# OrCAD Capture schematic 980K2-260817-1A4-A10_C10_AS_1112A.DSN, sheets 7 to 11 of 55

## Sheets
7 T14.SLOT14_PMVIx: size A2
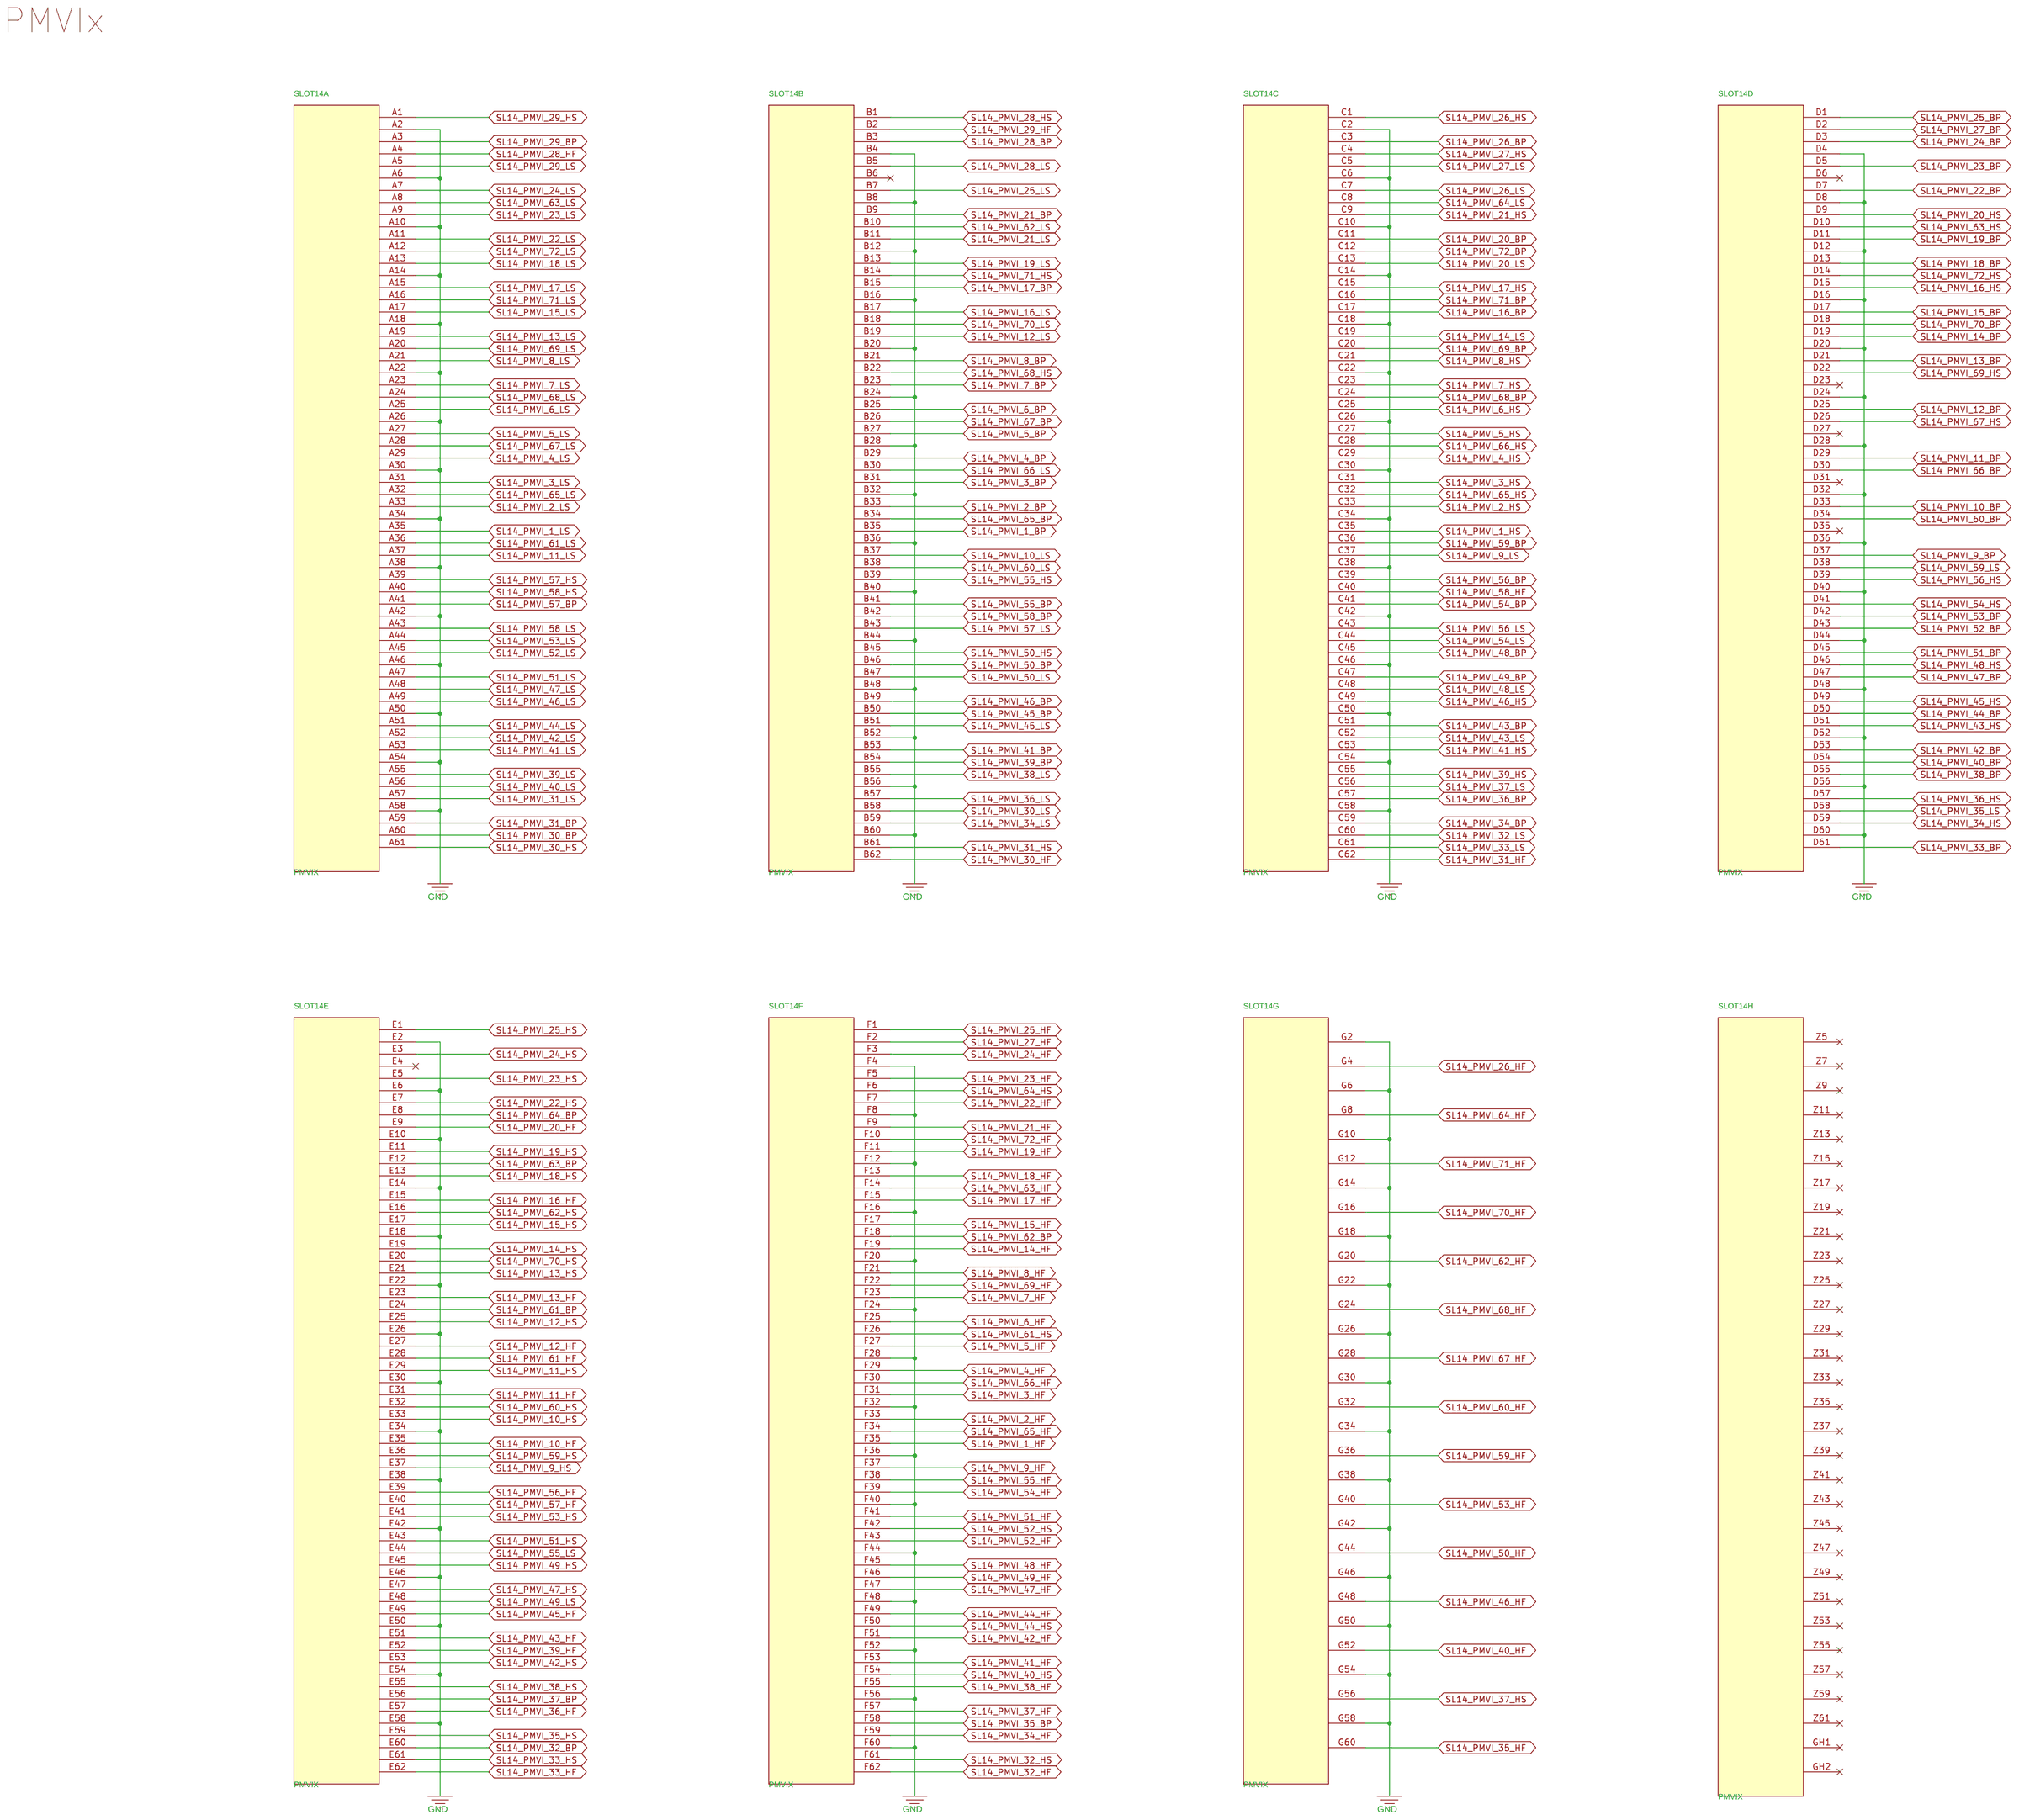
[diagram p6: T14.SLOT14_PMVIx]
8 T13.SLOT13_GX1x: size A2
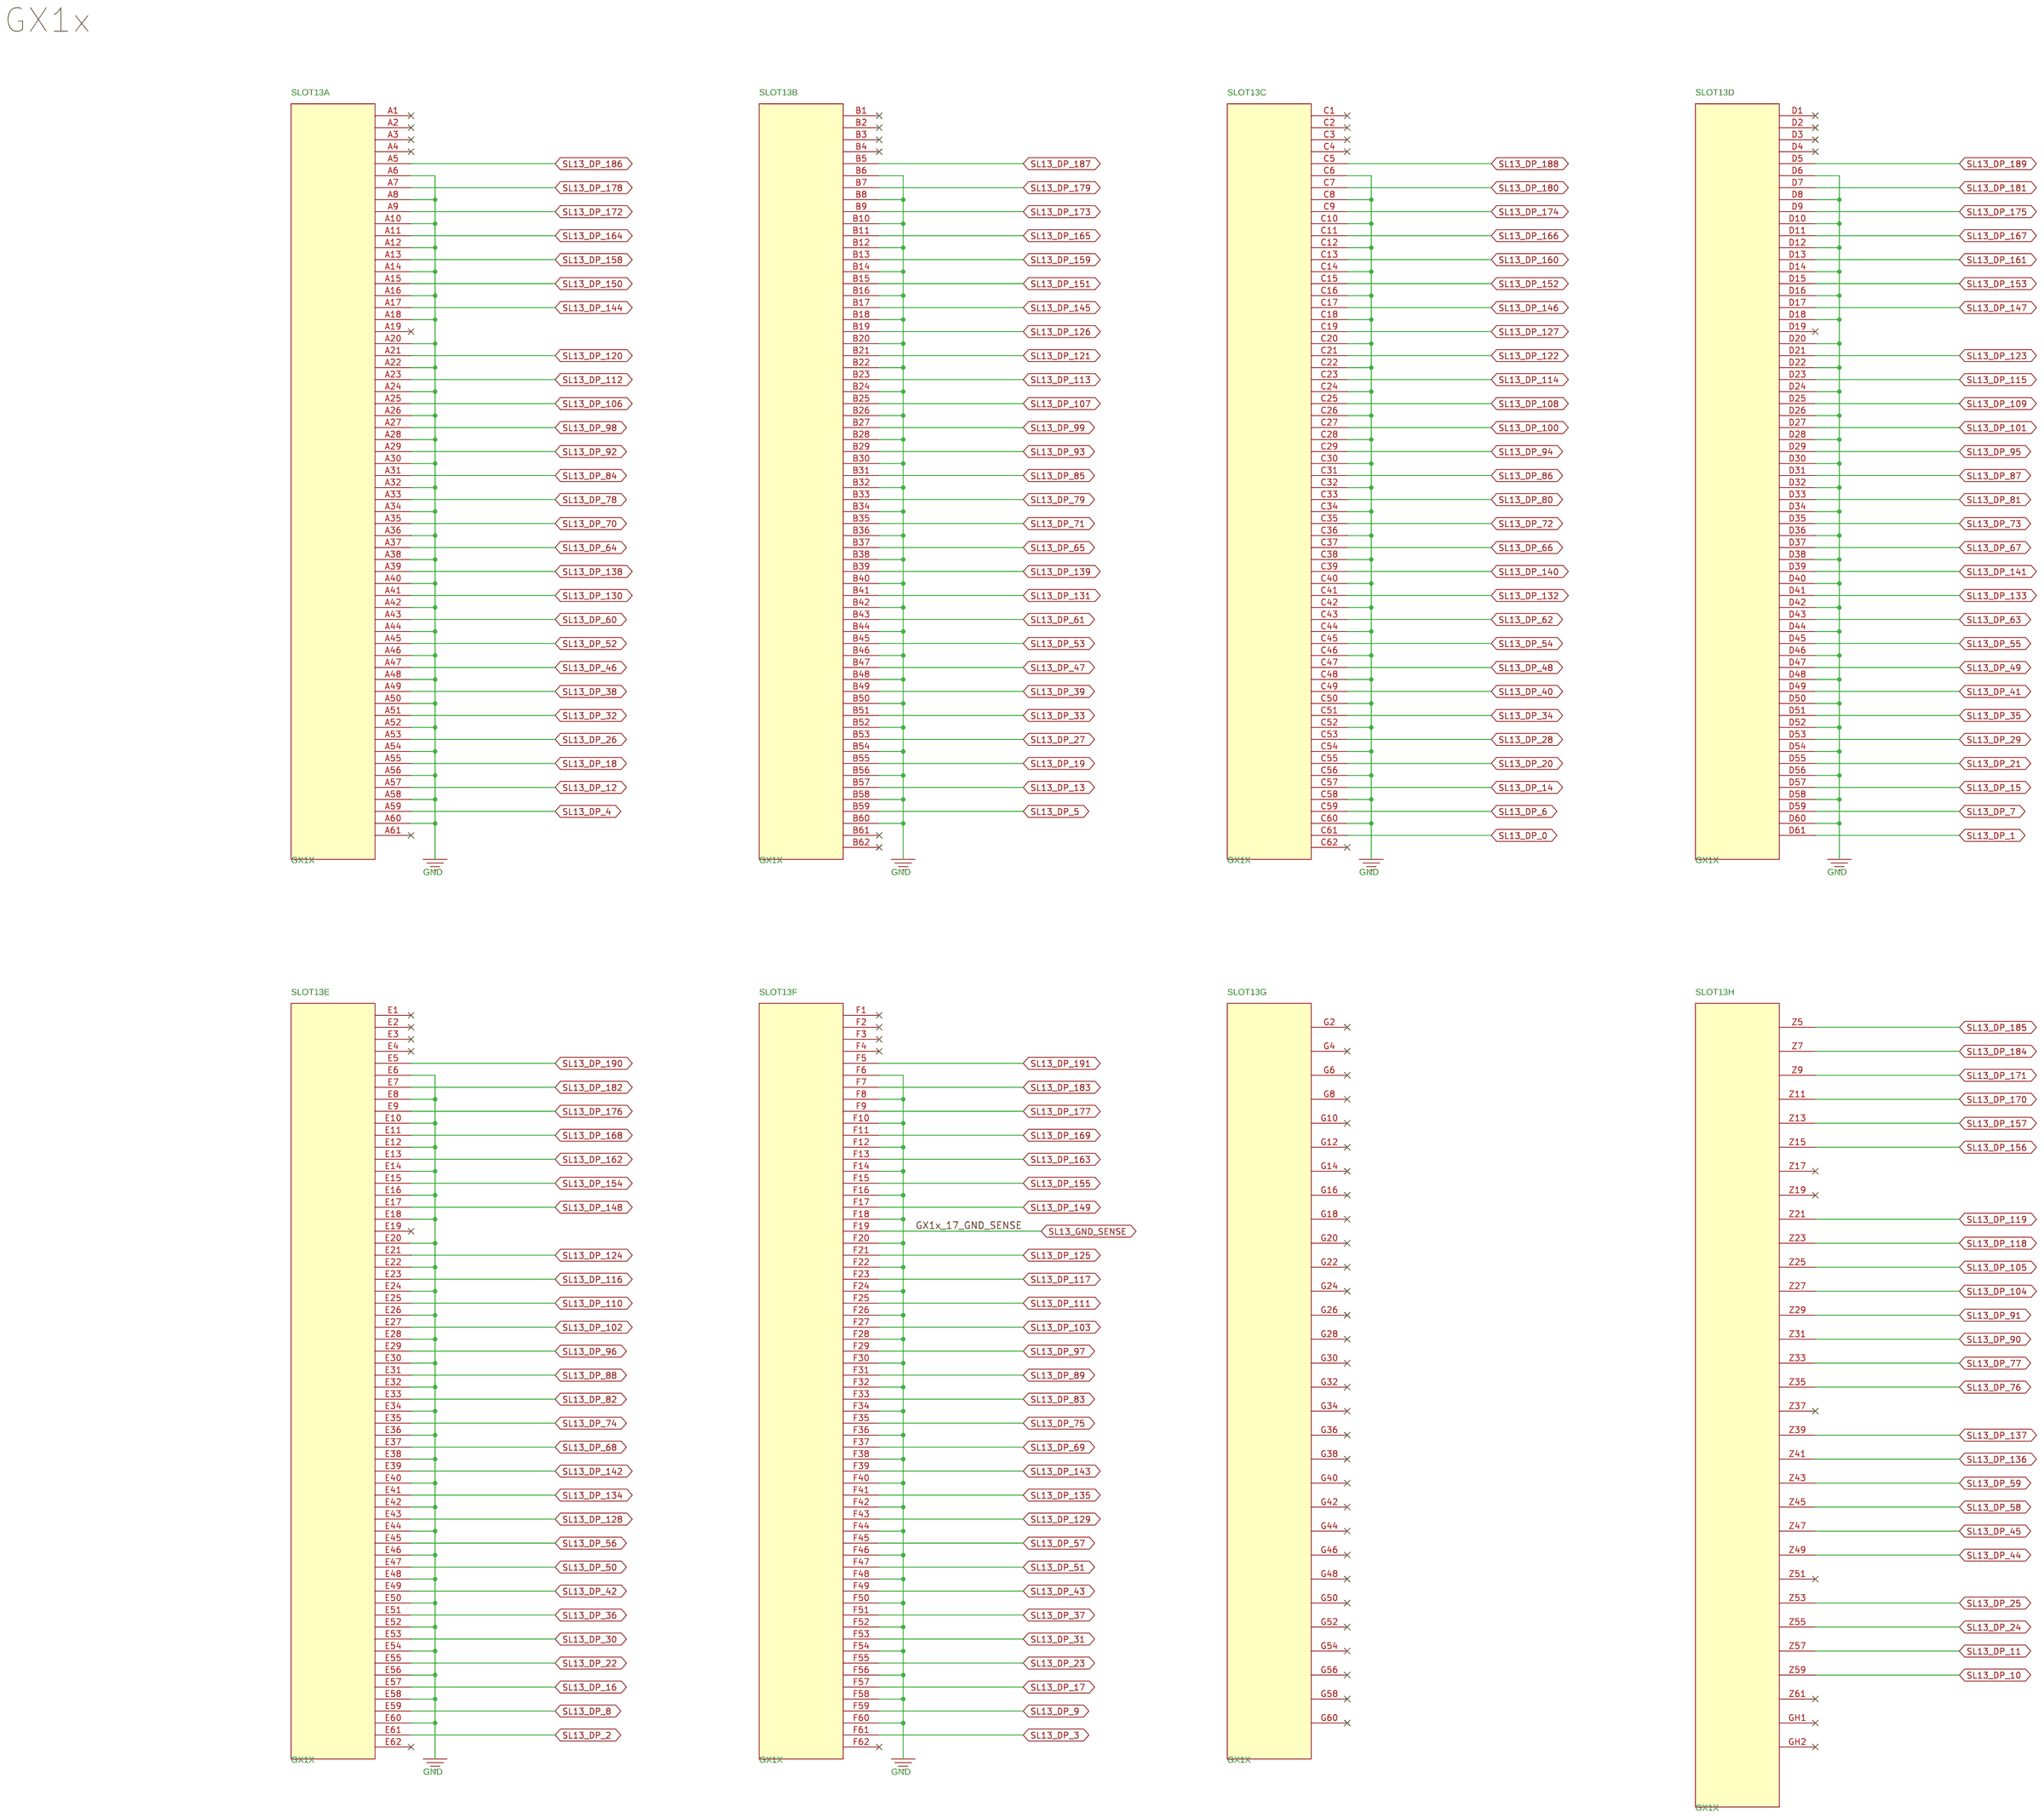
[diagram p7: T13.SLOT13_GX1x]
9 T12.SLOT12_EMPTY: size A2
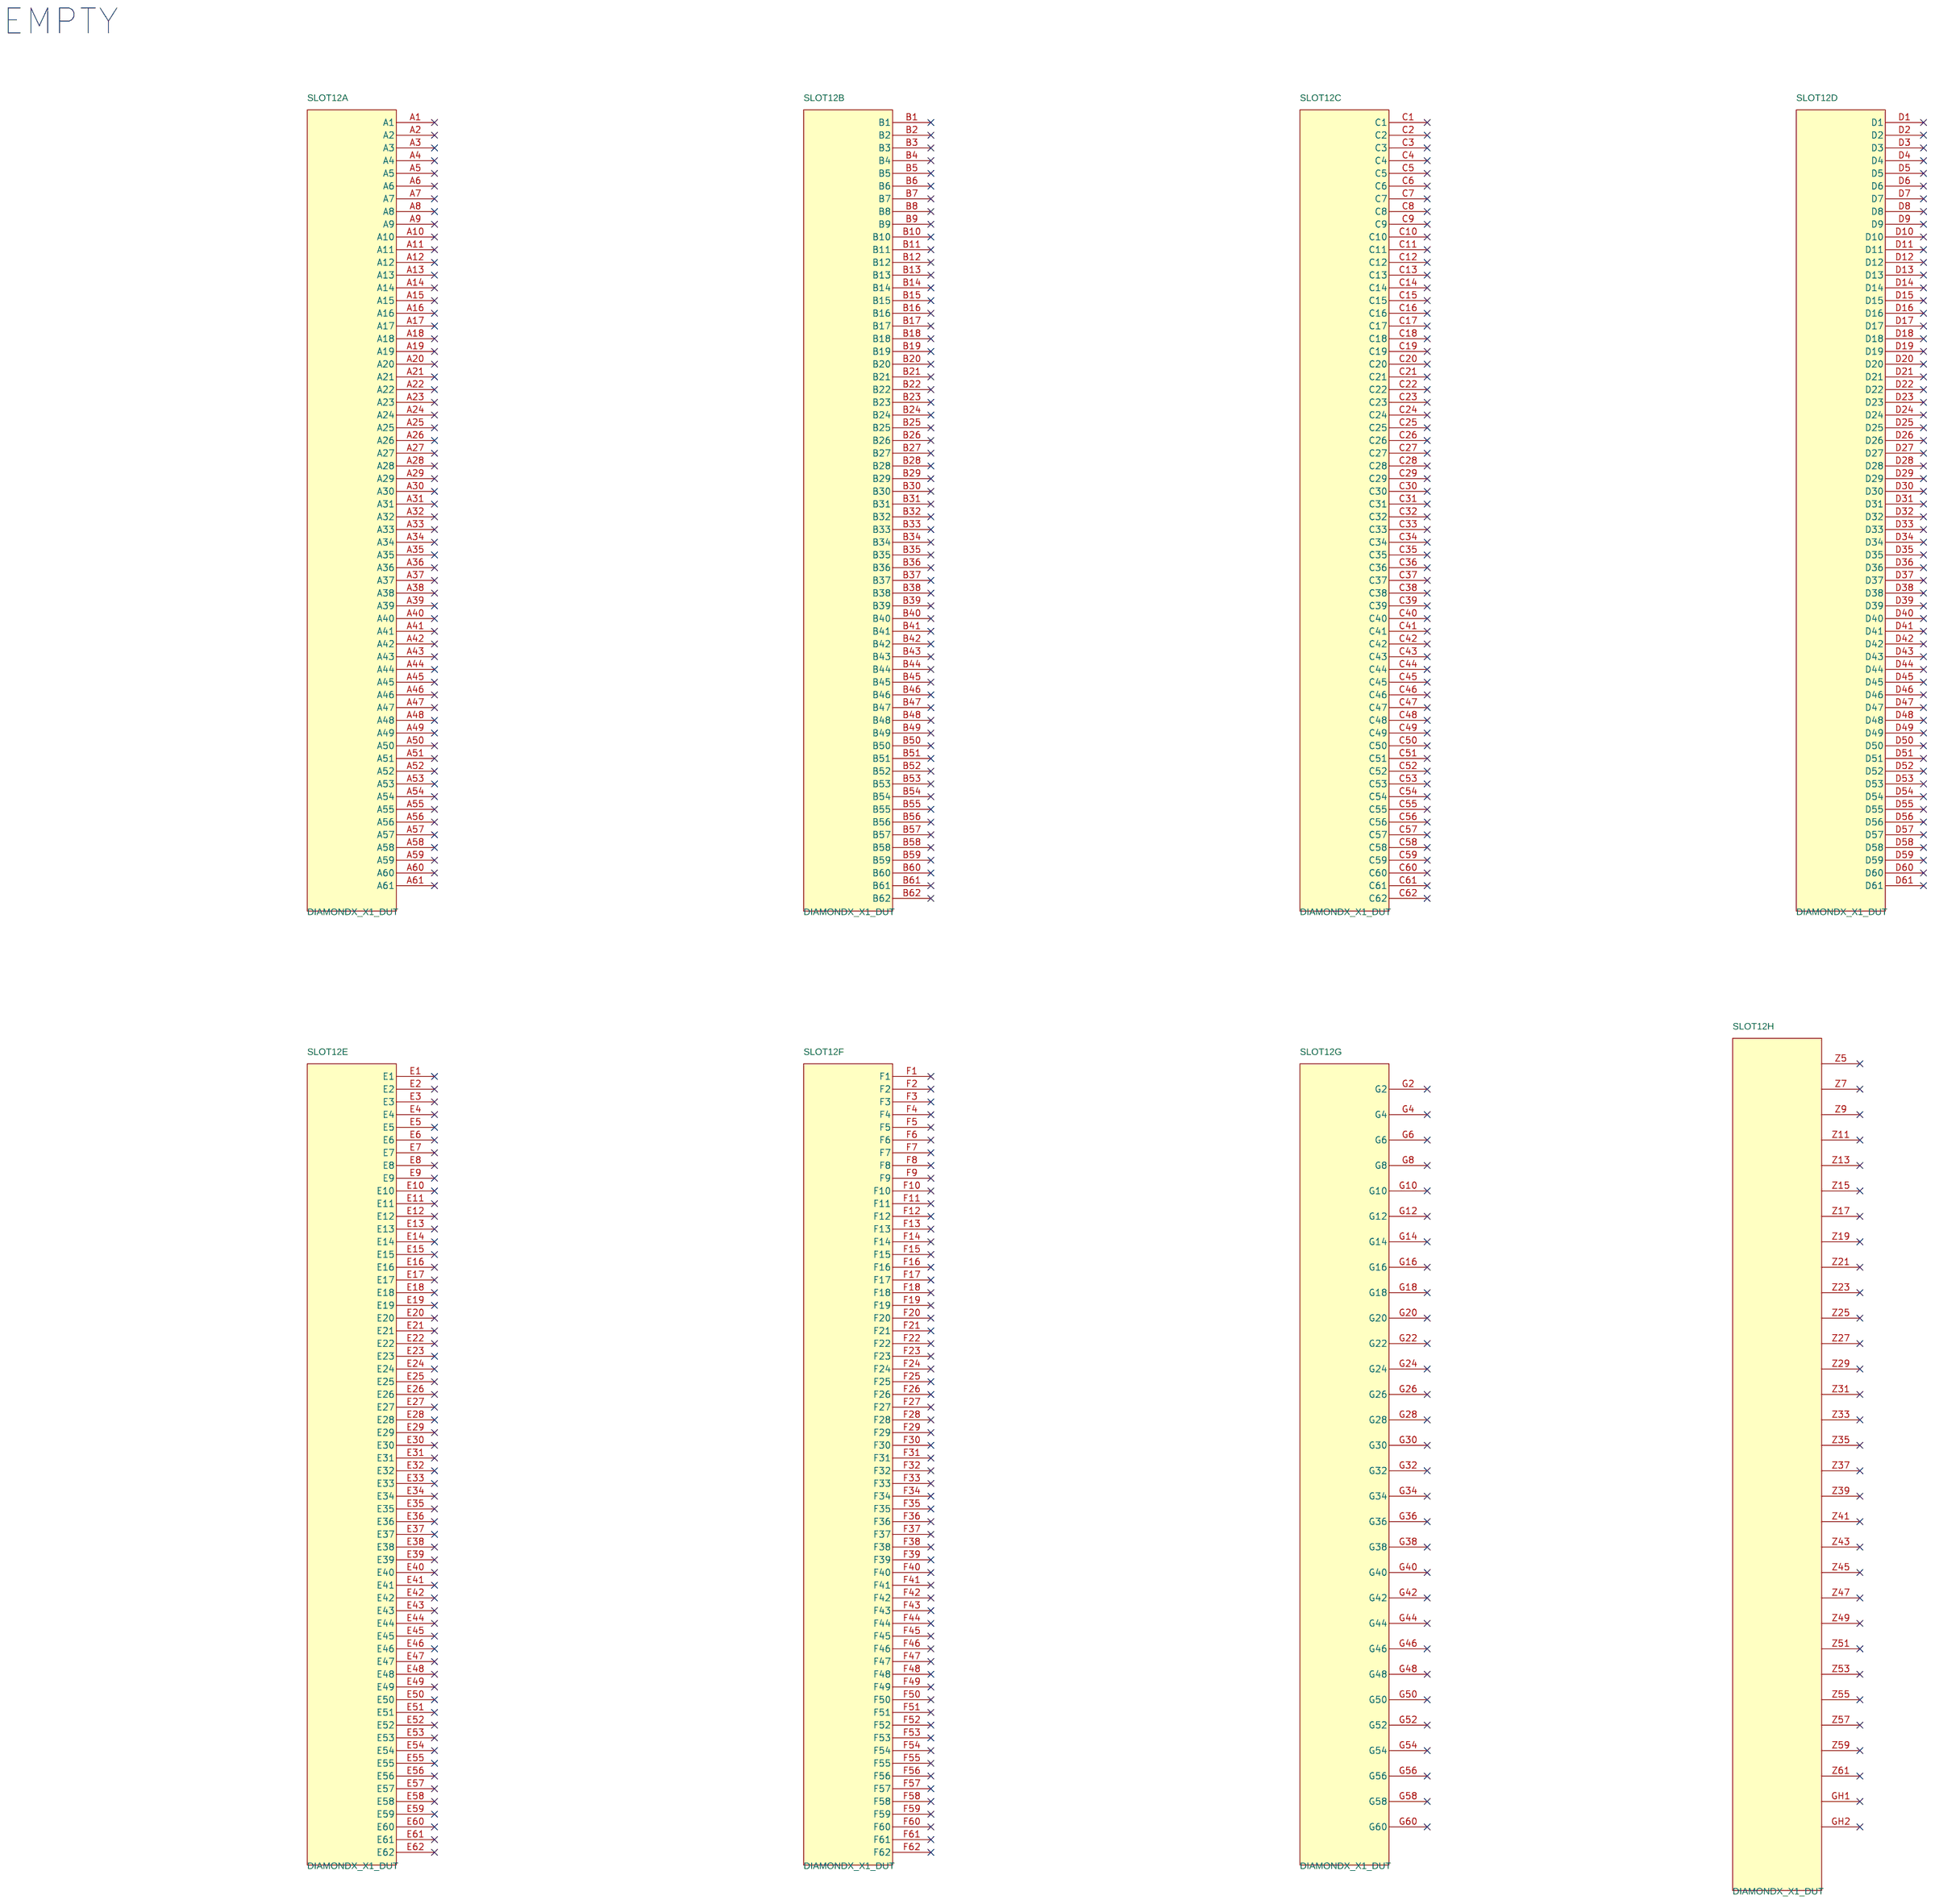
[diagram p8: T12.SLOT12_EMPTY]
10 T11.SLOT11_EMPTY: size A2
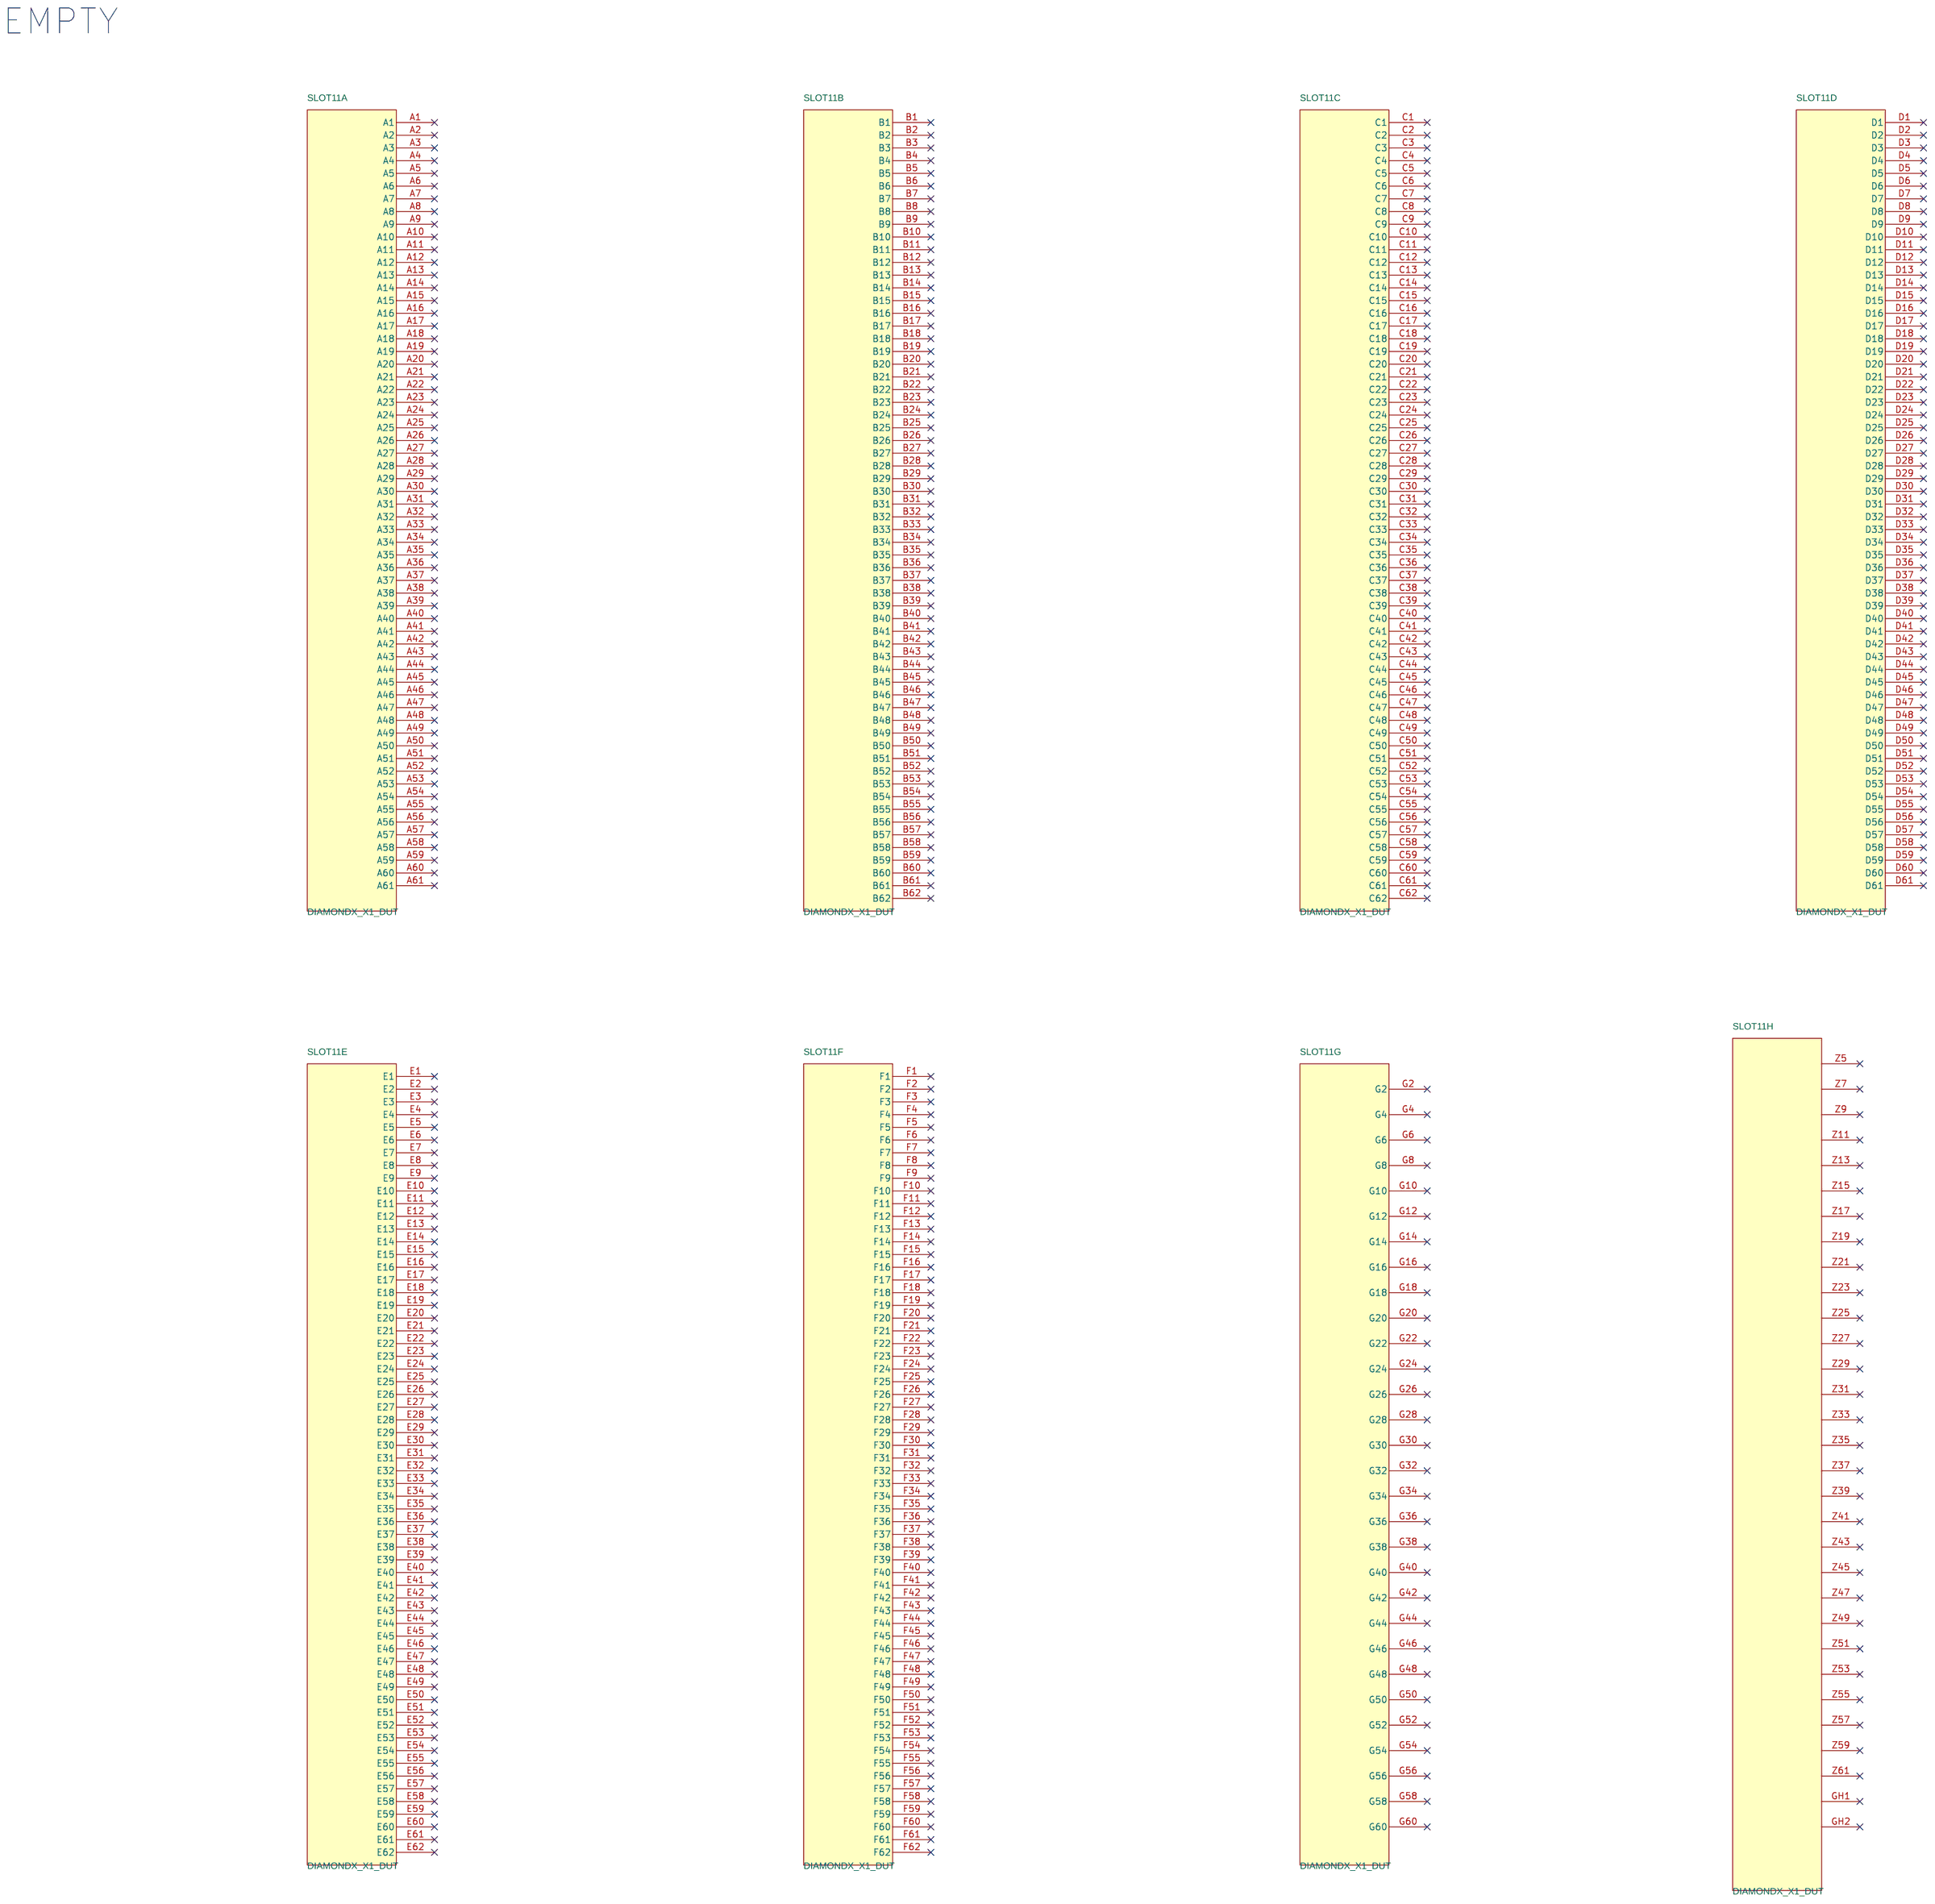
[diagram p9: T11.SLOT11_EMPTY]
11 T10.SLOT10_FPVI: size A2

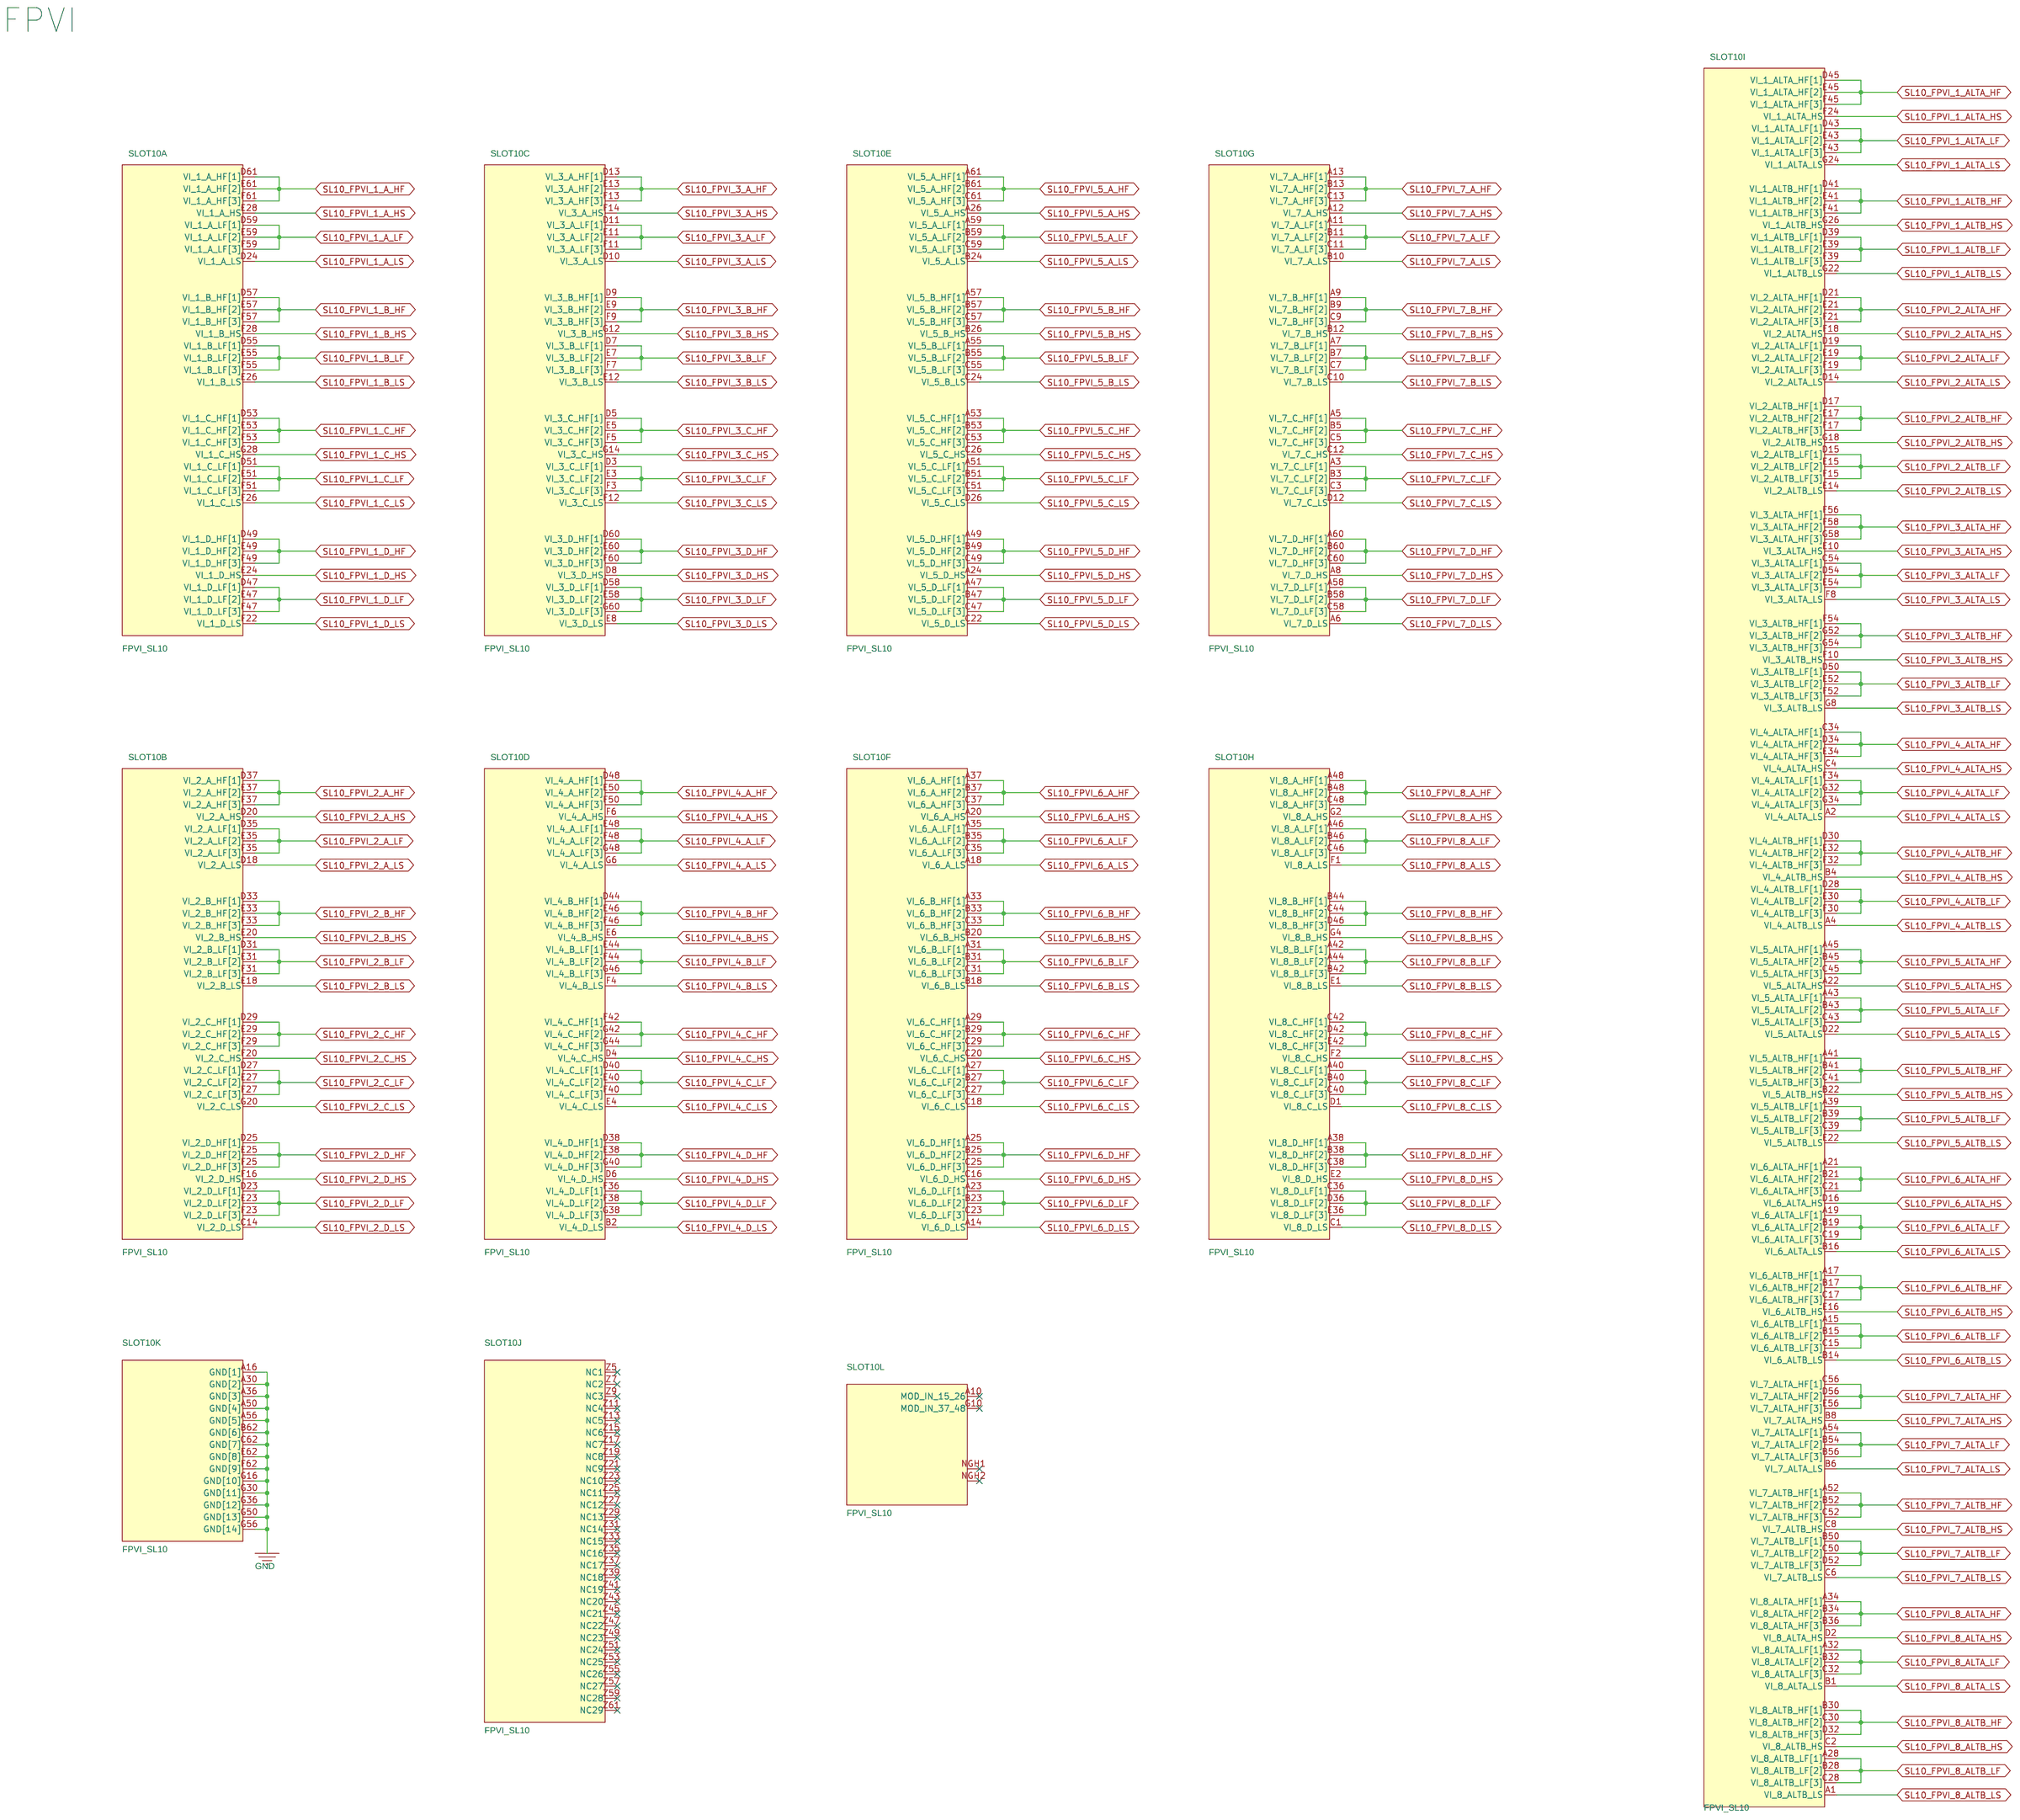
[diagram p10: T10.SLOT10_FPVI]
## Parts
sheet T10.SLOT10_FPVI
SLOT10  FPVI_SL10  [PG_LTXDX_F_X1_FPVI_SL10_V3]  (sections A,B,C,D,E,F,G,H,I,J,K,L)
sheet T11.SLOT11_EMPTY
SLOT11  DIAMONDX_X1_DUT  [PG_LTXDX_F_X1_PG400ND_SL11_V3]  (sections A,B,C,D,E,F,G,H)
sheet T12.SLOT12_EMPTY
SLOT12  DIAMONDX_X1_DUT  [PG_LTXDX_F_X1_PG400ND_SL12_V3]  (sections A,B,C,D,E,F,G,H)
sheet T13.SLOT13_GX1x
SLOT13  GX1X  [PG_LTXDX_F_X1_GX1_SL13_V2]  (sections A,B,C,D,E,F,G,H)
sheet T14.SLOT14_PMVIx
SLOT14  PMVIX  [PG_LTXDX_F_X1_PMVI_SL14_V3]  (sections A,B,C,D,E,F,G,H)

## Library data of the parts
SLOT10 = FPVI_SL10
SLOT11 SLOT12 = DIAMONDX_X1_DUT_1
SLOT13 = DIAMONDX_SLOT17_GX1X
SLOT14 = DIAMONDX_SLOT8_PMVIX

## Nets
GND: SLOT10.A16(GND[1]) SLOT10.A30(GND[2]) SLOT10.A36(GND[3]) SLOT10.A50(GND[4]) SLOT10.A56(GND[5]) SLOT10.B62(GND[6]) SLOT10.C62(GND[7]) SLOT10.E62(GND[8]) SLOT10.F62(GND[9]) SLOT10.G16(GND[10]) SLOT10.G30(GND[11]) SLOT10.G36(GND[12]) SLOT10.G50(GND[13]) SLOT10.G56(GND[14]) SLOT13.A6 SLOT13.A8 SLOT13.A10 SLOT13.A12 SLOT13.A14 SLOT13.A16 SLOT13.A18 SLOT13.A20 SLOT13.A22 SLOT13.A24 SLOT13.A26 SLOT13.A28 SLOT13.A30 SLOT13.A32 SLOT13.A34 SLOT13.A36 SLOT13.A38 SLOT13.A40 SLOT13.A42 SLOT13.A44 SLOT13.A46 SLOT13.A48 SLOT13.A50 SLOT13.A52 SLOT13.A54 SLOT13.A56 SLOT13.A58 SLOT13.A60 SLOT13.B6 SLOT13.B8 SLOT13.B10 SLOT13.B12 SLOT13.B14 SLOT13.B16 SLOT13.B18 SLOT13.B20 SLOT13.B22 SLOT13.B24 SLOT13.B26 SLOT13.B28 SLOT13.B30 SLOT13.B32 SLOT13.B34 SLOT13.B36 SLOT13.B38 SLOT13.B40 SLOT13.B42 SLOT13.B44 SLOT13.B46 SLOT13.B48 SLOT13.B50 SLOT13.B52 SLOT13.B54 SLOT13.B56 SLOT13.B58 SLOT13.B60 SLOT13.C6 SLOT13.C8 SLOT13.C10 SLOT13.C12 SLOT13.C14 SLOT13.C16 SLOT13.C18 SLOT13.C20 SLOT13.C22 SLOT13.C24 SLOT13.C26 SLOT13.C28 SLOT13.C30 SLOT13.C32 SLOT13.C34 SLOT13.C36 SLOT13.C38 SLOT13.C40 SLOT13.C42 SLOT13.C44 SLOT13.C46 SLOT13.C48 SLOT13.C50 SLOT13.C52 SLOT13.C54 SLOT13.C56 SLOT13.C58 SLOT13.C60 SLOT13.D6 SLOT13.D8 SLOT13.D10 SLOT13.D12 SLOT13.D14 SLOT13.D16 SLOT13.D18 SLOT13.D20 SLOT13.D22 SLOT13.D24 SLOT13.D26 SLOT13.D28 SLOT13.D30 SLOT13.D32 SLOT13.D34 SLOT13.D36 SLOT13.D38 SLOT13.D40 SLOT13.D42 SLOT13.D44 SLOT13.D46 SLOT13.D48 SLOT13.D50 SLOT13.D52 SLOT13.D54 SLOT13.D56 SLOT13.D58 SLOT13.D60 SLOT13.E6 SLOT13.E8 SLOT13.E10 SLOT13.E12 SLOT13.E14 SLOT13.E16 SLOT13.E18 SLOT13.E20 SLOT13.E22 SLOT13.E24 SLOT13.E26 SLOT13.E28 SLOT13.E30 SLOT13.E32 SLOT13.E34 SLOT13.E36 SLOT13.E38 SLOT13.E40 SLOT13.E42 SLOT13.E44 SLOT13.E46 SLOT13.E48 SLOT13.E50 SLOT13.E52 SLOT13.E54 SLOT13.E56 SLOT13.E58 SLOT13.E60 SLOT13.F6 SLOT13.F8 SLOT13.F10 SLOT13.F12 SLOT13.F14 SLOT13.F16 SLOT13.F18 SLOT13.F20 SLOT13.F22 SLOT13.F24 SLOT13.F26 SLOT13.F28 SLOT13.F30 SLOT13.F32 SLOT13.F34 SLOT13.F36 SLOT13.F38 SLOT13.F40 SLOT13.F42 SLOT13.F44 SLOT13.F46 SLOT13.F48 SLOT13.F50 SLOT13.F52 SLOT13.F54 SLOT13.F56 SLOT13.F58 SLOT13.F60 SLOT14.A2 SLOT14.A6 SLOT14.A10 SLOT14.A14 SLOT14.A18 SLOT14.A22 SLOT14.A26 SLOT14.A30 SLOT14.A34 SLOT14.A38 SLOT14.A42 SLOT14.A46 SLOT14.A50 SLOT14.A54 SLOT14.A58 SLOT14.B4 SLOT14.B8 SLOT14.B12 SLOT14.B16 SLOT14.B20 SLOT14.B24 SLOT14.B28 SLOT14.B32 SLOT14.B36 SLOT14.B40 SLOT14.B44 SLOT14.B48 SLOT14.B52 SLOT14.B56 SLOT14.B60 SLOT14.C2 SLOT14.C6 SLOT14.C10 SLOT14.C14 SLOT14.C18 SLOT14.C22 SLOT14.C26 SLOT14.C30 SLOT14.C34 SLOT14.C38 SLOT14.C42 SLOT14.C46 SLOT14.C50 SLOT14.C54 SLOT14.C58 SLOT14.D4 SLOT14.D8 SLOT14.D12 SLOT14.D16 SLOT14.D20 SLOT14.D24 SLOT14.D28 SLOT14.D32 SLOT14.D36 SLOT14.D40 SLOT14.D44 SLOT14.D48 SLOT14.D52 SLOT14.D56 SLOT14.D60 SLOT14.E2 SLOT14.E6 SLOT14.E10 SLOT14.E14 SLOT14.E18 SLOT14.E22 SLOT14.E26 SLOT14.E30 SLOT14.E34 SLOT14.E38 SLOT14.E42 SLOT14.E46 SLOT14.E50 SLOT14.E54 SLOT14.E58 SLOT14.F4 SLOT14.F8 SLOT14.F12 SLOT14.F16 SLOT14.F20 SLOT14.F24 SLOT14.F28 SLOT14.F32 SLOT14.F36 SLOT14.F40 SLOT14.F44 SLOT14.F48 SLOT14.F52 SLOT14.F56 SLOT14.F60 SLOT14.G2 SLOT14.G6 SLOT14.G10 SLOT14.G14 SLOT14.G18 SLOT14.G22 SLOT14.G26 SLOT14.G30 SLOT14.G34 SLOT14.G38 SLOT14.G42 SLOT14.G46 SLOT14.G50 SLOT14.G54 SLOT14.G58 ; also on sheet 3 4 12 15 16 19 20 21 22 24 28 32 36 40 44 48 52
SL02_VI100_1_B_HF: SLOT10.A59(VI_5_A_LF[1]) SLOT10.B59(VI_5_A_LF[2]) SLOT10.C59(VI_5_A_LF[3]) SLOT10.D59(VI_1_A_LF[1]) SLOT10.E59(VI_1_A_LF[2]) SLOT10.F59(VI_1_A_LF[3]) ; also on sheet 19 22
SL02_VI100_1_B_HS: SLOT10.B24(VI_5_A_LS) SLOT10.D24(VI_1_A_LS) ; also on sheet 19 22
SL10_FPVI_1_A_HF: SLOT10.D61(VI_1_A_HF[1]) SLOT10.E61(VI_1_A_HF[2]) SLOT10.F61(VI_1_A_HF[3]) ; also on sheet 50
SL10_FPVI_1_A_HS: SLOT10.E28(VI_1_A_HS) ; also on sheet 50
SL10_FPVI_1_ALTA_HF: SLOT10.D45(VI_1_ALTA_HF[1]) SLOT10.E45(VI_1_ALTA_HF[2]) SLOT10.F45(VI_1_ALTA_HF[3])
SL10_FPVI_1_ALTA_HS: SLOT10.F24(VI_1_ALTA_HS)
SL10_FPVI_1_ALTA_LF: SLOT10.D43(VI_1_ALTA_LF[1]) SLOT10.E43(VI_1_ALTA_LF[2]) SLOT10.F43(VI_1_ALTA_LF[3])
SL10_FPVI_1_ALTA_LS: SLOT10.G24(VI_1_ALTA_LS)
SL10_FPVI_1_ALTB_HF: SLOT10.D41(VI_1_ALTB_HF[1]) SLOT10.E41(VI_1_ALTB_HF[2]) SLOT10.F41(VI_1_ALTB_HF[3])
SL10_FPVI_1_ALTB_HS: SLOT10.G26(VI_1_ALTB_HS)
SL10_FPVI_1_ALTB_LF: SLOT10.D39(VI_1_ALTB_LF[1]) SLOT10.E39(VI_1_ALTB_LF[2]) SLOT10.F39(VI_1_ALTB_LF[3])
SL10_FPVI_1_ALTB_LS: SLOT10.G22(VI_1_ALTB_LS)
SL10_FPVI_1_B_HF: SLOT10.D57(VI_1_B_HF[1]) SLOT10.E57(VI_1_B_HF[2]) SLOT10.F57(VI_1_B_HF[3])
SL10_FPVI_1_B_HS: SLOT10.F28(VI_1_B_HS)
SL10_FPVI_1_B_LF: SLOT10.D55(VI_1_B_LF[1]) SLOT10.E55(VI_1_B_LF[2]) SLOT10.F55(VI_1_B_LF[3])
SL10_FPVI_1_B_LS: SLOT10.E26(VI_1_B_LS)
SL10_FPVI_1_C_HF: SLOT10.D53(VI_1_C_HF[1]) SLOT10.E53(VI_1_C_HF[2]) SLOT10.F53(VI_1_C_HF[3])
SL10_FPVI_1_C_HS: SLOT10.G28(VI_1_C_HS)
SL10_FPVI_1_C_LF: SLOT10.D51(VI_1_C_LF[1]) SLOT10.E51(VI_1_C_LF[2]) SLOT10.F51(VI_1_C_LF[3])
SL10_FPVI_1_C_LS: SLOT10.F26(VI_1_C_LS)
SL10_FPVI_1_D_HF: SLOT10.D49(VI_1_D_HF[1]) SLOT10.E49(VI_1_D_HF[2]) SLOT10.F49(VI_1_D_HF[3])
SL10_FPVI_1_D_HS: SLOT10.E24(VI_1_D_HS)
SL10_FPVI_1_D_LF: SLOT10.D47(VI_1_D_LF[1]) SLOT10.E47(VI_1_D_LF[2]) SLOT10.F47(VI_1_D_LF[3])
SL10_FPVI_1_D_LS: SLOT10.F22(VI_1_D_LS)
SL10_FPVI_2_6_A_LF: SLOT10.A35(VI_6_A_LF[1]) SLOT10.B35(VI_6_A_LF[2]) SLOT10.C35(VI_6_A_LF[3]) SLOT10.D35(VI_2_A_LF[1]) SLOT10.E35(VI_2_A_LF[2]) SLOT10.F35(VI_2_A_LF[3]) ; also on sheet 3 22
SL10_FPVI_2_A_HF: SLOT10.D37(VI_2_A_HF[1]) SLOT10.E37(VI_2_A_HF[2]) SLOT10.F37(VI_2_A_HF[3]) ; also on sheet 34
SL10_FPVI_2_A_HS: SLOT10.D20(VI_2_A_HS) ; also on sheet 34
SL10_FPVI_2_A_LS: SLOT10.A18(VI_6_A_LS) SLOT10.D18(VI_2_A_LS) ; also on sheet 3 22
SL10_FPVI_2_ALTA_HF: SLOT10.D21(VI_2_ALTA_HF[1]) SLOT10.E21(VI_2_ALTA_HF[2]) SLOT10.F21(VI_2_ALTA_HF[3])
SL10_FPVI_2_ALTA_HS: SLOT10.F18(VI_2_ALTA_HS)
SL10_FPVI_2_ALTA_LF: SLOT10.D19(VI_2_ALTA_LF[1]) SLOT10.E19(VI_2_ALTA_LF[2]) SLOT10.F19(VI_2_ALTA_LF[3])
SL10_FPVI_2_ALTA_LS: SLOT10.D14(VI_2_ALTA_LS)
SL10_FPVI_2_ALTB_HF: SLOT10.D17(VI_2_ALTB_HF[1]) SLOT10.E17(VI_2_ALTB_HF[2]) SLOT10.F17(VI_2_ALTB_HF[3])
SL10_FPVI_2_ALTB_HS: SLOT10.G18(VI_2_ALTB_HS)
SL10_FPVI_2_ALTB_LF: SLOT10.D15(VI_2_ALTB_LF[1]) SLOT10.E15(VI_2_ALTB_LF[2]) SLOT10.F15(VI_2_ALTB_LF[3])
SL10_FPVI_2_ALTB_LS: SLOT10.E14(VI_2_ALTB_LS)
SL10_FPVI_2_B_HF: SLOT10.D33(VI_2_B_HF[1]) SLOT10.E33(VI_2_B_HF[2]) SLOT10.F33(VI_2_B_HF[3])
SL10_FPVI_2_B_HS: SLOT10.E20(VI_2_B_HS)
SL10_FPVI_2_B_LF: SLOT10.D31(VI_2_B_LF[1]) SLOT10.E31(VI_2_B_LF[2]) SLOT10.F31(VI_2_B_LF[3])
SL10_FPVI_2_B_LS: SLOT10.E18(VI_2_B_LS)
SL10_FPVI_2_C_HF: SLOT10.D29(VI_2_C_HF[1]) SLOT10.E29(VI_2_C_HF[2]) SLOT10.F29(VI_2_C_HF[3])
SL10_FPVI_2_C_HS: SLOT10.F20(VI_2_C_HS)
SL10_FPVI_2_C_LF: SLOT10.D27(VI_2_C_LF[1]) SLOT10.E27(VI_2_C_LF[2]) SLOT10.F27(VI_2_C_LF[3])
SL10_FPVI_2_C_LS: SLOT10.G20(VI_2_C_LS)
SL10_FPVI_2_D_HF: SLOT10.D25(VI_2_D_HF[1]) SLOT10.E25(VI_2_D_HF[2]) SLOT10.F25(VI_2_D_HF[3])
SL10_FPVI_2_D_HS: SLOT10.F16(VI_2_D_HS)
SL10_FPVI_2_D_LF: SLOT10.D23(VI_2_D_LF[1]) SLOT10.E23(VI_2_D_LF[2]) SLOT10.F23(VI_2_D_LF[3])
SL10_FPVI_2_D_LS: SLOT10.C14(VI_2_D_LS)
SL10_FPVI_3_A_HF: SLOT10.D13(VI_3_A_HF[1]) SLOT10.E13(VI_3_A_HF[2]) SLOT10.F13(VI_3_A_HF[3])
SL10_FPVI_3_A_HS: SLOT10.F14(VI_3_A_HS)
SL10_FPVI_3_A_LF: SLOT10.D11(VI_3_A_LF[1]) SLOT10.E11(VI_3_A_LF[2]) SLOT10.F11(VI_3_A_LF[3])
SL10_FPVI_3_A_LS: SLOT10.D10(VI_3_A_LS)
SL10_FPVI_3_ALTA_HF: SLOT10.F56(VI_3_ALTA_HF[1]) SLOT10.F58(VI_3_ALTA_HF[2]) SLOT10.G58(VI_3_ALTA_HF[3])
SL10_FPVI_3_ALTA_HS: SLOT10.E10(VI_3_ALTA_HS)
SL10_FPVI_3_ALTA_LF: SLOT10.C54(VI_3_ALTA_LF[1]) SLOT10.D54(VI_3_ALTA_LF[2]) SLOT10.E54(VI_3_ALTA_LF[3])
SL10_FPVI_3_ALTA_LS: SLOT10.F8(VI_3_ALTA_LS)
SL10_FPVI_3_ALTB_HF: SLOT10.F54(VI_3_ALTB_HF[1]) SLOT10.G52(VI_3_ALTB_HF[2]) SLOT10.G54(VI_3_ALTB_HF[3])
SL10_FPVI_3_ALTB_HS: SLOT10.F10(VI_3_ALTB_HS)
SL10_FPVI_3_ALTB_LF: SLOT10.D50(VI_3_ALTB_LF[1]) SLOT10.E52(VI_3_ALTB_LF[2]) SLOT10.F52(VI_3_ALTB_LF[3])
SL10_FPVI_3_ALTB_LS: SLOT10.G8(VI_3_ALTB_LS)
SL10_FPVI_3_B_HF: SLOT10.D9(VI_3_B_HF[1]) SLOT10.E9(VI_3_B_HF[2]) SLOT10.F9(VI_3_B_HF[3])
SL10_FPVI_3_B_HS: SLOT10.G12(VI_3_B_HS)
SL10_FPVI_3_B_LF: SLOT10.D7(VI_3_B_LF[1]) SLOT10.E7(VI_3_B_LF[2]) SLOT10.F7(VI_3_B_LF[3])
SL10_FPVI_3_B_LS: SLOT10.E12(VI_3_B_LS)
SL10_FPVI_3_C_HF: SLOT10.D5(VI_3_C_HF[1]) SLOT10.E5(VI_3_C_HF[2]) SLOT10.F5(VI_3_C_HF[3])
SL10_FPVI_3_C_HS: SLOT10.G14(VI_3_C_HS)
SL10_FPVI_3_C_LF: SLOT10.D3(VI_3_C_LF[1]) SLOT10.E3(VI_3_C_LF[2]) SLOT10.F3(VI_3_C_LF[3])
SL10_FPVI_3_C_LS: SLOT10.F12(VI_3_C_LS)
SL10_FPVI_3_D_HF: SLOT10.D60(VI_3_D_HF[1]) SLOT10.E60(VI_3_D_HF[2]) SLOT10.F60(VI_3_D_HF[3])
SL10_FPVI_3_D_HS: SLOT10.D8(VI_3_D_HS)
SL10_FPVI_3_D_LF: SLOT10.D58(VI_3_D_LF[1]) SLOT10.E58(VI_3_D_LF[2]) SLOT10.G60(VI_3_D_LF[3])
SL10_FPVI_3_D_LS: SLOT10.E8(VI_3_D_LS)
SL10_FPVI_4_A_HF: SLOT10.D48(VI_4_A_HF[1]) SLOT10.E50(VI_4_A_HF[2]) SLOT10.F50(VI_4_A_HF[3])
SL10_FPVI_4_A_HS: SLOT10.F6(VI_4_A_HS)
SL10_FPVI_4_A_LF: SLOT10.E48(VI_4_A_LF[1]) SLOT10.F48(VI_4_A_LF[2]) SLOT10.G48(VI_4_A_LF[3])
SL10_FPVI_4_A_LS: SLOT10.G6(VI_4_A_LS)
SL10_FPVI_4_ALTA_HF: SLOT10.C34(VI_4_ALTA_HF[1]) SLOT10.D34(VI_4_ALTA_HF[2]) SLOT10.E34(VI_4_ALTA_HF[3])
SL10_FPVI_4_ALTA_HS: SLOT10.C4(VI_4_ALTA_HS)
SL10_FPVI_4_ALTA_LF: SLOT10.F34(VI_4_ALTA_LF[1]) SLOT10.G32(VI_4_ALTA_LF[2]) SLOT10.G34(VI_4_ALTA_LF[3])
SL10_FPVI_4_ALTA_LS: SLOT10.A2(VI_4_ALTA_LS)
SL10_FPVI_4_ALTB_HF: SLOT10.D30(VI_4_ALTB_HF[1]) SLOT10.E32(VI_4_ALTB_HF[2]) SLOT10.F32(VI_4_ALTB_HF[3])
SL10_FPVI_4_ALTB_HS: SLOT10.B4(VI_4_ALTB_HS)
SL10_FPVI_4_ALTB_LF: SLOT10.D28(VI_4_ALTB_LF[1]) SLOT10.E30(VI_4_ALTB_LF[2]) SLOT10.F30(VI_4_ALTB_LF[3])
SL10_FPVI_4_ALTB_LS: SLOT10.A4(VI_4_ALTB_LS)
SL10_FPVI_4_B_HF: SLOT10.D44(VI_4_B_HF[1]) SLOT10.E46(VI_4_B_HF[2]) SLOT10.F46(VI_4_B_HF[3])
SL10_FPVI_4_B_HS: SLOT10.E6(VI_4_B_HS)
SL10_FPVI_4_B_LF: SLOT10.E44(VI_4_B_LF[1]) SLOT10.F44(VI_4_B_LF[2]) SLOT10.G46(VI_4_B_LF[3])
SL10_FPVI_4_B_LS: SLOT10.F4(VI_4_B_LS)
SL10_FPVI_4_C_HF: SLOT10.F42(VI_4_C_HF[1]) SLOT10.G42(VI_4_C_HF[2]) SLOT10.G44(VI_4_C_HF[3])
SL10_FPVI_4_C_HS: SLOT10.D4(VI_4_C_HS)
SL10_FPVI_4_C_LF: SLOT10.D40(VI_4_C_LF[1]) SLOT10.E40(VI_4_C_LF[2]) SLOT10.F40(VI_4_C_LF[3])
SL10_FPVI_4_C_LS: SLOT10.E4(VI_4_C_LS)
SL10_FPVI_4_D_HF: SLOT10.D38(VI_4_D_HF[1]) SLOT10.E38(VI_4_D_HF[2]) SLOT10.G40(VI_4_D_HF[3])
SL10_FPVI_4_D_HS: SLOT10.D6(VI_4_D_HS)
SL10_FPVI_4_D_LF: SLOT10.F36(VI_4_D_LF[1]) SLOT10.F38(VI_4_D_LF[2]) SLOT10.G38(VI_4_D_LF[3])
SL10_FPVI_4_D_LS: SLOT10.B2(VI_4_D_LS)
SL10_FPVI_5_A_HF: SLOT10.A61(VI_5_A_HF[1]) SLOT10.B61(VI_5_A_HF[2]) SLOT10.C61(VI_5_A_HF[3]) ; also on sheet 42
SL10_FPVI_5_A_HS: SLOT10.A26(VI_5_A_HS) ; also on sheet 42
SL10_FPVI_5_ALTA_HF: SLOT10.A45(VI_5_ALTA_HF[1]) SLOT10.B45(VI_5_ALTA_HF[2]) SLOT10.C45(VI_5_ALTA_HF[3])
SL10_FPVI_5_ALTA_HS: SLOT10.A22(VI_5_ALTA_HS)
SL10_FPVI_5_ALTA_LF: SLOT10.A43(VI_5_ALTA_LF[1]) SLOT10.B43(VI_5_ALTA_LF[2]) SLOT10.C43(VI_5_ALTA_LF[3])
SL10_FPVI_5_ALTA_LS: SLOT10.D22(VI_5_ALTA_LS)
SL10_FPVI_5_ALTB_HF: SLOT10.A41(VI_5_ALTB_HF[1]) SLOT10.B41(VI_5_ALTB_HF[2]) SLOT10.C41(VI_5_ALTB_HF[3])
SL10_FPVI_5_ALTB_HS: SLOT10.B22(VI_5_ALTB_HS)
SL10_FPVI_5_ALTB_LF: SLOT10.A39(VI_5_ALTB_LF[1]) SLOT10.B39(VI_5_ALTB_LF[2]) SLOT10.C39(VI_5_ALTB_LF[3])
SL10_FPVI_5_ALTB_LS: SLOT10.E22(VI_5_ALTB_LS)
SL10_FPVI_5_B_HF: SLOT10.A57(VI_5_B_HF[1]) SLOT10.B57(VI_5_B_HF[2]) SLOT10.C57(VI_5_B_HF[3])
SL10_FPVI_5_B_HS: SLOT10.B26(VI_5_B_HS)
SL10_FPVI_5_B_LF: SLOT10.A55(VI_5_B_LF[1]) SLOT10.B55(VI_5_B_LF[2]) SLOT10.C55(VI_5_B_LF[3])
SL10_FPVI_5_B_LS: SLOT10.C24(VI_5_B_LS)
SL10_FPVI_5_C_HF: SLOT10.A53(VI_5_C_HF[1]) SLOT10.B53(VI_5_C_HF[2]) SLOT10.C53(VI_5_C_HF[3])
SL10_FPVI_5_C_HS: SLOT10.C26(VI_5_C_HS)
SL10_FPVI_5_C_LF: SLOT10.A51(VI_5_C_LF[1]) SLOT10.B51(VI_5_C_LF[2]) SLOT10.C51(VI_5_C_LF[3])
SL10_FPVI_5_C_LS: SLOT10.D26(VI_5_C_LS)
SL10_FPVI_5_D_HF: SLOT10.A49(VI_5_D_HF[1]) SLOT10.B49(VI_5_D_HF[2]) SLOT10.C49(VI_5_D_HF[3])
SL10_FPVI_5_D_HS: SLOT10.A24(VI_5_D_HS)
SL10_FPVI_5_D_LF: SLOT10.A47(VI_5_D_LF[1]) SLOT10.B47(VI_5_D_LF[2]) SLOT10.C47(VI_5_D_LF[3])
SL10_FPVI_5_D_LS: SLOT10.C22(VI_5_D_LS)
SL10_FPVI_6_A_HF: SLOT10.A37(VI_6_A_HF[1]) SLOT10.B37(VI_6_A_HF[2]) SLOT10.C37(VI_6_A_HF[3]) ; also on sheet 26
SL10_FPVI_6_A_HS: SLOT10.A20(VI_6_A_HS) ; also on sheet 26
SL10_FPVI_6_ALTA_HF: SLOT10.A21(VI_6_ALTA_HF[1]) SLOT10.B21(VI_6_ALTA_HF[2]) SLOT10.C21(VI_6_ALTA_HF[3])
SL10_FPVI_6_ALTA_HS: SLOT10.D16(VI_6_ALTA_HS)
SL10_FPVI_6_ALTA_LF: SLOT10.A19(VI_6_ALTA_LF[1]) SLOT10.B19(VI_6_ALTA_LF[2]) SLOT10.C19(VI_6_ALTA_LF[3])
SL10_FPVI_6_ALTA_LS: SLOT10.B16(VI_6_ALTA_LS)
SL10_FPVI_6_ALTB_HF: SLOT10.A17(VI_6_ALTB_HF[1]) SLOT10.B17(VI_6_ALTB_HF[2]) SLOT10.C17(VI_6_ALTB_HF[3])
SL10_FPVI_6_ALTB_HS: SLOT10.E16(VI_6_ALTB_HS)
SL10_FPVI_6_ALTB_LF: SLOT10.A15(VI_6_ALTB_LF[1]) SLOT10.B15(VI_6_ALTB_LF[2]) SLOT10.C15(VI_6_ALTB_LF[3])
SL10_FPVI_6_ALTB_LS: SLOT10.B14(VI_6_ALTB_LS)
SL10_FPVI_6_B_HF: SLOT10.A33(VI_6_B_HF[1]) SLOT10.B33(VI_6_B_HF[2]) SLOT10.C33(VI_6_B_HF[3])
SL10_FPVI_6_B_HS: SLOT10.B20(VI_6_B_HS)
SL10_FPVI_6_B_LF: SLOT10.A31(VI_6_B_LF[1]) SLOT10.B31(VI_6_B_LF[2]) SLOT10.C31(VI_6_B_LF[3])
SL10_FPVI_6_B_LS: SLOT10.B18(VI_6_B_LS)
SL10_FPVI_6_C_HF: SLOT10.A29(VI_6_C_HF[1]) SLOT10.B29(VI_6_C_HF[2]) SLOT10.C29(VI_6_C_HF[3])
SL10_FPVI_6_C_HS: SLOT10.C20(VI_6_C_HS)
SL10_FPVI_6_C_LF: SLOT10.A27(VI_6_C_LF[1]) SLOT10.B27(VI_6_C_LF[2]) SLOT10.C27(VI_6_C_LF[3])
SL10_FPVI_6_C_LS: SLOT10.C18(VI_6_C_LS)
SL10_FPVI_6_D_HF: SLOT10.A25(VI_6_D_HF[1]) SLOT10.B25(VI_6_D_HF[2]) SLOT10.C25(VI_6_D_HF[3])
SL10_FPVI_6_D_HS: SLOT10.C16(VI_6_D_HS)
SL10_FPVI_6_D_LF: SLOT10.A23(VI_6_D_LF[1]) SLOT10.B23(VI_6_D_LF[2]) SLOT10.C23(VI_6_D_LF[3])
SL10_FPVI_6_D_LS: SLOT10.A14(VI_6_D_LS)
SL10_FPVI_7_A_HF: SLOT10.A13(VI_7_A_HF[1]) SLOT10.B13(VI_7_A_HF[2]) SLOT10.C13(VI_7_A_HF[3])
SL10_FPVI_7_A_HS: SLOT10.A12(VI_7_A_HS)
SL10_FPVI_7_A_LF: SLOT10.A11(VI_7_A_LF[1]) SLOT10.B11(VI_7_A_LF[2]) SLOT10.C11(VI_7_A_LF[3])
SL10_FPVI_7_A_LS: SLOT10.B10(VI_7_A_LS)
SL10_FPVI_7_ALTA_HF: SLOT10.C56(VI_7_ALTA_HF[1]) SLOT10.D56(VI_7_ALTA_HF[2]) SLOT10.E56(VI_7_ALTA_HF[3])
SL10_FPVI_7_ALTA_HS: SLOT10.B8(VI_7_ALTA_HS)
SL10_FPVI_7_ALTA_LF: SLOT10.A54(VI_7_ALTA_LF[1]) SLOT10.B54(VI_7_ALTA_LF[2]) SLOT10.B56(VI_7_ALTA_LF[3])
SL10_FPVI_7_ALTA_LS: SLOT10.B6(VI_7_ALTA_LS)
SL10_FPVI_7_ALTB_HF: SLOT10.A52(VI_7_ALTB_HF[1]) SLOT10.B52(VI_7_ALTB_HF[2]) SLOT10.C52(VI_7_ALTB_HF[3])
SL10_FPVI_7_ALTB_HS: SLOT10.C8(VI_7_ALTB_HS)
SL10_FPVI_7_ALTB_LF: SLOT10.B50(VI_7_ALTB_LF[1]) SLOT10.C50(VI_7_ALTB_LF[2]) SLOT10.D52(VI_7_ALTB_LF[3])
SL10_FPVI_7_ALTB_LS: SLOT10.C6(VI_7_ALTB_LS)
SL10_FPVI_7_B_HF: SLOT10.A9(VI_7_B_HF[1]) SLOT10.B9(VI_7_B_HF[2]) SLOT10.C9(VI_7_B_HF[3])
SL10_FPVI_7_B_HS: SLOT10.B12(VI_7_B_HS)
SL10_FPVI_7_B_LF: SLOT10.A7(VI_7_B_LF[1]) SLOT10.B7(VI_7_B_LF[2]) SLOT10.C7(VI_7_B_LF[3])
SL10_FPVI_7_B_LS: SLOT10.C10(VI_7_B_LS)
SL10_FPVI_7_C_HF: SLOT10.A5(VI_7_C_HF[1]) SLOT10.B5(VI_7_C_HF[2]) SLOT10.C5(VI_7_C_HF[3])
SL10_FPVI_7_C_HS: SLOT10.C12(VI_7_C_HS)
SL10_FPVI_7_C_LF: SLOT10.A3(VI_7_C_LF[1]) SLOT10.B3(VI_7_C_LF[2]) SLOT10.C3(VI_7_C_LF[3])
SL10_FPVI_7_C_LS: SLOT10.D12(VI_7_C_LS)
SL10_FPVI_7_D_HF: SLOT10.A60(VI_7_D_HF[1]) SLOT10.B60(VI_7_D_HF[2]) SLOT10.C60(VI_7_D_HF[3])
SL10_FPVI_7_D_HS: SLOT10.A8(VI_7_D_HS)
SL10_FPVI_7_D_LF: SLOT10.A58(VI_7_D_LF[1]) SLOT10.B58(VI_7_D_LF[2]) SLOT10.C58(VI_7_D_LF[3])
SL10_FPVI_7_D_LS: SLOT10.A6(VI_7_D_LS)
SL10_FPVI_8_A_HF: SLOT10.A48(VI_8_A_HF[1]) SLOT10.B48(VI_8_A_HF[2]) SLOT10.C48(VI_8_A_HF[3])
SL10_FPVI_8_A_HS: SLOT10.G2(VI_8_A_HS)
SL10_FPVI_8_A_LF: SLOT10.A46(VI_8_A_LF[1]) SLOT10.B46(VI_8_A_LF[2]) SLOT10.C46(VI_8_A_LF[3])
SL10_FPVI_8_A_LS: SLOT10.F1(VI_8_A_LS)
SL10_FPVI_8_ALTA_HF: SLOT10.A34(VI_8_ALTA_HF[1]) SLOT10.B34(VI_8_ALTA_HF[2]) SLOT10.B36(VI_8_ALTA_HF[3])
SL10_FPVI_8_ALTA_HS: SLOT10.D2(VI_8_ALTA_HS)
SL10_FPVI_8_ALTA_LF: SLOT10.A32(VI_8_ALTA_LF[1]) SLOT10.B32(VI_8_ALTA_LF[2]) SLOT10.C32(VI_8_ALTA_LF[3])
SL10_FPVI_8_ALTA_LS: SLOT10.B1(VI_8_ALTA_LS)
SL10_FPVI_8_ALTB_HF: SLOT10.B30(VI_8_ALTB_HF[1]) SLOT10.C30(VI_8_ALTB_HF[2]) SLOT10.D32(VI_8_ALTB_HF[3])
SL10_FPVI_8_ALTB_HS: SLOT10.C2(VI_8_ALTB_HS)
SL10_FPVI_8_ALTB_LF: SLOT10.A28(VI_8_ALTB_LF[1]) SLOT10.B28(VI_8_ALTB_LF[2]) SLOT10.C28(VI_8_ALTB_LF[3])
SL10_FPVI_8_ALTB_LS: SLOT10.A1(VI_8_ALTB_LS)
SL10_FPVI_8_B_HF: SLOT10.B44(VI_8_B_HF[1]) SLOT10.C44(VI_8_B_HF[2]) SLOT10.D46(VI_8_B_HF[3])
SL10_FPVI_8_B_HS: SLOT10.G4(VI_8_B_HS)
SL10_FPVI_8_B_LF: SLOT10.A42(VI_8_B_LF[1]) SLOT10.A44(VI_8_B_LF[2]) SLOT10.B42(VI_8_B_LF[3])
SL10_FPVI_8_B_LS: SLOT10.E1(VI_8_B_LS)
SL10_FPVI_8_C_HF: SLOT10.C42(VI_8_C_HF[1]) SLOT10.D42(VI_8_C_HF[2]) SLOT10.E42(VI_8_C_HF[3])
SL10_FPVI_8_C_HS: SLOT10.F2(VI_8_C_HS)
SL10_FPVI_8_C_LF: SLOT10.A40(VI_8_C_LF[1]) SLOT10.B40(VI_8_C_LF[2]) SLOT10.C40(VI_8_C_LF[3])
SL10_FPVI_8_C_LS: SLOT10.D1(VI_8_C_LS)
SL10_FPVI_8_D_HF: SLOT10.A38(VI_8_D_HF[1]) SLOT10.B38(VI_8_D_HF[2]) SLOT10.C38(VI_8_D_HF[3])
SL10_FPVI_8_D_HS: SLOT10.E2(VI_8_D_HS)
SL10_FPVI_8_D_LF: SLOT10.C36(VI_8_D_LF[1]) SLOT10.D36(VI_8_D_LF[2]) SLOT10.E36(VI_8_D_LF[3])
SL10_FPVI_8_D_LS: SLOT10.C1(VI_8_D_LS)
SL13_DP_0: SLOT13.C61 ; also on sheet 54
SL13_DP_1: SLOT13.D61 ; also on sheet 54
SL13_DP_2: SLOT13.E61 ; also on sheet 54
SL13_DP_3: SLOT13.F61 ; also on sheet 54
SL13_DP_4: SLOT13.A59 ; also on sheet 54
SL13_DP_5: SLOT13.B59 ; also on sheet 54
SL13_DP_6: SLOT13.C59 ; also on sheet 54
SL13_DP_7: SLOT13.D59 ; also on sheet 54
SL13_DP_8: SLOT13.E59 ; also on sheet 53
SL13_DP_9: SLOT13.F59 ; also on sheet 53
SL13_DP_10: SLOT13.Z59 ; also on sheet 53
SL13_DP_11: SLOT13.Z57 ; also on sheet 53
SL13_DP_12: SLOT13.A57 ; also on sheet 53
SL13_DP_13: SLOT13.B57 ; also on sheet 53
SL13_DP_14: SLOT13.C57 ; also on sheet 53
SL13_DP_15: SLOT13.D57 ; also on sheet 53
SL13_DP_16: SLOT13.E57 ; also on sheet 53
SL13_DP_17: SLOT13.F57 ; also on sheet 53
SL13_DP_18: SLOT13.A55 ; also on sheet 53
SL13_DP_19: SLOT13.B55 ; also on sheet 53
SL13_DP_20: SLOT13.C55 ; also on sheet 53
SL13_DP_21: SLOT13.D55 ; also on sheet 52
SL13_DP_22: SLOT13.E55 ; also on sheet 52
SL13_DP_23: SLOT13.F55 ; also on sheet 52
SL13_DP_24: SLOT13.Z55 ; also on sheet 52
SL13_DP_25: SLOT13.Z53 ; also on sheet 52
SL13_DP_26: SLOT13.A53 ; also on sheet 52
SL13_DP_27: SLOT13.B53 ; also on sheet 52
SL13_DP_28: SLOT13.C53 ; also on sheet 52
SL13_DP_29: SLOT13.D53 ; also on sheet 52
SL13_DP_30: SLOT13.E53 ; also on sheet 46
SL13_DP_31: SLOT13.F53 ; also on sheet 46
SL13_DP_32: SLOT13.A51 ; also on sheet 46
SL13_DP_33: SLOT13.B51 ; also on sheet 46
SL13_DP_34: SLOT13.C51 ; also on sheet 46
SL13_DP_35: SLOT13.D51 ; also on sheet 46
SL13_DP_36: SLOT13.E51 ; also on sheet 46
SL13_DP_37: SLOT13.F51 ; also on sheet 46
SL13_DP_38: SLOT13.A49 ; also on sheet 45
SL13_DP_39: SLOT13.B49 ; also on sheet 45
SL13_DP_40: SLOT13.C49 ; also on sheet 45
SL13_DP_41: SLOT13.D49 ; also on sheet 45
SL13_DP_42: SLOT13.E49 ; also on sheet 45
SL13_DP_43: SLOT13.F49 ; also on sheet 45
SL13_DP_44: SLOT13.Z49 ; also on sheet 45
SL13_DP_45: SLOT13.Z47 ; also on sheet 45
SL13_DP_46: SLOT13.A47 ; also on sheet 45
SL13_DP_47: SLOT13.B47 ; also on sheet 45
SL13_DP_48: SLOT13.C47 ; also on sheet 45
SL13_DP_49: SLOT13.D47 ; also on sheet 45
SL13_DP_50: SLOT13.E47 ; also on sheet 45
SL13_DP_51: SLOT13.F47 ; also on sheet 44
SL13_DP_52: SLOT13.A45 ; also on sheet 44
SL13_DP_53: SLOT13.B45 ; also on sheet 44
SL13_DP_54: SLOT13.C45 ; also on sheet 44
SL13_DP_55: SLOT13.D45 ; also on sheet 44
SL13_DP_56: SLOT13.E45 ; also on sheet 44
SL13_DP_57: SLOT13.F45 ; also on sheet 44
SL13_DP_58: SLOT13.Z45 ; also on sheet 44
SL13_DP_59: SLOT13.Z43 ; also on sheet 44
SL13_DP_60: SLOT13.A43 ; also on sheet 38
SL13_DP_61: SLOT13.B43 ; also on sheet 38
SL13_DP_62: SLOT13.C43 ; also on sheet 38
SL13_DP_63: SLOT13.D43 ; also on sheet 38
SL13_DP_64: SLOT13.A37 ; also on sheet 38
SL13_DP_65: SLOT13.B37 ; also on sheet 38
SL13_DP_66: SLOT13.C37 ; also on sheet 38
SL13_DP_67: SLOT13.D37 ; also on sheet 38
SL13_DP_68: SLOT13.E37 ; also on sheet 37
SL13_DP_69: SLOT13.F37 ; also on sheet 37
SL13_DP_70: SLOT13.A35 ; also on sheet 37
SL13_DP_71: SLOT13.B35 ; also on sheet 37
SL13_DP_72: SLOT13.C35 ; also on sheet 37
SL13_DP_73: SLOT13.D35 ; also on sheet 37
SL13_DP_74: SLOT13.E35 ; also on sheet 37
SL13_DP_75: SLOT13.F35 ; also on sheet 37
SL13_DP_76: SLOT13.Z35 ; also on sheet 37
SL13_DP_77: SLOT13.Z33 ; also on sheet 37
SL13_DP_78: SLOT13.A33 ; also on sheet 37
SL13_DP_79: SLOT13.B33 ; also on sheet 37
SL13_DP_80: SLOT13.C33 ; also on sheet 37
SL13_DP_81: SLOT13.D33 ; also on sheet 36
SL13_DP_82: SLOT13.E33 ; also on sheet 36
SL13_DP_83: SLOT13.F33 ; also on sheet 36
SL13_DP_84: SLOT13.A31 ; also on sheet 36
SL13_DP_85: SLOT13.B31 ; also on sheet 36
SL13_DP_86: SLOT13.C31 ; also on sheet 36
SL13_DP_87: SLOT13.D31 ; also on sheet 36
SL13_DP_88: SLOT13.E31 ; also on sheet 36
SL13_DP_89: SLOT13.F31 ; also on sheet 36
SL13_DP_90: SLOT13.Z31 ; also on sheet 30
SL13_DP_91: SLOT13.Z29 ; also on sheet 30
SL13_DP_92: SLOT13.A29 ; also on sheet 30
SL13_DP_93: SLOT13.B29 ; also on sheet 30
SL13_DP_94: SLOT13.C29 ; also on sheet 30
SL13_DP_95: SLOT13.D29 ; also on sheet 30
SL13_DP_96: SLOT13.E29 ; also on sheet 30
SL13_DP_97: SLOT13.F29 ; also on sheet 30
SL13_DP_98: SLOT13.A27 ; also on sheet 29
SL13_DP_99: SLOT13.B27 ; also on sheet 29
SL13_DP_100: SLOT13.C27 ; also on sheet 29
SL13_DP_101: SLOT13.D27 ; also on sheet 29
SL13_DP_102: SLOT13.E27 ; also on sheet 29
SL13_DP_103: SLOT13.F27 ; also on sheet 29
SL13_DP_104: SLOT13.Z27 ; also on sheet 29
SL13_DP_105: SLOT13.Z25 ; also on sheet 29
SL13_DP_106: SLOT13.A25 ; also on sheet 29
SL13_DP_107: SLOT13.B25 ; also on sheet 29
SL13_DP_108: SLOT13.C25 ; also on sheet 29
SL13_DP_109: SLOT13.D25 ; also on sheet 29
SL13_DP_110: SLOT13.E25 ; also on sheet 29
SL13_DP_111: SLOT13.F25 ; also on sheet 28
SL13_DP_112: SLOT13.A23 ; also on sheet 28
SL13_DP_113: SLOT13.B23 ; also on sheet 28
SL13_DP_114: SLOT13.C23 ; also on sheet 28
SL13_DP_115: SLOT13.D23 ; also on sheet 28
SL13_DP_116: SLOT13.E23 ; also on sheet 28
SL13_DP_117: SLOT13.F23 ; also on sheet 28
SL13_DP_118: SLOT13.Z23 ; also on sheet 28
SL13_DP_119: SLOT13.Z21 ; also on sheet 28
SL13_DP_120: SLOT13.A21
SL13_DP_121: SLOT13.B21 ; also on sheet 51
SL13_DP_122: SLOT13.C21 ; also on sheet 51
SL13_DP_123: SLOT13.D21 ; also on sheet 51
SL13_DP_124: SLOT13.E21 ; also on sheet 51
SL13_DP_125: SLOT13.F21 ; also on sheet 51
SL13_DP_126: SLOT13.B19 ; also on sheet 51
SL13_DP_127: SLOT13.C19 ; also on sheet 43
SL13_DP_128: SLOT13.E43 ; also on sheet 43
SL13_DP_129: SLOT13.F43 ; also on sheet 43
SL13_DP_130: SLOT13.A41 ; also on sheet 43
SL13_DP_131: SLOT13.B41 ; also on sheet 43
SL13_DP_132: SLOT13.C41 ; also on sheet 43
SL13_DP_133: SLOT13.D41 ; also on sheet 35
SL13_DP_134: SLOT13.E41 ; also on sheet 35
SL13_DP_135: SLOT13.F41 ; also on sheet 35
SL13_DP_136: SLOT13.Z41 ; also on sheet 35
SL13_DP_137: SLOT13.Z39 ; also on sheet 35
SL13_DP_138: SLOT13.A39 ; also on sheet 35
SL13_DP_139: SLOT13.B39 ; also on sheet 27
SL13_DP_140: SLOT13.C39 ; also on sheet 27
SL13_DP_141: SLOT13.D39 ; also on sheet 27
SL13_DP_142: SLOT13.E39 ; also on sheet 27
SL13_DP_143: SLOT13.F39 ; also on sheet 27
SL13_DP_144: SLOT13.A17 ; also on sheet 27
SL13_DP_145: SLOT13.B17
SL13_DP_146: SLOT13.C17
SL13_DP_147: SLOT13.D17
SL13_DP_148: SLOT13.E17
SL13_DP_149: SLOT13.F17
SL13_DP_150: SLOT13.A15
SL13_DP_151: SLOT13.B15
SL13_DP_152: SLOT13.C15
SL13_DP_153: SLOT13.D15
SL13_DP_154: SLOT13.E15
SL13_DP_155: SLOT13.F15
SL13_DP_156: SLOT13.Z15
SL13_DP_157: SLOT13.Z13
SL13_DP_158: SLOT13.A13
SL13_DP_159: SLOT13.B13
SL13_DP_160: SLOT13.C13
SL13_DP_161: SLOT13.D13
SL13_DP_162: SLOT13.E13
SL13_DP_163: SLOT13.F13
SL13_DP_164: SLOT13.A11
SL13_DP_165: SLOT13.B11
SL13_DP_166: SLOT13.C11
SL13_DP_167: SLOT13.D11
SL13_DP_168: SLOT13.E11
SL13_DP_169: SLOT13.F11
SL13_DP_170: SLOT13.Z11
SL13_DP_171: SLOT13.Z9
SL13_DP_172: SLOT13.A9
SL13_DP_173: SLOT13.B9
SL13_DP_174: SLOT13.C9
SL13_DP_175: SLOT13.D9
SL13_DP_176: SLOT13.E9
SL13_DP_177: SLOT13.F9
SL13_DP_178: SLOT13.A7
SL13_DP_179: SLOT13.B7
SL13_DP_180: SLOT13.C7
SL13_DP_181: SLOT13.D7
SL13_DP_182: SLOT13.E7
SL13_DP_183: SLOT13.F7
SL13_DP_184: SLOT13.Z7
SL13_DP_185: SLOT13.Z5
SL13_DP_186: SLOT13.A5
SL13_DP_187: SLOT13.B5
SL13_DP_188: SLOT13.C5
SL13_DP_189: SLOT13.D5
SL13_DP_190: SLOT13.E5
SL13_DP_191: SLOT13.F5
SL13_GND_SENSE: SLOT13.F19 ; also on sheet 22
SL14_PMVI_1_BP: SLOT14.B35
SL14_PMVI_1_HF: SLOT14.F35 ; also on sheet 50
SL14_PMVI_1_HS: SLOT14.C35 ; also on sheet 50
SL14_PMVI_1_LS: SLOT14.A35 ; also on sheet 47
SL14_PMVI_2_BP: SLOT14.B33
SL14_PMVI_2_HF: SLOT14.F33 ; also on sheet 42
SL14_PMVI_2_HS: SLOT14.C33 ; also on sheet 42
SL14_PMVI_2_LS: SLOT14.A33 ; also on sheet 39
SL14_PMVI_3_BP: SLOT14.B31
SL14_PMVI_3_HF: SLOT14.F31 ; also on sheet 34
SL14_PMVI_3_HS: SLOT14.C31 ; also on sheet 34
SL14_PMVI_3_LS: SLOT14.A31 ; also on sheet 31
SL14_PMVI_4_BP: SLOT14.B29
SL14_PMVI_4_HF: SLOT14.F29 ; also on sheet 26
SL14_PMVI_4_HS: SLOT14.C29 ; also on sheet 26
SL14_PMVI_4_LS: SLOT14.A29 ; also on sheet 23
SL14_PMVI_5_BP: SLOT14.B27
SL14_PMVI_5_HF: SLOT14.F27
SL14_PMVI_5_HS: SLOT14.C27
SL14_PMVI_5_LS: SLOT14.A27
SL14_PMVI_6_BP: SLOT14.B25
SL14_PMVI_6_HF: SLOT14.F25
SL14_PMVI_6_HS: SLOT14.C25
SL14_PMVI_6_LS: SLOT14.A25
SL14_PMVI_7_BP: SLOT14.B23
SL14_PMVI_7_HF: SLOT14.F23
SL14_PMVI_7_HS: SLOT14.C23
SL14_PMVI_7_LS: SLOT14.A23
SL14_PMVI_8_BP: SLOT14.B21
SL14_PMVI_8_HF: SLOT14.F21
SL14_PMVI_8_HS: SLOT14.C21
SL14_PMVI_8_LS: SLOT14.A21
SL14_PMVI_9_BP: SLOT14.D37
SL14_PMVI_9_HF: SLOT14.F37
SL14_PMVI_9_HS: SLOT14.E37
SL14_PMVI_9_LS: SLOT14.C37
SL14_PMVI_10_BP: SLOT14.D33
SL14_PMVI_10_HF: SLOT14.E35 ; also on sheet 47
SL14_PMVI_10_HS: SLOT14.E33 ; also on sheet 47
SL14_PMVI_10_LS: SLOT14.B37 ; also on sheet 47
SL14_PMVI_11_BP: SLOT14.D29
SL14_PMVI_11_HF: SLOT14.E31 ; also on sheet 47
SL14_PMVI_11_HS: SLOT14.E29 ; also on sheet 47
SL14_PMVI_11_LS: SLOT14.A37 ; also on sheet 47
SL14_PMVI_12_BP: SLOT14.D25
SL14_PMVI_12_HF: SLOT14.E27 ; also on sheet 47
SL14_PMVI_12_HS: SLOT14.E25 ; also on sheet 47
SL14_PMVI_12_LS: SLOT14.B19 ; also on sheet 47
SL14_PMVI_13_BP: SLOT14.D21
SL14_PMVI_13_HF: SLOT14.E23 ; also on sheet 47
SL14_PMVI_13_HS: SLOT14.E21 ; also on sheet 47
SL14_PMVI_13_LS: SLOT14.A19 ; also on sheet 47
SL14_PMVI_14_BP: SLOT14.D19
SL14_PMVI_14_HF: SLOT14.F19 ; also on sheet 47
SL14_PMVI_14_HS: SLOT14.E19 ; also on sheet 47
SL14_PMVI_14_LS: SLOT14.C19 ; also on sheet 47
SL14_PMVI_15_BP: SLOT14.D17
SL14_PMVI_15_HF: SLOT14.F17 ; also on sheet 47
SL14_PMVI_15_HS: SLOT14.E17 ; also on sheet 47
SL14_PMVI_15_LS: SLOT14.A17 ; also on sheet 47
SL14_PMVI_16_BP: SLOT14.C17
SL14_PMVI_16_HF: SLOT14.E15 ; also on sheet 47
SL14_PMVI_16_HS: SLOT14.D15 ; also on sheet 47
SL14_PMVI_16_LS: SLOT14.B17 ; also on sheet 47
SL14_PMVI_17_BP: SLOT14.B15
SL14_PMVI_17_HF: SLOT14.F15 ; also on sheet 47
SL14_PMVI_17_HS: SLOT14.C15 ; also on sheet 47
SL14_PMVI_17_LS: SLOT14.A15 ; also on sheet 47
SL14_PMVI_18_BP: SLOT14.D13
SL14_PMVI_18_HF: SLOT14.F13 ; also on sheet 47
SL14_PMVI_18_HS: SLOT14.E13 ; also on sheet 47
SL14_PMVI_18_LS: SLOT14.A13 ; also on sheet 47
SL14_PMVI_19_BP: SLOT14.D11
SL14_PMVI_19_HF: SLOT14.F11 ; also on sheet 47
SL14_PMVI_19_HS: SLOT14.E11 ; also on sheet 47
SL14_PMVI_19_LS: SLOT14.B13 ; also on sheet 47
SL14_PMVI_20_BP: SLOT14.C11
SL14_PMVI_20_HF: SLOT14.E9 ; also on sheet 39
SL14_PMVI_20_HS: SLOT14.D9 ; also on sheet 39
SL14_PMVI_20_LS: SLOT14.C13 ; also on sheet 39
SL14_PMVI_21_BP: SLOT14.B9
SL14_PMVI_21_HF: SLOT14.F9 ; also on sheet 39
SL14_PMVI_21_HS: SLOT14.C9 ; also on sheet 39
SL14_PMVI_21_LS: SLOT14.B11 ; also on sheet 39
SL14_PMVI_22_BP: SLOT14.D7
SL14_PMVI_22_HF: SLOT14.F7 ; also on sheet 39
SL14_PMVI_22_HS: SLOT14.E7 ; also on sheet 39
SL14_PMVI_22_LS: SLOT14.A11 ; also on sheet 39
SL14_PMVI_23_BP: SLOT14.D5
SL14_PMVI_23_HF: SLOT14.F5 ; also on sheet 39
SL14_PMVI_23_HS: SLOT14.E5 ; also on sheet 39
SL14_PMVI_23_LS: SLOT14.A9 ; also on sheet 39
SL14_PMVI_24_BP: SLOT14.D3
SL14_PMVI_24_HF: SLOT14.F3 ; also on sheet 39
SL14_PMVI_24_HS: SLOT14.E3 ; also on sheet 39
SL14_PMVI_24_LS: SLOT14.A7 ; also on sheet 39
SL14_PMVI_25_BP: SLOT14.D1
SL14_PMVI_25_HF: SLOT14.F1 ; also on sheet 39
SL14_PMVI_25_HS: SLOT14.E1 ; also on sheet 39
SL14_PMVI_25_LS: SLOT14.B7 ; also on sheet 39
SL14_PMVI_26_BP: SLOT14.C3
SL14_PMVI_26_HF: SLOT14.G4 ; also on sheet 39
SL14_PMVI_26_HS: SLOT14.C1 ; also on sheet 39
SL14_PMVI_26_LS: SLOT14.C7 ; also on sheet 39
SL14_PMVI_27_BP: SLOT14.D2
SL14_PMVI_27_HF: SLOT14.F2 ; also on sheet 39
SL14_PMVI_27_HS: SLOT14.C4 ; also on sheet 39
SL14_PMVI_27_LS: SLOT14.C5 ; also on sheet 39
SL14_PMVI_28_BP: SLOT14.B3
SL14_PMVI_28_HF: SLOT14.A4 ; also on sheet 39
SL14_PMVI_28_HS: SLOT14.B1 ; also on sheet 39
SL14_PMVI_28_LS: SLOT14.B5 ; also on sheet 39
SL14_PMVI_29_BP: SLOT14.A3
SL14_PMVI_29_HF: SLOT14.B2 ; also on sheet 39
SL14_PMVI_29_HS: SLOT14.A1 ; also on sheet 39
SL14_PMVI_29_LS: SLOT14.A5 ; also on sheet 39
SL14_PMVI_30_BP: SLOT14.A60
SL14_PMVI_30_HF: SLOT14.B62 ; also on sheet 31
SL14_PMVI_30_HS: SLOT14.A61 ; also on sheet 31
SL14_PMVI_30_LS: SLOT14.B58 ; also on sheet 31
SL14_PMVI_31_BP: SLOT14.A59
SL14_PMVI_31_HF: SLOT14.C62 ; also on sheet 31
SL14_PMVI_31_HS: SLOT14.B61 ; also on sheet 31
SL14_PMVI_31_LS: SLOT14.A57 ; also on sheet 31
SL14_PMVI_32_BP: SLOT14.E60
SL14_PMVI_32_HF: SLOT14.F62 ; also on sheet 31
SL14_PMVI_32_HS: SLOT14.F61 ; also on sheet 31
SL14_PMVI_32_LS: SLOT14.C60 ; also on sheet 31
SL14_PMVI_33_BP: SLOT14.D61
SL14_PMVI_33_HF: SLOT14.E62 ; also on sheet 31
SL14_PMVI_33_HS: SLOT14.E61 ; also on sheet 31
SL14_PMVI_33_LS: SLOT14.C61 ; also on sheet 31
SL14_PMVI_34_BP: SLOT14.C59
SL14_PMVI_34_HF: SLOT14.F59 ; also on sheet 31
SL14_PMVI_34_HS: SLOT14.D59 ; also on sheet 31
SL14_PMVI_34_LS: SLOT14.B59 ; also on sheet 31
SL14_PMVI_35_BP: SLOT14.F58
SL14_PMVI_35_HF: SLOT14.G60 ; also on sheet 31
SL14_PMVI_35_HS: SLOT14.E59 ; also on sheet 31
SL14_PMVI_35_LS: SLOT14.D58 ; also on sheet 31
SL14_PMVI_36_BP: SLOT14.C57
SL14_PMVI_36_HF: SLOT14.E57 ; also on sheet 31
SL14_PMVI_36_HS: SLOT14.D57 ; also on sheet 31
SL14_PMVI_36_LS: SLOT14.B57 ; also on sheet 31
SL14_PMVI_37_BP: SLOT14.E56
SL14_PMVI_37_HF: SLOT14.F57 ; also on sheet 31
SL14_PMVI_37_HS: SLOT14.G56 ; also on sheet 31
SL14_PMVI_37_LS: SLOT14.C56 ; also on sheet 31
SL14_PMVI_38_BP: SLOT14.D55
SL14_PMVI_38_HF: SLOT14.F55 ; also on sheet 31
SL14_PMVI_38_HS: SLOT14.E55 ; also on sheet 31
SL14_PMVI_38_LS: SLOT14.B55 ; also on sheet 31
SL14_PMVI_39_BP: SLOT14.B54
SL14_PMVI_39_HF: SLOT14.E52 ; also on sheet 31
SL14_PMVI_39_HS: SLOT14.C55 ; also on sheet 31
SL14_PMVI_39_LS: SLOT14.A55 ; also on sheet 31
SL14_PMVI_40_BP: SLOT14.D54
SL14_PMVI_40_HF: SLOT14.G52 ; also on sheet 23
SL14_PMVI_40_HS: SLOT14.F54 ; also on sheet 23
SL14_PMVI_40_LS: SLOT14.A56 ; also on sheet 23
SL14_PMVI_41_BP: SLOT14.B53
SL14_PMVI_41_HF: SLOT14.F53 ; also on sheet 23
SL14_PMVI_41_HS: SLOT14.C53 ; also on sheet 23
SL14_PMVI_41_LS: SLOT14.A53 ; also on sheet 23
SL14_PMVI_42_BP: SLOT14.D53
SL14_PMVI_42_HF: SLOT14.F51 ; also on sheet 23
SL14_PMVI_42_HS: SLOT14.E53 ; also on sheet 23
SL14_PMVI_42_LS: SLOT14.A52 ; also on sheet 23
SL14_PMVI_43_BP: SLOT14.C51
SL14_PMVI_43_HF: SLOT14.E51 ; also on sheet 23
SL14_PMVI_43_HS: SLOT14.D51 ; also on sheet 23
SL14_PMVI_43_LS: SLOT14.C52 ; also on sheet 23
SL14_PMVI_44_BP: SLOT14.D50
SL14_PMVI_44_HF: SLOT14.F49 ; also on sheet 23
SL14_PMVI_44_HS: SLOT14.F50 ; also on sheet 23
SL14_PMVI_44_LS: SLOT14.A51 ; also on sheet 23
SL14_PMVI_45_BP: SLOT14.B50
SL14_PMVI_45_HF: SLOT14.E49 ; also on sheet 23
SL14_PMVI_45_HS: SLOT14.D49 ; also on sheet 23
SL14_PMVI_45_LS: SLOT14.B51 ; also on sheet 23
SL14_PMVI_46_BP: SLOT14.B49
SL14_PMVI_46_HF: SLOT14.G48 ; also on sheet 23
SL14_PMVI_46_HS: SLOT14.C49 ; also on sheet 23
SL14_PMVI_46_LS: SLOT14.A49 ; also on sheet 23
SL14_PMVI_47_BP: SLOT14.D47
SL14_PMVI_47_HF: SLOT14.F47 ; also on sheet 23
SL14_PMVI_47_HS: SLOT14.E47 ; also on sheet 23
SL14_PMVI_47_LS: SLOT14.A48 ; also on sheet 23
SL14_PMVI_48_BP: SLOT14.C45
SL14_PMVI_48_HF: SLOT14.F45 ; also on sheet 23
SL14_PMVI_48_HS: SLOT14.D46 ; also on sheet 23
SL14_PMVI_48_LS: SLOT14.C48 ; also on sheet 23
SL14_PMVI_49_BP: SLOT14.C47
SL14_PMVI_49_HF: SLOT14.F46 ; also on sheet 23
SL14_PMVI_49_HS: SLOT14.E45 ; also on sheet 23
SL14_PMVI_49_LS: SLOT14.E48 ; also on sheet 23
SL14_PMVI_50_BP: SLOT14.B46
SL14_PMVI_50_HF: SLOT14.G44
SL14_PMVI_50_HS: SLOT14.B45
SL14_PMVI_50_LS: SLOT14.B47
SL14_PMVI_51_BP: SLOT14.D45
SL14_PMVI_51_HF: SLOT14.F41
SL14_PMVI_51_HS: SLOT14.E43
SL14_PMVI_51_LS: SLOT14.A47
SL14_PMVI_52_BP: SLOT14.D43
SL14_PMVI_52_HF: SLOT14.F43
SL14_PMVI_52_HS: SLOT14.F42
SL14_PMVI_52_LS: SLOT14.A45
SL14_PMVI_53_BP: SLOT14.D42
SL14_PMVI_53_HF: SLOT14.G40
SL14_PMVI_53_HS: SLOT14.E41
SL14_PMVI_53_LS: SLOT14.A44
SL14_PMVI_54_BP: SLOT14.C41
SL14_PMVI_54_HF: SLOT14.F39
SL14_PMVI_54_HS: SLOT14.D41
SL14_PMVI_54_LS: SLOT14.C44
SL14_PMVI_55_BP: SLOT14.B41
SL14_PMVI_55_HF: SLOT14.F38
SL14_PMVI_55_HS: SLOT14.B39
SL14_PMVI_55_LS: SLOT14.E44
SL14_PMVI_56_BP: SLOT14.C39
SL14_PMVI_56_HF: SLOT14.E39
SL14_PMVI_56_HS: SLOT14.D39
SL14_PMVI_56_LS: SLOT14.C43
SL14_PMVI_57_BP: SLOT14.A41
SL14_PMVI_57_HF: SLOT14.E40
SL14_PMVI_57_HS: SLOT14.A39
SL14_PMVI_57_LS: SLOT14.B43
SL14_PMVI_58_BP: SLOT14.B42
SL14_PMVI_58_HF: SLOT14.C40
SL14_PMVI_58_HS: SLOT14.A40
SL14_PMVI_58_LS: SLOT14.A43
SL14_PMVI_59_BP: SLOT14.C36
SL14_PMVI_59_HF: SLOT14.G36
SL14_PMVI_59_HS: SLOT14.E36
SL14_PMVI_59_LS: SLOT14.D38
SL14_PMVI_60_BP: SLOT14.D34
SL14_PMVI_60_HF: SLOT14.G32
SL14_PMVI_60_HS: SLOT14.E32
SL14_PMVI_60_LS: SLOT14.B38
SL14_PMVI_61_BP: SLOT14.E24
SL14_PMVI_61_HF: SLOT14.E28
SL14_PMVI_61_HS: SLOT14.F26
SL14_PMVI_61_LS: SLOT14.A36
SL14_PMVI_62_BP: SLOT14.F18
SL14_PMVI_62_HF: SLOT14.G20
SL14_PMVI_62_HS: SLOT14.E16
SL14_PMVI_62_LS: SLOT14.B10
SL14_PMVI_63_BP: SLOT14.E12
SL14_PMVI_63_HF: SLOT14.F14
SL14_PMVI_63_HS: SLOT14.D10
SL14_PMVI_63_LS: SLOT14.A8
SL14_PMVI_64_BP: SLOT14.E8
SL14_PMVI_64_HF: SLOT14.G8
SL14_PMVI_64_HS: SLOT14.F6
SL14_PMVI_64_LS: SLOT14.C8
SL14_PMVI_65_BP: SLOT14.B34
SL14_PMVI_65_HF: SLOT14.F34
SL14_PMVI_65_HS: SLOT14.C32
SL14_PMVI_65_LS: SLOT14.A32
SL14_PMVI_66_BP: SLOT14.D30
SL14_PMVI_66_HF: SLOT14.F30
SL14_PMVI_66_HS: SLOT14.C28
SL14_PMVI_66_LS: SLOT14.B30
SL14_PMVI_67_BP: SLOT14.B26
SL14_PMVI_67_HF: SLOT14.G28
SL14_PMVI_67_HS: SLOT14.D26
SL14_PMVI_67_LS: SLOT14.A28
SL14_PMVI_68_BP: SLOT14.C24
SL14_PMVI_68_HF: SLOT14.G24
SL14_PMVI_68_HS: SLOT14.B22
SL14_PMVI_68_LS: SLOT14.A24
SL14_PMVI_69_BP: SLOT14.C20
SL14_PMVI_69_HF: SLOT14.F22
SL14_PMVI_69_HS: SLOT14.D22
SL14_PMVI_69_LS: SLOT14.A20
SL14_PMVI_70_BP: SLOT14.D18
SL14_PMVI_70_HF: SLOT14.G16
SL14_PMVI_70_HS: SLOT14.E20
SL14_PMVI_70_LS: SLOT14.B18
SL14_PMVI_71_BP: SLOT14.C16
SL14_PMVI_71_HF: SLOT14.G12
SL14_PMVI_71_HS: SLOT14.B14
SL14_PMVI_71_LS: SLOT14.A16
SL14_PMVI_72_BP: SLOT14.C12
SL14_PMVI_72_HF: SLOT14.F10
SL14_PMVI_72_HS: SLOT14.D14
SL14_PMVI_72_LS: SLOT14.A12

Not connected (* = marked no-connect by the designer): SLOT10 A10(MOD_IN_15_26)* G10(MOD_IN_37_48)* NGH1* NGH2* Z5(NC1)* Z7(NC2)* Z9(NC3)* Z11(NC4)* Z13(NC5)* Z15(NC6)* Z17(NC7)* Z19(NC8)* Z21(NC9)* Z23(NC10)* Z25(NC11)* Z27(NC12)* Z29(NC13)* Z31(NC14)* Z33(NC15)* Z35(NC16)* Z37(NC17)* Z39(NC18)* Z41(NC19)* Z43(NC20)* Z45(NC21)* Z47(NC22)* Z49(NC23)* Z51(NC24)* Z53(NC25)* Z55(NC26)* Z57(NC27)* Z59(NC28)* Z61(NC29)*; SLOT11 A1* A2* A3* A4* A5* A6* A7* A8* A9* A10* A11* A12* A13* A14* A15* A16* A17* A18* A19* A20* A21* A22* A23* A24* A25* A26* A27* A28* A29* A30* A31* A32* A33* A34* A35* A36* A37* A38* A39* A40* A41* A42* A43* A44* A45* A46* A47* A48* A49* A50* A51* A52* A53* A54* A55* A56* A57* A58* A59* A60* A61* B1* B2* B3* B4* B5* B6* B7* B8* B9* B10* B11* B12* B13* B14* B15* B16* B17* B18* B19* B20* B21* B22* B23* B24* B25* B26* B27* B28* B29* B30* B31* B32* B33* B34* B35* B36* B37* B38* B39* B40* B41* B42* B43* B44* B45* B46* B47* B48* B49* B50* B51* B52* B53* B54* B55* B56* B57* B58* B59* B60* B61* B62* C1* C2* C3* C4* C5* C6* C7* C8* C9* C10* C11* C12* C13* C14* C15* C16* C17* C18* C19* C20* C21* C22* C23* C24* C25* C26* C27* C28* C29* C30* C31* C32* C33* C34* C35* C36* C37* C38* C39* C40* C41* C42* C43* C44* C45* C46* C47* C48* C49* C50* C51* C52* C53* C54* C55* C56* C57* C58* C59* C60* C61* C62* D1* D2* D3* D4* D5* D6* D7* D8* D9* D10* D11* D12* D13* D14* D15* D16* D17* D18* D19* D20* D21* D22* D23* D24* D25* D26* D27* D28* D29* D30* D31* D32* D33* D34* D35* D36* D37* D38* D39* D40* D41* D42* D43* D44* D45* D46* D47* D48* D49* D50* D51* D52* D53* D54* D55* D56* D57* D58* D59* D60* D61* E1* E2* E3* E4* E5* E6* E7* E8* E9* E10* E11* E12* E13* E14* E15* E16* E17* E18* E19* E20* E21* E22* E23* E24* E25* E26* E27* E28* E29* E30* E31* E32* E33* E34* E35* E36* E37* E38* E39* E40* E41* E42* E43* E44* E45* E46* E47* E48* E49* E50* E51* E52* E53* E54* E55* E56* E57* E58* E59* E60* E61* E62* F1* F2* F3* F4* F5* F6* F7* F8* F9* F10* F11* F12* F13* F14* F15* F16* F17* F18* F19* F20* F21* F22* F23* F24* F25* F26* F27* F28* F29* F30* F31* F32* F33* F34* F35* F36* F37* F38* F39* F40* F41* F42* F43* F44* F45* F46* F47* F48* F49* F50* F51* F52* F53* F54* F55* F56* F57* F58* F59* F60* F61* F62* G2* G4* G6* G8* G10* G12* G14* G16* G18* G20* G22* G24* G26* G28* G30* G32* G34* G36* G38* G40* G42* G44* G46* G48* G50* G52* G54* G56* G58* G60* GH1* GH2* Z5* Z7* Z9* Z11* Z13* Z15* Z17* Z19* Z21* Z23* Z25* Z27* Z29* Z31* Z33* Z35* Z37* Z39* Z41* Z43* Z45* Z47* Z49* Z51* Z53* Z55* Z57* Z59* Z61*; SLOT12 A1* A2* A3* A4* A5* A6* A7* A8* A9* A10* A11* A12* A13* A14* A15* A16* A17* A18* A19* A20* A21* A22* A23* A24* A25* A26* A27* A28* A29* A30* A31* A32* A33* A34* A35* A36* A37* A38* A39* A40* A41* A42* A43* A44* A45* A46* A47* A48* A49* A50* A51* A52* A53* A54* A55* A56* A57* A58* A59* A60* A61* B1* B2* B3* B4* B5* B6* B7* B8* B9* B10* B11* B12* B13* B14* B15* B16* B17* B18* B19* B20* B21* B22* B23* B24* B25* B26* B27* B28* B29* B30* B31* B32* B33* B34* B35* B36* B37* B38* B39* B40* B41* B42* B43* B44* B45* B46* B47* B48* B49* B50* B51* B52* B53* B54* B55* B56* B57* B58* B59* B60* B61* B62* C1* C2* C3* C4* C5* C6* C7* C8* C9* C10* C11* C12* C13* C14* C15* C16* C17* C18* C19* C20* C21* C22* C23* C24* C25* C26* C27* C28* C29* C30* C31* C32* C33* C34* C35* C36* C37* C38* C39* C40* C41* C42* C43* C44* C45* C46* C47* C48* C49* C50* C51* C52* C53* C54* C55* C56* C57* C58* C59* C60* C61* C62* D1* D2* D3* D4* D5* D6* D7* D8* D9* D10* D11* D12* D13* D14* D15* D16* D17* D18* D19* D20* D21* D22* D23* D24* D25* D26* D27* D28* D29* D30* D31* D32* D33* D34* D35* D36* D37* D38* D39* D40* D41* D42* D43* D44* D45* D46* D47* D48* D49* D50* D51* D52* D53* D54* D55* D56* D57* D58* D59* D60* D61* E1* E2* E3* E4* E5* E6* E7* E8* E9* E10* E11* E12* E13* E14* E15* E16* E17* E18* E19* E20* E21* E22* E23* E24* E25* E26* E27* E28* E29* E30* E31* E32* E33* E34* E35* E36* E37* E38* E39* E40* E41* E42* E43* E44* E45* E46* E47* E48* E49* E50* E51* E52* E53* E54* E55* E56* E57* E58* E59* E60* E61* E62* F1* F2* F3* F4* F5* F6* F7* F8* F9* F10* F11* F12* F13* F14* F15* F16* F17* F18* F19* F20* F21* F22* F23* F24* F25* F26* F27* F28* F29* F30* F31* F32* F33* F34* F35* F36* F37* F38* F39* F40* F41* F42* F43* F44* F45* F46* F47* F48* F49* F50* F51* F52* F53* F54* F55* F56* F57* F58* F59* F60* F61* F62* G2* G4* G6* G8* G10* G12* G14* G16* G18* G20* G22* G24* G26* G28* G30* G32* G34* G36* G38* G40* G42* G44* G46* G48* G50* G52* G54* G56* G58* G60* GH1* GH2* Z5* Z7* Z9* Z11* Z13* Z15* Z17* Z19* Z21* Z23* Z25* Z27* Z29* Z31* Z33* Z35* Z37* Z39* Z41* Z43* Z45* Z47* Z49* Z51* Z53* Z55* Z57* Z59* Z61*; SLOT13 A1* A2* A3* A4* A19* A61* B1* B2* B3* B4* B61* B62* C1* C2* C3* C4* C62* D1* D2* D3* D4* D19* E1* E2* E3* E4* E19* E62* F1* F2* F3* F4* F62* G2* G4* G6* G8* G10* G12* G14* G16* G18* G20* G22* G24* G26* G28* G30* G32* G34* G36* G38* G40* G42* G44* G46* G48* G50* G52* G54* G56* G58* G60* GH1* GH2* Z17* Z19* Z37* Z51* Z61*; SLOT14 B6* D6* D23* D27* D31* D35* E4* GH1* GH2* Z5* Z7* Z9* Z11* Z13* Z15* Z17* Z19* Z21* Z23* Z25* Z27* Z29* Z31* Z33* Z35* Z37* Z39* Z41* Z43* Z45* Z47* Z49* Z51* Z53* Z55* Z57* Z59* Z61*

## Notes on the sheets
sheet 7
- PMVIx
sheet 8
- GX1x
sheet 9
- EMPTY
sheet 10
- EMPTY
sheet 11
- FPVI
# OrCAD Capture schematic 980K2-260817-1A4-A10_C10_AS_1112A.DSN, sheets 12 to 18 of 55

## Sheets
12 T09.SLOT09_FPVI: size A2
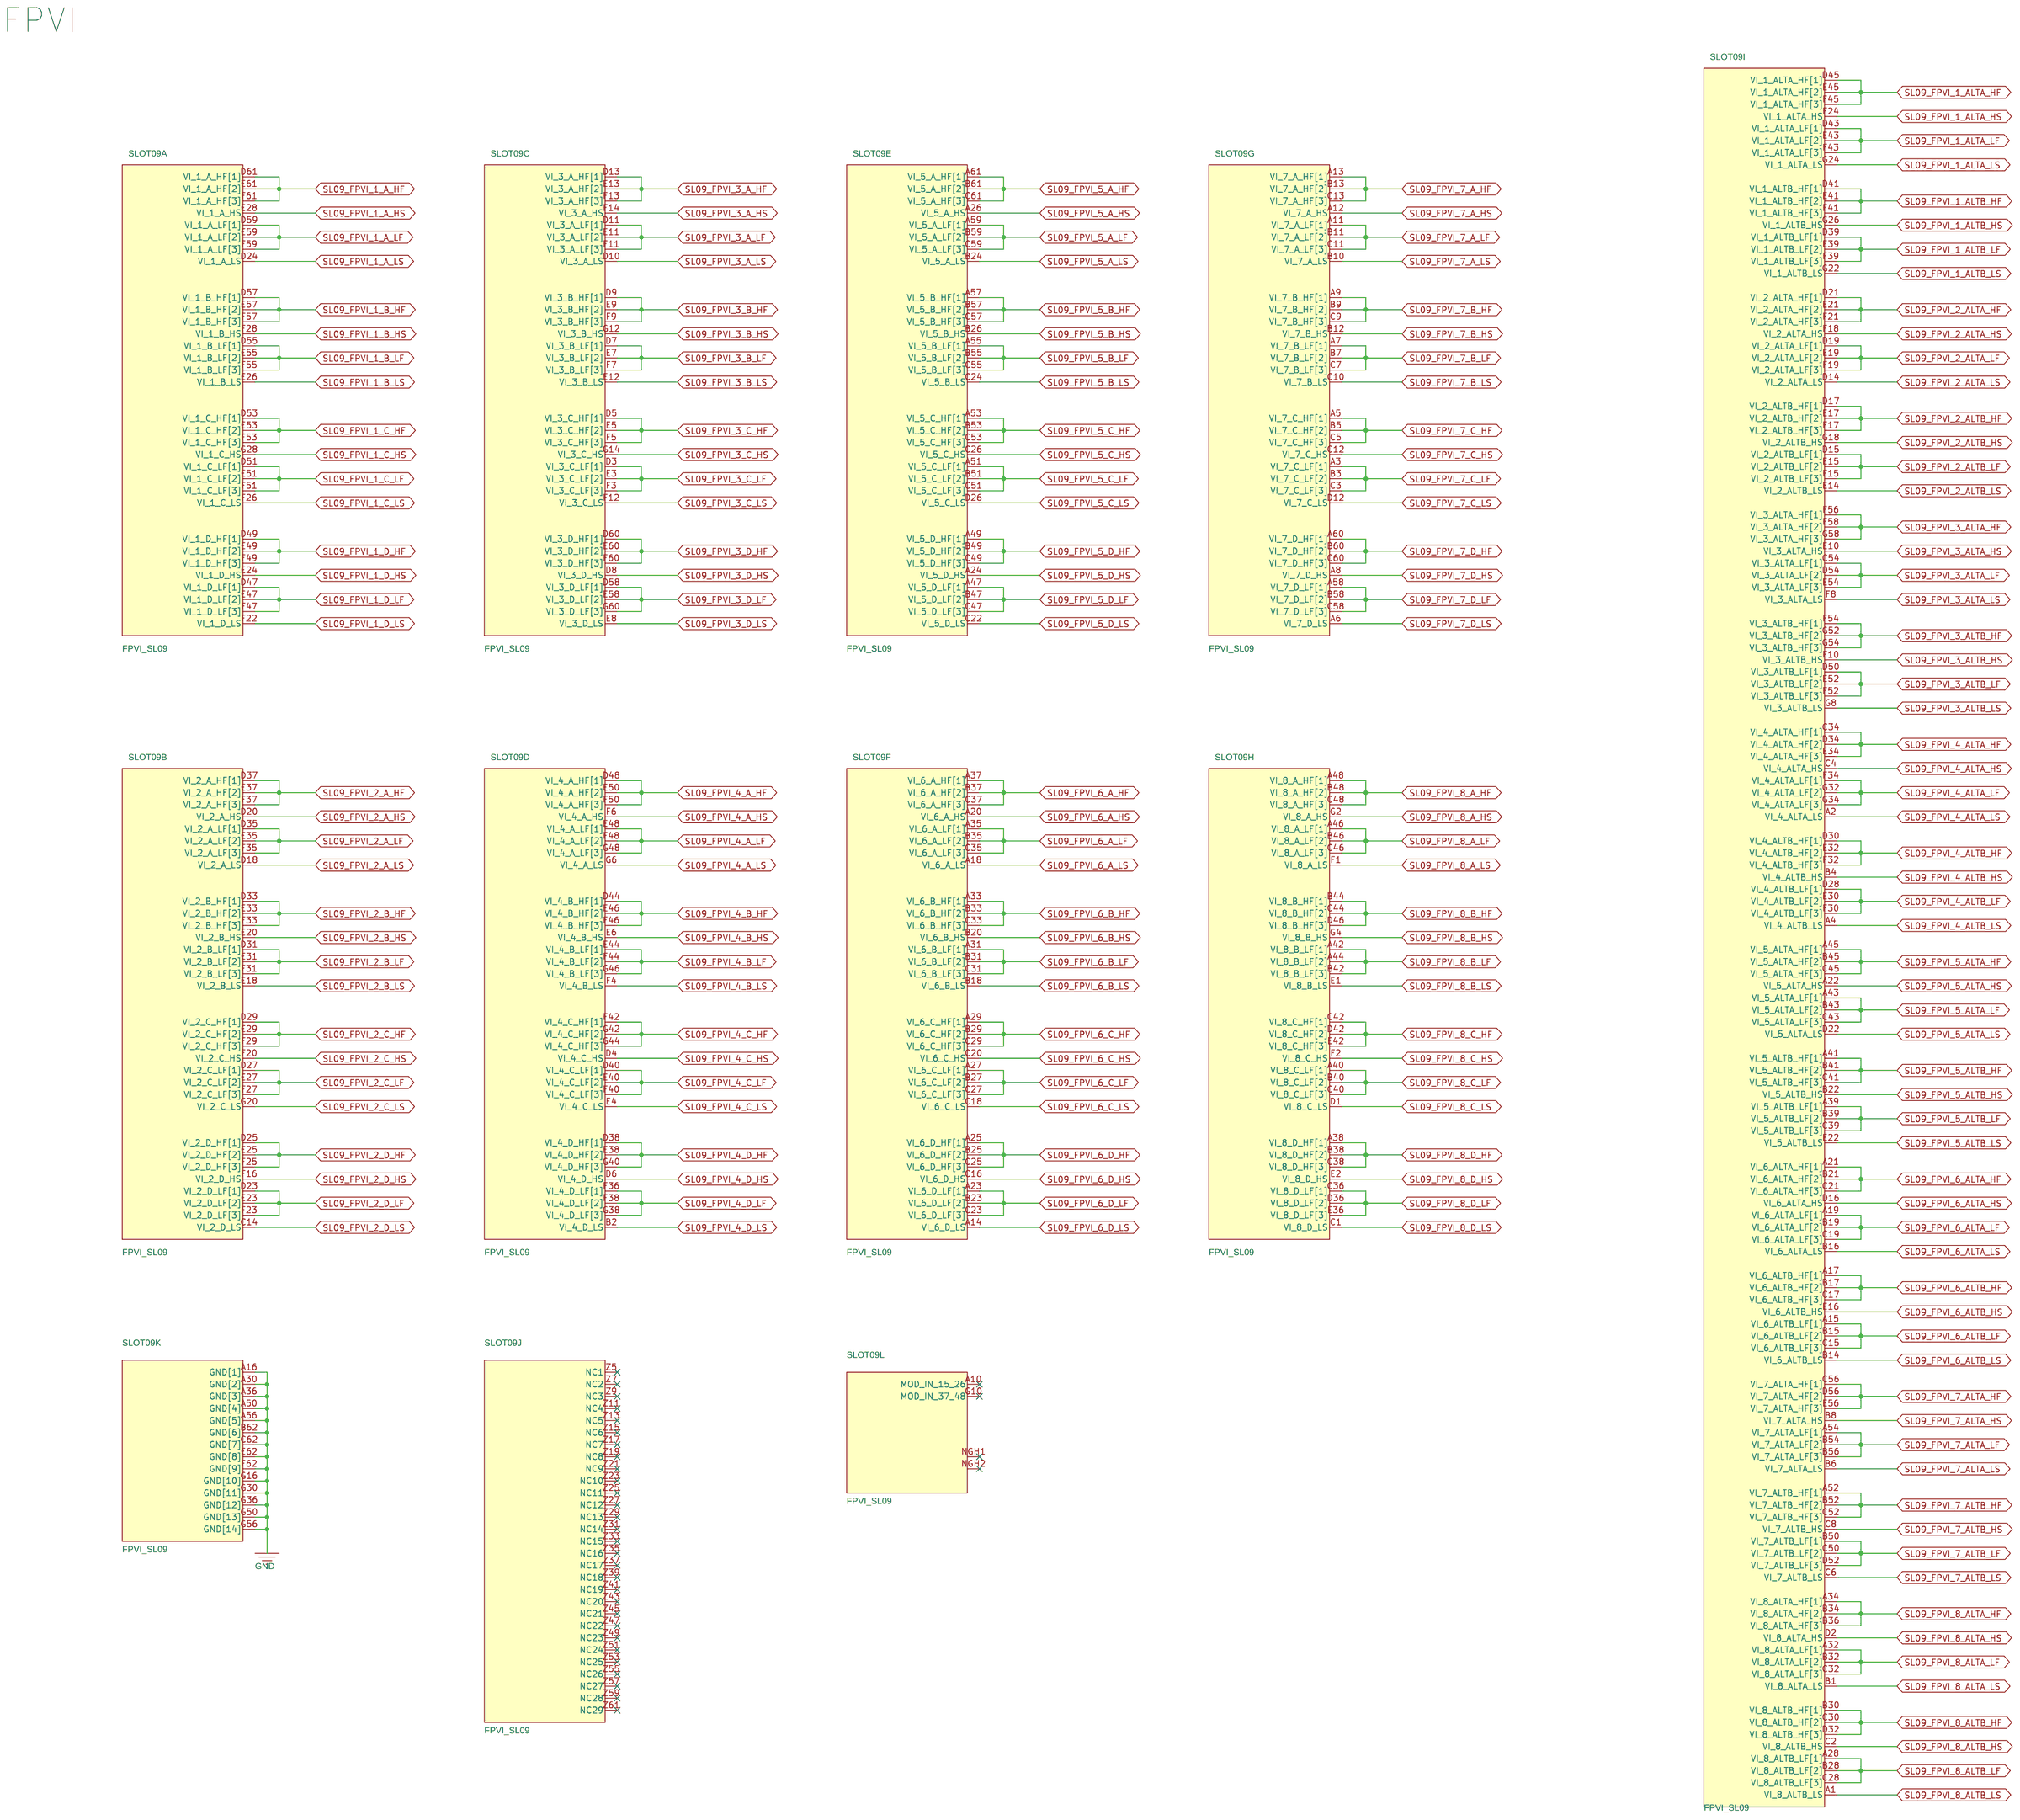
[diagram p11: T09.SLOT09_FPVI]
13 T08.SLOT08_EMPTY: size A2
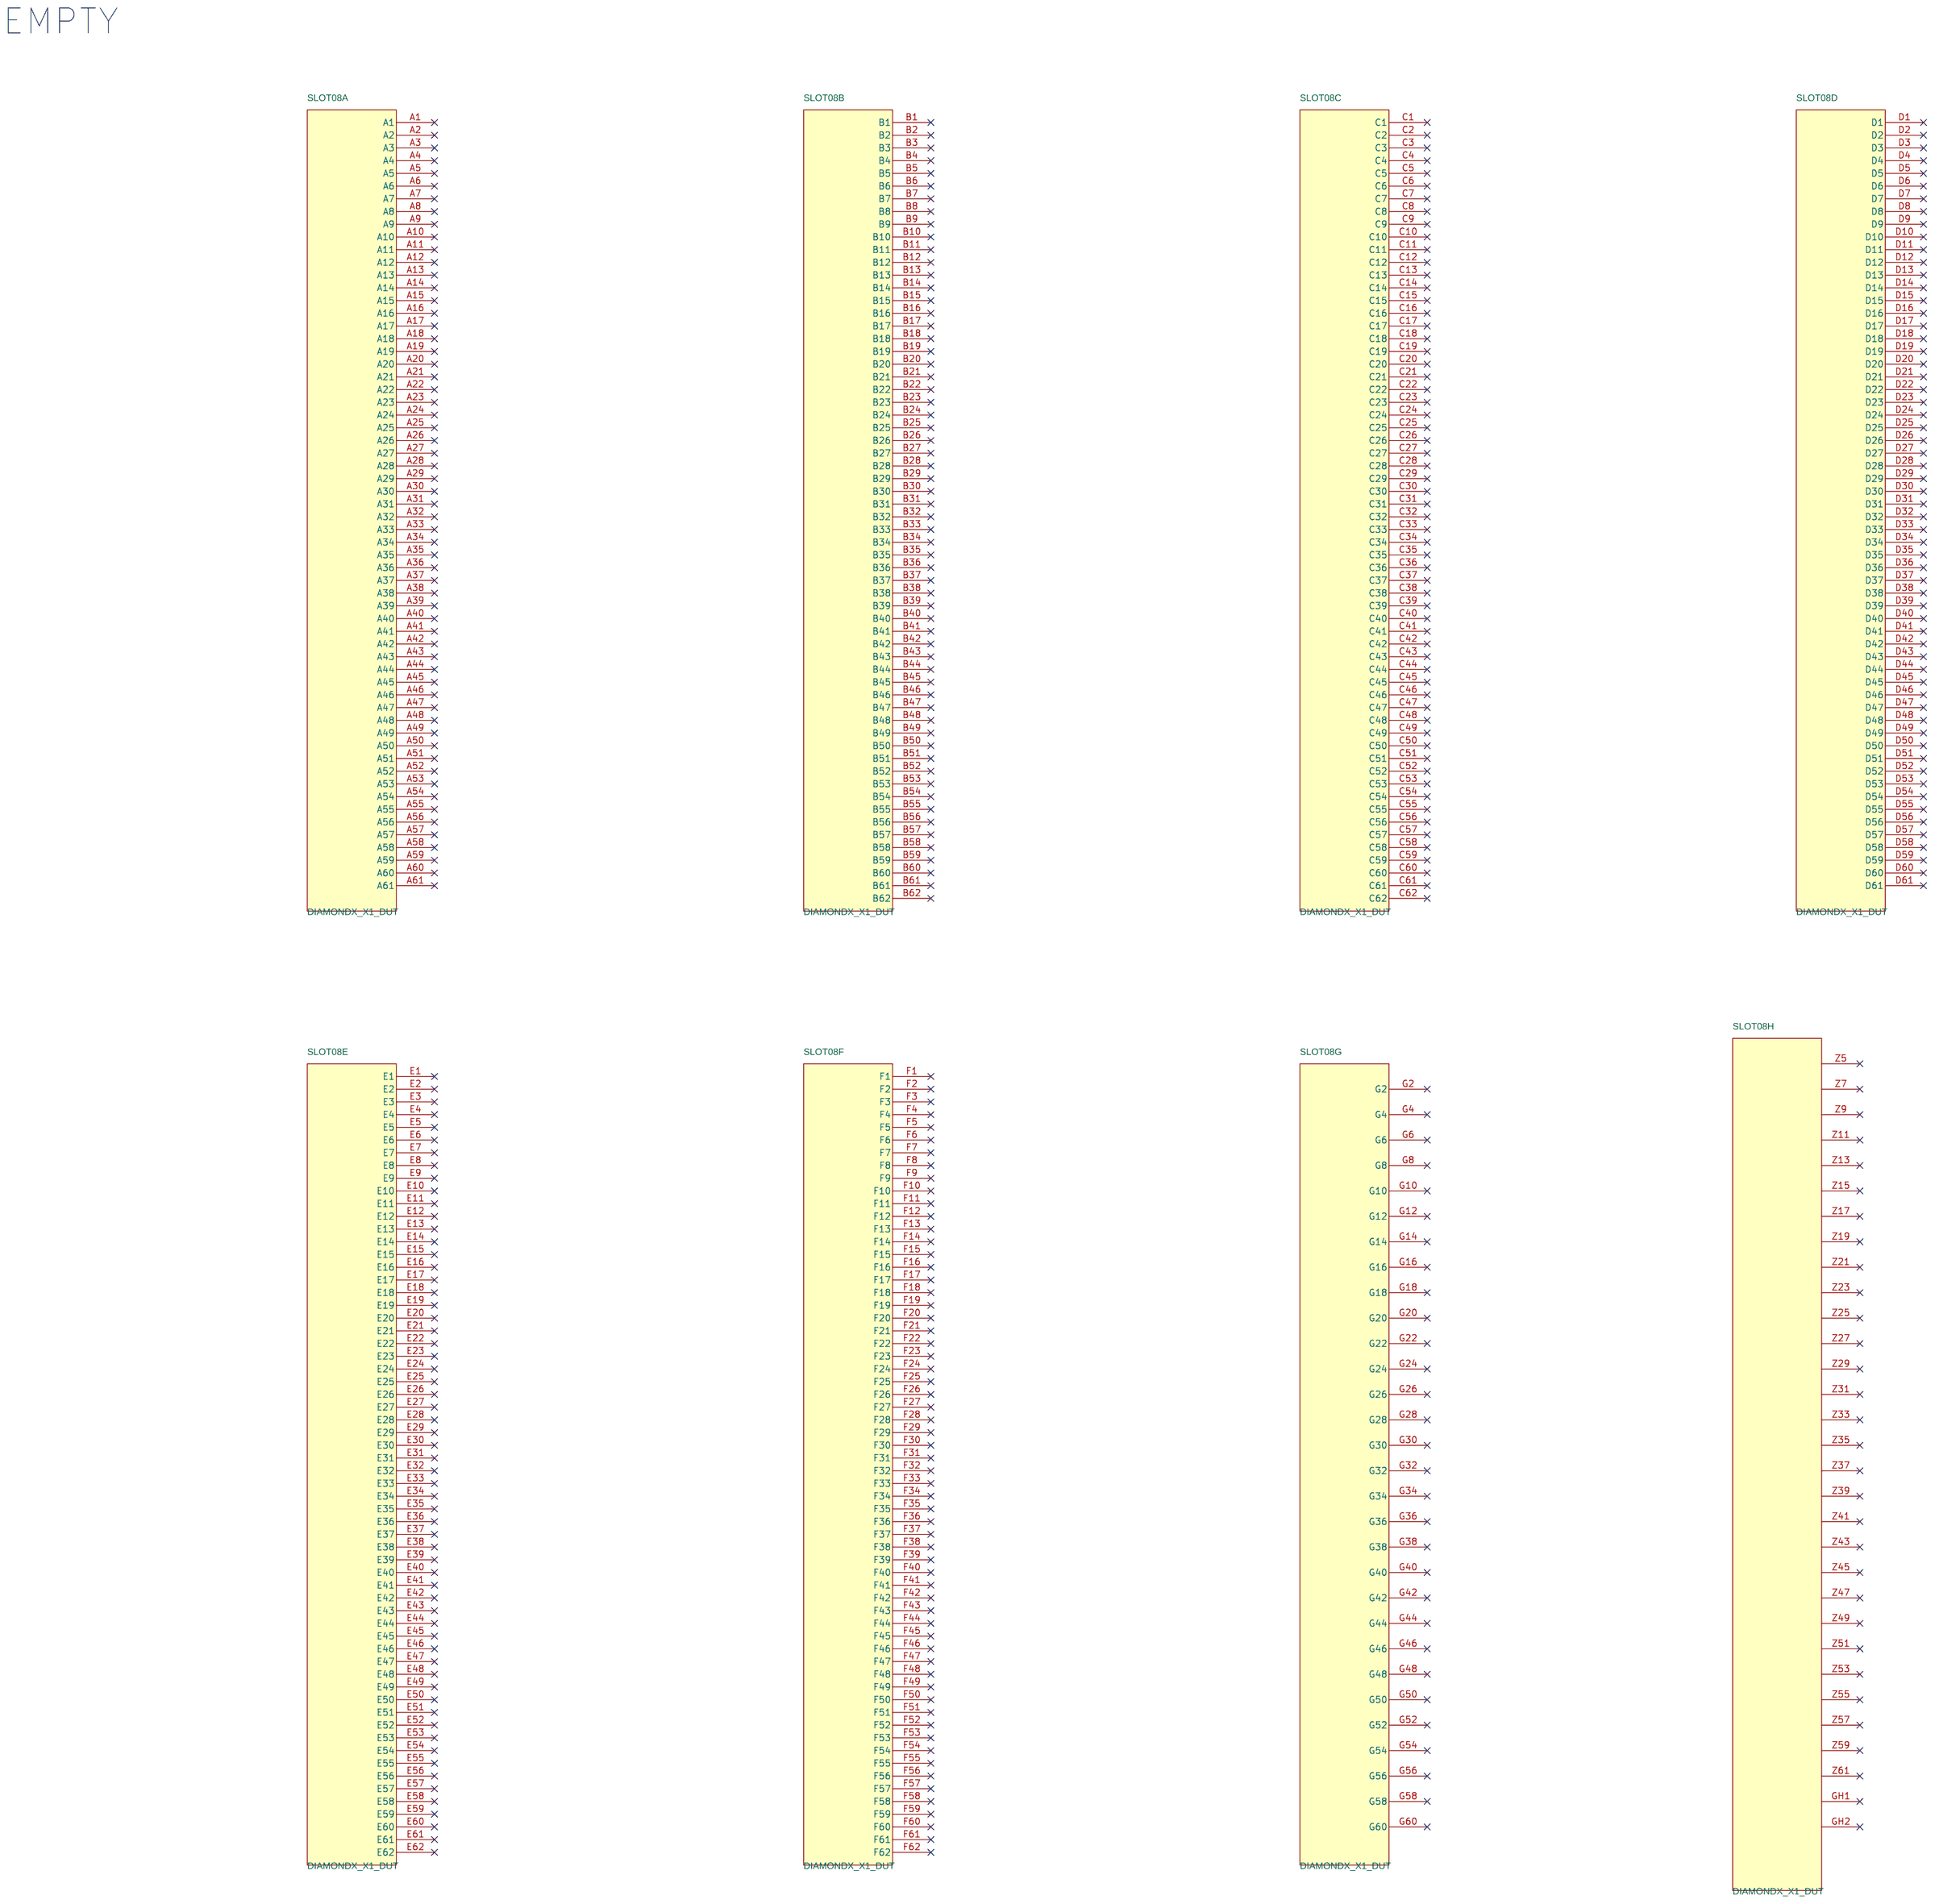
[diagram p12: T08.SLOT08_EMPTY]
14 T07.SLOT07_EMPTY: size A2
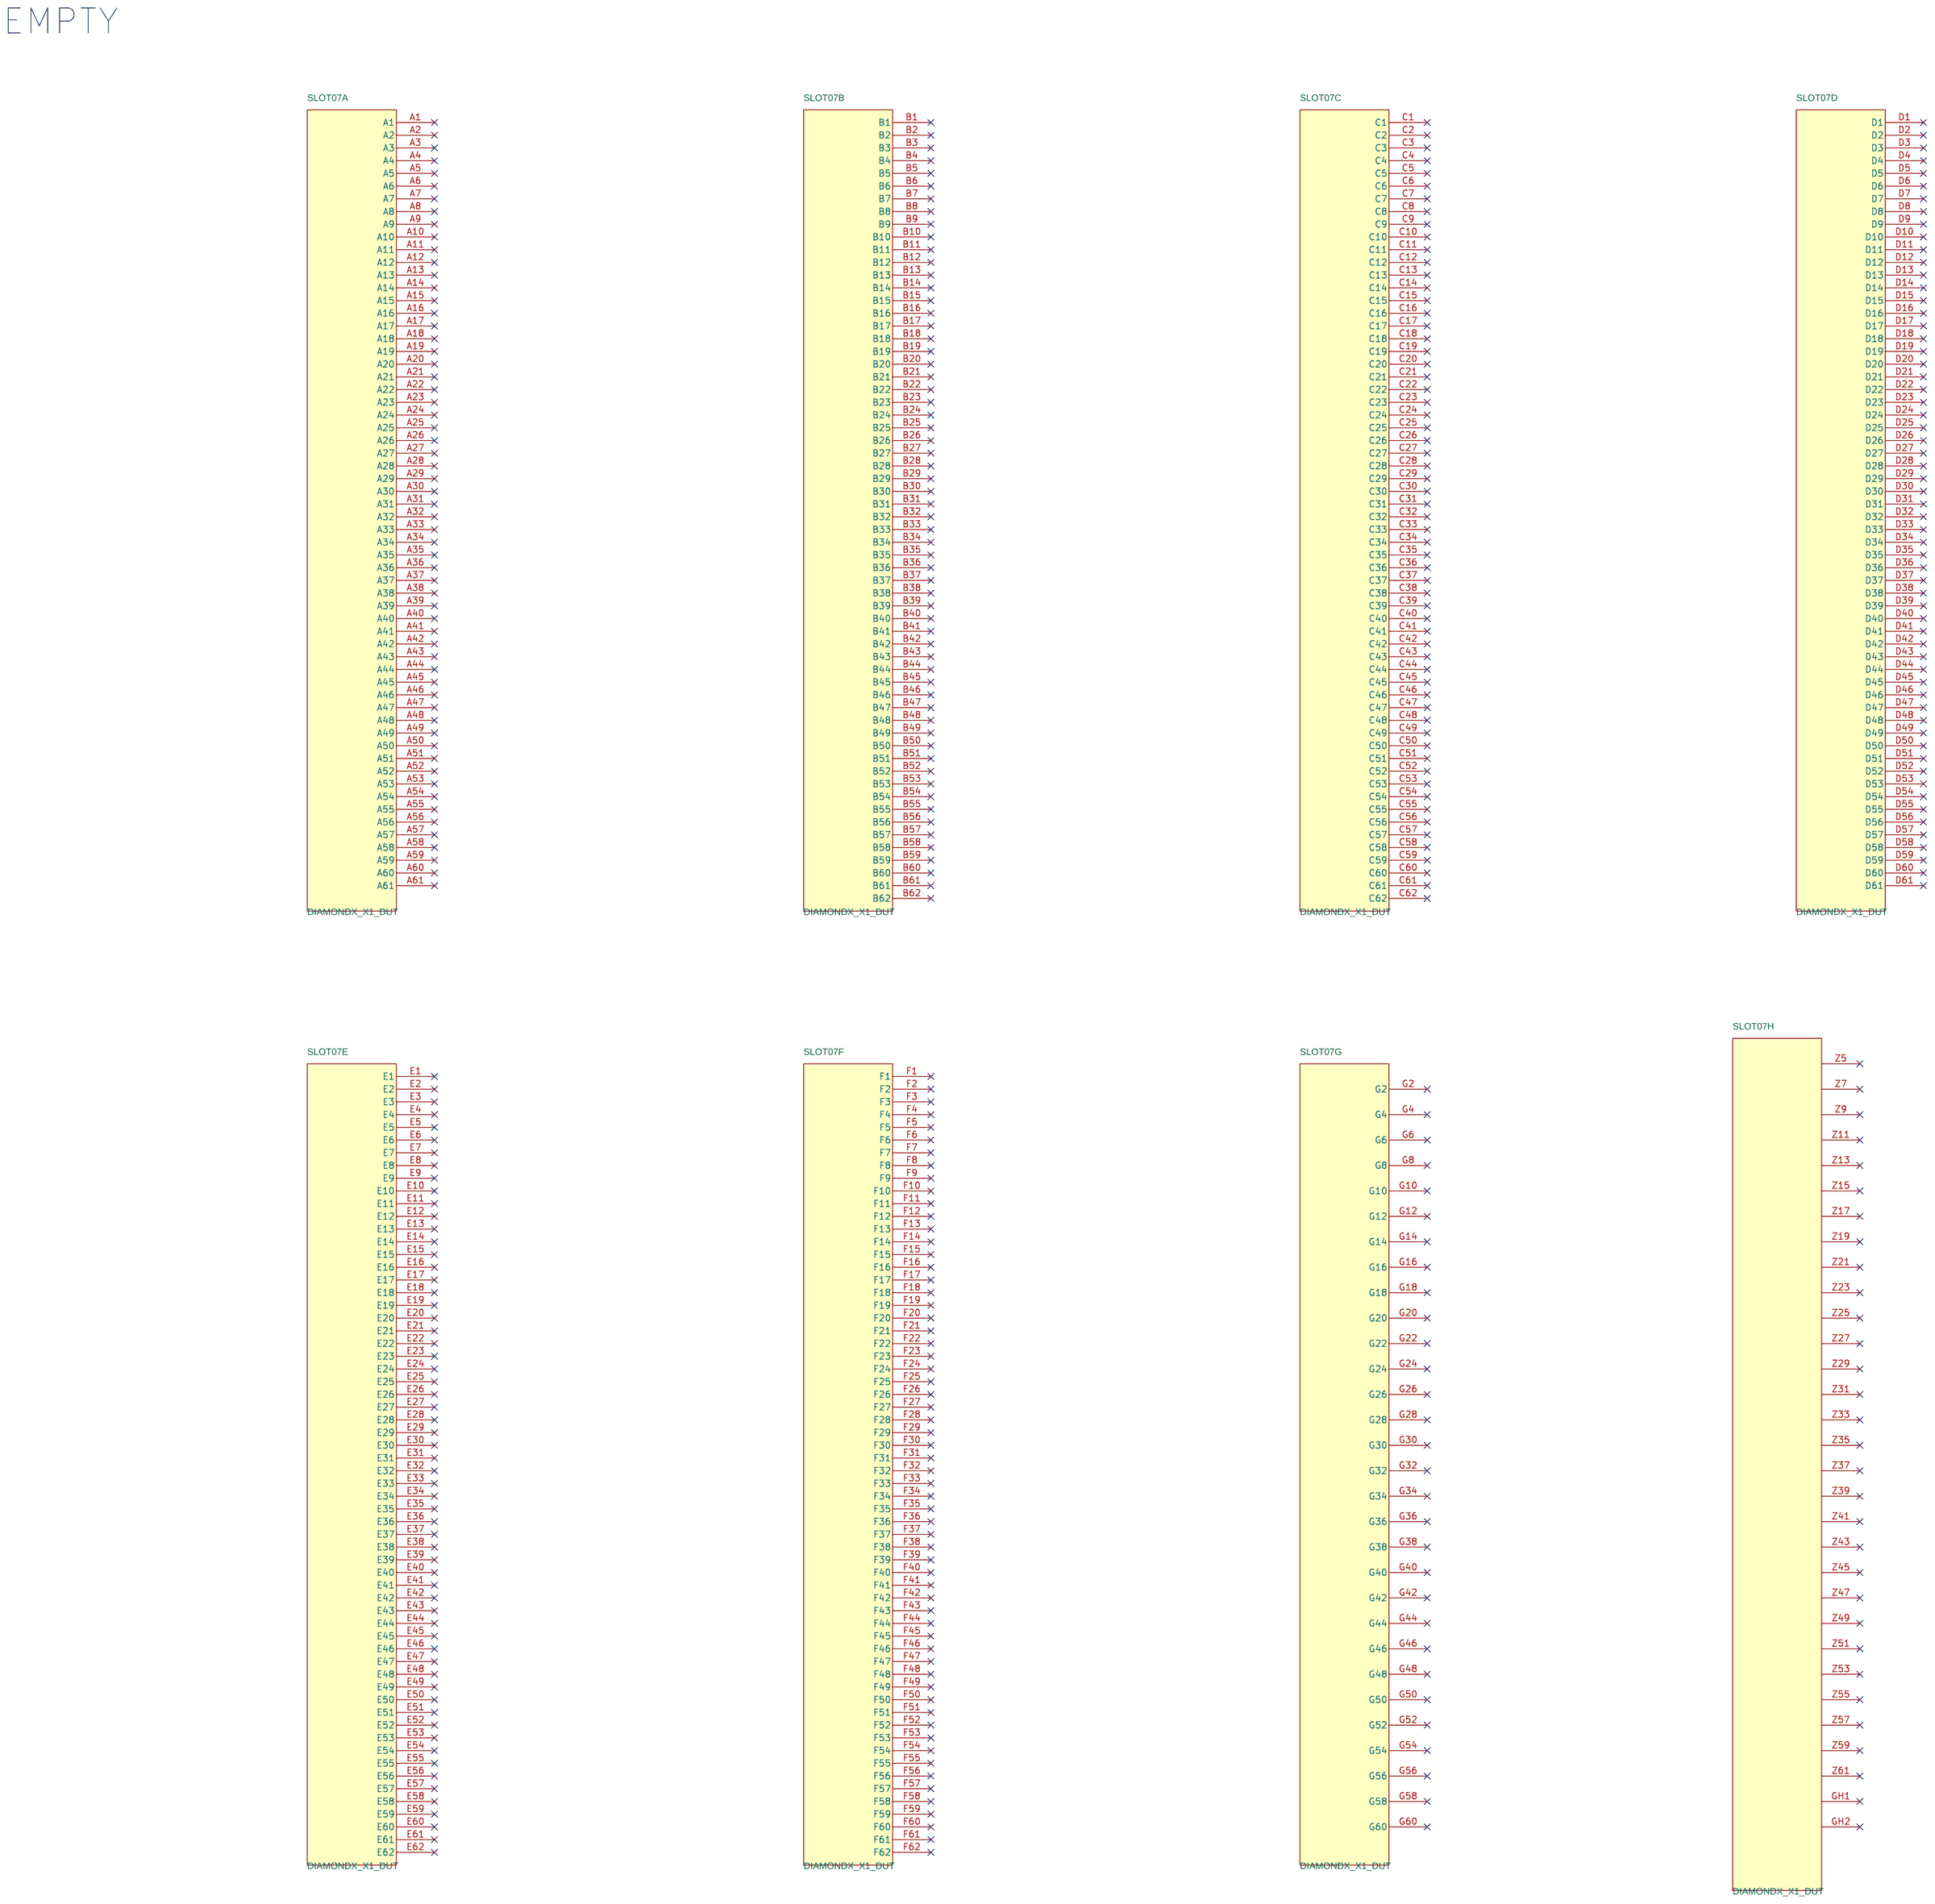
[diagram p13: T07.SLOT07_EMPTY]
15 T06.SLOT06_GX1x: size A2
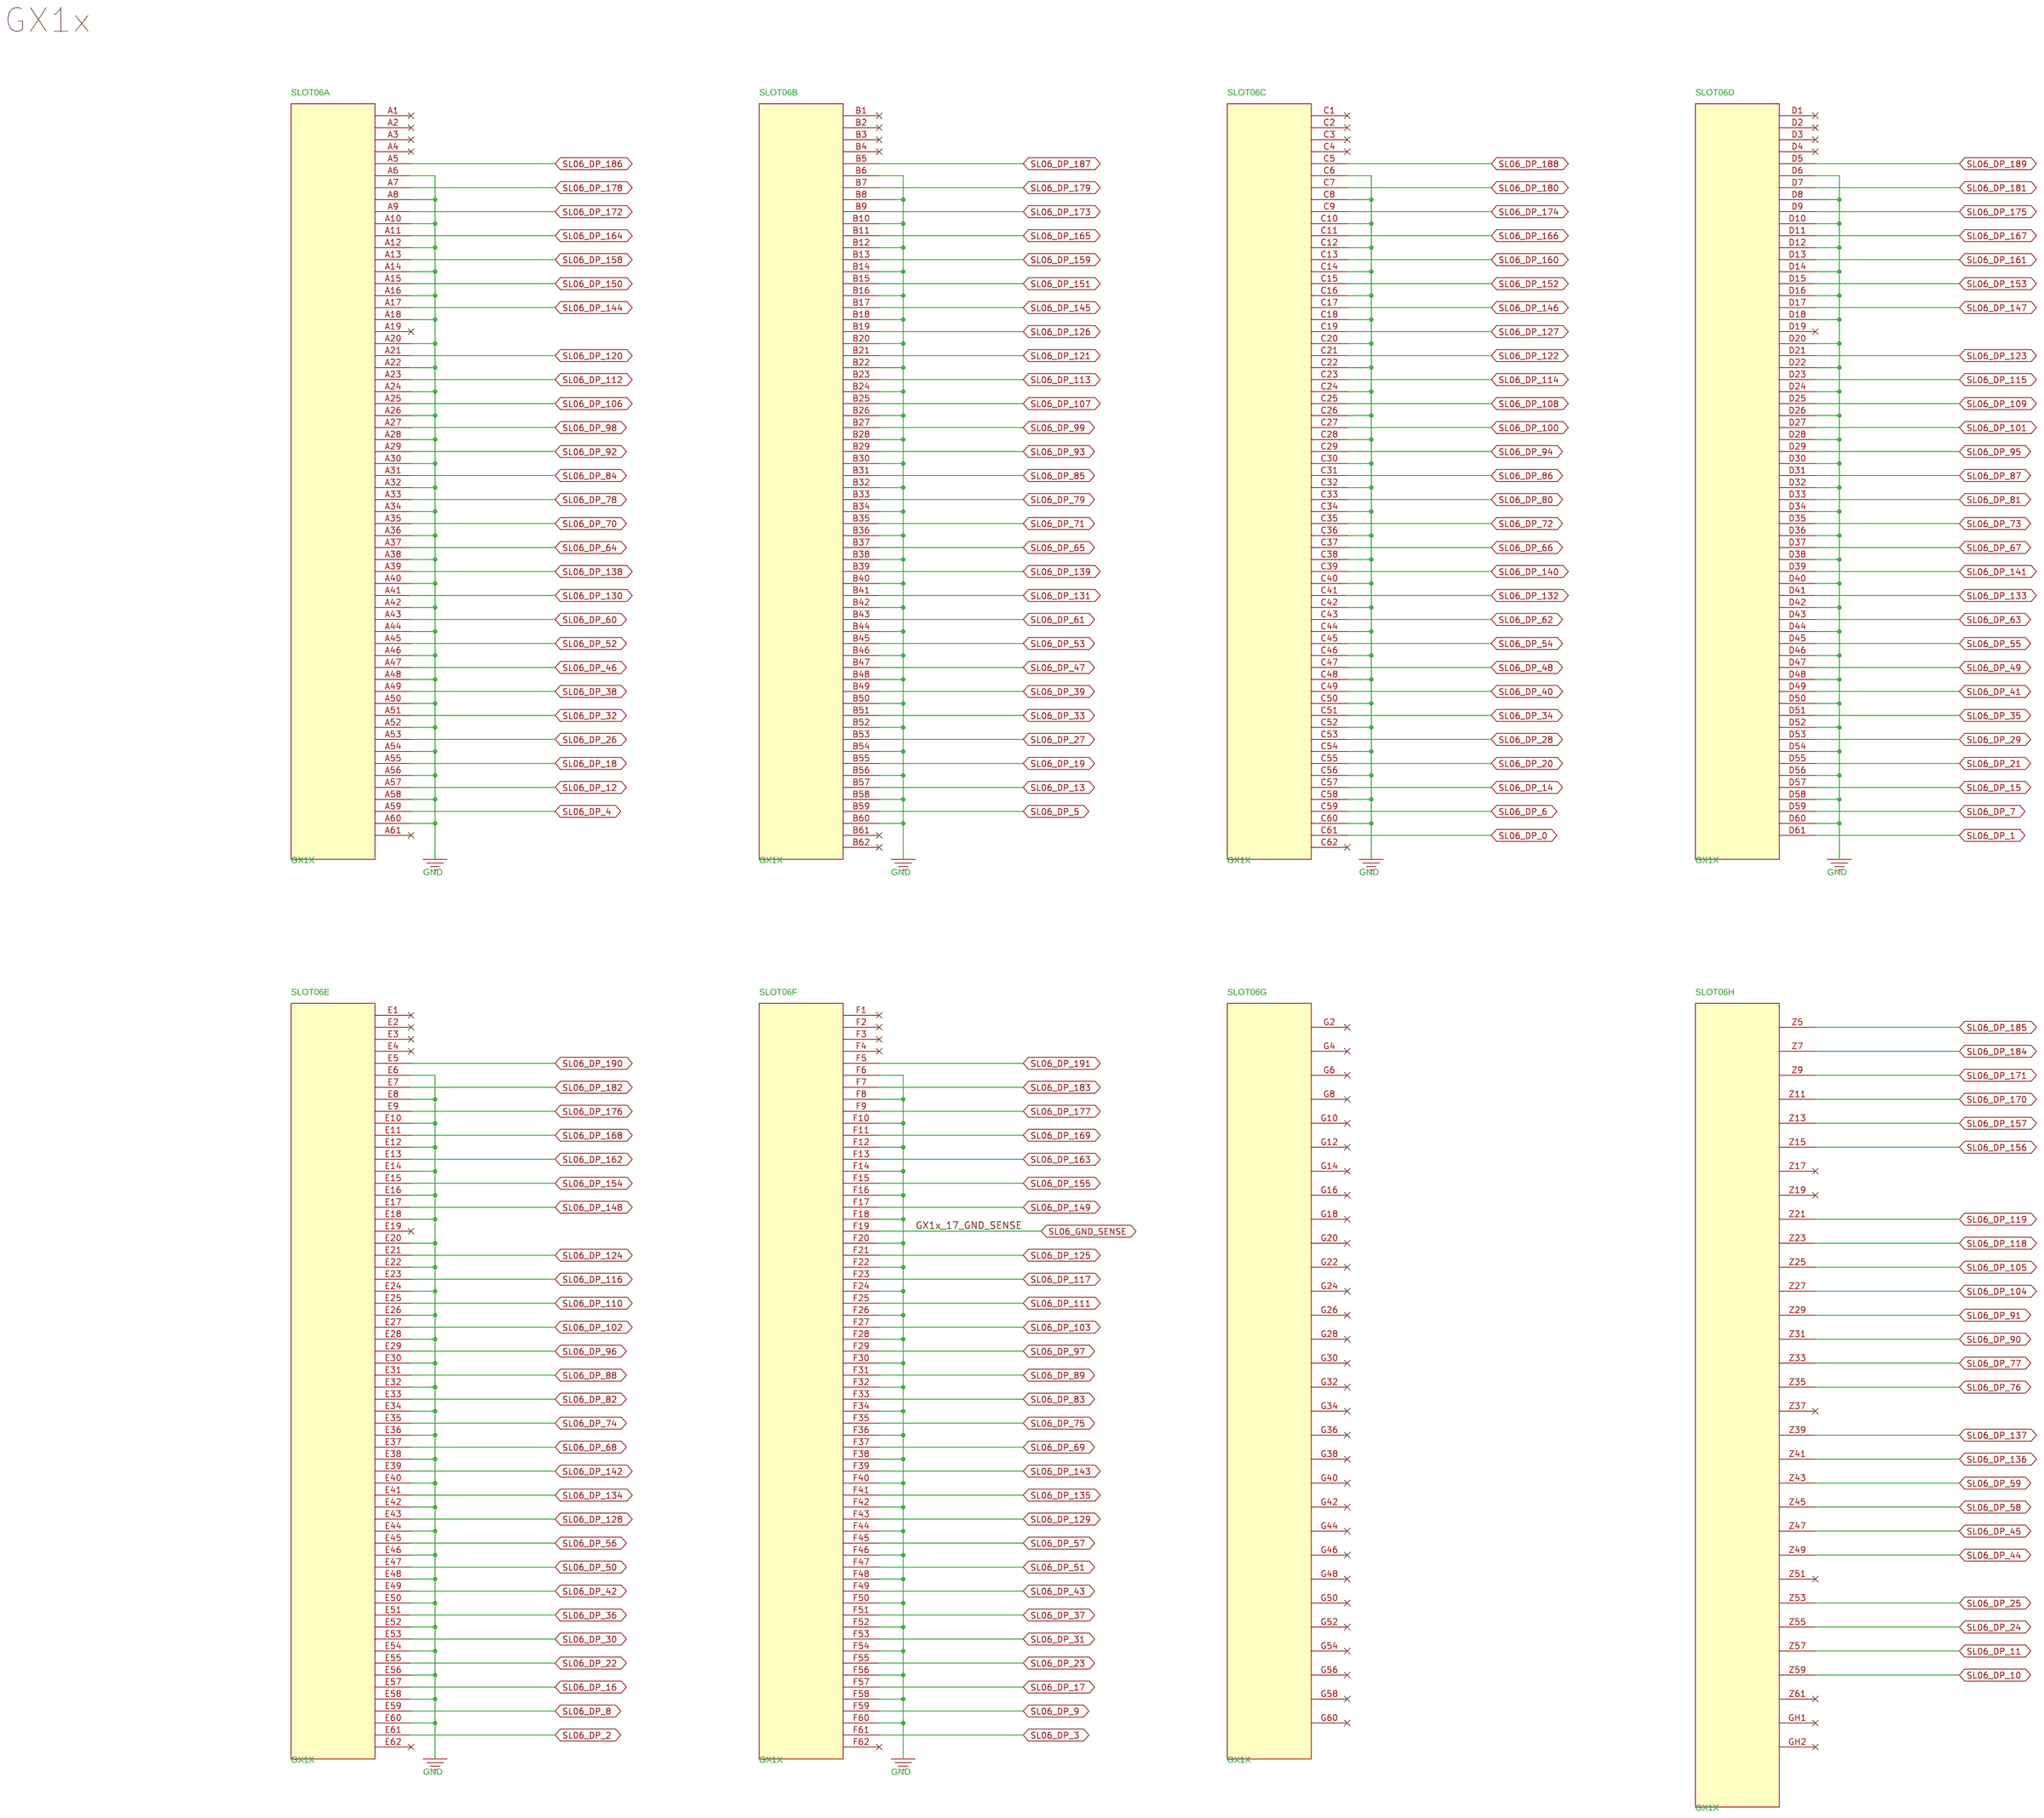
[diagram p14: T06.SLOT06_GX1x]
16 T05.SLOT05_PMVIx: size A2
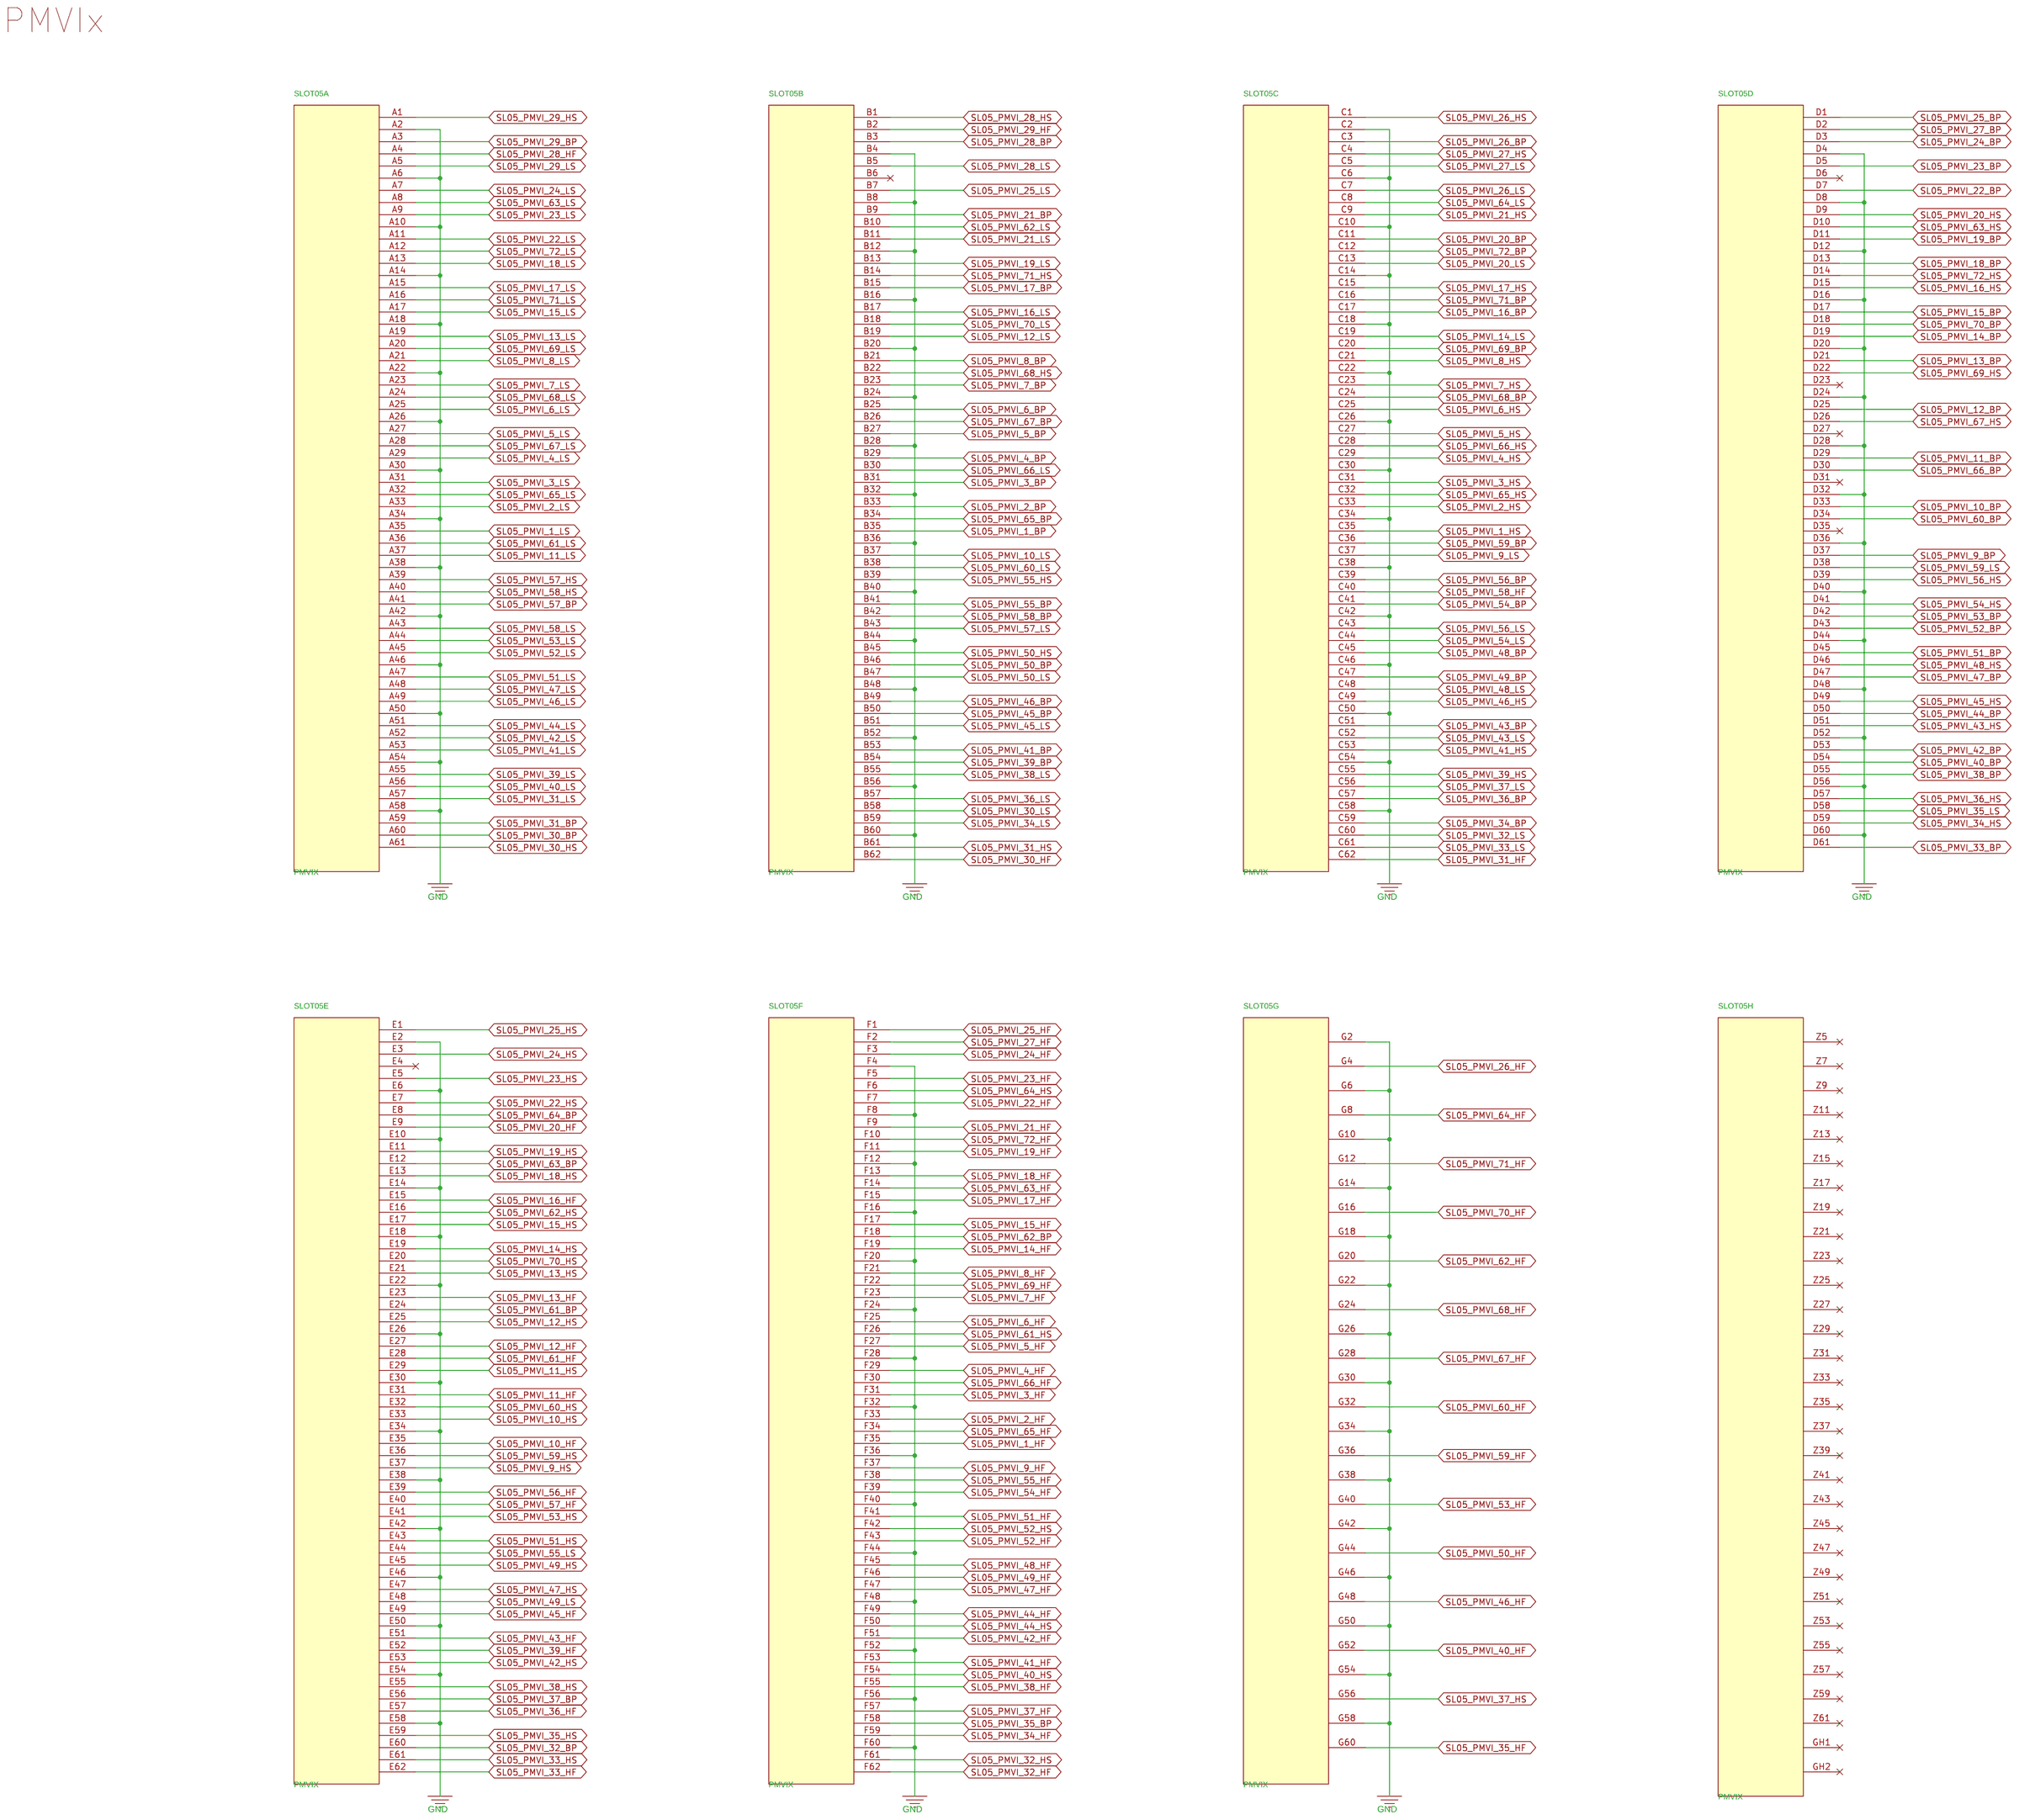
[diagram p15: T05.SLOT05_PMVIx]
17 T04.SLOT04_EMPTY: size A2
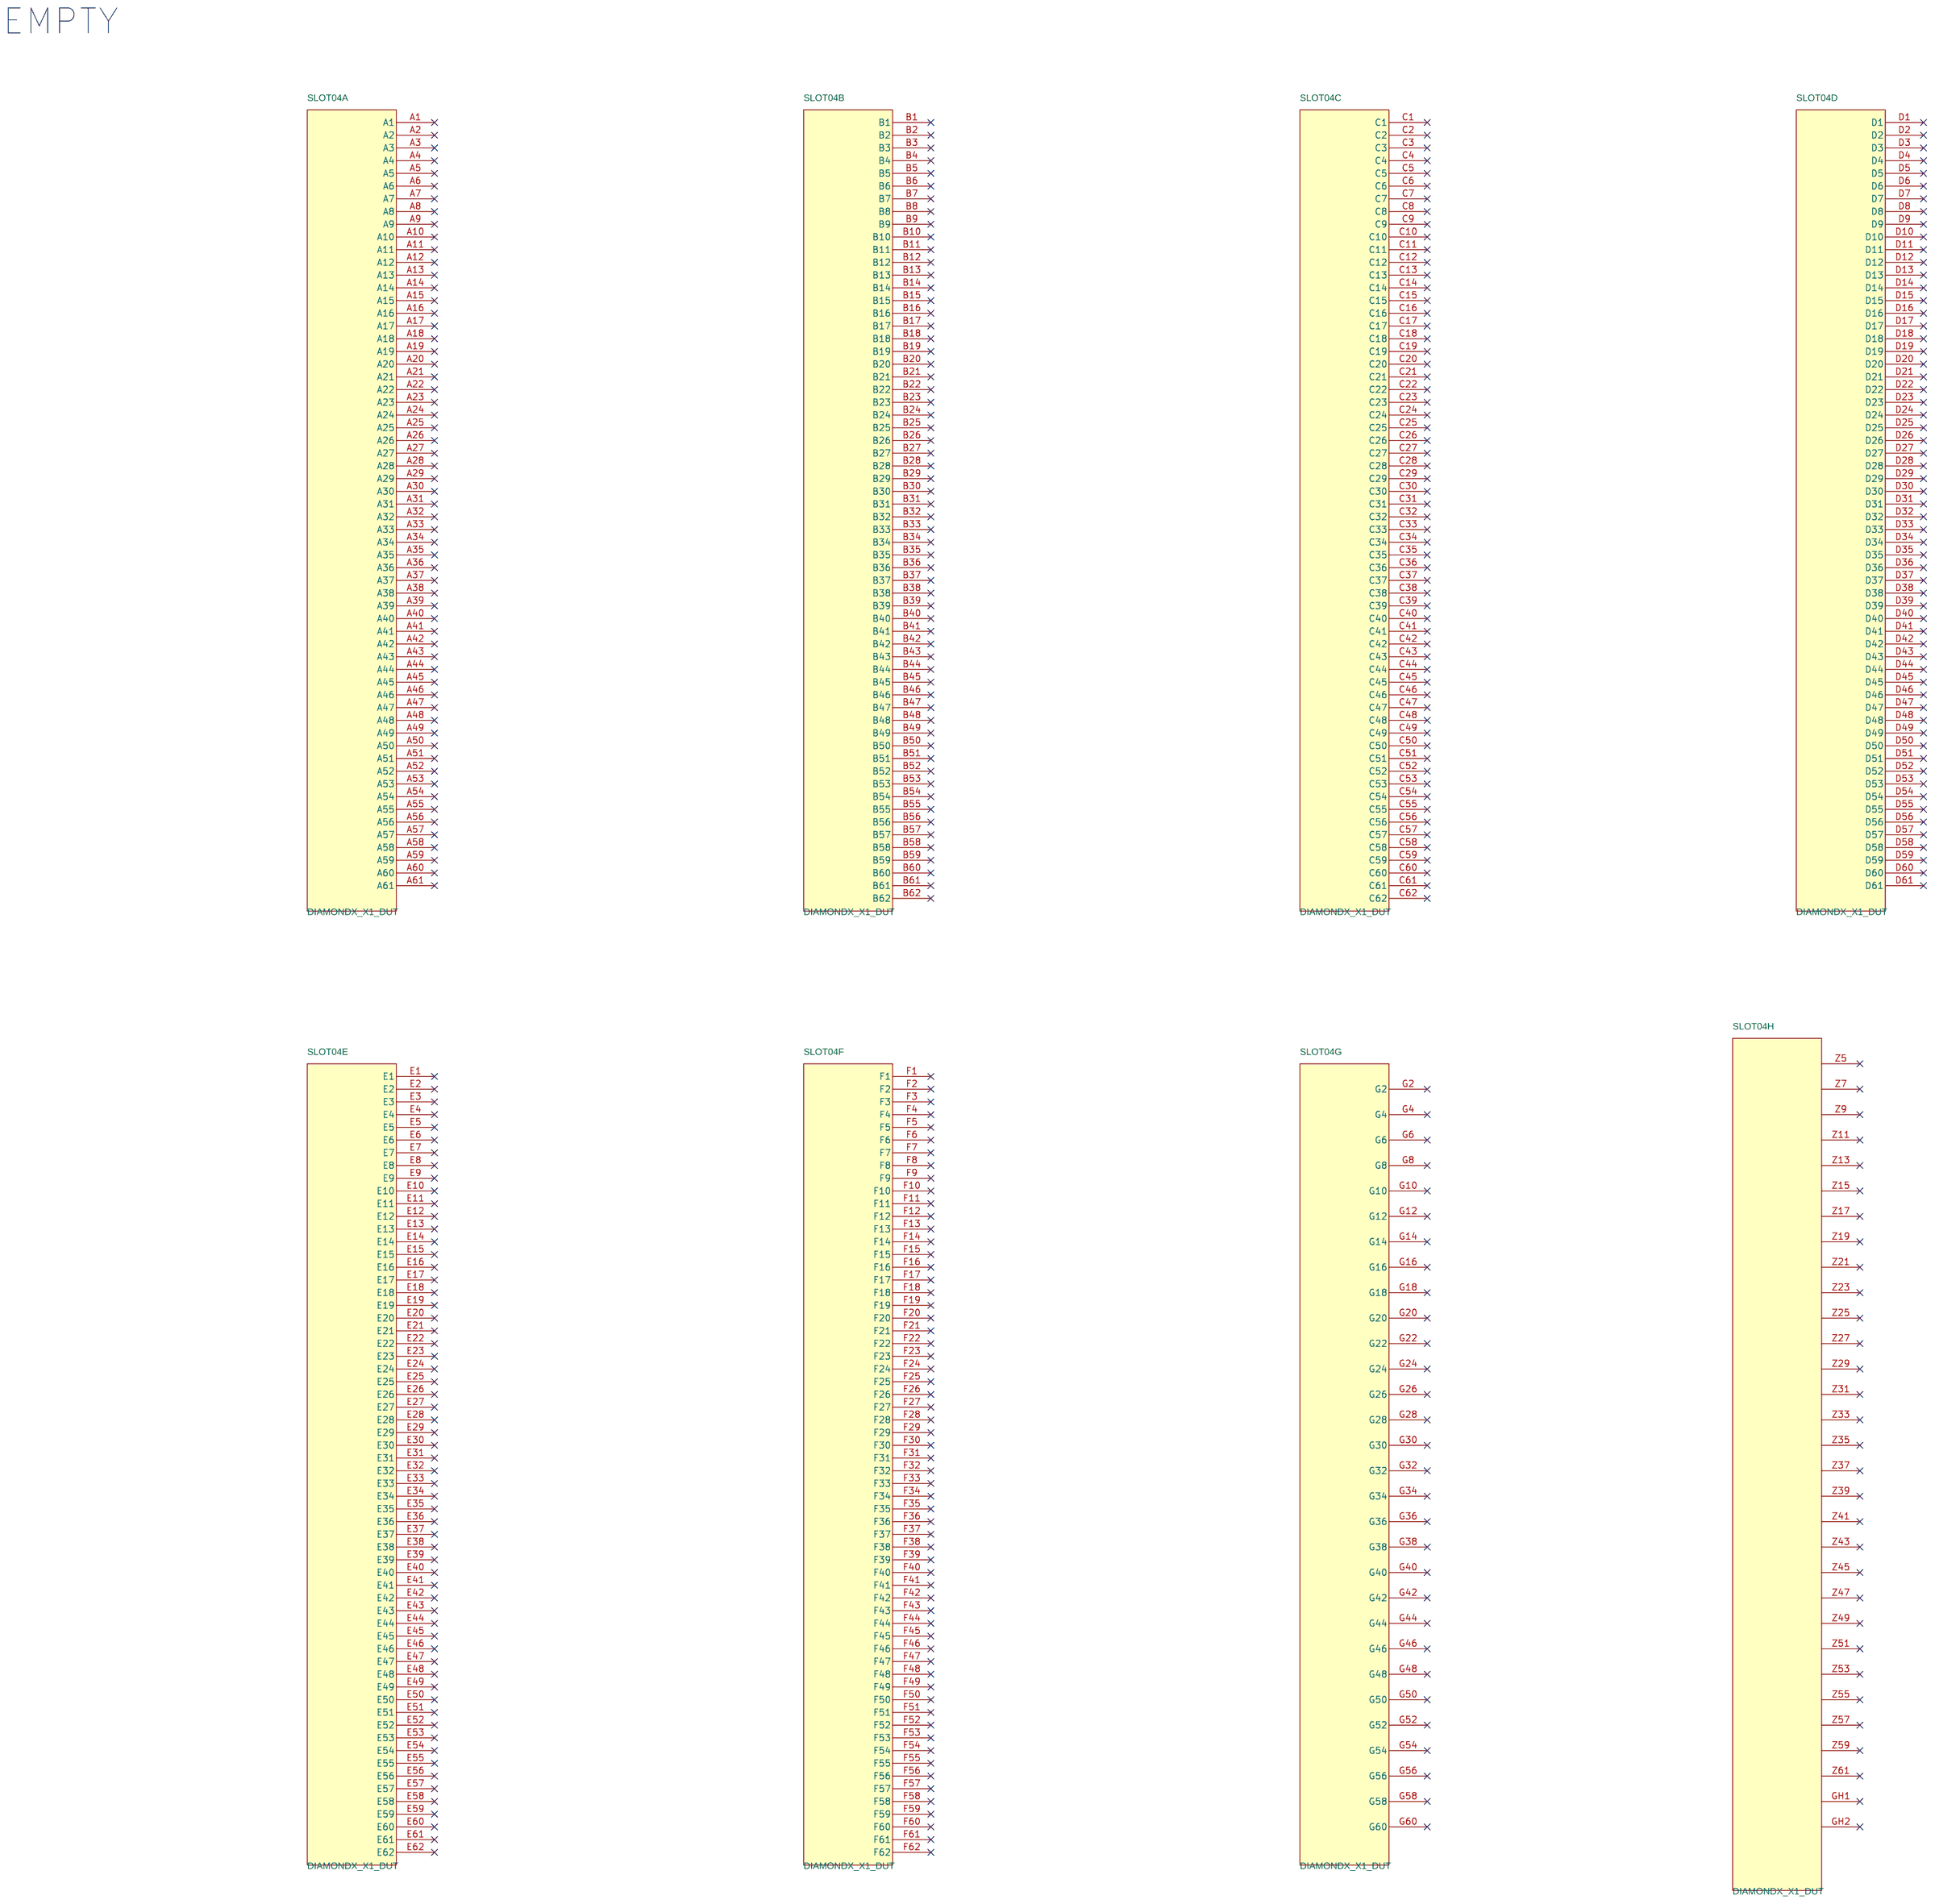
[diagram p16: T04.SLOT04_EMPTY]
18 T03.SLOT03_EMPTY: size A2

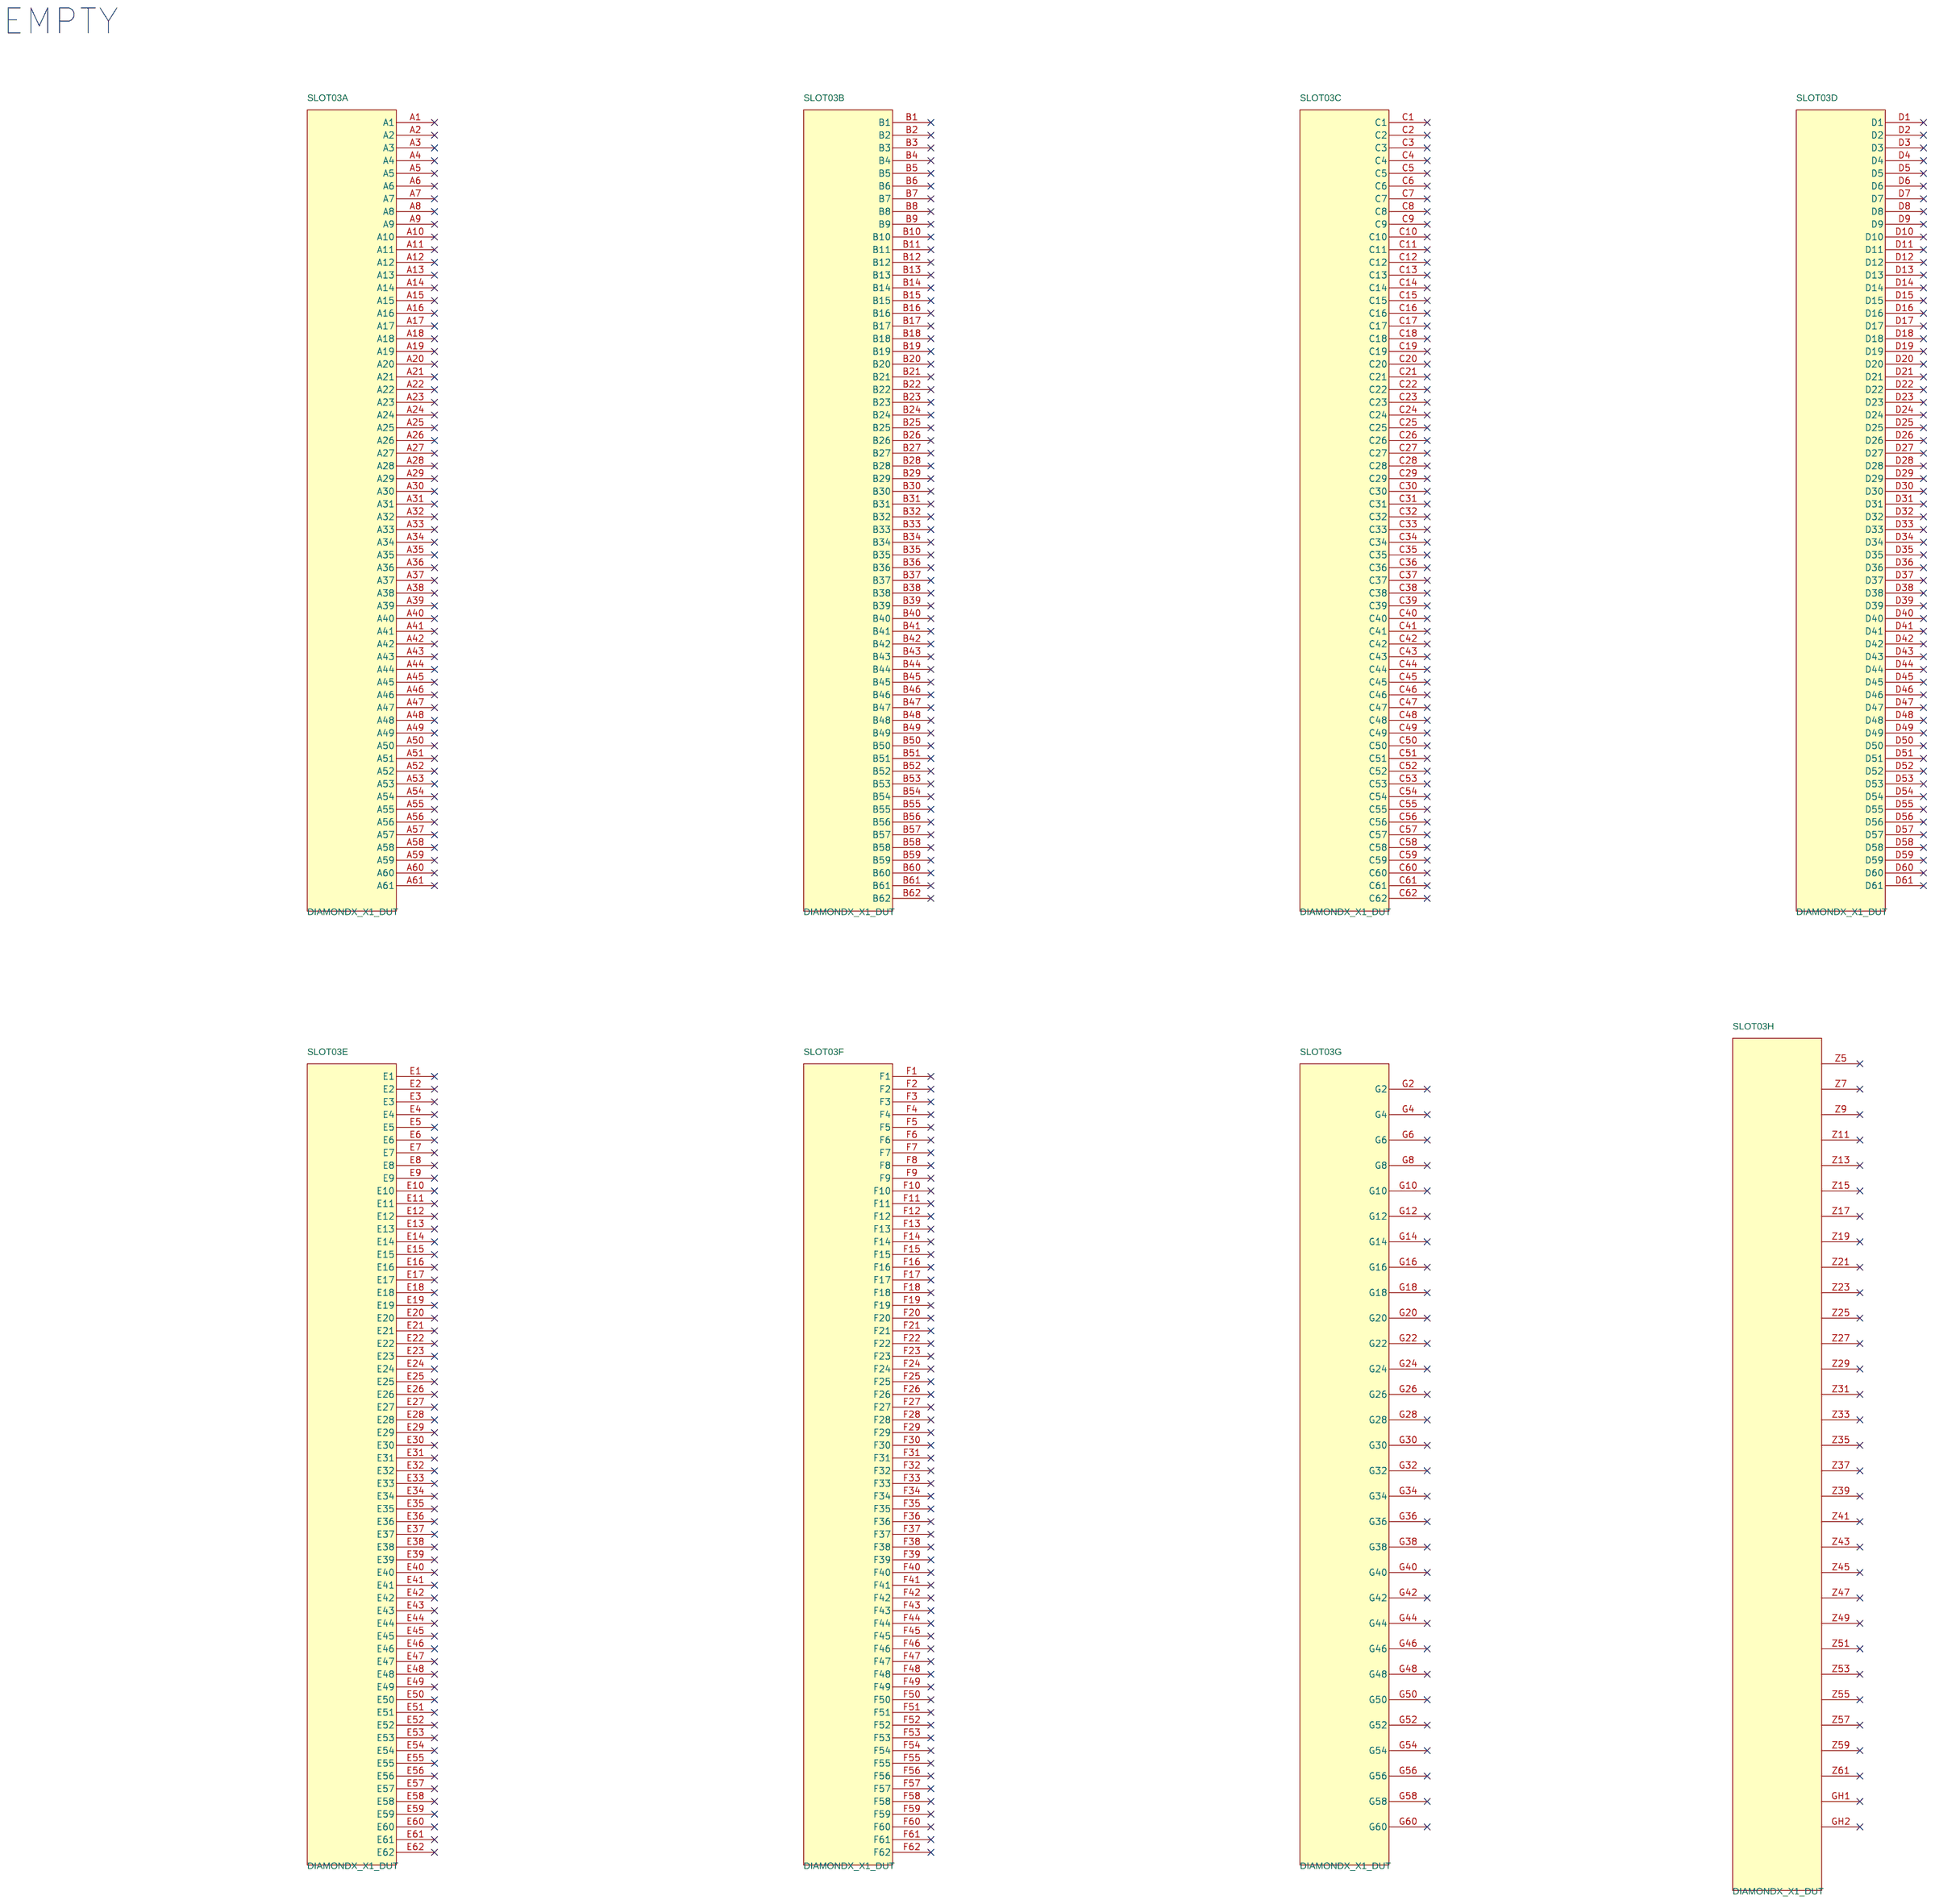
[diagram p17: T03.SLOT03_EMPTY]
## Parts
sheet T03.SLOT03_EMPTY
SLOT03  DIAMONDX_X1_DUT  [PG_LTXDX_F_X1_PG400ND_SL03_V3]  (sections A,B,C,D,E,F,G,H)
sheet T04.SLOT04_EMPTY
SLOT04  DIAMONDX_X1_DUT  [PG_LTXDX_F_X1_PG400ND_SL04_V3]  (sections A,B,C,D,E,F,G,H)
sheet T05.SLOT05_PMVIx
SLOT05  PMVIX  [PG_LTXDX_F_X1_PMVI_SL05_V3]  (sections A,B,C,D,E,F,G,H)
sheet T06.SLOT06_GX1x
SLOT06  GX1X  [PG_LTXDX_F_X1_GX1_SL06_V2]  (sections A,B,C,D,E,F,G,H)
sheet T07.SLOT07_EMPTY
SLOT07  DIAMONDX_X1_DUT  [PG_LTXDX_F_X1_PG400ND_SL07_V3]  (sections A,B,C,D,E,F,G,H)
sheet T08.SLOT08_EMPTY
SLOT08  DIAMONDX_X1_DUT  [PG_LTXDX_F_X1_PG400ND_SL08_V3]  (sections A,B,C,D,E,F,G,H)
sheet T09.SLOT09_FPVI
SLOT09  FPVI_SL09  [PG_LTXDX_F_X1_FPVI_SL09_V3]  (sections A,B,C,D,E,F,G,H,I,J,K,L)

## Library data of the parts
SLOT03 SLOT04 SLOT07 SLOT08 = DIAMONDX_X1_DUT_1
SLOT05 = DIAMONDX_SLOT8_PMVIX
SLOT06 = DIAMONDX_SLOT17_GX1X
SLOT09 = FPVI_SL09

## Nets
GND: SLOT05.A2 SLOT05.A6 SLOT05.A10 SLOT05.A14 SLOT05.A18 SLOT05.A22 SLOT05.A26 SLOT05.A30 SLOT05.A34 SLOT05.A38 SLOT05.A42 SLOT05.A46 SLOT05.A50 SLOT05.A54 SLOT05.A58 SLOT05.B4 SLOT05.B8 SLOT05.B12 SLOT05.B16 SLOT05.B20 SLOT05.B24 SLOT05.B28 SLOT05.B32 SLOT05.B36 SLOT05.B40 SLOT05.B44 SLOT05.B48 SLOT05.B52 SLOT05.B56 SLOT05.B60 SLOT05.C2 SLOT05.C6 SLOT05.C10 SLOT05.C14 SLOT05.C18 SLOT05.C22 SLOT05.C26 SLOT05.C30 SLOT05.C34 SLOT05.C38 SLOT05.C42 SLOT05.C46 SLOT05.C50 SLOT05.C54 SLOT05.C58 SLOT05.D4 SLOT05.D8 SLOT05.D12 SLOT05.D16 SLOT05.D20 SLOT05.D24 SLOT05.D28 SLOT05.D32 SLOT05.D36 SLOT05.D40 SLOT05.D44 SLOT05.D48 SLOT05.D52 SLOT05.D56 SLOT05.D60 SLOT05.E2 SLOT05.E6 SLOT05.E10 SLOT05.E14 SLOT05.E18 SLOT05.E22 SLOT05.E26 SLOT05.E30 SLOT05.E34 SLOT05.E38 SLOT05.E42 SLOT05.E46 SLOT05.E50 SLOT05.E54 SLOT05.E58 SLOT05.F4 SLOT05.F8 SLOT05.F12 SLOT05.F16 SLOT05.F20 SLOT05.F24 SLOT05.F28 SLOT05.F32 SLOT05.F36 SLOT05.F40 SLOT05.F44 SLOT05.F48 SLOT05.F52 SLOT05.F56 SLOT05.F60 SLOT05.G2 SLOT05.G6 SLOT05.G10 SLOT05.G14 SLOT05.G18 SLOT05.G22 SLOT05.G26 SLOT05.G30 SLOT05.G34 SLOT05.G38 SLOT05.G42 SLOT05.G46 SLOT05.G50 SLOT05.G54 SLOT05.G58 SLOT06.A6 SLOT06.A8 SLOT06.A10 SLOT06.A12 SLOT06.A14 SLOT06.A16 SLOT06.A18 SLOT06.A20 SLOT06.A22 SLOT06.A24 SLOT06.A26 SLOT06.A28 SLOT06.A30 SLOT06.A32 SLOT06.A34 SLOT06.A36 SLOT06.A38 SLOT06.A40 SLOT06.A42 SLOT06.A44 SLOT06.A46 SLOT06.A48 SLOT06.A50 SLOT06.A52 SLOT06.A54 SLOT06.A56 SLOT06.A58 SLOT06.A60 SLOT06.B6 SLOT06.B8 SLOT06.B10 SLOT06.B12 SLOT06.B14 SLOT06.B16 SLOT06.B18 SLOT06.B20 SLOT06.B22 SLOT06.B24 SLOT06.B26 SLOT06.B28 SLOT06.B30 SLOT06.B32 SLOT06.B34 SLOT06.B36 SLOT06.B38 SLOT06.B40 SLOT06.B42 SLOT06.B44 SLOT06.B46 SLOT06.B48 SLOT06.B50 SLOT06.B52 SLOT06.B54 SLOT06.B56 SLOT06.B58 SLOT06.B60 SLOT06.C6 SLOT06.C8 SLOT06.C10 SLOT06.C12 SLOT06.C14 SLOT06.C16 SLOT06.C18 SLOT06.C20 SLOT06.C22 SLOT06.C24 SLOT06.C26 SLOT06.C28 SLOT06.C30 SLOT06.C32 SLOT06.C34 SLOT06.C36 SLOT06.C38 SLOT06.C40 SLOT06.C42 SLOT06.C44 SLOT06.C46 SLOT06.C48 SLOT06.C50 SLOT06.C52 SLOT06.C54 SLOT06.C56 SLOT06.C58 SLOT06.C60 SLOT06.D6 SLOT06.D8 SLOT06.D10 SLOT06.D12 SLOT06.D14 SLOT06.D16 SLOT06.D18 SLOT06.D20 SLOT06.D22 SLOT06.D24 SLOT06.D26 SLOT06.D28 SLOT06.D30 SLOT06.D32 SLOT06.D34 SLOT06.D36 SLOT06.D38 SLOT06.D40 SLOT06.D42 SLOT06.D44 SLOT06.D46 SLOT06.D48 SLOT06.D50 SLOT06.D52 SLOT06.D54 SLOT06.D56 SLOT06.D58 SLOT06.D60 SLOT06.E6 SLOT06.E8 SLOT06.E10 SLOT06.E12 SLOT06.E14 SLOT06.E16 SLOT06.E18 SLOT06.E20 SLOT06.E22 SLOT06.E24 SLOT06.E26 SLOT06.E28 SLOT06.E30 SLOT06.E32 SLOT06.E34 SLOT06.E36 SLOT06.E38 SLOT06.E40 SLOT06.E42 SLOT06.E44 SLOT06.E46 SLOT06.E48 SLOT06.E50 SLOT06.E52 SLOT06.E54 SLOT06.E56 SLOT06.E58 SLOT06.E60 SLOT06.F6 SLOT06.F8 SLOT06.F10 SLOT06.F12 SLOT06.F14 SLOT06.F16 SLOT06.F18 SLOT06.F20 SLOT06.F22 SLOT06.F24 SLOT06.F26 SLOT06.F28 SLOT06.F30 SLOT06.F32 SLOT06.F34 SLOT06.F36 SLOT06.F38 SLOT06.F40 SLOT06.F42 SLOT06.F44 SLOT06.F46 SLOT06.F48 SLOT06.F50 SLOT06.F52 SLOT06.F54 SLOT06.F56 SLOT06.F58 SLOT06.F60 SLOT09.A16(GND[1]) SLOT09.A30(GND[2]) SLOT09.A36(GND[3]) SLOT09.A50(GND[4]) SLOT09.A56(GND[5]) SLOT09.B62(GND[6]) SLOT09.C62(GND[7]) SLOT09.E62(GND[8]) SLOT09.F62(GND[9]) SLOT09.G16(GND[10]) SLOT09.G30(GND[11]) SLOT09.G36(GND[12]) SLOT09.G50(GND[13]) SLOT09.G56(GND[14]) ; also on sheet 3 4 7 8 11 19 20 21 22 24 28 32 36 40 44 48 52
SL01_VI100_1_B_HF: SLOT09.A59(VI_5_A_LF[1]) SLOT09.B59(VI_5_A_LF[2]) SLOT09.C59(VI_5_A_LF[3]) SLOT09.D59(VI_1_A_LF[1]) SLOT09.E59(VI_1_A_LF[2]) SLOT09.F59(VI_1_A_LF[3]) ; also on sheet 20 22
SL01_VI100_1_B_HS: SLOT09.B24(VI_5_A_LS) SLOT09.D24(VI_1_A_LS) ; also on sheet 20 22
SL05_PMVI_1_BP: SLOT05.B35
SL05_PMVI_1_HF: SLOT05.F35 ; also on sheet 54
SL05_PMVI_1_HS: SLOT05.C35 ; also on sheet 54
SL05_PMVI_1_LS: SLOT05.A35 ; also on sheet 51
SL05_PMVI_2_BP: SLOT05.B33
SL05_PMVI_2_HF: SLOT05.F33 ; also on sheet 46
SL05_PMVI_2_HS: SLOT05.C33 ; also on sheet 46
SL05_PMVI_2_LS: SLOT05.A33 ; also on sheet 43
SL05_PMVI_3_BP: SLOT05.B31
SL05_PMVI_3_HF: SLOT05.F31 ; also on sheet 38
SL05_PMVI_3_HS: SLOT05.C31 ; also on sheet 38
SL05_PMVI_3_LS: SLOT05.A31 ; also on sheet 35
SL05_PMVI_4_BP: SLOT05.B29
SL05_PMVI_4_HF: SLOT05.F29 ; also on sheet 30
SL05_PMVI_4_HS: SLOT05.C29 ; also on sheet 30
SL05_PMVI_4_LS: SLOT05.A29 ; also on sheet 27
SL05_PMVI_5_BP: SLOT05.B27
SL05_PMVI_5_HF: SLOT05.F27
SL05_PMVI_5_HS: SLOT05.C27
SL05_PMVI_5_LS: SLOT05.A27
SL05_PMVI_6_BP: SLOT05.B25
SL05_PMVI_6_HF: SLOT05.F25
SL05_PMVI_6_HS: SLOT05.C25
SL05_PMVI_6_LS: SLOT05.A25
SL05_PMVI_7_BP: SLOT05.B23
SL05_PMVI_7_HF: SLOT05.F23
SL05_PMVI_7_HS: SLOT05.C23
SL05_PMVI_7_LS: SLOT05.A23
SL05_PMVI_8_BP: SLOT05.B21
SL05_PMVI_8_HF: SLOT05.F21
SL05_PMVI_8_HS: SLOT05.C21
SL05_PMVI_8_LS: SLOT05.A21
SL05_PMVI_9_BP: SLOT05.D37
SL05_PMVI_9_HF: SLOT05.F37
SL05_PMVI_9_HS: SLOT05.E37
SL05_PMVI_9_LS: SLOT05.C37
SL05_PMVI_10_BP: SLOT05.D33
SL05_PMVI_10_HF: SLOT05.E35 ; also on sheet 51
SL05_PMVI_10_HS: SLOT05.E33 ; also on sheet 51
SL05_PMVI_10_LS: SLOT05.B37 ; also on sheet 51
SL05_PMVI_11_BP: SLOT05.D29
SL05_PMVI_11_HF: SLOT05.E31 ; also on sheet 51
SL05_PMVI_11_HS: SLOT05.E29 ; also on sheet 51
SL05_PMVI_11_LS: SLOT05.A37 ; also on sheet 51
SL05_PMVI_12_BP: SLOT05.D25
SL05_PMVI_12_HF: SLOT05.E27 ; also on sheet 51
SL05_PMVI_12_HS: SLOT05.E25 ; also on sheet 51
SL05_PMVI_12_LS: SLOT05.B19 ; also on sheet 51
SL05_PMVI_13_BP: SLOT05.D21
SL05_PMVI_13_HF: SLOT05.E23 ; also on sheet 51
SL05_PMVI_13_HS: SLOT05.E21 ; also on sheet 51
SL05_PMVI_13_LS: SLOT05.A19 ; also on sheet 51
SL05_PMVI_14_BP: SLOT05.D19
SL05_PMVI_14_HF: SLOT05.F19 ; also on sheet 51
SL05_PMVI_14_HS: SLOT05.E19 ; also on sheet 51
SL05_PMVI_14_LS: SLOT05.C19 ; also on sheet 51
SL05_PMVI_15_BP: SLOT05.D17
SL05_PMVI_15_HF: SLOT05.F17 ; also on sheet 51
SL05_PMVI_15_HS: SLOT05.E17 ; also on sheet 51
SL05_PMVI_15_LS: SLOT05.A17 ; also on sheet 51
SL05_PMVI_16_BP: SLOT05.C17
SL05_PMVI_16_HF: SLOT05.E15 ; also on sheet 51
SL05_PMVI_16_HS: SLOT05.D15 ; also on sheet 51
SL05_PMVI_16_LS: SLOT05.B17 ; also on sheet 51
SL05_PMVI_17_BP: SLOT05.B15
SL05_PMVI_17_HF: SLOT05.F15 ; also on sheet 51
SL05_PMVI_17_HS: SLOT05.C15 ; also on sheet 51
SL05_PMVI_17_LS: SLOT05.A15 ; also on sheet 51
SL05_PMVI_18_BP: SLOT05.D13
SL05_PMVI_18_HF: SLOT05.F13 ; also on sheet 51
SL05_PMVI_18_HS: SLOT05.E13 ; also on sheet 51
SL05_PMVI_18_LS: SLOT05.A13 ; also on sheet 51
SL05_PMVI_19_BP: SLOT05.D11
SL05_PMVI_19_HF: SLOT05.F11 ; also on sheet 51
SL05_PMVI_19_HS: SLOT05.E11 ; also on sheet 51
SL05_PMVI_19_LS: SLOT05.B13 ; also on sheet 51
SL05_PMVI_20_BP: SLOT05.C11
SL05_PMVI_20_HF: SLOT05.E9 ; also on sheet 43
SL05_PMVI_20_HS: SLOT05.D9 ; also on sheet 43
SL05_PMVI_20_LS: SLOT05.C13 ; also on sheet 43
SL05_PMVI_21_BP: SLOT05.B9
SL05_PMVI_21_HF: SLOT05.F9 ; also on sheet 43
SL05_PMVI_21_HS: SLOT05.C9 ; also on sheet 43
SL05_PMVI_21_LS: SLOT05.B11 ; also on sheet 43
SL05_PMVI_22_BP: SLOT05.D7
SL05_PMVI_22_HF: SLOT05.F7 ; also on sheet 43
SL05_PMVI_22_HS: SLOT05.E7 ; also on sheet 43
SL05_PMVI_22_LS: SLOT05.A11 ; also on sheet 43
SL05_PMVI_23_BP: SLOT05.D5
SL05_PMVI_23_HF: SLOT05.F5 ; also on sheet 43
SL05_PMVI_23_HS: SLOT05.E5 ; also on sheet 43
SL05_PMVI_23_LS: SLOT05.A9 ; also on sheet 43
SL05_PMVI_24_BP: SLOT05.D3
SL05_PMVI_24_HF: SLOT05.F3 ; also on sheet 43
SL05_PMVI_24_HS: SLOT05.E3 ; also on sheet 43
SL05_PMVI_24_LS: SLOT05.A7 ; also on sheet 43
SL05_PMVI_25_BP: SLOT05.D1
SL05_PMVI_25_HF: SLOT05.F1 ; also on sheet 43
SL05_PMVI_25_HS: SLOT05.E1 ; also on sheet 43
SL05_PMVI_25_LS: SLOT05.B7 ; also on sheet 43
SL05_PMVI_26_BP: SLOT05.C3
SL05_PMVI_26_HF: SLOT05.G4 ; also on sheet 43
SL05_PMVI_26_HS: SLOT05.C1 ; also on sheet 43
SL05_PMVI_26_LS: SLOT05.C7 ; also on sheet 43
SL05_PMVI_27_BP: SLOT05.D2
SL05_PMVI_27_HF: SLOT05.F2 ; also on sheet 43
SL05_PMVI_27_HS: SLOT05.C4 ; also on sheet 43
SL05_PMVI_27_LS: SLOT05.C5 ; also on sheet 43
SL05_PMVI_28_BP: SLOT05.B3
SL05_PMVI_28_HF: SLOT05.A4 ; also on sheet 43
SL05_PMVI_28_HS: SLOT05.B1 ; also on sheet 43
SL05_PMVI_28_LS: SLOT05.B5 ; also on sheet 43
SL05_PMVI_29_BP: SLOT05.A3
SL05_PMVI_29_HF: SLOT05.B2 ; also on sheet 43
SL05_PMVI_29_HS: SLOT05.A1 ; also on sheet 43
SL05_PMVI_29_LS: SLOT05.A5 ; also on sheet 43
SL05_PMVI_30_BP: SLOT05.A60
SL05_PMVI_30_HF: SLOT05.B62 ; also on sheet 35
SL05_PMVI_30_HS: SLOT05.A61 ; also on sheet 35
SL05_PMVI_30_LS: SLOT05.B58 ; also on sheet 35
SL05_PMVI_31_BP: SLOT05.A59
SL05_PMVI_31_HF: SLOT05.C62 ; also on sheet 35
SL05_PMVI_31_HS: SLOT05.B61 ; also on sheet 35
SL05_PMVI_31_LS: SLOT05.A57 ; also on sheet 35
SL05_PMVI_32_BP: SLOT05.E60
SL05_PMVI_32_HF: SLOT05.F62 ; also on sheet 35
SL05_PMVI_32_HS: SLOT05.F61 ; also on sheet 35
SL05_PMVI_32_LS: SLOT05.C60 ; also on sheet 35
SL05_PMVI_33_BP: SLOT05.D61
SL05_PMVI_33_HF: SLOT05.E62 ; also on sheet 35
SL05_PMVI_33_HS: SLOT05.E61 ; also on sheet 35
SL05_PMVI_33_LS: SLOT05.C61 ; also on sheet 35
SL05_PMVI_34_BP: SLOT05.C59
SL05_PMVI_34_HF: SLOT05.F59 ; also on sheet 35
SL05_PMVI_34_HS: SLOT05.D59 ; also on sheet 35
SL05_PMVI_34_LS: SLOT05.B59 ; also on sheet 35
SL05_PMVI_35_BP: SLOT05.F58
SL05_PMVI_35_HF: SLOT05.G60 ; also on sheet 35
SL05_PMVI_35_HS: SLOT05.E59 ; also on sheet 35
SL05_PMVI_35_LS: SLOT05.D58 ; also on sheet 35
SL05_PMVI_36_BP: SLOT05.C57
SL05_PMVI_36_HF: SLOT05.E57 ; also on sheet 35
SL05_PMVI_36_HS: SLOT05.D57 ; also on sheet 35
SL05_PMVI_36_LS: SLOT05.B57 ; also on sheet 35
SL05_PMVI_37_BP: SLOT05.E56
SL05_PMVI_37_HF: SLOT05.F57 ; also on sheet 35
SL05_PMVI_37_HS: SLOT05.G56 ; also on sheet 35
SL05_PMVI_37_LS: SLOT05.C56 ; also on sheet 35
SL05_PMVI_38_BP: SLOT05.D55
SL05_PMVI_38_HF: SLOT05.F55 ; also on sheet 35
SL05_PMVI_38_HS: SLOT05.E55 ; also on sheet 35
SL05_PMVI_38_LS: SLOT05.B55 ; also on sheet 35
SL05_PMVI_39_BP: SLOT05.B54
SL05_PMVI_39_HF: SLOT05.E52 ; also on sheet 35
SL05_PMVI_39_HS: SLOT05.C55 ; also on sheet 35
SL05_PMVI_39_LS: SLOT05.A55 ; also on sheet 35
SL05_PMVI_40_BP: SLOT05.D54
SL05_PMVI_40_HF: SLOT05.G52 ; also on sheet 27
SL05_PMVI_40_HS: SLOT05.F54 ; also on sheet 27
SL05_PMVI_40_LS: SLOT05.A56 ; also on sheet 27
SL05_PMVI_41_BP: SLOT05.B53
SL05_PMVI_41_HF: SLOT05.F53 ; also on sheet 27
SL05_PMVI_41_HS: SLOT05.C53 ; also on sheet 27
SL05_PMVI_41_LS: SLOT05.A53 ; also on sheet 27
SL05_PMVI_42_BP: SLOT05.D53
SL05_PMVI_42_HF: SLOT05.F51 ; also on sheet 27
SL05_PMVI_42_HS: SLOT05.E53 ; also on sheet 27
SL05_PMVI_42_LS: SLOT05.A52 ; also on sheet 27
SL05_PMVI_43_BP: SLOT05.C51
SL05_PMVI_43_HF: SLOT05.E51 ; also on sheet 27
SL05_PMVI_43_HS: SLOT05.D51 ; also on sheet 27
SL05_PMVI_43_LS: SLOT05.C52 ; also on sheet 27
SL05_PMVI_44_BP: SLOT05.D50
SL05_PMVI_44_HF: SLOT05.F49 ; also on sheet 27
SL05_PMVI_44_HS: SLOT05.F50 ; also on sheet 27
SL05_PMVI_44_LS: SLOT05.A51 ; also on sheet 27
SL05_PMVI_45_BP: SLOT05.B50
SL05_PMVI_45_HF: SLOT05.E49 ; also on sheet 27
SL05_PMVI_45_HS: SLOT05.D49 ; also on sheet 27
SL05_PMVI_45_LS: SLOT05.B51 ; also on sheet 27
SL05_PMVI_46_BP: SLOT05.B49
SL05_PMVI_46_HF: SLOT05.G48 ; also on sheet 27
SL05_PMVI_46_HS: SLOT05.C49 ; also on sheet 27
SL05_PMVI_46_LS: SLOT05.A49 ; also on sheet 27
SL05_PMVI_47_BP: SLOT05.D47
SL05_PMVI_47_HF: SLOT05.F47 ; also on sheet 27
SL05_PMVI_47_HS: SLOT05.E47 ; also on sheet 27
SL05_PMVI_47_LS: SLOT05.A48 ; also on sheet 27
SL05_PMVI_48_BP: SLOT05.C45
SL05_PMVI_48_HF: SLOT05.F45 ; also on sheet 27
SL05_PMVI_48_HS: SLOT05.D46 ; also on sheet 27
SL05_PMVI_48_LS: SLOT05.C48 ; also on sheet 27
SL05_PMVI_49_BP: SLOT05.C47
SL05_PMVI_49_HF: SLOT05.F46 ; also on sheet 27
SL05_PMVI_49_HS: SLOT05.E45 ; also on sheet 27
SL05_PMVI_49_LS: SLOT05.E48 ; also on sheet 27
SL05_PMVI_50_BP: SLOT05.B46
SL05_PMVI_50_HF: SLOT05.G44
SL05_PMVI_50_HS: SLOT05.B45
SL05_PMVI_50_LS: SLOT05.B47
SL05_PMVI_51_BP: SLOT05.D45
SL05_PMVI_51_HF: SLOT05.F41
SL05_PMVI_51_HS: SLOT05.E43
SL05_PMVI_51_LS: SLOT05.A47
SL05_PMVI_52_BP: SLOT05.D43
SL05_PMVI_52_HF: SLOT05.F43
SL05_PMVI_52_HS: SLOT05.F42
SL05_PMVI_52_LS: SLOT05.A45
SL05_PMVI_53_BP: SLOT05.D42
SL05_PMVI_53_HF: SLOT05.G40
SL05_PMVI_53_HS: SLOT05.E41
SL05_PMVI_53_LS: SLOT05.A44
SL05_PMVI_54_BP: SLOT05.C41
SL05_PMVI_54_HF: SLOT05.F39
SL05_PMVI_54_HS: SLOT05.D41
SL05_PMVI_54_LS: SLOT05.C44
SL05_PMVI_55_BP: SLOT05.B41
SL05_PMVI_55_HF: SLOT05.F38
SL05_PMVI_55_HS: SLOT05.B39
SL05_PMVI_55_LS: SLOT05.E44
SL05_PMVI_56_BP: SLOT05.C39
SL05_PMVI_56_HF: SLOT05.E39
SL05_PMVI_56_HS: SLOT05.D39
SL05_PMVI_56_LS: SLOT05.C43
SL05_PMVI_57_BP: SLOT05.A41
SL05_PMVI_57_HF: SLOT05.E40
SL05_PMVI_57_HS: SLOT05.A39
SL05_PMVI_57_LS: SLOT05.B43
SL05_PMVI_58_BP: SLOT05.B42
SL05_PMVI_58_HF: SLOT05.C40
SL05_PMVI_58_HS: SLOT05.A40
SL05_PMVI_58_LS: SLOT05.A43
SL05_PMVI_59_BP: SLOT05.C36
SL05_PMVI_59_HF: SLOT05.G36
SL05_PMVI_59_HS: SLOT05.E36
SL05_PMVI_59_LS: SLOT05.D38
SL05_PMVI_60_BP: SLOT05.D34
SL05_PMVI_60_HF: SLOT05.G32
SL05_PMVI_60_HS: SLOT05.E32
SL05_PMVI_60_LS: SLOT05.B38
SL05_PMVI_61_BP: SLOT05.E24
SL05_PMVI_61_HF: SLOT05.E28
SL05_PMVI_61_HS: SLOT05.F26
SL05_PMVI_61_LS: SLOT05.A36
SL05_PMVI_62_BP: SLOT05.F18
SL05_PMVI_62_HF: SLOT05.G20
SL05_PMVI_62_HS: SLOT05.E16
SL05_PMVI_62_LS: SLOT05.B10
SL05_PMVI_63_BP: SLOT05.E12
SL05_PMVI_63_HF: SLOT05.F14
SL05_PMVI_63_HS: SLOT05.D10
SL05_PMVI_63_LS: SLOT05.A8
SL05_PMVI_64_BP: SLOT05.E8
SL05_PMVI_64_HF: SLOT05.G8
SL05_PMVI_64_HS: SLOT05.F6
SL05_PMVI_64_LS: SLOT05.C8
SL05_PMVI_65_BP: SLOT05.B34
SL05_PMVI_65_HF: SLOT05.F34
SL05_PMVI_65_HS: SLOT05.C32
SL05_PMVI_65_LS: SLOT05.A32
SL05_PMVI_66_BP: SLOT05.D30
SL05_PMVI_66_HF: SLOT05.F30
SL05_PMVI_66_HS: SLOT05.C28
SL05_PMVI_66_LS: SLOT05.B30
SL05_PMVI_67_BP: SLOT05.B26
SL05_PMVI_67_HF: SLOT05.G28
SL05_PMVI_67_HS: SLOT05.D26
SL05_PMVI_67_LS: SLOT05.A28
SL05_PMVI_68_BP: SLOT05.C24
SL05_PMVI_68_HF: SLOT05.G24
SL05_PMVI_68_HS: SLOT05.B22
SL05_PMVI_68_LS: SLOT05.A24
SL05_PMVI_69_BP: SLOT05.C20
SL05_PMVI_69_HF: SLOT05.F22
SL05_PMVI_69_HS: SLOT05.D22
SL05_PMVI_69_LS: SLOT05.A20
SL05_PMVI_70_BP: SLOT05.D18
SL05_PMVI_70_HF: SLOT05.G16
SL05_PMVI_70_HS: SLOT05.E20
SL05_PMVI_70_LS: SLOT05.B18
SL05_PMVI_71_BP: SLOT05.C16
SL05_PMVI_71_HF: SLOT05.G12
SL05_PMVI_71_HS: SLOT05.B14
SL05_PMVI_71_LS: SLOT05.A16
SL05_PMVI_72_BP: SLOT05.C12
SL05_PMVI_72_HF: SLOT05.F10
SL05_PMVI_72_HS: SLOT05.D14
SL05_PMVI_72_LS: SLOT05.A12
SL06_DP_0: SLOT06.C61 ; also on sheet 50
SL06_DP_1: SLOT06.D61 ; also on sheet 50
SL06_DP_2: SLOT06.E61 ; also on sheet 50
SL06_DP_3: SLOT06.F61 ; also on sheet 50
SL06_DP_4: SLOT06.A59 ; also on sheet 50
SL06_DP_5: SLOT06.B59 ; also on sheet 50
SL06_DP_6: SLOT06.C59 ; also on sheet 50
SL06_DP_7: SLOT06.D59 ; also on sheet 50
SL06_DP_8: SLOT06.E59 ; also on sheet 49
SL06_DP_9: SLOT06.F59 ; also on sheet 49
SL06_DP_10: SLOT06.Z59 ; also on sheet 49
SL06_DP_11: SLOT06.Z57 ; also on sheet 49
SL06_DP_12: SLOT06.A57 ; also on sheet 49
SL06_DP_13: SLOT06.B57 ; also on sheet 49
SL06_DP_14: SLOT06.C57 ; also on sheet 49
SL06_DP_15: SLOT06.D57 ; also on sheet 49
SL06_DP_16: SLOT06.E57 ; also on sheet 49
SL06_DP_17: SLOT06.F57 ; also on sheet 49
SL06_DP_18: SLOT06.A55 ; also on sheet 49
SL06_DP_19: SLOT06.B55 ; also on sheet 49
SL06_DP_20: SLOT06.C55 ; also on sheet 49
SL06_DP_21: SLOT06.D55 ; also on sheet 48
SL06_DP_22: SLOT06.E55 ; also on sheet 48
SL06_DP_23: SLOT06.F55 ; also on sheet 48
SL06_DP_24: SLOT06.Z55 ; also on sheet 48
SL06_DP_25: SLOT06.Z53 ; also on sheet 48
SL06_DP_26: SLOT06.A53 ; also on sheet 48
SL06_DP_27: SLOT06.B53 ; also on sheet 48
SL06_DP_28: SLOT06.C53 ; also on sheet 48
SL06_DP_29: SLOT06.D53 ; also on sheet 48
SL06_DP_30: SLOT06.E53 ; also on sheet 42
SL06_DP_31: SLOT06.F53 ; also on sheet 42
SL06_DP_32: SLOT06.A51 ; also on sheet 42
SL06_DP_33: SLOT06.B51 ; also on sheet 42
SL06_DP_34: SLOT06.C51 ; also on sheet 42
SL06_DP_35: SLOT06.D51 ; also on sheet 42
SL06_DP_36: SLOT06.E51 ; also on sheet 42
SL06_DP_37: SLOT06.F51 ; also on sheet 42
SL06_DP_38: SLOT06.A49 ; also on sheet 41
SL06_DP_39: SLOT06.B49 ; also on sheet 41
SL06_DP_40: SLOT06.C49 ; also on sheet 41
SL06_DP_41: SLOT06.D49 ; also on sheet 41
SL06_DP_42: SLOT06.E49 ; also on sheet 41
SL06_DP_43: SLOT06.F49 ; also on sheet 41
SL06_DP_44: SLOT06.Z49 ; also on sheet 41
SL06_DP_45: SLOT06.Z47 ; also on sheet 41
SL06_DP_46: SLOT06.A47 ; also on sheet 41
SL06_DP_47: SLOT06.B47 ; also on sheet 41
SL06_DP_48: SLOT06.C47 ; also on sheet 41
SL06_DP_49: SLOT06.D47 ; also on sheet 41
SL06_DP_50: SLOT06.E47 ; also on sheet 41
SL06_DP_51: SLOT06.F47 ; also on sheet 40
SL06_DP_52: SLOT06.A45 ; also on sheet 40
SL06_DP_53: SLOT06.B45 ; also on sheet 40
SL06_DP_54: SLOT06.C45 ; also on sheet 40
SL06_DP_55: SLOT06.D45 ; also on sheet 40
SL06_DP_56: SLOT06.E45 ; also on sheet 40
SL06_DP_57: SLOT06.F45 ; also on sheet 40
SL06_DP_58: SLOT06.Z45 ; also on sheet 40
SL06_DP_59: SLOT06.Z43 ; also on sheet 40
SL06_DP_60: SLOT06.A43 ; also on sheet 34
SL06_DP_61: SLOT06.B43 ; also on sheet 34
SL06_DP_62: SLOT06.C43 ; also on sheet 34
SL06_DP_63: SLOT06.D43 ; also on sheet 34
SL06_DP_64: SLOT06.A37 ; also on sheet 34
SL06_DP_65: SLOT06.B37 ; also on sheet 34
SL06_DP_66: SLOT06.C37 ; also on sheet 34
SL06_DP_67: SLOT06.D37 ; also on sheet 34
SL06_DP_68: SLOT06.E37 ; also on sheet 33
SL06_DP_69: SLOT06.F37 ; also on sheet 33
SL06_DP_70: SLOT06.A35 ; also on sheet 33
SL06_DP_71: SLOT06.B35 ; also on sheet 33
SL06_DP_72: SLOT06.C35 ; also on sheet 33
SL06_DP_73: SLOT06.D35 ; also on sheet 33
SL06_DP_74: SLOT06.E35 ; also on sheet 33
SL06_DP_75: SLOT06.F35 ; also on sheet 33
SL06_DP_76: SLOT06.Z35 ; also on sheet 33
SL06_DP_77: SLOT06.Z33 ; also on sheet 33
SL06_DP_78: SLOT06.A33 ; also on sheet 33
SL06_DP_79: SLOT06.B33 ; also on sheet 33
SL06_DP_80: SLOT06.C33 ; also on sheet 33
SL06_DP_81: SLOT06.D33 ; also on sheet 32
SL06_DP_82: SLOT06.E33 ; also on sheet 32
SL06_DP_83: SLOT06.F33 ; also on sheet 32
SL06_DP_84: SLOT06.A31 ; also on sheet 32
SL06_DP_85: SLOT06.B31 ; also on sheet 32
SL06_DP_86: SLOT06.C31 ; also on sheet 32
SL06_DP_87: SLOT06.D31 ; also on sheet 32
SL06_DP_88: SLOT06.E31 ; also on sheet 32
SL06_DP_89: SLOT06.F31 ; also on sheet 32
SL06_DP_90: SLOT06.Z31 ; also on sheet 26
SL06_DP_91: SLOT06.Z29 ; also on sheet 26
SL06_DP_92: SLOT06.A29 ; also on sheet 26
SL06_DP_93: SLOT06.B29 ; also on sheet 26
SL06_DP_94: SLOT06.C29 ; also on sheet 26
SL06_DP_95: SLOT06.D29 ; also on sheet 26
SL06_DP_96: SLOT06.E29 ; also on sheet 26
SL06_DP_97: SLOT06.F29 ; also on sheet 26
SL06_DP_98: SLOT06.A27 ; also on sheet 25
SL06_DP_99: SLOT06.B27 ; also on sheet 25
SL06_DP_100: SLOT06.C27 ; also on sheet 25
SL06_DP_101: SLOT06.D27 ; also on sheet 25
SL06_DP_102: SLOT06.E27 ; also on sheet 25
SL06_DP_103: SLOT06.F27 ; also on sheet 25
SL06_DP_104: SLOT06.Z27 ; also on sheet 25
SL06_DP_105: SLOT06.Z25 ; also on sheet 25
SL06_DP_106: SLOT06.A25 ; also on sheet 25
SL06_DP_107: SLOT06.B25 ; also on sheet 25
SL06_DP_108: SLOT06.C25 ; also on sheet 25
SL06_DP_109: SLOT06.D25 ; also on sheet 25
SL06_DP_110: SLOT06.E25 ; also on sheet 25
SL06_DP_111: SLOT06.F25 ; also on sheet 24
SL06_DP_112: SLOT06.A23 ; also on sheet 24
SL06_DP_113: SLOT06.B23 ; also on sheet 24
SL06_DP_114: SLOT06.C23 ; also on sheet 24
SL06_DP_115: SLOT06.D23 ; also on sheet 24
SL06_DP_116: SLOT06.E23 ; also on sheet 24
SL06_DP_117: SLOT06.F23 ; also on sheet 24
SL06_DP_118: SLOT06.Z23 ; also on sheet 24
SL06_DP_119: SLOT06.Z21 ; also on sheet 24
SL06_DP_120: SLOT06.A21
SL06_DP_121: SLOT06.B21 ; also on sheet 47
SL06_DP_122: SLOT06.C21 ; also on sheet 47
SL06_DP_123: SLOT06.D21 ; also on sheet 47
SL06_DP_124: SLOT06.E21 ; also on sheet 47
SL06_DP_125: SLOT06.F21 ; also on sheet 47
SL06_DP_126: SLOT06.B19 ; also on sheet 47
SL06_DP_127: SLOT06.C19 ; also on sheet 39
SL06_DP_128: SLOT06.E43 ; also on sheet 39
SL06_DP_129: SLOT06.F43 ; also on sheet 39
SL06_DP_130: SLOT06.A41 ; also on sheet 39
SL06_DP_131: SLOT06.B41 ; also on sheet 39
SL06_DP_132: SLOT06.C41 ; also on sheet 39
SL06_DP_133: SLOT06.D41 ; also on sheet 31
SL06_DP_134: SLOT06.E41 ; also on sheet 31
SL06_DP_135: SLOT06.F41 ; also on sheet 31
SL06_DP_136: SLOT06.Z41 ; also on sheet 31
SL06_DP_137: SLOT06.Z39 ; also on sheet 31
SL06_DP_138: SLOT06.A39 ; also on sheet 31
SL06_DP_139: SLOT06.B39 ; also on sheet 23
SL06_DP_140: SLOT06.C39 ; also on sheet 23
SL06_DP_141: SLOT06.D39 ; also on sheet 23
SL06_DP_142: SLOT06.E39 ; also on sheet 23
SL06_DP_143: SLOT06.F39 ; also on sheet 23
SL06_DP_144: SLOT06.A17 ; also on sheet 23
SL06_DP_145: SLOT06.B17
SL06_DP_146: SLOT06.C17
SL06_DP_147: SLOT06.D17
SL06_DP_148: SLOT06.E17
SL06_DP_149: SLOT06.F17
SL06_DP_150: SLOT06.A15
SL06_DP_151: SLOT06.B15
SL06_DP_152: SLOT06.C15
SL06_DP_153: SLOT06.D15
SL06_DP_154: SLOT06.E15
SL06_DP_155: SLOT06.F15
SL06_DP_156: SLOT06.Z15
SL06_DP_157: SLOT06.Z13
SL06_DP_158: SLOT06.A13
SL06_DP_159: SLOT06.B13
SL06_DP_160: SLOT06.C13
SL06_DP_161: SLOT06.D13
SL06_DP_162: SLOT06.E13
SL06_DP_163: SLOT06.F13
SL06_DP_164: SLOT06.A11
SL06_DP_165: SLOT06.B11
SL06_DP_166: SLOT06.C11
SL06_DP_167: SLOT06.D11
SL06_DP_168: SLOT06.E11
SL06_DP_169: SLOT06.F11
SL06_DP_170: SLOT06.Z11
SL06_DP_171: SLOT06.Z9
SL06_DP_172: SLOT06.A9
SL06_DP_173: SLOT06.B9
SL06_DP_174: SLOT06.C9
SL06_DP_175: SLOT06.D9
SL06_DP_176: SLOT06.E9
SL06_DP_177: SLOT06.F9
SL06_DP_178: SLOT06.A7
SL06_DP_179: SLOT06.B7
SL06_DP_180: SLOT06.C7
SL06_DP_181: SLOT06.D7
SL06_DP_182: SLOT06.E7
SL06_DP_183: SLOT06.F7
SL06_DP_184: SLOT06.Z7
SL06_DP_185: SLOT06.Z5
SL06_DP_186: SLOT06.A5
SL06_DP_187: SLOT06.B5
SL06_DP_188: SLOT06.C5
SL06_DP_189: SLOT06.D5
SL06_DP_190: SLOT06.E5
SL06_DP_191: SLOT06.F5
SL06_GND_SENSE: SLOT06.F19 ; also on sheet 22
SL09_FPVI_1_A_HF: SLOT09.D61(VI_1_A_HF[1]) SLOT09.E61(VI_1_A_HF[2]) SLOT09.F61(VI_1_A_HF[3]) ; also on sheet 54
SL09_FPVI_1_A_HS: SLOT09.E28(VI_1_A_HS) ; also on sheet 54
SL09_FPVI_1_ALTA_HF: SLOT09.D45(VI_1_ALTA_HF[1]) SLOT09.E45(VI_1_ALTA_HF[2]) SLOT09.F45(VI_1_ALTA_HF[3])
SL09_FPVI_1_ALTA_HS: SLOT09.F24(VI_1_ALTA_HS)
SL09_FPVI_1_ALTA_LF: SLOT09.D43(VI_1_ALTA_LF[1]) SLOT09.E43(VI_1_ALTA_LF[2]) SLOT09.F43(VI_1_ALTA_LF[3])
SL09_FPVI_1_ALTA_LS: SLOT09.G24(VI_1_ALTA_LS)
SL09_FPVI_1_ALTB_HF: SLOT09.D41(VI_1_ALTB_HF[1]) SLOT09.E41(VI_1_ALTB_HF[2]) SLOT09.F41(VI_1_ALTB_HF[3])
SL09_FPVI_1_ALTB_HS: SLOT09.G26(VI_1_ALTB_HS)
SL09_FPVI_1_ALTB_LF: SLOT09.D39(VI_1_ALTB_LF[1]) SLOT09.E39(VI_1_ALTB_LF[2]) SLOT09.F39(VI_1_ALTB_LF[3])
SL09_FPVI_1_ALTB_LS: SLOT09.G22(VI_1_ALTB_LS)
SL09_FPVI_1_B_HF: SLOT09.D57(VI_1_B_HF[1]) SLOT09.E57(VI_1_B_HF[2]) SLOT09.F57(VI_1_B_HF[3])
SL09_FPVI_1_B_HS: SLOT09.F28(VI_1_B_HS)
SL09_FPVI_1_B_LF: SLOT09.D55(VI_1_B_LF[1]) SLOT09.E55(VI_1_B_LF[2]) SLOT09.F55(VI_1_B_LF[3])
SL09_FPVI_1_B_LS: SLOT09.E26(VI_1_B_LS)
SL09_FPVI_1_C_HF: SLOT09.D53(VI_1_C_HF[1]) SLOT09.E53(VI_1_C_HF[2]) SLOT09.F53(VI_1_C_HF[3])
SL09_FPVI_1_C_HS: SLOT09.G28(VI_1_C_HS)
SL09_FPVI_1_C_LF: SLOT09.D51(VI_1_C_LF[1]) SLOT09.E51(VI_1_C_LF[2]) SLOT09.F51(VI_1_C_LF[3])
SL09_FPVI_1_C_LS: SLOT09.F26(VI_1_C_LS)
SL09_FPVI_1_D_HF: SLOT09.D49(VI_1_D_HF[1]) SLOT09.E49(VI_1_D_HF[2]) SLOT09.F49(VI_1_D_HF[3])
SL09_FPVI_1_D_HS: SLOT09.E24(VI_1_D_HS)
SL09_FPVI_1_D_LF: SLOT09.D47(VI_1_D_LF[1]) SLOT09.E47(VI_1_D_LF[2]) SLOT09.F47(VI_1_D_LF[3])
SL09_FPVI_1_D_LS: SLOT09.F22(VI_1_D_LS)
SL09_FPVI_2_A_HF: SLOT09.D37(VI_2_A_HF[1]) SLOT09.E37(VI_2_A_HF[2]) SLOT09.F37(VI_2_A_HF[3]) ; also on sheet 38
SL09_FPVI_2_A_HS: SLOT09.D20(VI_2_A_HS) ; also on sheet 38
SL09_FPVI_2_A_LF: SLOT09.A35(VI_6_A_LF[1]) SLOT09.B35(VI_6_A_LF[2]) SLOT09.C35(VI_6_A_LF[3]) SLOT09.D35(VI_2_A_LF[1]) SLOT09.E35(VI_2_A_LF[2]) SLOT09.F35(VI_2_A_LF[3]) ; also on sheet 4 22
SL09_FPVI_2_A_LS: SLOT09.A18(VI_6_A_LS) SLOT09.D18(VI_2_A_LS) ; also on sheet 4 22
SL09_FPVI_2_ALTA_HF: SLOT09.D21(VI_2_ALTA_HF[1]) SLOT09.E21(VI_2_ALTA_HF[2]) SLOT09.F21(VI_2_ALTA_HF[3])
SL09_FPVI_2_ALTA_HS: SLOT09.F18(VI_2_ALTA_HS)
SL09_FPVI_2_ALTA_LF: SLOT09.D19(VI_2_ALTA_LF[1]) SLOT09.E19(VI_2_ALTA_LF[2]) SLOT09.F19(VI_2_ALTA_LF[3])
SL09_FPVI_2_ALTA_LS: SLOT09.D14(VI_2_ALTA_LS)
SL09_FPVI_2_ALTB_HF: SLOT09.D17(VI_2_ALTB_HF[1]) SLOT09.E17(VI_2_ALTB_HF[2]) SLOT09.F17(VI_2_ALTB_HF[3])
SL09_FPVI_2_ALTB_HS: SLOT09.G18(VI_2_ALTB_HS)
SL09_FPVI_2_ALTB_LF: SLOT09.D15(VI_2_ALTB_LF[1]) SLOT09.E15(VI_2_ALTB_LF[2]) SLOT09.F15(VI_2_ALTB_LF[3])
SL09_FPVI_2_ALTB_LS: SLOT09.E14(VI_2_ALTB_LS)
SL09_FPVI_2_B_HF: SLOT09.D33(VI_2_B_HF[1]) SLOT09.E33(VI_2_B_HF[2]) SLOT09.F33(VI_2_B_HF[3])
SL09_FPVI_2_B_HS: SLOT09.E20(VI_2_B_HS)
SL09_FPVI_2_B_LF: SLOT09.D31(VI_2_B_LF[1]) SLOT09.E31(VI_2_B_LF[2]) SLOT09.F31(VI_2_B_LF[3])
SL09_FPVI_2_B_LS: SLOT09.E18(VI_2_B_LS)
SL09_FPVI_2_C_HF: SLOT09.D29(VI_2_C_HF[1]) SLOT09.E29(VI_2_C_HF[2]) SLOT09.F29(VI_2_C_HF[3])
SL09_FPVI_2_C_HS: SLOT09.F20(VI_2_C_HS)
SL09_FPVI_2_C_LF: SLOT09.D27(VI_2_C_LF[1]) SLOT09.E27(VI_2_C_LF[2]) SLOT09.F27(VI_2_C_LF[3])
SL09_FPVI_2_C_LS: SLOT09.G20(VI_2_C_LS)
SL09_FPVI_2_D_HF: SLOT09.D25(VI_2_D_HF[1]) SLOT09.E25(VI_2_D_HF[2]) SLOT09.F25(VI_2_D_HF[3])
SL09_FPVI_2_D_HS: SLOT09.F16(VI_2_D_HS)
SL09_FPVI_2_D_LF: SLOT09.D23(VI_2_D_LF[1]) SLOT09.E23(VI_2_D_LF[2]) SLOT09.F23(VI_2_D_LF[3])
SL09_FPVI_2_D_LS: SLOT09.C14(VI_2_D_LS)
SL09_FPVI_3_A_HF: SLOT09.D13(VI_3_A_HF[1]) SLOT09.E13(VI_3_A_HF[2]) SLOT09.F13(VI_3_A_HF[3])
SL09_FPVI_3_A_HS: SLOT09.F14(VI_3_A_HS)
SL09_FPVI_3_A_LF: SLOT09.D11(VI_3_A_LF[1]) SLOT09.E11(VI_3_A_LF[2]) SLOT09.F11(VI_3_A_LF[3])
SL09_FPVI_3_A_LS: SLOT09.D10(VI_3_A_LS)
SL09_FPVI_3_ALTA_HF: SLOT09.F56(VI_3_ALTA_HF[1]) SLOT09.F58(VI_3_ALTA_HF[2]) SLOT09.G58(VI_3_ALTA_HF[3])
SL09_FPVI_3_ALTA_HS: SLOT09.E10(VI_3_ALTA_HS)
SL09_FPVI_3_ALTA_LF: SLOT09.C54(VI_3_ALTA_LF[1]) SLOT09.D54(VI_3_ALTA_LF[2]) SLOT09.E54(VI_3_ALTA_LF[3])
SL09_FPVI_3_ALTA_LS: SLOT09.F8(VI_3_ALTA_LS)
SL09_FPVI_3_ALTB_HF: SLOT09.F54(VI_3_ALTB_HF[1]) SLOT09.G52(VI_3_ALTB_HF[2]) SLOT09.G54(VI_3_ALTB_HF[3])
SL09_FPVI_3_ALTB_HS: SLOT09.F10(VI_3_ALTB_HS)
SL09_FPVI_3_ALTB_LF: SLOT09.D50(VI_3_ALTB_LF[1]) SLOT09.E52(VI_3_ALTB_LF[2]) SLOT09.F52(VI_3_ALTB_LF[3])
SL09_FPVI_3_ALTB_LS: SLOT09.G8(VI_3_ALTB_LS)
SL09_FPVI_3_B_HF: SLOT09.D9(VI_3_B_HF[1]) SLOT09.E9(VI_3_B_HF[2]) SLOT09.F9(VI_3_B_HF[3])
SL09_FPVI_3_B_HS: SLOT09.G12(VI_3_B_HS)
SL09_FPVI_3_B_LF: SLOT09.D7(VI_3_B_LF[1]) SLOT09.E7(VI_3_B_LF[2]) SLOT09.F7(VI_3_B_LF[3])
SL09_FPVI_3_B_LS: SLOT09.E12(VI_3_B_LS)
SL09_FPVI_3_C_HF: SLOT09.D5(VI_3_C_HF[1]) SLOT09.E5(VI_3_C_HF[2]) SLOT09.F5(VI_3_C_HF[3])
SL09_FPVI_3_C_HS: SLOT09.G14(VI_3_C_HS)
SL09_FPVI_3_C_LF: SLOT09.D3(VI_3_C_LF[1]) SLOT09.E3(VI_3_C_LF[2]) SLOT09.F3(VI_3_C_LF[3])
SL09_FPVI_3_C_LS: SLOT09.F12(VI_3_C_LS)
SL09_FPVI_3_D_HF: SLOT09.D60(VI_3_D_HF[1]) SLOT09.E60(VI_3_D_HF[2]) SLOT09.F60(VI_3_D_HF[3])
SL09_FPVI_3_D_HS: SLOT09.D8(VI_3_D_HS)
SL09_FPVI_3_D_LF: SLOT09.D58(VI_3_D_LF[1]) SLOT09.E58(VI_3_D_LF[2]) SLOT09.G60(VI_3_D_LF[3])
SL09_FPVI_3_D_LS: SLOT09.E8(VI_3_D_LS)
SL09_FPVI_4_A_HF: SLOT09.D48(VI_4_A_HF[1]) SLOT09.E50(VI_4_A_HF[2]) SLOT09.F50(VI_4_A_HF[3])
SL09_FPVI_4_A_HS: SLOT09.F6(VI_4_A_HS)
SL09_FPVI_4_A_LF: SLOT09.E48(VI_4_A_LF[1]) SLOT09.F48(VI_4_A_LF[2]) SLOT09.G48(VI_4_A_LF[3])
SL09_FPVI_4_A_LS: SLOT09.G6(VI_4_A_LS)
SL09_FPVI_4_ALTA_HF: SLOT09.C34(VI_4_ALTA_HF[1]) SLOT09.D34(VI_4_ALTA_HF[2]) SLOT09.E34(VI_4_ALTA_HF[3])
SL09_FPVI_4_ALTA_HS: SLOT09.C4(VI_4_ALTA_HS)
SL09_FPVI_4_ALTA_LF: SLOT09.F34(VI_4_ALTA_LF[1]) SLOT09.G32(VI_4_ALTA_LF[2]) SLOT09.G34(VI_4_ALTA_LF[3])
SL09_FPVI_4_ALTA_LS: SLOT09.A2(VI_4_ALTA_LS)
SL09_FPVI_4_ALTB_HF: SLOT09.D30(VI_4_ALTB_HF[1]) SLOT09.E32(VI_4_ALTB_HF[2]) SLOT09.F32(VI_4_ALTB_HF[3])
SL09_FPVI_4_ALTB_HS: SLOT09.B4(VI_4_ALTB_HS)
SL09_FPVI_4_ALTB_LF: SLOT09.D28(VI_4_ALTB_LF[1]) SLOT09.E30(VI_4_ALTB_LF[2]) SLOT09.F30(VI_4_ALTB_LF[3])
SL09_FPVI_4_ALTB_LS: SLOT09.A4(VI_4_ALTB_LS)
SL09_FPVI_4_B_HF: SLOT09.D44(VI_4_B_HF[1]) SLOT09.E46(VI_4_B_HF[2]) SLOT09.F46(VI_4_B_HF[3])
SL09_FPVI_4_B_HS: SLOT09.E6(VI_4_B_HS)
SL09_FPVI_4_B_LF: SLOT09.E44(VI_4_B_LF[1]) SLOT09.F44(VI_4_B_LF[2]) SLOT09.G46(VI_4_B_LF[3])
SL09_FPVI_4_B_LS: SLOT09.F4(VI_4_B_LS)
SL09_FPVI_4_C_HF: SLOT09.F42(VI_4_C_HF[1]) SLOT09.G42(VI_4_C_HF[2]) SLOT09.G44(VI_4_C_HF[3])
SL09_FPVI_4_C_HS: SLOT09.D4(VI_4_C_HS)
SL09_FPVI_4_C_LF: SLOT09.D40(VI_4_C_LF[1]) SLOT09.E40(VI_4_C_LF[2]) SLOT09.F40(VI_4_C_LF[3])
SL09_FPVI_4_C_LS: SLOT09.E4(VI_4_C_LS)
SL09_FPVI_4_D_HF: SLOT09.D38(VI_4_D_HF[1]) SLOT09.E38(VI_4_D_HF[2]) SLOT09.G40(VI_4_D_HF[3])
SL09_FPVI_4_D_HS: SLOT09.D6(VI_4_D_HS)
SL09_FPVI_4_D_LF: SLOT09.F36(VI_4_D_LF[1]) SLOT09.F38(VI_4_D_LF[2]) SLOT09.G38(VI_4_D_LF[3])
SL09_FPVI_4_D_LS: SLOT09.B2(VI_4_D_LS)
SL09_FPVI_5_A_HF: SLOT09.A61(VI_5_A_HF[1]) SLOT09.B61(VI_5_A_HF[2]) SLOT09.C61(VI_5_A_HF[3]) ; also on sheet 46
SL09_FPVI_5_A_HS: SLOT09.A26(VI_5_A_HS) ; also on sheet 46
SL09_FPVI_5_ALTA_HF: SLOT09.A45(VI_5_ALTA_HF[1]) SLOT09.B45(VI_5_ALTA_HF[2]) SLOT09.C45(VI_5_ALTA_HF[3])
SL09_FPVI_5_ALTA_HS: SLOT09.A22(VI_5_ALTA_HS)
SL09_FPVI_5_ALTA_LF: SLOT09.A43(VI_5_ALTA_LF[1]) SLOT09.B43(VI_5_ALTA_LF[2]) SLOT09.C43(VI_5_ALTA_LF[3])
SL09_FPVI_5_ALTA_LS: SLOT09.D22(VI_5_ALTA_LS)
SL09_FPVI_5_ALTB_HF: SLOT09.A41(VI_5_ALTB_HF[1]) SLOT09.B41(VI_5_ALTB_HF[2]) SLOT09.C41(VI_5_ALTB_HF[3])
SL09_FPVI_5_ALTB_HS: SLOT09.B22(VI_5_ALTB_HS)
SL09_FPVI_5_ALTB_LF: SLOT09.A39(VI_5_ALTB_LF[1]) SLOT09.B39(VI_5_ALTB_LF[2]) SLOT09.C39(VI_5_ALTB_LF[3])
SL09_FPVI_5_ALTB_LS: SLOT09.E22(VI_5_ALTB_LS)
SL09_FPVI_5_B_HF: SLOT09.A57(VI_5_B_HF[1]) SLOT09.B57(VI_5_B_HF[2]) SLOT09.C57(VI_5_B_HF[3])
SL09_FPVI_5_B_HS: SLOT09.B26(VI_5_B_HS)
SL09_FPVI_5_B_LF: SLOT09.A55(VI_5_B_LF[1]) SLOT09.B55(VI_5_B_LF[2]) SLOT09.C55(VI_5_B_LF[3])
SL09_FPVI_5_B_LS: SLOT09.C24(VI_5_B_LS)
SL09_FPVI_5_C_HF: SLOT09.A53(VI_5_C_HF[1]) SLOT09.B53(VI_5_C_HF[2]) SLOT09.C53(VI_5_C_HF[3])
SL09_FPVI_5_C_HS: SLOT09.C26(VI_5_C_HS)
SL09_FPVI_5_C_LF: SLOT09.A51(VI_5_C_LF[1]) SLOT09.B51(VI_5_C_LF[2]) SLOT09.C51(VI_5_C_LF[3])
SL09_FPVI_5_C_LS: SLOT09.D26(VI_5_C_LS)
SL09_FPVI_5_D_HF: SLOT09.A49(VI_5_D_HF[1]) SLOT09.B49(VI_5_D_HF[2]) SLOT09.C49(VI_5_D_HF[3])
SL09_FPVI_5_D_HS: SLOT09.A24(VI_5_D_HS)
SL09_FPVI_5_D_LF: SLOT09.A47(VI_5_D_LF[1]) SLOT09.B47(VI_5_D_LF[2]) SLOT09.C47(VI_5_D_LF[3])
SL09_FPVI_5_D_LS: SLOT09.C22(VI_5_D_LS)
SL09_FPVI_6_A_HF: SLOT09.A37(VI_6_A_HF[1]) SLOT09.B37(VI_6_A_HF[2]) SLOT09.C37(VI_6_A_HF[3]) ; also on sheet 30
SL09_FPVI_6_A_HS: SLOT09.A20(VI_6_A_HS) ; also on sheet 30
SL09_FPVI_6_ALTA_HF: SLOT09.A21(VI_6_ALTA_HF[1]) SLOT09.B21(VI_6_ALTA_HF[2]) SLOT09.C21(VI_6_ALTA_HF[3])
SL09_FPVI_6_ALTA_HS: SLOT09.D16(VI_6_ALTA_HS)
SL09_FPVI_6_ALTA_LF: SLOT09.A19(VI_6_ALTA_LF[1]) SLOT09.B19(VI_6_ALTA_LF[2]) SLOT09.C19(VI_6_ALTA_LF[3])
SL09_FPVI_6_ALTA_LS: SLOT09.B16(VI_6_ALTA_LS)
SL09_FPVI_6_ALTB_HF: SLOT09.A17(VI_6_ALTB_HF[1]) SLOT09.B17(VI_6_ALTB_HF[2]) SLOT09.C17(VI_6_ALTB_HF[3])
SL09_FPVI_6_ALTB_HS: SLOT09.E16(VI_6_ALTB_HS)
SL09_FPVI_6_ALTB_LF: SLOT09.A15(VI_6_ALTB_LF[1]) SLOT09.B15(VI_6_ALTB_LF[2]) SLOT09.C15(VI_6_ALTB_LF[3])
SL09_FPVI_6_ALTB_LS: SLOT09.B14(VI_6_ALTB_LS)
SL09_FPVI_6_B_HF: SLOT09.A33(VI_6_B_HF[1]) SLOT09.B33(VI_6_B_HF[2]) SLOT09.C33(VI_6_B_HF[3])
SL09_FPVI_6_B_HS: SLOT09.B20(VI_6_B_HS)
SL09_FPVI_6_B_LF: SLOT09.A31(VI_6_B_LF[1]) SLOT09.B31(VI_6_B_LF[2]) SLOT09.C31(VI_6_B_LF[3])
SL09_FPVI_6_B_LS: SLOT09.B18(VI_6_B_LS)
SL09_FPVI_6_C_HF: SLOT09.A29(VI_6_C_HF[1]) SLOT09.B29(VI_6_C_HF[2]) SLOT09.C29(VI_6_C_HF[3])
SL09_FPVI_6_C_HS: SLOT09.C20(VI_6_C_HS)
SL09_FPVI_6_C_LF: SLOT09.A27(VI_6_C_LF[1]) SLOT09.B27(VI_6_C_LF[2]) SLOT09.C27(VI_6_C_LF[3])
SL09_FPVI_6_C_LS: SLOT09.C18(VI_6_C_LS)
SL09_FPVI_6_D_HF: SLOT09.A25(VI_6_D_HF[1]) SLOT09.B25(VI_6_D_HF[2]) SLOT09.C25(VI_6_D_HF[3])
SL09_FPVI_6_D_HS: SLOT09.C16(VI_6_D_HS)
SL09_FPVI_6_D_LF: SLOT09.A23(VI_6_D_LF[1]) SLOT09.B23(VI_6_D_LF[2]) SLOT09.C23(VI_6_D_LF[3])
SL09_FPVI_6_D_LS: SLOT09.A14(VI_6_D_LS)
SL09_FPVI_7_A_HF: SLOT09.A13(VI_7_A_HF[1]) SLOT09.B13(VI_7_A_HF[2]) SLOT09.C13(VI_7_A_HF[3])
SL09_FPVI_7_A_HS: SLOT09.A12(VI_7_A_HS)
SL09_FPVI_7_A_LF: SLOT09.A11(VI_7_A_LF[1]) SLOT09.B11(VI_7_A_LF[2]) SLOT09.C11(VI_7_A_LF[3])
SL09_FPVI_7_A_LS: SLOT09.B10(VI_7_A_LS)
SL09_FPVI_7_ALTA_HF: SLOT09.C56(VI_7_ALTA_HF[1]) SLOT09.D56(VI_7_ALTA_HF[2]) SLOT09.E56(VI_7_ALTA_HF[3])
SL09_FPVI_7_ALTA_HS: SLOT09.B8(VI_7_ALTA_HS)
SL09_FPVI_7_ALTA_LF: SLOT09.A54(VI_7_ALTA_LF[1]) SLOT09.B54(VI_7_ALTA_LF[2]) SLOT09.B56(VI_7_ALTA_LF[3])
SL09_FPVI_7_ALTA_LS: SLOT09.B6(VI_7_ALTA_LS)
SL09_FPVI_7_ALTB_HF: SLOT09.A52(VI_7_ALTB_HF[1]) SLOT09.B52(VI_7_ALTB_HF[2]) SLOT09.C52(VI_7_ALTB_HF[3])
SL09_FPVI_7_ALTB_HS: SLOT09.C8(VI_7_ALTB_HS)
SL09_FPVI_7_ALTB_LF: SLOT09.B50(VI_7_ALTB_LF[1]) SLOT09.C50(VI_7_ALTB_LF[2]) SLOT09.D52(VI_7_ALTB_LF[3])
SL09_FPVI_7_ALTB_LS: SLOT09.C6(VI_7_ALTB_LS)
SL09_FPVI_7_B_HF: SLOT09.A9(VI_7_B_HF[1]) SLOT09.B9(VI_7_B_HF[2]) SLOT09.C9(VI_7_B_HF[3])
SL09_FPVI_7_B_HS: SLOT09.B12(VI_7_B_HS)
SL09_FPVI_7_B_LF: SLOT09.A7(VI_7_B_LF[1]) SLOT09.B7(VI_7_B_LF[2]) SLOT09.C7(VI_7_B_LF[3])
SL09_FPVI_7_B_LS: SLOT09.C10(VI_7_B_LS)
SL09_FPVI_7_C_HF: SLOT09.A5(VI_7_C_HF[1]) SLOT09.B5(VI_7_C_HF[2]) SLOT09.C5(VI_7_C_HF[3])
SL09_FPVI_7_C_HS: SLOT09.C12(VI_7_C_HS)
SL09_FPVI_7_C_LF: SLOT09.A3(VI_7_C_LF[1]) SLOT09.B3(VI_7_C_LF[2]) SLOT09.C3(VI_7_C_LF[3])
SL09_FPVI_7_C_LS: SLOT09.D12(VI_7_C_LS)
SL09_FPVI_7_D_HF: SLOT09.A60(VI_7_D_HF[1]) SLOT09.B60(VI_7_D_HF[2]) SLOT09.C60(VI_7_D_HF[3])
SL09_FPVI_7_D_HS: SLOT09.A8(VI_7_D_HS)
SL09_FPVI_7_D_LF: SLOT09.A58(VI_7_D_LF[1]) SLOT09.B58(VI_7_D_LF[2]) SLOT09.C58(VI_7_D_LF[3])
SL09_FPVI_7_D_LS: SLOT09.A6(VI_7_D_LS)
SL09_FPVI_8_A_HF: SLOT09.A48(VI_8_A_HF[1]) SLOT09.B48(VI_8_A_HF[2]) SLOT09.C48(VI_8_A_HF[3])
SL09_FPVI_8_A_HS: SLOT09.G2(VI_8_A_HS)
SL09_FPVI_8_A_LF: SLOT09.A46(VI_8_A_LF[1]) SLOT09.B46(VI_8_A_LF[2]) SLOT09.C46(VI_8_A_LF[3])
SL09_FPVI_8_A_LS: SLOT09.F1(VI_8_A_LS)
SL09_FPVI_8_ALTA_HF: SLOT09.A34(VI_8_ALTA_HF[1]) SLOT09.B34(VI_8_ALTA_HF[2]) SLOT09.B36(VI_8_ALTA_HF[3])
SL09_FPVI_8_ALTA_HS: SLOT09.D2(VI_8_ALTA_HS)
SL09_FPVI_8_ALTA_LF: SLOT09.A32(VI_8_ALTA_LF[1]) SLOT09.B32(VI_8_ALTA_LF[2]) SLOT09.C32(VI_8_ALTA_LF[3])
SL09_FPVI_8_ALTA_LS: SLOT09.B1(VI_8_ALTA_LS)
SL09_FPVI_8_ALTB_HF: SLOT09.B30(VI_8_ALTB_HF[1]) SLOT09.C30(VI_8_ALTB_HF[2]) SLOT09.D32(VI_8_ALTB_HF[3])
SL09_FPVI_8_ALTB_HS: SLOT09.C2(VI_8_ALTB_HS)
SL09_FPVI_8_ALTB_LF: SLOT09.A28(VI_8_ALTB_LF[1]) SLOT09.B28(VI_8_ALTB_LF[2]) SLOT09.C28(VI_8_ALTB_LF[3])
SL09_FPVI_8_ALTB_LS: SLOT09.A1(VI_8_ALTB_LS)
SL09_FPVI_8_B_HF: SLOT09.B44(VI_8_B_HF[1]) SLOT09.C44(VI_8_B_HF[2]) SLOT09.D46(VI_8_B_HF[3])
SL09_FPVI_8_B_HS: SLOT09.G4(VI_8_B_HS)
SL09_FPVI_8_B_LF: SLOT09.A42(VI_8_B_LF[1]) SLOT09.A44(VI_8_B_LF[2]) SLOT09.B42(VI_8_B_LF[3])
SL09_FPVI_8_B_LS: SLOT09.E1(VI_8_B_LS)
SL09_FPVI_8_C_HF: SLOT09.C42(VI_8_C_HF[1]) SLOT09.D42(VI_8_C_HF[2]) SLOT09.E42(VI_8_C_HF[3])
SL09_FPVI_8_C_HS: SLOT09.F2(VI_8_C_HS)
SL09_FPVI_8_C_LF: SLOT09.A40(VI_8_C_LF[1]) SLOT09.B40(VI_8_C_LF[2]) SLOT09.C40(VI_8_C_LF[3])
SL09_FPVI_8_C_LS: SLOT09.D1(VI_8_C_LS)
SL09_FPVI_8_D_HF: SLOT09.A38(VI_8_D_HF[1]) SLOT09.B38(VI_8_D_HF[2]) SLOT09.C38(VI_8_D_HF[3])
SL09_FPVI_8_D_HS: SLOT09.E2(VI_8_D_HS)
SL09_FPVI_8_D_LF: SLOT09.C36(VI_8_D_LF[1]) SLOT09.D36(VI_8_D_LF[2]) SLOT09.E36(VI_8_D_LF[3])
SL09_FPVI_8_D_LS: SLOT09.C1(VI_8_D_LS)

Not connected (* = marked no-connect by the designer): SLOT03 A1* A2* A3* A4* A5* A6* A7* A8* A9* A10* A11* A12* A13* A14* A15* A16* A17* A18* A19* A20* A21* A22* A23* A24* A25* A26* A27* A28* A29* A30* A31* A32* A33* A34* A35* A36* A37* A38* A39* A40* A41* A42* A43* A44* A45* A46* A47* A48* A49* A50* A51* A52* A53* A54* A55* A56* A57* A58* A59* A60* A61* B1* B2* B3* B4* B5* B6* B7* B8* B9* B10* B11* B12* B13* B14* B15* B16* B17* B18* B19* B20* B21* B22* B23* B24* B25* B26* B27* B28* B29* B30* B31* B32* B33* B34* B35* B36* B37* B38* B39* B40* B41* B42* B43* B44* B45* B46* B47* B48* B49* B50* B51* B52* B53* B54* B55* B56* B57* B58* B59* B60* B61* B62* C1* C2* C3* C4* C5* C6* C7* C8* C9* C10* C11* C12* C13* C14* C15* C16* C17* C18* C19* C20* C21* C22* C23* C24* C25* C26* C27* C28* C29* C30* C31* C32* C33* C34* C35* C36* C37* C38* C39* C40* C41* C42* C43* C44* C45* C46* C47* C48* C49* C50* C51* C52* C53* C54* C55* C56* C57* C58* C59* C60* C61* C62* D1* D2* D3* D4* D5* D6* D7* D8* D9* D10* D11* D12* D13* D14* D15* D16* D17* D18* D19* D20* D21* D22* D23* D24* D25* D26* D27* D28* D29* D30* D31* D32* D33* D34* D35* D36* D37* D38* D39* D40* D41* D42* D43* D44* D45* D46* D47* D48* D49* D50* D51* D52* D53* D54* D55* D56* D57* D58* D59* D60* D61* E1* E2* E3* E4* E5* E6* E7* E8* E9* E10* E11* E12* E13* E14* E15* E16* E17* E18* E19* E20* E21* E22* E23* E24* E25* E26* E27* E28* E29* E30* E31* E32* E33* E34* E35* E36* E37* E38* E39* E40* E41* E42* E43* E44* E45* E46* E47* E48* E49* E50* E51* E52* E53* E54* E55* E56* E57* E58* E59* E60* E61* E62* F1* F2* F3* F4* F5* F6* F7* F8* F9* F10* F11* F12* F13* F14* F15* F16* F17* F18* F19* F20* F21* F22* F23* F24* F25* F26* F27* F28* F29* F30* F31* F32* F33* F34* F35* F36* F37* F38* F39* F40* F41* F42* F43* F44* F45* F46* F47* F48* F49* F50* F51* F52* F53* F54* F55* F56* F57* F58* F59* F60* F61* F62* G2* G4* G6* G8* G10* G12* G14* G16* G18* G20* G22* G24* G26* G28* G30* G32* G34* G36* G38* G40* G42* G44* G46* G48* G50* G52* G54* G56* G58* G60* GH1* GH2* Z5* Z7* Z9* Z11* Z13* Z15* Z17* Z19* Z21* Z23* Z25* Z27* Z29* Z31* Z33* Z35* Z37* Z39* Z41* Z43* Z45* Z47* Z49* Z51* Z53* Z55* Z57* Z59* Z61*; SLOT04 A1* A2* A3* A4* A5* A6* A7* A8* A9* A10* A11* A12* A13* A14* A15* A16* A17* A18* A19* A20* A21* A22* A23* A24* A25* A26* A27* A28* A29* A30* A31* A32* A33* A34* A35* A36* A37* A38* A39* A40* A41* A42* A43* A44* A45* A46* A47* A48* A49* A50* A51* A52* A53* A54* A55* A56* A57* A58* A59* A60* A61* B1* B2* B3* B4* B5* B6* B7* B8* B9* B10* B11* B12* B13* B14* B15* B16* B17* B18* B19* B20* B21* B22* B23* B24* B25* B26* B27* B28* B29* B30* B31* B32* B33* B34* B35* B36* B37* B38* B39* B40* B41* B42* B43* B44* B45* B46* B47* B48* B49* B50* B51* B52* B53* B54* B55* B56* B57* B58* B59* B60* B61* B62* C1* C2* C3* C4* C5* C6* C7* C8* C9* C10* C11* C12* C13* C14* C15* C16* C17* C18* C19* C20* C21* C22* C23* C24* C25* C26* C27* C28* C29* C30* C31* C32* C33* C34* C35* C36* C37* C38* C39* C40* C41* C42* C43* C44* C45* C46* C47* C48* C49* C50* C51* C52* C53* C54* C55* C56* C57* C58* C59* C60* C61* C62* D1* D2* D3* D4* D5* D6* D7* D8* D9* D10* D11* D12* D13* D14* D15* D16* D17* D18* D19* D20* D21* D22* D23* D24* D25* D26* D27* D28* D29* D30* D31* D32* D33* D34* D35* D36* D37* D38* D39* D40* D41* D42* D43* D44* D45* D46* D47* D48* D49* D50* D51* D52* D53* D54* D55* D56* D57* D58* D59* D60* D61* E1* E2* E3* E4* E5* E6* E7* E8* E9* E10* E11* E12* E13* E14* E15* E16* E17* E18* E19* E20* E21* E22* E23* E24* E25* E26* E27* E28* E29* E30* E31* E32* E33* E34* E35* E36* E37* E38* E39* E40* E41* E42* E43* E44* E45* E46* E47* E48* E49* E50* E51* E52* E53* E54* E55* E56* E57* E58* E59* E60* E61* E62* F1* F2* F3* F4* F5* F6* F7* F8* F9* F10* F11* F12* F13* F14* F15* F16* F17* F18* F19* F20* F21* F22* F23* F24* F25* F26* F27* F28* F29* F30* F31* F32* F33* F34* F35* F36* F37* F38* F39* F40* F41* F42* F43* F44* F45* F46* F47* F48* F49* F50* F51* F52* F53* F54* F55* F56* F57* F58* F59* F60* F61* F62* G2* G4* G6* G8* G10* G12* G14* G16* G18* G20* G22* G24* G26* G28* G30* G32* G34* G36* G38* G40* G42* G44* G46* G48* G50* G52* G54* G56* G58* G60* GH1* GH2* Z5* Z7* Z9* Z11* Z13* Z15* Z17* Z19* Z21* Z23* Z25* Z27* Z29* Z31* Z33* Z35* Z37* Z39* Z41* Z43* Z45* Z47* Z49* Z51* Z53* Z55* Z57* Z59* Z61*; SLOT05 B6* D6* D23* D27* D31* D35* E4* GH1* GH2* Z5* Z7* Z9* Z11* Z13* Z15* Z17* Z19* Z21* Z23* Z25* Z27* Z29* Z31* Z33* Z35* Z37* Z39* Z41* Z43* Z45* Z47* Z49* Z51* Z53* Z55* Z57* Z59* Z61*; SLOT06 A1* A2* A3* A4* A19* A61* B1* B2* B3* B4* B61* B62* C1* C2* C3* C4* C62* D1* D2* D3* D4* D19* E1* E2* E3* E4* E19* E62* F1* F2* F3* F4* F62* G2* G4* G6* G8* G10* G12* G14* G16* G18* G20* G22* G24* G26* G28* G30* G32* G34* G36* G38* G40* G42* G44* G46* G48* G50* G52* G54* G56* G58* G60* GH1* GH2* Z17* Z19* Z37* Z51* Z61*; SLOT07 A1* A2* A3* A4* A5* A6* A7* A8* A9* A10* A11* A12* A13* A14* A15* A16* A17* A18* A19* A20* A21* A22* A23* A24* A25* A26* A27* A28* A29* A30* A31* A32* A33* A34* A35* A36* A37* A38* A39* A40* A41* A42* A43* A44* A45* A46* A47* A48* A49* A50* A51* A52* A53* A54* A55* A56* A57* A58* A59* A60* A61* B1* B2* B3* B4* B5* B6* B7* B8* B9* B10* B11* B12* B13* B14* B15* B16* B17* B18* B19* B20* B21* B22* B23* B24* B25* B26* B27* B28* B29* B30* B31* B32* B33* B34* B35* B36* B37* B38* B39* B40* B41* B42* B43* B44* B45* B46* B47* B48* B49* B50* B51* B52* B53* B54* B55* B56* B57* B58* B59* B60* B61* B62* C1* C2* C3* C4* C5* C6* C7* C8* C9* C10* C11* C12* C13* C14* C15* C16* C17* C18* C19* C20* C21* C22* C23* C24* C25* C26* C27* C28* C29* C30* C31* C32* C33* C34* C35* C36* C37* C38* C39* C40* C41* C42* C43* C44* C45* C46* C47* C48* C49* C50* C51* C52* C53* C54* C55* C56* C57* C58* C59* C60* C61* C62* D1* D2* D3* D4* D5* D6* D7* D8* D9* D10* D11* D12* D13* D14* D15* D16* D17* D18* D19* D20* D21* D22* D23* D24* D25* D26* D27* D28* D29* D30* D31* D32* D33* D34* D35* D36* D37* D38* D39* D40* D41* D42* D43* D44* D45* D46* D47* D48* D49* D50* D51* D52* D53* D54* D55* D56* D57* D58* D59* D60* D61* E1* E2* E3* E4* E5* E6* E7* E8* E9* E10* E11* E12* E13* E14* E15* E16* E17* E18* E19* E20* E21* E22* E23* E24* E25* E26* E27* E28* E29* E30* E31* E32* E33* E34* E35* E36* E37* E38* E39* E40* E41* E42* E43* E44* E45* E46* E47* E48* E49* E50* E51* E52* E53* E54* E55* E56* E57* E58* E59* E60* E61* E62* F1* F2* F3* F4* F5* F6* F7* F8* F9* F10* F11* F12* F13* F14* F15* F16* F17* F18* F19* F20* F21* F22* F23* F24* F25* F26* F27* F28* F29* F30* F31* F32* F33* F34* F35* F36* F37* F38* F39* F40* F41* F42* F43* F44* F45* F46* F47* F48* F49* F50* F51* F52* F53* F54* F55* F56* F57* F58* F59* F60* F61* F62* G2* G4* G6* G8* G10* G12* G14* G16* G18* G20* G22* G24* G26* G28* G30* G32* G34* G36* G38* G40* G42* G44* G46* G48* G50* G52* G54* G56* G58* G60* GH1* GH2* Z5* Z7* Z9* Z11* Z13* Z15* Z17* Z19* Z21* Z23* Z25* Z27* Z29* Z31* Z33* Z35* Z37* Z39* Z41* Z43* Z45* Z47* Z49* Z51* Z53* Z55* Z57* Z59* Z61*; SLOT08 A1* A2* A3* A4* A5* A6* A7* A8* A9* A10* A11* A12* A13* A14* A15* A16* A17* A18* A19* A20* A21* A22* A23* A24* A25* A26* A27* A28* A29* A30* A31* A32* A33* A34* A35* A36* A37* A38* A39* A40* A41* A42* A43* A44* A45* A46* A47* A48* A49* A50* A51* A52* A53* A54* A55* A56* A57* A58* A59* A60* A61* B1* B2* B3* B4* B5* B6* B7* B8* B9* B10* B11* B12* B13* B14* B15* B16* B17* B18* B19* B20* B21* B22* B23* B24* B25* B26* B27* B28* B29* B30* B31* B32* B33* B34* B35* B36* B37* B38* B39* B40* B41* B42* B43* B44* B45* B46* B47* B48* B49* B50* B51* B52* B53* B54* B55* B56* B57* B58* B59* B60* B61* B62* C1* C2* C3* C4* C5* C6* C7* C8* C9* C10* C11* C12* C13* C14* C15* C16* C17* C18* C19* C20* C21* C22* C23* C24* C25* C26* C27* C28* C29* C30* C31* C32* C33* C34* C35* C36* C37* C38* C39* C40* C41* C42* C43* C44* C45* C46* C47* C48* C49* C50* C51* C52* C53* C54* C55* C56* C57* C58* C59* C60* C61* C62* D1* D2* D3* D4* D5* D6* D7* D8* D9* D10* D11* D12* D13* D14* D15* D16* D17* D18* D19* D20* D21* D22* D23* D24* D25* D26* D27* D28* D29* D30* D31* D32* D33* D34* D35* D36* D37* D38* D39* D40* D41* D42* D43* D44* D45* D46* D47* D48* D49* D50* D51* D52* D53* D54* D55* D56* D57* D58* D59* D60* D61* E1* E2* E3* E4* E5* E6* E7* E8* E9* E10* E11* E12* E13* E14* E15* E16* E17* E18* E19* E20* E21* E22* E23* E24* E25* E26* E27* E28* E29* E30* E31* E32* E33* E34* E35* E36* E37* E38* E39* E40* E41* E42* E43* E44* E45* E46* E47* E48* E49* E50* E51* E52* E53* E54* E55* E56* E57* E58* E59* E60* E61* E62* F1* F2* F3* F4* F5* F6* F7* F8* F9* F10* F11* F12* F13* F14* F15* F16* F17* F18* F19* F20* F21* F22* F23* F24* F25* F26* F27* F28* F29* F30* F31* F32* F33* F34* F35* F36* F37* F38* F39* F40* F41* F42* F43* F44* F45* F46* F47* F48* F49* F50* F51* F52* F53* F54* F55* F56* F57* F58* F59* F60* F61* F62* G2* G4* G6* G8* G10* G12* G14* G16* G18* G20* G22* G24* G26* G28* G30* G32* G34* G36* G38* G40* G42* G44* G46* G48* G50* G52* G54* G56* G58* G60* GH1* GH2* Z5* Z7* Z9* Z11* Z13* Z15* Z17* Z19* Z21* Z23* Z25* Z27* Z29* Z31* Z33* Z35* Z37* Z39* Z41* Z43* Z45* Z47* Z49* Z51* Z53* Z55* Z57* Z59* Z61*; SLOT09 A10(MOD_IN_15_26)* G10(MOD_IN_37_48)* NGH1* NGH2* Z5(NC1)* Z7(NC2)* Z9(NC3)* Z11(NC4)* Z13(NC5)* Z15(NC6)* Z17(NC7)* Z19(NC8)* Z21(NC9)* Z23(NC10)* Z25(NC11)* Z27(NC12)* Z29(NC13)* Z31(NC14)* Z33(NC15)* Z35(NC16)* Z37(NC17)* Z39(NC18)* Z41(NC19)* Z43(NC20)* Z45(NC21)* Z47(NC22)* Z49(NC23)* Z51(NC24)* Z53(NC25)* Z55(NC26)* Z57(NC27)* Z59(NC28)* Z61(NC29)*

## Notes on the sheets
sheet 12
- FPVI
sheet 13
- EMPTY
sheet 14
- EMPTY
sheet 15
- GX1x
sheet 16
- PMVIx
sheet 17
- EMPTY
sheet 18
- EMPTY
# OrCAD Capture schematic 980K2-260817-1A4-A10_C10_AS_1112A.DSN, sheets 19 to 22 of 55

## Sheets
19 T02.SLOT02_VI100: size A2
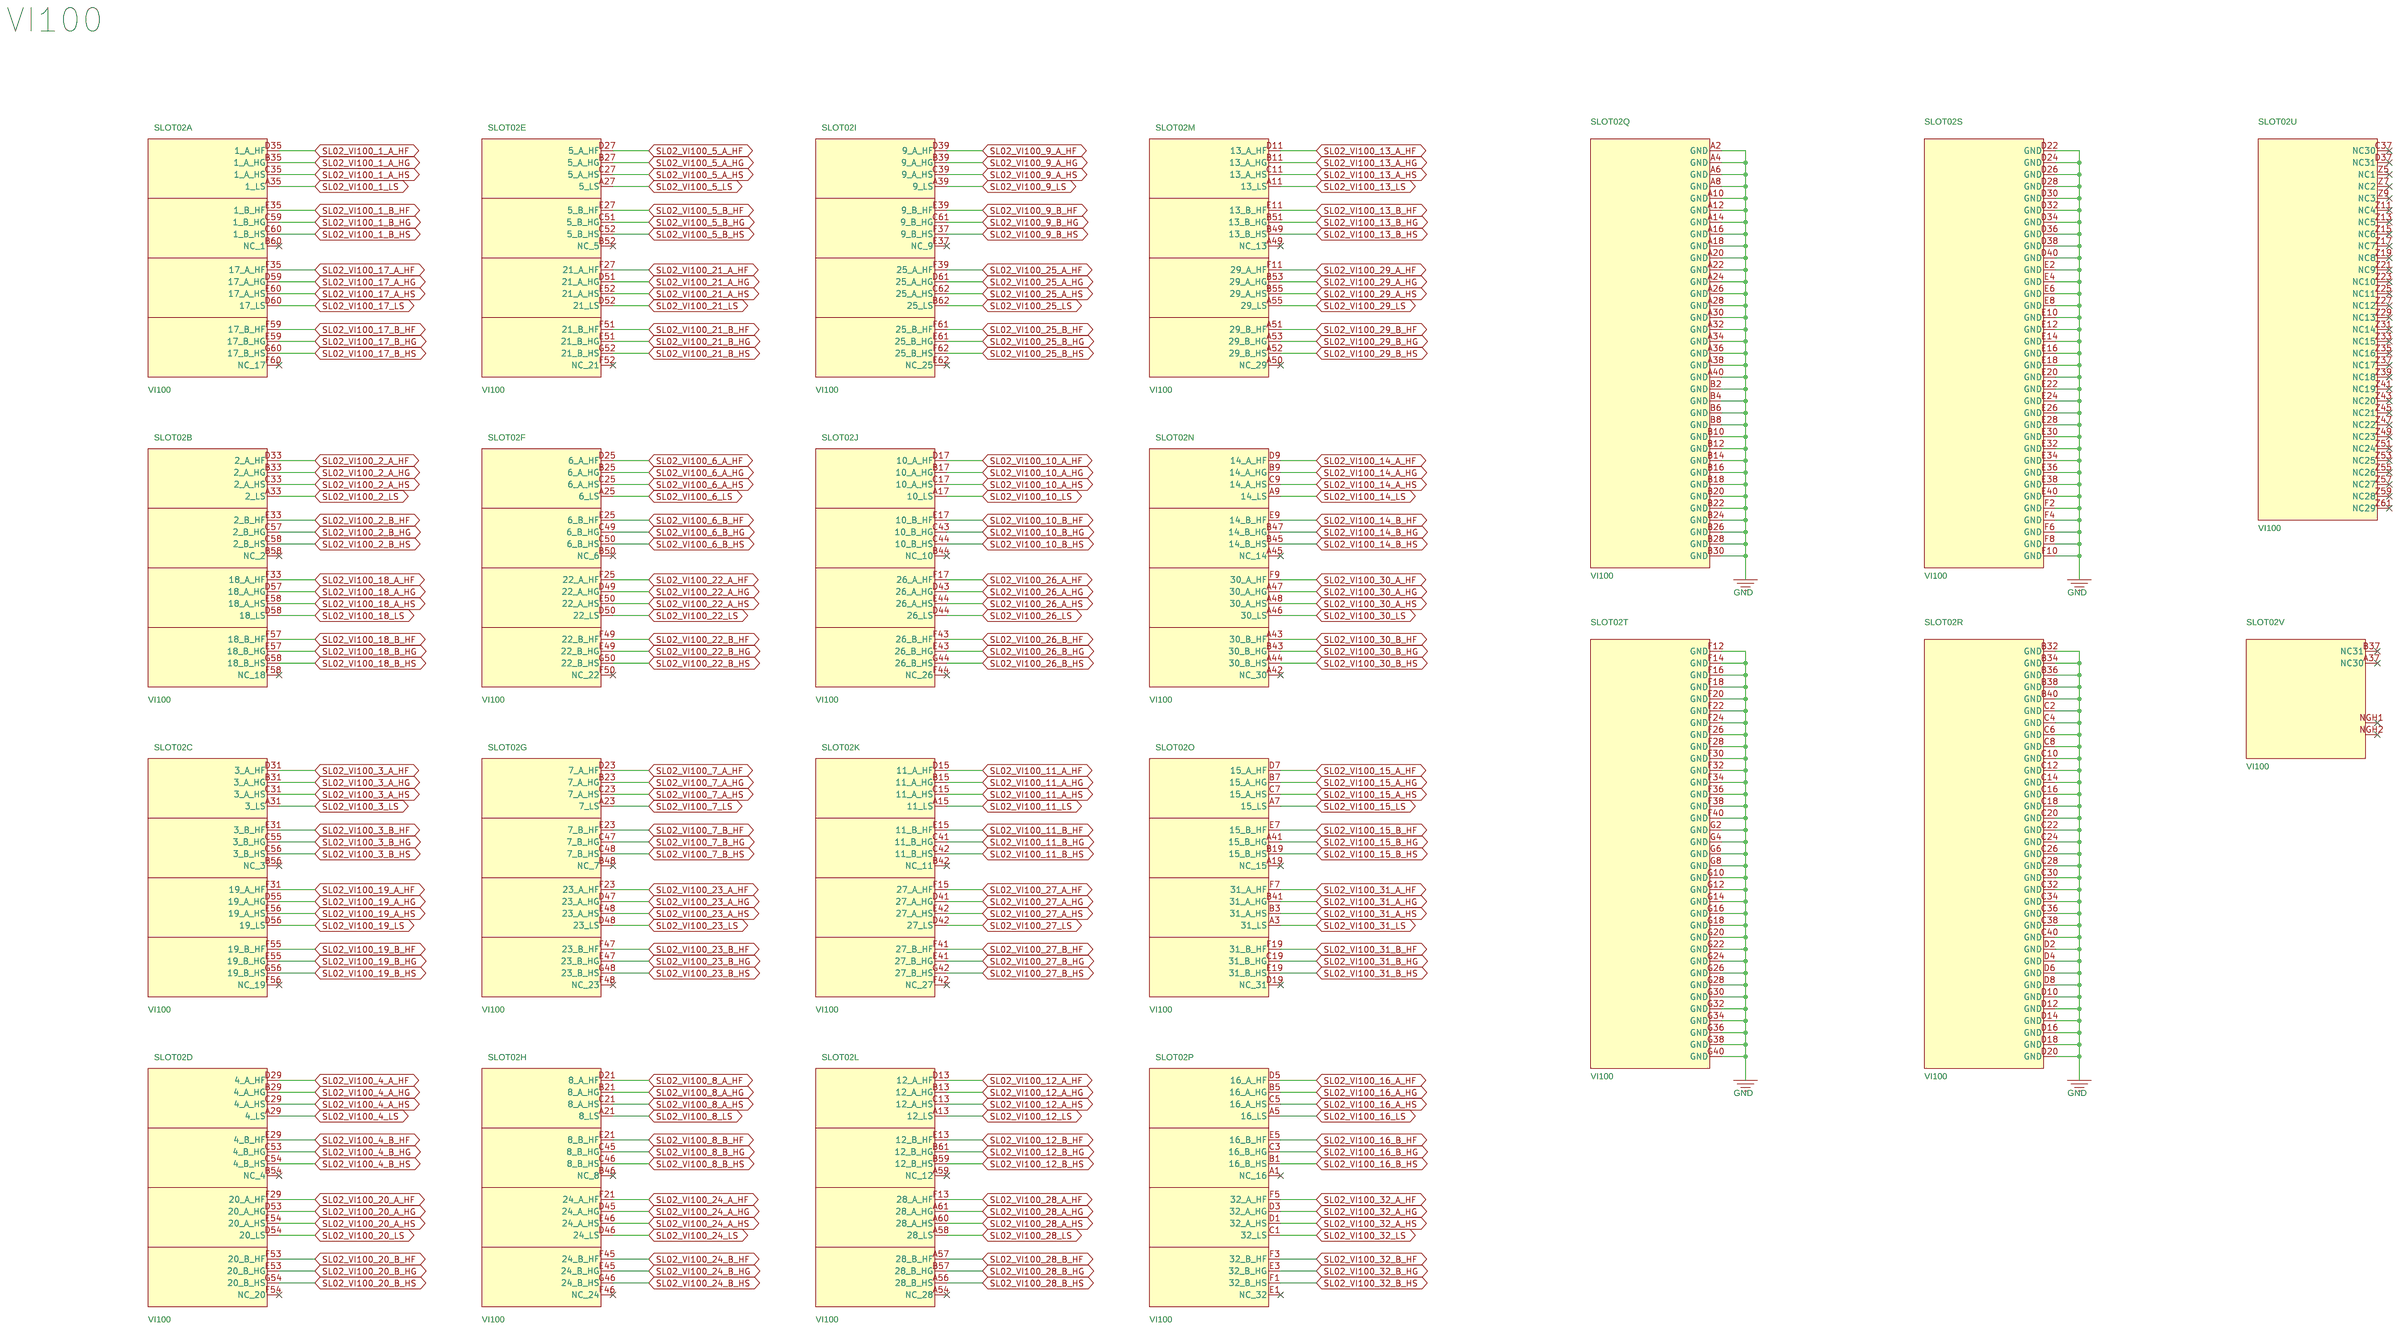
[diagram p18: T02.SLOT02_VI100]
20 T01.SLOT01_VI100: size A2
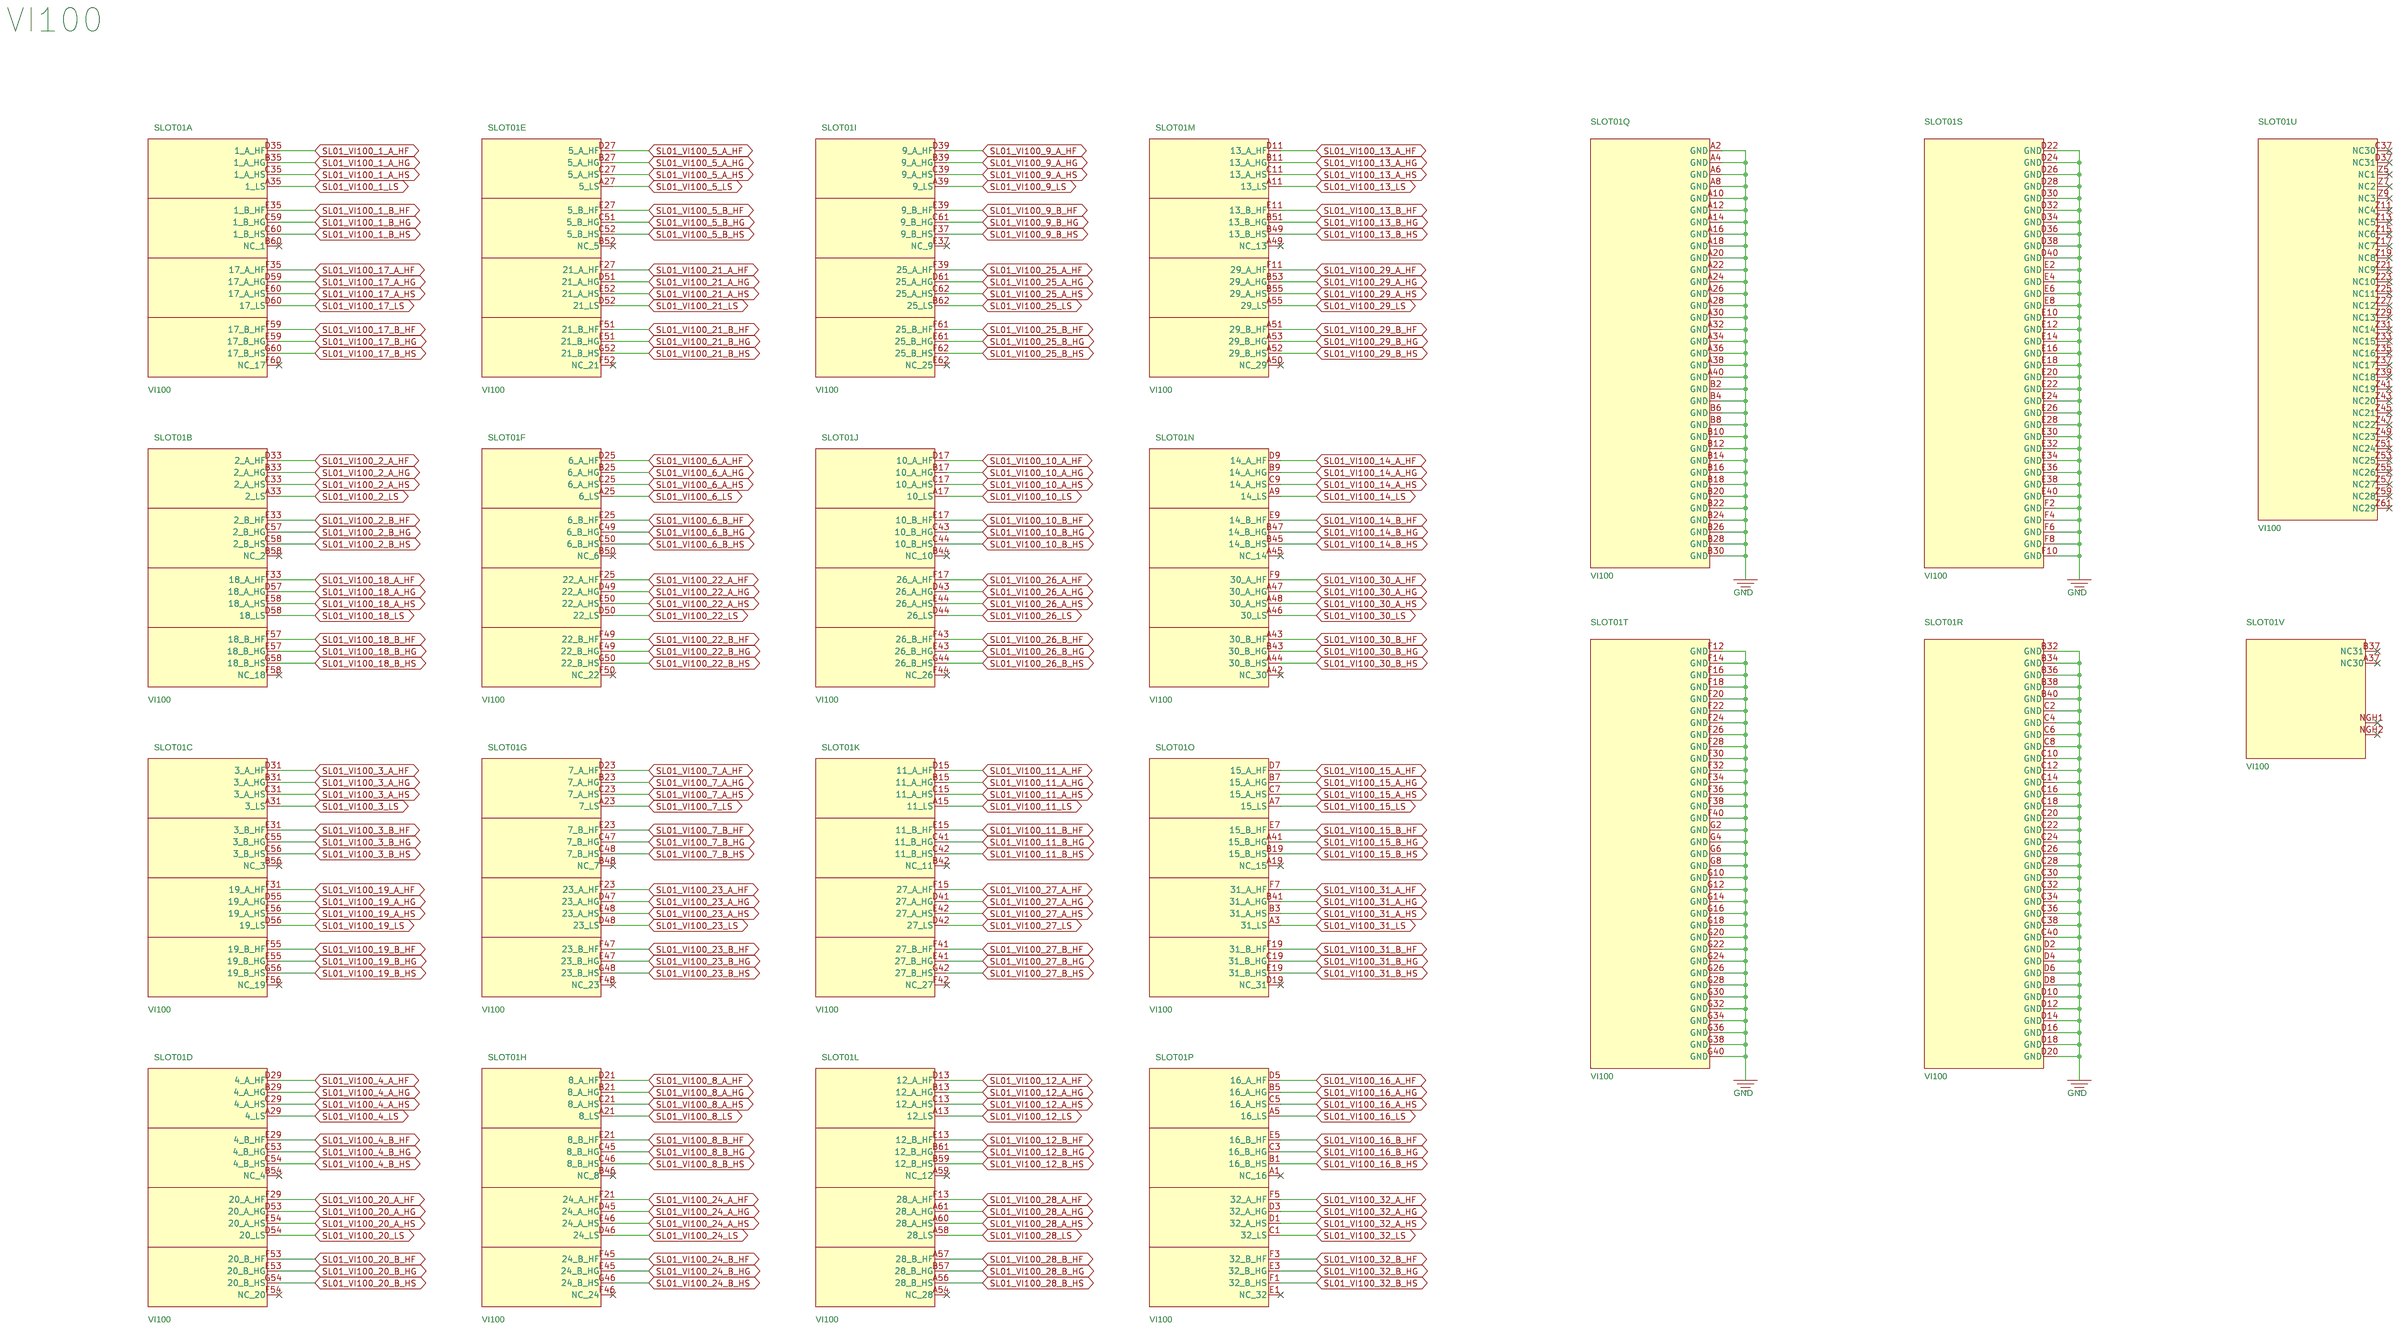
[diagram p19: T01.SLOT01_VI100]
21 T00.SLOT0_SDU: size A2
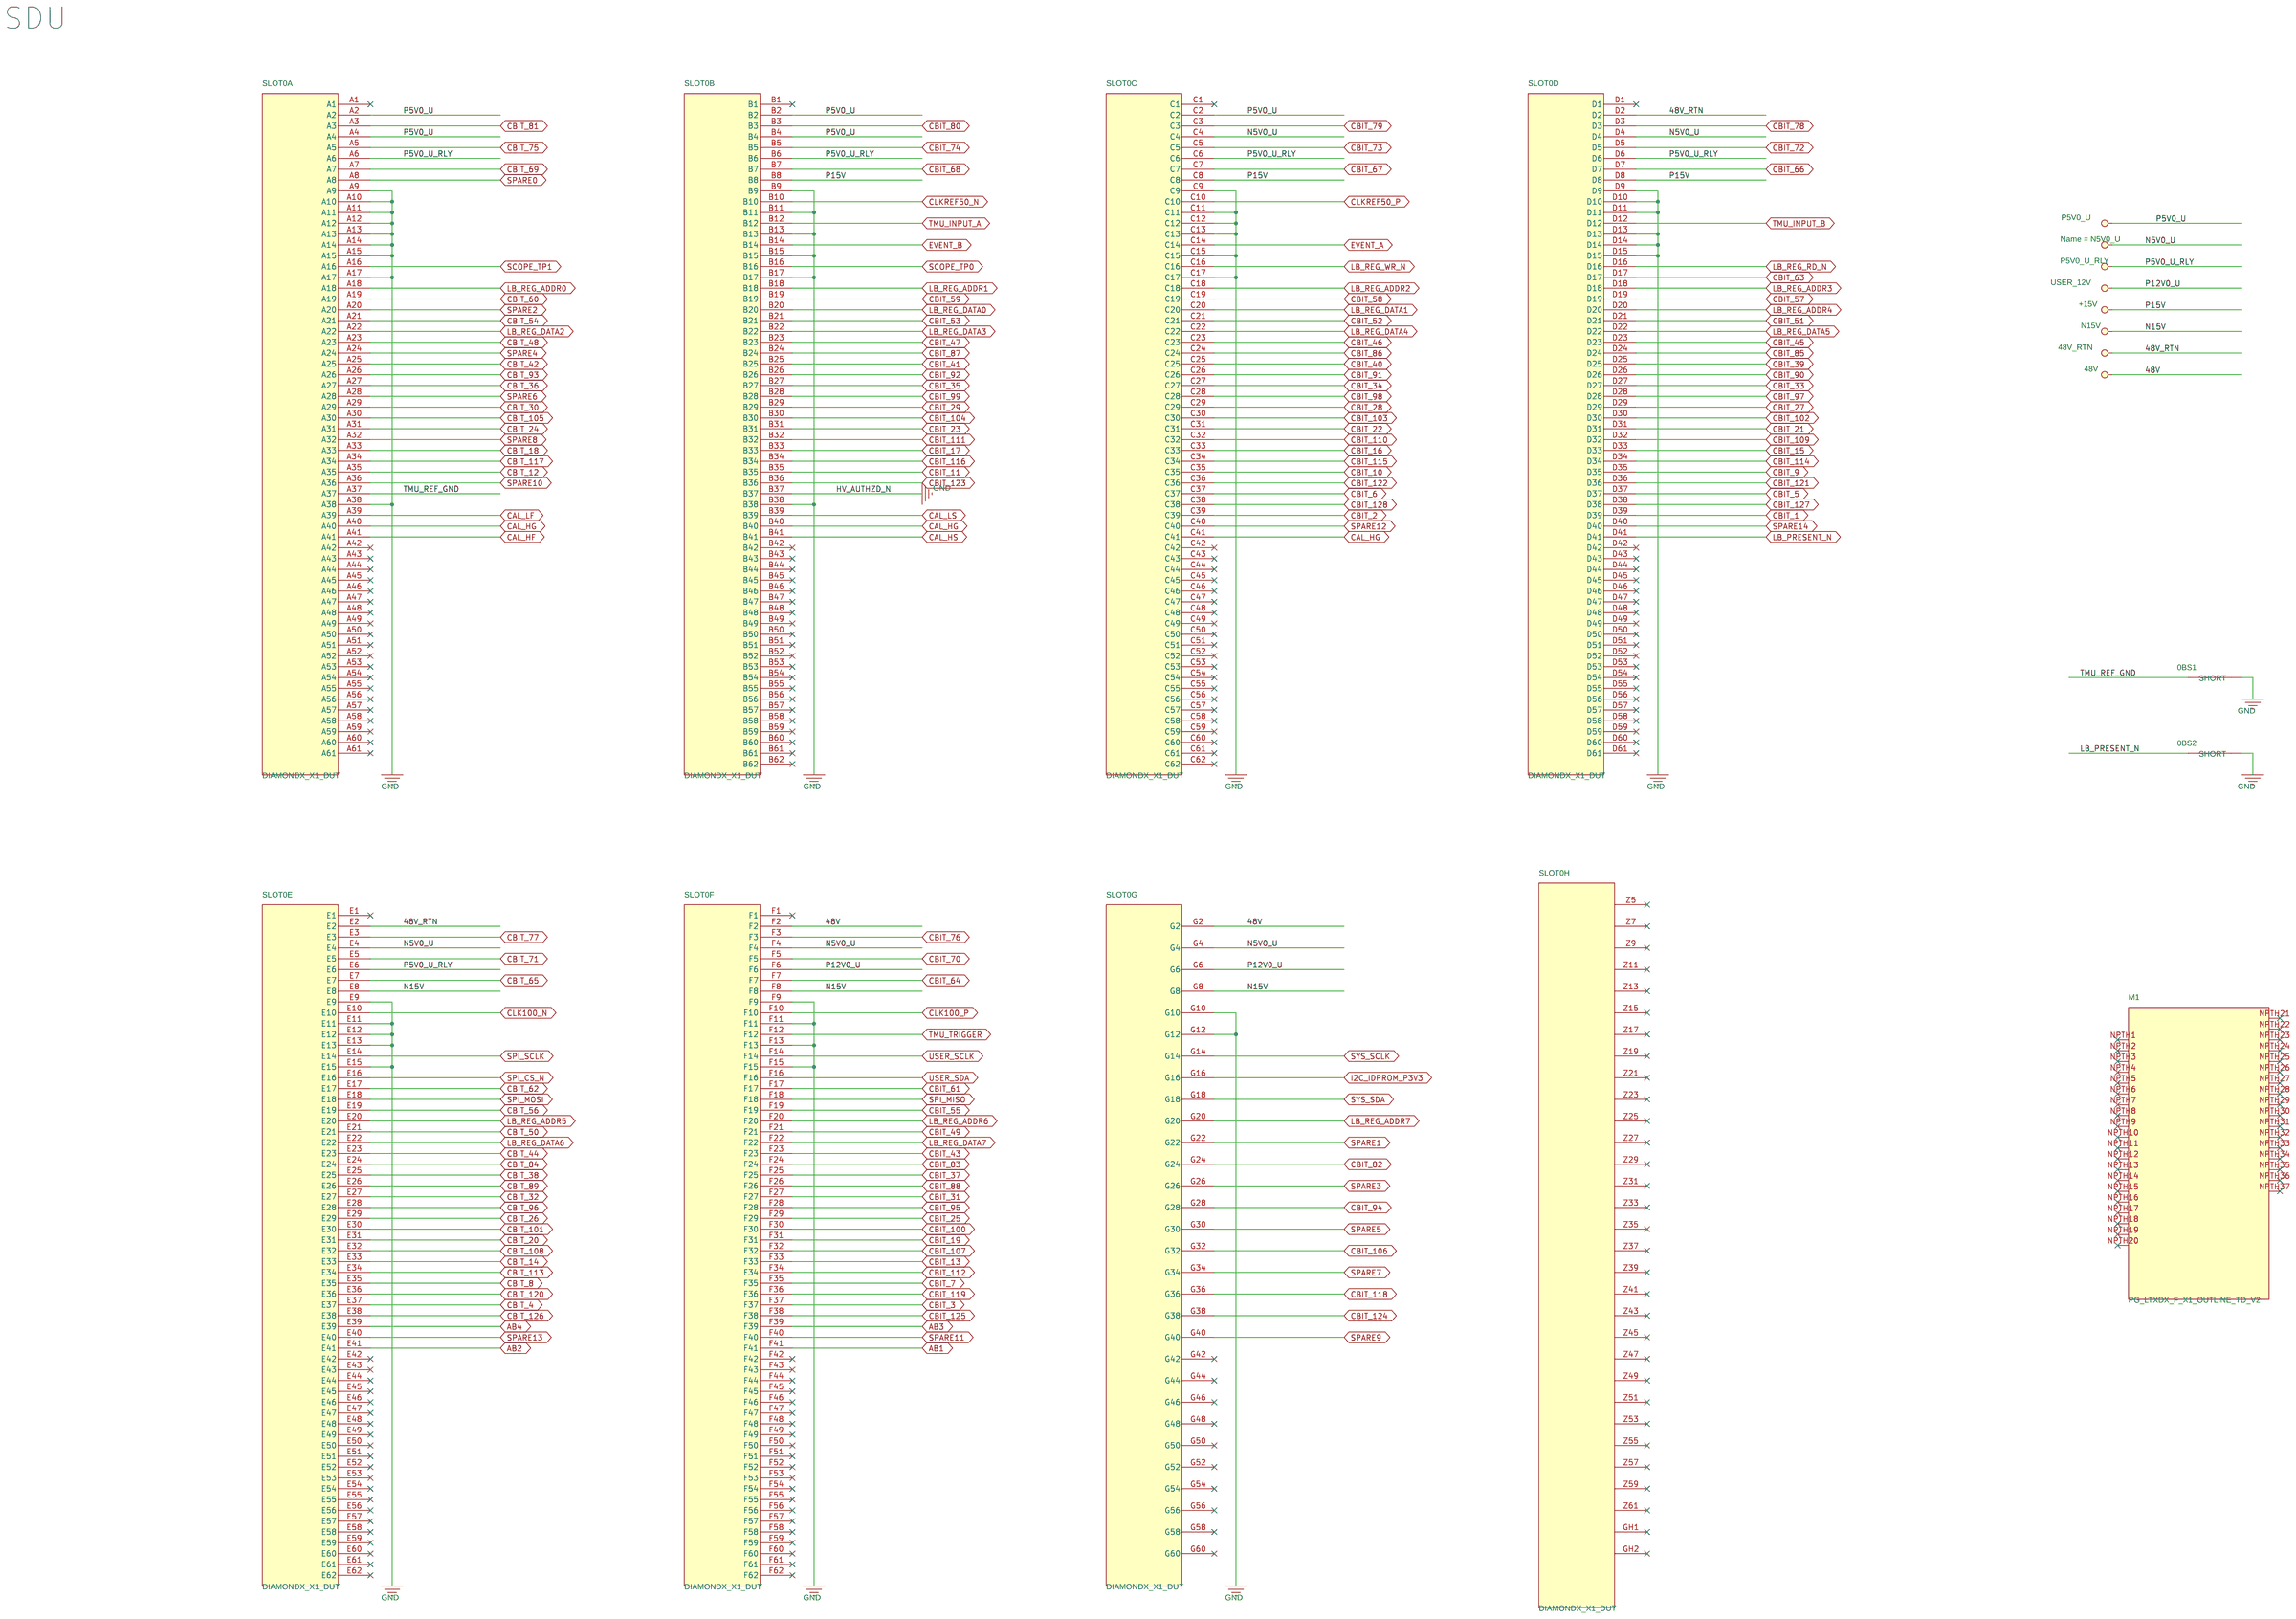
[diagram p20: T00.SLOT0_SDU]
22 S9999_MISC: size A3

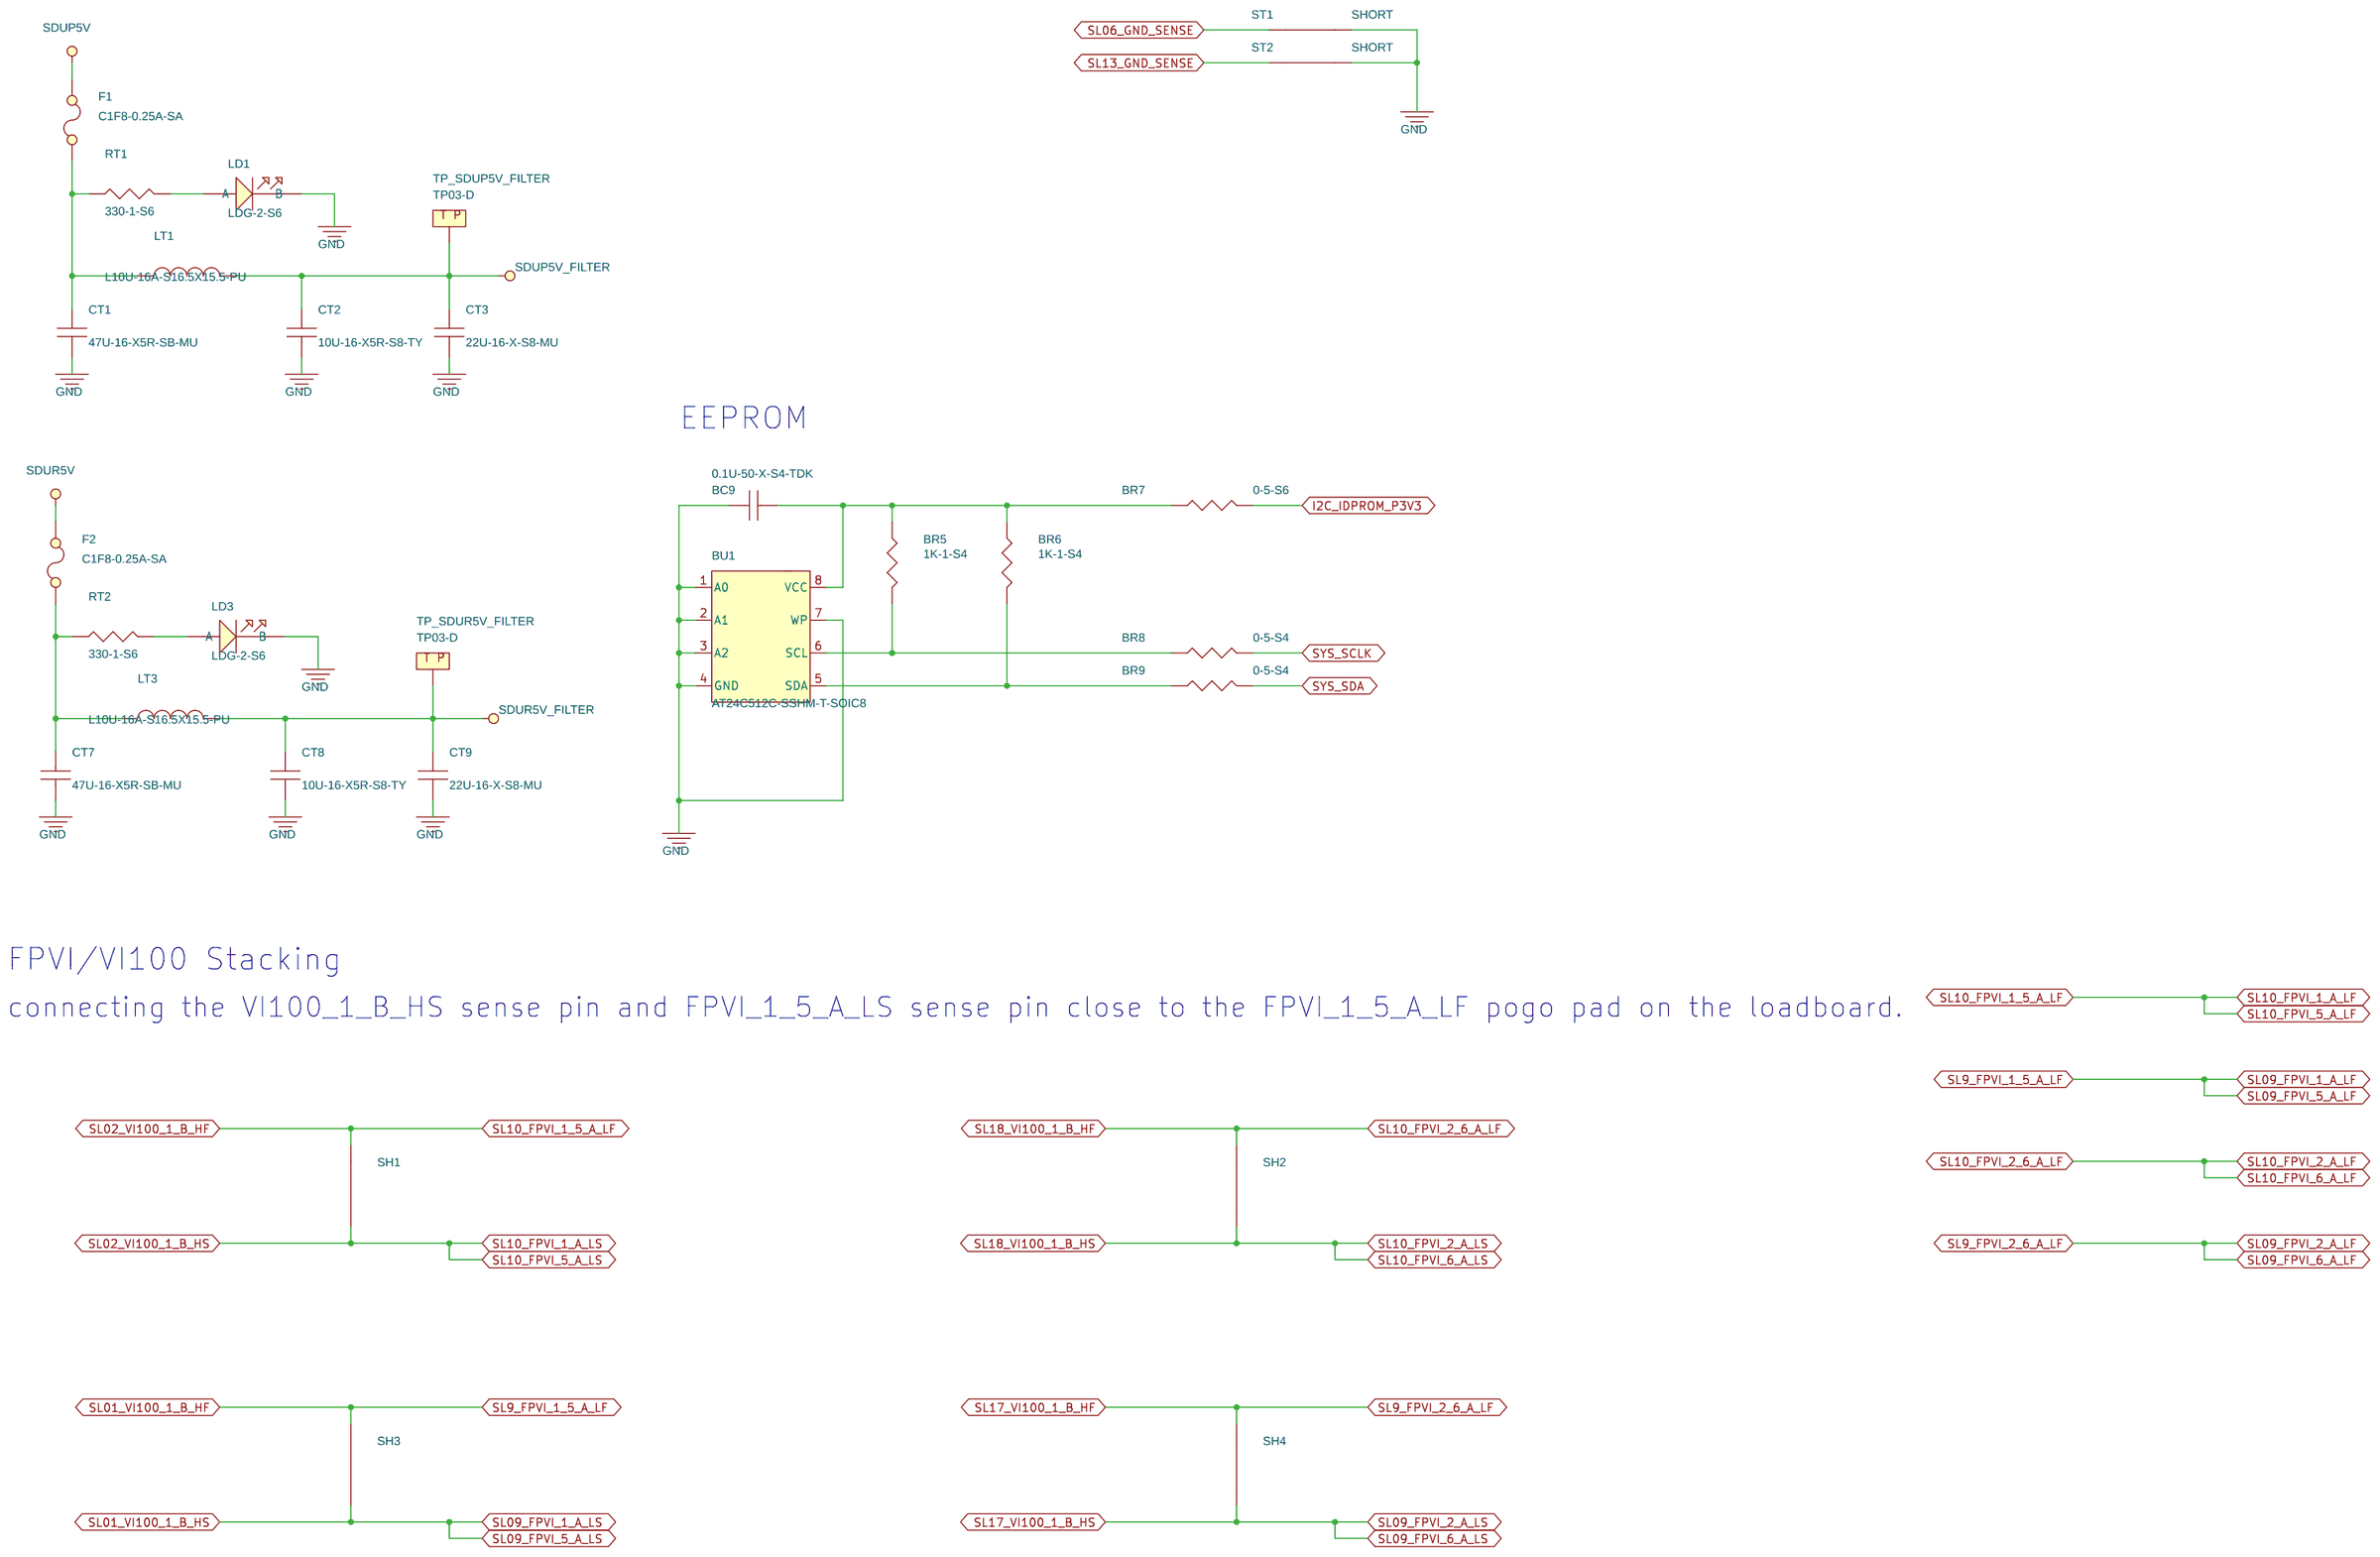
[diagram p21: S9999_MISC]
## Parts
sheet S9999_MISC
BC9  0.1U-50-X-S4-TDK  [C0402]
BR5  1K-1-S4  [R0402]
BR6  1K-1-S4  [R0402]
BR7  0-5-S6  [R0603]
BR8  0-5-S4  [R0402]
BR9  0-5-S4  [R0402]
BU1  AT24C512C-SSHM-T-SOIC8  [SO8_206X127MM]
CT1  47U-16-X5R-SB-MU  [C1210]
CT2  10U-16-X5R-S8-TY  [C0805]
CT3  22U-16-X-S8-MU  [C0805]
CT7  47U-16-X5R-SB-MU  [C1210]
CT8  10U-16-X5R-S8-TY  [C0805]
CT9  22U-16-X-S8-MU  [C0805]
F1  C1F8-0.25A-SA  [FUSE_1206_H1P05MM]
F2  C1F8-0.25A-SA  [FUSE_1206_H1P05MM]
LD1  LDG-2-S6  [LED_0603]
LD3  LDG-2-S6  [LED_0603]
LT1  L10U-16A-S16.5X15.5-PU  [IND_16P5X15P5MM]
LT3  L10U-16A-S16.5X15.5-PU  [IND_16P5X15P5MM]
RT1  330-1-S6  [R0603]
RT2  330-1-S6  [R0603]
SH1  SHORT  [DEFAULT_SHORT_SMALL]
SH2  SHORT  [DEFAULT_SHORT_SMALL]
SH3  SHORT  [DEFAULT_SHORT_SMALL]
SH4  SHORT  [DEFAULT_SHORT_SMALL]
ST1  SHORT  [DEFAULT_SHORT_SMALL]
ST2  SHORT  [DEFAULT_SHORT_SMALL]
TP_SDUP5V_FILTER  TP03-D  [TP_060_040]
TP_SDUR5V_FILTER  TP03-D  [TP_060_040]
sheet T00.SLOT0_SDU
0BS1  SHORT  [DEFAULT_SHORT_SMALL]
0BS2  SHORT  [DEFAULT_SHORT_SMALL]
M1  PG_LTXDX_F_X1_OUTLINE_TD_V2  [PG_LTXDX_F_X1_OUTLINE_TD_COHU]
SLOT0  DIAMONDX_X1_DUT  [PG_LTXDX_F_X1_SDU_SL00_V3]  (sections A,B,C,D,E,F,G,H)
sheet T01.SLOT01_VI100
SLOT01  VI100  [PG_LTXDX_F_X1_VI100_SL01_V3]  (sections A,B,C,D,E,F,G,H,I,J,K,L,M,N,O,P,Q,R,S,T,U,V)
sheet T02.SLOT02_VI100
SLOT02  VI100  [PG_LTXDX_F_X1_VI100_SL02_V3]  (sections A,B,C,D,E,F,G,H,I,J,K,L,M,N,O,P,Q,R,S,T,U,V)

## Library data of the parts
BC9 = 0.1U-50-X-S4-TDK
BR5 BR6 = 1K-1-S4
BR7 = 0-5-S6
BR8 BR9 = 0-5-S4
BU1 = AT24C512C-SSHM-T-SOIC8
CT1 CT7 = 47U-16-X5R-SB-MU
CT2 CT8 = 10U-16-X5R-S8-TY
CT3 CT9 = 22U-16-X-S8-MU
F1 F2 = C1F8-0.25A-SA
LD1 LD3 = LDG-2-S6
LT1 LT3 = L10U-16A-S16.5X15.5-PU
RT1 RT2 = 330-1-S6
0BS1 0BS2 SH1 ST1 ST2 = SHORT
SH2-SH4 = SHORT: KAIROSNAME: SH1
TP_SDUP5V_FILTER TP_SDUR5V_FILTER = TP03-D
M1 = PG_LTXDX_F_X1_OUTLINE_6042
SLOT0 = DIAMONDX_X1_DUT_1: KAIROSNAME: SLOT0A
SLOT01 SLOT02 = VI100_SL01

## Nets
48V: SLOT0.F2 SLOT0.G2
48V_RTN: SLOT0.D2 SLOT0.E2
+15V: SLOT0.B8 SLOT0.C8 SLOT0.D8
-15V: SLOT0.E8 SLOT0.F8 SLOT0.G8
GND: 0BS1.2 0BS2.2 BC9.2 BU1.1(A0) BU1.2(A1) BU1.3(A2) BU1.4(GND) BU1.7(WP) CT1.2 CT2.2 CT3.2 CT7.2 CT8.2 CT9.2 LD1.2(B) LD3.2(B) SLOT0.A9 SLOT0.A10 SLOT0.A11 SLOT0.A12 SLOT0.A13 SLOT0.A14 SLOT0.A15 SLOT0.A17 SLOT0.A38 SLOT0.B9 SLOT0.B11 SLOT0.B13 SLOT0.B15 SLOT0.B17 SLOT0.B37 SLOT0.B38 SLOT0.C9 SLOT0.C11 SLOT0.C12 SLOT0.C13 SLOT0.C15 SLOT0.C17 SLOT0.D9 SLOT0.D10 SLOT0.D11 SLOT0.D13 SLOT0.D14 SLOT0.D15 SLOT0.E9 SLOT0.E11 SLOT0.E12 SLOT0.E13 SLOT0.E15 SLOT0.F9 SLOT0.F11 SLOT0.F13 SLOT0.F15 SLOT0.G10 SLOT0.G12 SLOT01.A2(GND) SLOT01.A4(GND) SLOT01.A6(GND) SLOT01.A8(GND) SLOT01.A10(GND) SLOT01.A12(GND) SLOT01.A14(GND) SLOT01.A16(GND) SLOT01.A18(GND) SLOT01.A20(GND) SLOT01.A22(GND) SLOT01.A24(GND) SLOT01.A26(GND) SLOT01.A28(GND) SLOT01.A30(GND) SLOT01.A32(GND) SLOT01.A34(GND) SLOT01.A36(GND) SLOT01.A38(GND) SLOT01.A40(GND) SLOT01.B2(GND) SLOT01.B4(GND) SLOT01.B6(GND) SLOT01.B8(GND) SLOT01.B10(GND) SLOT01.B12(GND) SLOT01.B14(GND) SLOT01.B16(GND) SLOT01.B18(GND) SLOT01.B20(GND) SLOT01.B22(GND) SLOT01.B24(GND) SLOT01.B26(GND) SLOT01.B28(GND) SLOT01.B30(GND) SLOT01.B32(GND) SLOT01.B34(GND) SLOT01.B36(GND) SLOT01.B38(GND) SLOT01.B40(GND) SLOT01.C2(GND) SLOT01.C4(GND) SLOT01.C6(GND) SLOT01.C8(GND) SLOT01.C10(GND) SLOT01.C12(GND) SLOT01.C14(GND) SLOT01.C16(GND) SLOT01.C18(GND) SLOT01.C20(GND) SLOT01.C22(GND) SLOT01.C24(GND) SLOT01.C26(GND) SLOT01.C28(GND) SLOT01.C30(GND) SLOT01.C32(GND) SLOT01.C34(GND) SLOT01.C36(GND) SLOT01.C38(GND) SLOT01.C40(GND) SLOT01.D2(GND) SLOT01.D4(GND) SLOT01.D6(GND) SLOT01.D8(GND) SLOT01.D10(GND) SLOT01.D12(GND) SLOT01.D14(GND) SLOT01.D16(GND) SLOT01.D18(GND) SLOT01.D20(GND) SLOT01.D22(GND) SLOT01.D24(GND) SLOT01.D26(GND) SLOT01.D28(GND) SLOT01.D30(GND) SLOT01.D32(GND) SLOT01.D34(GND) SLOT01.D36(GND) SLOT01.D38(GND) SLOT01.D40(GND) SLOT01.E2(GND) SLOT01.E4(GND) SLOT01.E6(GND) SLOT01.E8(GND) SLOT01.E10(GND) SLOT01.E12(GND) SLOT01.E14(GND) SLOT01.E16(GND) SLOT01.E18(GND) SLOT01.E20(GND) SLOT01.E22(GND) SLOT01.E24(GND) SLOT01.E26(GND) SLOT01.E28(GND) SLOT01.E30(GND) SLOT01.E32(GND) SLOT01.E34(GND) SLOT01.E36(GND) SLOT01.E38(GND) SLOT01.E40(GND) SLOT01.F2(GND) SLOT01.F4(GND) SLOT01.F6(GND) SLOT01.F8(GND) SLOT01.F10(GND) SLOT01.F12(GND) SLOT01.F14(GND) SLOT01.F16(GND) SLOT01.F18(GND) SLOT01.F20(GND) SLOT01.F22(GND) SLOT01.F24(GND) SLOT01.F26(GND) SLOT01.F28(GND) SLOT01.F30(GND) SLOT01.F32(GND) SLOT01.F34(GND) SLOT01.F36(GND) SLOT01.F38(GND) SLOT01.F40(GND) SLOT01.G2(GND) SLOT01.G4(GND) SLOT01.G6(GND) SLOT01.G8(GND) SLOT01.G10(GND) SLOT01.G12(GND) SLOT01.G14(GND) SLOT01.G16(GND) SLOT01.G18(GND) SLOT01.G20(GND) SLOT01.G22(GND) SLOT01.G24(GND) SLOT01.G26(GND) SLOT01.G28(GND) SLOT01.G30(GND) SLOT01.G32(GND) SLOT01.G34(GND) SLOT01.G36(GND) SLOT01.G38(GND) SLOT01.G40(GND) SLOT02.A2(GND) SLOT02.A4(GND) SLOT02.A6(GND) SLOT02.A8(GND) SLOT02.A10(GND) SLOT02.A12(GND) SLOT02.A14(GND) SLOT02.A16(GND) SLOT02.A18(GND) SLOT02.A20(GND) SLOT02.A22(GND) SLOT02.A24(GND) SLOT02.A26(GND) SLOT02.A28(GND) SLOT02.A30(GND) SLOT02.A32(GND) SLOT02.A34(GND) SLOT02.A36(GND) SLOT02.A38(GND) SLOT02.A40(GND) SLOT02.B2(GND) SLOT02.B4(GND) SLOT02.B6(GND) SLOT02.B8(GND) SLOT02.B10(GND) SLOT02.B12(GND) SLOT02.B14(GND) SLOT02.B16(GND) SLOT02.B18(GND) SLOT02.B20(GND) SLOT02.B22(GND) SLOT02.B24(GND) SLOT02.B26(GND) SLOT02.B28(GND) SLOT02.B30(GND) SLOT02.B32(GND) SLOT02.B34(GND) SLOT02.B36(GND) SLOT02.B38(GND) SLOT02.B40(GND) SLOT02.C2(GND) SLOT02.C4(GND) SLOT02.C6(GND) SLOT02.C8(GND) SLOT02.C10(GND) SLOT02.C12(GND) SLOT02.C14(GND) SLOT02.C16(GND) SLOT02.C18(GND) SLOT02.C20(GND) SLOT02.C22(GND) SLOT02.C24(GND) SLOT02.C26(GND) SLOT02.C28(GND) SLOT02.C30(GND) SLOT02.C32(GND) SLOT02.C34(GND) SLOT02.C36(GND) SLOT02.C38(GND) SLOT02.C40(GND) SLOT02.D2(GND) SLOT02.D4(GND) SLOT02.D6(GND) SLOT02.D8(GND) SLOT02.D10(GND) SLOT02.D12(GND) SLOT02.D14(GND) SLOT02.D16(GND) SLOT02.D18(GND) SLOT02.D20(GND) SLOT02.D22(GND) SLOT02.D24(GND) SLOT02.D26(GND) SLOT02.D28(GND) SLOT02.D30(GND) SLOT02.D32(GND) SLOT02.D34(GND) SLOT02.D36(GND) SLOT02.D38(GND) SLOT02.D40(GND) SLOT02.E2(GND) SLOT02.E4(GND) SLOT02.E6(GND) SLOT02.E8(GND) SLOT02.E10(GND) SLOT02.E12(GND) SLOT02.E14(GND) SLOT02.E16(GND) SLOT02.E18(GND) SLOT02.E20(GND) SLOT02.E22(GND) SLOT02.E24(GND) SLOT02.E26(GND) SLOT02.E28(GND) SLOT02.E30(GND) SLOT02.E32(GND) SLOT02.E34(GND) SLOT02.E36(GND) SLOT02.E38(GND) SLOT02.E40(GND) SLOT02.F2(GND) SLOT02.F4(GND) SLOT02.F6(GND) SLOT02.F8(GND) SLOT02.F10(GND) SLOT02.F12(GND) SLOT02.F14(GND) SLOT02.F16(GND) SLOT02.F18(GND) SLOT02.F20(GND) SLOT02.F22(GND) SLOT02.F24(GND) SLOT02.F26(GND) SLOT02.F28(GND) SLOT02.F30(GND) SLOT02.F32(GND) SLOT02.F34(GND) SLOT02.F36(GND) SLOT02.F38(GND) SLOT02.F40(GND) SLOT02.G2(GND) SLOT02.G4(GND) SLOT02.G6(GND) SLOT02.G8(GND) SLOT02.G10(GND) SLOT02.G12(GND) SLOT02.G14(GND) SLOT02.G16(GND) SLOT02.G18(GND) SLOT02.G20(GND) SLOT02.G22(GND) SLOT02.G24(GND) SLOT02.G26(GND) SLOT02.G28(GND) SLOT02.G30(GND) SLOT02.G32(GND) SLOT02.G34(GND) SLOT02.G36(GND) SLOT02.G38(GND) SLOT02.G40(GND) ST1.1 ST2.1 ; also on sheet 3 4 7 8 11 12 15 16 24 28 32 36 40 44 48 52
AB1: SLOT0.F41
AB2: SLOT0.E41
AB3: SLOT0.F39
AB4: SLOT0.E39
CAL_HF: SLOT0.A41
CAL_HG: SLOT0.A40 SLOT0.B40 SLOT0.C41
CAL_HS: SLOT0.B41
CAL_LF: SLOT0.A39
CAL_LS: SLOT0.B39
CBIT_1: SLOT0.D39 ; also on sheet 46 54
CBIT_2: SLOT0.C39 ; also on sheet 30 38 46 54
CBIT_3: SLOT0.F37 ; also on sheet 30 38 46 54
CBIT_4: SLOT0.E37 ; also on sheet 30 38 46 54
CBIT_5: SLOT0.D37 ; also on sheet 30 38 46 54
CBIT_6: SLOT0.C37 ; also on sheet 30 38 46 54
CBIT_7: SLOT0.F35 ; also on sheet 30 38 46 54
CBIT_8: SLOT0.E35 ; also on sheet 30 38 46 54
CBIT_9: SLOT0.D35 ; also on sheet 30 38 46 54
CBIT_10: SLOT0.C35 ; also on sheet 30 38 46 54
CBIT_11: SLOT0.B35 ; also on sheet 30 38 46 54
CBIT_12: SLOT0.A35 ; also on sheet 30 38 46 54
CBIT_13: SLOT0.F33 ; also on sheet 30 38 46 54
CBIT_14: SLOT0.E33 ; also on sheet 30 38 46 54
CBIT_15: SLOT0.D33 ; also on sheet 46 54
CBIT_16: SLOT0.C33 ; also on sheet 30 38 46 54
CBIT_17: SLOT0.B33 ; also on sheet 30 38 46 54
CBIT_18: SLOT0.A33 ; also on sheet 30 38 46 54
CBIT_19: SLOT0.F31 ; also on sheet 29 37 45 53
CBIT_20: SLOT0.E31 ; also on sheet 29 37 45 53
CBIT_21: SLOT0.D31 ; also on sheet 29 37 45 53
CBIT_22: SLOT0.C31 ; also on sheet 29 37 45 53
CBIT_23: SLOT0.B31 ; also on sheet 45 53
CBIT_24: SLOT0.A31 ; also on sheet 45 53
CBIT_25: SLOT0.F29 ; also on sheet 29 37 45 53
CBIT_26: SLOT0.E29 ; also on sheet 29 37 45 53
CBIT_27: SLOT0.D29 ; also on sheet 29 37 45 53
CBIT_28: SLOT0.C29 ; also on sheet 29 37 45 53
CBIT_29: SLOT0.B29 ; also on sheet 29 37 45 53
CBIT_30: SLOT0.A29 ; also on sheet 29 37 45 53
CBIT_31: SLOT0.F27 ; also on sheet 29 37 45 53
CBIT_32: SLOT0.E27 ; also on sheet 29 37 45 53
CBIT_33: SLOT0.D27 ; also on sheet 29 37 45 53
CBIT_34: SLOT0.C27 ; also on sheet 29 37 45 53
CBIT_35: SLOT0.B27 ; also on sheet 29 37 45 53
CBIT_36: SLOT0.A27 ; also on sheet 29 37 45 53
CBIT_37: SLOT0.F25 ; also on sheet 29 37 45 53
CBIT_38: SLOT0.E25 ; also on sheet 28 36 44 52
CBIT_39: SLOT0.D25 ; also on sheet 28 36 44 52
CBIT_40: SLOT0.C25 ; also on sheet 28 36 44 52
CBIT_41: SLOT0.B25 ; also on sheet 28 36 44 52
CBIT_42: SLOT0.A25 ; also on sheet 28 36 44 52
CBIT_43: SLOT0.F23 ; also on sheet 28 36 44 52
CBIT_44: SLOT0.E23 ; also on sheet 28 36 44 52
CBIT_45: SLOT0.D23 ; also on sheet 28 36 44 52
CBIT_46: SLOT0.C23 ; also on sheet 28 36 44 52
CBIT_47: SLOT0.B23 ; also on sheet 28 36 44 52
CBIT_48: SLOT0.A23 ; also on sheet 28 36 44 52
CBIT_49: SLOT0.F21 ; also on sheet 28 36 44 52
CBIT_50: SLOT0.E21 ; also on sheet 28 36 44 52
CBIT_51: SLOT0.D21 ; also on sheet 27 35 43 51
CBIT_52: SLOT0.C21 ; also on sheet 27 35 43 51
CBIT_53: SLOT0.B21 ; also on sheet 27 35 43 51
CBIT_54: SLOT0.A21 ; also on sheet 27 35 43 51
CBIT_55: SLOT0.F19 ; also on sheet 27 35 43 51
CBIT_56: SLOT0.E19 ; also on sheet 27 35 43 51
CBIT_57: SLOT0.D19 ; also on sheet 27 35 43 51
CBIT_58: SLOT0.C19 ; also on sheet 27 35 43 51
CBIT_59: SLOT0.B19 ; also on sheet 27 35 43 51
CBIT_60: SLOT0.A19 ; also on sheet 27 35 43 51
CBIT_61: SLOT0.F17 ; also on sheet 42 50
CBIT_62: SLOT0.E17 ; also on sheet 26 34 42 50
CBIT_63: SLOT0.D17 ; also on sheet 26 34 42 50
CBIT_64: SLOT0.F7 ; also on sheet 26 34 42 50
CBIT_65: SLOT0.E7 ; also on sheet 26 34 42 50
CBIT_66: SLOT0.D7 ; also on sheet 26 34 42 50
CBIT_67: SLOT0.C7 ; also on sheet 26 34 42 50
CBIT_68: SLOT0.B7 ; also on sheet 26 34 42 50
CBIT_69: SLOT0.A7 ; also on sheet 26 34 42 50
CBIT_70: SLOT0.F5 ; also on sheet 26 34 42 50
CBIT_71: SLOT0.E5 ; also on sheet 26 34 42 50
CBIT_72: SLOT0.D5 ; also on sheet 26 34 42 50
CBIT_73: SLOT0.C5 ; also on sheet 26 34 42 50
CBIT_74: SLOT0.B5 ; also on sheet 26 34 42 50
CBIT_75: SLOT0.A5 ; also on sheet 42 50
CBIT_76: SLOT0.F3 ; also on sheet 26 34 42 50
CBIT_77: SLOT0.E3 ; also on sheet 26 34 42 50
CBIT_78: SLOT0.D3 ; also on sheet 26 34 42 50
CBIT_79: SLOT0.C3 ; also on sheet 25 33 41 49
CBIT_80: SLOT0.B3 ; also on sheet 25 33 41 49
CBIT_81: SLOT0.A3 ; also on sheet 25 33 41 49
CBIT_82: SLOT0.G24 ; also on sheet 25 33 41 49
CBIT_83: SLOT0.F24 ; also on sheet 41 49
CBIT_84: SLOT0.E24 ; also on sheet 41 49
CBIT_85: SLOT0.D24 ; also on sheet 25 33 41 49
CBIT_86: SLOT0.C24 ; also on sheet 25 33 41 49
CBIT_87: SLOT0.B24 ; also on sheet 25 33 41 49
CBIT_88: SLOT0.F26 ; also on sheet 25 33 41 49
CBIT_89: SLOT0.E26 ; also on sheet 25 33 41 49
CBIT_90: SLOT0.D26 ; also on sheet 25 33 41 49
CBIT_91: SLOT0.C26 ; also on sheet 25 33 41 49
CBIT_92: SLOT0.B26 ; also on sheet 25 33 41 49
CBIT_93: SLOT0.A26 ; also on sheet 25 33 41 49
CBIT_94: SLOT0.G28 ; also on sheet 25 33 41 49
CBIT_95: SLOT0.F28 ; also on sheet 25 33 41 49
CBIT_96: SLOT0.E28 ; also on sheet 25 33 41 49
CBIT_97: SLOT0.D28 ; also on sheet 25 33 41 49
CBIT_98: SLOT0.C28 ; also on sheet 24 32 40 48
CBIT_99: SLOT0.B28 ; also on sheet 24 32 40 48
CBIT_100: SLOT0.F30 ; also on sheet 24 32 40 48
CBIT_101: SLOT0.E30 ; also on sheet 24 32 40 48
CBIT_102: SLOT0.D30 ; also on sheet 24 32 40 48
CBIT_103: SLOT0.C30 ; also on sheet 24 32 40 48
CBIT_104: SLOT0.B30 ; also on sheet 24 32 40 48
CBIT_105: SLOT0.A30 ; also on sheet 24 32 40 48
CBIT_106: SLOT0.G32 ; also on sheet 24 32 40 48
CBIT_107: SLOT0.F32 ; also on sheet 24 32 40 48
CBIT_108: SLOT0.E32 ; also on sheet 24 32 40 48
CBIT_109: SLOT0.D32 ; also on sheet 24 32 40 48
CBIT_110: SLOT0.C32 ; also on sheet 24 32 40 48
CBIT_111: SLOT0.B32 ; also on sheet 23 31 39 47
CBIT_112: SLOT0.F34 ; also on sheet 23 31 39 47
CBIT_113: SLOT0.E34 ; also on sheet 23 31 39 47
CBIT_114: SLOT0.D34 ; also on sheet 23 31 39 47
CBIT_115: SLOT0.C34 ; also on sheet 23 31 39 47
CBIT_116: SLOT0.B34 ; also on sheet 23 31 39 47
CBIT_117: SLOT0.A34 ; also on sheet 23 31 39 47
CBIT_118: SLOT0.G36 ; also on sheet 23 31 39 47
CBIT_119: SLOT0.F36 ; also on sheet 23 31 39 47
CBIT_120: SLOT0.E36 ; also on sheet 23 31 39 47
CBIT_121: SLOT0.D36 ; also on sheet 30 38
CBIT_122: SLOT0.C36 ; also on sheet 26 34
CBIT_123: SLOT0.B36 ; also on sheet 29 37
CBIT_124: SLOT0.G38 ; also on sheet 25 33
CBIT_125: SLOT0.F38 ; also on sheet 25 29 33 37
CBIT_126: SLOT0.E38 ; also on sheet 26 30 34 38
CBIT_127: SLOT0.D38 ; also on sheet 27 35 43 51
CBIT_128: SLOT0.C38 ; also on sheet 23 31 39 47
CLK100_N: SLOT0.E10
CLK100_P: SLOT0.F10
CLKREF50_N: SLOT0.B10
CLKREF50_P: SLOT0.C10
EVENT_A: SLOT0.C14
EVENT_B: SLOT0.B14
I2C_IDPROM_P3V3: BR7.2 SLOT0.G16
LB_PRESENT_N: 0BS2.1 SLOT0.D41
LB_REG_ADDR0: SLOT0.A18
LB_REG_ADDR1: SLOT0.B18
LB_REG_ADDR2: SLOT0.C18
LB_REG_ADDR3: SLOT0.D18
LB_REG_ADDR4: SLOT0.D20
LB_REG_ADDR5: SLOT0.E20
LB_REG_ADDR6: SLOT0.F20
LB_REG_ADDR7: SLOT0.G20
LB_REG_DATA0: SLOT0.B20
LB_REG_DATA1: SLOT0.C20
LB_REG_DATA2: SLOT0.A22
LB_REG_DATA3: SLOT0.B22
LB_REG_DATA4: SLOT0.C22
LB_REG_DATA5: SLOT0.D22
LB_REG_DATA6: SLOT0.E22
LB_REG_DATA7: SLOT0.F22
LB_REG_RD_N: SLOT0.D16
LB_REG_WR_N: SLOT0.C16
S1_C1B_F: SLOT01.E29(4_B_HF) ; also on sheet 51 53
S1_IS1N_F: SLOT01.E9(14_B_HF) ; also on sheet 51 53
S1_IS1P_F: SLOT01.E7(15_B_HF) ; also on sheet 51 53
S1_IS2N_F: SLOT01.E31(3_B_HF) ; also on sheet 51 54
S1_IS2P_F: SLOT01.E5(16_B_HF) ; also on sheet 51 54
S1_SRG_F: SLOT01.D29(4_A_HF) ; also on sheet 51 54
S2_C1B_F: SLOT02.E29(4_B_HF) ; also on sheet 47 49
S2_IS1N_F: SLOT02.E9(14_B_HF) ; also on sheet 47 49
S2_IS1P_F: SLOT02.E7(15_B_HF) ; also on sheet 47 49
S2_IS2N_F: SLOT02.E31(3_B_HF) ; also on sheet 47 50
S2_IS2P_F: SLOT02.E5(16_B_HF) ; also on sheet 47 50
S2_SRG_F: SLOT02.D29(4_A_HF) ; also on sheet 47 50
S3_C1B_F: SLOT01.F53(20_B_HF) ; also on sheet 43 45
S3_IS1N_F: SLOT01.A43(30_B_HF) ; also on sheet 43 45
S3_IS1P_F: SLOT01.F19(31_B_HF) ; also on sheet 43 45
S3_IS2N_F: SLOT01.F55(19_B_HF) ; also on sheet 43 46
S3_IS2P_F: SLOT01.F3(32_B_HF) ; also on sheet 43 46
S3_SRG_F: SLOT01.F29(20_A_HF) ; also on sheet 43 46
S4_C1B_F: SLOT02.F53(20_B_HF) ; also on sheet 39 41
S4_IS1N_F: SLOT02.A43(30_B_HF) ; also on sheet 39 41
S4_IS1P_F: SLOT02.F19(31_B_HF) ; also on sheet 39 41
S4_IS2N_F: SLOT02.F55(19_B_HF) ; also on sheet 39 42
S4_IS2P_F: SLOT02.F3(32_B_HF) ; also on sheet 39 42
S4_SRG_F: SLOT02.F29(20_A_HF) ; also on sheet 39 42
SCOPE_TP0: SLOT0.B16
SCOPE_TP1: SLOT0.A16
SDUN5V: SLOT0.C4 SLOT0.D4 SLOT0.E4 SLOT0.F4 SLOT0.G4
SDUP5V: F1.1 SLOT0.A2 SLOT0.A4 SLOT0.B2 SLOT0.B4 SLOT0.C2
SDUP5V_FILTER: CT2.1 CT3.1 LT1.2 TP_SDUP5V_FILTER.1(TP) ; also on sheet 23 27 31 35 39 43 47 51
SDUR5V: F2.1 SLOT0.A6 SLOT0.B6 SLOT0.C6 SLOT0.D6 SLOT0.E6
SDUR5V_FILTER: CT8.1 CT9.1 LT3.2 TP_SDUR5V_FILTER.1(TP) ; also on sheet 23 24 25 26 27 28 29 30 31 32 33 34 35 36 37 38 39 40 41 42 43 44 45 46 47 48 49 50 51 52 53 54
SL01_VI100_1_A_HF: SLOT01.D35(1_A_HF) ; also on sheet 54
SL01_VI100_1_A_HG: SLOT01.B35(1_A_HG)
SL01_VI100_1_A_HS: SLOT01.C35(1_A_HS) ; also on sheet 54
SL01_VI100_1_B_HF: SH3.2 SLOT01.E35(1_B_HF) ; also on sheet 12
SL01_VI100_1_B_HG: SLOT01.C59(1_B_HG)
SL01_VI100_1_B_HS: SH3.1 SLOT01.C60(1_B_HS) ; also on sheet 12
SL01_VI100_1_LS: SLOT01.A35(1_LS) ; also on sheet 51
SL01_VI100_2_A_HF: SLOT01.D33(2_A_HF) ; also on sheet 54
SL01_VI100_2_A_HG: SLOT01.B33(2_A_HG)
SL01_VI100_2_A_HS: SLOT01.C33(2_A_HS) ; also on sheet 54
SL01_VI100_2_B_HF: SLOT01.E33(2_B_HF) ; also on sheet 52
SL01_VI100_2_B_HG: SLOT01.C57(2_B_HG)
SL01_VI100_2_B_HS: SLOT01.C58(2_B_HS) ; also on sheet 52
SL01_VI100_2_LS: SLOT01.A33(2_LS) ; also on sheet 51
SL01_VI100_3_A_HF: SLOT01.D31(3_A_HF) ; also on sheet 54
SL01_VI100_3_A_HG: SLOT01.B31(3_A_HG)
SL01_VI100_3_A_HS: SLOT01.C31(3_A_HS) ; also on sheet 54
SL01_VI100_3_B_HG: SLOT01.C55(3_B_HG)
SL01_VI100_3_B_HS: SLOT01.C56(3_B_HS) ; also on sheet 54
SL01_VI100_3_LS: SLOT01.A31(3_LS) ; also on sheet 51
SL01_VI100_4_A_HG: SLOT01.B29(4_A_HG)
SL01_VI100_4_A_HS: SLOT01.C29(4_A_HS) ; also on sheet 54
SL01_VI100_4_B_HG: SLOT01.C53(4_B_HG)
SL01_VI100_4_B_HS: SLOT01.C54(4_B_HS) ; also on sheet 53
SL01_VI100_4_LS: SLOT01.A29(4_LS) ; also on sheet 51
SL01_VI100_5_A_HF: SLOT01.D27(5_A_HF) ; also on sheet 54
SL01_VI100_5_A_HG: SLOT01.B27(5_A_HG)
SL01_VI100_5_A_HS: SLOT01.C27(5_A_HS) ; also on sheet 54
SL01_VI100_5_B_HF: SLOT01.E27(5_B_HF)
SL01_VI100_5_B_HG: SLOT01.C51(5_B_HG)
SL01_VI100_5_B_HS: SLOT01.C52(5_B_HS)
SL01_VI100_5_LS: SLOT01.A27(5_LS) ; also on sheet 51
SL01_VI100_6_A_HF: SLOT01.D25(6_A_HF) ; also on sheet 54
SL01_VI100_6_A_HG: SLOT01.B25(6_A_HG)
SL01_VI100_6_A_HS: SLOT01.C25(6_A_HS) ; also on sheet 54
SL01_VI100_6_B_HF: SLOT01.E25(6_B_HF) ; also on sheet 52
SL01_VI100_6_B_HG: SLOT01.C49(6_B_HG)
SL01_VI100_6_B_HS: SLOT01.C50(6_B_HS) ; also on sheet 52
SL01_VI100_6_LS: SLOT01.A25(6_LS) ; also on sheet 51
SL01_VI100_7_A_HF: SLOT01.D23(7_A_HF) ; also on sheet 53
SL01_VI100_7_A_HG: SLOT01.B23(7_A_HG)
SL01_VI100_7_A_HS: SLOT01.C23(7_A_HS) ; also on sheet 53
SL01_VI100_7_B_HF: SLOT01.E23(7_B_HF) ; also on sheet 52
SL01_VI100_7_B_HG: SLOT01.C47(7_B_HG)
SL01_VI100_7_B_HS: SLOT01.C48(7_B_HS) ; also on sheet 52
SL01_VI100_7_LS: SLOT01.A23(7_LS) ; also on sheet 51
SL01_VI100_8_A_HF: SLOT01.D21(8_A_HF) ; also on sheet 53
SL01_VI100_8_A_HG: SLOT01.B21(8_A_HG)
SL01_VI100_8_A_HS: SLOT01.C21(8_A_HS) ; also on sheet 53
SL01_VI100_8_B_HF: SLOT01.E21(8_B_HF) ; also on sheet 53
SL01_VI100_8_B_HG: SLOT01.C45(8_B_HG)
SL01_VI100_8_B_HS: SLOT01.C46(8_B_HS) ; also on sheet 53
SL01_VI100_8_LS: SLOT01.A21(8_LS) ; also on sheet 51
SL01_VI100_9_A_HF: SLOT01.D39(9_A_HF) ; also on sheet 53
SL01_VI100_9_A_HG: SLOT01.B39(9_A_HG)
SL01_VI100_9_A_HS: SLOT01.C39(9_A_HS) ; also on sheet 53
SL01_VI100_9_B_HF: SLOT01.E39(9_B_HF) ; also on sheet 53
SL01_VI100_9_B_HG: SLOT01.C61(9_B_HG)
SL01_VI100_9_B_HS: SLOT01.F37(9_B_HS) ; also on sheet 53
SL01_VI100_9_LS: SLOT01.A39(9_LS) ; also on sheet 51
SL01_VI100_10_A_HF: SLOT01.D17(10_A_HF) ; also on sheet 53
SL01_VI100_10_A_HG: SLOT01.B17(10_A_HG)
SL01_VI100_10_A_HS: SLOT01.C17(10_A_HS) ; also on sheet 53
SL01_VI100_10_B_HF: SLOT01.E17(10_B_HF) ; also on sheet 52
SL01_VI100_10_B_HG: SLOT01.C43(10_B_HG)
SL01_VI100_10_B_HS: SLOT01.C44(10_B_HS) ; also on sheet 52
SL01_VI100_10_LS: SLOT01.A17(10_LS) ; also on sheet 51
SL01_VI100_11_A_HF: SLOT01.D15(11_A_HF) ; also on sheet 53
SL01_VI100_11_A_HG: SLOT01.B15(11_A_HG)
SL01_VI100_11_A_HS: SLOT01.C15(11_A_HS) ; also on sheet 53
SL01_VI100_11_B_HF: SLOT01.E15(11_B_HF) ; also on sheet 52
SL01_VI100_11_B_HG: SLOT01.C41(11_B_HG)
SL01_VI100_11_B_HS: SLOT01.C42(11_B_HS) ; also on sheet 52
SL01_VI100_11_LS: SLOT01.A15(11_LS) ; also on sheet 51
SL01_VI100_12_A_HF: SLOT01.D13(12_A_HF) ; also on sheet 53
SL01_VI100_12_A_HG: SLOT01.B13(12_A_HG)
SL01_VI100_12_A_HS: SLOT01.C13(12_A_HS) ; also on sheet 53
SL01_VI100_12_B_HF: SLOT01.E13(12_B_HF) ; also on sheet 52
SL01_VI100_12_B_HG: SLOT01.B61(12_B_HG)
SL01_VI100_12_B_HS: SLOT01.B59(12_B_HS) ; also on sheet 52
SL01_VI100_12_LS: SLOT01.A13(12_LS) ; also on sheet 51
SL01_VI100_13_A_HF: SLOT01.D11(13_A_HF) ; also on sheet 53
SL01_VI100_13_A_HG: SLOT01.B11(13_A_HG)
SL01_VI100_13_A_HS: SLOT01.C11(13_A_HS) ; also on sheet 53
SL01_VI100_13_B_HF: SLOT01.E11(13_B_HF) ; also on sheet 52
SL01_VI100_13_B_HG: SLOT01.B51(13_B_HG)
SL01_VI100_13_B_HS: SLOT01.B49(13_B_HS) ; also on sheet 52
SL01_VI100_13_LS: SLOT01.A11(13_LS) ; also on sheet 51
SL01_VI100_14_A_HF: SLOT01.D9(14_A_HF) ; also on sheet 53
SL01_VI100_14_A_HG: SLOT01.B9(14_A_HG)
SL01_VI100_14_A_HS: SLOT01.C9(14_A_HS) ; also on sheet 53
SL01_VI100_14_B_HG: SLOT01.B47(14_B_HG)
SL01_VI100_14_B_HS: SLOT01.B45(14_B_HS) ; also on sheet 53
SL01_VI100_14_LS: SLOT01.A9(14_LS) ; also on sheet 51
SL01_VI100_15_A_HF: SLOT01.D7(15_A_HF) ; also on sheet 52
SL01_VI100_15_A_HG: SLOT01.B7(15_A_HG)
SL01_VI100_15_A_HS: SLOT01.C7(15_A_HS) ; also on sheet 52
SL01_VI100_15_B_HG: SLOT01.A41(15_B_HG)
SL01_VI100_15_B_HS: SLOT01.B19(15_B_HS) ; also on sheet 53
SL01_VI100_15_LS: SLOT01.A7(15_LS) ; also on sheet 51
SL01_VI100_16_A_HF: SLOT01.D5(16_A_HF) ; also on sheet 52
SL01_VI100_16_A_HG: SLOT01.B5(16_A_HG)
SL01_VI100_16_A_HS: SLOT01.C5(16_A_HS) ; also on sheet 52
SL01_VI100_16_B_HG: SLOT01.C3(16_B_HG)
SL01_VI100_16_B_HS: SLOT01.B1(16_B_HS) ; also on sheet 54
SL01_VI100_16_LS: SLOT01.A5(16_LS) ; also on sheet 51
SL01_VI100_17_A_HF: SLOT01.F35(17_A_HF) ; also on sheet 46
SL01_VI100_17_A_HG: SLOT01.D59(17_A_HG)
SL01_VI100_17_A_HS: SLOT01.E60(17_A_HS) ; also on sheet 46
SL01_VI100_17_B_HF: SLOT01.F59(17_B_HF)
SL01_VI100_17_B_HG: SLOT01.E59(17_B_HG)
SL01_VI100_17_B_HS: SLOT01.G60(17_B_HS)
SL01_VI100_17_LS: SLOT01.D60(17_LS) ; also on sheet 43
SL01_VI100_18_A_HF: SLOT01.F33(18_A_HF) ; also on sheet 46
SL01_VI100_18_A_HG: SLOT01.D57(18_A_HG)
SL01_VI100_18_A_HS: SLOT01.E58(18_A_HS) ; also on sheet 46
SL01_VI100_18_B_HF: SLOT01.F57(18_B_HF) ; also on sheet 44
SL01_VI100_18_B_HG: SLOT01.E57(18_B_HG)
SL01_VI100_18_B_HS: SLOT01.G58(18_B_HS) ; also on sheet 44
SL01_VI100_18_LS: SLOT01.D58(18_LS) ; also on sheet 43
SL01_VI100_19_A_HF: SLOT01.F31(19_A_HF) ; also on sheet 46
SL01_VI100_19_A_HG: SLOT01.D55(19_A_HG)
SL01_VI100_19_A_HS: SLOT01.E56(19_A_HS) ; also on sheet 46
SL01_VI100_19_B_HG: SLOT01.E55(19_B_HG)
SL01_VI100_19_B_HS: SLOT01.G56(19_B_HS) ; also on sheet 46
SL01_VI100_19_LS: SLOT01.D56(19_LS) ; also on sheet 43
SL01_VI100_20_A_HG: SLOT01.D53(20_A_HG)
SL01_VI100_20_A_HS: SLOT01.E54(20_A_HS) ; also on sheet 46
SL01_VI100_20_B_HG: SLOT01.E53(20_B_HG)
SL01_VI100_20_B_HS: SLOT01.G54(20_B_HS) ; also on sheet 45
SL01_VI100_20_LS: SLOT01.D54(20_LS) ; also on sheet 43
SL01_VI100_21_A_HF: SLOT01.F27(21_A_HF) ; also on sheet 46
SL01_VI100_21_A_HG: SLOT01.D51(21_A_HG)
SL01_VI100_21_A_HS: SLOT01.E52(21_A_HS) ; also on sheet 46
SL01_VI100_21_B_HF: SLOT01.F51(21_B_HF)
SL01_VI100_21_B_HG: SLOT01.E51(21_B_HG)
SL01_VI100_21_B_HS: SLOT01.G52(21_B_HS)
SL01_VI100_21_LS: SLOT01.D52(21_LS) ; also on sheet 43
SL01_VI100_22_A_HF: SLOT01.F25(22_A_HF) ; also on sheet 46
SL01_VI100_22_A_HG: SLOT01.D49(22_A_HG)
SL01_VI100_22_A_HS: SLOT01.E50(22_A_HS) ; also on sheet 46
SL01_VI100_22_B_HF: SLOT01.F49(22_B_HF) ; also on sheet 44
SL01_VI100_22_B_HG: SLOT01.E49(22_B_HG)
SL01_VI100_22_B_HS: SLOT01.G50(22_B_HS) ; also on sheet 44
SL01_VI100_22_LS: SLOT01.D50(22_LS) ; also on sheet 43
SL01_VI100_23_A_HF: SLOT01.F23(23_A_HF) ; also on sheet 45
SL01_VI100_23_A_HG: SLOT01.D47(23_A_HG)
SL01_VI100_23_A_HS: SLOT01.E48(23_A_HS) ; also on sheet 45
SL01_VI100_23_B_HF: SLOT01.F47(23_B_HF) ; also on sheet 44
SL01_VI100_23_B_HG: SLOT01.E47(23_B_HG)
SL01_VI100_23_B_HS: SLOT01.G48(23_B_HS) ; also on sheet 44
SL01_VI100_23_LS: SLOT01.D48(23_LS) ; also on sheet 43
SL01_VI100_24_A_HF: SLOT01.F21(24_A_HF) ; also on sheet 45
SL01_VI100_24_A_HG: SLOT01.D45(24_A_HG)
SL01_VI100_24_A_HS: SLOT01.E46(24_A_HS) ; also on sheet 45
SL01_VI100_24_B_HF: SLOT01.F45(24_B_HF) ; also on sheet 45
SL01_VI100_24_B_HG: SLOT01.E45(24_B_HG)
SL01_VI100_24_B_HS: SLOT01.G46(24_B_HS) ; also on sheet 45
SL01_VI100_24_LS: SLOT01.D46(24_LS) ; also on sheet 43
SL01_VI100_25_A_HF: SLOT01.F39(25_A_HF) ; also on sheet 45
SL01_VI100_25_A_HG: SLOT01.D61(25_A_HG)
SL01_VI100_25_A_HS: SLOT01.C62(25_A_HS) ; also on sheet 45
SL01_VI100_25_B_HF: SLOT01.F61(25_B_HF) ; also on sheet 45
SL01_VI100_25_B_HG: SLOT01.E61(25_B_HG)
SL01_VI100_25_B_HS: SLOT01.F62(25_B_HS) ; also on sheet 45
SL01_VI100_25_LS: SLOT01.B62(25_LS) ; also on sheet 43
SL01_VI100_26_A_HF: SLOT01.F17(26_A_HF) ; also on sheet 45
SL01_VI100_26_A_HG: SLOT01.D43(26_A_HG)
SL01_VI100_26_A_HS: SLOT01.E44(26_A_HS) ; also on sheet 45
SL01_VI100_26_B_HF: SLOT01.F43(26_B_HF) ; also on sheet 44
SL01_VI100_26_B_HG: SLOT01.E43(26_B_HG)
SL01_VI100_26_B_HS: SLOT01.G44(26_B_HS) ; also on sheet 44
SL01_VI100_26_LS: SLOT01.D44(26_LS) ; also on sheet 43
SL01_VI100_27_A_HF: SLOT01.F15(27_A_HF) ; also on sheet 45
SL01_VI100_27_A_HG: SLOT01.D41(27_A_HG)
SL01_VI100_27_A_HS: SLOT01.E42(27_A_HS) ; also on sheet 45
SL01_VI100_27_B_HF: SLOT01.F41(27_B_HF) ; also on sheet 44
SL01_VI100_27_B_HG: SLOT01.E41(27_B_HG)
SL01_VI100_27_B_HS: SLOT01.G42(27_B_HS) ; also on sheet 44
SL01_VI100_27_LS: SLOT01.D42(27_LS) ; also on sheet 43
SL01_VI100_28_A_HF: SLOT01.F13(28_A_HF) ; also on sheet 45
SL01_VI100_28_A_HG: SLOT01.A61(28_A_HG)
SL01_VI100_28_A_HS: SLOT01.A60(28_A_HS) ; also on sheet 45
SL01_VI100_28_B_HF: SLOT01.A57(28_B_HF) ; also on sheet 44
SL01_VI100_28_B_HG: SLOT01.B57(28_B_HG)
SL01_VI100_28_B_HS: SLOT01.A56(28_B_HS) ; also on sheet 44
SL01_VI100_28_LS: SLOT01.A58(28_LS) ; also on sheet 43
SL01_VI100_29_A_HF: SLOT01.F11(29_A_HF) ; also on sheet 45
SL01_VI100_29_A_HG: SLOT01.B53(29_A_HG)
SL01_VI100_29_A_HS: SLOT01.B55(29_A_HS) ; also on sheet 45
SL01_VI100_29_B_HF: SLOT01.A51(29_B_HF) ; also on sheet 44
SL01_VI100_29_B_HG: SLOT01.A53(29_B_HG)
SL01_VI100_29_B_HS: SLOT01.A52(29_B_HS) ; also on sheet 44
SL01_VI100_29_LS: SLOT01.A55(29_LS) ; also on sheet 43
SL01_VI100_30_A_HF: SLOT01.F9(30_A_HF) ; also on sheet 45
SL01_VI100_30_A_HG: SLOT01.A47(30_A_HG)
SL01_VI100_30_A_HS: SLOT01.A48(30_A_HS) ; also on sheet 45
SL01_VI100_30_B_HG: SLOT01.B43(30_B_HG)
SL01_VI100_30_B_HS: SLOT01.A44(30_B_HS) ; also on sheet 45
SL01_VI100_30_LS: SLOT01.A46(30_LS) ; also on sheet 43
SL01_VI100_31_A_HF: SLOT01.F7(31_A_HF) ; also on sheet 44
SL01_VI100_31_A_HG: SLOT01.B41(31_A_HG)
SL01_VI100_31_A_HS: SLOT01.B3(31_A_HS) ; also on sheet 44
SL01_VI100_31_B_HG: SLOT01.C19(31_B_HG)
SL01_VI100_31_B_HS: SLOT01.E19(31_B_HS) ; also on sheet 45
SL01_VI100_31_LS: SLOT01.A3(31_LS) ; also on sheet 43
SL01_VI100_32_A_HF: SLOT01.F5(32_A_HF) ; also on sheet 44
SL01_VI100_32_A_HG: SLOT01.D3(32_A_HG)
SL01_VI100_32_A_HS: SLOT01.D1(32_A_HS) ; also on sheet 44
SL01_VI100_32_B_HG: SLOT01.E3(32_B_HG)
SL01_VI100_32_B_HS: SLOT01.F1(32_B_HS) ; also on sheet 46
SL01_VI100_32_LS: SLOT01.C1(32_LS) ; also on sheet 43
SL02_VI100_1_A_HF: SLOT02.D35(1_A_HF) ; also on sheet 50
SL02_VI100_1_A_HG: SLOT02.B35(1_A_HG)
SL02_VI100_1_A_HS: SLOT02.C35(1_A_HS) ; also on sheet 50
SL02_VI100_1_B_HF: SH1.2 SLOT02.E35(1_B_HF) ; also on sheet 11
SL02_VI100_1_B_HG: SLOT02.C59(1_B_HG)
SL02_VI100_1_B_HS: SH1.1 SLOT02.C60(1_B_HS) ; also on sheet 11
SL02_VI100_1_LS: SLOT02.A35(1_LS) ; also on sheet 47
SL02_VI100_2_A_HF: SLOT02.D33(2_A_HF) ; also on sheet 50
SL02_VI100_2_A_HG: SLOT02.B33(2_A_HG)
SL02_VI100_2_A_HS: SLOT02.C33(2_A_HS) ; also on sheet 50
SL02_VI100_2_B_HF: SLOT02.E33(2_B_HF) ; also on sheet 48
SL02_VI100_2_B_HG: SLOT02.C57(2_B_HG)
SL02_VI100_2_B_HS: SLOT02.C58(2_B_HS) ; also on sheet 48
SL02_VI100_2_LS: SLOT02.A33(2_LS) ; also on sheet 47
SL02_VI100_3_A_HF: SLOT02.D31(3_A_HF) ; also on sheet 50
SL02_VI100_3_A_HG: SLOT02.B31(3_A_HG)
SL02_VI100_3_A_HS: SLOT02.C31(3_A_HS) ; also on sheet 50
SL02_VI100_3_B_HG: SLOT02.C55(3_B_HG)
SL02_VI100_3_B_HS: SLOT02.C56(3_B_HS) ; also on sheet 50
SL02_VI100_3_LS: SLOT02.A31(3_LS) ; also on sheet 47
SL02_VI100_4_A_HG: SLOT02.B29(4_A_HG)
SL02_VI100_4_A_HS: SLOT02.C29(4_A_HS) ; also on sheet 50
SL02_VI100_4_B_HG: SLOT02.C53(4_B_HG)
SL02_VI100_4_B_HS: SLOT02.C54(4_B_HS) ; also on sheet 49
SL02_VI100_4_LS: SLOT02.A29(4_LS) ; also on sheet 47
SL02_VI100_5_A_HF: SLOT02.D27(5_A_HF) ; also on sheet 50
SL02_VI100_5_A_HG: SLOT02.B27(5_A_HG)
SL02_VI100_5_A_HS: SLOT02.C27(5_A_HS) ; also on sheet 50
SL02_VI100_5_B_HF: SLOT02.E27(5_B_HF)
SL02_VI100_5_B_HG: SLOT02.C51(5_B_HG)
SL02_VI100_5_B_HS: SLOT02.C52(5_B_HS)
SL02_VI100_5_LS: SLOT02.A27(5_LS) ; also on sheet 47
SL02_VI100_6_A_HF: SLOT02.D25(6_A_HF) ; also on sheet 50
SL02_VI100_6_A_HG: SLOT02.B25(6_A_HG)
SL02_VI100_6_A_HS: SLOT02.C25(6_A_HS) ; also on sheet 50
SL02_VI100_6_B_HF: SLOT02.E25(6_B_HF) ; also on sheet 48
SL02_VI100_6_B_HG: SLOT02.C49(6_B_HG)
SL02_VI100_6_B_HS: SLOT02.C50(6_B_HS) ; also on sheet 48
SL02_VI100_6_LS: SLOT02.A25(6_LS) ; also on sheet 47
SL02_VI100_7_A_HF: SLOT02.D23(7_A_HF) ; also on sheet 49
SL02_VI100_7_A_HG: SLOT02.B23(7_A_HG)
SL02_VI100_7_A_HS: SLOT02.C23(7_A_HS) ; also on sheet 49
SL02_VI100_7_B_HF: SLOT02.E23(7_B_HF) ; also on sheet 48
SL02_VI100_7_B_HG: SLOT02.C47(7_B_HG)
SL02_VI100_7_B_HS: SLOT02.C48(7_B_HS) ; also on sheet 48
SL02_VI100_7_LS: SLOT02.A23(7_LS) ; also on sheet 47
SL02_VI100_8_A_HF: SLOT02.D21(8_A_HF) ; also on sheet 49
SL02_VI100_8_A_HG: SLOT02.B21(8_A_HG)
SL02_VI100_8_A_HS: SLOT02.C21(8_A_HS) ; also on sheet 49
SL02_VI100_8_B_HF: SLOT02.E21(8_B_HF) ; also on sheet 49
SL02_VI100_8_B_HG: SLOT02.C45(8_B_HG)
SL02_VI100_8_B_HS: SLOT02.C46(8_B_HS) ; also on sheet 49
SL02_VI100_8_LS: SLOT02.A21(8_LS) ; also on sheet 47
SL02_VI100_9_A_HF: SLOT02.D39(9_A_HF) ; also on sheet 49
SL02_VI100_9_A_HG: SLOT02.B39(9_A_HG)
SL02_VI100_9_A_HS: SLOT02.C39(9_A_HS) ; also on sheet 49
SL02_VI100_9_B_HF: SLOT02.E39(9_B_HF) ; also on sheet 49
SL02_VI100_9_B_HG: SLOT02.C61(9_B_HG)
SL02_VI100_9_B_HS: SLOT02.F37(9_B_HS) ; also on sheet 49
SL02_VI100_9_LS: SLOT02.A39(9_LS) ; also on sheet 47
SL02_VI100_10_A_HF: SLOT02.D17(10_A_HF) ; also on sheet 49
SL02_VI100_10_A_HG: SLOT02.B17(10_A_HG)
SL02_VI100_10_A_HS: SLOT02.C17(10_A_HS) ; also on sheet 49
SL02_VI100_10_B_HF: SLOT02.E17(10_B_HF) ; also on sheet 48
SL02_VI100_10_B_HG: SLOT02.C43(10_B_HG)
SL02_VI100_10_B_HS: SLOT02.C44(10_B_HS) ; also on sheet 48
SL02_VI100_10_LS: SLOT02.A17(10_LS) ; also on sheet 47
SL02_VI100_11_A_HF: SLOT02.D15(11_A_HF) ; also on sheet 49
SL02_VI100_11_A_HG: SLOT02.B15(11_A_HG)
SL02_VI100_11_A_HS: SLOT02.C15(11_A_HS) ; also on sheet 49
SL02_VI100_11_B_HF: SLOT02.E15(11_B_HF) ; also on sheet 48
SL02_VI100_11_B_HG: SLOT02.C41(11_B_HG)
SL02_VI100_11_B_HS: SLOT02.C42(11_B_HS) ; also on sheet 48
SL02_VI100_11_LS: SLOT02.A15(11_LS) ; also on sheet 47
SL02_VI100_12_A_HF: SLOT02.D13(12_A_HF) ; also on sheet 49
SL02_VI100_12_A_HG: SLOT02.B13(12_A_HG)
SL02_VI100_12_A_HS: SLOT02.C13(12_A_HS) ; also on sheet 49
SL02_VI100_12_B_HF: SLOT02.E13(12_B_HF) ; also on sheet 48
SL02_VI100_12_B_HG: SLOT02.B61(12_B_HG)
SL02_VI100_12_B_HS: SLOT02.B59(12_B_HS) ; also on sheet 48
SL02_VI100_12_LS: SLOT02.A13(12_LS) ; also on sheet 47
SL02_VI100_13_A_HF: SLOT02.D11(13_A_HF) ; also on sheet 49
SL02_VI100_13_A_HG: SLOT02.B11(13_A_HG)
SL02_VI100_13_A_HS: SLOT02.C11(13_A_HS) ; also on sheet 49
SL02_VI100_13_B_HF: SLOT02.E11(13_B_HF) ; also on sheet 48
SL02_VI100_13_B_HG: SLOT02.B51(13_B_HG)
SL02_VI100_13_B_HS: SLOT02.B49(13_B_HS) ; also on sheet 48
SL02_VI100_13_LS: SLOT02.A11(13_LS) ; also on sheet 47
SL02_VI100_14_A_HF: SLOT02.D9(14_A_HF) ; also on sheet 49
SL02_VI100_14_A_HG: SLOT02.B9(14_A_HG)
SL02_VI100_14_A_HS: SLOT02.C9(14_A_HS) ; also on sheet 49
SL02_VI100_14_B_HG: SLOT02.B47(14_B_HG)
SL02_VI100_14_B_HS: SLOT02.B45(14_B_HS) ; also on sheet 49
SL02_VI100_14_LS: SLOT02.A9(14_LS) ; also on sheet 47
SL02_VI100_15_A_HF: SLOT02.D7(15_A_HF) ; also on sheet 48
SL02_VI100_15_A_HG: SLOT02.B7(15_A_HG)
SL02_VI100_15_A_HS: SLOT02.C7(15_A_HS) ; also on sheet 48
SL02_VI100_15_B_HG: SLOT02.A41(15_B_HG)
SL02_VI100_15_B_HS: SLOT02.B19(15_B_HS) ; also on sheet 49
SL02_VI100_15_LS: SLOT02.A7(15_LS) ; also on sheet 47
SL02_VI100_16_A_HF: SLOT02.D5(16_A_HF) ; also on sheet 48
SL02_VI100_16_A_HG: SLOT02.B5(16_A_HG)
SL02_VI100_16_A_HS: SLOT02.C5(16_A_HS) ; also on sheet 48
SL02_VI100_16_B_HG: SLOT02.C3(16_B_HG)
SL02_VI100_16_B_HS: SLOT02.B1(16_B_HS) ; also on sheet 50
SL02_VI100_16_LS: SLOT02.A5(16_LS) ; also on sheet 47
SL02_VI100_17_A_HF: SLOT02.F35(17_A_HF) ; also on sheet 42
SL02_VI100_17_A_HG: SLOT02.D59(17_A_HG)
SL02_VI100_17_A_HS: SLOT02.E60(17_A_HS) ; also on sheet 42
SL02_VI100_17_B_HF: SLOT02.F59(17_B_HF)
SL02_VI100_17_B_HG: SLOT02.E59(17_B_HG)
SL02_VI100_17_B_HS: SLOT02.G60(17_B_HS)
SL02_VI100_17_LS: SLOT02.D60(17_LS) ; also on sheet 39
SL02_VI100_18_A_HF: SLOT02.F33(18_A_HF) ; also on sheet 42
SL02_VI100_18_A_HG: SLOT02.D57(18_A_HG)
SL02_VI100_18_A_HS: SLOT02.E58(18_A_HS) ; also on sheet 42
SL02_VI100_18_B_HF: SLOT02.F57(18_B_HF) ; also on sheet 40
SL02_VI100_18_B_HG: SLOT02.E57(18_B_HG)
SL02_VI100_18_B_HS: SLOT02.G58(18_B_HS) ; also on sheet 40
SL02_VI100_18_LS: SLOT02.D58(18_LS) ; also on sheet 39
SL02_VI100_19_A_HF: SLOT02.F31(19_A_HF) ; also on sheet 42
SL02_VI100_19_A_HG: SLOT02.D55(19_A_HG)
SL02_VI100_19_A_HS: SLOT02.E56(19_A_HS) ; also on sheet 42
SL02_VI100_19_B_HG: SLOT02.E55(19_B_HG)
SL02_VI100_19_B_HS: SLOT02.G56(19_B_HS) ; also on sheet 42
SL02_VI100_19_LS: SLOT02.D56(19_LS) ; also on sheet 39
SL02_VI100_20_A_HG: SLOT02.D53(20_A_HG)
SL02_VI100_20_A_HS: SLOT02.E54(20_A_HS) ; also on sheet 42
SL02_VI100_20_B_HG: SLOT02.E53(20_B_HG)
SL02_VI100_20_B_HS: SLOT02.G54(20_B_HS) ; also on sheet 41
SL02_VI100_20_LS: SLOT02.D54(20_LS) ; also on sheet 39
SL02_VI100_21_A_HF: SLOT02.F27(21_A_HF) ; also on sheet 42
SL02_VI100_21_A_HG: SLOT02.D51(21_A_HG)
SL02_VI100_21_A_HS: SLOT02.E52(21_A_HS) ; also on sheet 42
SL02_VI100_21_B_HF: SLOT02.F51(21_B_HF)
SL02_VI100_21_B_HG: SLOT02.E51(21_B_HG)
SL02_VI100_21_B_HS: SLOT02.G52(21_B_HS)
SL02_VI100_21_LS: SLOT02.D52(21_LS) ; also on sheet 39
SL02_VI100_22_A_HF: SLOT02.F25(22_A_HF) ; also on sheet 42
SL02_VI100_22_A_HG: SLOT02.D49(22_A_HG)
SL02_VI100_22_A_HS: SLOT02.E50(22_A_HS) ; also on sheet 42
SL02_VI100_22_B_HF: SLOT02.F49(22_B_HF) ; also on sheet 40
SL02_VI100_22_B_HG: SLOT02.E49(22_B_HG)
SL02_VI100_22_B_HS: SLOT02.G50(22_B_HS) ; also on sheet 40
SL02_VI100_22_LS: SLOT02.D50(22_LS) ; also on sheet 39
SL02_VI100_23_A_HF: SLOT02.F23(23_A_HF) ; also on sheet 41
SL02_VI100_23_A_HG: SLOT02.D47(23_A_HG)
SL02_VI100_23_A_HS: SLOT02.E48(23_A_HS) ; also on sheet 41
SL02_VI100_23_B_HF: SLOT02.F47(23_B_HF) ; also on sheet 40
SL02_VI100_23_B_HG: SLOT02.E47(23_B_HG)
SL02_VI100_23_B_HS: SLOT02.G48(23_B_HS) ; also on sheet 40
SL02_VI100_23_LS: SLOT02.D48(23_LS) ; also on sheet 39
SL02_VI100_24_A_HF: SLOT02.F21(24_A_HF) ; also on sheet 41
SL02_VI100_24_A_HG: SLOT02.D45(24_A_HG)
SL02_VI100_24_A_HS: SLOT02.E46(24_A_HS) ; also on sheet 41
SL02_VI100_24_B_HF: SLOT02.F45(24_B_HF) ; also on sheet 41
SL02_VI100_24_B_HG: SLOT02.E45(24_B_HG)
SL02_VI100_24_B_HS: SLOT02.G46(24_B_HS) ; also on sheet 41
SL02_VI100_24_LS: SLOT02.D46(24_LS) ; also on sheet 39
SL02_VI100_25_A_HF: SLOT02.F39(25_A_HF) ; also on sheet 41
SL02_VI100_25_A_HG: SLOT02.D61(25_A_HG)
SL02_VI100_25_A_HS: SLOT02.C62(25_A_HS) ; also on sheet 41
SL02_VI100_25_B_HF: SLOT02.F61(25_B_HF) ; also on sheet 41
SL02_VI100_25_B_HG: SLOT02.E61(25_B_HG)
SL02_VI100_25_B_HS: SLOT02.F62(25_B_HS) ; also on sheet 41
SL02_VI100_25_LS: SLOT02.B62(25_LS) ; also on sheet 39
SL02_VI100_26_A_HF: SLOT02.F17(26_A_HF) ; also on sheet 41
SL02_VI100_26_A_HG: SLOT02.D43(26_A_HG)
SL02_VI100_26_A_HS: SLOT02.E44(26_A_HS) ; also on sheet 41
SL02_VI100_26_B_HF: SLOT02.F43(26_B_HF) ; also on sheet 40
SL02_VI100_26_B_HG: SLOT02.E43(26_B_HG)
SL02_VI100_26_B_HS: SLOT02.G44(26_B_HS) ; also on sheet 40
SL02_VI100_26_LS: SLOT02.D44(26_LS) ; also on sheet 39
SL02_VI100_27_A_HF: SLOT02.F15(27_A_HF) ; also on sheet 41
SL02_VI100_27_A_HG: SLOT02.D41(27_A_HG)
SL02_VI100_27_A_HS: SLOT02.E42(27_A_HS) ; also on sheet 41
SL02_VI100_27_B_HF: SLOT02.F41(27_B_HF) ; also on sheet 40
SL02_VI100_27_B_HG: SLOT02.E41(27_B_HG)
SL02_VI100_27_B_HS: SLOT02.G42(27_B_HS) ; also on sheet 40
SL02_VI100_27_LS: SLOT02.D42(27_LS) ; also on sheet 39
SL02_VI100_28_A_HF: SLOT02.F13(28_A_HF) ; also on sheet 41
SL02_VI100_28_A_HG: SLOT02.A61(28_A_HG)
SL02_VI100_28_A_HS: SLOT02.A60(28_A_HS) ; also on sheet 41
SL02_VI100_28_B_HF: SLOT02.A57(28_B_HF) ; also on sheet 40
SL02_VI100_28_B_HG: SLOT02.B57(28_B_HG)
SL02_VI100_28_B_HS: SLOT02.A56(28_B_HS) ; also on sheet 40
SL02_VI100_28_LS: SLOT02.A58(28_LS) ; also on sheet 39
SL02_VI100_29_A_HF: SLOT02.F11(29_A_HF) ; also on sheet 41
SL02_VI100_29_A_HG: SLOT02.B53(29_A_HG)
SL02_VI100_29_A_HS: SLOT02.B55(29_A_HS) ; also on sheet 41
SL02_VI100_29_B_HF: SLOT02.A51(29_B_HF) ; also on sheet 40
SL02_VI100_29_B_HG: SLOT02.A53(29_B_HG)
SL02_VI100_29_B_HS: SLOT02.A52(29_B_HS) ; also on sheet 40
SL02_VI100_29_LS: SLOT02.A55(29_LS) ; also on sheet 39
SL02_VI100_30_A_HF: SLOT02.F9(30_A_HF) ; also on sheet 41
SL02_VI100_30_A_HG: SLOT02.A47(30_A_HG)
SL02_VI100_30_A_HS: SLOT02.A48(30_A_HS) ; also on sheet 41
SL02_VI100_30_B_HG: SLOT02.B43(30_B_HG)
SL02_VI100_30_B_HS: SLOT02.A44(30_B_HS) ; also on sheet 41
SL02_VI100_30_LS: SLOT02.A46(30_LS) ; also on sheet 39
SL02_VI100_31_A_HF: SLOT02.F7(31_A_HF) ; also on sheet 40
SL02_VI100_31_A_HG: SLOT02.B41(31_A_HG)
SL02_VI100_31_A_HS: SLOT02.B3(31_A_HS) ; also on sheet 40
SL02_VI100_31_B_HG: SLOT02.C19(31_B_HG)
SL02_VI100_31_B_HS: SLOT02.E19(31_B_HS) ; also on sheet 41
SL02_VI100_31_LS: SLOT02.A3(31_LS) ; also on sheet 39
SL02_VI100_32_A_HF: SLOT02.F5(32_A_HF) ; also on sheet 40
SL02_VI100_32_A_HG: SLOT02.D3(32_A_HG)
SL02_VI100_32_A_HS: SLOT02.D1(32_A_HS) ; also on sheet 40
SL02_VI100_32_B_HG: SLOT02.E3(32_B_HG)
SL02_VI100_32_B_HS: SLOT02.F1(32_B_HS) ; also on sheet 42
SL02_VI100_32_LS: SLOT02.C1(32_LS) ; also on sheet 39
SL06_GND_SENSE: ST1.2 ; also on sheet 15
SL09_FPVI_2_A_LF: SH4.2 ; also on sheet 4 12
SL09_FPVI_2_A_LS: SH4.1 ; also on sheet 4 12
SL10_FPVI_2_6_A_LF: SH2.2 ; also on sheet 3 11
SL10_FPVI_2_A_LS: SH2.1 ; also on sheet 3 11
SL13_GND_SENSE: ST2.2 ; also on sheet 8
SPARE0: SLOT0.A8
SPARE1: SLOT0.G22
SPARE2: SLOT0.A20
SPARE3: SLOT0.G26
SPARE4: SLOT0.A24
SPARE5: SLOT0.G30
SPARE6: SLOT0.A28
SPARE7: SLOT0.G34
SPARE8: SLOT0.A32
SPARE9: SLOT0.G40
SPARE10: SLOT0.A36
SPARE11: SLOT0.F40
SPARE12: SLOT0.C40
SPARE13: SLOT0.E40
SPARE14: SLOT0.D40
SPI_CS_N: SLOT0.E16
SPI_MISO: SLOT0.F18
SPI_MOSI: SLOT0.E18
SPI_SCLK: SLOT0.E14
SYS_SCLK: BR8.2 SLOT0.G14
SYS_SDA: BR9.2 SLOT0.G18
TMU_INPUT_A: SLOT0.B12
TMU_INPUT_B: SLOT0.D12
TMU_REF_GND: 0BS1.1 SLOT0.A37
TMU_TRIGGER: SLOT0.F12
USER_12V: SLOT0.F6 SLOT0.G6
USER_SCLK: SLOT0.F14
USER_SDA: SLOT0.F16
N00304: LD1.1(A) RT1.2
N16304853: CT1.1 F1.2 LT1.1 RT1.1
N16305479: LD3.1(A) RT2.2
N16305515: CT7.1 F2.2 LT3.1 RT2.1
N17370523: BC9.1 BR5.1 BR6.1 BR7.1 BU1.8(VCC)
N17370531: BR6.2 BR9.1 BU1.5(SDA)
N17370539: BR5.2 BR8.1 BU1.6(SCL)

Not connected (* = marked no-connect by the designer): M1 NPTH1* NPTH2* NPTH3* NPTH4* NPTH5* NPTH6* NPTH7* NPTH8* NPTH9* NPTH10* NPTH11* NPTH12* NPTH13* NPTH14* NPTH15* NPTH16* NPTH17* NPTH18* NPTH19* NPTH20* NPTH21* NPTH22* NPTH23* NPTH24* NPTH25* NPTH26* NPTH27* NPTH28* NPTH29* NPTH30* NPTH31* NPTH32* NPTH33* NPTH34* NPTH35* NPTH36* NPTH37*; SLOT0 A1* A42* A43* A44* A45* A46* A47* A48* A49* A50* A51* A52* A53* A54* A55* A56* A57* A58* A59* A60* A61* B1* B42* B43* B44* B45* B46* B47* B48* B49* B50* B51* B52* B53* B54* B55* B56* B57* B58* B59* B60* B61* B62* C1* C42* C43* C44* C45* C46* C47* C48* C49* C50* C51* C52* C53* C54* C55* C56* C57* C58* C59* C60* C61* C62* D1* D42* D43* D44* D45* D46* D47* D48* D49* D50* D51* D52* D53* D54* D55* D56* D57* D58* D59* D60* D61* E1* E42* E43* E44* E45* E46* E47* E48* E49* E50* E51* E52* E53* E54* E55* E56* E57* E58* E59* E60* E61* E62* F1* F42* F43* F44* F45* F46* F47* F48* F49* F50* F51* F52* F53* F54* F55* F56* F57* F58* F59* F60* F61* F62* G42* G44* G46* G48* G50* G52* G54* G56* G58* G60* GH1* GH2* Z5* Z7* Z9* Z11* Z13* Z15* Z17* Z19* Z21* Z23* Z25* Z27* Z29* Z31* Z33* Z35* Z37* Z39* Z41* Z43* Z45* Z47* Z49* Z51* Z53* Z55* Z57* Z59* Z61*; SLOT01 A1(NC_16)* A19(NC_15)* A37(NC30)* A42(NC_30)* A45(NC_14)* A49(NC_13)* A50(NC_29)* A54(NC_28)* A59(NC_12)* B37(NC31)* B42(NC_11)* B44(NC_10)* B46(NC_8)* B48(NC_7)* B50(NC_6)* B52(NC_5)* B54(NC_4)* B56(NC_3)* B58(NC_2)* B60(NC_1)* C37(NC30)* D19(NC_31)* D37(NC31)* E1(NC_32)* E37(NC_9)* E62(NC_25)* F42(NC_27)* F44(NC_26)* F46(NC_24)* F48(NC_23)* F50(NC_22)* F52(NC_21)* F54(NC_20)* F56(NC_19)* F58(NC_18)* F60(NC_17)* NGH1* NGH2* Z5(NC1)* Z7(NC2)* Z9(NC3)* Z11(NC4)* Z13(NC5)* Z15(NC6)* Z17(NC7)* Z19(NC8)* Z21(NC9)* Z23(NC10)* Z25(NC11)* Z27(NC12)* Z29(NC13)* Z31(NC14)* Z33(NC15)* Z35(NC16)* Z37(NC17)* Z39(NC18)* Z41(NC19)* Z43(NC20)* Z45(NC21)* Z47(NC22)* Z49(NC23)* Z51(NC24)* Z53(NC25)* Z55(NC26)* Z57(NC27)* Z59(NC28)* Z61(NC29)*; SLOT02 A1(NC_16)* A19(NC_15)* A37(NC30)* A42(NC_30)* A45(NC_14)* A49(NC_13)* A50(NC_29)* A54(NC_28)* A59(NC_12)* B37(NC31)* B42(NC_11)* B44(NC_10)* B46(NC_8)* B48(NC_7)* B50(NC_6)* B52(NC_5)* B54(NC_4)* B56(NC_3)* B58(NC_2)* B60(NC_1)* C37(NC30)* D19(NC_31)* D37(NC31)* E1(NC_32)* E37(NC_9)* E62(NC_25)* F42(NC_27)* F44(NC_26)* F46(NC_24)* F48(NC_23)* F50(NC_22)* F52(NC_21)* F54(NC_20)* F56(NC_19)* F58(NC_18)* F60(NC_17)* NGH1* NGH2* Z5(NC1)* Z7(NC2)* Z9(NC3)* Z11(NC4)* Z13(NC5)* Z15(NC6)* Z17(NC7)* Z19(NC8)* Z21(NC9)* Z23(NC10)* Z25(NC11)* Z27(NC12)* Z29(NC13)* Z31(NC14)* Z33(NC15)* Z35(NC16)* Z37(NC17)* Z39(NC18)* Z41(NC19)* Z43(NC20)* Z45(NC21)* Z47(NC22)* Z49(NC23)* Z51(NC24)* Z53(NC25)* Z55(NC26)* Z57(NC27)* Z59(NC28)* Z61(NC29)*

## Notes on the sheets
sheet 19
- VI100
sheet 20
- VI100
sheet 21
- SDU
sheet 22
- EEPROM
- FPVI/VI100 Stacking
- connecting the VI100_1_B_HS sense pin and FPVI_1_5_A_LS sense pin close to the FPVI_1_5_A_LF pogo pad on the loadboard.
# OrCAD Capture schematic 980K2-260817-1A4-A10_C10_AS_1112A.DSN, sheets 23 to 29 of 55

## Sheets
23 P0084_S8_DUT: size C
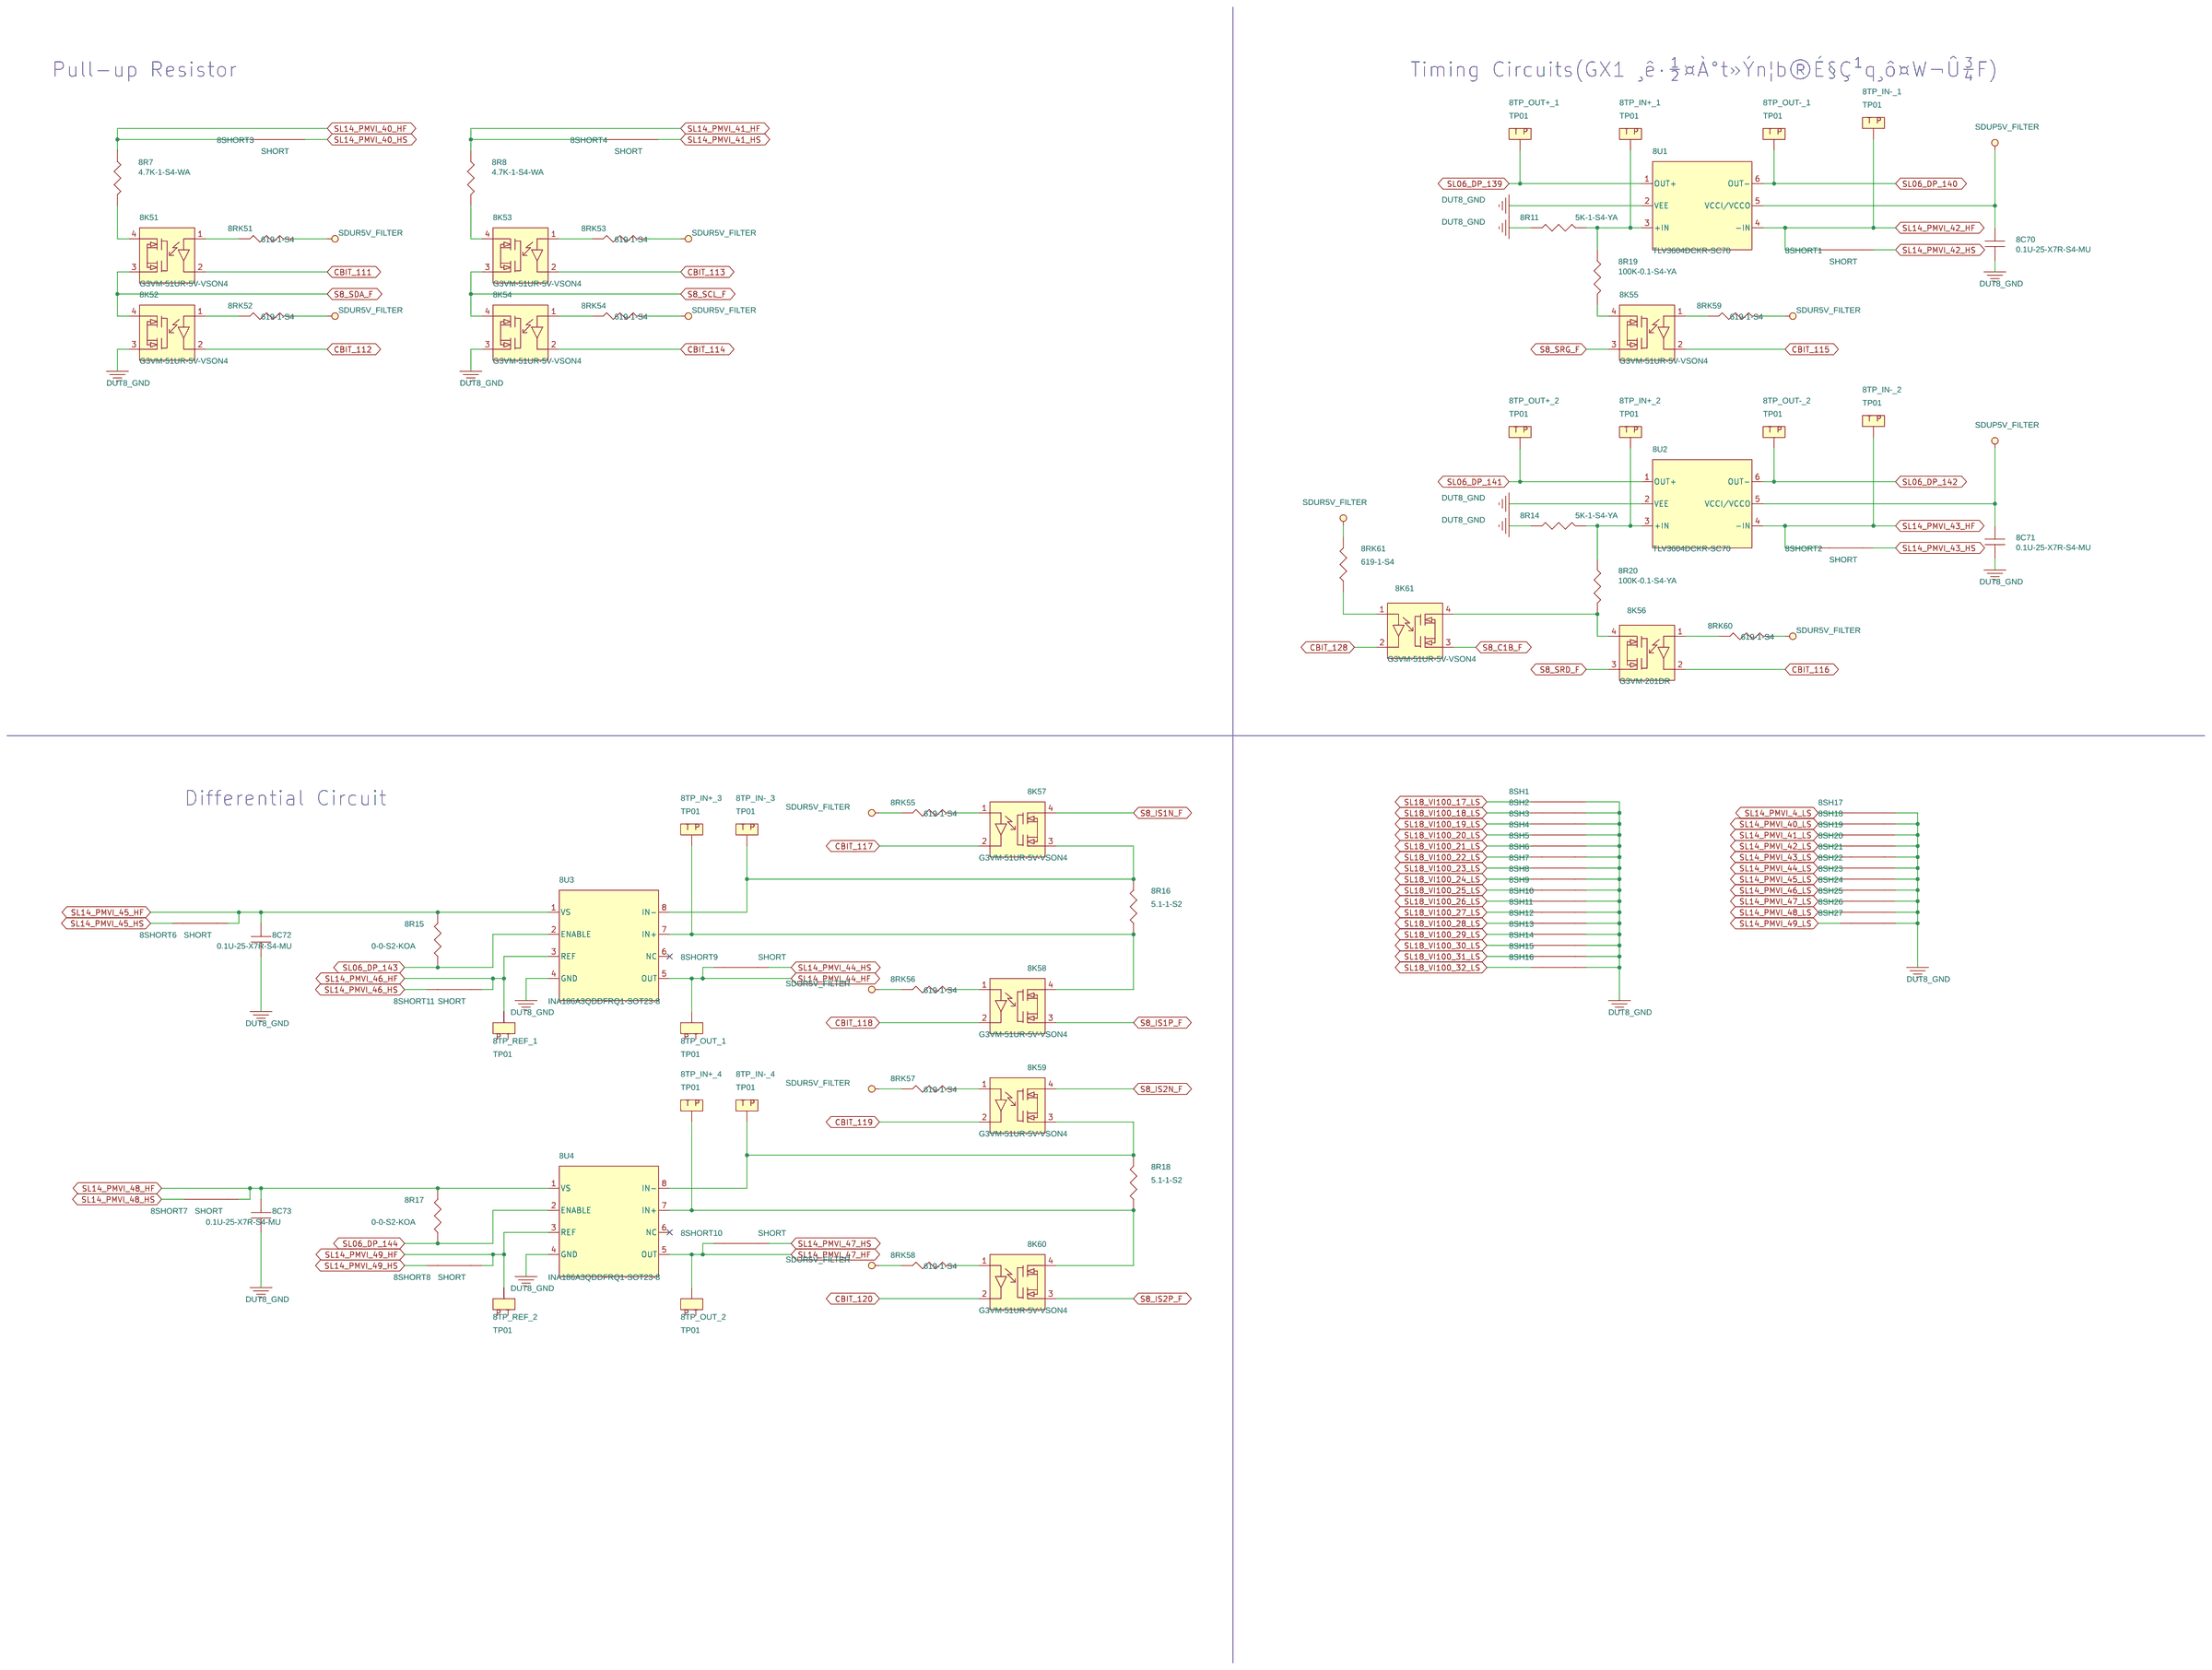
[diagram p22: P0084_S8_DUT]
24 P0083_S8_DUT: size C
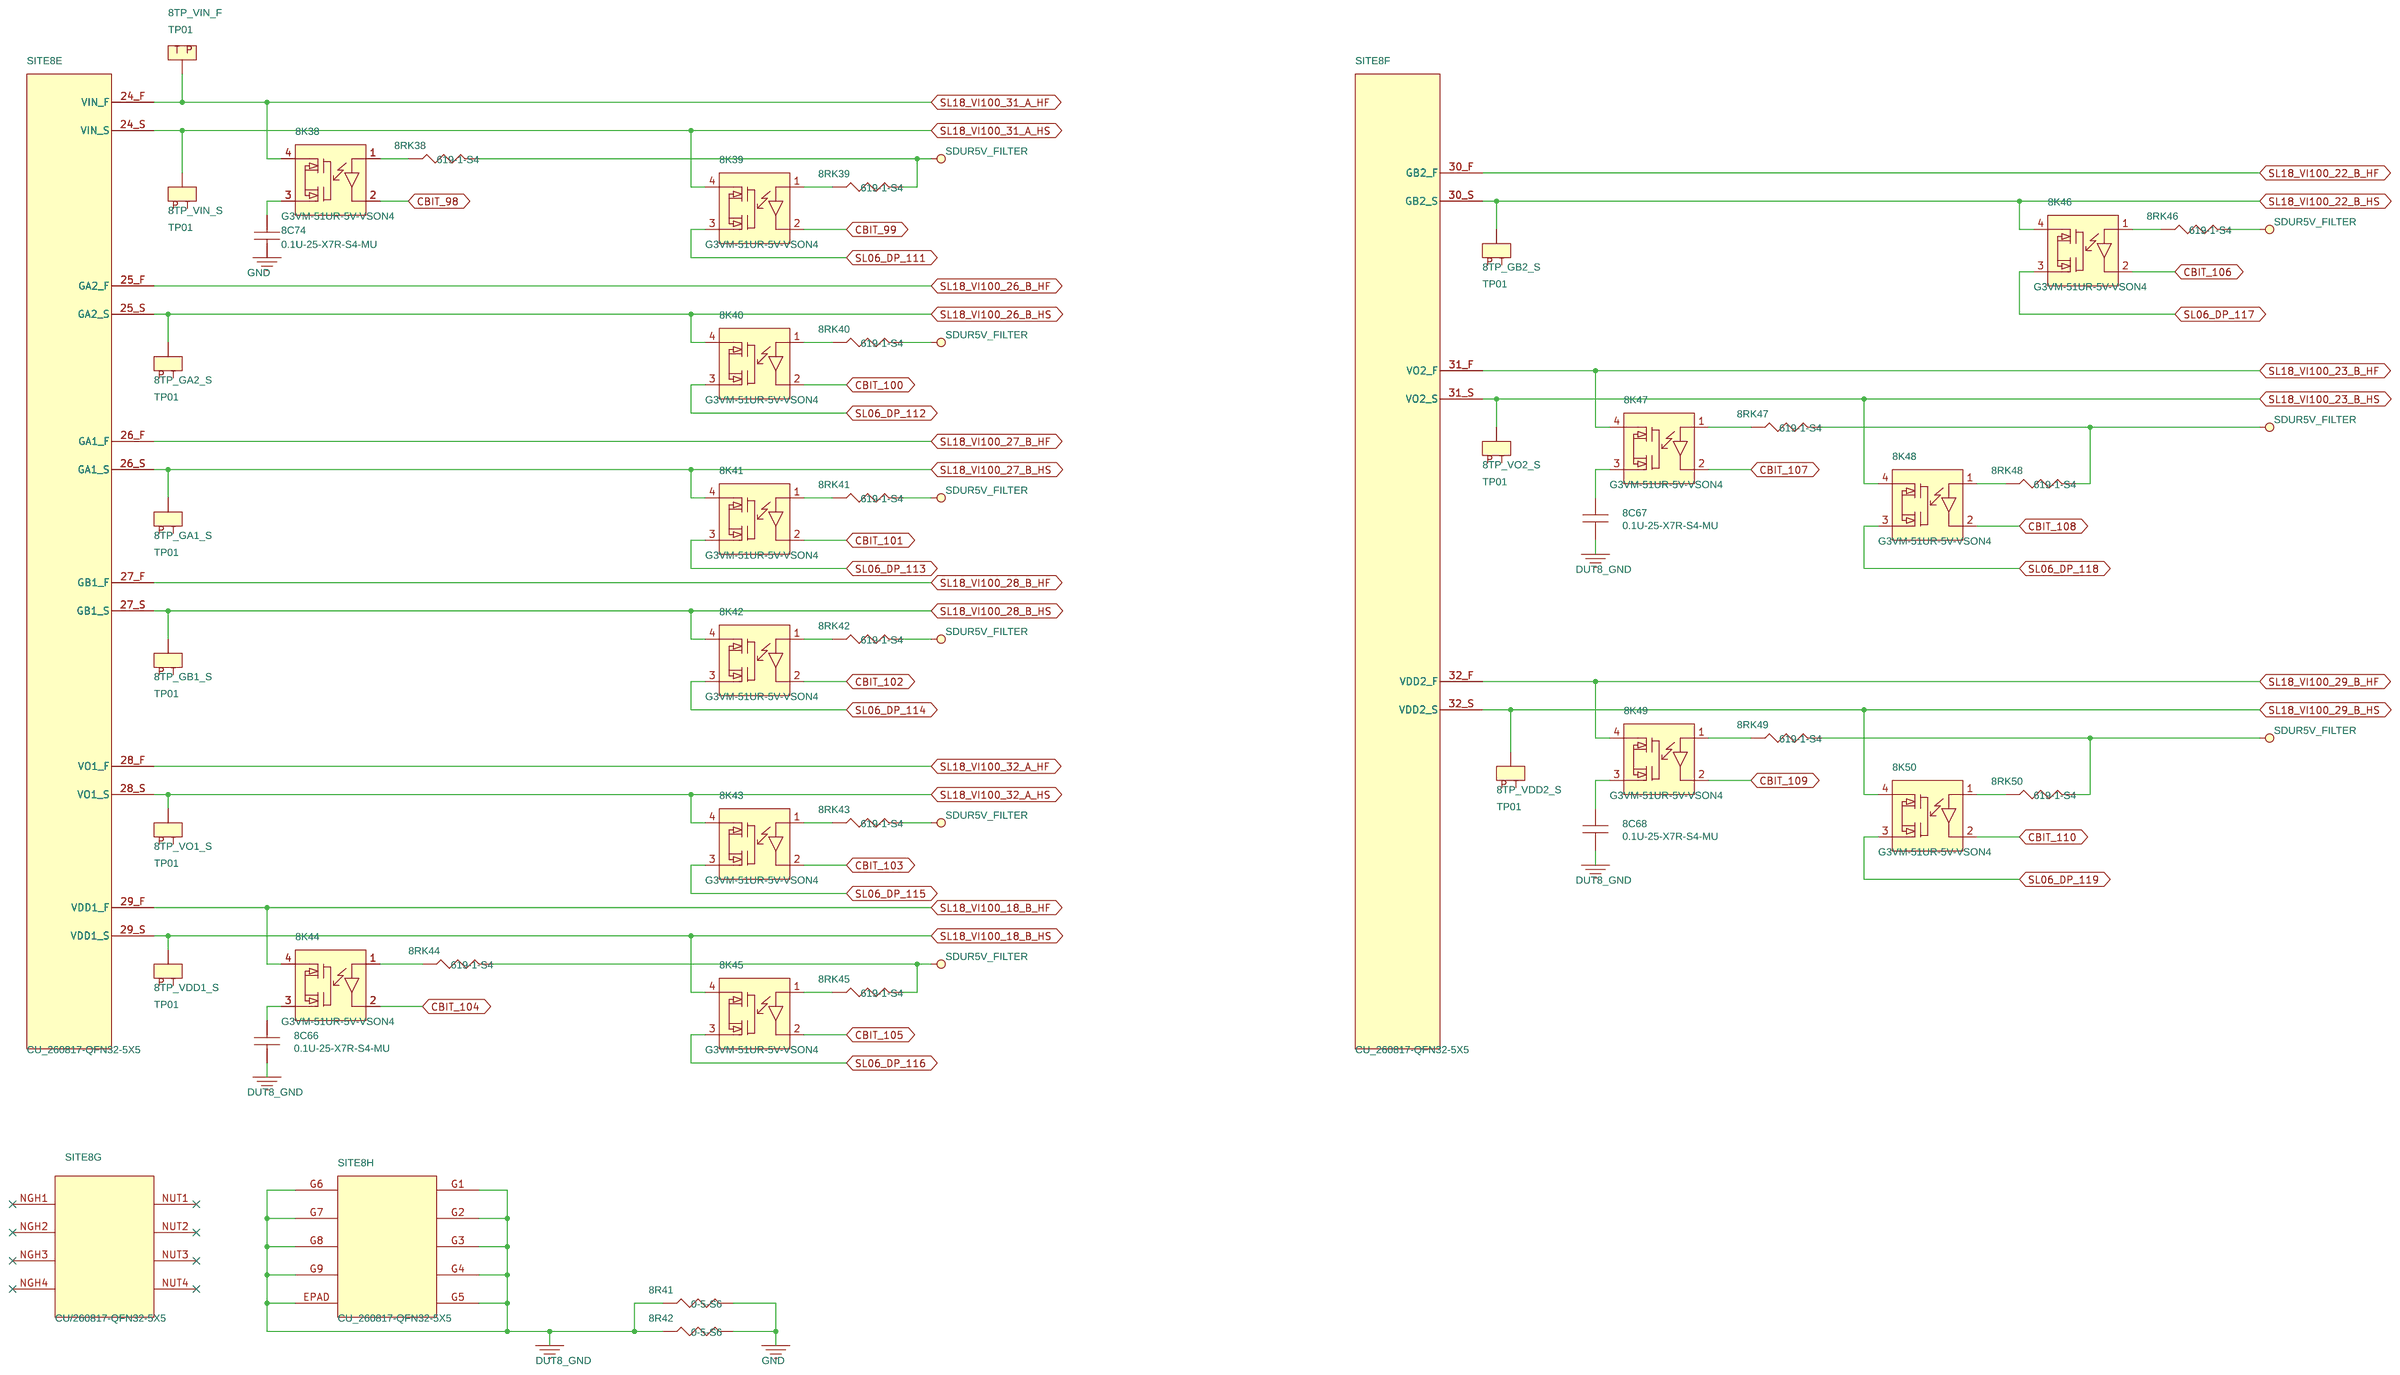
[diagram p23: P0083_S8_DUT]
25 P0082_S8_DUT: size C
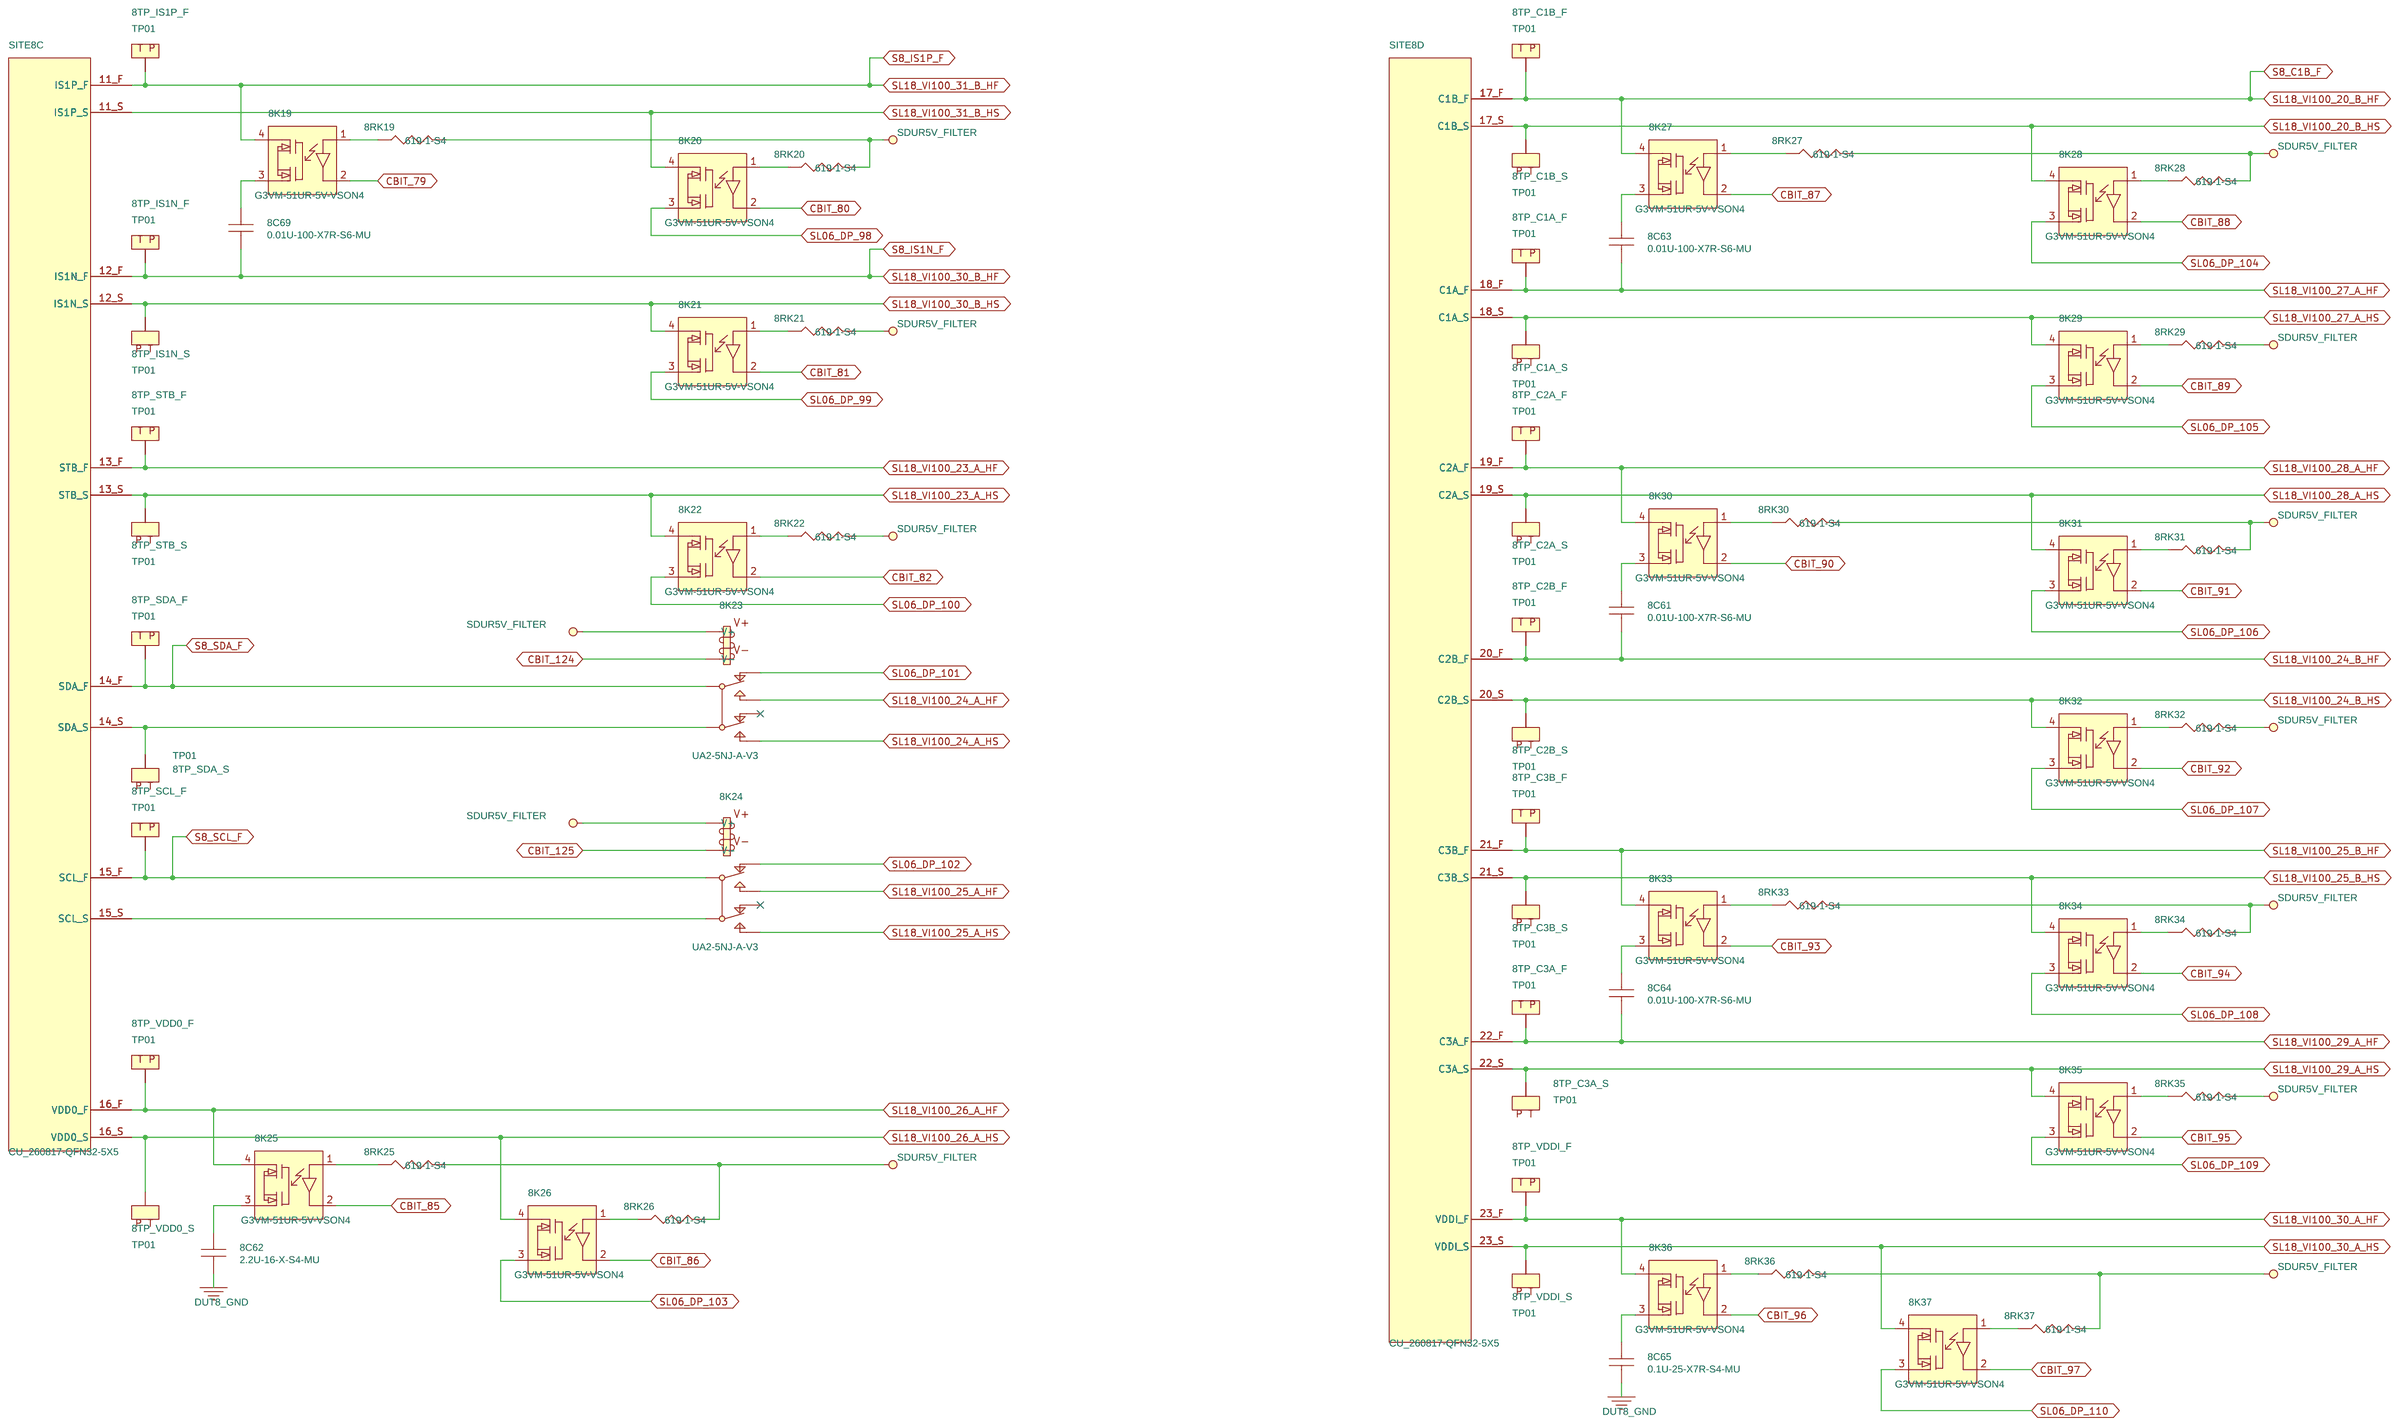
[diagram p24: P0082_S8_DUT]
26 P0081_S8_DUT: size C
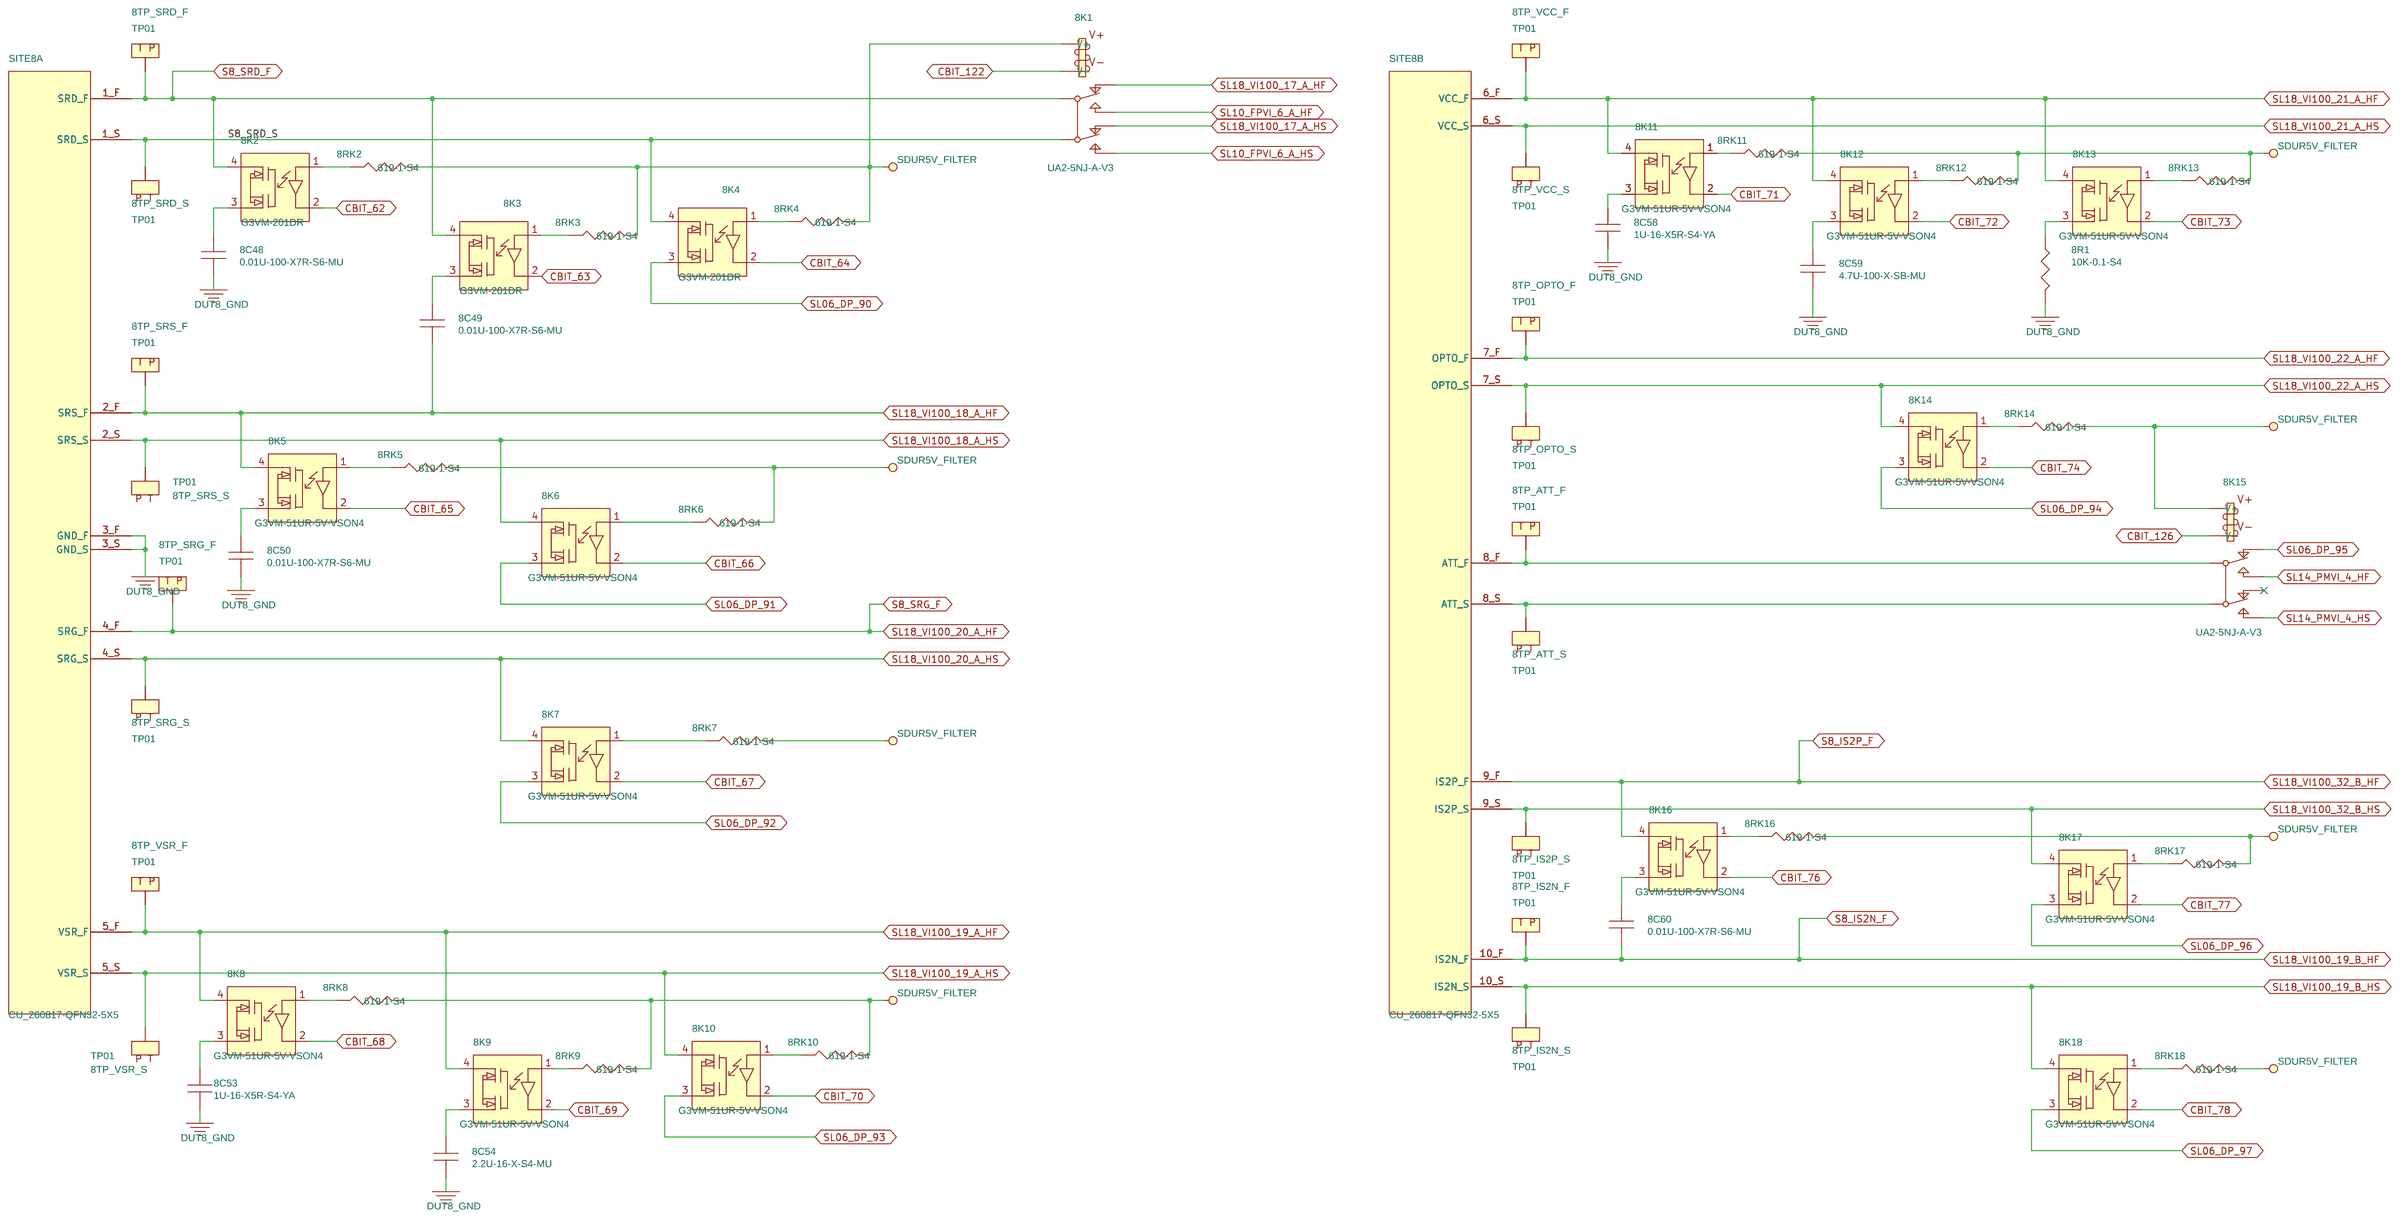
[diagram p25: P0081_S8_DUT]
27 P0074_S7_DUT: size C
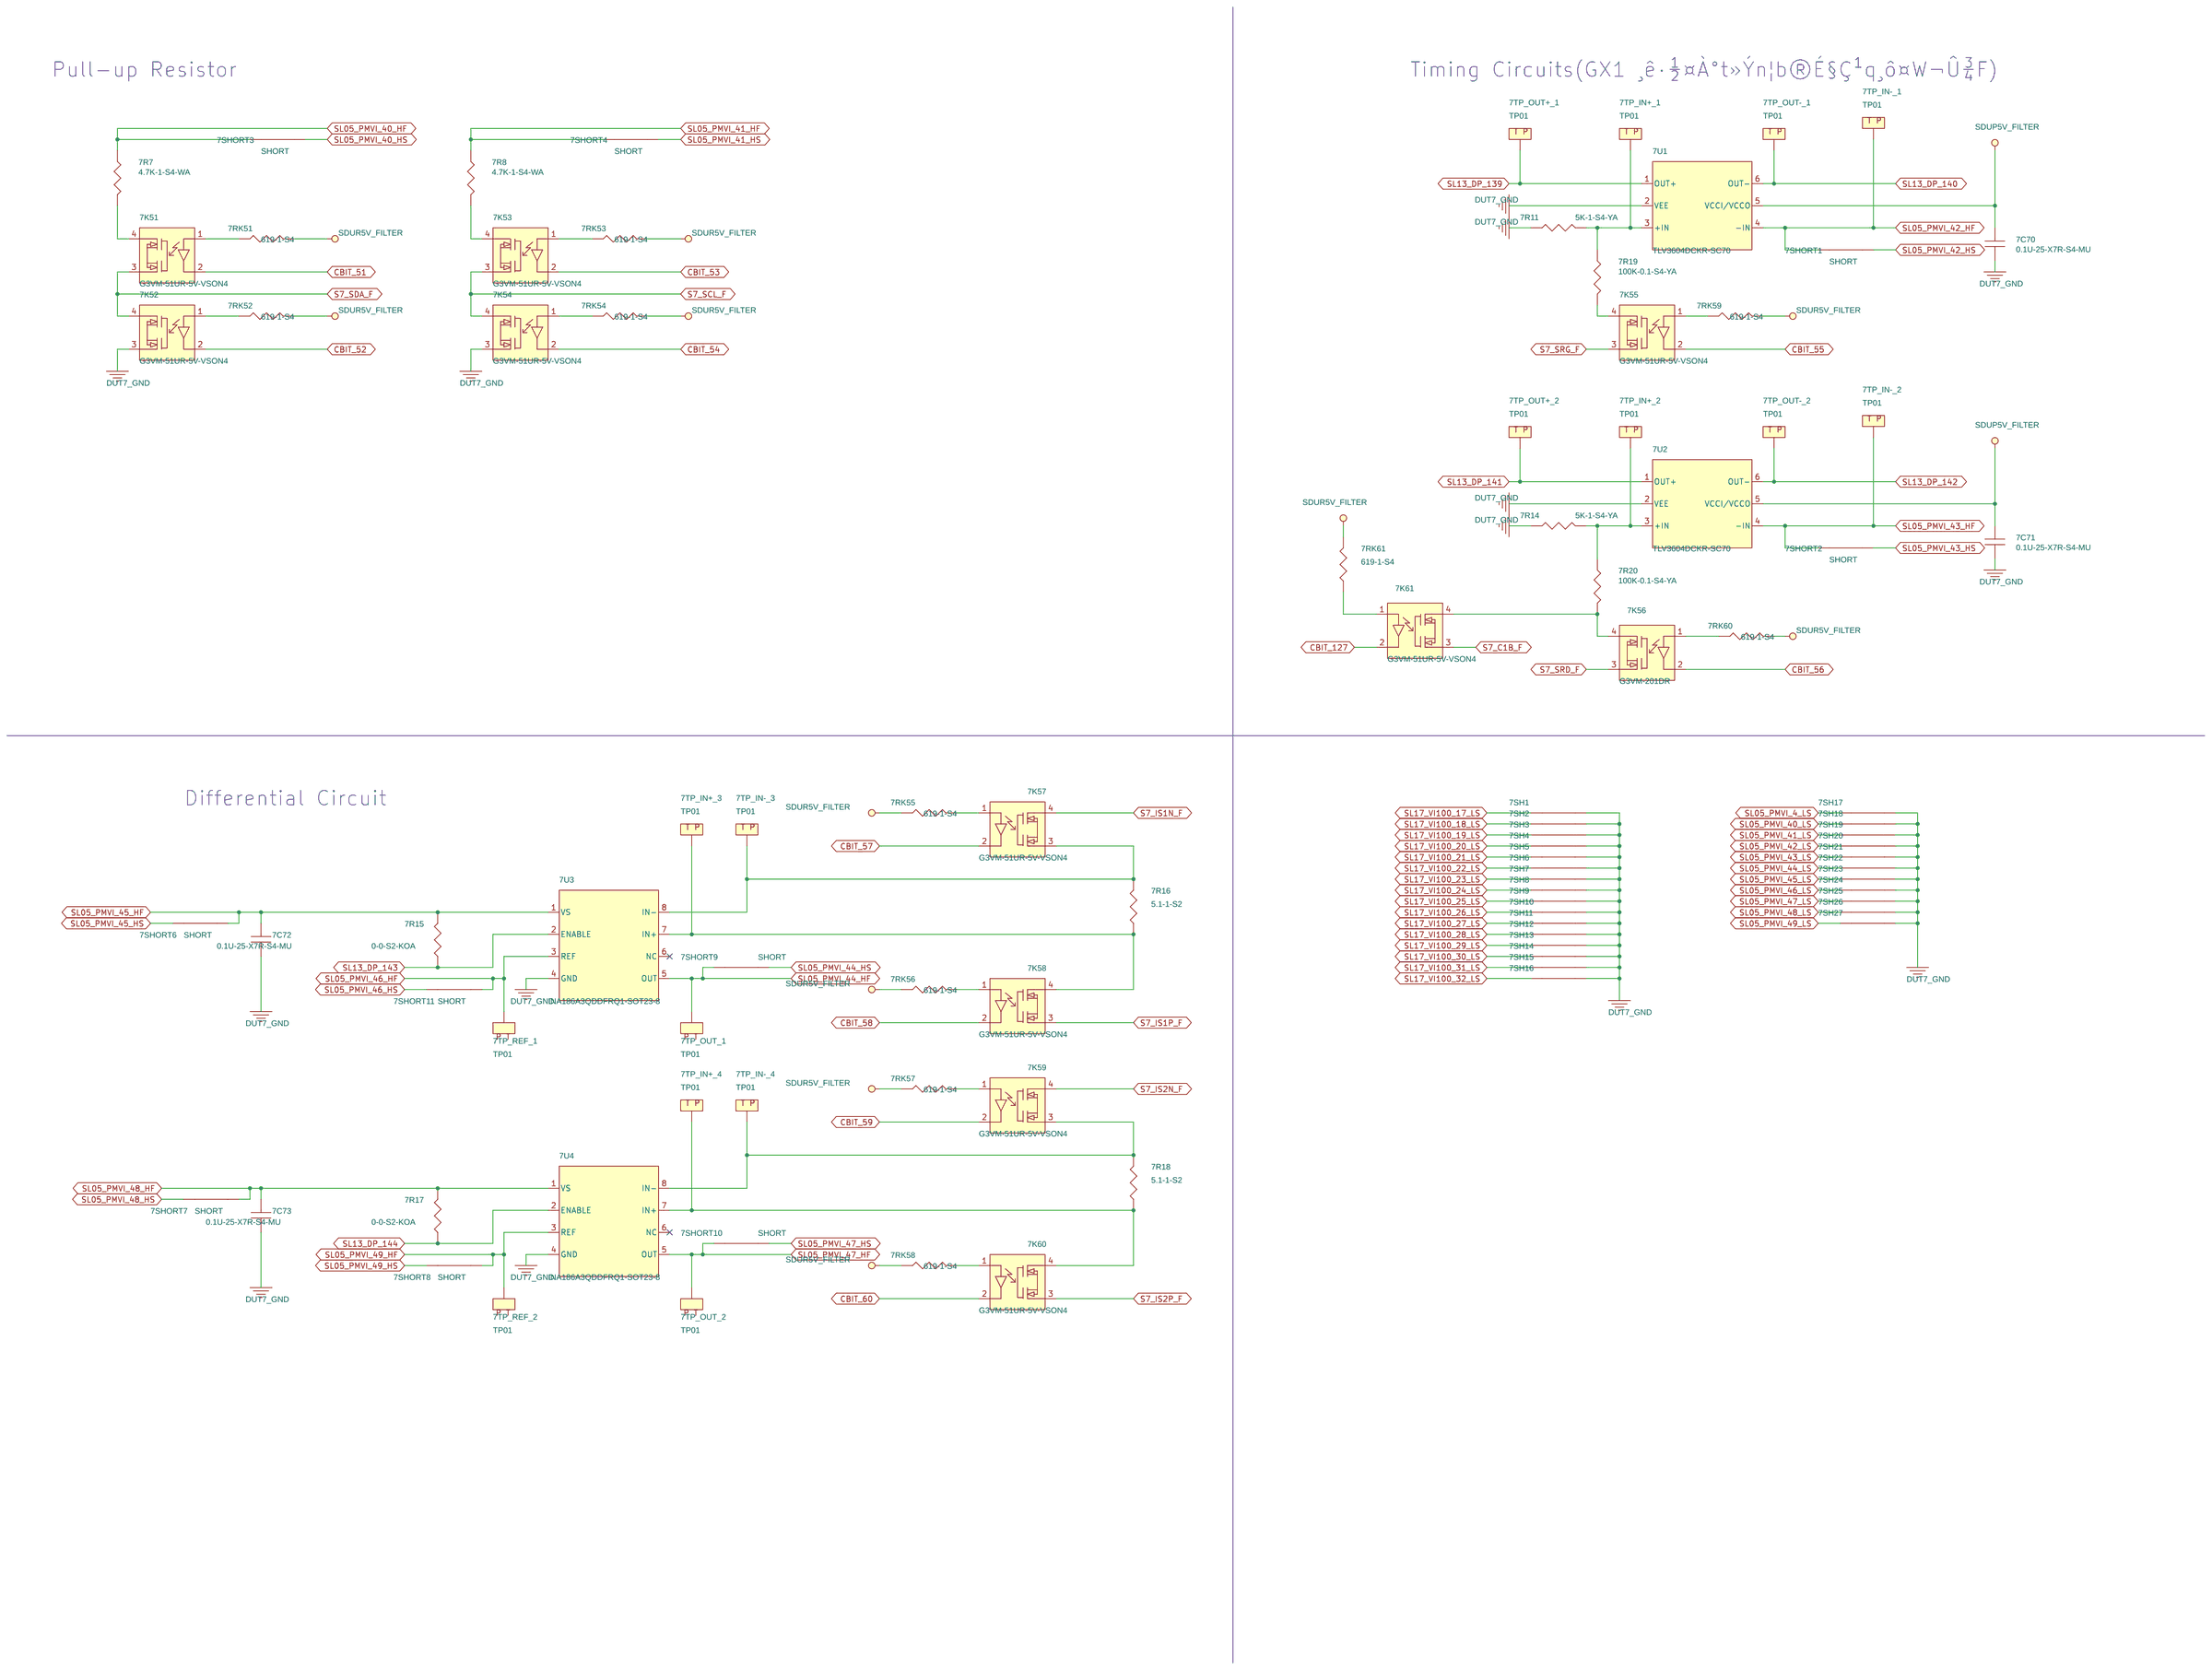
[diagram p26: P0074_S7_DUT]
28 P0073_S7_DUT: size C
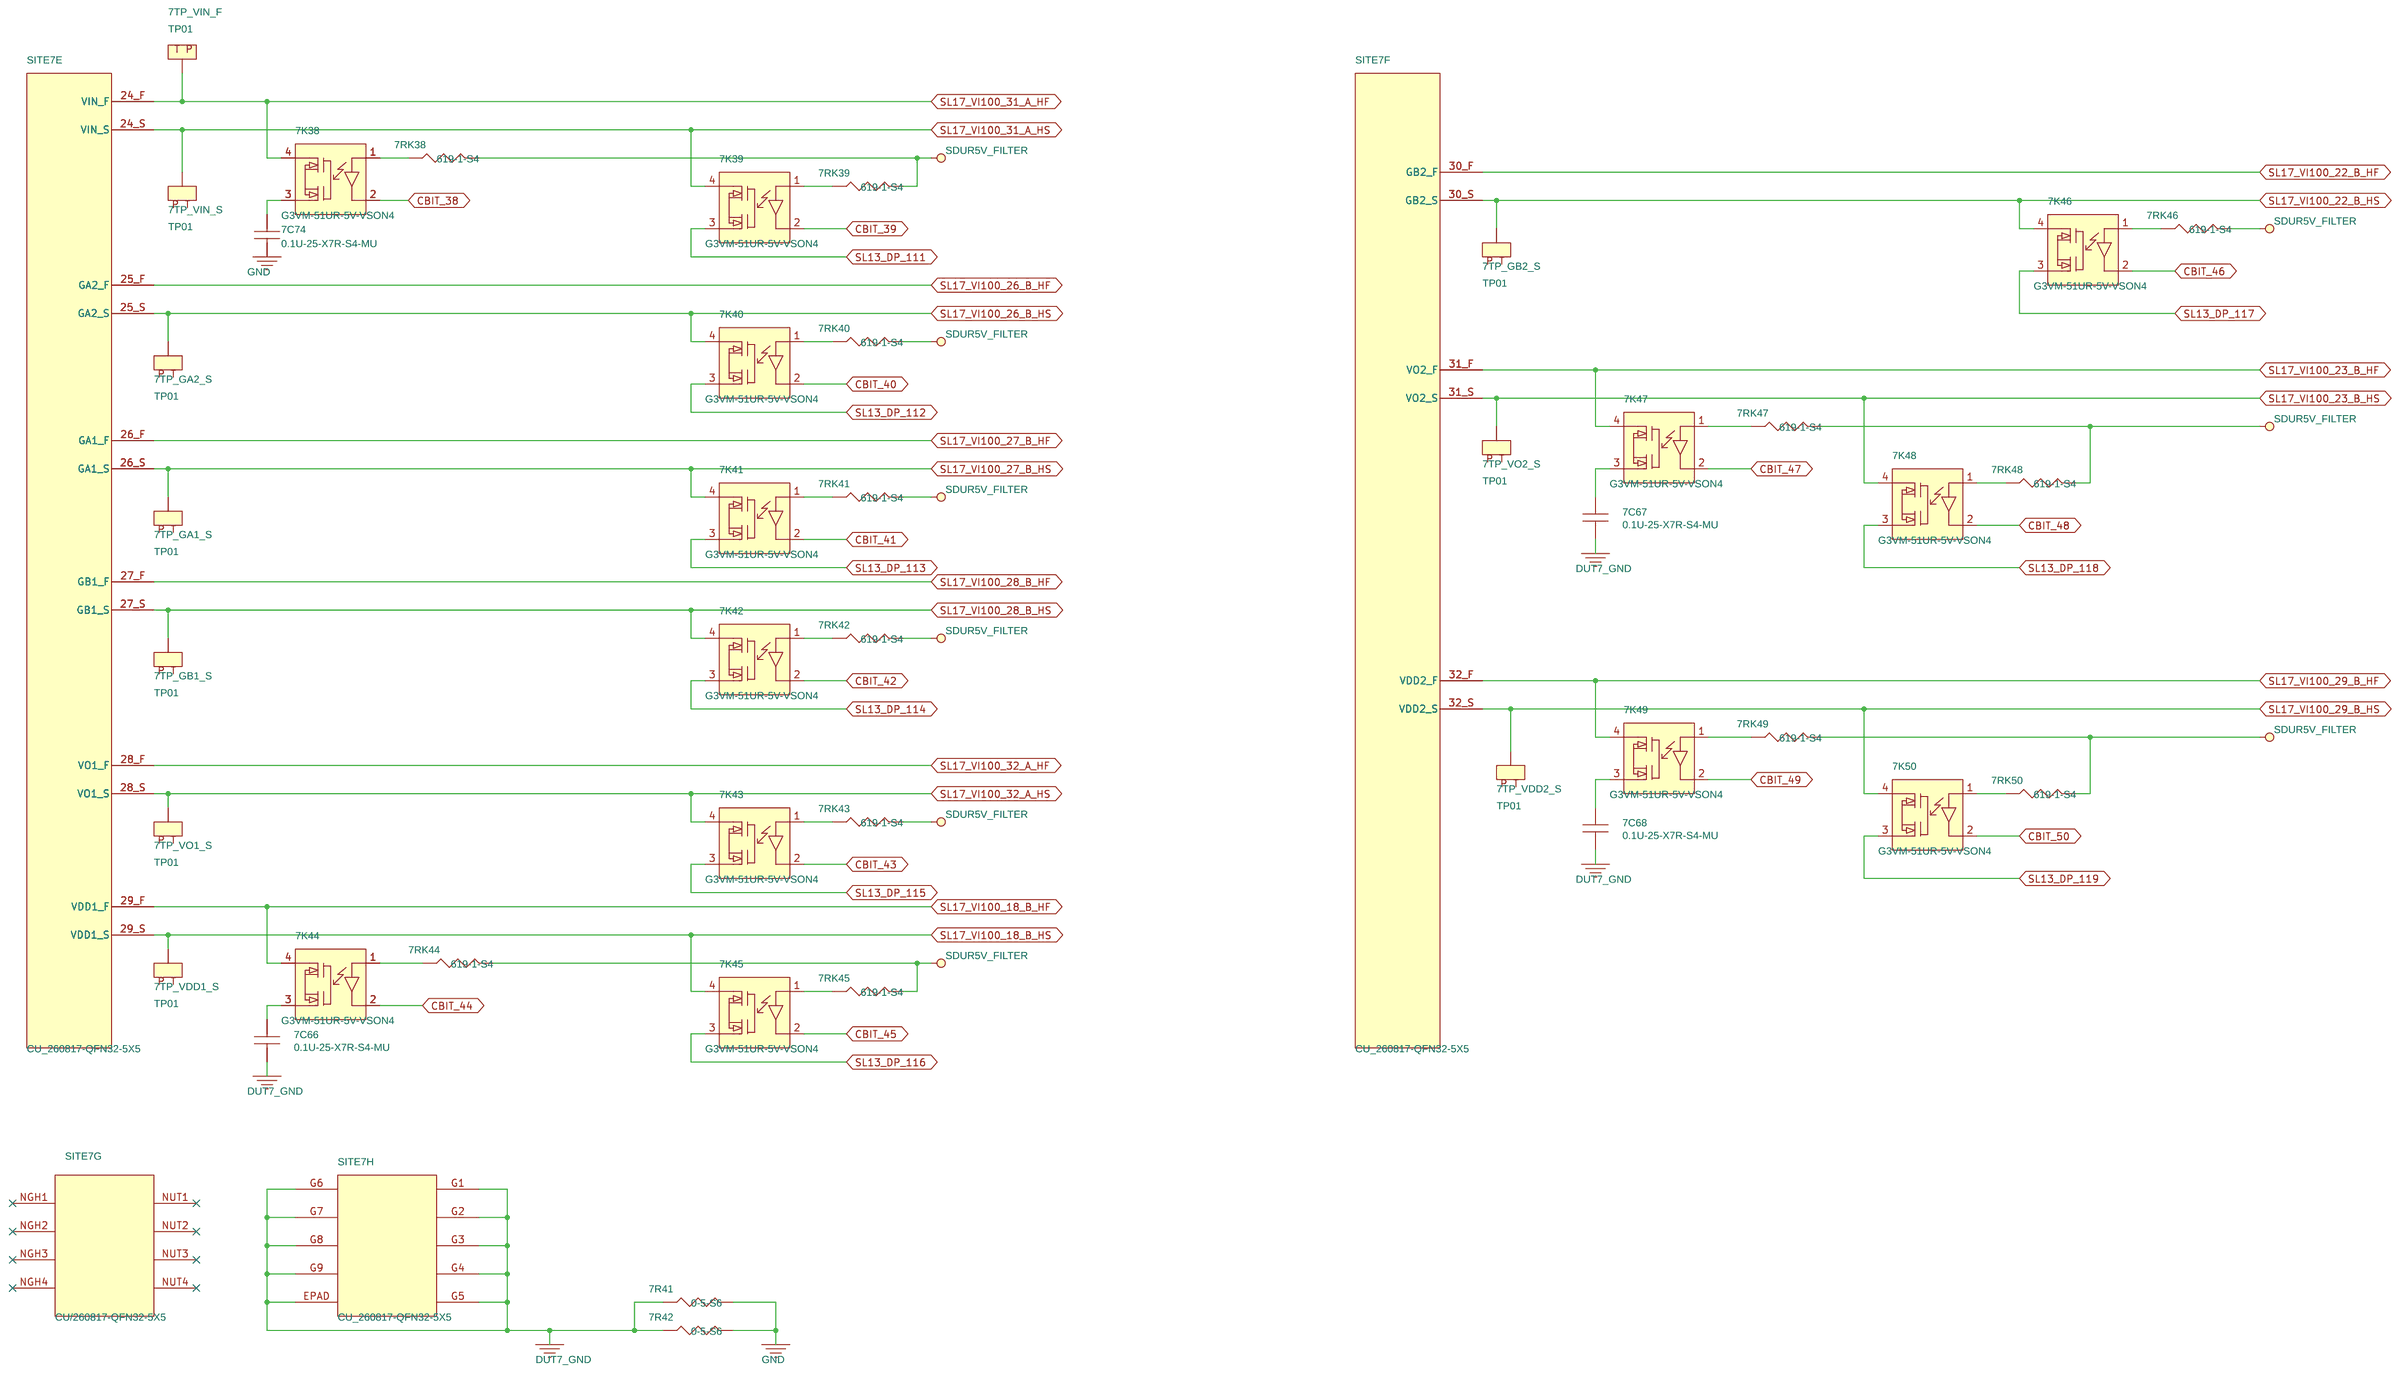
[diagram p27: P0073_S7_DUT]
29 P0072_S7_DUT: size C

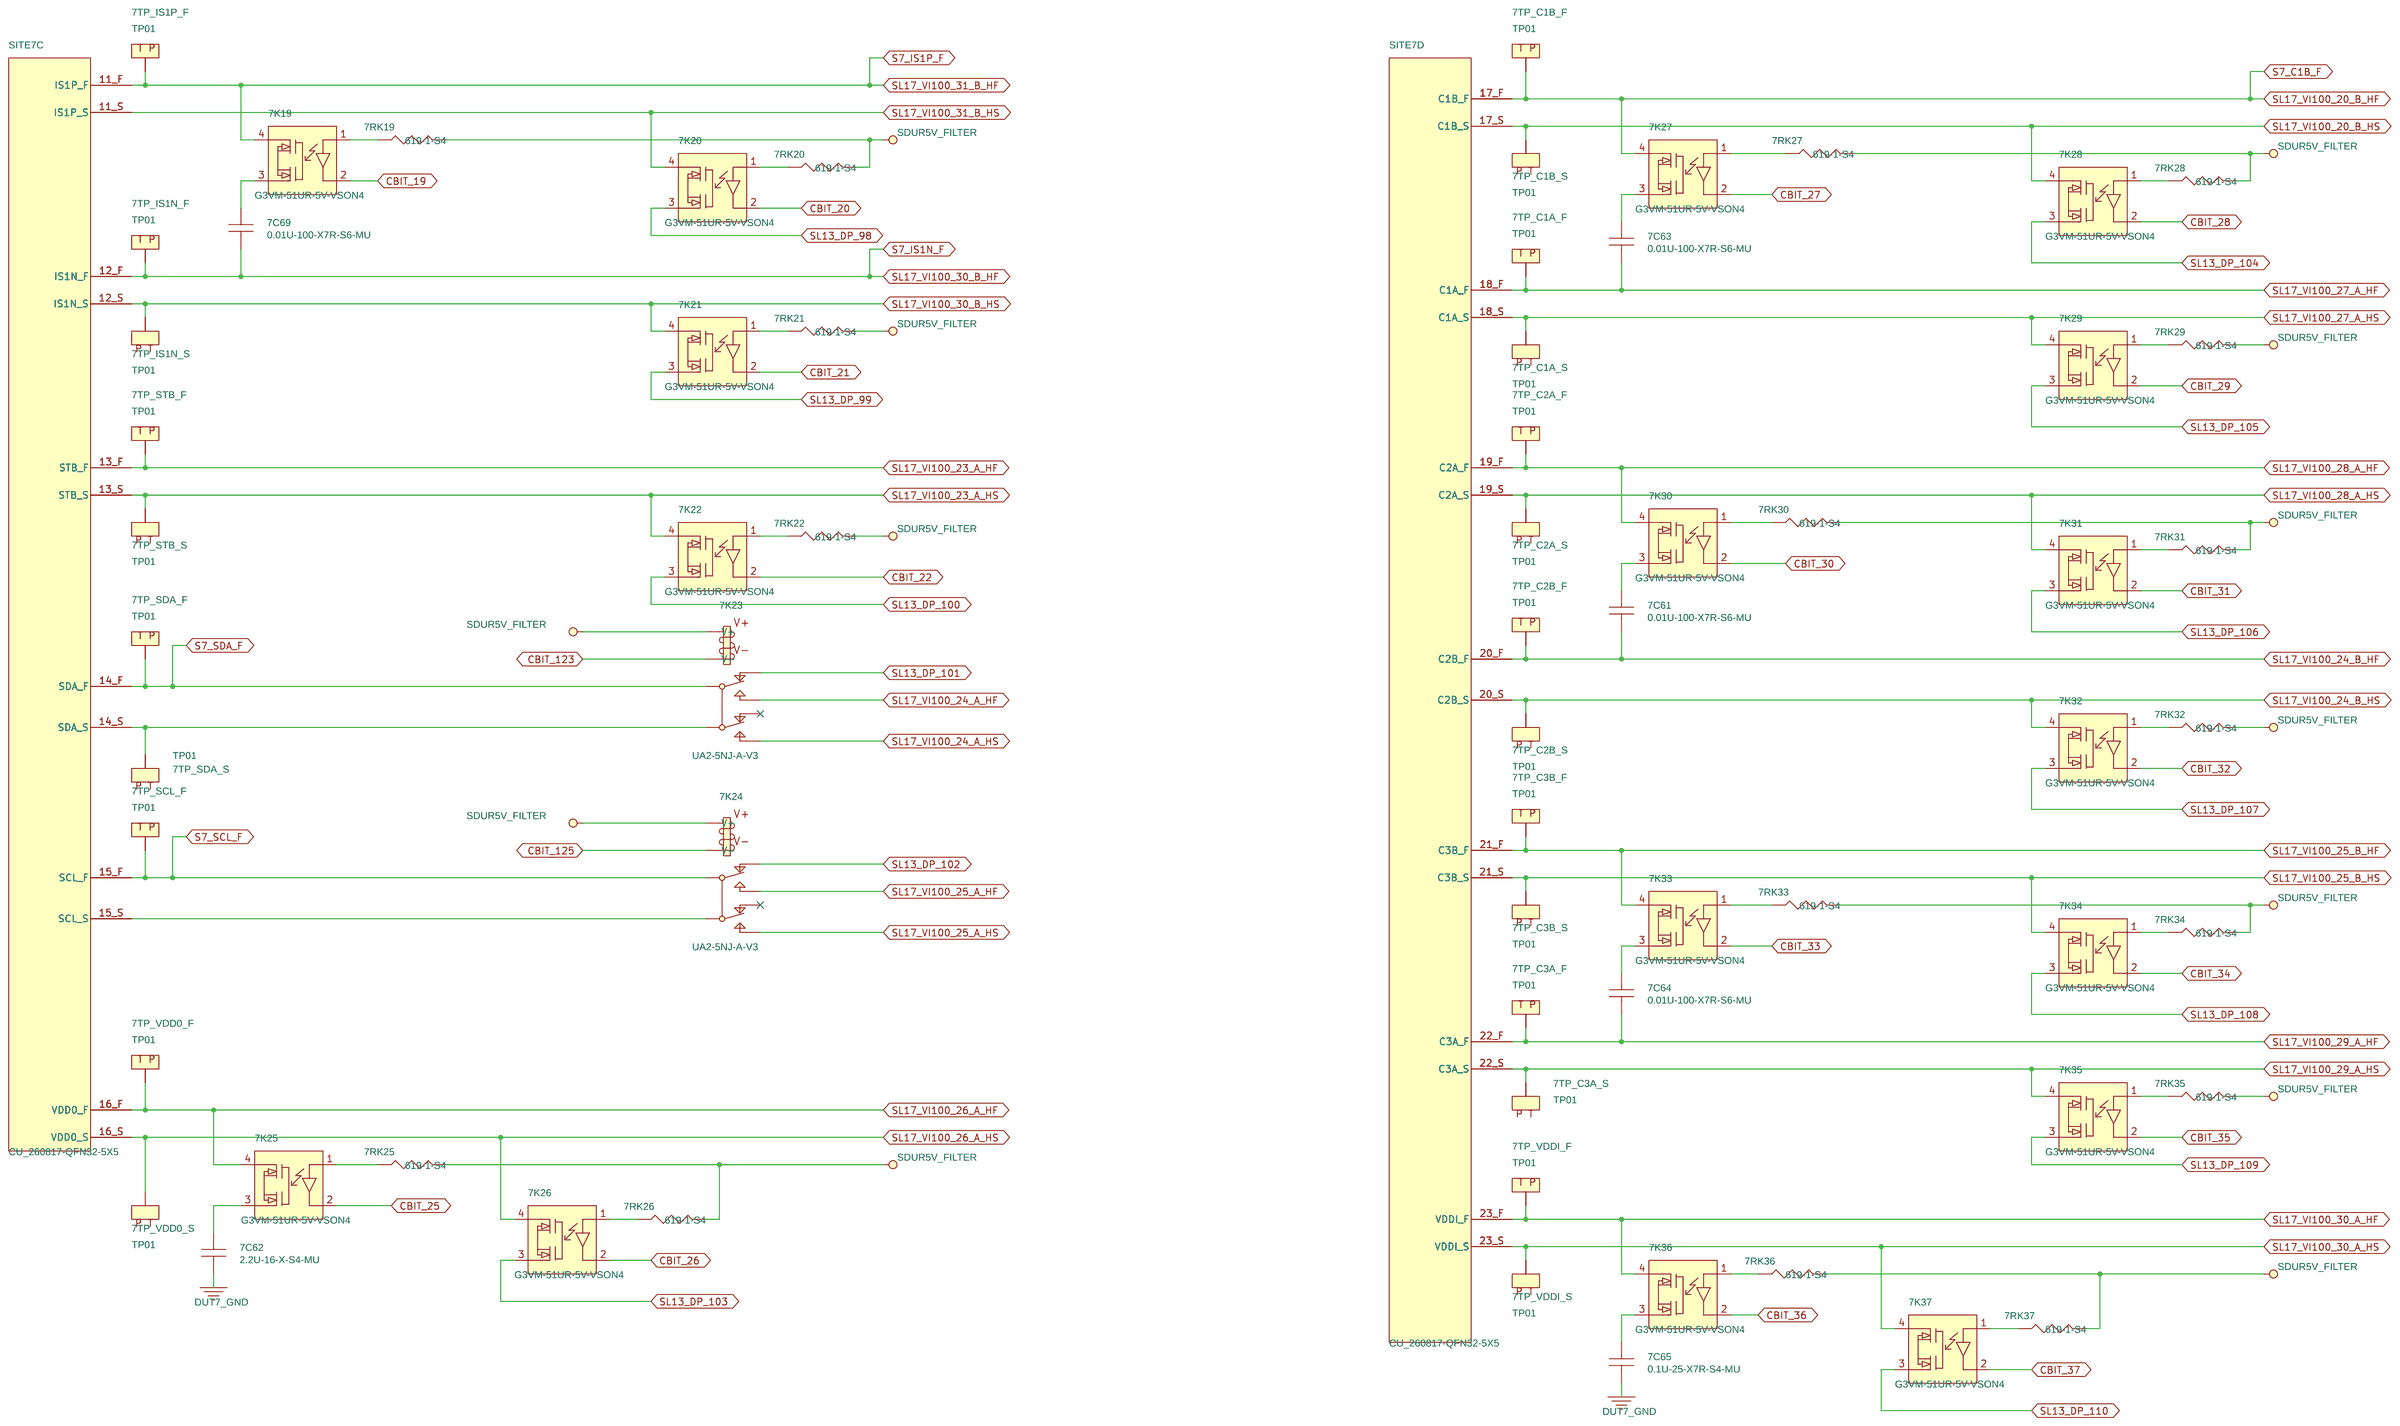
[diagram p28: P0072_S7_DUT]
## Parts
sheet P0072_S7_DUT
7C61  0.01U-100-X7R-S6-MU  [C0603]
7C62  2.2U-16-X-S4-MU  [C0402]
7C63  0.01U-100-X7R-S6-MU  [C0603]
7C64  0.01U-100-X7R-S6-MU  [C0603]
7C65  0.1U-25-X7R-S4-MU  [C0402]
7C69  0.01U-100-X7R-S6-MU  [C0603]
7K19  G3VM-51UR-5V-VSON4  [RL_G3VM_4P_VSON4]
7K20  G3VM-51UR-5V-VSON4  [RL_G3VM_4P_VSON4]
7K21  G3VM-51UR-5V-VSON4  [RL_G3VM_4P_VSON4]
7K22  G3VM-51UR-5V-VSON4  [RL_G3VM_4P_VSON4]
7K23  UA2-5NJ-A-V3  [RL_NECUA2_5V_V3]
7K24  UA2-5NJ-A-V3  [RL_NECUA2_5V_V3]
7K25  G3VM-51UR-5V-VSON4  [RL_G3VM_4P_VSON4]
7K26  G3VM-51UR-5V-VSON4  [RL_G3VM_4P_VSON4]
7K27  G3VM-51UR-5V-VSON4  [RL_G3VM_4P_VSON4]
7K28  G3VM-51UR-5V-VSON4  [RL_G3VM_4P_VSON4]
7K29  G3VM-51UR-5V-VSON4  [RL_G3VM_4P_VSON4]
7K30  G3VM-51UR-5V-VSON4  [RL_G3VM_4P_VSON4]
7K31  G3VM-51UR-5V-VSON4  [RL_G3VM_4P_VSON4]
7K32  G3VM-51UR-5V-VSON4  [RL_G3VM_4P_VSON4]
7K33  G3VM-51UR-5V-VSON4  [RL_G3VM_4P_VSON4]
7K34  G3VM-51UR-5V-VSON4  [RL_G3VM_4P_VSON4]
7K35  G3VM-51UR-5V-VSON4  [RL_G3VM_4P_VSON4]
7K36  G3VM-51UR-5V-VSON4  [RL_G3VM_4P_VSON4]
7K37  G3VM-51UR-5V-VSON4  [RL_G3VM_4P_VSON4]
7RK19  619-1-S4  [R0402]
7RK20  619-1-S4  [R0402]
7RK21  619-1-S4  [R0402]
7RK22  619-1-S4  [R0402]
7RK25  619-1-S4  [R0402]
7RK26  619-1-S4  [R0402]
7RK27  619-1-S4  [R0402]
7RK28  619-1-S4  [R0402]
7RK29  619-1-S4  [R0402]
7RK30  619-1-S4  [R0402]
7RK31  619-1-S4  [R0402]
7RK32  619-1-S4  [R0402]
7RK33  619-1-S4  [R0402]
7RK34  619-1-S4  [R0402]
7RK35  619-1-S4  [R0402]
7RK36  619-1-S4  [R0402]
7RK37  619-1-S4  [R0402]
7TP_C1A_F  TP01  [TP_040_T]
7TP_C1A_S  TP01  [TP_040_T]
7TP_C1B_F  TP01  [TP_040_T]
7TP_C1B_S  TP01  [TP_040_T]
7TP_C2A_F  TP01  [TP_040_T]
7TP_C2A_S  TP01  [TP_040_T]
7TP_C2B_F  TP01  [TP_040_T]
7TP_C2B_S  TP01  [TP_040_T]
7TP_C3A_F  TP01  [TP_040_T]
7TP_C3A_S  TP01  [TP_040_T]
7TP_C3B_F  TP01  [TP_040_T]
7TP_C3B_S  TP01  [TP_040_T]
7TP_IS1N_F  TP01  [TP_040_T]
7TP_IS1N_S  TP01  [TP_040_T]
7TP_IS1P_F  TP01  [TP_040_T]
7TP_SCL_F  TP01  [TP_040_T]
7TP_SDA_F  TP01  [TP_040_T]
7TP_SDA_S  TP01  [TP_040_T]
7TP_STB_F  TP01  [TP_040_T]
7TP_STB_S  TP01  [TP_040_T]
7TP_VDD0_F  TP01  [TP_040_T]
7TP_VDD0_S  TP01  [TP_040_T]
7TP_VDDI_F  TP01  [TP_040_T]
7TP_VDDI_S  TP01  [TP_040_T]
sheet P0073_S7_DUT
7C66  0.1U-25-X7R-S4-MU  [C0402]
7C67  0.1U-25-X7R-S4-MU  [C0402]
7C68  0.1U-25-X7R-S4-MU  [C0402]
7C74  0.1U-25-X7R-S4-MU  [C0402]
7K38  G3VM-51UR-5V-VSON4  [RL_G3VM_4P_VSON4]
7K39  G3VM-51UR-5V-VSON4  [RL_G3VM_4P_VSON4]
7K40  G3VM-51UR-5V-VSON4  [RL_G3VM_4P_VSON4]
7K41  G3VM-51UR-5V-VSON4  [RL_G3VM_4P_VSON4]
7K42  G3VM-51UR-5V-VSON4  [RL_G3VM_4P_VSON4]
7K43  G3VM-51UR-5V-VSON4  [RL_G3VM_4P_VSON4]
7K44  G3VM-51UR-5V-VSON4  [RL_G3VM_4P_VSON4]
7K45  G3VM-51UR-5V-VSON4  [RL_G3VM_4P_VSON4]
7K46  G3VM-51UR-5V-VSON4  [RL_G3VM_4P_VSON4]
7K47  G3VM-51UR-5V-VSON4  [RL_G3VM_4P_VSON4]
7K48  G3VM-51UR-5V-VSON4  [RL_G3VM_4P_VSON4]
7K49  G3VM-51UR-5V-VSON4  [RL_G3VM_4P_VSON4]
7K50  G3VM-51UR-5V-VSON4  [RL_G3VM_4P_VSON4]
7R41  0-5-S6  [R0603]
7R42  0-5-S6  [R0603]
7RK38  619-1-S4  [R0402]
7RK39  619-1-S4  [R0402]
7RK40  619-1-S4  [R0402]
7RK41  619-1-S4  [R0402]
7RK42  619-1-S4  [R0402]
7RK43  619-1-S4  [R0402]
7RK44  619-1-S4  [R0402]
7RK45  619-1-S4  [R0402]
7RK46  619-1-S4  [R0402]
7RK47  619-1-S4  [R0402]
7RK48  619-1-S4  [R0402]
7RK49  619-1-S4  [R0402]
7RK50  619-1-S4  [R0402]
7TP_GA1_S  TP01  [TP_040_T]
7TP_GA2_S  TP01  [TP_040_T]
7TP_GB1_S  TP01  [TP_040_T]
7TP_GB2_S  TP01  [TP_040_T]
7TP_VDD1_S  TP01  [TP_040_T]
7TP_VDD2_S  TP01  [TP_040_T]
7TP_VIN_F  TP01  [TP_040_T]
7TP_VIN_S  TP01  [TP_040_T]
7TP_VO1_S  TP01  [TP_040_T]
7TP_VO2_S  TP01  [TP_040_T]
SITE7  CU_260817-QFN32-5X5  [SK_QFN5x5_64P_0P5MM_JG_260817]  (sections A,B,C,D,E,F,G,H)
sheet P0074_S7_DUT
7C70  0.1U-25-X7R-S4-MU  [C0402]
7C71  0.1U-25-X7R-S4-MU  [C0402]
7C72  0.1U-25-X7R-S4-MU  [C0402]
7C73  0.1U-25-X7R-S4-MU  [C0402]
7K51  G3VM-51UR-5V-VSON4  [RL_G3VM_4P_VSON4]
7K52  G3VM-51UR-5V-VSON4  [RL_G3VM_4P_VSON4]
7K53  G3VM-51UR-5V-VSON4  [RL_G3VM_4P_VSON4]
7K54  G3VM-51UR-5V-VSON4  [RL_G3VM_4P_VSON4]
7K55  G3VM-51UR-5V-VSON4  [RL_G3VM_4P_VSON4]
7K56  G3VM-201DR  [RL_G3VM201DR_200V]
7K57  G3VM-51UR-5V-VSON4  [RL_G3VM_4P_VSON4]
7K58  G3VM-51UR-5V-VSON4  [RL_G3VM_4P_VSON4]
7K59  G3VM-51UR-5V-VSON4  [RL_G3VM_4P_VSON4]
7K60  G3VM-51UR-5V-VSON4  [RL_G3VM_4P_VSON4]
7K61  G3VM-51UR-5V-VSON4  [RL_G3VM_4P_VSON4]
7R7  4.7K-1-S4-WA  [R0402]
7R8  4.7K-1-S4-WA  [R0402]
7R11  5K-1-S4-YA  [R0402]
7R14  5K-1-S4-YA  [R0402]
7R15  0-0-S2-KOA  [R0201]
7R16  5.1-1-S2  [R0201]
7R17  0-0-S2-KOA  [R0201]
7R18  5.1-1-S2  [R0201]
7R19  100K-0.1-S4-YA  [R0402]
7R20  100K-0.1-S4-YA  [R0402]
7RK51  619-1-S4  [R0402]
7RK52  619-1-S4  [R0402]
7RK53  619-1-S4  [R0402]
7RK54  619-1-S4  [R0402]
7RK55  619-1-S4  [R0402]
7RK56  619-1-S4  [R0402]
7RK57  619-1-S4  [R0402]
7RK58  619-1-S4  [R0402]
7RK59  619-1-S4  [R0402]
7RK60  619-1-S4  [R0402]
7RK61  619-1-S4  [R0402]
7SH1  SHORT  [DEFAULT_SHORT_SMALL]
7SH2  SHORT  [DEFAULT_SHORT_SMALL]
7SH3  SHORT  [DEFAULT_SHORT_SMALL]
7SH4  SHORT  [DEFAULT_SHORT_SMALL]
7SH5  SHORT  [DEFAULT_SHORT_SMALL]
7SH6  SHORT  [DEFAULT_SHORT_SMALL]
7SH7  SHORT  [DEFAULT_SHORT_SMALL]
7SH8  SHORT  [DEFAULT_SHORT_SMALL]
7SH9  SHORT  [DEFAULT_SHORT_SMALL]
7SH10  SHORT  [DEFAULT_SHORT_SMALL]
7SH11  SHORT  [DEFAULT_SHORT_SMALL]
7SH12  SHORT  [DEFAULT_SHORT_SMALL]
7SH13  SHORT  [DEFAULT_SHORT_SMALL]
7SH14  SHORT  [DEFAULT_SHORT_SMALL]
7SH15  SHORT  [DEFAULT_SHORT_SMALL]
7SH16  SHORT  [DEFAULT_SHORT_SMALL]
7SH17  SHORT  [DEFAULT_SHORT_SMALL]
7SH18  SHORT  [DEFAULT_SHORT_SMALL]
7SH19  SHORT  [DEFAULT_SHORT_SMALL]
7SH20  SHORT  [DEFAULT_SHORT_SMALL]
7SH21  SHORT  [DEFAULT_SHORT_SMALL]
7SH22  SHORT  [DEFAULT_SHORT_SMALL]
7SH23  SHORT  [DEFAULT_SHORT_SMALL]
7SH24  SHORT  [DEFAULT_SHORT_SMALL]
7SH25  SHORT  [DEFAULT_SHORT_SMALL]
7SH26  SHORT  [DEFAULT_SHORT_SMALL]
7SH27  SHORT  [DEFAULT_SHORT_SMALL]
7SHORT1  SHORT  [DEFAULT_SHORT_SMALL]
7SHORT2  SHORT  [DEFAULT_SHORT_SMALL]
7SHORT3  SHORT  [DEFAULT_SHORT_SMALL]
7SHORT4  SHORT  [DEFAULT_SHORT_SMALL]
7SHORT6  SHORT  [DEFAULT_SHORT_SMALL]
7SHORT7  SHORT  [DEFAULT_SHORT_SMALL]
7SHORT8  SHORT  [DEFAULT_SHORT_SMALL]
7SHORT9  SHORT  [DEFAULT_SHORT_SMALL]
7SHORT10  SHORT  [DEFAULT_SHORT_SMALL]
7SHORT11  SHORT  [DEFAULT_SHORT_SMALL]
7TP_IN+_1  TP01  [TP_040_T]
7TP_IN+_2  TP01  [TP_040_T]
7TP_IN+_3  TP01  [TP_040_T]
7TP_IN+_4  TP01  [TP_040_T]
7TP_IN-_1  TP01  [TP_040_T]
7TP_IN-_2  TP01  [TP_040_T]
7TP_IN-_3  TP01  [TP_040_T]
7TP_IN-_4  TP01  [TP_040_T]
7TP_OUT+_1  TP01  [TP_040_T]
7TP_OUT+_2  TP01  [TP_040_T]
7TP_OUT-_1  TP01  [TP_040_T]
7TP_OUT-_2  TP01  [TP_040_T]
7TP_OUT_1  TP01  [TP_040_T]
7TP_OUT_2  TP01  [TP_040_T]
7TP_REF_1  TP01  [TP_040_T]
7TP_REF_2  TP01  [TP_040_T]
7U1  TLV3604DCKR-SC70  [SC70]
7U2  TLV3604DCKR-SC70  [SC70]
7U3  INA186A3QDDFRQ1-SOT23-8  [SOT23_8P_0P65MM_H1P3MM]
7U4  INA186A3QDDFRQ1-SOT23-8  [SOT23_8P_0P65MM_H1P3MM]
sheet P0081_S8_DUT
8C48  0.01U-100-X7R-S6-MU  [C0603]
8C49  0.01U-100-X7R-S6-MU  [C0603]
8C50  0.01U-100-X7R-S6-MU  [C0603]
8C53  1U-16-X5R-S4-YA  [C0402]
8C54  2.2U-16-X-S4-MU  [C0402]
8C58  1U-16-X5R-S4-YA  [C0402]
8C59  4.7U-100-X-SB-MU  [C1210]
8C60  0.01U-100-X7R-S6-MU  [C0603]
8K1  UA2-5NJ-A-V3  [RL_NECUA2_5V_V3]
8K2  G3VM-201DR  [RL_G3VM201DR_200V]
8K3  G3VM-201DR  [RL_G3VM201DR_200V]
8K4  G3VM-201DR  [RL_G3VM201DR_200V]
8K5  G3VM-51UR-5V-VSON4  [RL_G3VM_4P_VSON4]
8K6  G3VM-51UR-5V-VSON4  [RL_G3VM_4P_VSON4]
8K7  G3VM-51UR-5V-VSON4  [RL_G3VM_4P_VSON4]
8K8  G3VM-51UR-5V-VSON4  [RL_G3VM_4P_VSON4]
8K9  G3VM-51UR-5V-VSON4  [RL_G3VM_4P_VSON4]
8K10  G3VM-51UR-5V-VSON4  [RL_G3VM_4P_VSON4]
8K11  G3VM-51UR-5V-VSON4  [RL_G3VM_4P_VSON4]
8K12  G3VM-51UR-5V-VSON4  [RL_G3VM_4P_VSON4]
8K13  G3VM-51UR-5V-VSON4  [RL_G3VM_4P_VSON4]
8K14  G3VM-51UR-5V-VSON4  [RL_G3VM_4P_VSON4]
8K15  UA2-5NJ-A-V3  [RL_NECUA2_5V_V3]
8K16  G3VM-51UR-5V-VSON4  [RL_G3VM_4P_VSON4]
8K17  G3VM-51UR-5V-VSON4  [RL_G3VM_4P_VSON4]
8K18  G3VM-51UR-5V-VSON4  [RL_G3VM_4P_VSON4]
8R1  10K-0.1-S4  [R0402]
8RK2  619-1-S4  [R0402]
8RK3  619-1-S4  [R0402]
8RK4  619-1-S4  [R0402]
8RK5  619-1-S4  [R0402]
8RK6  619-1-S4  [R0402]
8RK7  619-1-S4  [R0402]
8RK8  619-1-S4  [R0402]
8RK9  619-1-S4  [R0402]
8RK10  619-1-S4  [R0402]
8RK11  619-1-S4  [R0402]
8RK12  619-1-S4  [R0402]
8RK13  619-1-S4  [R0402]
8RK14  619-1-S4  [R0402]
8RK16  619-1-S4  [R0402]
8RK17  619-1-S4  [R0402]
8RK18  619-1-S4  [R0402]
8TP_ATT_F  TP01  [TP_040_T]
8TP_ATT_S  TP01  [TP_040_T]
8TP_IS2N_F  TP01  [TP_040_T]
8TP_IS2N_S  TP01  [TP_040_T]
8TP_IS2P_S  TP01  [TP_040_T]
8TP_OPTO_F  TP01  [TP_040_T]
8TP_OPTO_S  TP01  [TP_040_T]
8TP_SRD_F  TP01  [TP_040_T]
8TP_SRD_S  TP01  [TP_040_T]
8TP_SRG_F  TP01  [TP_040_T]
8TP_SRG_S  TP01  [TP_040_T]
8TP_SRS_F  TP01  [TP_040_T]
8TP_SRS_S  TP01  [TP_040_T]
8TP_VCC_F  TP01  [TP_040_T]
8TP_VCC_S  TP01  [TP_040_T]
8TP_VSR_F  TP01  [TP_040_T]
8TP_VSR_S  TP01  [TP_040_T]
sheet P0082_S8_DUT
8C61  0.01U-100-X7R-S6-MU  [C0603]
8C62  2.2U-16-X-S4-MU  [C0402]
8C63  0.01U-100-X7R-S6-MU  [C0603]
8C64  0.01U-100-X7R-S6-MU  [C0603]
8C65  0.1U-25-X7R-S4-MU  [C0402]
8C69  0.01U-100-X7R-S6-MU  [C0603]
8K19  G3VM-51UR-5V-VSON4  [RL_G3VM_4P_VSON4]
8K20  G3VM-51UR-5V-VSON4  [RL_G3VM_4P_VSON4]
8K21  G3VM-51UR-5V-VSON4  [RL_G3VM_4P_VSON4]
8K22  G3VM-51UR-5V-VSON4  [RL_G3VM_4P_VSON4]
8K23  UA2-5NJ-A-V3  [RL_NECUA2_5V_V3]
8K24  UA2-5NJ-A-V3  [RL_NECUA2_5V_V3]
8K25  G3VM-51UR-5V-VSON4  [RL_G3VM_4P_VSON4]
8K26  G3VM-51UR-5V-VSON4  [RL_G3VM_4P_VSON4]
8K27  G3VM-51UR-5V-VSON4  [RL_G3VM_4P_VSON4]
8K28  G3VM-51UR-5V-VSON4  [RL_G3VM_4P_VSON4]
8K29  G3VM-51UR-5V-VSON4  [RL_G3VM_4P_VSON4]
8K30  G3VM-51UR-5V-VSON4  [RL_G3VM_4P_VSON4]
8K31  G3VM-51UR-5V-VSON4  [RL_G3VM_4P_VSON4]
8K32  G3VM-51UR-5V-VSON4  [RL_G3VM_4P_VSON4]
8K33  G3VM-51UR-5V-VSON4  [RL_G3VM_4P_VSON4]
8K34  G3VM-51UR-5V-VSON4  [RL_G3VM_4P_VSON4]
8K35  G3VM-51UR-5V-VSON4  [RL_G3VM_4P_VSON4]
8K36  G3VM-51UR-5V-VSON4  [RL_G3VM_4P_VSON4]
8K37  G3VM-51UR-5V-VSON4  [RL_G3VM_4P_VSON4]
8RK19  619-1-S4  [R0402]
8RK20  619-1-S4  [R0402]
8RK21  619-1-S4  [R0402]
8RK22  619-1-S4  [R0402]
8RK25  619-1-S4  [R0402]
8RK26  619-1-S4  [R0402]
8RK27  619-1-S4  [R0402]
8RK28  619-1-S4  [R0402]
8RK29  619-1-S4  [R0402]
8RK30  619-1-S4  [R0402]
8RK31  619-1-S4  [R0402]
8RK32  619-1-S4  [R0402]
8RK33  619-1-S4  [R0402]
8RK34  619-1-S4  [R0402]
8RK35  619-1-S4  [R0402]
8RK36  619-1-S4  [R0402]
8RK37  619-1-S4  [R0402]
8TP_C1A_F  TP01  [TP_040_T]
8TP_C1A_S  TP01  [TP_040_T]
8TP_C1B_F  TP01  [TP_040_T]
8TP_C1B_S  TP01  [TP_040_T]
8TP_C2A_F  TP01  [TP_040_T]
8TP_C2A_S  TP01  [TP_040_T]
8TP_C2B_F  TP01  [TP_040_T]
8TP_C2B_S  TP01  [TP_040_T]
8TP_C3A_F  TP01  [TP_040_T]
8TP_C3A_S  TP01  [TP_040_T]
8TP_C3B_F  TP01  [TP_040_T]
8TP_C3B_S  TP01  [TP_040_T]
8TP_IS1N_F  TP01  [TP_040_T]
8TP_IS1N_S  TP01  [TP_040_T]
8TP_IS1P_F  TP01  [TP_040_T]
8TP_SCL_F  TP01  [TP_040_T]
8TP_SDA_F  TP01  [TP_040_T]
8TP_SDA_S  TP01  [TP_040_T]
8TP_STB_F  TP01  [TP_040_T]
8TP_STB_S  TP01  [TP_040_T]
8TP_VDD0_F  TP01  [TP_040_T]
8TP_VDD0_S  TP01  [TP_040_T]
8TP_VDDI_F  TP01  [TP_040_T]
8TP_VDDI_S  TP01  [TP_040_T]
sheet P0083_S8_DUT
8C66  0.1U-25-X7R-S4-MU  [C0402]
8C67  0.1U-25-X7R-S4-MU  [C0402]
8C68  0.1U-25-X7R-S4-MU  [C0402]
8C74  0.1U-25-X7R-S4-MU  [C0402]
8K38  G3VM-51UR-5V-VSON4  [RL_G3VM_4P_VSON4]
8K39  G3VM-51UR-5V-VSON4  [RL_G3VM_4P_VSON4]
8K40  G3VM-51UR-5V-VSON4  [RL_G3VM_4P_VSON4]
8K41  G3VM-51UR-5V-VSON4  [RL_G3VM_4P_VSON4]
8K42  G3VM-51UR-5V-VSON4  [RL_G3VM_4P_VSON4]
8K43  G3VM-51UR-5V-VSON4  [RL_G3VM_4P_VSON4]
8K44  G3VM-51UR-5V-VSON4  [RL_G3VM_4P_VSON4]
8K45  G3VM-51UR-5V-VSON4  [RL_G3VM_4P_VSON4]
8K46  G3VM-51UR-5V-VSON4  [RL_G3VM_4P_VSON4]
8K47  G3VM-51UR-5V-VSON4  [RL_G3VM_4P_VSON4]
8K48  G3VM-51UR-5V-VSON4  [RL_G3VM_4P_VSON4]
8K49  G3VM-51UR-5V-VSON4  [RL_G3VM_4P_VSON4]
8K50  G3VM-51UR-5V-VSON4  [RL_G3VM_4P_VSON4]
8R41  0-5-S6  [R0603]
8R42  0-5-S6  [R0603]
8RK38  619-1-S4  [R0402]
8RK39  619-1-S4  [R0402]
8RK40  619-1-S4  [R0402]
8RK41  619-1-S4  [R0402]
8RK42  619-1-S4  [R0402]
8RK43  619-1-S4  [R0402]
8RK44  619-1-S4  [R0402]
8RK45  619-1-S4  [R0402]
8RK46  619-1-S4  [R0402]
8RK47  619-1-S4  [R0402]
8RK48  619-1-S4  [R0402]
8RK49  619-1-S4  [R0402]
8RK50  619-1-S4  [R0402]
8TP_GA1_S  TP01  [TP_040_T]
8TP_GA2_S  TP01  [TP_040_T]
8TP_GB1_S  TP01  [TP_040_T]
8TP_GB2_S  TP01  [TP_040_T]
8TP_VDD1_S  TP01  [TP_040_T]
8TP_VDD2_S  TP01  [TP_040_T]
8TP_VIN_F  TP01  [TP_040_T]
8TP_VIN_S  TP01  [TP_040_T]
8TP_VO1_S  TP01  [TP_040_T]
8TP_VO2_S  TP01  [TP_040_T]
SITE8  CU_260817-QFN32-5X5  [SK_QFN5x5_64P_0P5MM_JG_260817]  (sections A,B,C,D,E,F,G,H)
sheet P0084_S8_DUT
8C70  0.1U-25-X7R-S4-MU  [C0402]
8C71  0.1U-25-X7R-S4-MU  [C0402]
8C72  0.1U-25-X7R-S4-MU  [C0402]
8C73  0.1U-25-X7R-S4-MU  [C0402]
8K51  G3VM-51UR-5V-VSON4  [RL_G3VM_4P_VSON4]
8K52  G3VM-51UR-5V-VSON4  [RL_G3VM_4P_VSON4]
8K53  G3VM-51UR-5V-VSON4  [RL_G3VM_4P_VSON4]
8K54  G3VM-51UR-5V-VSON4  [RL_G3VM_4P_VSON4]
8K55  G3VM-51UR-5V-VSON4  [RL_G3VM_4P_VSON4]
8K56  G3VM-201DR  [RL_G3VM201DR_200V]
8K57  G3VM-51UR-5V-VSON4  [RL_G3VM_4P_VSON4]
8K58  G3VM-51UR-5V-VSON4  [RL_G3VM_4P_VSON4]
8K59  G3VM-51UR-5V-VSON4  [RL_G3VM_4P_VSON4]
8K60  G3VM-51UR-5V-VSON4  [RL_G3VM_4P_VSON4]
8K61  G3VM-51UR-5V-VSON4  [RL_G3VM_4P_VSON4]
8R7  4.7K-1-S4-WA  [R0402]
8R8  4.7K-1-S4-WA  [R0402]
8R11  5K-1-S4-YA  [R0402]
8R14  5K-1-S4-YA  [R0402]
8R15  0-0-S2-KOA  [R0201]
8R16  5.1-1-S2  [R0201]
8R17  0-0-S2-KOA  [R0201]
8R18  5.1-1-S2  [R0201]
8R19  100K-0.1-S4-YA  [R0402]
8R20  100K-0.1-S4-YA  [R0402]
8RK51  619-1-S4  [R0402]
8RK52  619-1-S4  [R0402]
8RK53  619-1-S4  [R0402]
8RK54  619-1-S4  [R0402]
8RK55  619-1-S4  [R0402]
8RK56  619-1-S4  [R0402]
8RK57  619-1-S4  [R0402]
8RK58  619-1-S4  [R0402]
8RK59  619-1-S4  [R0402]
8RK60  619-1-S4  [R0402]
8RK61  619-1-S4  [R0402]
8SH1  SHORT  [DEFAULT_SHORT_SMALL]
8SH2  SHORT  [DEFAULT_SHORT_SMALL]
8SH3  SHORT  [DEFAULT_SHORT_SMALL]
8SH4  SHORT  [DEFAULT_SHORT_SMALL]
8SH5  SHORT  [DEFAULT_SHORT_SMALL]
8SH6  SHORT  [DEFAULT_SHORT_SMALL]
8SH7  SHORT  [DEFAULT_SHORT_SMALL]
8SH8  SHORT  [DEFAULT_SHORT_SMALL]
8SH9  SHORT  [DEFAULT_SHORT_SMALL]
8SH10  SHORT  [DEFAULT_SHORT_SMALL]
8SH11  SHORT  [DEFAULT_SHORT_SMALL]
8SH12  SHORT  [DEFAULT_SHORT_SMALL]
8SH13  SHORT  [DEFAULT_SHORT_SMALL]
8SH14  SHORT  [DEFAULT_SHORT_SMALL]
8SH15  SHORT  [DEFAULT_SHORT_SMALL]
8SH16  SHORT  [DEFAULT_SHORT_SMALL]
8SH17  SHORT  [DEFAULT_SHORT_SMALL]
8SH18  SHORT  [DEFAULT_SHORT_SMALL]
8SH19  SHORT  [DEFAULT_SHORT_SMALL]
8SH20  SHORT  [DEFAULT_SHORT_SMALL]
8SH21  SHORT  [DEFAULT_SHORT_SMALL]
8SH22  SHORT  [DEFAULT_SHORT_SMALL]
8SH23  SHORT  [DEFAULT_SHORT_SMALL]
8SH24  SHORT  [DEFAULT_SHORT_SMALL]
8SH25  SHORT  [DEFAULT_SHORT_SMALL]
8SH26  SHORT  [DEFAULT_SHORT_SMALL]
8SH27  SHORT  [DEFAULT_SHORT_SMALL]
8SHORT1  SHORT  [DEFAULT_SHORT_SMALL]
8SHORT2  SHORT  [DEFAULT_SHORT_SMALL]
8SHORT3  SHORT  [DEFAULT_SHORT_SMALL]
8SHORT4  SHORT  [DEFAULT_SHORT_SMALL]
8SHORT6  SHORT  [DEFAULT_SHORT_SMALL]
8SHORT7  SHORT  [DEFAULT_SHORT_SMALL]
8SHORT8  SHORT  [DEFAULT_SHORT_SMALL]
8SHORT9  SHORT  [DEFAULT_SHORT_SMALL]
8SHORT10  SHORT  [DEFAULT_SHORT_SMALL]
8SHORT11  SHORT  [DEFAULT_SHORT_SMALL]
8TP_IN+_1  TP01  [TP_040_T]
8TP_IN+_2  TP01  [TP_040_T]
8TP_IN+_3  TP01  [TP_040_T]
8TP_IN+_4  TP01  [TP_040_T]
8TP_IN-_1  TP01  [TP_040_T]
8TP_IN-_2  TP01  [TP_040_T]
8TP_IN-_3  TP01  [TP_040_T]
8TP_IN-_4  TP01  [TP_040_T]
8TP_OUT+_1  TP01  [TP_040_T]
8TP_OUT+_2  TP01  [TP_040_T]
8TP_OUT-_1  TP01  [TP_040_T]
8TP_OUT-_2  TP01  [TP_040_T]
8TP_OUT_1  TP01  [TP_040_T]
8TP_OUT_2  TP01  [TP_040_T]
8TP_REF_1  TP01  [TP_040_T]
8TP_REF_2  TP01  [TP_040_T]
8U1  TLV3604DCKR-SC70  [SC70]
8U2  TLV3604DCKR-SC70  [SC70]
8U3  INA186A3QDDFRQ1-SOT23-8  [SOT23_8P_0P65MM_H1P3MM]
8U4  INA186A3QDDFRQ1-SOT23-8  [SOT23_8P_0P65MM_H1P3MM]

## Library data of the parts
7C61 7C63 7C64 7C69 8C48-8C50 8C60 8C61 8C63 8C64 8C69 = 0.01U-100-X7R-S6-MU
7C62 8C54 8C62 = 2.2U-16-X-S4-MU
7C65-7C68 7C70-7C74 8C65-8C68 8C70-8C74 = 0.1U-25-X7R-S4-MU
7K19-7K22 7K25-7K55 7K57-7K61 8K5-8K14 8K16-8K22 8K25-8K55 8K57-8K61 = G3VM-51UR-5V-VSON4
7K23 7K24 8K1 8K15 8K23 8K24 = UA2-5NJ-A-V3
7RK19-7RK22 7RK25-7RK61 8RK2-8RK14 8RK16-8RK22 8RK25-8RK61 = 619-1-S4
7TP_C1A_F 7TP_C1A_S 7TP_C1B_F 7TP_C1B_S 7TP_C2A_F 7TP_C2A_S 7TP_C2B_F 7TP_C2B_S 7TP_C3A_F 7TP_C3A_S 7TP_C3B_F 7TP_C3B_S 7TP_GA1_S 7TP_GA2_S 7TP_GB1_S 7TP_GB2_S 7TP_IN+_1-7TP_IN+_4 7TP_IN-_1-7TP_IN-_4 7TP_IS1N_F 7TP_IS1N_S 7TP_IS1P_F 7TP_OUT+_1 7TP_OUT+_2 7TP_OUT-_1 7TP_OUT-_2 7TP_OUT_1 7TP_OUT_2 7TP_REF_1 7TP_REF_2 7TP_SCL_F 7TP_SDA_F 7TP_SDA_S 7TP_STB_F 7TP_STB_S 7TP_VDD0_F 7TP_VDD0_S 7TP_VDD1_S 7TP_VDD2_S 7TP_VDDI_F 7TP_VDDI_S 7TP_VIN_F 7TP_VIN_S 7TP_VO1_S 7TP_VO2_S 8TP_ATT_F 8TP_ATT_S 8TP_C1A_F 8TP_C1A_S 8TP_C1B_F 8TP_C1B_S 8TP_C2A_F 8TP_C2A_S 8TP_C2B_F 8TP_C2B_S 8TP_C3A_F 8TP_C3A_S 8TP_C3B_F 8TP_C3B_S 8TP_GA1_S 8TP_GA2_S 8TP_GB1_S 8TP_GB2_S 8TP_IN+_1-8TP_IN+_4 8TP_IN-_1-8TP_IN-_4 8TP_IS1N_F 8TP_IS1N_S 8TP_IS1P_F 8TP_IS2N_F 8TP_IS2N_S 8TP_IS2P_S 8TP_OPTO_F 8TP_OPTO_S 8TP_OUT+_1 8TP_OUT+_2 8TP_OUT-_1 8TP_OUT-_2 8TP_OUT_1 8TP_OUT_2 8TP_REF_1 8TP_REF_2 8TP_SCL_F 8TP_SDA_F 8TP_SDA_S 8TP_SRD_F 8TP_SRD_S 8TP_SRG_F 8TP_SRG_S 8TP_SRS_F 8TP_SRS_S 8TP_STB_F 8TP_STB_S 8TP_VCC_F 8TP_VCC_S 8TP_VDD0_F 8TP_VDD0_S 8TP_VDD1_S 8TP_VDD2_S 8TP_VDDI_F 8TP_VDDI_S 8TP_VIN_F 8TP_VIN_S 8TP_VO1_S 8TP_VO2_S 8TP_VSR_F 8TP_VSR_S = TP01_v2
7R41 7R42 8R41 8R42 = 0-5-S6
SITE7 SITE8 = CU_260817-QFN32-5X5
7K56 8K2-8K4 8K56 = G3VM-201DR
7R7 7R8 8R7 8R8 = 4.7K-1-S4-WA
7R11 7R14 8R11 8R14 = 5K-1-S4-YA
7R15 7R17 8R15 8R17 = 0-0-S2-KOA
7R16 7R18 8R16 8R18 = 5.1-1-S2
7R19 7R20 8R19 8R20 = 100K-0.1-S4-YA
7SH1-7SH27 8SH1-8SH27 = SHORT: KAIROSNAME: SH1
7SHORT1-7SHORT4 7SHORT6-7SHORT11 8SHORT1-8SHORT4 8SHORT6-8SHORT11 = SHORT
7U1 7U2 8U1 8U2 = TLV3604DCKR-SC70
7U3 7U4 8U3 8U4 = INA186A3QDDFRQ1-SOT23-8
8C53 8C58 = 1U-16-X5R-S4-YA
8C59 = 4.7U-100-X-SB-MU
8R1 = 10K-0.1-S4

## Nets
GND: 7R41.2 7R42.2 8R41.2 8R42.2 ; also on sheet 3 4 7 8 11 12 15 16 19 20 21 22 32 36 40 44 48 52
CBIT_19: 7K19.2 ; also on sheet 21 37 45 53
CBIT_20: 7K20.2 ; also on sheet 21 37 45 53
CBIT_21: 7K21.2 ; also on sheet 21 37 45 53
CBIT_22: 7K22.2 ; also on sheet 21 37 45 53
CBIT_25: 7K25.2 ; also on sheet 21 37 45 53
CBIT_26: 7K26.2 ; also on sheet 21 37 45 53
CBIT_27: 7K27.2 ; also on sheet 21 37 45 53
CBIT_28: 7K28.2 ; also on sheet 21 37 45 53
CBIT_29: 7K29.2 ; also on sheet 21 37 45 53
CBIT_30: 7K30.2 ; also on sheet 21 37 45 53
CBIT_31: 7K31.2 ; also on sheet 21 37 45 53
CBIT_32: 7K32.2 ; also on sheet 21 37 45 53
CBIT_33: 7K33.2 ; also on sheet 21 37 45 53
CBIT_34: 7K34.2 ; also on sheet 21 37 45 53
CBIT_35: 7K35.2 ; also on sheet 21 37 45 53
CBIT_36: 7K36.2 ; also on sheet 21 37 45 53
CBIT_37: 7K37.2 ; also on sheet 21 37 45 53
CBIT_38: 7K38.2 ; also on sheet 21 36 44 52
CBIT_39: 7K39.2 ; also on sheet 21 36 44 52
CBIT_40: 7K40.2 ; also on sheet 21 36 44 52
CBIT_41: 7K41.2 ; also on sheet 21 36 44 52
CBIT_42: 7K42.2 ; also on sheet 21 36 44 52
CBIT_43: 7K43.2 ; also on sheet 21 36 44 52
CBIT_44: 7K44.2 ; also on sheet 21 36 44 52
CBIT_45: 7K45.2 ; also on sheet 21 36 44 52
CBIT_46: 7K46.2 ; also on sheet 21 36 44 52
CBIT_47: 7K47.2 ; also on sheet 21 36 44 52
CBIT_48: 7K48.2 ; also on sheet 21 36 44 52
CBIT_49: 7K49.2 ; also on sheet 21 36 44 52
CBIT_50: 7K50.2 ; also on sheet 21 36 44 52
CBIT_51: 7K51.2 ; also on sheet 21 35 43 51
CBIT_52: 7K52.2 ; also on sheet 21 35 43 51
CBIT_53: 7K53.2 ; also on sheet 21 35 43 51
CBIT_54: 7K54.2 ; also on sheet 21 35 43 51
CBIT_55: 7K55.2 ; also on sheet 21 35 43 51
CBIT_56: 7K56.2 ; also on sheet 21 35 43 51
CBIT_57: 7K57.2 ; also on sheet 21 35 43 51
CBIT_58: 7K58.2 ; also on sheet 21 35 43 51
CBIT_59: 7K59.2 ; also on sheet 21 35 43 51
CBIT_60: 7K60.2 ; also on sheet 21 35 43 51
CBIT_62: 8K2.2 ; also on sheet 21 34 42 50
CBIT_63: 8K3.2 ; also on sheet 21 34 42 50
CBIT_64: 8K4.2 ; also on sheet 21 34 42 50
CBIT_65: 8K5.2 ; also on sheet 21 34 42 50
CBIT_66: 8K6.2 ; also on sheet 21 34 42 50
CBIT_67: 8K7.2 ; also on sheet 21 34 42 50
CBIT_68: 8K8.2 ; also on sheet 21 34 42 50
CBIT_69: 8K9.2 ; also on sheet 21 34 42 50
CBIT_70: 8K10.2 ; also on sheet 21 34 42 50
CBIT_71: 8K11.2 ; also on sheet 21 34 42 50
CBIT_72: 8K12.2 ; also on sheet 21 34 42 50
CBIT_73: 8K13.2 ; also on sheet 21 34 42 50
CBIT_74: 8K14.2 ; also on sheet 21 34 42 50
CBIT_76: 8K16.2 ; also on sheet 21 34 42 50
CBIT_77: 8K17.2 ; also on sheet 21 34 42 50
CBIT_78: 8K18.2 ; also on sheet 21 34 42 50
CBIT_79: 8K19.2 ; also on sheet 21 33 41 49
CBIT_80: 8K20.2 ; also on sheet 21 33 41 49
CBIT_81: 8K21.2 ; also on sheet 21 33 41 49
CBIT_82: 8K22.2 ; also on sheet 21 33 41 49
CBIT_85: 8K25.2 ; also on sheet 21 33 41 49
CBIT_86: 8K26.2 ; also on sheet 21 33 41 49
CBIT_87: 8K27.2 ; also on sheet 21 33 41 49
CBIT_88: 8K28.2 ; also on sheet 21 33 41 49
CBIT_89: 8K29.2 ; also on sheet 21 33 41 49
CBIT_90: 8K30.2 ; also on sheet 21 33 41 49
CBIT_91: 8K31.2 ; also on sheet 21 33 41 49
CBIT_92: 8K32.2 ; also on sheet 21 33 41 49
CBIT_93: 8K33.2 ; also on sheet 21 33 41 49
CBIT_94: 8K34.2 ; also on sheet 21 33 41 49
CBIT_95: 8K35.2 ; also on sheet 21 33 41 49
CBIT_96: 8K36.2 ; also on sheet 21 33 41 49
CBIT_97: 8K37.2 ; also on sheet 21 33 41 49
CBIT_98: 8K38.2 ; also on sheet 21 32 40 48
CBIT_99: 8K39.2 ; also on sheet 21 32 40 48
CBIT_100: 8K40.2 ; also on sheet 21 32 40 48
CBIT_101: 8K41.2 ; also on sheet 21 32 40 48
CBIT_102: 8K42.2 ; also on sheet 21 32 40 48
CBIT_103: 8K43.2 ; also on sheet 21 32 40 48
CBIT_104: 8K44.2 ; also on sheet 21 32 40 48
CBIT_105: 8K45.2 ; also on sheet 21 32 40 48
CBIT_106: 8K46.2 ; also on sheet 21 32 40 48
CBIT_107: 8K47.2 ; also on sheet 21 32 40 48
CBIT_108: 8K48.2 ; also on sheet 21 32 40 48
CBIT_109: 8K49.2 ; also on sheet 21 32 40 48
CBIT_110: 8K50.2 ; also on sheet 21 32 40 48
CBIT_111: 8K51.2 ; also on sheet 21 31 39 47
CBIT_112: 8K52.2 ; also on sheet 21 31 39 47
CBIT_113: 8K53.2 ; also on sheet 21 31 39 47
CBIT_114: 8K54.2 ; also on sheet 21 31 39 47
CBIT_115: 8K55.2 ; also on sheet 21 31 39 47
CBIT_116: 8K56.2 ; also on sheet 21 31 39 47
CBIT_117: 8K57.2 ; also on sheet 21 31 39 47
CBIT_118: 8K58.2 ; also on sheet 21 31 39 47
CBIT_119: 8K59.2 ; also on sheet 21 31 39 47
CBIT_120: 8K60.2 ; also on sheet 21 31 39 47
CBIT_122: 8K1.8(V-) ; also on sheet 21 34
CBIT_123: 7K23.8(V-) ; also on sheet 21 37
CBIT_124: 8K23.8(V-) ; also on sheet 21 33
CBIT_125: 7K24.8(V-) 8K24.8(V-) ; also on sheet 21 33 37
CBIT_126: 8K15.8(V-) ; also on sheet 21 30 34 38
CBIT_127: 7K61.2 ; also on sheet 21 35 43 51
CBIT_128: 8K61.2 ; also on sheet 21 31 39 47
DUT7_GND: 7C62.2 7C65.2 7C66.2 7C67.2 7C68.2 7C70.2 7C71.2 7C72.2 7C73.2 7C74.2 7K52.3 7K54.3 7R11.1 7R14.1 7R41.1 7R42.1 7SH1.2 7SH2.2 7SH3.2 7SH4.2 7SH5.2 7SH6.2 7SH7.2 7SH8.2 7SH9.2 7SH10.2 7SH11.2 7SH12.2 7SH13.2 7SH14.2 7SH15.2 7SH16.2 7SH17.2 7SH18.2 7SH19.2 7SH20.2 7SH21.2 7SH22.2 7SH23.2 7SH24.2 7SH25.2 7SH26.2 7SH27.2 7U1.2(VEE) 7U2.2(VEE) 7U3.4(GND) 7U4.4(GND) SITE7.EPAD SITE7.G1 SITE7.G2 SITE7.G3 SITE7.G4 SITE7.G5 SITE7.G6 SITE7.G7 SITE7.G8 SITE7.G9 ; also on sheet 30
DUT8_GND: 8C48.2 8C50.2 8C53.2 8C54.2 8C58.2 8C59.2 8C62.2 8C65.2 8C66.2 8C67.2 8C68.2 8C70.2 8C71.2 8C72.2 8C73.2 8C74.2 8K52.3 8K54.3 8R1.2 8R11.1 8R14.1 8R41.1 8R42.1 8SH1.2 8SH2.2 8SH3.2 8SH4.2 8SH5.2 8SH6.2 8SH7.2 8SH8.2 8SH9.2 8SH10.2 8SH11.2 8SH12.2 8SH13.2 8SH14.2 8SH15.2 8SH16.2 8SH17.2 8SH18.2 8SH19.2 8SH20.2 8SH21.2 8SH22.2 8SH23.2 8SH24.2 8SH25.2 8SH26.2 8SH27.2 8U1.2(VEE) 8U2.2(VEE) 8U3.4(GND) 8U4.4(GND) SITE8.3_F(GND_F) SITE8.3_S(GND_S) SITE8.EPAD SITE8.G1 SITE8.G2 SITE8.G3 SITE8.G4 SITE8.G5 SITE8.G6 SITE8.G7 SITE8.G8 SITE8.G9
S7_C1B_F: 7K27.4 7K61.3 7TP_C1B_F.1(TP) SITE7.17_F(C1B_F) ; also on sheet 4
S7_IS1N_F: 7C69.2 7K57.4 7TP_IS1N_F.1(TP) SITE7.12_F(IS1N_F) ; also on sheet 4
S7_IS1P_F: 7K19.4 7K58.3 7TP_IS1P_F.1(TP) SITE7.11_F(IS1P_F) ; also on sheet 4
S7_IS2N_F: 7K59.4 ; also on sheet 4 30
S7_IS2P_F: 7K60.3 ; also on sheet 4 30
S7_SCL_F: 7K24.3 7K53.3 7K54.4 7TP_SCL_F.1(TP) SITE7.15_F(SCL_F)
S7_SDA_F: 7K23.3 7K51.3 7K52.4 7TP_SDA_F.1(TP) SITE7.14_F(SDA_F)
S7_SRD_F: 7K56.3 ; also on sheet 30
S7_SRG_F: 7K55.3 ; also on sheet 4 30
S8_C1B_F: 8K27.4 8K61.3 8TP_C1B_F.1(TP) SITE8.17_F(C1B_F) ; also on sheet 3
S8_IS1N_F: 8C69.2 8K57.4 8TP_IS1N_F.1(TP) SITE8.12_F(IS1N_F) ; also on sheet 3
S8_IS1P_F: 8K19.4 8K58.3 8TP_IS1P_F.1(TP) SITE8.11_F(IS1P_F) ; also on sheet 3
S8_IS2N_F: 8C60.2 8K59.4 8TP_IS2N_F.1(TP) SITE8.10_F(IS2N_F) ; also on sheet 3
S8_IS2P_F: 8K16.4 8K60.3 SITE8.9_F(IS2P_F) ; also on sheet 3
S8_SCL_F: 8K24.3 8K53.3 8K54.4 8TP_SCL_F.1(TP) SITE8.15_F(SCL_F)
S8_SDA_F: 8K23.3 8K51.3 8K52.4 8TP_SDA_F.1(TP) SITE8.14_F(SDA_F)
S8_SRD_F: 8K1.3 8K2.4 8K3.4 8K56.3 8TP_SRD_F.1(TP) SITE8.1_F(SRD_F)
S8_SRD_S: 8K1.6 8K4.4 8TP_SRD_S.1(TP) SITE8.1_S(SRD_S)
S8_SRG_F: 8K55.3 8TP_SRG_F.1(TP) SITE8.4_F(SRG_F) ; also on sheet 3
SDUP5V_FILTER: 7C70.1 7C71.1 7U1.5(VCCI/VCCO) 7U2.5(VCCI/VCCO) 8C70.1 8C71.1 8U1.5(VCCI/VCCO) 8U2.5(VCCI/VCCO) ; also on sheet 22 31 35 39 43 47 51
SDUR5V_FILTER: 7K23.1(V+) 7K24.1(V+) 7RK19.2 7RK20.2 7RK21.2 7RK22.2 7RK25.2 7RK26.2 7RK27.2 7RK28.2 7RK29.2 7RK30.2 7RK31.2 7RK32.2 7RK33.2 7RK34.2 7RK35.2 7RK36.2 7RK37.2 7RK38.2 7RK39.2 7RK40.2 7RK41.2 7RK42.2 7RK43.2 7RK44.2 7RK45.2 7RK46.2 7RK47.2 7RK48.2 7RK49.2 7RK50.2 7RK51.2 7RK52.2 7RK53.2 7RK54.2 7RK55.1 7RK56.1 7RK57.1 7RK58.1 7RK59.2 7RK60.2 7RK61.2 8K1.1(V+) 8K15.1(V+) 8K23.1(V+) 8K24.1(V+) 8RK2.2 8RK3.2 8RK4.2 8RK5.2 8RK6.2 8RK7.2 8RK8.2 8RK9.2 8RK10.2 8RK11.2 8RK12.2 8RK13.2 8RK14.2 8RK16.2 8RK17.2 8RK18.2 8RK19.2 8RK20.2 8RK21.2 8RK22.2 8RK25.2 8RK26.2 8RK27.2 8RK28.2 8RK29.2 8RK30.2 8RK31.2 8RK32.2 8RK33.2 8RK34.2 8RK35.2 8RK36.2 8RK37.2 8RK38.2 8RK39.2 8RK40.2 8RK41.2 8RK42.2 8RK43.2 8RK44.2 8RK45.2 8RK46.2 8RK47.2 8RK48.2 8RK49.2 8RK50.2 8RK51.2 8RK52.2 8RK53.2 8RK54.2 8RK55.1 8RK56.1 8RK57.1 8RK58.1 8RK59.2 8RK60.2 8RK61.2 ; also on sheet 22 30 31 32 33 34 35 36 37 38 39 40 41 42 43 44 45 46 47 48 49 50 51 52 53 54
SL05_PMVI_4_LS: 7SH17.1 ; also on sheet 16
SL05_PMVI_40_HF: 7R7.1 7SHORT3.1 ; also on sheet 16
SL05_PMVI_40_HS: 7SHORT3.2 ; also on sheet 16
SL05_PMVI_40_LS: 7SH18.1 ; also on sheet 16
SL05_PMVI_41_HF: 7R8.1 7SHORT4.1 ; also on sheet 16
SL05_PMVI_41_HS: 7SHORT4.2 ; also on sheet 16
SL05_PMVI_41_LS: 7SH19.1 ; also on sheet 16
SL05_PMVI_42_HF: 7SHORT1.1 7TP_IN-_1.1(TP) 7U1.4(-IN) ; also on sheet 16
SL05_PMVI_42_HS: 7SHORT1.2 ; also on sheet 16
SL05_PMVI_42_LS: 7SH20.1 ; also on sheet 16
SL05_PMVI_43_HF: 7SHORT2.1 7TP_IN-_2.1(TP) 7U2.4(-IN) ; also on sheet 16
SL05_PMVI_43_HS: 7SHORT2.2 ; also on sheet 16
SL05_PMVI_43_LS: 7SH21.1 ; also on sheet 16
SL05_PMVI_44_HF: 7SHORT9.1 7TP_OUT_1.1(TP) 7U3.5(OUT) ; also on sheet 16
SL05_PMVI_44_HS: 7SHORT9.2 ; also on sheet 16
SL05_PMVI_44_LS: 7SH22.1 ; also on sheet 16
SL05_PMVI_45_HF: 7C72.1 7R15.2 7SHORT6.2 7U3.1(VS) ; also on sheet 16
SL05_PMVI_45_HS: 7SHORT6.1 ; also on sheet 16
SL05_PMVI_45_LS: 7SH23.1 ; also on sheet 16
SL05_PMVI_46_HF: 7SHORT11.2 7TP_REF_1.1(TP) 7U3.3(REF) ; also on sheet 16
SL05_PMVI_46_HS: 7SHORT11.1 ; also on sheet 16
SL05_PMVI_46_LS: 7SH24.1 ; also on sheet 16
SL05_PMVI_47_HF: 7SHORT10.1 7TP_OUT_2.1(TP) 7U4.5(OUT) ; also on sheet 16
SL05_PMVI_47_HS: 7SHORT10.2 ; also on sheet 16
SL05_PMVI_47_LS: 7SH25.1 ; also on sheet 16
SL05_PMVI_48_HF: 7C73.1 7R17.2 7SHORT7.2 7U4.1(VS) ; also on sheet 16
SL05_PMVI_48_HS: 7SHORT7.1 ; also on sheet 16
SL05_PMVI_48_LS: 7SH26.1 ; also on sheet 16
SL05_PMVI_49_HF: 7SHORT8.2 7TP_REF_2.1(TP) 7U4.3(REF) ; also on sheet 16
SL05_PMVI_49_HS: 7SHORT8.1 ; also on sheet 16
SL05_PMVI_49_LS: 7SH27.1 ; also on sheet 16
SL06_DP_90: 8K4.3 ; also on sheet 15
SL06_DP_91: 8K6.3 ; also on sheet 15
SL06_DP_92: 8K7.3 ; also on sheet 15
SL06_DP_93: 8K10.3 ; also on sheet 15
SL06_DP_94: 8K14.3 ; also on sheet 15
SL06_DP_95: 8K15.2 ; also on sheet 15
SL06_DP_96: 8K17.3 ; also on sheet 15
SL06_DP_97: 8K18.3 ; also on sheet 15
SL06_DP_98: 8K20.3 ; also on sheet 15
SL06_DP_99: 8K21.3 ; also on sheet 15
SL06_DP_100: 8K22.3 ; also on sheet 15
SL06_DP_101: 8K23.2 ; also on sheet 15
SL06_DP_102: 8K24.2 ; also on sheet 15
SL06_DP_103: 8K26.3 ; also on sheet 15
SL06_DP_104: 8K28.3 ; also on sheet 15
SL06_DP_105: 8K29.3 ; also on sheet 15
SL06_DP_106: 8K31.3 ; also on sheet 15
SL06_DP_107: 8K32.3 ; also on sheet 15
SL06_DP_108: 8K34.3 ; also on sheet 15
SL06_DP_109: 8K35.3 ; also on sheet 15
SL06_DP_110: 8K37.3 ; also on sheet 15
SL06_DP_111: 8K39.3 ; also on sheet 15
SL06_DP_112: 8K40.3 ; also on sheet 15
SL06_DP_113: 8K41.3 ; also on sheet 15
SL06_DP_114: 8K42.3 ; also on sheet 15
SL06_DP_115: 8K43.3 ; also on sheet 15
SL06_DP_116: 8K45.3 ; also on sheet 15
SL06_DP_117: 8K46.3 ; also on sheet 15
SL06_DP_118: 8K48.3 ; also on sheet 15
SL06_DP_119: 8K50.3 ; also on sheet 15
SL06_DP_139: 8TP_OUT+_1.1(TP) 8U1.1(OUT+) ; also on sheet 15
SL06_DP_140: 8TP_OUT-_1.1(TP) 8U1.6(OUT-) ; also on sheet 15
SL06_DP_141: 8TP_OUT+_2.1(TP) 8U2.1(OUT+) ; also on sheet 15
SL06_DP_142: 8TP_OUT-_2.1(TP) 8U2.6(OUT-) ; also on sheet 15
SL06_DP_143: 8R15.1 8U3.2(ENABLE) ; also on sheet 15
SL06_DP_144: 8R17.1 8U4.2(ENABLE) ; also on sheet 15
SL10_FPVI_6_A_HF: 8K1.4 ; also on sheet 11
SL10_FPVI_6_A_HS: 8K1.5 ; also on sheet 11
SL13_DP_98: 7K20.3 ; also on sheet 8
SL13_DP_99: 7K21.3 ; also on sheet 8
SL13_DP_100: 7K22.3 ; also on sheet 8
SL13_DP_101: 7K23.2 ; also on sheet 8
SL13_DP_102: 7K24.2 ; also on sheet 8
SL13_DP_103: 7K26.3 ; also on sheet 8
SL13_DP_104: 7K28.3 ; also on sheet 8
SL13_DP_105: 7K29.3 ; also on sheet 8
SL13_DP_106: 7K31.3 ; also on sheet 8
SL13_DP_107: 7K32.3 ; also on sheet 8
SL13_DP_108: 7K34.3 ; also on sheet 8
SL13_DP_109: 7K35.3 ; also on sheet 8
SL13_DP_110: 7K37.3 ; also on sheet 8
SL13_DP_111: 7K39.3 ; also on sheet 8
SL13_DP_112: 7K40.3 ; also on sheet 8
SL13_DP_113: 7K41.3 ; also on sheet 8
SL13_DP_114: 7K42.3 ; also on sheet 8
SL13_DP_115: 7K43.3 ; also on sheet 8
SL13_DP_116: 7K45.3 ; also on sheet 8
SL13_DP_117: 7K46.3 ; also on sheet 8
SL13_DP_118: 7K48.3 ; also on sheet 8
SL13_DP_119: 7K50.3 ; also on sheet 8
SL13_DP_139: 7TP_OUT+_1.1(TP) 7U1.1(OUT+) ; also on sheet 8
SL13_DP_140: 7TP_OUT-_1.1(TP) 7U1.6(OUT-) ; also on sheet 8
SL13_DP_141: 7TP_OUT+_2.1(TP) 7U2.1(OUT+) ; also on sheet 8
SL13_DP_142: 7TP_OUT-_2.1(TP) 7U2.6(OUT-) ; also on sheet 8
SL13_DP_143: 7R15.1 7U3.2(ENABLE) ; also on sheet 8
SL13_DP_144: 7R17.1 7U4.2(ENABLE) ; also on sheet 8
SL14_PMVI_4_HF: 8K15.4 ; also on sheet 7
SL14_PMVI_4_HS: 8K15.5 ; also on sheet 7
SL14_PMVI_4_LS: 8SH17.1 ; also on sheet 7
SL14_PMVI_40_HF: 8R7.1 8SHORT3.1 ; also on sheet 7
SL14_PMVI_40_HS: 8SHORT3.2 ; also on sheet 7
SL14_PMVI_40_LS: 8SH18.1 ; also on sheet 7
SL14_PMVI_41_HF: 8R8.1 8SHORT4.1 ; also on sheet 7
SL14_PMVI_41_HS: 8SHORT4.2 ; also on sheet 7
SL14_PMVI_41_LS: 8SH19.1 ; also on sheet 7
SL14_PMVI_42_HF: 8SHORT1.1 8TP_IN-_1.1(TP) 8U1.4(-IN) ; also on sheet 7
SL14_PMVI_42_HS: 8SHORT1.2 ; also on sheet 7
SL14_PMVI_42_LS: 8SH20.1 ; also on sheet 7
SL14_PMVI_43_HF: 8SHORT2.1 8TP_IN-_2.1(TP) 8U2.4(-IN) ; also on sheet 7
SL14_PMVI_43_HS: 8SHORT2.2 ; also on sheet 7
SL14_PMVI_43_LS: 8SH21.1 ; also on sheet 7
SL14_PMVI_44_HF: 8SHORT9.1 8TP_OUT_1.1(TP) 8U3.5(OUT) ; also on sheet 7
SL14_PMVI_44_HS: 8SHORT9.2 ; also on sheet 7
SL14_PMVI_44_LS: 8SH22.1 ; also on sheet 7
SL14_PMVI_45_HF: 8C72.1 8R15.2 8SHORT6.2 8U3.1(VS) ; also on sheet 7
SL14_PMVI_45_HS: 8SHORT6.1 ; also on sheet 7
SL14_PMVI_45_LS: 8SH23.1 ; also on sheet 7
SL14_PMVI_46_HF: 8SHORT11.2 8TP_REF_1.1(TP) 8U3.3(REF) ; also on sheet 7
SL14_PMVI_46_HS: 8SHORT11.1 ; also on sheet 7
SL14_PMVI_46_LS: 8SH24.1 ; also on sheet 7
SL14_PMVI_47_HF: 8SHORT10.1 8TP_OUT_2.1(TP) 8U4.5(OUT) ; also on sheet 7
SL14_PMVI_47_HS: 8SHORT10.2 ; also on sheet 7
SL14_PMVI_47_LS: 8SH25.1 ; also on sheet 7
SL14_PMVI_48_HF: 8C73.1 8R17.2 8SHORT7.2 8U4.1(VS) ; also on sheet 7
SL14_PMVI_48_HS: 8SHORT7.1 ; also on sheet 7
SL14_PMVI_48_LS: 8SH26.1 ; also on sheet 7
SL14_PMVI_49_HF: 8SHORT8.2 8TP_REF_2.1(TP) 8U4.3(REF) ; also on sheet 7
SL14_PMVI_49_HS: 8SHORT8.1 ; also on sheet 7
SL14_PMVI_49_LS: 8SH27.1 ; also on sheet 7
SL17_VI100_17_LS: 7SH1.1 ; also on sheet 4
SL17_VI100_18_B_HF: 7K44.4 SITE7.29_F(VDD1_F) ; also on sheet 4
SL17_VI100_18_B_HS: 7K45.4 7TP_VDD1_S.1(TP) SITE7.29_S(VDD1_S) ; also on sheet 4
SL17_VI100_18_LS: 7SH2.1 ; also on sheet 4
SL17_VI100_19_LS: 7SH3.1 ; also on sheet 4
SL17_VI100_20_B_HS: 7K28.4 7TP_C1B_S.1(TP) SITE7.17_S(C1B_S) ; also on sheet 4
SL17_VI100_20_LS: 7SH4.1 ; also on sheet 4
SL17_VI100_21_LS: 7SH5.1 ; also on sheet 4
SL17_VI100_22_B_HF: SITE7.30_F(GB2_F) ; also on sheet 4
SL17_VI100_22_B_HS: 7K46.4 7TP_GB2_S.1(TP) SITE7.30_S(GB2_S) ; also on sheet 4
SL17_VI100_22_LS: 7SH6.1 ; also on sheet 4
SL17_VI100_23_A_HF: 7TP_STB_F.1(TP) SITE7.13_F(STB_F) ; also on sheet 4
SL17_VI100_23_A_HS: 7K22.4 7TP_STB_S.1(TP) SITE7.13_S(STB_S) ; also on sheet 4
SL17_VI100_23_B_HF: 7K47.4 SITE7.31_F(VO2_F) ; also on sheet 4
SL17_VI100_23_B_HS: 7K48.4 7TP_VO2_S.1(TP) SITE7.31_S(VO2_S) ; also on sheet 4
SL17_VI100_23_LS: 7SH7.1 ; also on sheet 4
SL17_VI100_24_A_HF: 7K23.4 ; also on sheet 4
SL17_VI100_24_A_HS: 7K23.5 ; also on sheet 4
SL17_VI100_24_B_HF: 7C61.2 7TP_C2B_F.1(TP) SITE7.20_F(C2B_F) ; also on sheet 4
SL17_VI100_24_B_HS: 7K32.4 7TP_C2B_S.1(TP) SITE7.20_S(C2B_S) ; also on sheet 4
SL17_VI100_24_LS: 7SH8.1 ; also on sheet 4
SL17_VI100_25_A_HF: 7K24.4 ; also on sheet 4
SL17_VI100_25_A_HS: 7K24.5 ; also on sheet 4
SL17_VI100_25_B_HF: 7K33.4 7TP_C3B_F.1(TP) SITE7.21_F(C3B_F) ; also on sheet 4
SL17_VI100_25_B_HS: 7K34.4 7TP_C3B_S.1(TP) SITE7.21_S(C3B_S) ; also on sheet 4
SL17_VI100_25_LS: 7SH9.1 ; also on sheet 4
SL17_VI100_26_A_HF: 7K25.4 7TP_VDD0_F.1(TP) SITE7.16_F(VDD0_F) ; also on sheet 4
SL17_VI100_26_A_HS: 7K26.4 7TP_VDD0_S.1(TP) SITE7.16_S(VDD0_S) ; also on sheet 4
SL17_VI100_26_B_HF: SITE7.25_F(GA2_F) ; also on sheet 4
SL17_VI100_26_B_HS: 7K40.4 7TP_GA2_S.1(TP) SITE7.25_S(GA2_S) ; also on sheet 4
SL17_VI100_26_LS: 7SH10.1 ; also on sheet 4
SL17_VI100_27_A_HF: 7C63.2 7TP_C1A_F.1(TP) SITE7.18_F(C1A_F) ; also on sheet 4
SL17_VI100_27_A_HS: 7K29.4 7TP_C1A_S.1(TP) SITE7.18_S(C1A_S) ; also on sheet 4
SL17_VI100_27_B_HF: SITE7.26_F(GA1_F) ; also on sheet 4
SL17_VI100_27_B_HS: 7K41.4 7TP_GA1_S.1(TP) SITE7.26_S(GA1_S) ; also on sheet 4
SL17_VI100_27_LS: 7SH11.1 ; also on sheet 4
SL17_VI100_28_A_HF: 7K30.4 7TP_C2A_F.1(TP) SITE7.19_F(C2A_F) ; also on sheet 4
SL17_VI100_28_A_HS: 7K31.4 7TP_C2A_S.1(TP) SITE7.19_S(C2A_S) ; also on sheet 4
SL17_VI100_28_B_HF: SITE7.27_F(GB1_F) ; also on sheet 4
SL17_VI100_28_B_HS: 7K42.4 7TP_GB1_S.1(TP) SITE7.27_S(GB1_S) ; also on sheet 4
SL17_VI100_28_LS: 7SH12.1 ; also on sheet 4
SL17_VI100_29_A_HF: 7C64.2 7TP_C3A_F.1(TP) SITE7.22_F(C3A_F) ; also on sheet 4
SL17_VI100_29_A_HS: 7K35.4 7TP_C3A_S.1(TP) SITE7.22_S(C3A_S) ; also on sheet 4
SL17_VI100_29_B_HF: 7K49.4 SITE7.32_F(VDD2_F) ; also on sheet 4
SL17_VI100_29_B_HS: 7K50.4 7TP_VDD2_S.1(TP) SITE7.32_S(VDD2_S) ; also on sheet 4
SL17_VI100_29_LS: 7SH13.1 ; also on sheet 4
SL17_VI100_30_A_HF: 7K36.4 7TP_VDDI_F.1(TP) SITE7.23_F(VDDI_F) ; also on sheet 4
SL17_VI100_30_A_HS: 7K37.4 7TP_VDDI_S.1(TP) SITE7.23_S(VDDI_S) ; also on sheet 4
SL17_VI100_30_B_HS: 7K21.4 7TP_IS1N_S.1(TP) SITE7.12_S(IS1N_S) ; also on sheet 4
SL17_VI100_30_LS: 7SH14.1 ; also on sheet 4
SL17_VI100_31_A_HF: 7K38.4 7TP_VIN_F.1(TP) SITE7.24_F(VIN_F) ; also on sheet 4
SL17_VI100_31_A_HS: 7K39.4 7TP_VIN_S.1(TP) SITE7.24_S(VIN_S) ; also on sheet 4
SL17_VI100_31_B_HS: 7K20.4 SITE7.11_S(IS1P_S) ; also on sheet 4
SL17_VI100_31_LS: 7SH15.1 ; also on sheet 4
SL17_VI100_32_A_HF: SITE7.28_F(VO1_F) ; also on sheet 4
SL17_VI100_32_A_HS: 7K43.4 7TP_VO1_S.1(TP) SITE7.28_S(VO1_S) ; also on sheet 4
SL17_VI100_32_LS: 7SH16.1 ; also on sheet 4
SL18_VI100_17_A_HF: 8K1.2 ; also on sheet 3
SL18_VI100_17_A_HS: 8K1.7 ; also on sheet 3
SL18_VI100_17_LS: 8SH1.1 ; also on sheet 3
SL18_VI100_18_A_HF: 8C49.2 8K5.4 8TP_SRS_F.1(TP) SITE8.2_F(SRS_F) ; also on sheet 3
SL18_VI100_18_A_HS: 8K6.4 8TP_SRS_S.1(TP) SITE8.2_S(SRS_S) ; also on sheet 3
SL18_VI100_18_B_HF: 8K44.4 SITE8.29_F(VDD1_F) ; also on sheet 3
SL18_VI100_18_B_HS: 8K45.4 8TP_VDD1_S.1(TP) SITE8.29_S(VDD1_S) ; also on sheet 3
SL18_VI100_18_LS: 8SH2.1 ; also on sheet 3
SL18_VI100_19_A_HF: 8K8.4 8K9.4 8TP_VSR_F.1(TP) SITE8.5_F(VSR_F) ; also on sheet 3
SL18_VI100_19_A_HS: 8K10.4 8TP_VSR_S.1(TP) SITE8.5_S(VSR_S) ; also on sheet 3
SL18_VI100_19_B_HS: 8K18.4 8TP_IS2N_S.1(TP) SITE8.10_S(IS2N_S) ; also on sheet 3
SL18_VI100_19_LS: 8SH3.1 ; also on sheet 3
SL18_VI100_20_A_HS: 8K7.4 8TP_SRG_S.1(TP) SITE8.4_S(SRG_S) ; also on sheet 3
SL18_VI100_20_B_HS: 8K28.4 8TP_C1B_S.1(TP) SITE8.17_S(C1B_S) ; also on sheet 3
SL18_VI100_20_LS: 8SH4.1 ; also on sheet 3
SL18_VI100_21_A_HF: 8K11.4 8K12.4 8K13.4 8TP_VCC_F.1(TP) SITE8.6_F(VCC_F) ; also on sheet 3
SL18_VI100_21_A_HS: 8TP_VCC_S.1(TP) SITE8.6_S(VCC_S) ; also on sheet 3
SL18_VI100_21_LS: 8SH5.1 ; also on sheet 3
SL18_VI100_22_A_HF: 8TP_OPTO_F.1(TP) SITE8.7_F(OPTO_F) ; also on sheet 3
SL18_VI100_22_A_HS: 8K14.4 8TP_OPTO_S.1(TP) SITE8.7_S(OPTO_S) ; also on sheet 3
SL18_VI100_22_B_HF: SITE8.30_F(GB2_F) ; also on sheet 3
SL18_VI100_22_B_HS: 8K46.4 8TP_GB2_S.1(TP) SITE8.30_S(GB2_S) ; also on sheet 3
SL18_VI100_22_LS: 8SH6.1 ; also on sheet 3
SL18_VI100_23_A_HF: 8TP_STB_F.1(TP) SITE8.13_F(STB_F) ; also on sheet 3
SL18_VI100_23_A_HS: 8K22.4 8TP_STB_S.1(TP) SITE8.13_S(STB_S) ; also on sheet 3
SL18_VI100_23_B_HF: 8K47.4 SITE8.31_F(VO2_F) ; also on sheet 3
SL18_VI100_23_B_HS: 8K48.4 8TP_VO2_S.1(TP) SITE8.31_S(VO2_S) ; also on sheet 3
SL18_VI100_23_LS: 8SH7.1 ; also on sheet 3
SL18_VI100_24_A_HF: 8K23.4 ; also on sheet 3
SL18_VI100_24_A_HS: 8K23.5 ; also on sheet 3
SL18_VI100_24_B_HF: 8C61.2 8TP_C2B_F.1(TP) SITE8.20_F(C2B_F) ; also on sheet 3
SL18_VI100_24_B_HS: 8K32.4 8TP_C2B_S.1(TP) SITE8.20_S(C2B_S) ; also on sheet 3
SL18_VI100_24_LS: 8SH8.1 ; also on sheet 3
SL18_VI100_25_A_HF: 8K24.4 ; also on sheet 3
SL18_VI100_25_A_HS: 8K24.5 ; also on sheet 3
SL18_VI100_25_B_HF: 8K33.4 8TP_C3B_F.1(TP) SITE8.21_F(C3B_F) ; also on sheet 3
SL18_VI100_25_B_HS: 8K34.4 8TP_C3B_S.1(TP) SITE8.21_S(C3B_S) ; also on sheet 3
SL18_VI100_25_LS: 8SH9.1 ; also on sheet 3
SL18_VI100_26_A_HF: 8K25.4 8TP_VDD0_F.1(TP) SITE8.16_F(VDD0_F) ; also on sheet 3
SL18_VI100_26_A_HS: 8K26.4 8TP_VDD0_S.1(TP) SITE8.16_S(VDD0_S) ; also on sheet 3
SL18_VI100_26_B_HF: SITE8.25_F(GA2_F) ; also on sheet 3
SL18_VI100_26_B_HS: 8K40.4 8TP_GA2_S.1(TP) SITE8.25_S(GA2_S) ; also on sheet 3
SL18_VI100_26_LS: 8SH10.1 ; also on sheet 3
SL18_VI100_27_A_HF: 8C63.2 8TP_C1A_F.1(TP) SITE8.18_F(C1A_F) ; also on sheet 3
SL18_VI100_27_A_HS: 8K29.4 8TP_C1A_S.1(TP) SITE8.18_S(C1A_S) ; also on sheet 3
SL18_VI100_27_B_HF: SITE8.26_F(GA1_F) ; also on sheet 3
SL18_VI100_27_B_HS: 8K41.4 8TP_GA1_S.1(TP) SITE8.26_S(GA1_S) ; also on sheet 3
SL18_VI100_27_LS: 8SH11.1 ; also on sheet 3
SL18_VI100_28_A_HF: 8K30.4 8TP_C2A_F.1(TP) SITE8.19_F(C2A_F) ; also on sheet 3
SL18_VI100_28_A_HS: 8K31.4 8TP_C2A_S.1(TP) SITE8.19_S(C2A_S) ; also on sheet 3
SL18_VI100_28_B_HF: SITE8.27_F(GB1_F) ; also on sheet 3
SL18_VI100_28_B_HS: 8K42.4 8TP_GB1_S.1(TP) SITE8.27_S(GB1_S) ; also on sheet 3
SL18_VI100_28_LS: 8SH12.1 ; also on sheet 3
SL18_VI100_29_A_HF: 8C64.2 8TP_C3A_F.1(TP) SITE8.22_F(C3A_F) ; also on sheet 3
SL18_VI100_29_A_HS: 8K35.4 8TP_C3A_S.1(TP) SITE8.22_S(C3A_S) ; also on sheet 3
SL18_VI100_29_B_HF: 8K49.4 SITE8.32_F(VDD2_F) ; also on sheet 3
SL18_VI100_29_B_HS: 8K50.4 8TP_VDD2_S.1(TP) SITE8.32_S(VDD2_S) ; also on sheet 3
SL18_VI100_29_LS: 8SH13.1 ; also on sheet 3
SL18_VI100_30_A_HF: 8K36.4 8TP_VDDI_F.1(TP) SITE8.23_F(VDDI_F) ; also on sheet 3
SL18_VI100_30_A_HS: 8K37.4 8TP_VDDI_S.1(TP) SITE8.23_S(VDDI_S) ; also on sheet 3
SL18_VI100_30_B_HS: 8K21.4 8TP_IS1N_S.1(TP) SITE8.12_S(IS1N_S) ; also on sheet 3
SL18_VI100_30_LS: 8SH14.1 ; also on sheet 3
SL18_VI100_31_A_HF: 8K38.4 8TP_VIN_F.1(TP) SITE8.24_F(VIN_F) ; also on sheet 3
SL18_VI100_31_A_HS: 8K39.4 8TP_VIN_S.1(TP) SITE8.24_S(VIN_S) ; also on sheet 3
SL18_VI100_31_B_HS: 8K20.4 SITE8.11_S(IS1P_S) ; also on sheet 3
SL18_VI100_31_LS: 8SH15.1 ; also on sheet 3
SL18_VI100_32_A_HF: SITE8.28_F(VO1_F) ; also on sheet 3
SL18_VI100_32_A_HS: 8K43.4 8TP_VO1_S.1(TP) SITE8.28_S(VO1_S) ; also on sheet 3
SL18_VI100_32_B_HS: 8K17.4 8TP_IS2P_S.1(TP) SITE8.9_S(IS2P_S) ; also on sheet 3
SL18_VI100_32_LS: 8SH16.1 ; also on sheet 3
N18733742: 7C69.1 7K19.3
N18733769: 7K19.1 7RK19.1
N18733771: 7K20.1 7RK20.1
N18733772: 7K21.1 7RK21.1
N18733797: 7K22.1 7RK22.1
N18733803: 7K23.6 7TP_SDA_S.1(TP) SITE7.14_S(SDA_S)
N18733817: 7K24.6 SITE7.15_S(SCL_S)
N18733827: 7C62.1 7K25.3
N18733845: 7K25.1 7RK25.1
N18733849: 7K26.1 7RK26.1
N18733854: 7C63.1 7K27.3
N18733870: 7K28.1 7RK28.1
N18733891: 7K27.1 7RK27.1
N18733893: 7K29.1 7RK29.1
N18733898: 7C61.1 7K30.3
N18733912: 7K31.1 7RK31.1
N18733932: 7K30.1 7RK30.1
N18733935: 7K32.1 7RK32.1
N18733937: 7K35.1 7RK35.1
N18733939: 7K34.1 7RK34.1
N18733941: 7K33.1 7RK33.1
N18733944: 7C64.1 7K33.3
N18733979: 7K37.1 7RK37.1
N18733980: 7K36.1 7RK36.1
N18733986: 7C65.1 7K36.3
N18735272: 7K39.1 7RK39.1
N18735273: 7K38.1 7RK38.1
N18735279: 7C74.1 7K38.3
N18735298: 7K40.1 7RK40.1
N18735311: 7K41.1 7RK41.1
N18735324: 7K42.1 7RK42.1
N18735336: 7K43.1 7RK43.1
N18735349: 7K45.1 7RK45.1
N18735350: 7K44.1 7RK44.1
N18735360: 7C66.1 7K44.3
N18735378: 7K46.1 7RK46.1
N18735394: 7C67.1 7K47.3
N18735407: 7K48.1 7RK48.1
N18735408: 7K47.1 7RK47.1
N18735418: 7C68.1 7K49.3
N18735431: 7K50.1 7RK50.1
N18735432: 7K49.1 7RK49.1
N18736246: 7K51.4 7R7.2
N18736258: 7K53.4 7R8.2
N18736260: 7K53.1 7RK53.1
N18736282: 7R11.2 7R19.1 7TP_IN+_1.1(TP) 7U1.3(+IN)
N18736294: 7R14.2 7R20.1 7TP_IN+_2.1(TP) 7U2.3(+IN)
N18736304: 7K55.1 7RK59.1
N18736307: 7K55.4 7R19.2
N18736309: 7K56.1 7RK60.1
N18736326: 7K57.3 7R16.1 7TP_IN-_3.1(TP) 7U3.8(IN-)
N18736327: 7K58.4 7R16.2 7TP_IN+_3.1(TP) 7U3.7(IN+)
N18736355: 7K60.4 7R18.2 7TP_IN+_4.1(TP) 7U4.7(IN+)
N18736359: 7K59.3 7R18.1 7TP_IN-_4.1(TP) 7U4.8(IN-)
N18736370: 7K56.4 7K61.4 7R20.2
N18736371: 7K54.1 7RK54.1
N18736375: 7K51.1 7RK51.1
N18736377: 7K52.1 7RK52.1
N18736441: 7K57.1 7RK55.2
N18736442: 7K58.1 7RK56.2
N18736443: 7K59.1 7RK57.2
N18736444: 7K60.1 7RK58.2
N18736447: 7K61.1 7RK61.1
N18737578: 8C48.1 8K2.3
N18737587: 8C49.1 8K3.3
N18737596: 8C50.1 8K5.3
N18737629: 8K7.1 8RK7.1
N18737636: 8C53.1 8K8.3
N18737645: 8C54.1 8K9.3
N18737675: 8C59.1 8K12.3
N18737682: 8K13.3 8R1.1
N18737700: 8K15.6 8TP_ATT_S.1(TP) SITE8.8_S(ATT_S)
N18737718: 8K5.1 8RK5.1
N18737720: 8K6.1 8RK6.1
N18737722: 8K8.1 8RK8.1
N18737723: 8K9.1 8RK9.1
N18737724: 8K10.1 8RK10.1
N18737725: 8K11.1 8RK11.1
N18737728: 8C58.1 8K11.3
N18737731: 8K12.1 8RK12.1
N18737733: 8K13.1 8RK13.1
N18737736: 8K14.1 8RK14.1
N18737738: 8K2.1 8RK2.1
N18737739: 8K3.1 8RK3.1
N18737740: 8K4.1 8RK4.1
N18737760: 8K15.3 8TP_ATT_F.1(TP) SITE8.8_F(ATT_F)
N18737772: 8C60.1 8K16.3
N18737785: 8K17.1 8RK17.1
N18737799: 8K16.1 8RK16.1
N18737803: 8K18.1 8RK18.1
N18738953: 8C69.1 8K19.3
N18738980: 8K19.1 8RK19.1
N18738982: 8K20.1 8RK20.1
N18738983: 8K21.1 8RK21.1
N18739008: 8K22.1 8RK22.1
N18739014: 8K23.6 8TP_SDA_S.1(TP) SITE8.14_S(SDA_S)
N18739028: 8K24.6 SITE8.15_S(SCL_S)
N18739038: 8C62.1 8K25.3
N18739056: 8K25.1 8RK25.1
N18739060: 8K26.1 8RK26.1
N18739065: 8C63.1 8K27.3
N18739081: 8K28.1 8RK28.1
N18739102: 8K27.1 8RK27.1
N18739104: 8K29.1 8RK29.1
N18739109: 8C61.1 8K30.3
N18739123: 8K31.1 8RK31.1
N18739143: 8K30.1 8RK30.1
N18739146: 8K32.1 8RK32.1
N18739148: 8K35.1 8RK35.1
N18739150: 8K34.1 8RK34.1
N18739152: 8K33.1 8RK33.1
N18739155: 8C64.1 8K33.3
N18739190: 8K37.1 8RK37.1
N18739191: 8K36.1 8RK36.1
N18739197: 8C65.1 8K36.3
N18740483: 8K39.1 8RK39.1
N18740484: 8K38.1 8RK38.1
N18740490: 8C74.1 8K38.3
N18740509: 8K40.1 8RK40.1
N18740522: 8K41.1 8RK41.1
N18740535: 8K42.1 8RK42.1
N18740547: 8K43.1 8RK43.1
N18740560: 8K45.1 8RK45.1
N18740561: 8K44.1 8RK44.1
N18740571: 8C66.1 8K44.3
N18740589: 8K46.1 8RK46.1
N18740605: 8C67.1 8K47.3
N18740618: 8K48.1 8RK48.1
N18740619: 8K47.1 8RK47.1
N18740629: 8C68.1 8K49.3
N18740642: 8K50.1 8RK50.1
N18740643: 8K49.1 8RK49.1
N18741457: 8K51.4 8R7.2
N18741469: 8K53.4 8R8.2
N18741471: 8K53.1 8RK53.1
N18741493: 8R11.2 8R19.1 8TP_IN+_1.1(TP) 8U1.3(+IN)
N18741505: 8R14.2 8R20.1 8TP_IN+_2.1(TP) 8U2.3(+IN)
N18741515: 8K55.1 8RK59.1
N18741518: 8K55.4 8R19.2
N18741520: 8K56.1 8RK60.1
N18741537: 8K57.3 8R16.1 8TP_IN-_3.1(TP) 8U3.8(IN-)
N18741538: 8K58.4 8R16.2 8TP_IN+_3.1(TP) 8U3.7(IN+)
N18741566: 8K60.4 8R18.2 8TP_IN+_4.1(TP) 8U4.7(IN+)
N18741570: 8K59.3 8R18.1 8TP_IN-_4.1(TP) 8U4.8(IN-)
N18741581: 8K56.4 8K61.4 8R20.2
N18741582: 8K54.1 8RK54.1
N18741586: 8K51.1 8RK51.1
N18741588: 8K52.1 8RK52.1
N18741652: 8K57.1 8RK55.2
N18741653: 8K58.1 8RK56.2
N18741654: 8K59.1 8RK57.2
N18741655: 8K60.1 8RK58.2
N18741658: 8K61.1 8RK61.1

Not connected (* = marked no-connect by the designer): 7K23 7*; 7K24 7*; 7U3 6(NC)*; 7U4 6(NC)*; 8K15 7*; 8K23 7*; 8K24 7*; 8U3 6(NC)*; 8U4 6(NC)*; SITE7 NGH1* NGH2* NGH3* NGH4* NUT1* NUT2* NUT3* NUT4*; SITE8 NGH1* NGH2* NGH3* NGH4* NUT1* NUT2* NUT3* NUT4*

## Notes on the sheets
sheet 23
- Pull-up Resistor
- Timing Circuits(GX1 ¸ê·½¤À°t»Ý­n¦b®É§Ç¹q¸ô¤W¬Û¾F)
- Differential Circuit
sheet 27
- Pull-up Resistor
- Timing Circuits(GX1 ¸ê·½¤À°t»Ý­n¦b®É§Ç¹q¸ô¤W¬Û¾F)
- Differential Circuit
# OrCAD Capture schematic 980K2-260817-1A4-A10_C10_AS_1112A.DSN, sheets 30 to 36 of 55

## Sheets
30 P0071_S7_DUT: size C
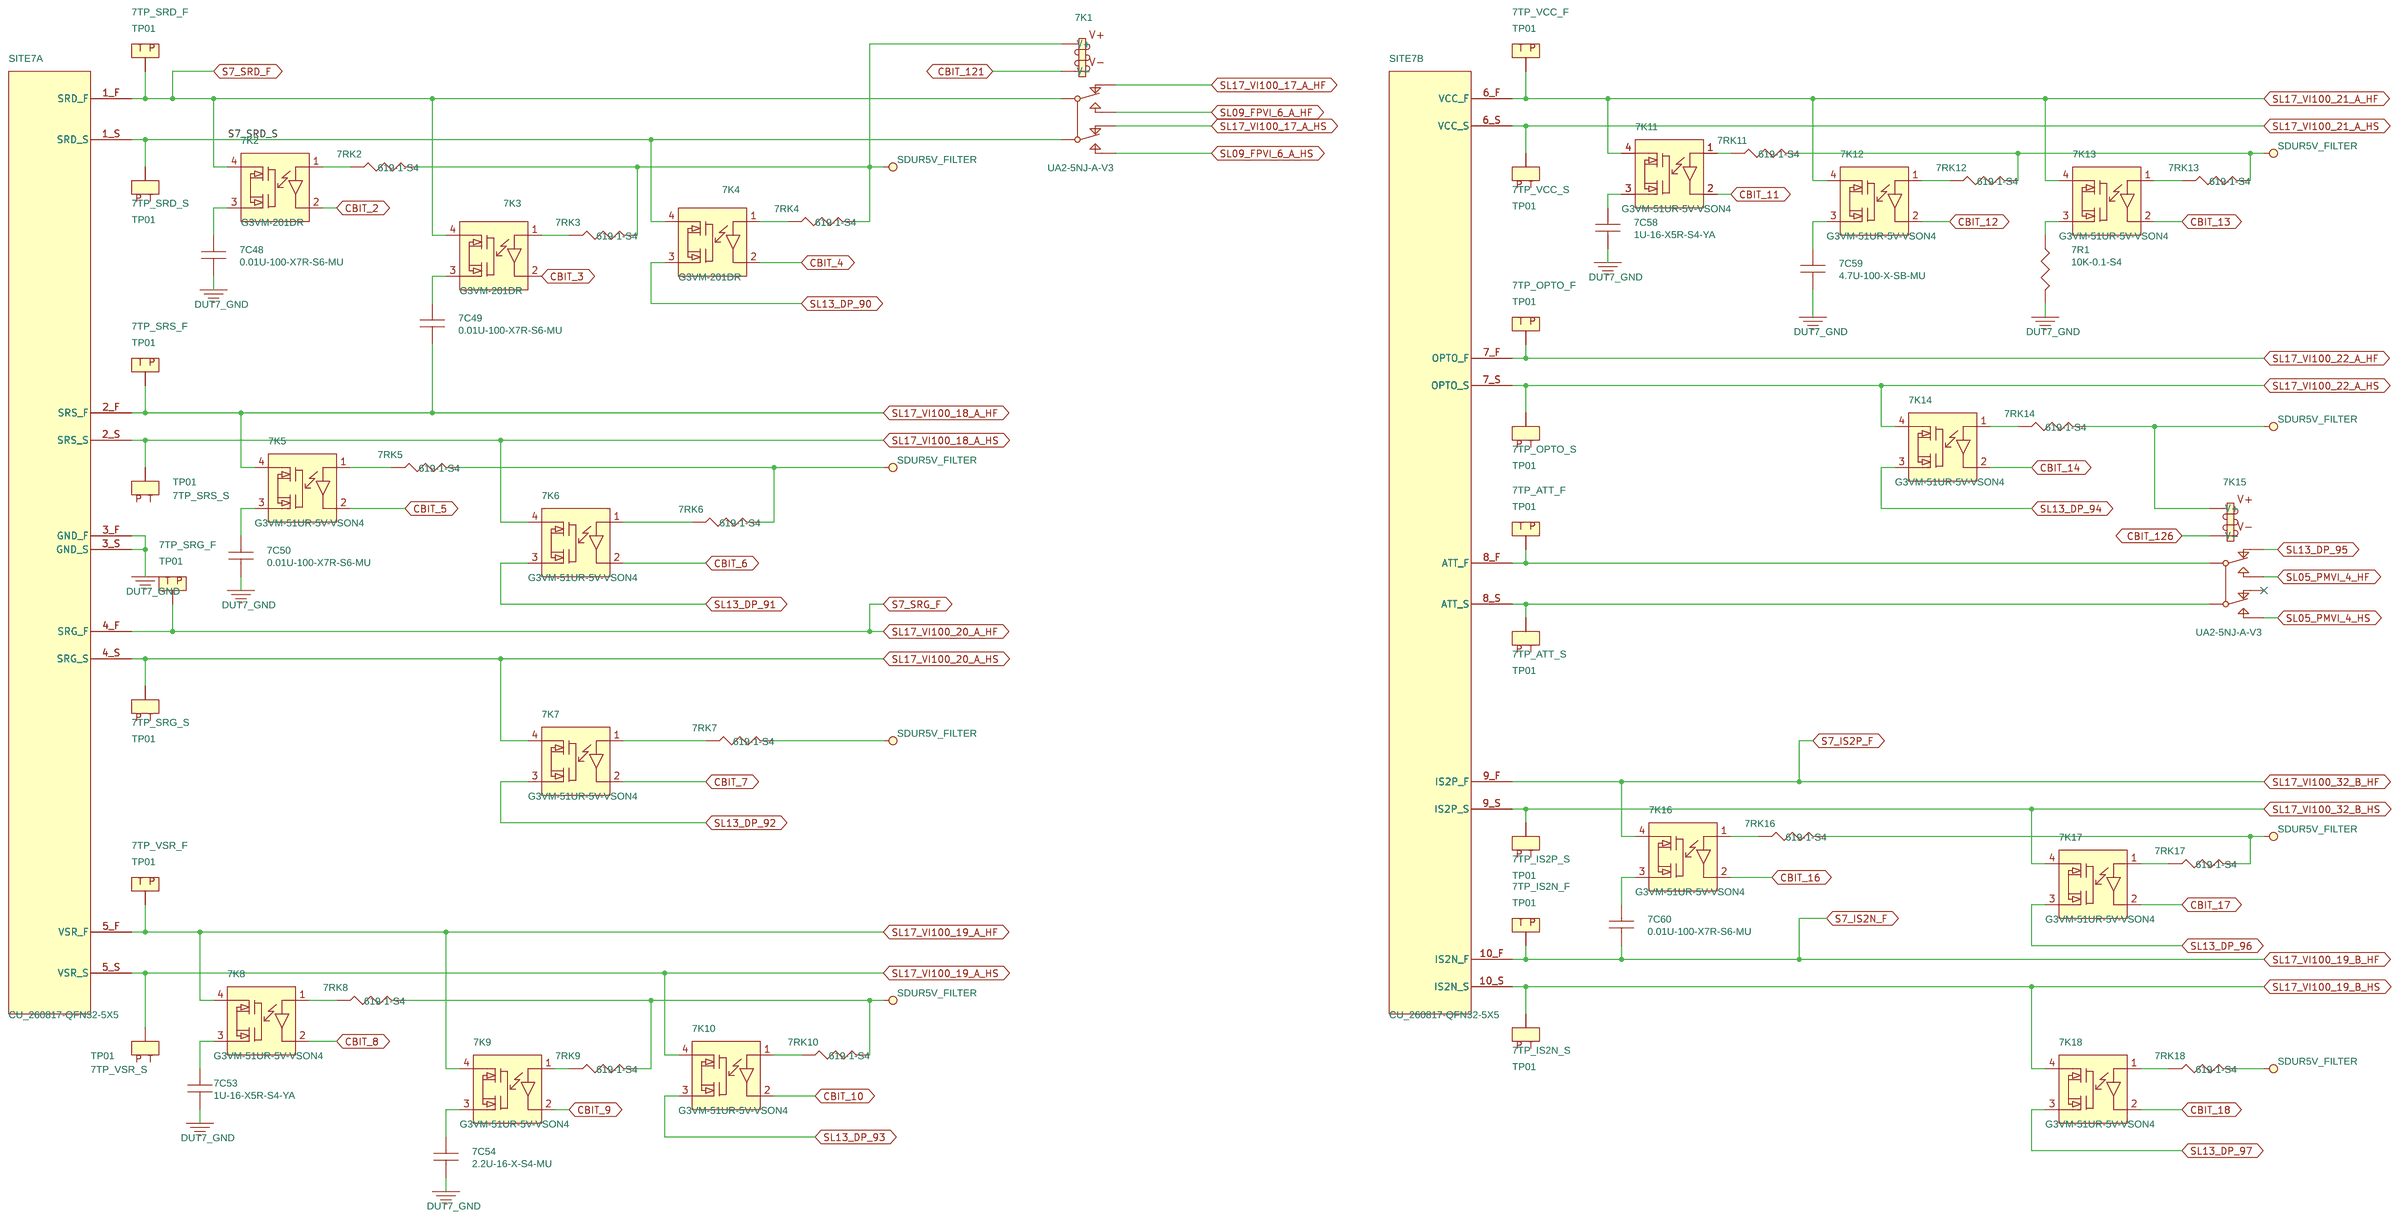
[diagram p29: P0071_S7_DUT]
31 P0064_S6_DUT: size C
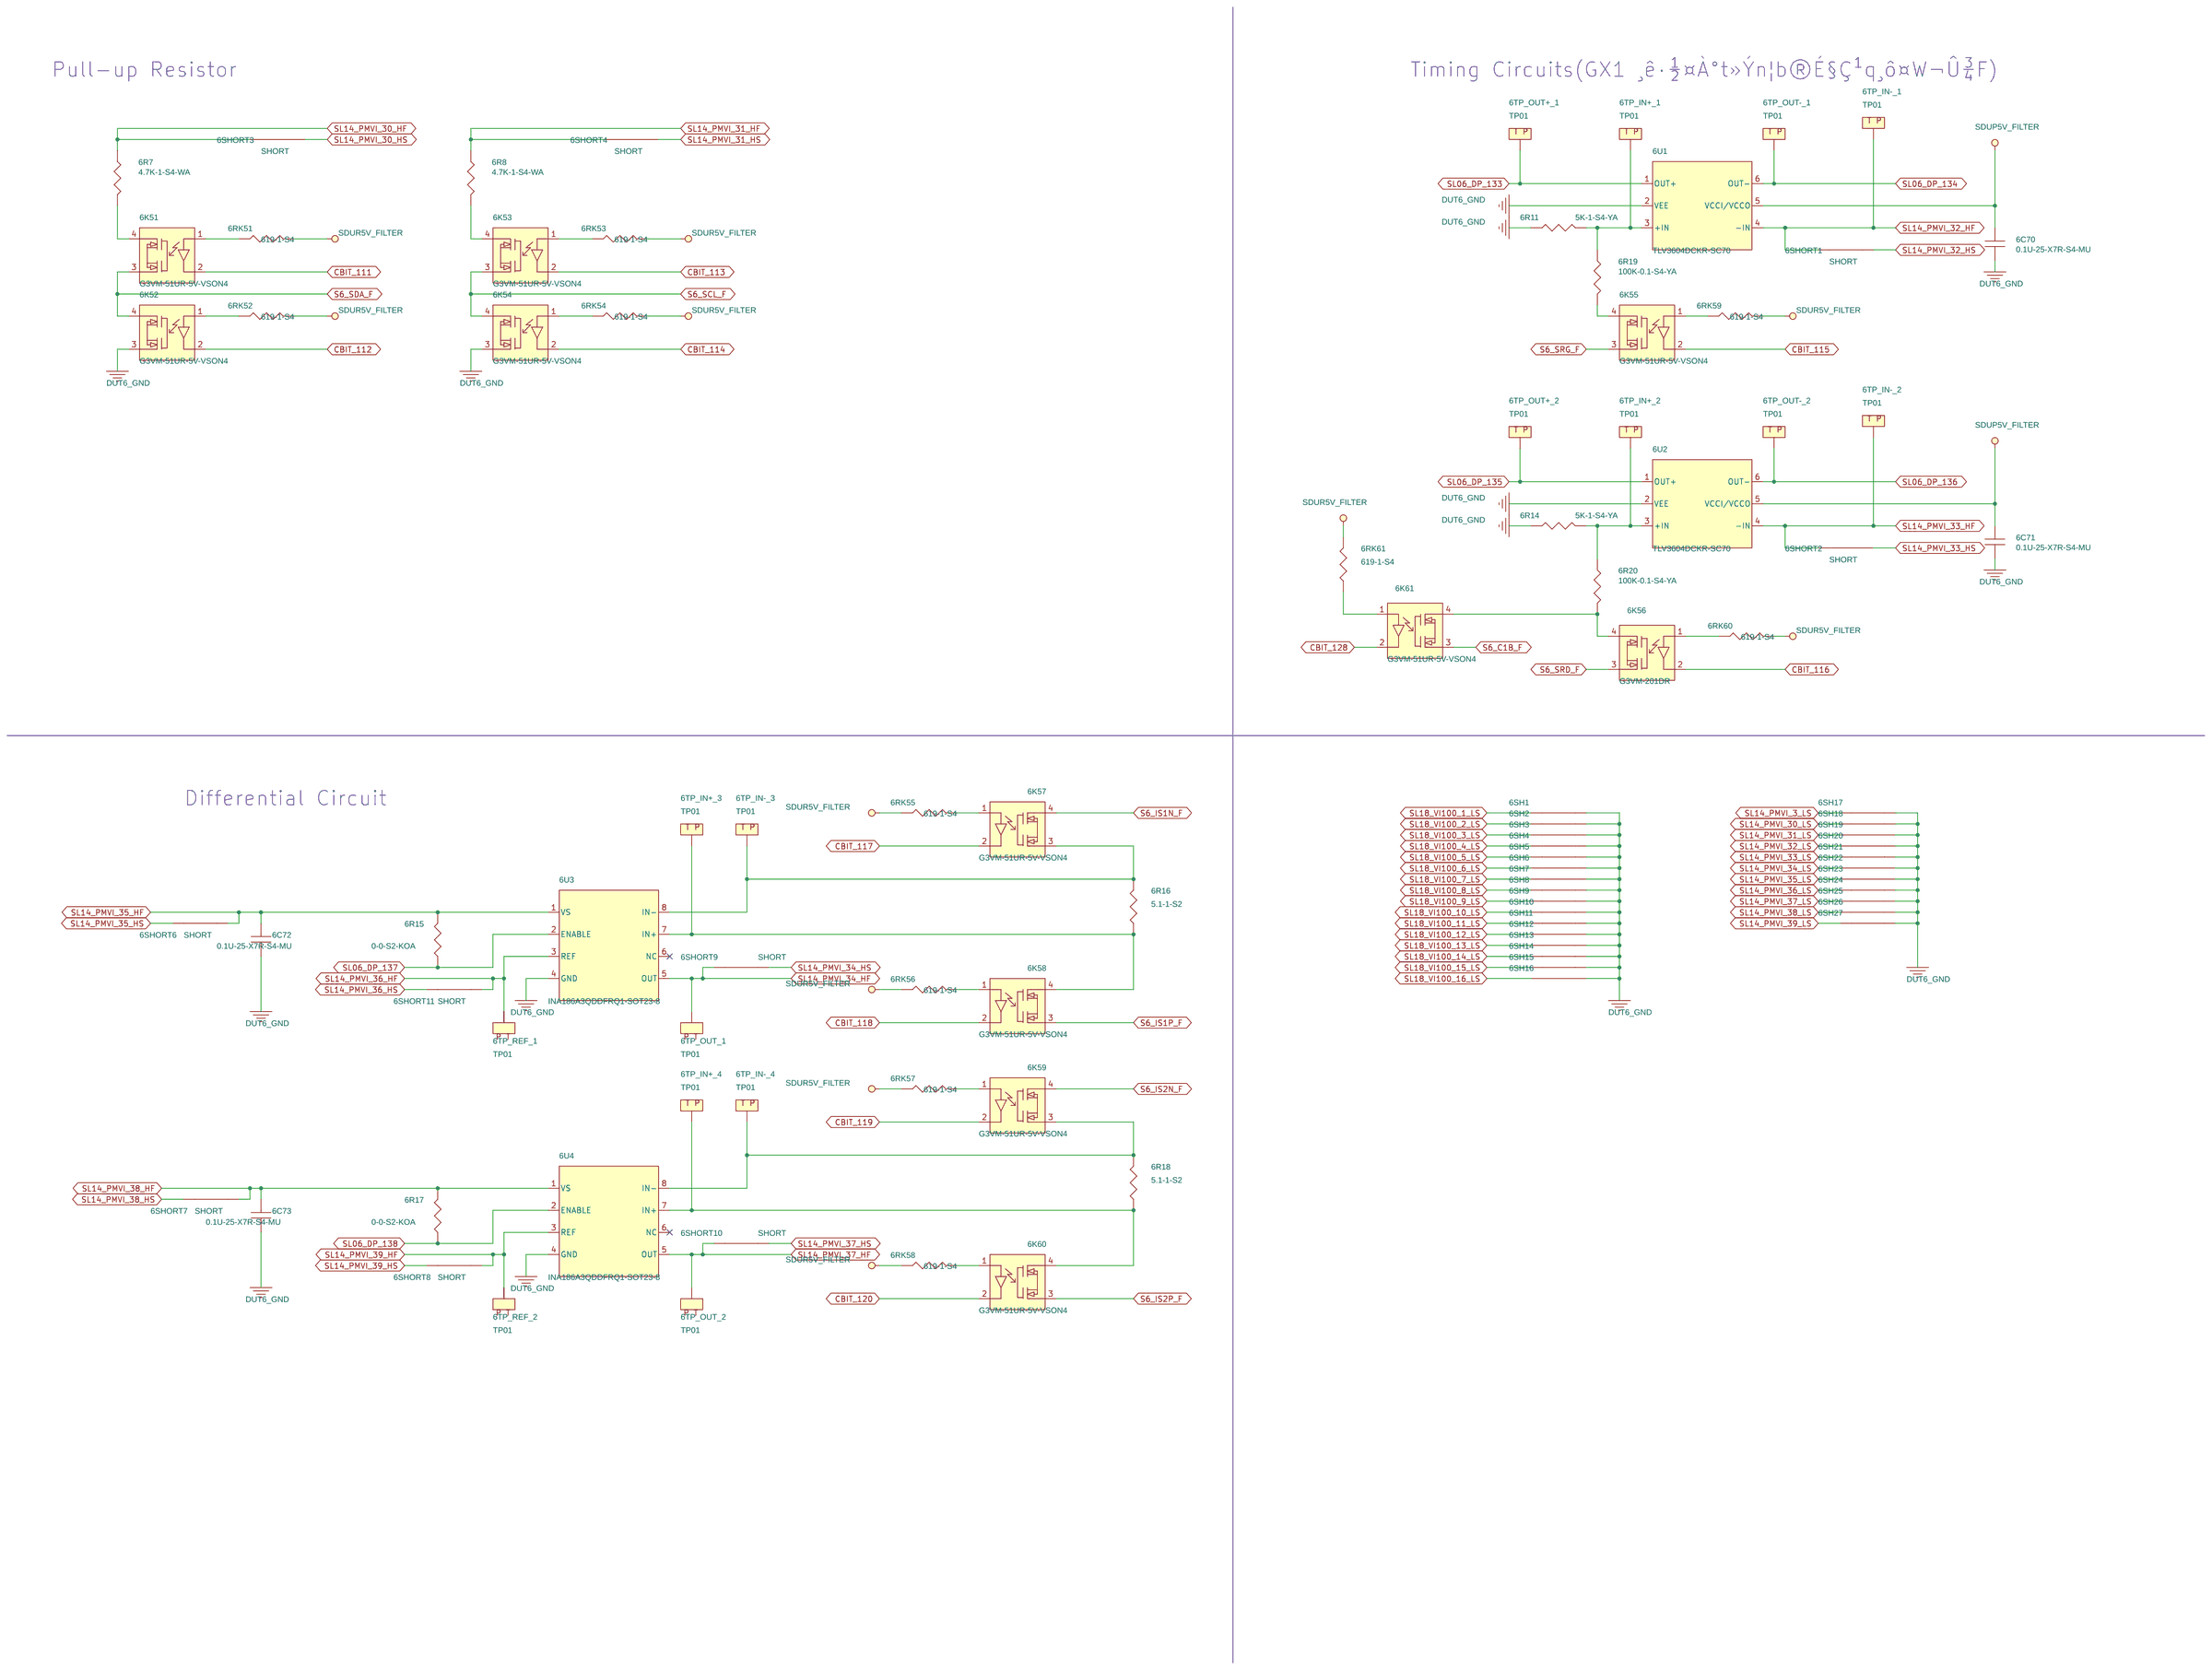
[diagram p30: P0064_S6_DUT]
32 P0063_S6_DUT: size C
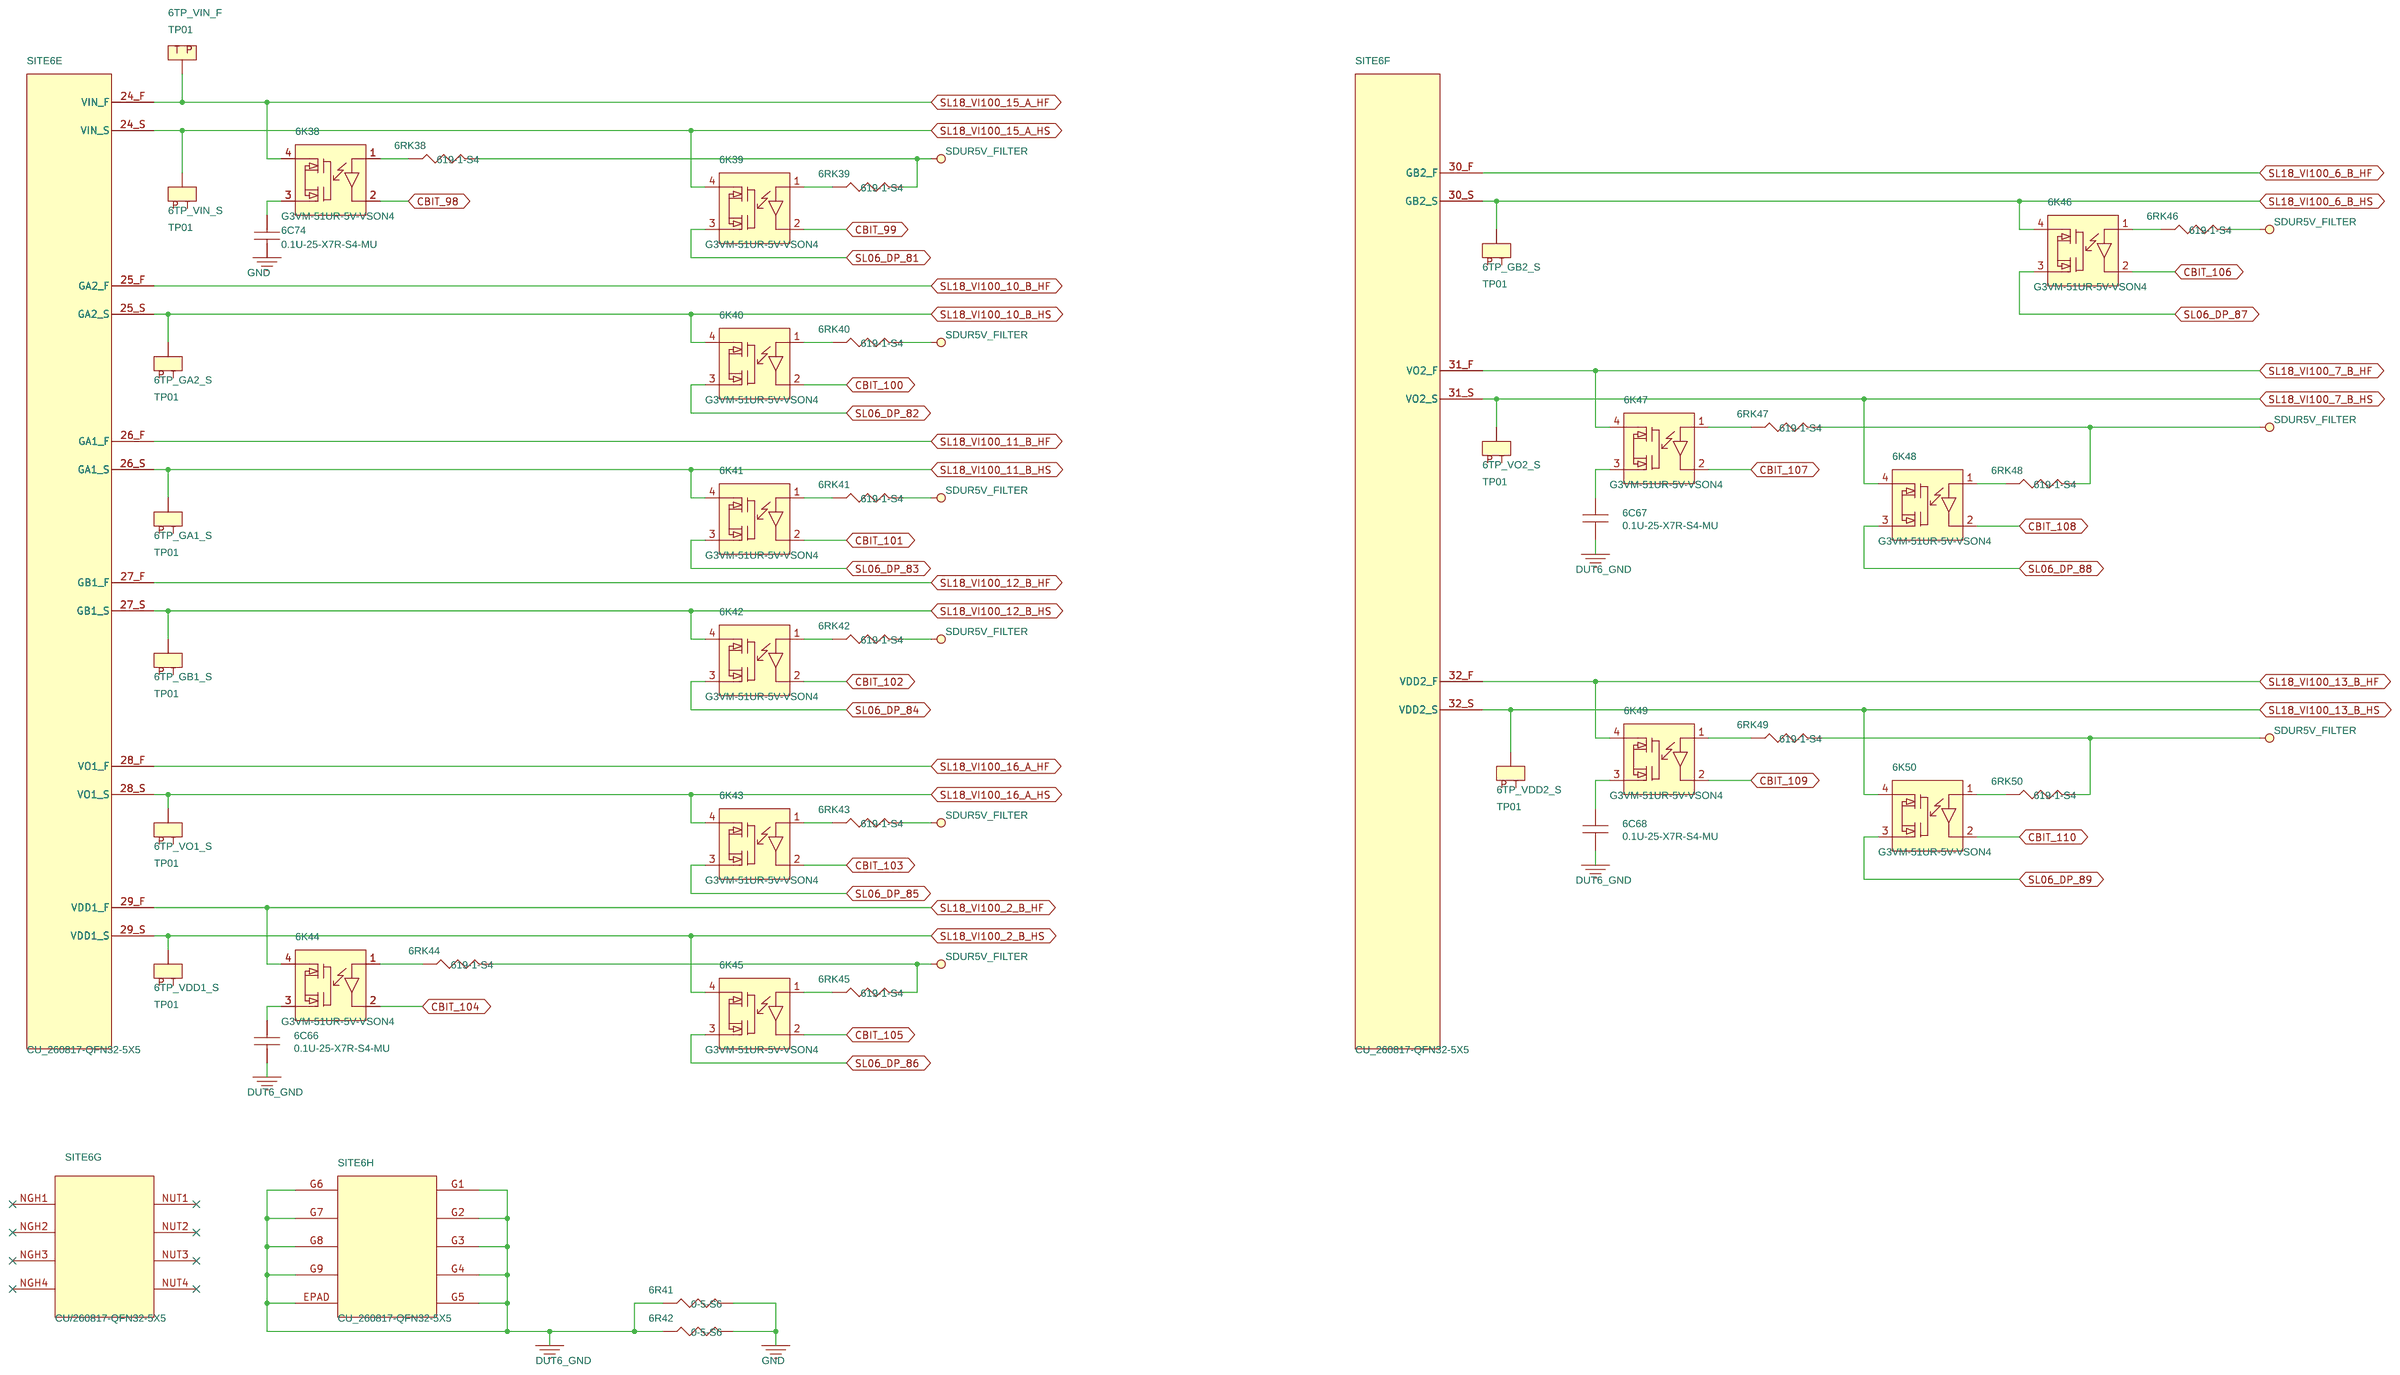
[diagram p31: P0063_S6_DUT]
33 P0062_S6_DUT: size C
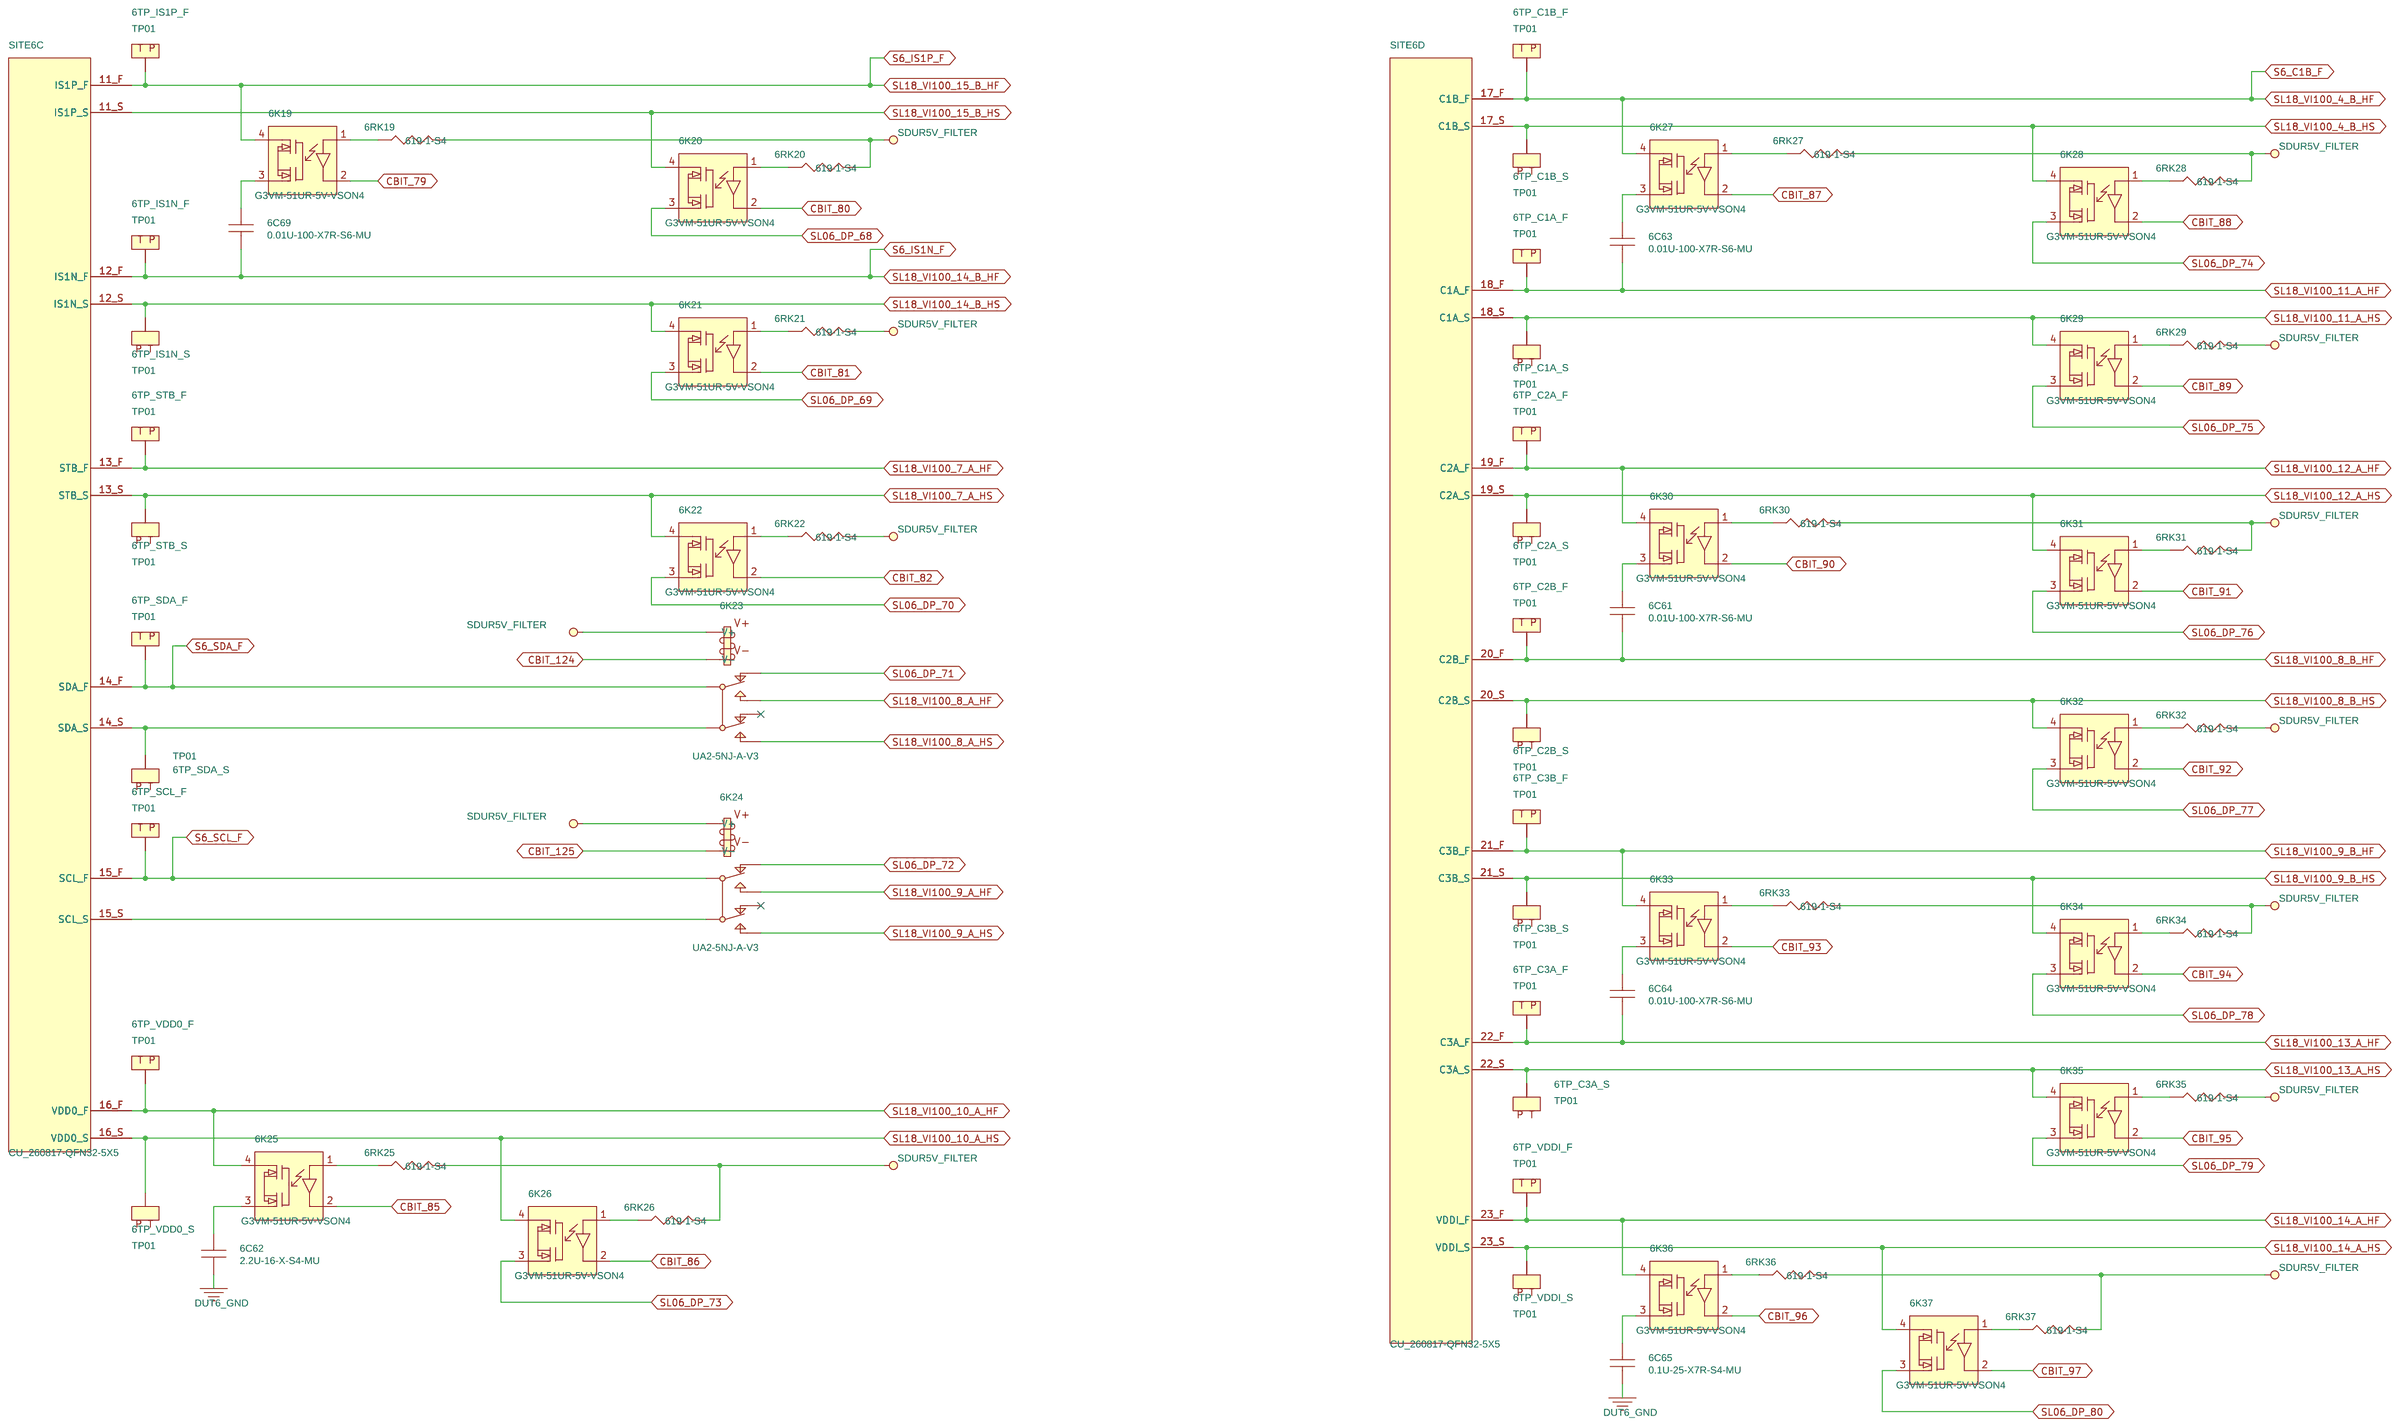
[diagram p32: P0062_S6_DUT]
34 P0061_S6_DUT: size C
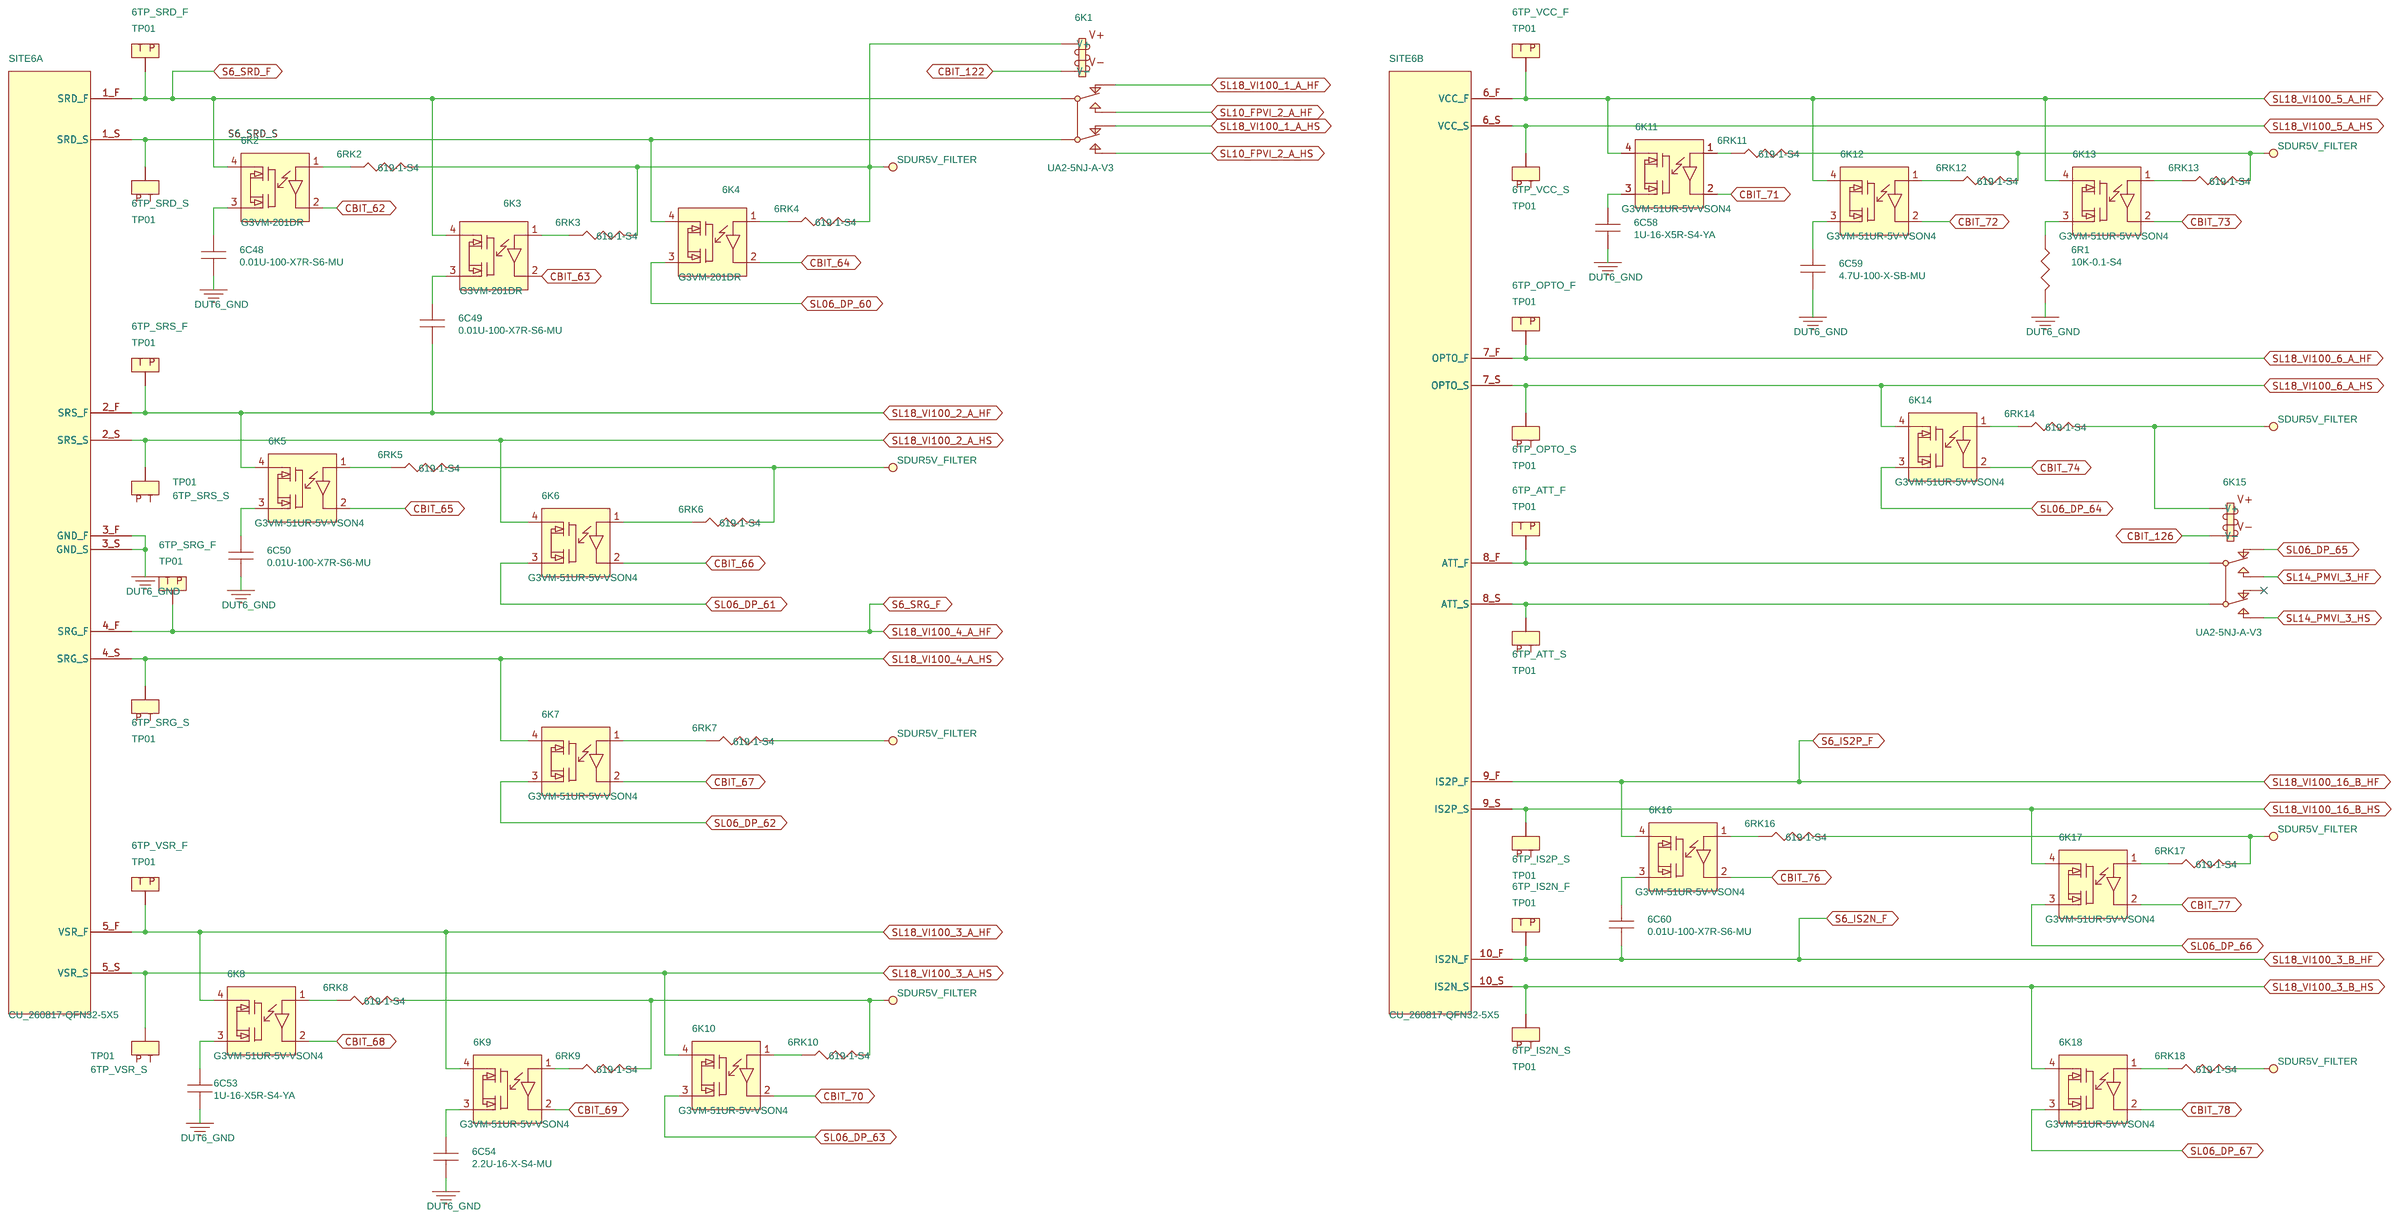
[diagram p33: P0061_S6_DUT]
35 P0054_S5_DUT: size C
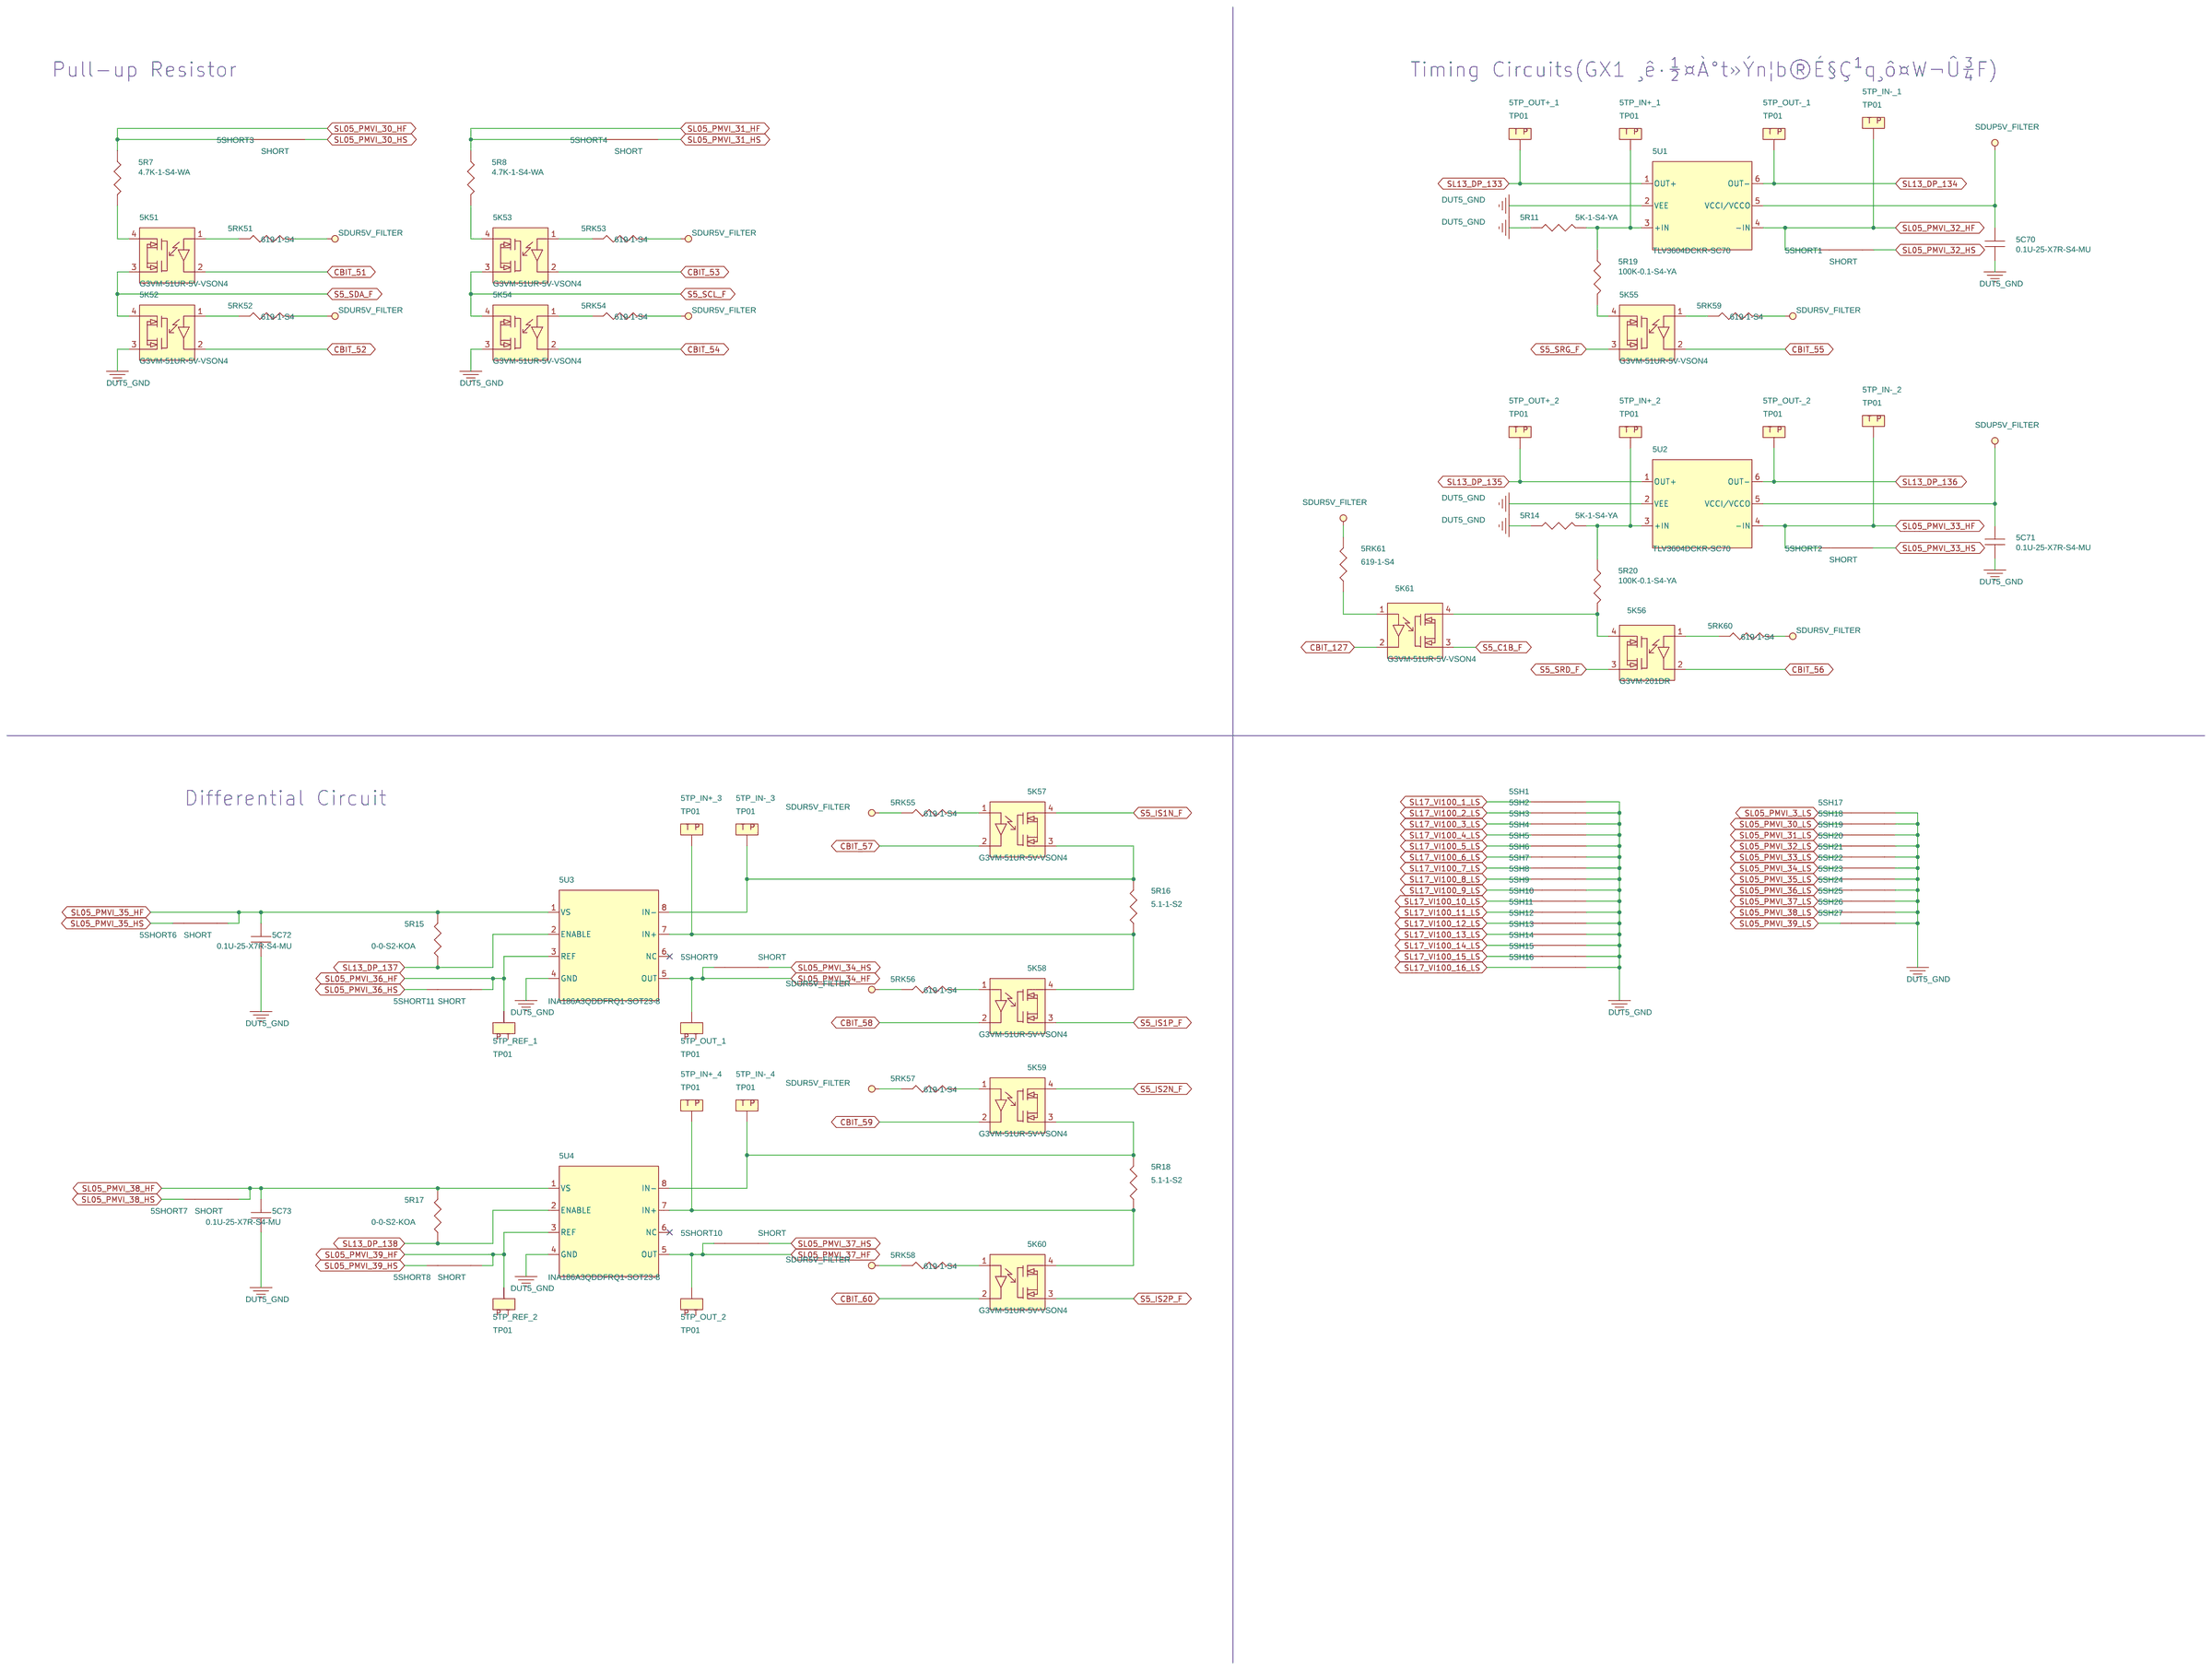
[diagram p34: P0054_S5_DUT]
36 P0053_S5_DUT: size C

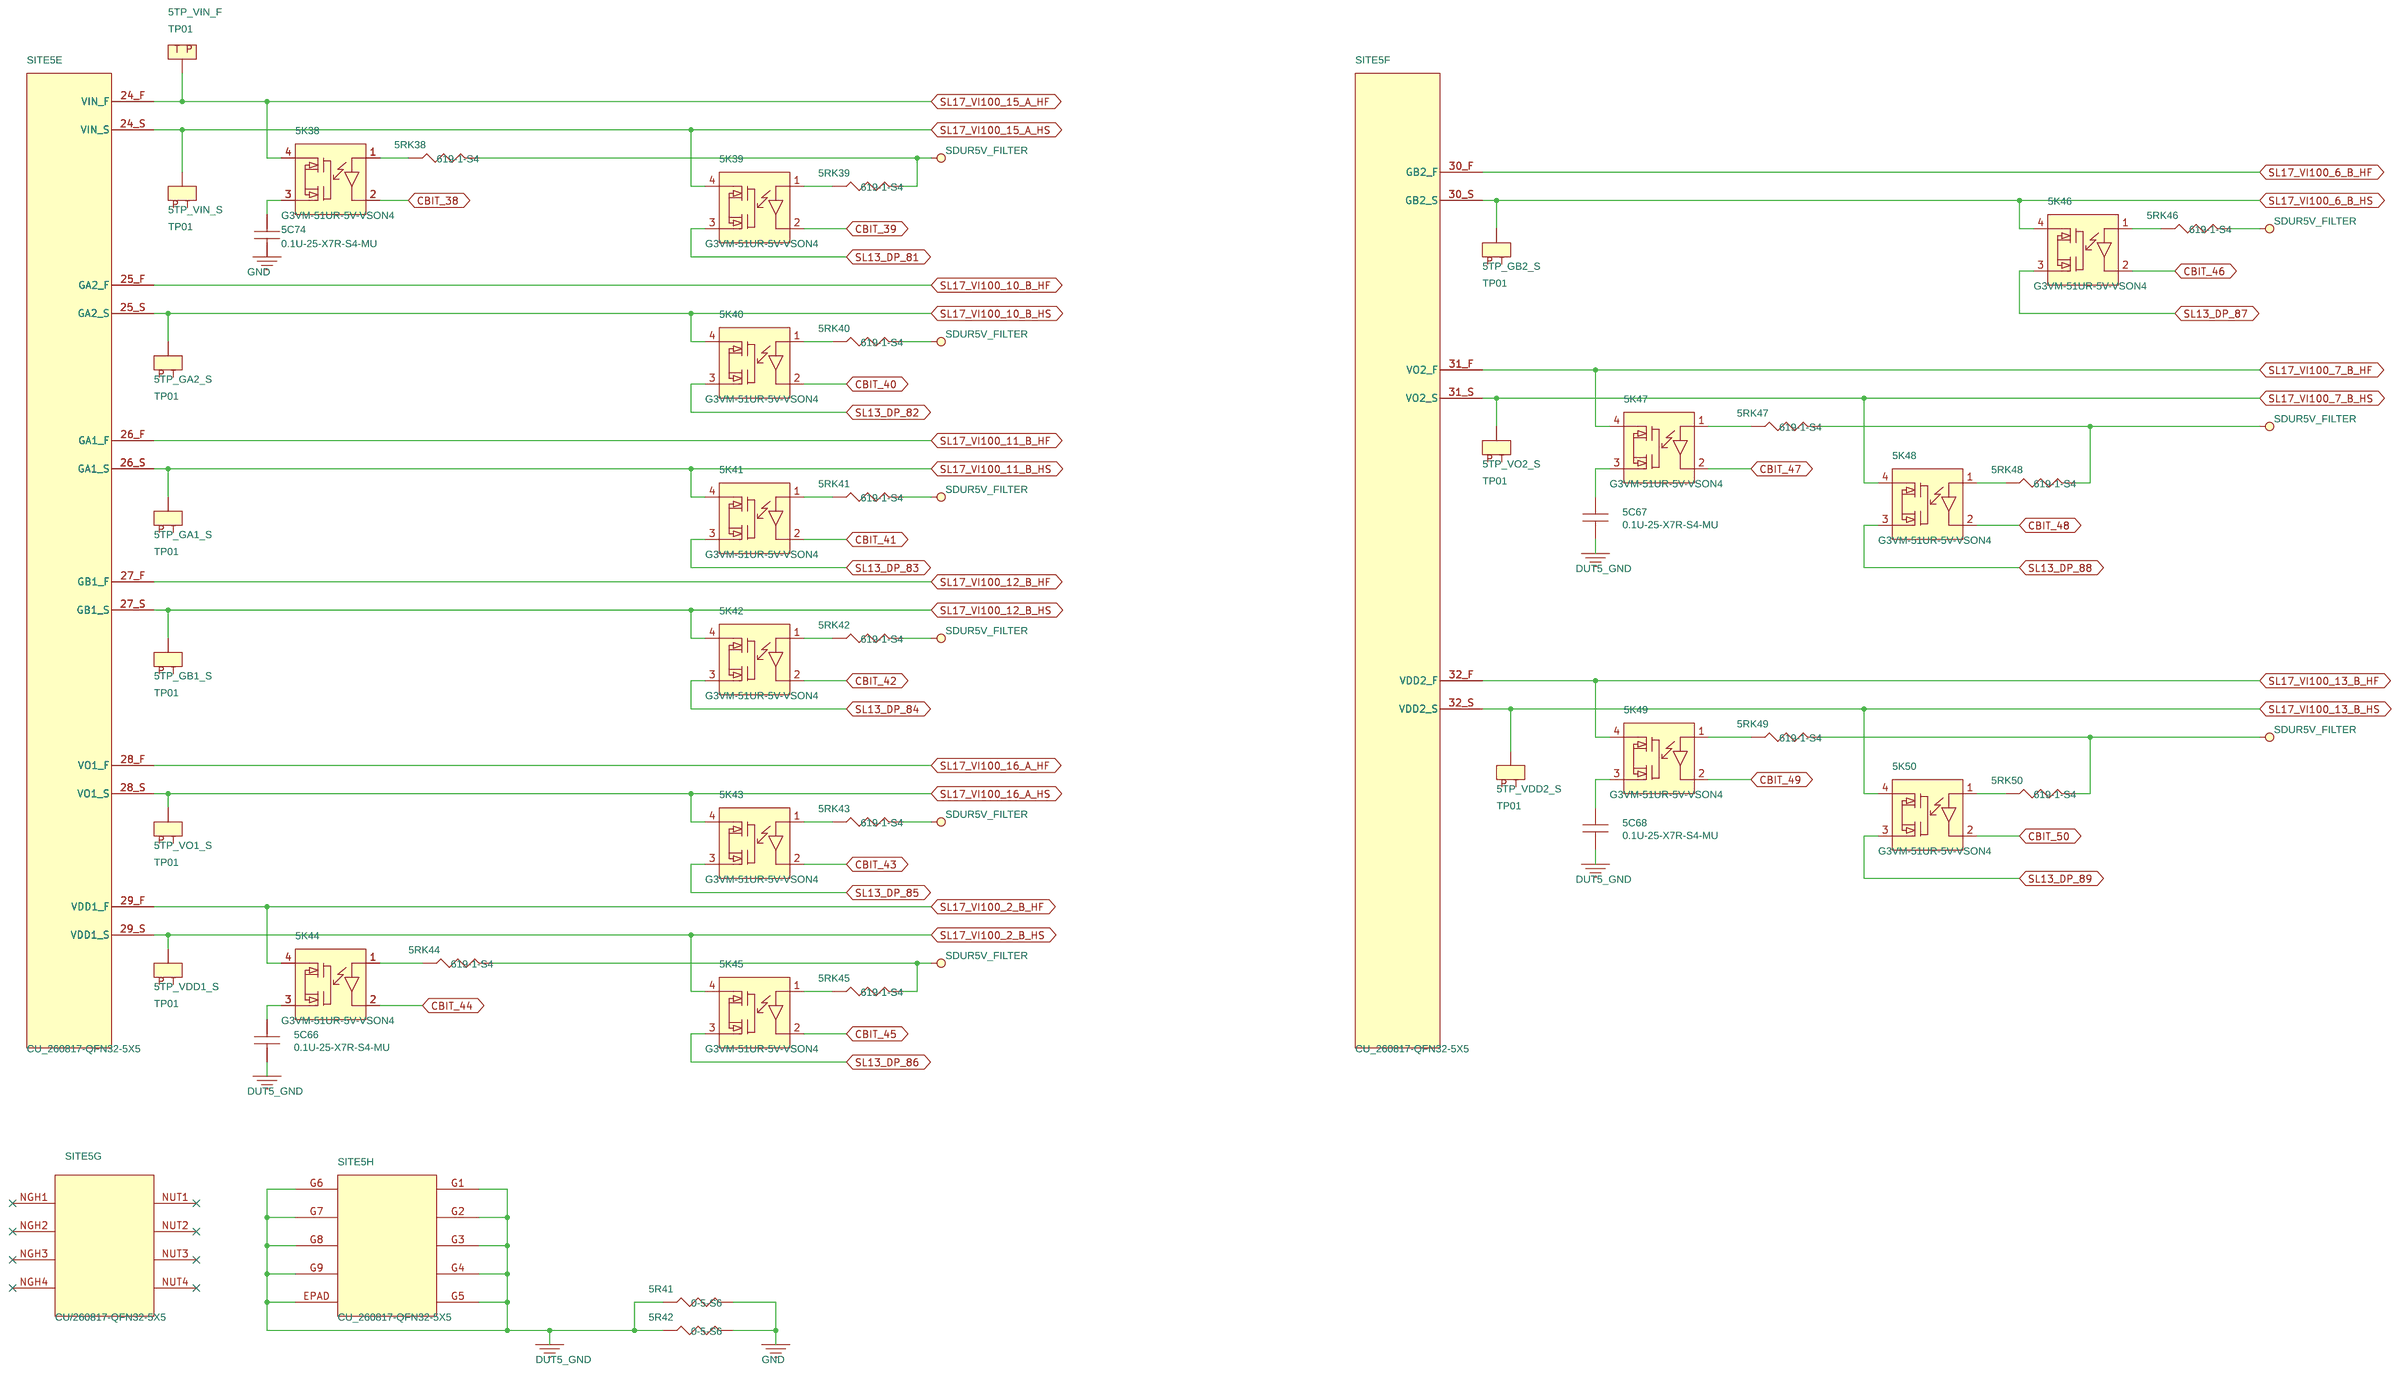
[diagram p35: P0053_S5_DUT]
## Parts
sheet P0051_S5_DUT
SITE5  CU_260817-QFN32-5X5  [SK_QFN5x5_64P_0P5MM_JG_260817]  (sections A,B,C,D,E,F,G,H)
sheet P0053_S5_DUT
5C66  0.1U-25-X7R-S4-MU  [C0402]
5C67  0.1U-25-X7R-S4-MU  [C0402]
5C68  0.1U-25-X7R-S4-MU  [C0402]
5C74  0.1U-25-X7R-S4-MU  [C0402]
5K38  G3VM-51UR-5V-VSON4  [RL_G3VM_4P_VSON4]
5K39  G3VM-51UR-5V-VSON4  [RL_G3VM_4P_VSON4]
5K40  G3VM-51UR-5V-VSON4  [RL_G3VM_4P_VSON4]
5K41  G3VM-51UR-5V-VSON4  [RL_G3VM_4P_VSON4]
5K42  G3VM-51UR-5V-VSON4  [RL_G3VM_4P_VSON4]
5K43  G3VM-51UR-5V-VSON4  [RL_G3VM_4P_VSON4]
5K44  G3VM-51UR-5V-VSON4  [RL_G3VM_4P_VSON4]
5K45  G3VM-51UR-5V-VSON4  [RL_G3VM_4P_VSON4]
5K46  G3VM-51UR-5V-VSON4  [RL_G3VM_4P_VSON4]
5K47  G3VM-51UR-5V-VSON4  [RL_G3VM_4P_VSON4]
5K48  G3VM-51UR-5V-VSON4  [RL_G3VM_4P_VSON4]
5K49  G3VM-51UR-5V-VSON4  [RL_G3VM_4P_VSON4]
5K50  G3VM-51UR-5V-VSON4  [RL_G3VM_4P_VSON4]
5R41  0-5-S6  [R0603]
5R42  0-5-S6  [R0603]
5RK38  619-1-S4  [R0402]
5RK39  619-1-S4  [R0402]
5RK40  619-1-S4  [R0402]
5RK41  619-1-S4  [R0402]
5RK42  619-1-S4  [R0402]
5RK43  619-1-S4  [R0402]
5RK44  619-1-S4  [R0402]
5RK45  619-1-S4  [R0402]
5RK46  619-1-S4  [R0402]
5RK47  619-1-S4  [R0402]
5RK48  619-1-S4  [R0402]
5RK49  619-1-S4  [R0402]
5RK50  619-1-S4  [R0402]
5TP_GA1_S  TP01  [TP_040_T]
5TP_GA2_S  TP01  [TP_040_T]
5TP_GB1_S  TP01  [TP_040_T]
5TP_GB2_S  TP01  [TP_040_T]
5TP_VDD1_S  TP01  [TP_040_T]
5TP_VDD2_S  TP01  [TP_040_T]
5TP_VIN_F  TP01  [TP_040_T]
5TP_VIN_S  TP01  [TP_040_T]
5TP_VO1_S  TP01  [TP_040_T]
5TP_VO2_S  TP01  [TP_040_T]
sheet P0054_S5_DUT
5C70  0.1U-25-X7R-S4-MU  [C0402]
5C71  0.1U-25-X7R-S4-MU  [C0402]
5C72  0.1U-25-X7R-S4-MU  [C0402]
5C73  0.1U-25-X7R-S4-MU  [C0402]
5K51  G3VM-51UR-5V-VSON4  [RL_G3VM_4P_VSON4]
5K52  G3VM-51UR-5V-VSON4  [RL_G3VM_4P_VSON4]
5K53  G3VM-51UR-5V-VSON4  [RL_G3VM_4P_VSON4]
5K54  G3VM-51UR-5V-VSON4  [RL_G3VM_4P_VSON4]
5K55  G3VM-51UR-5V-VSON4  [RL_G3VM_4P_VSON4]
5K56  G3VM-201DR  [RL_G3VM201DR_200V]
5K57  G3VM-51UR-5V-VSON4  [RL_G3VM_4P_VSON4]
5K58  G3VM-51UR-5V-VSON4  [RL_G3VM_4P_VSON4]
5K59  G3VM-51UR-5V-VSON4  [RL_G3VM_4P_VSON4]
5K60  G3VM-51UR-5V-VSON4  [RL_G3VM_4P_VSON4]
5K61  G3VM-51UR-5V-VSON4  [RL_G3VM_4P_VSON4]
5R7  4.7K-1-S4-WA  [R0402]
5R8  4.7K-1-S4-WA  [R0402]
5R11  5K-1-S4-YA  [R0402]
5R14  5K-1-S4-YA  [R0402]
5R15  0-0-S2-KOA  [R0201]
5R16  5.1-1-S2  [R0201]
5R17  0-0-S2-KOA  [R0201]
5R18  5.1-1-S2  [R0201]
5R19  100K-0.1-S4-YA  [R0402]
5R20  100K-0.1-S4-YA  [R0402]
5RK51  619-1-S4  [R0402]
5RK52  619-1-S4  [R0402]
5RK53  619-1-S4  [R0402]
5RK54  619-1-S4  [R0402]
5RK55  619-1-S4  [R0402]
5RK56  619-1-S4  [R0402]
5RK57  619-1-S4  [R0402]
5RK58  619-1-S4  [R0402]
5RK59  619-1-S4  [R0402]
5RK60  619-1-S4  [R0402]
5RK61  619-1-S4  [R0402]
5SH1  SHORT  [DEFAULT_SHORT_SMALL]
5SH2  SHORT  [DEFAULT_SHORT_SMALL]
5SH3  SHORT  [DEFAULT_SHORT_SMALL]
5SH4  SHORT  [DEFAULT_SHORT_SMALL]
5SH5  SHORT  [DEFAULT_SHORT_SMALL]
5SH6  SHORT  [DEFAULT_SHORT_SMALL]
5SH7  SHORT  [DEFAULT_SHORT_SMALL]
5SH8  SHORT  [DEFAULT_SHORT_SMALL]
5SH9  SHORT  [DEFAULT_SHORT_SMALL]
5SH10  SHORT  [DEFAULT_SHORT_SMALL]
5SH11  SHORT  [DEFAULT_SHORT_SMALL]
5SH12  SHORT  [DEFAULT_SHORT_SMALL]
5SH13  SHORT  [DEFAULT_SHORT_SMALL]
5SH14  SHORT  [DEFAULT_SHORT_SMALL]
5SH15  SHORT  [DEFAULT_SHORT_SMALL]
5SH16  SHORT  [DEFAULT_SHORT_SMALL]
5SH17  SHORT  [DEFAULT_SHORT_SMALL]
5SH18  SHORT  [DEFAULT_SHORT_SMALL]
5SH19  SHORT  [DEFAULT_SHORT_SMALL]
5SH20  SHORT  [DEFAULT_SHORT_SMALL]
5SH21  SHORT  [DEFAULT_SHORT_SMALL]
5SH22  SHORT  [DEFAULT_SHORT_SMALL]
5SH23  SHORT  [DEFAULT_SHORT_SMALL]
5SH24  SHORT  [DEFAULT_SHORT_SMALL]
5SH25  SHORT  [DEFAULT_SHORT_SMALL]
5SH26  SHORT  [DEFAULT_SHORT_SMALL]
5SH27  SHORT  [DEFAULT_SHORT_SMALL]
5SHORT1  SHORT  [DEFAULT_SHORT_SMALL]
5SHORT2  SHORT  [DEFAULT_SHORT_SMALL]
5SHORT3  SHORT  [DEFAULT_SHORT_SMALL]
5SHORT4  SHORT  [DEFAULT_SHORT_SMALL]
5SHORT6  SHORT  [DEFAULT_SHORT_SMALL]
5SHORT7  SHORT  [DEFAULT_SHORT_SMALL]
5SHORT8  SHORT  [DEFAULT_SHORT_SMALL]
5SHORT9  SHORT  [DEFAULT_SHORT_SMALL]
5SHORT10  SHORT  [DEFAULT_SHORT_SMALL]
5SHORT11  SHORT  [DEFAULT_SHORT_SMALL]
5TP_IN+_1  TP01  [TP_040_T]
5TP_IN+_2  TP01  [TP_040_T]
5TP_IN+_3  TP01  [TP_040_T]
5TP_IN+_4  TP01  [TP_040_T]
5TP_IN-_1  TP01  [TP_040_T]
5TP_IN-_2  TP01  [TP_040_T]
5TP_IN-_3  TP01  [TP_040_T]
5TP_IN-_4  TP01  [TP_040_T]
5TP_OUT+_1  TP01  [TP_040_T]
5TP_OUT+_2  TP01  [TP_040_T]
5TP_OUT-_1  TP01  [TP_040_T]
5TP_OUT-_2  TP01  [TP_040_T]
5TP_OUT_1  TP01  [TP_040_T]
5TP_OUT_2  TP01  [TP_040_T]
5TP_REF_1  TP01  [TP_040_T]
5TP_REF_2  TP01  [TP_040_T]
5U1  TLV3604DCKR-SC70  [SC70]
5U2  TLV3604DCKR-SC70  [SC70]
5U3  INA186A3QDDFRQ1-SOT23-8  [SOT23_8P_0P65MM_H1P3MM]
5U4  INA186A3QDDFRQ1-SOT23-8  [SOT23_8P_0P65MM_H1P3MM]
sheet P0061_S6_DUT
6C48  0.01U-100-X7R-S6-MU  [C0603]
6C49  0.01U-100-X7R-S6-MU  [C0603]
6C50  0.01U-100-X7R-S6-MU  [C0603]
6C53  1U-16-X5R-S4-YA  [C0402]
6C54  2.2U-16-X-S4-MU  [C0402]
6C58  1U-16-X5R-S4-YA  [C0402]
6C59  4.7U-100-X-SB-MU  [C1210]
6C60  0.01U-100-X7R-S6-MU  [C0603]
6K1  UA2-5NJ-A-V3  [RL_NECUA2_5V_V3]
6K2  G3VM-201DR  [RL_G3VM201DR_200V]
6K3  G3VM-201DR  [RL_G3VM201DR_200V]
6K4  G3VM-201DR  [RL_G3VM201DR_200V]
6K5  G3VM-51UR-5V-VSON4  [RL_G3VM_4P_VSON4]
6K6  G3VM-51UR-5V-VSON4  [RL_G3VM_4P_VSON4]
6K7  G3VM-51UR-5V-VSON4  [RL_G3VM_4P_VSON4]
6K8  G3VM-51UR-5V-VSON4  [RL_G3VM_4P_VSON4]
6K9  G3VM-51UR-5V-VSON4  [RL_G3VM_4P_VSON4]
6K10  G3VM-51UR-5V-VSON4  [RL_G3VM_4P_VSON4]
6K11  G3VM-51UR-5V-VSON4  [RL_G3VM_4P_VSON4]
6K12  G3VM-51UR-5V-VSON4  [RL_G3VM_4P_VSON4]
6K13  G3VM-51UR-5V-VSON4  [RL_G3VM_4P_VSON4]
6K14  G3VM-51UR-5V-VSON4  [RL_G3VM_4P_VSON4]
6K15  UA2-5NJ-A-V3  [RL_NECUA2_5V_V3]
6K16  G3VM-51UR-5V-VSON4  [RL_G3VM_4P_VSON4]
6K17  G3VM-51UR-5V-VSON4  [RL_G3VM_4P_VSON4]
6K18  G3VM-51UR-5V-VSON4  [RL_G3VM_4P_VSON4]
6R1  10K-0.1-S4  [R0402]
6RK2  619-1-S4  [R0402]
6RK3  619-1-S4  [R0402]
6RK4  619-1-S4  [R0402]
6RK5  619-1-S4  [R0402]
6RK6  619-1-S4  [R0402]
6RK7  619-1-S4  [R0402]
6RK8  619-1-S4  [R0402]
6RK9  619-1-S4  [R0402]
6RK10  619-1-S4  [R0402]
6RK11  619-1-S4  [R0402]
6RK12  619-1-S4  [R0402]
6RK13  619-1-S4  [R0402]
6RK14  619-1-S4  [R0402]
6RK16  619-1-S4  [R0402]
6RK17  619-1-S4  [R0402]
6RK18  619-1-S4  [R0402]
6TP_ATT_F  TP01  [TP_040_T]
6TP_ATT_S  TP01  [TP_040_T]
6TP_IS2N_F  TP01  [TP_040_T]
6TP_IS2N_S  TP01  [TP_040_T]
6TP_IS2P_S  TP01  [TP_040_T]
6TP_OPTO_F  TP01  [TP_040_T]
6TP_OPTO_S  TP01  [TP_040_T]
6TP_SRD_F  TP01  [TP_040_T]
6TP_SRD_S  TP01  [TP_040_T]
6TP_SRG_F  TP01  [TP_040_T]
6TP_SRG_S  TP01  [TP_040_T]
6TP_SRS_F  TP01  [TP_040_T]
6TP_SRS_S  TP01  [TP_040_T]
6TP_VCC_F  TP01  [TP_040_T]
6TP_VCC_S  TP01  [TP_040_T]
6TP_VSR_F  TP01  [TP_040_T]
6TP_VSR_S  TP01  [TP_040_T]
SITE6  CU_260817-QFN32-5X5  [SK_QFN5x5_64P_0P5MM_JG_260817]  (sections A,B,C,D,E,F,G,H)
sheet P0062_S6_DUT
6C61  0.01U-100-X7R-S6-MU  [C0603]
6C62  2.2U-16-X-S4-MU  [C0402]
6C63  0.01U-100-X7R-S6-MU  [C0603]
6C64  0.01U-100-X7R-S6-MU  [C0603]
6C65  0.1U-25-X7R-S4-MU  [C0402]
6C69  0.01U-100-X7R-S6-MU  [C0603]
6K19  G3VM-51UR-5V-VSON4  [RL_G3VM_4P_VSON4]
6K20  G3VM-51UR-5V-VSON4  [RL_G3VM_4P_VSON4]
6K21  G3VM-51UR-5V-VSON4  [RL_G3VM_4P_VSON4]
6K22  G3VM-51UR-5V-VSON4  [RL_G3VM_4P_VSON4]
6K23  UA2-5NJ-A-V3  [RL_NECUA2_5V_V3]
6K24  UA2-5NJ-A-V3  [RL_NECUA2_5V_V3]
6K25  G3VM-51UR-5V-VSON4  [RL_G3VM_4P_VSON4]
6K26  G3VM-51UR-5V-VSON4  [RL_G3VM_4P_VSON4]
6K27  G3VM-51UR-5V-VSON4  [RL_G3VM_4P_VSON4]
6K28  G3VM-51UR-5V-VSON4  [RL_G3VM_4P_VSON4]
6K29  G3VM-51UR-5V-VSON4  [RL_G3VM_4P_VSON4]
6K30  G3VM-51UR-5V-VSON4  [RL_G3VM_4P_VSON4]
6K31  G3VM-51UR-5V-VSON4  [RL_G3VM_4P_VSON4]
6K32  G3VM-51UR-5V-VSON4  [RL_G3VM_4P_VSON4]
6K33  G3VM-51UR-5V-VSON4  [RL_G3VM_4P_VSON4]
6K34  G3VM-51UR-5V-VSON4  [RL_G3VM_4P_VSON4]
6K35  G3VM-51UR-5V-VSON4  [RL_G3VM_4P_VSON4]
6K36  G3VM-51UR-5V-VSON4  [RL_G3VM_4P_VSON4]
6K37  G3VM-51UR-5V-VSON4  [RL_G3VM_4P_VSON4]
6RK19  619-1-S4  [R0402]
6RK20  619-1-S4  [R0402]
6RK21  619-1-S4  [R0402]
6RK22  619-1-S4  [R0402]
6RK25  619-1-S4  [R0402]
6RK26  619-1-S4  [R0402]
6RK27  619-1-S4  [R0402]
6RK28  619-1-S4  [R0402]
6RK29  619-1-S4  [R0402]
6RK30  619-1-S4  [R0402]
6RK31  619-1-S4  [R0402]
6RK32  619-1-S4  [R0402]
6RK33  619-1-S4  [R0402]
6RK34  619-1-S4  [R0402]
6RK35  619-1-S4  [R0402]
6RK36  619-1-S4  [R0402]
6RK37  619-1-S4  [R0402]
6TP_C1A_F  TP01  [TP_040_T]
6TP_C1A_S  TP01  [TP_040_T]
6TP_C1B_F  TP01  [TP_040_T]
6TP_C1B_S  TP01  [TP_040_T]
6TP_C2A_F  TP01  [TP_040_T]
6TP_C2A_S  TP01  [TP_040_T]
6TP_C2B_F  TP01  [TP_040_T]
6TP_C2B_S  TP01  [TP_040_T]
6TP_C3A_F  TP01  [TP_040_T]
6TP_C3A_S  TP01  [TP_040_T]
6TP_C3B_F  TP01  [TP_040_T]
6TP_C3B_S  TP01  [TP_040_T]
6TP_IS1N_F  TP01  [TP_040_T]
6TP_IS1N_S  TP01  [TP_040_T]
6TP_IS1P_F  TP01  [TP_040_T]
6TP_SCL_F  TP01  [TP_040_T]
6TP_SDA_F  TP01  [TP_040_T]
6TP_SDA_S  TP01  [TP_040_T]
6TP_STB_F  TP01  [TP_040_T]
6TP_STB_S  TP01  [TP_040_T]
6TP_VDD0_F  TP01  [TP_040_T]
6TP_VDD0_S  TP01  [TP_040_T]
6TP_VDDI_F  TP01  [TP_040_T]
6TP_VDDI_S  TP01  [TP_040_T]
sheet P0063_S6_DUT
6C66  0.1U-25-X7R-S4-MU  [C0402]
6C67  0.1U-25-X7R-S4-MU  [C0402]
6C68  0.1U-25-X7R-S4-MU  [C0402]
6C74  0.1U-25-X7R-S4-MU  [C0402]
6K38  G3VM-51UR-5V-VSON4  [RL_G3VM_4P_VSON4]
6K39  G3VM-51UR-5V-VSON4  [RL_G3VM_4P_VSON4]
6K40  G3VM-51UR-5V-VSON4  [RL_G3VM_4P_VSON4]
6K41  G3VM-51UR-5V-VSON4  [RL_G3VM_4P_VSON4]
6K42  G3VM-51UR-5V-VSON4  [RL_G3VM_4P_VSON4]
6K43  G3VM-51UR-5V-VSON4  [RL_G3VM_4P_VSON4]
6K44  G3VM-51UR-5V-VSON4  [RL_G3VM_4P_VSON4]
6K45  G3VM-51UR-5V-VSON4  [RL_G3VM_4P_VSON4]
6K46  G3VM-51UR-5V-VSON4  [RL_G3VM_4P_VSON4]
6K47  G3VM-51UR-5V-VSON4  [RL_G3VM_4P_VSON4]
6K48  G3VM-51UR-5V-VSON4  [RL_G3VM_4P_VSON4]
6K49  G3VM-51UR-5V-VSON4  [RL_G3VM_4P_VSON4]
6K50  G3VM-51UR-5V-VSON4  [RL_G3VM_4P_VSON4]
6R41  0-5-S6  [R0603]
6R42  0-5-S6  [R0603]
6RK38  619-1-S4  [R0402]
6RK39  619-1-S4  [R0402]
6RK40  619-1-S4  [R0402]
6RK41  619-1-S4  [R0402]
6RK42  619-1-S4  [R0402]
6RK43  619-1-S4  [R0402]
6RK44  619-1-S4  [R0402]
6RK45  619-1-S4  [R0402]
6RK46  619-1-S4  [R0402]
6RK47  619-1-S4  [R0402]
6RK48  619-1-S4  [R0402]
6RK49  619-1-S4  [R0402]
6RK50  619-1-S4  [R0402]
6TP_GA1_S  TP01  [TP_040_T]
6TP_GA2_S  TP01  [TP_040_T]
6TP_GB1_S  TP01  [TP_040_T]
6TP_GB2_S  TP01  [TP_040_T]
6TP_VDD1_S  TP01  [TP_040_T]
6TP_VDD2_S  TP01  [TP_040_T]
6TP_VIN_F  TP01  [TP_040_T]
6TP_VIN_S  TP01  [TP_040_T]
6TP_VO1_S  TP01  [TP_040_T]
6TP_VO2_S  TP01  [TP_040_T]
sheet P0064_S6_DUT
6C70  0.1U-25-X7R-S4-MU  [C0402]
6C71  0.1U-25-X7R-S4-MU  [C0402]
6C72  0.1U-25-X7R-S4-MU  [C0402]
6C73  0.1U-25-X7R-S4-MU  [C0402]
6K51  G3VM-51UR-5V-VSON4  [RL_G3VM_4P_VSON4]
6K52  G3VM-51UR-5V-VSON4  [RL_G3VM_4P_VSON4]
6K53  G3VM-51UR-5V-VSON4  [RL_G3VM_4P_VSON4]
6K54  G3VM-51UR-5V-VSON4  [RL_G3VM_4P_VSON4]
6K55  G3VM-51UR-5V-VSON4  [RL_G3VM_4P_VSON4]
6K56  G3VM-201DR  [RL_G3VM201DR_200V]
6K57  G3VM-51UR-5V-VSON4  [RL_G3VM_4P_VSON4]
6K58  G3VM-51UR-5V-VSON4  [RL_G3VM_4P_VSON4]
6K59  G3VM-51UR-5V-VSON4  [RL_G3VM_4P_VSON4]
6K60  G3VM-51UR-5V-VSON4  [RL_G3VM_4P_VSON4]
6K61  G3VM-51UR-5V-VSON4  [RL_G3VM_4P_VSON4]
6R7  4.7K-1-S4-WA  [R0402]
6R8  4.7K-1-S4-WA  [R0402]
6R11  5K-1-S4-YA  [R0402]
6R14  5K-1-S4-YA  [R0402]
6R15  0-0-S2-KOA  [R0201]
6R16  5.1-1-S2  [R0201]
6R17  0-0-S2-KOA  [R0201]
6R18  5.1-1-S2  [R0201]
6R19  100K-0.1-S4-YA  [R0402]
6R20  100K-0.1-S4-YA  [R0402]
6RK51  619-1-S4  [R0402]
6RK52  619-1-S4  [R0402]
6RK53  619-1-S4  [R0402]
6RK54  619-1-S4  [R0402]
6RK55  619-1-S4  [R0402]
6RK56  619-1-S4  [R0402]
6RK57  619-1-S4  [R0402]
6RK58  619-1-S4  [R0402]
6RK59  619-1-S4  [R0402]
6RK60  619-1-S4  [R0402]
6RK61  619-1-S4  [R0402]
6SH1  SHORT  [DEFAULT_SHORT_SMALL]
6SH2  SHORT  [DEFAULT_SHORT_SMALL]
6SH3  SHORT  [DEFAULT_SHORT_SMALL]
6SH4  SHORT  [DEFAULT_SHORT_SMALL]
6SH5  SHORT  [DEFAULT_SHORT_SMALL]
6SH6  SHORT  [DEFAULT_SHORT_SMALL]
6SH7  SHORT  [DEFAULT_SHORT_SMALL]
6SH8  SHORT  [DEFAULT_SHORT_SMALL]
6SH9  SHORT  [DEFAULT_SHORT_SMALL]
6SH10  SHORT  [DEFAULT_SHORT_SMALL]
6SH11  SHORT  [DEFAULT_SHORT_SMALL]
6SH12  SHORT  [DEFAULT_SHORT_SMALL]
6SH13  SHORT  [DEFAULT_SHORT_SMALL]
6SH14  SHORT  [DEFAULT_SHORT_SMALL]
6SH15  SHORT  [DEFAULT_SHORT_SMALL]
6SH16  SHORT  [DEFAULT_SHORT_SMALL]
6SH17  SHORT  [DEFAULT_SHORT_SMALL]
6SH18  SHORT  [DEFAULT_SHORT_SMALL]
6SH19  SHORT  [DEFAULT_SHORT_SMALL]
6SH20  SHORT  [DEFAULT_SHORT_SMALL]
6SH21  SHORT  [DEFAULT_SHORT_SMALL]
6SH22  SHORT  [DEFAULT_SHORT_SMALL]
6SH23  SHORT  [DEFAULT_SHORT_SMALL]
6SH24  SHORT  [DEFAULT_SHORT_SMALL]
6SH25  SHORT  [DEFAULT_SHORT_SMALL]
6SH26  SHORT  [DEFAULT_SHORT_SMALL]
6SH27  SHORT  [DEFAULT_SHORT_SMALL]
6SHORT1  SHORT  [DEFAULT_SHORT_SMALL]
6SHORT2  SHORT  [DEFAULT_SHORT_SMALL]
6SHORT3  SHORT  [DEFAULT_SHORT_SMALL]
6SHORT4  SHORT  [DEFAULT_SHORT_SMALL]
6SHORT6  SHORT  [DEFAULT_SHORT_SMALL]
6SHORT7  SHORT  [DEFAULT_SHORT_SMALL]
6SHORT8  SHORT  [DEFAULT_SHORT_SMALL]
6SHORT9  SHORT  [DEFAULT_SHORT_SMALL]
6SHORT10  SHORT  [DEFAULT_SHORT_SMALL]
6SHORT11  SHORT  [DEFAULT_SHORT_SMALL]
6TP_IN+_1  TP01  [TP_040_T]
6TP_IN+_2  TP01  [TP_040_T]
6TP_IN+_3  TP01  [TP_040_T]
6TP_IN+_4  TP01  [TP_040_T]
6TP_IN-_1  TP01  [TP_040_T]
6TP_IN-_2  TP01  [TP_040_T]
6TP_IN-_3  TP01  [TP_040_T]
6TP_IN-_4  TP01  [TP_040_T]
6TP_OUT+_1  TP01  [TP_040_T]
6TP_OUT+_2  TP01  [TP_040_T]
6TP_OUT-_1  TP01  [TP_040_T]
6TP_OUT-_2  TP01  [TP_040_T]
6TP_OUT_1  TP01  [TP_040_T]
6TP_OUT_2  TP01  [TP_040_T]
6TP_REF_1  TP01  [TP_040_T]
6TP_REF_2  TP01  [TP_040_T]
6U1  TLV3604DCKR-SC70  [SC70]
6U2  TLV3604DCKR-SC70  [SC70]
6U3  INA186A3QDDFRQ1-SOT23-8  [SOT23_8P_0P65MM_H1P3MM]
6U4  INA186A3QDDFRQ1-SOT23-8  [SOT23_8P_0P65MM_H1P3MM]
sheet P0071_S7_DUT
7C48  0.01U-100-X7R-S6-MU  [C0603]
7C49  0.01U-100-X7R-S6-MU  [C0603]
7C50  0.01U-100-X7R-S6-MU  [C0603]
7C53  1U-16-X5R-S4-YA  [C0402]
7C54  2.2U-16-X-S4-MU  [C0402]
7C58  1U-16-X5R-S4-YA  [C0402]
7C59  4.7U-100-X-SB-MU  [C1210]
7C60  0.01U-100-X7R-S6-MU  [C0603]
7K1  UA2-5NJ-A-V3  [RL_NECUA2_5V_V3]
7K2  G3VM-201DR  [RL_G3VM201DR_200V]
7K3  G3VM-201DR  [RL_G3VM201DR_200V]
7K4  G3VM-201DR  [RL_G3VM201DR_200V]
7K5  G3VM-51UR-5V-VSON4  [RL_G3VM_4P_VSON4]
7K6  G3VM-51UR-5V-VSON4  [RL_G3VM_4P_VSON4]
7K7  G3VM-51UR-5V-VSON4  [RL_G3VM_4P_VSON4]
7K8  G3VM-51UR-5V-VSON4  [RL_G3VM_4P_VSON4]
7K9  G3VM-51UR-5V-VSON4  [RL_G3VM_4P_VSON4]
7K10  G3VM-51UR-5V-VSON4  [RL_G3VM_4P_VSON4]
7K11  G3VM-51UR-5V-VSON4  [RL_G3VM_4P_VSON4]
7K12  G3VM-51UR-5V-VSON4  [RL_G3VM_4P_VSON4]
7K13  G3VM-51UR-5V-VSON4  [RL_G3VM_4P_VSON4]
7K14  G3VM-51UR-5V-VSON4  [RL_G3VM_4P_VSON4]
7K15  UA2-5NJ-A-V3  [RL_NECUA2_5V_V3]
7K16  G3VM-51UR-5V-VSON4  [RL_G3VM_4P_VSON4]
7K17  G3VM-51UR-5V-VSON4  [RL_G3VM_4P_VSON4]
7K18  G3VM-51UR-5V-VSON4  [RL_G3VM_4P_VSON4]
7R1  10K-0.1-S4  [R0402]
7RK2  619-1-S4  [R0402]
7RK3  619-1-S4  [R0402]
7RK4  619-1-S4  [R0402]
7RK5  619-1-S4  [R0402]
7RK6  619-1-S4  [R0402]
7RK7  619-1-S4  [R0402]
7RK8  619-1-S4  [R0402]
7RK9  619-1-S4  [R0402]
7RK10  619-1-S4  [R0402]
7RK11  619-1-S4  [R0402]
7RK12  619-1-S4  [R0402]
7RK13  619-1-S4  [R0402]
7RK14  619-1-S4  [R0402]
7RK16  619-1-S4  [R0402]
7RK17  619-1-S4  [R0402]
7RK18  619-1-S4  [R0402]
7TP_ATT_F  TP01  [TP_040_T]
7TP_ATT_S  TP01  [TP_040_T]
7TP_IS2N_F  TP01  [TP_040_T]
7TP_IS2N_S  TP01  [TP_040_T]
7TP_IS2P_S  TP01  [TP_040_T]
7TP_OPTO_F  TP01  [TP_040_T]
7TP_OPTO_S  TP01  [TP_040_T]
7TP_SRD_F  TP01  [TP_040_T]
7TP_SRD_S  TP01  [TP_040_T]
7TP_SRG_F  TP01  [TP_040_T]
7TP_SRG_S  TP01  [TP_040_T]
7TP_SRS_F  TP01  [TP_040_T]
7TP_SRS_S  TP01  [TP_040_T]
7TP_VCC_F  TP01  [TP_040_T]
7TP_VCC_S  TP01  [TP_040_T]
7TP_VSR_F  TP01  [TP_040_T]
7TP_VSR_S  TP01  [TP_040_T]
sheet P0073_S7_DUT
SITE7  CU_260817-QFN32-5X5  [SK_QFN5x5_64P_0P5MM_JG_260817]  (sections A,B,C,D,E,F,G,H)

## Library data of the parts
SITE5-SITE7 = CU_260817-QFN32-5X5
5C66-5C68 5C70-5C74 6C65-6C68 6C70-6C74 = 0.1U-25-X7R-S4-MU
5K38-5K55 5K57-5K61 6K5-6K14 6K16-6K22 6K25-6K55 6K57-6K61 7K5-7K14 7K16-7K18 = G3VM-51UR-5V-VSON4
5R41 5R42 6R41 6R42 = 0-5-S6
5RK38-5RK61 6RK2-6RK14 6RK16-6RK22 6RK25-6RK61 7RK2-7RK14 7RK16-7RK18 = 619-1-S4
5TP_GA1_S 5TP_GA2_S 5TP_GB1_S 5TP_GB2_S 5TP_IN+_1-5TP_IN+_4 5TP_IN-_1-5TP_IN-_4 5TP_OUT+_1 5TP_OUT+_2 5TP_OUT-_1 5TP_OUT-_2 5TP_OUT_1 5TP_OUT_2 5TP_REF_1 5TP_REF_2 5TP_VDD1_S 5TP_VDD2_S 5TP_VIN_F 5TP_VIN_S 5TP_VO1_S 5TP_VO2_S 6TP_ATT_F 6TP_ATT_S 6TP_C1A_F 6TP_C1A_S 6TP_C1B_F 6TP_C1B_S 6TP_C2A_F 6TP_C2A_S 6TP_C2B_F 6TP_C2B_S 6TP_C3A_F 6TP_C3A_S 6TP_C3B_F 6TP_C3B_S 6TP_GA1_S 6TP_GA2_S 6TP_GB1_S 6TP_GB2_S 6TP_IN+_1-6TP_IN+_4 6TP_IN-_1-6TP_IN-_4 6TP_IS1N_F 6TP_IS1N_S 6TP_IS1P_F 6TP_IS2N_F 6TP_IS2N_S 6TP_IS2P_S 6TP_OPTO_F 6TP_OPTO_S 6TP_OUT+_1 6TP_OUT+_2 6TP_OUT-_1 6TP_OUT-_2 6TP_OUT_1 6TP_OUT_2 6TP_REF_1 6TP_REF_2 6TP_SCL_F 6TP_SDA_F 6TP_SDA_S 6TP_SRD_F 6TP_SRD_S 6TP_SRG_F 6TP_SRG_S 6TP_SRS_F 6TP_SRS_S 6TP_STB_F 6TP_STB_S 6TP_VCC_F 6TP_VCC_S 6TP_VDD0_F 6TP_VDD0_S 6TP_VDD1_S 6TP_VDD2_S 6TP_VDDI_F 6TP_VDDI_S 6TP_VIN_F 6TP_VIN_S 6TP_VO1_S 6TP_VO2_S 6TP_VSR_F 6TP_VSR_S 7TP_ATT_F 7TP_ATT_S 7TP_IS2N_F 7TP_IS2N_S 7TP_IS2P_S 7TP_OPTO_F 7TP_OPTO_S 7TP_SRD_F 7TP_SRD_S 7TP_SRG_F 7TP_SRG_S 7TP_SRS_F 7TP_SRS_S 7TP_VCC_F 7TP_VCC_S 7TP_VSR_F 7TP_VSR_S = TP01_v2
5K56 6K2-6K4 6K56 7K2-7K4 = G3VM-201DR
5R7 5R8 6R7 6R8 = 4.7K-1-S4-WA
5R11 5R14 6R11 6R14 = 5K-1-S4-YA
5R15 5R17 6R15 6R17 = 0-0-S2-KOA
5R16 5R18 6R16 6R18 = 5.1-1-S2
5R19 5R20 6R19 6R20 = 100K-0.1-S4-YA
5SH1-5SH27 6SH1-6SH27 = SHORT: KAIROSNAME: SH1
5SHORT1-5SHORT4 5SHORT6-5SHORT11 6SHORT1-6SHORT4 6SHORT6-6SHORT11 = SHORT
5U1 5U2 6U1 6U2 = TLV3604DCKR-SC70
5U3 5U4 6U3 6U4 = INA186A3QDDFRQ1-SOT23-8
6C48-6C50 6C60 6C61 6C63 6C64 6C69 7C48-7C50 7C60 = 0.01U-100-X7R-S6-MU
6C53 6C58 7C53 7C58 = 1U-16-X5R-S4-YA
6C54 6C62 7C54 = 2.2U-16-X-S4-MU
6C59 7C59 = 4.7U-100-X-SB-MU
6K1 6K15 6K23 6K24 7K1 7K15 = UA2-5NJ-A-V3
6R1 7R1 = 10K-0.1-S4

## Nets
GND: 5R41.2 5R42.2 6R41.2 6R42.2 ; also on sheet 3 4 7 8 11 12 15 16 19 20 21 22 24 28 40 44 48 52
CBIT_2: 7K2.2 ; also on sheet 21 38 46 54
CBIT_3: 7K3.2 ; also on sheet 21 38 46 54
CBIT_4: 7K4.2 ; also on sheet 21 38 46 54
CBIT_5: 7K5.2 ; also on sheet 21 38 46 54
CBIT_6: 7K6.2 ; also on sheet 21 38 46 54
CBIT_7: 7K7.2 ; also on sheet 21 38 46 54
CBIT_8: 7K8.2 ; also on sheet 21 38 46 54
CBIT_9: 7K9.2 ; also on sheet 21 38 46 54
CBIT_10: 7K10.2 ; also on sheet 21 38 46 54
CBIT_11: 7K11.2 ; also on sheet 21 38 46 54
CBIT_12: 7K12.2 ; also on sheet 21 38 46 54
CBIT_13: 7K13.2 ; also on sheet 21 38 46 54
CBIT_14: 7K14.2 ; also on sheet 21 38 46 54
CBIT_16: 7K16.2 ; also on sheet 21 38 46 54
CBIT_17: 7K17.2 ; also on sheet 21 38 46 54
CBIT_18: 7K18.2 ; also on sheet 21 38 46 54
CBIT_38: 5K38.2 ; also on sheet 21 28 44 52
CBIT_39: 5K39.2 ; also on sheet 21 28 44 52
CBIT_40: 5K40.2 ; also on sheet 21 28 44 52
CBIT_41: 5K41.2 ; also on sheet 21 28 44 52
CBIT_42: 5K42.2 ; also on sheet 21 28 44 52
CBIT_43: 5K43.2 ; also on sheet 21 28 44 52
CBIT_44: 5K44.2 ; also on sheet 21 28 44 52
CBIT_45: 5K45.2 ; also on sheet 21 28 44 52
CBIT_46: 5K46.2 ; also on sheet 21 28 44 52
CBIT_47: 5K47.2 ; also on sheet 21 28 44 52
CBIT_48: 5K48.2 ; also on sheet 21 28 44 52
CBIT_49: 5K49.2 ; also on sheet 21 28 44 52
CBIT_50: 5K50.2 ; also on sheet 21 28 44 52
CBIT_51: 5K51.2 ; also on sheet 21 27 43 51
CBIT_52: 5K52.2 ; also on sheet 21 27 43 51
CBIT_53: 5K53.2 ; also on sheet 21 27 43 51
CBIT_54: 5K54.2 ; also on sheet 21 27 43 51
CBIT_55: 5K55.2 ; also on sheet 21 27 43 51
CBIT_56: 5K56.2 ; also on sheet 21 27 43 51
CBIT_57: 5K57.2 ; also on sheet 21 27 43 51
CBIT_58: 5K58.2 ; also on sheet 21 27 43 51
CBIT_59: 5K59.2 ; also on sheet 21 27 43 51
CBIT_60: 5K60.2 ; also on sheet 21 27 43 51
CBIT_62: 6K2.2 ; also on sheet 21 26 42 50
CBIT_63: 6K3.2 ; also on sheet 21 26 42 50
CBIT_64: 6K4.2 ; also on sheet 21 26 42 50
CBIT_65: 6K5.2 ; also on sheet 21 26 42 50
CBIT_66: 6K6.2 ; also on sheet 21 26 42 50
CBIT_67: 6K7.2 ; also on sheet 21 26 42 50
CBIT_68: 6K8.2 ; also on sheet 21 26 42 50
CBIT_69: 6K9.2 ; also on sheet 21 26 42 50
CBIT_70: 6K10.2 ; also on sheet 21 26 42 50
CBIT_71: 6K11.2 ; also on sheet 21 26 42 50
CBIT_72: 6K12.2 ; also on sheet 21 26 42 50
CBIT_73: 6K13.2 ; also on sheet 21 26 42 50
CBIT_74: 6K14.2 ; also on sheet 21 26 42 50
CBIT_76: 6K16.2 ; also on sheet 21 26 42 50
CBIT_77: 6K17.2 ; also on sheet 21 26 42 50
CBIT_78: 6K18.2 ; also on sheet 21 26 42 50
CBIT_79: 6K19.2 ; also on sheet 21 25 41 49
CBIT_80: 6K20.2 ; also on sheet 21 25 41 49
CBIT_81: 6K21.2 ; also on sheet 21 25 41 49
CBIT_82: 6K22.2 ; also on sheet 21 25 41 49
CBIT_85: 6K25.2 ; also on sheet 21 25 41 49
CBIT_86: 6K26.2 ; also on sheet 21 25 41 49
CBIT_87: 6K27.2 ; also on sheet 21 25 41 49
CBIT_88: 6K28.2 ; also on sheet 21 25 41 49
CBIT_89: 6K29.2 ; also on sheet 21 25 41 49
CBIT_90: 6K30.2 ; also on sheet 21 25 41 49
CBIT_91: 6K31.2 ; also on sheet 21 25 41 49
CBIT_92: 6K32.2 ; also on sheet 21 25 41 49
CBIT_93: 6K33.2 ; also on sheet 21 25 41 49
CBIT_94: 6K34.2 ; also on sheet 21 25 41 49
CBIT_95: 6K35.2 ; also on sheet 21 25 41 49
CBIT_96: 6K36.2 ; also on sheet 21 25 41 49
CBIT_97: 6K37.2 ; also on sheet 21 25 41 49
CBIT_98: 6K38.2 ; also on sheet 21 24 40 48
CBIT_99: 6K39.2 ; also on sheet 21 24 40 48
CBIT_100: 6K40.2 ; also on sheet 21 24 40 48
CBIT_101: 6K41.2 ; also on sheet 21 24 40 48
CBIT_102: 6K42.2 ; also on sheet 21 24 40 48
CBIT_103: 6K43.2 ; also on sheet 21 24 40 48
CBIT_104: 6K44.2 ; also on sheet 21 24 40 48
CBIT_105: 6K45.2 ; also on sheet 21 24 40 48
CBIT_106: 6K46.2 ; also on sheet 21 24 40 48
CBIT_107: 6K47.2 ; also on sheet 21 24 40 48
CBIT_108: 6K48.2 ; also on sheet 21 24 40 48
CBIT_109: 6K49.2 ; also on sheet 21 24 40 48
CBIT_110: 6K50.2 ; also on sheet 21 24 40 48
CBIT_111: 6K51.2 ; also on sheet 21 23 39 47
CBIT_112: 6K52.2 ; also on sheet 21 23 39 47
CBIT_113: 6K53.2 ; also on sheet 21 23 39 47
CBIT_114: 6K54.2 ; also on sheet 21 23 39 47
CBIT_115: 6K55.2 ; also on sheet 21 23 39 47
CBIT_116: 6K56.2 ; also on sheet 21 23 39 47
CBIT_117: 6K57.2 ; also on sheet 21 23 39 47
CBIT_118: 6K58.2 ; also on sheet 21 23 39 47
CBIT_119: 6K59.2 ; also on sheet 21 23 39 47
CBIT_120: 6K60.2 ; also on sheet 21 23 39 47
CBIT_121: 7K1.8(V-) ; also on sheet 21 38
CBIT_122: 6K1.8(V-) ; also on sheet 21 26
CBIT_124: 6K23.8(V-) ; also on sheet 21 25
CBIT_125: 6K24.8(V-) ; also on sheet 21 25 29 37
CBIT_126: 6K15.8(V-) 7K15.8(V-) ; also on sheet 21 26 38
CBIT_127: 5K61.2 ; also on sheet 21 27 43 51
CBIT_128: 6K61.2 ; also on sheet 21 23 39 47
DUT5_GND: 5C66.2 5C67.2 5C68.2 5C70.2 5C71.2 5C72.2 5C73.2 5C74.2 5K52.3 5K54.3 5R11.1 5R14.1 5R41.1 5R42.1 5SH1.2 5SH2.2 5SH3.2 5SH4.2 5SH5.2 5SH6.2 5SH7.2 5SH8.2 5SH9.2 5SH10.2 5SH11.2 5SH12.2 5SH13.2 5SH14.2 5SH15.2 5SH16.2 5SH17.2 5SH18.2 5SH19.2 5SH20.2 5SH21.2 5SH22.2 5SH23.2 5SH24.2 5SH25.2 5SH26.2 5SH27.2 5U1.2(VEE) 5U2.2(VEE) 5U3.4(GND) 5U4.4(GND) SITE5.EPAD SITE5.G1 SITE5.G2 SITE5.G3 SITE5.G4 SITE5.G5 SITE5.G6 SITE5.G7 SITE5.G8 SITE5.G9 ; also on sheet 37 38
DUT6_GND: 6C48.2 6C50.2 6C53.2 6C54.2 6C58.2 6C59.2 6C62.2 6C65.2 6C66.2 6C67.2 6C68.2 6C70.2 6C71.2 6C72.2 6C73.2 6C74.2 6K52.3 6K54.3 6R1.2 6R11.1 6R14.1 6R41.1 6R42.1 6SH1.2 6SH2.2 6SH3.2 6SH4.2 6SH5.2 6SH6.2 6SH7.2 6SH8.2 6SH9.2 6SH10.2 6SH11.2 6SH12.2 6SH13.2 6SH14.2 6SH15.2 6SH16.2 6SH17.2 6SH18.2 6SH19.2 6SH20.2 6SH21.2 6SH22.2 6SH23.2 6SH24.2 6SH25.2 6SH26.2 6SH27.2 6U1.2(VEE) 6U2.2(VEE) 6U3.4(GND) 6U4.4(GND) SITE6.3_F(GND_F) SITE6.3_S(GND_S) SITE6.EPAD SITE6.G1 SITE6.G2 SITE6.G3 SITE6.G4 SITE6.G5 SITE6.G6 SITE6.G7 SITE6.G8 SITE6.G9
DUT7_GND: 7C48.2 7C50.2 7C53.2 7C54.2 7C58.2 7C59.2 7R1.2 SITE7.3_F(GND_F) SITE7.3_S(GND_S) ; also on sheet 27 28 29
S5_C1B_F: 5K61.3 ; also on sheet 4 37
S5_IS1N_F: 5K57.4 ; also on sheet 4 37
S5_IS1P_F: 5K58.3 ; also on sheet 4 37
S5_IS2N_F: 5K59.4 ; also on sheet 4 38
S5_IS2P_F: 5K60.3 ; also on sheet 4 38
S5_SCL_F: 5K53.3 5K54.4 ; also on sheet 37
S5_SDA_F: 5K51.3 5K52.4 ; also on sheet 37
S5_SRD_F: 5K56.3 ; also on sheet 38
S5_SRG_F: 5K55.3 ; also on sheet 4 38
S6_C1B_F: 6K27.4 6K61.3 6TP_C1B_F.1(TP) SITE6.17_F(C1B_F) ; also on sheet 3
S6_IS1N_F: 6C69.2 6K57.4 6TP_IS1N_F.1(TP) SITE6.12_F(IS1N_F) ; also on sheet 3
S6_IS1P_F: 6K19.4 6K58.3 6TP_IS1P_F.1(TP) SITE6.11_F(IS1P_F) ; also on sheet 3
S6_IS2N_F: 6C60.2 6K59.4 6TP_IS2N_F.1(TP) SITE6.10_F(IS2N_F) ; also on sheet 3
S6_IS2P_F: 6K16.4 6K60.3 SITE6.9_F(IS2P_F) ; also on sheet 3
S6_SCL_F: 6K24.3 6K53.3 6K54.4 6TP_SCL_F.1(TP) SITE6.15_F(SCL_F)
S6_SDA_F: 6K23.3 6K51.3 6K52.4 6TP_SDA_F.1(TP) SITE6.14_F(SDA_F)
S6_SRD_F: 6K1.3 6K2.4 6K3.4 6K56.3 6TP_SRD_F.1(TP) SITE6.1_F(SRD_F)
S6_SRD_S: 6K1.6 6K4.4 6TP_SRD_S.1(TP) SITE6.1_S(SRD_S)
S6_SRG_F: 6K55.3 6TP_SRG_F.1(TP) SITE6.4_F(SRG_F) ; also on sheet 3
S7_IS2N_F: 7C60.2 7TP_IS2N_F.1(TP) SITE7.10_F(IS2N_F) ; also on sheet 4 27
S7_IS2P_F: 7K16.4 SITE7.9_F(IS2P_F) ; also on sheet 4 27
S7_SRD_F: 7K1.3 7K2.4 7K3.4 7TP_SRD_F.1(TP) SITE7.1_F(SRD_F) ; also on sheet 27
S7_SRD_S: 7K1.6 7K4.4 7TP_SRD_S.1(TP) SITE7.1_S(SRD_S)
S7_SRG_F: 7TP_SRG_F.1(TP) SITE7.4_F(SRG_F) ; also on sheet 4 27
SDUP5V_FILTER: 5C70.1 5C71.1 5U1.5(VCCI/VCCO) 5U2.5(VCCI/VCCO) 6C70.1 6C71.1 6U1.5(VCCI/VCCO) 6U2.5(VCCI/VCCO) ; also on sheet 22 23 27 39 43 47 51
SDUR5V_FILTER: 5RK38.2 5RK39.2 5RK40.2 5RK41.2 5RK42.2 5RK43.2 5RK44.2 5RK45.2 5RK46.2 5RK47.2 5RK48.2 5RK49.2 5RK50.2 5RK51.2 5RK52.2 5RK53.2 5RK54.2 5RK55.1 5RK56.1 5RK57.1 5RK58.1 5RK59.2 5RK60.2 5RK61.2 6K1.1(V+) 6K15.1(V+) 6K23.1(V+) 6K24.1(V+) 6RK2.2 6RK3.2 6RK4.2 6RK5.2 6RK6.2 6RK7.2 6RK8.2 6RK9.2 6RK10.2 6RK11.2 6RK12.2 6RK13.2 6RK14.2 6RK16.2 6RK17.2 6RK18.2 6RK19.2 6RK20.2 6RK21.2 6RK22.2 6RK25.2 6RK26.2 6RK27.2 6RK28.2 6RK29.2 6RK30.2 6RK31.2 6RK32.2 6RK33.2 6RK34.2 6RK35.2 6RK36.2 6RK37.2 6RK38.2 6RK39.2 6RK40.2 6RK41.2 6RK42.2 6RK43.2 6RK44.2 6RK45.2 6RK46.2 6RK47.2 6RK48.2 6RK49.2 6RK50.2 6RK51.2 6RK52.2 6RK53.2 6RK54.2 6RK55.1 6RK56.1 6RK57.1 6RK58.1 6RK59.2 6RK60.2 6RK61.2 7K1.1(V+) 7K15.1(V+) 7RK2.2 7RK3.2 7RK4.2 7RK5.2 7RK6.2 7RK7.2 7RK8.2 7RK9.2 7RK10.2 7RK11.2 7RK12.2 7RK13.2 7RK14.2 7RK16.2 7RK17.2 7RK18.2 ; also on sheet 22 23 24 25 26 27 28 29 37 38 39 40 41 42 43 44 45 46 47 48 49 50 51 52 53 54
SL05_PMVI_3_LS: 5SH17.1 ; also on sheet 16
SL05_PMVI_4_HF: 7K15.4 ; also on sheet 16
SL05_PMVI_4_HS: 7K15.5 ; also on sheet 16
SL05_PMVI_30_HF: 5R7.1 5SHORT3.1 ; also on sheet 16
SL05_PMVI_30_HS: 5SHORT3.2 ; also on sheet 16
SL05_PMVI_30_LS: 5SH18.1 ; also on sheet 16
SL05_PMVI_31_HF: 5R8.1 5SHORT4.1 ; also on sheet 16
SL05_PMVI_31_HS: 5SHORT4.2 ; also on sheet 16
SL05_PMVI_31_LS: 5SH19.1 ; also on sheet 16
SL05_PMVI_32_HF: 5SHORT1.1 5TP_IN-_1.1(TP) 5U1.4(-IN) ; also on sheet 16
SL05_PMVI_32_HS: 5SHORT1.2 ; also on sheet 16
SL05_PMVI_32_LS: 5SH20.1 ; also on sheet 16
SL05_PMVI_33_HF: 5SHORT2.1 5TP_IN-_2.1(TP) 5U2.4(-IN) ; also on sheet 16
SL05_PMVI_33_HS: 5SHORT2.2 ; also on sheet 16
SL05_PMVI_33_LS: 5SH21.1 ; also on sheet 16
SL05_PMVI_34_HF: 5SHORT9.1 5TP_OUT_1.1(TP) 5U3.5(OUT) ; also on sheet 16
SL05_PMVI_34_HS: 5SHORT9.2 ; also on sheet 16
SL05_PMVI_34_LS: 5SH22.1 ; also on sheet 16
SL05_PMVI_35_HF: 5C72.1 5R15.2 5SHORT6.2 5U3.1(VS) ; also on sheet 16
SL05_PMVI_35_HS: 5SHORT6.1 ; also on sheet 16
SL05_PMVI_35_LS: 5SH23.1 ; also on sheet 16
SL05_PMVI_36_HF: 5SHORT11.2 5TP_REF_1.1(TP) 5U3.3(REF) ; also on sheet 16
SL05_PMVI_36_HS: 5SHORT11.1 ; also on sheet 16
SL05_PMVI_36_LS: 5SH24.1 ; also on sheet 16
SL05_PMVI_37_HF: 5SHORT10.1 5TP_OUT_2.1(TP) 5U4.5(OUT) ; also on sheet 16
SL05_PMVI_37_HS: 5SHORT10.2 ; also on sheet 16
SL05_PMVI_37_LS: 5SH25.1 ; also on sheet 16
SL05_PMVI_38_HF: 5C73.1 5R17.2 5SHORT7.2 5U4.1(VS) ; also on sheet 16
SL05_PMVI_38_HS: 5SHORT7.1 ; also on sheet 16
SL05_PMVI_38_LS: 5SH26.1 ; also on sheet 16
SL05_PMVI_39_HF: 5SHORT8.2 5TP_REF_2.1(TP) 5U4.3(REF) ; also on sheet 16
SL05_PMVI_39_HS: 5SHORT8.1 ; also on sheet 16
SL05_PMVI_39_LS: 5SH27.1 ; also on sheet 16
SL06_DP_60: 6K4.3 ; also on sheet 15
SL06_DP_61: 6K6.3 ; also on sheet 15
SL06_DP_62: 6K7.3 ; also on sheet 15
SL06_DP_63: 6K10.3 ; also on sheet 15
SL06_DP_64: 6K14.3 ; also on sheet 15
SL06_DP_65: 6K15.2 ; also on sheet 15
SL06_DP_66: 6K17.3 ; also on sheet 15
SL06_DP_67: 6K18.3 ; also on sheet 15
SL06_DP_68: 6K20.3 ; also on sheet 15
SL06_DP_69: 6K21.3 ; also on sheet 15
SL06_DP_70: 6K22.3 ; also on sheet 15
SL06_DP_71: 6K23.2 ; also on sheet 15
SL06_DP_72: 6K24.2 ; also on sheet 15
SL06_DP_73: 6K26.3 ; also on sheet 15
SL06_DP_74: 6K28.3 ; also on sheet 15
SL06_DP_75: 6K29.3 ; also on sheet 15
SL06_DP_76: 6K31.3 ; also on sheet 15
SL06_DP_77: 6K32.3 ; also on sheet 15
SL06_DP_78: 6K34.3 ; also on sheet 15
SL06_DP_79: 6K35.3 ; also on sheet 15
SL06_DP_80: 6K37.3 ; also on sheet 15
SL06_DP_81: 6K39.3 ; also on sheet 15
SL06_DP_82: 6K40.3 ; also on sheet 15
SL06_DP_83: 6K41.3 ; also on sheet 15
SL06_DP_84: 6K42.3 ; also on sheet 15
SL06_DP_85: 6K43.3 ; also on sheet 15
SL06_DP_86: 6K45.3 ; also on sheet 15
SL06_DP_87: 6K46.3 ; also on sheet 15
SL06_DP_88: 6K48.3 ; also on sheet 15
SL06_DP_89: 6K50.3 ; also on sheet 15
SL06_DP_133: 6TP_OUT+_1.1(TP) 6U1.1(OUT+) ; also on sheet 15
SL06_DP_134: 6TP_OUT-_1.1(TP) 6U1.6(OUT-) ; also on sheet 15
SL06_DP_135: 6TP_OUT+_2.1(TP) 6U2.1(OUT+) ; also on sheet 15
SL06_DP_136: 6TP_OUT-_2.1(TP) 6U2.6(OUT-) ; also on sheet 15
SL06_DP_137: 6R15.1 6U3.2(ENABLE) ; also on sheet 15
SL06_DP_138: 6R17.1 6U4.2(ENABLE) ; also on sheet 15
SL09_FPVI_6_A_HF: 7K1.4 ; also on sheet 12
SL09_FPVI_6_A_HS: 7K1.5 ; also on sheet 12
SL10_FPVI_2_A_HF: 6K1.4 ; also on sheet 11
SL10_FPVI_2_A_HS: 6K1.5 ; also on sheet 11
SL13_DP_81: 5K39.3 ; also on sheet 8
SL13_DP_82: 5K40.3 ; also on sheet 8
SL13_DP_83: 5K41.3 ; also on sheet 8
SL13_DP_84: 5K42.3 ; also on sheet 8
SL13_DP_85: 5K43.3 ; also on sheet 8
SL13_DP_86: 5K45.3 ; also on sheet 8
SL13_DP_87: 5K46.3 ; also on sheet 8
SL13_DP_88: 5K48.3 ; also on sheet 8
SL13_DP_89: 5K50.3 ; also on sheet 8
SL13_DP_90: 7K4.3 ; also on sheet 8
SL13_DP_91: 7K6.3 ; also on sheet 8
SL13_DP_92: 7K7.3 ; also on sheet 8
SL13_DP_93: 7K10.3 ; also on sheet 8
SL13_DP_94: 7K14.3 ; also on sheet 8
SL13_DP_95: 7K15.2 ; also on sheet 8
SL13_DP_96: 7K17.3 ; also on sheet 8
SL13_DP_97: 7K18.3 ; also on sheet 8
SL13_DP_133: 5TP_OUT+_1.1(TP) 5U1.1(OUT+) ; also on sheet 8
SL13_DP_134: 5TP_OUT-_1.1(TP) 5U1.6(OUT-) ; also on sheet 8
SL13_DP_135: 5TP_OUT+_2.1(TP) 5U2.1(OUT+) ; also on sheet 8
SL13_DP_136: 5TP_OUT-_2.1(TP) 5U2.6(OUT-) ; also on sheet 8
SL13_DP_137: 5R15.1 5U3.2(ENABLE) ; also on sheet 8
SL13_DP_138: 5R17.1 5U4.2(ENABLE) ; also on sheet 8
SL14_PMVI_3_HF: 6K15.4 ; also on sheet 7
SL14_PMVI_3_HS: 6K15.5 ; also on sheet 7
SL14_PMVI_3_LS: 6SH17.1 ; also on sheet 7
SL14_PMVI_30_HF: 6R7.1 6SHORT3.1 ; also on sheet 7
SL14_PMVI_30_HS: 6SHORT3.2 ; also on sheet 7
SL14_PMVI_30_LS: 6SH18.1 ; also on sheet 7
SL14_PMVI_31_HF: 6R8.1 6SHORT4.1 ; also on sheet 7
SL14_PMVI_31_HS: 6SHORT4.2 ; also on sheet 7
SL14_PMVI_31_LS: 6SH19.1 ; also on sheet 7
SL14_PMVI_32_HF: 6SHORT1.1 6TP_IN-_1.1(TP) 6U1.4(-IN) ; also on sheet 7
SL14_PMVI_32_HS: 6SHORT1.2 ; also on sheet 7
SL14_PMVI_32_LS: 6SH20.1 ; also on sheet 7
SL14_PMVI_33_HF: 6SHORT2.1 6TP_IN-_2.1(TP) 6U2.4(-IN) ; also on sheet 7
SL14_PMVI_33_HS: 6SHORT2.2 ; also on sheet 7
SL14_PMVI_33_LS: 6SH21.1 ; also on sheet 7
SL14_PMVI_34_HF: 6SHORT9.1 6TP_OUT_1.1(TP) 6U3.5(OUT) ; also on sheet 7
SL14_PMVI_34_HS: 6SHORT9.2 ; also on sheet 7
SL14_PMVI_34_LS: 6SH22.1 ; also on sheet 7
SL14_PMVI_35_HF: 6C72.1 6R15.2 6SHORT6.2 6U3.1(VS) ; also on sheet 7
SL14_PMVI_35_HS: 6SHORT6.1 ; also on sheet 7
SL14_PMVI_35_LS: 6SH23.1 ; also on sheet 7
SL14_PMVI_36_HF: 6SHORT11.2 6TP_REF_1.1(TP) 6U3.3(REF) ; also on sheet 7
SL14_PMVI_36_HS: 6SHORT11.1 ; also on sheet 7
SL14_PMVI_36_LS: 6SH24.1 ; also on sheet 7
SL14_PMVI_37_HF: 6SHORT10.1 6TP_OUT_2.1(TP) 6U4.5(OUT) ; also on sheet 7
SL14_PMVI_37_HS: 6SHORT10.2 ; also on sheet 7
SL14_PMVI_37_LS: 6SH25.1 ; also on sheet 7
SL14_PMVI_38_HF: 6C73.1 6R17.2 6SHORT7.2 6U4.1(VS) ; also on sheet 7
SL14_PMVI_38_HS: 6SHORT7.1 ; also on sheet 7
SL14_PMVI_38_LS: 6SH26.1 ; also on sheet 7
SL14_PMVI_39_HF: 6SHORT8.2 6TP_REF_2.1(TP) 6U4.3(REF) ; also on sheet 7
SL14_PMVI_39_HS: 6SHORT8.1 ; also on sheet 7
SL14_PMVI_39_LS: 6SH27.1 ; also on sheet 7
SL17_VI100_1_LS: 5SH1.1 ; also on sheet 4
SL17_VI100_2_B_HF: 5K44.4 SITE5.29_F(VDD1_F) ; also on sheet 4
SL17_VI100_2_B_HS: 5K45.4 5TP_VDD1_S.1(TP) SITE5.29_S(VDD1_S) ; also on sheet 4
SL17_VI100_2_LS: 5SH2.1 ; also on sheet 4
SL17_VI100_3_LS: 5SH3.1 ; also on sheet 4
SL17_VI100_4_LS: 5SH4.1 ; also on sheet 4
SL17_VI100_5_LS: 5SH5.1 ; also on sheet 4
SL17_VI100_6_B_HF: SITE5.30_F(GB2_F) ; also on sheet 4
SL17_VI100_6_B_HS: 5K46.4 5TP_GB2_S.1(TP) SITE5.30_S(GB2_S) ; also on sheet 4
SL17_VI100_6_LS: 5SH6.1 ; also on sheet 4
SL17_VI100_7_B_HF: 5K47.4 SITE5.31_F(VO2_F) ; also on sheet 4
SL17_VI100_7_B_HS: 5K48.4 5TP_VO2_S.1(TP) SITE5.31_S(VO2_S) ; also on sheet 4
SL17_VI100_7_LS: 5SH7.1 ; also on sheet 4
SL17_VI100_8_LS: 5SH8.1 ; also on sheet 4
SL17_VI100_9_LS: 5SH9.1 ; also on sheet 4
SL17_VI100_10_B_HF: SITE5.25_F(GA2_F) ; also on sheet 4
SL17_VI100_10_B_HS: 5K40.4 5TP_GA2_S.1(TP) SITE5.25_S(GA2_S) ; also on sheet 4
SL17_VI100_10_LS: 5SH10.1 ; also on sheet 4
SL17_VI100_11_B_HF: SITE5.26_F(GA1_F) ; also on sheet 4
SL17_VI100_11_B_HS: 5K41.4 5TP_GA1_S.1(TP) SITE5.26_S(GA1_S) ; also on sheet 4
SL17_VI100_11_LS: 5SH11.1 ; also on sheet 4
SL17_VI100_12_B_HF: SITE5.27_F(GB1_F) ; also on sheet 4
SL17_VI100_12_B_HS: 5K42.4 5TP_GB1_S.1(TP) SITE5.27_S(GB1_S) ; also on sheet 4
SL17_VI100_12_LS: 5SH12.1 ; also on sheet 4
SL17_VI100_13_B_HF: 5K49.4 SITE5.32_F(VDD2_F) ; also on sheet 4
SL17_VI100_13_B_HS: 5K50.4 5TP_VDD2_S.1(TP) SITE5.32_S(VDD2_S) ; also on sheet 4
SL17_VI100_13_LS: 5SH13.1 ; also on sheet 4
SL17_VI100_14_LS: 5SH14.1 ; also on sheet 4
SL17_VI100_15_A_HF: 5K38.4 5TP_VIN_F.1(TP) SITE5.24_F(VIN_F) ; also on sheet 4
SL17_VI100_15_A_HS: 5K39.4 5TP_VIN_S.1(TP) SITE5.24_S(VIN_S) ; also on sheet 4
SL17_VI100_15_LS: 5SH15.1 ; also on sheet 4
SL17_VI100_16_A_HF: SITE5.28_F(VO1_F) ; also on sheet 4
SL17_VI100_16_A_HS: 5K43.4 5TP_VO1_S.1(TP) SITE5.28_S(VO1_S) ; also on sheet 4
SL17_VI100_16_LS: 5SH16.1 ; also on sheet 4
SL17_VI100_17_A_HF: 7K1.2 ; also on sheet 4
SL17_VI100_17_A_HS: 7K1.7 ; also on sheet 4
SL17_VI100_18_A_HF: 7C49.2 7K5.4 7TP_SRS_F.1(TP) SITE7.2_F(SRS_F) ; also on sheet 4
SL17_VI100_18_A_HS: 7K6.4 7TP_SRS_S.1(TP) SITE7.2_S(SRS_S) ; also on sheet 4
SL17_VI100_19_A_HF: 7K8.4 7K9.4 7TP_VSR_F.1(TP) SITE7.5_F(VSR_F) ; also on sheet 4
SL17_VI100_19_A_HS: 7K10.4 7TP_VSR_S.1(TP) SITE7.5_S(VSR_S) ; also on sheet 4
SL17_VI100_19_B_HS: 7K18.4 7TP_IS2N_S.1(TP) SITE7.10_S(IS2N_S) ; also on sheet 4
SL17_VI100_20_A_HS: 7K7.4 7TP_SRG_S.1(TP) SITE7.4_S(SRG_S) ; also on sheet 4
SL17_VI100_21_A_HF: 7K11.4 7K12.4 7K13.4 7TP_VCC_F.1(TP) SITE7.6_F(VCC_F) ; also on sheet 4
SL17_VI100_21_A_HS: 7TP_VCC_S.1(TP) SITE7.6_S(VCC_S) ; also on sheet 4
SL17_VI100_22_A_HF: 7TP_OPTO_F.1(TP) SITE7.7_F(OPTO_F) ; also on sheet 4
SL17_VI100_22_A_HS: 7K14.4 7TP_OPTO_S.1(TP) SITE7.7_S(OPTO_S) ; also on sheet 4
SL17_VI100_32_B_HS: 7K17.4 7TP_IS2P_S.1(TP) SITE7.9_S(IS2P_S) ; also on sheet 4
SL18_VI100_1_A_HF: 6K1.2 ; also on sheet 3
SL18_VI100_1_A_HS: 6K1.7 ; also on sheet 3
SL18_VI100_1_LS: 6SH1.1 ; also on sheet 3
SL18_VI100_2_A_HF: 6C49.2 6K5.4 6TP_SRS_F.1(TP) SITE6.2_F(SRS_F) ; also on sheet 3
SL18_VI100_2_A_HS: 6K6.4 6TP_SRS_S.1(TP) SITE6.2_S(SRS_S) ; also on sheet 3
SL18_VI100_2_B_HF: 6K44.4 SITE6.29_F(VDD1_F) ; also on sheet 3
SL18_VI100_2_B_HS: 6K45.4 6TP_VDD1_S.1(TP) SITE6.29_S(VDD1_S) ; also on sheet 3
SL18_VI100_2_LS: 6SH2.1 ; also on sheet 3
SL18_VI100_3_A_HF: 6K8.4 6K9.4 6TP_VSR_F.1(TP) SITE6.5_F(VSR_F) ; also on sheet 3
SL18_VI100_3_A_HS: 6K10.4 6TP_VSR_S.1(TP) SITE6.5_S(VSR_S) ; also on sheet 3
SL18_VI100_3_B_HS: 6K18.4 6TP_IS2N_S.1(TP) SITE6.10_S(IS2N_S) ; also on sheet 3
SL18_VI100_3_LS: 6SH3.1 ; also on sheet 3
SL18_VI100_4_A_HS: 6K7.4 6TP_SRG_S.1(TP) SITE6.4_S(SRG_S) ; also on sheet 3
SL18_VI100_4_B_HS: 6K28.4 6TP_C1B_S.1(TP) SITE6.17_S(C1B_S) ; also on sheet 3
SL18_VI100_4_LS: 6SH4.1 ; also on sheet 3
SL18_VI100_5_A_HF: 6K11.4 6K12.4 6K13.4 6TP_VCC_F.1(TP) SITE6.6_F(VCC_F) ; also on sheet 3
SL18_VI100_5_A_HS: 6TP_VCC_S.1(TP) SITE6.6_S(VCC_S) ; also on sheet 3
SL18_VI100_5_LS: 6SH5.1 ; also on sheet 3
SL18_VI100_6_A_HF: 6TP_OPTO_F.1(TP) SITE6.7_F(OPTO_F) ; also on sheet 3
SL18_VI100_6_A_HS: 6K14.4 6TP_OPTO_S.1(TP) SITE6.7_S(OPTO_S) ; also on sheet 3
SL18_VI100_6_B_HF: SITE6.30_F(GB2_F) ; also on sheet 3
SL18_VI100_6_B_HS: 6K46.4 6TP_GB2_S.1(TP) SITE6.30_S(GB2_S) ; also on sheet 3
SL18_VI100_6_LS: 6SH6.1 ; also on sheet 3
SL18_VI100_7_A_HF: 6TP_STB_F.1(TP) SITE6.13_F(STB_F) ; also on sheet 3
SL18_VI100_7_A_HS: 6K22.4 6TP_STB_S.1(TP) SITE6.13_S(STB_S) ; also on sheet 3
SL18_VI100_7_B_HF: 6K47.4 SITE6.31_F(VO2_F) ; also on sheet 3
SL18_VI100_7_B_HS: 6K48.4 6TP_VO2_S.1(TP) SITE6.31_S(VO2_S) ; also on sheet 3
SL18_VI100_7_LS: 6SH7.1 ; also on sheet 3
SL18_VI100_8_A_HF: 6K23.4 ; also on sheet 3
SL18_VI100_8_A_HS: 6K23.5 ; also on sheet 3
SL18_VI100_8_B_HF: 6C61.2 6TP_C2B_F.1(TP) SITE6.20_F(C2B_F) ; also on sheet 3
SL18_VI100_8_B_HS: 6K32.4 6TP_C2B_S.1(TP) SITE6.20_S(C2B_S) ; also on sheet 3
SL18_VI100_8_LS: 6SH8.1 ; also on sheet 3
SL18_VI100_9_A_HF: 6K24.4 ; also on sheet 3
SL18_VI100_9_A_HS: 6K24.5 ; also on sheet 3
SL18_VI100_9_B_HF: 6K33.4 6TP_C3B_F.1(TP) SITE6.21_F(C3B_F) ; also on sheet 3
SL18_VI100_9_B_HS: 6K34.4 6TP_C3B_S.1(TP) SITE6.21_S(C3B_S) ; also on sheet 3
SL18_VI100_9_LS: 6SH9.1 ; also on sheet 3
SL18_VI100_10_A_HF: 6K25.4 6TP_VDD0_F.1(TP) SITE6.16_F(VDD0_F) ; also on sheet 3
SL18_VI100_10_A_HS: 6K26.4 6TP_VDD0_S.1(TP) SITE6.16_S(VDD0_S) ; also on sheet 3
SL18_VI100_10_B_HF: SITE6.25_F(GA2_F) ; also on sheet 3
SL18_VI100_10_B_HS: 6K40.4 6TP_GA2_S.1(TP) SITE6.25_S(GA2_S) ; also on sheet 3
SL18_VI100_10_LS: 6SH10.1 ; also on sheet 3
SL18_VI100_11_A_HF: 6C63.2 6TP_C1A_F.1(TP) SITE6.18_F(C1A_F) ; also on sheet 3
SL18_VI100_11_A_HS: 6K29.4 6TP_C1A_S.1(TP) SITE6.18_S(C1A_S) ; also on sheet 3
SL18_VI100_11_B_HF: SITE6.26_F(GA1_F) ; also on sheet 3
SL18_VI100_11_B_HS: 6K41.4 6TP_GA1_S.1(TP) SITE6.26_S(GA1_S) ; also on sheet 3
SL18_VI100_11_LS: 6SH11.1 ; also on sheet 3
SL18_VI100_12_A_HF: 6K30.4 6TP_C2A_F.1(TP) SITE6.19_F(C2A_F) ; also on sheet 3
SL18_VI100_12_A_HS: 6K31.4 6TP_C2A_S.1(TP) SITE6.19_S(C2A_S) ; also on sheet 3
SL18_VI100_12_B_HF: SITE6.27_F(GB1_F) ; also on sheet 3
SL18_VI100_12_B_HS: 6K42.4 6TP_GB1_S.1(TP) SITE6.27_S(GB1_S) ; also on sheet 3
SL18_VI100_12_LS: 6SH12.1 ; also on sheet 3
SL18_VI100_13_A_HF: 6C64.2 6TP_C3A_F.1(TP) SITE6.22_F(C3A_F) ; also on sheet 3
SL18_VI100_13_A_HS: 6K35.4 6TP_C3A_S.1(TP) SITE6.22_S(C3A_S) ; also on sheet 3
SL18_VI100_13_B_HF: 6K49.4 SITE6.32_F(VDD2_F) ; also on sheet 3
SL18_VI100_13_B_HS: 6K50.4 6TP_VDD2_S.1(TP) SITE6.32_S(VDD2_S) ; also on sheet 3
SL18_VI100_13_LS: 6SH13.1 ; also on sheet 3
SL18_VI100_14_A_HF: 6K36.4 6TP_VDDI_F.1(TP) SITE6.23_F(VDDI_F) ; also on sheet 3
SL18_VI100_14_A_HS: 6K37.4 6TP_VDDI_S.1(TP) SITE6.23_S(VDDI_S) ; also on sheet 3
SL18_VI100_14_B_HS: 6K21.4 6TP_IS1N_S.1(TP) SITE6.12_S(IS1N_S) ; also on sheet 3
SL18_VI100_14_LS: 6SH14.1 ; also on sheet 3
SL18_VI100_15_A_HF: 6K38.4 6TP_VIN_F.1(TP) SITE6.24_F(VIN_F) ; also on sheet 3
SL18_VI100_15_A_HS: 6K39.4 6TP_VIN_S.1(TP) SITE6.24_S(VIN_S) ; also on sheet 3
SL18_VI100_15_B_HS: 6K20.4 SITE6.11_S(IS1P_S) ; also on sheet 3
SL18_VI100_15_LS: 6SH15.1 ; also on sheet 3
SL18_VI100_16_A_HF: SITE6.28_F(VO1_F) ; also on sheet 3
SL18_VI100_16_A_HS: 6K43.4 6TP_VO1_S.1(TP) SITE6.28_S(VO1_S) ; also on sheet 3
SL18_VI100_16_B_HS: 6K17.4 6TP_IS2P_S.1(TP) SITE6.9_S(IS2P_S) ; also on sheet 3
SL18_VI100_16_LS: 6SH16.1 ; also on sheet 3
N18724850: 5K39.1 5RK39.1
N18724851: 5K38.1 5RK38.1
N18724857: 5C74.1 5K38.3
N18724876: 5K40.1 5RK40.1
N18724889: 5K41.1 5RK41.1
N18724902: 5K42.1 5RK42.1
N18724914: 5K43.1 5RK43.1
N18724927: 5K45.1 5RK45.1
N18724928: 5K44.1 5RK44.1
N18724938: 5C66.1 5K44.3
N18724956: 5K46.1 5RK46.1
N18724972: 5C67.1 5K47.3
N18724985: 5K48.1 5RK48.1
N18724986: 5K47.1 5RK47.1
N18724996: 5C68.1 5K49.3
N18725009: 5K50.1 5RK50.1
N18725010: 5K49.1 5RK49.1
N18725824: 5K51.4 5R7.2
N18725836: 5K53.4 5R8.2
N18725838: 5K53.1 5RK53.1
N18725860: 5R11.2 5R19.1 5TP_IN+_1.1(TP) 5U1.3(+IN)
N18725872: 5R14.2 5R20.1 5TP_IN+_2.1(TP) 5U2.3(+IN)
N18725882: 5K55.1 5RK59.1
N18725885: 5K55.4 5R19.2
N18725887: 5K56.1 5RK60.1
N18725904: 5K57.3 5R16.1 5TP_IN-_3.1(TP) 5U3.8(IN-)
N18725905: 5K58.4 5R16.2 5TP_IN+_3.1(TP) 5U3.7(IN+)
N18725933: 5K60.4 5R18.2 5TP_IN+_4.1(TP) 5U4.7(IN+)
N18725937: 5K59.3 5R18.1 5TP_IN-_4.1(TP) 5U4.8(IN-)
N18725948: 5K56.4 5K61.4 5R20.2
N18725949: 5K54.1 5RK54.1
N18725953: 5K51.1 5RK51.1
N18725955: 5K52.1 5RK52.1
N18726019: 5K57.1 5RK55.2
N18726020: 5K58.1 5RK56.2
N18726021: 5K59.1 5RK57.2
N18726022: 5K60.1 5RK58.2
N18726025: 5K61.1 5RK61.1
N18727156: 6C48.1 6K2.3
N18727165: 6C49.1 6K3.3
N18727174: 6C50.1 6K5.3
N18727207: 6K7.1 6RK7.1
N18727214: 6C53.1 6K8.3
N18727223: 6C54.1 6K9.3
N18727253: 6C59.1 6K12.3
N18727260: 6K13.3 6R1.1
N18727278: 6K15.6 6TP_ATT_S.1(TP) SITE6.8_S(ATT_S)
N18727296: 6K5.1 6RK5.1
N18727298: 6K6.1 6RK6.1
N18727300: 6K8.1 6RK8.1
N18727301: 6K9.1 6RK9.1
N18727302: 6K10.1 6RK10.1
N18727303: 6K11.1 6RK11.1
N18727306: 6C58.1 6K11.3
N18727309: 6K12.1 6RK12.1
N18727311: 6K13.1 6RK13.1
N18727314: 6K14.1 6RK14.1
N18727316: 6K2.1 6RK2.1
N18727317: 6K3.1 6RK3.1
N18727318: 6K4.1 6RK4.1
N18727338: 6K15.3 6TP_ATT_F.1(TP) SITE6.8_F(ATT_F)
N18727350: 6C60.1 6K16.3
N18727363: 6K17.1 6RK17.1
N18727377: 6K16.1 6RK16.1
N18727381: 6K18.1 6RK18.1
N18728531: 6C69.1 6K19.3
N18728558: 6K19.1 6RK19.1
N18728560: 6K20.1 6RK20.1
N18728561: 6K21.1 6RK21.1
N18728586: 6K22.1 6RK22.1
N18728592: 6K23.6 6TP_SDA_S.1(TP) SITE6.14_S(SDA_S)
N18728606: 6K24.6 SITE6.15_S(SCL_S)
N18728616: 6C62.1 6K25.3
N18728634: 6K25.1 6RK25.1
N18728638: 6K26.1 6RK26.1
N18728643: 6C63.1 6K27.3
N18728659: 6K28.1 6RK28.1
N18728680: 6K27.1 6RK27.1
N18728682: 6K29.1 6RK29.1
N18728687: 6C61.1 6K30.3
N18728701: 6K31.1 6RK31.1
N18728721: 6K30.1 6RK30.1
N18728724: 6K32.1 6RK32.1
N18728726: 6K35.1 6RK35.1
N18728728: 6K34.1 6RK34.1
N18728730: 6K33.1 6RK33.1
N18728733: 6C64.1 6K33.3
N18728768: 6K37.1 6RK37.1
N18728769: 6K36.1 6RK36.1
N18728775: 6C65.1 6K36.3
N18730061: 6K39.1 6RK39.1
N18730062: 6K38.1 6RK38.1
N18730068: 6C74.1 6K38.3
N18730087: 6K40.1 6RK40.1
N18730100: 6K41.1 6RK41.1
N18730113: 6K42.1 6RK42.1
N18730125: 6K43.1 6RK43.1
N18730138: 6K45.1 6RK45.1
N18730139: 6K44.1 6RK44.1
N18730149: 6C66.1 6K44.3
N18730167: 6K46.1 6RK46.1
N18730183: 6C67.1 6K47.3
N18730196: 6K48.1 6RK48.1
N18730197: 6K47.1 6RK47.1
N18730207: 6C68.1 6K49.3
N18730220: 6K50.1 6RK50.1
N18730221: 6K49.1 6RK49.1
N18731035: 6K51.4 6R7.2
N18731047: 6K53.4 6R8.2
N18731049: 6K53.1 6RK53.1
N18731071: 6R11.2 6R19.1 6TP_IN+_1.1(TP) 6U1.3(+IN)
N18731083: 6R14.2 6R20.1 6TP_IN+_2.1(TP) 6U2.3(+IN)
N18731093: 6K55.1 6RK59.1
N18731096: 6K55.4 6R19.2
N18731098: 6K56.1 6RK60.1
N18731115: 6K57.3 6R16.1 6TP_IN-_3.1(TP) 6U3.8(IN-)
N18731116: 6K58.4 6R16.2 6TP_IN+_3.1(TP) 6U3.7(IN+)
N18731144: 6K60.4 6R18.2 6TP_IN+_4.1(TP) 6U4.7(IN+)
N18731148: 6K59.3 6R18.1 6TP_IN-_4.1(TP) 6U4.8(IN-)
N18731159: 6K56.4 6K61.4 6R20.2
N18731160: 6K54.1 6RK54.1
N18731164: 6K51.1 6RK51.1
N18731166: 6K52.1 6RK52.1
N18731230: 6K57.1 6RK55.2
N18731231: 6K58.1 6RK56.2
N18731232: 6K59.1 6RK57.2
N18731233: 6K60.1 6RK58.2
N18731236: 6K61.1 6RK61.1
N18732367: 7C48.1 7K2.3
N18732376: 7C49.1 7K3.3
N18732385: 7C50.1 7K5.3
N18732418: 7K7.1 7RK7.1
N18732425: 7C53.1 7K8.3
N18732434: 7C54.1 7K9.3
N18732464: 7C59.1 7K12.3
N18732471: 7K13.3 7R1.1
N18732489: 7K15.6 7TP_ATT_S.1(TP) SITE7.8_S(ATT_S)
N18732507: 7K5.1 7RK5.1
N18732509: 7K6.1 7RK6.1
N18732511: 7K8.1 7RK8.1
N18732512: 7K9.1 7RK9.1
N18732513: 7K10.1 7RK10.1
N18732514: 7K11.1 7RK11.1
N18732517: 7C58.1 7K11.3
N18732520: 7K12.1 7RK12.1
N18732522: 7K13.1 7RK13.1
N18732525: 7K14.1 7RK14.1
N18732527: 7K2.1 7RK2.1
N18732528: 7K3.1 7RK3.1
N18732529: 7K4.1 7RK4.1
N18732549: 7K15.3 7TP_ATT_F.1(TP) SITE7.8_F(ATT_F)
N18732561: 7C60.1 7K16.3
N18732574: 7K17.1 7RK17.1
N18732588: 7K16.1 7RK16.1
N18732592: 7K18.1 7RK18.1

Not connected (* = marked no-connect by the designer): 5U3 6(NC)*; 5U4 6(NC)*; 6K15 7*; 6K23 7*; 6K24 7*; 6U3 6(NC)*; 6U4 6(NC)*; 7K15 7*; SITE5 NGH1* NGH2* NGH3* NGH4* NUT1* NUT2* NUT3* NUT4*; SITE6 NGH1* NGH2* NGH3* NGH4* NUT1* NUT2* NUT3* NUT4*

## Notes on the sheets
sheet 31
- Pull-up Resistor
- Timing Circuits(GX1 ¸ê·½¤À°t»Ý­n¦b®É§Ç¹q¸ô¤W¬Û¾F)
- Differential Circuit
sheet 35
- Pull-up Resistor
- Timing Circuits(GX1 ¸ê·½¤À°t»Ý­n¦b®É§Ç¹q¸ô¤W¬Û¾F)
- Differential Circuit
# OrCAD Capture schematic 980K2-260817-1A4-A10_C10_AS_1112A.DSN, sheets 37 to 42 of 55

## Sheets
37 P0052_S5_DUT: size C
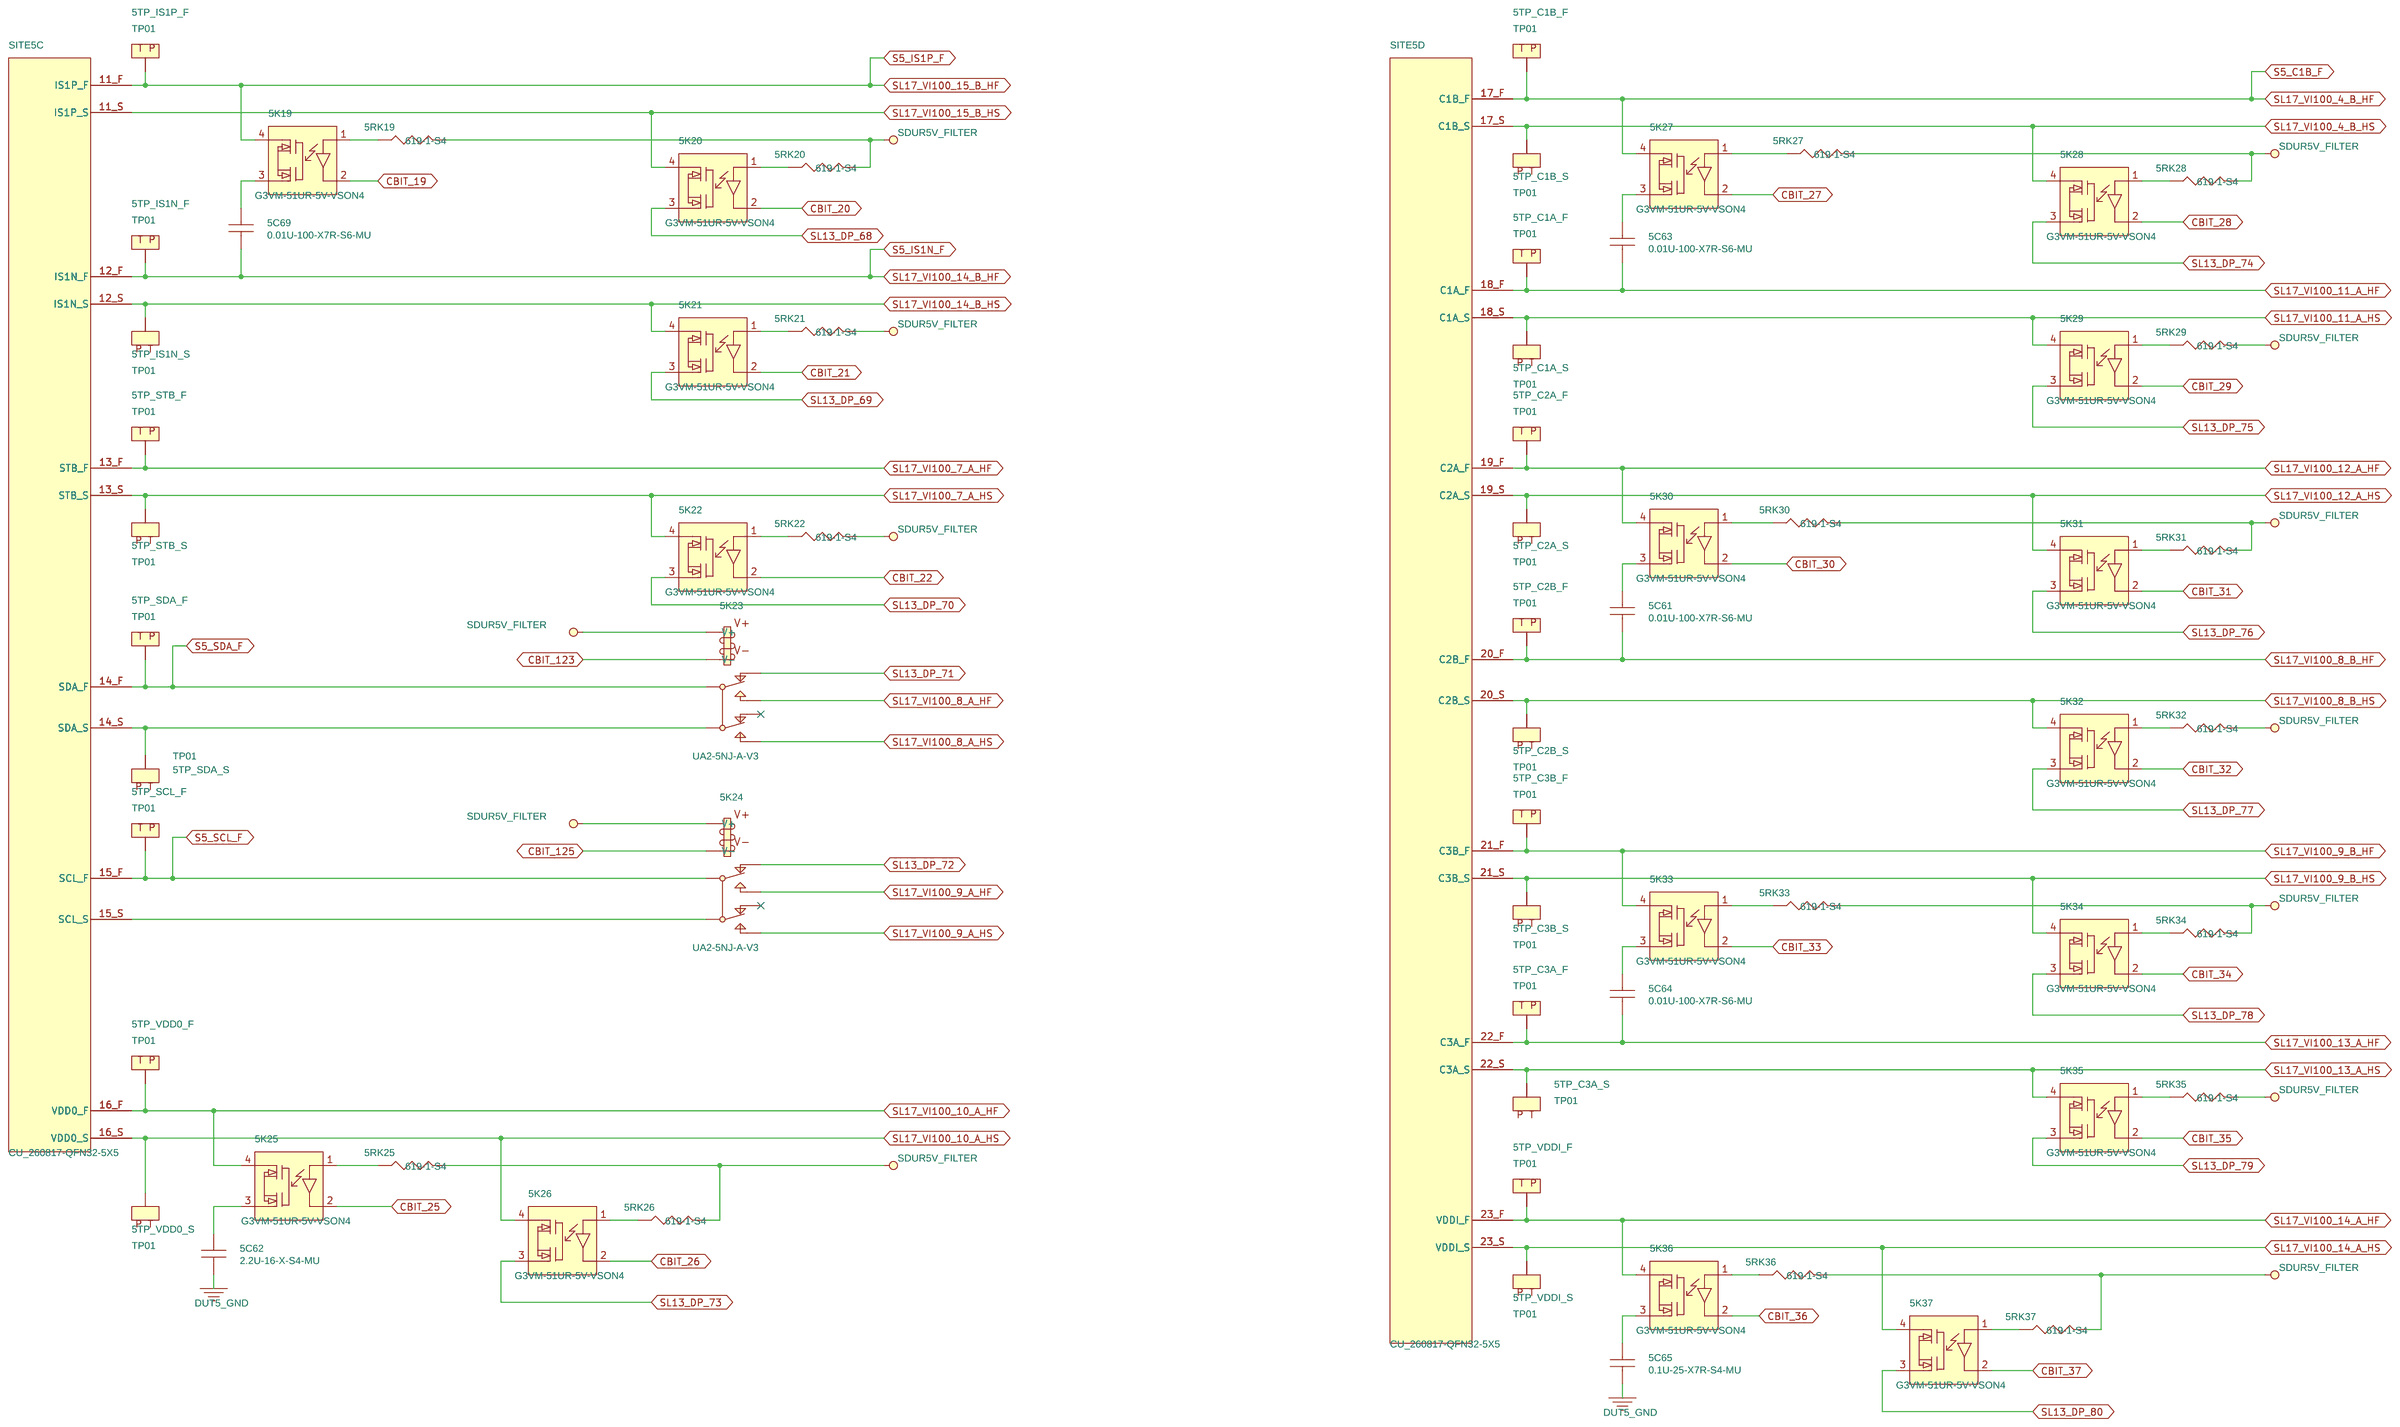
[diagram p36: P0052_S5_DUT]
38 P0051_S5_DUT: size C
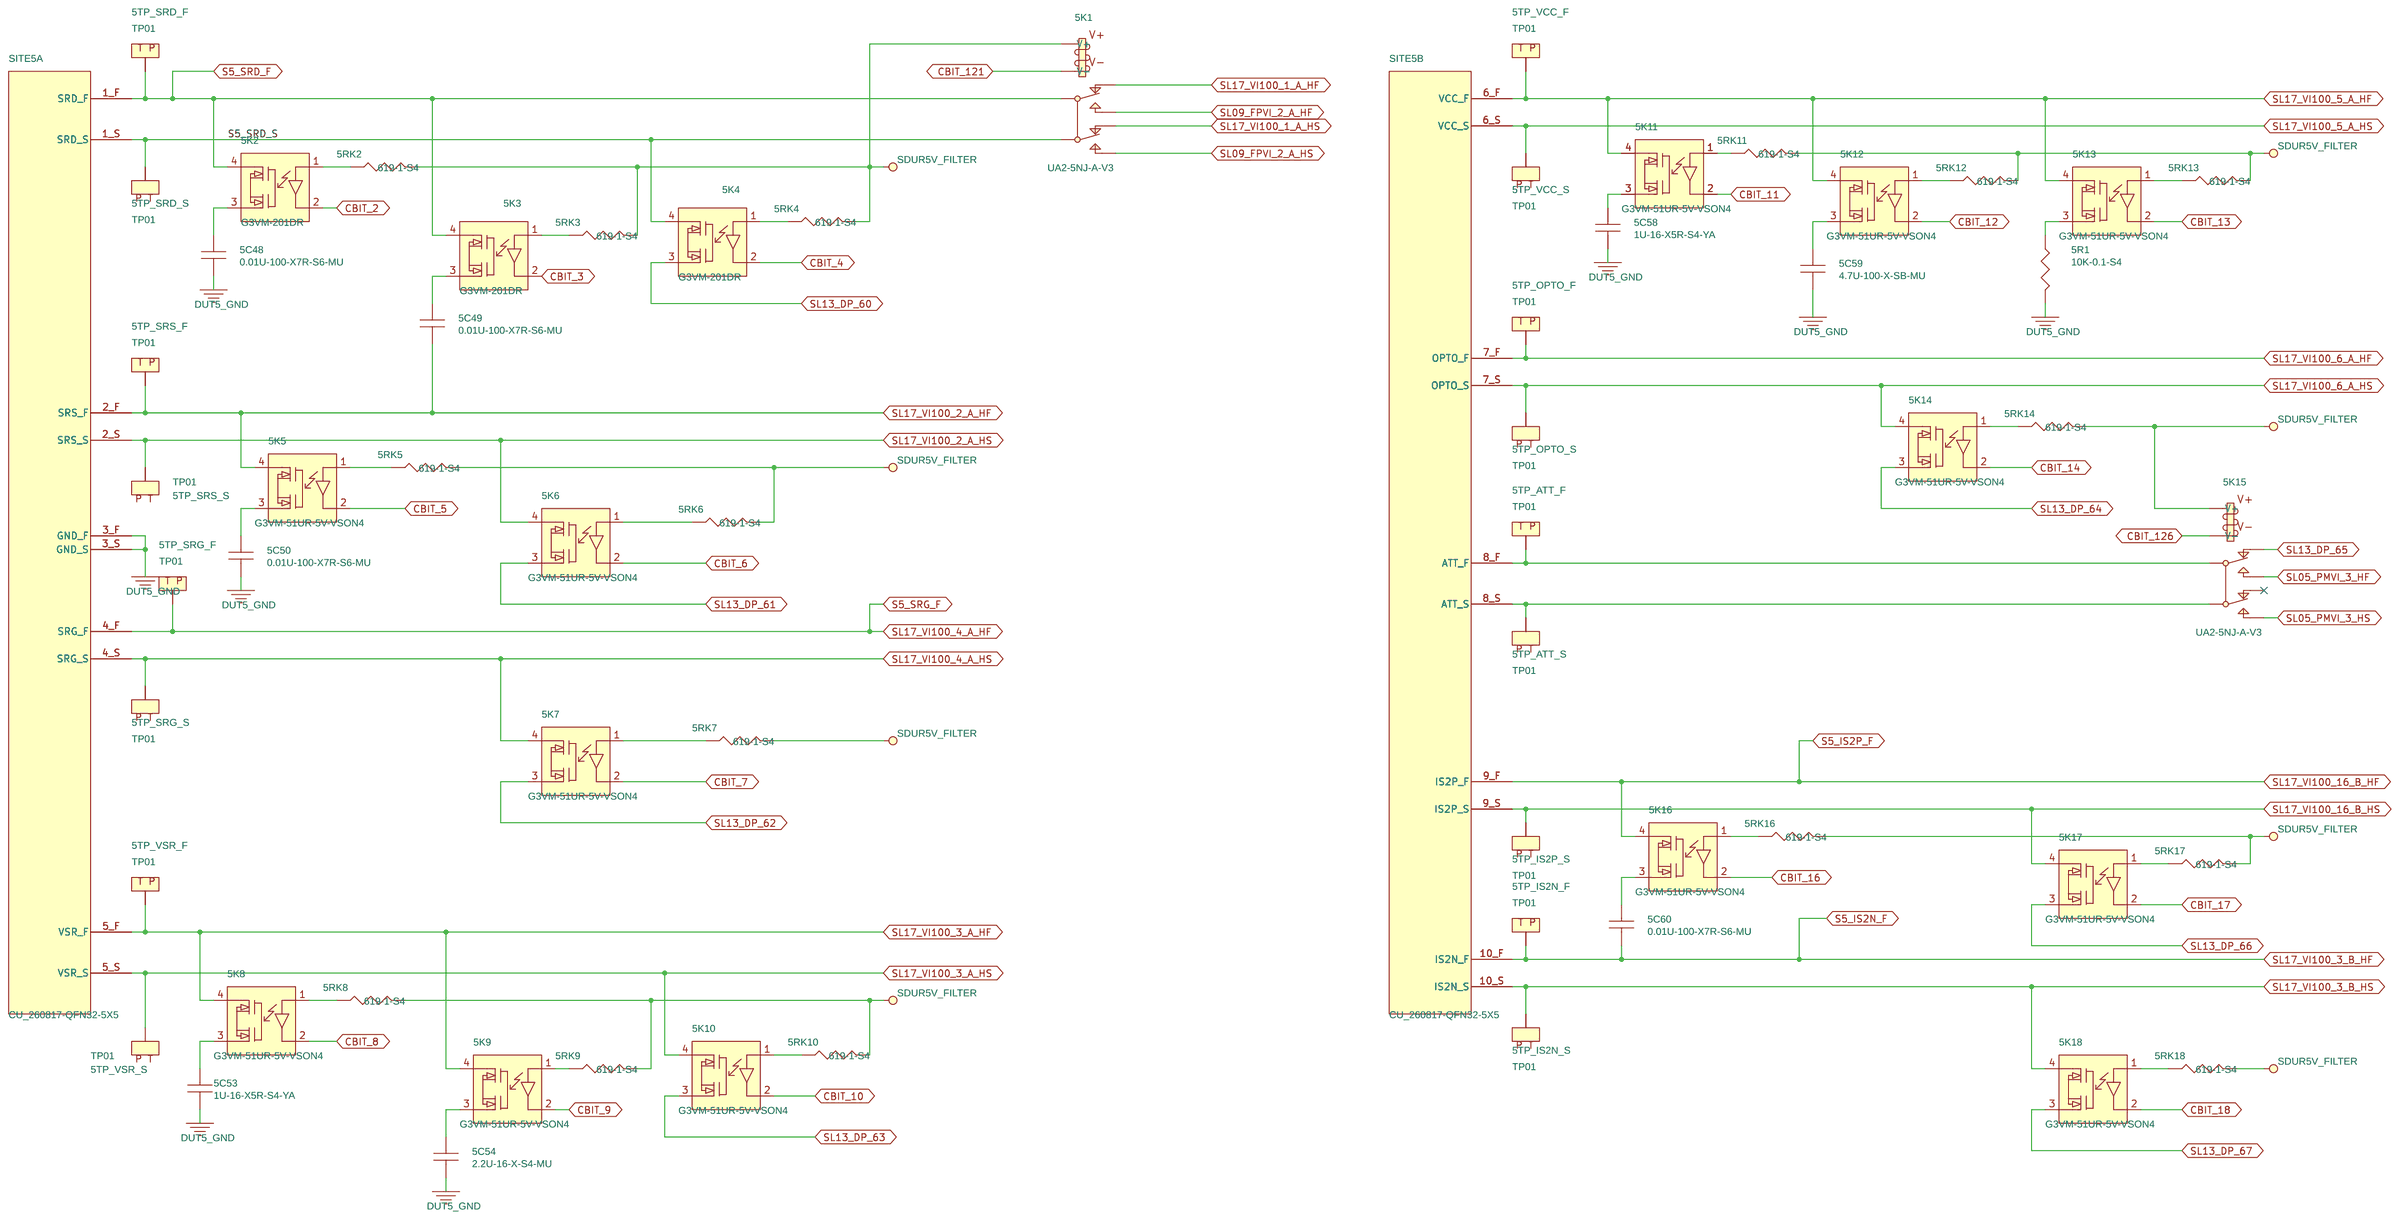
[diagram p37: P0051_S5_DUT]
39 P0044_S4_DUT: size C
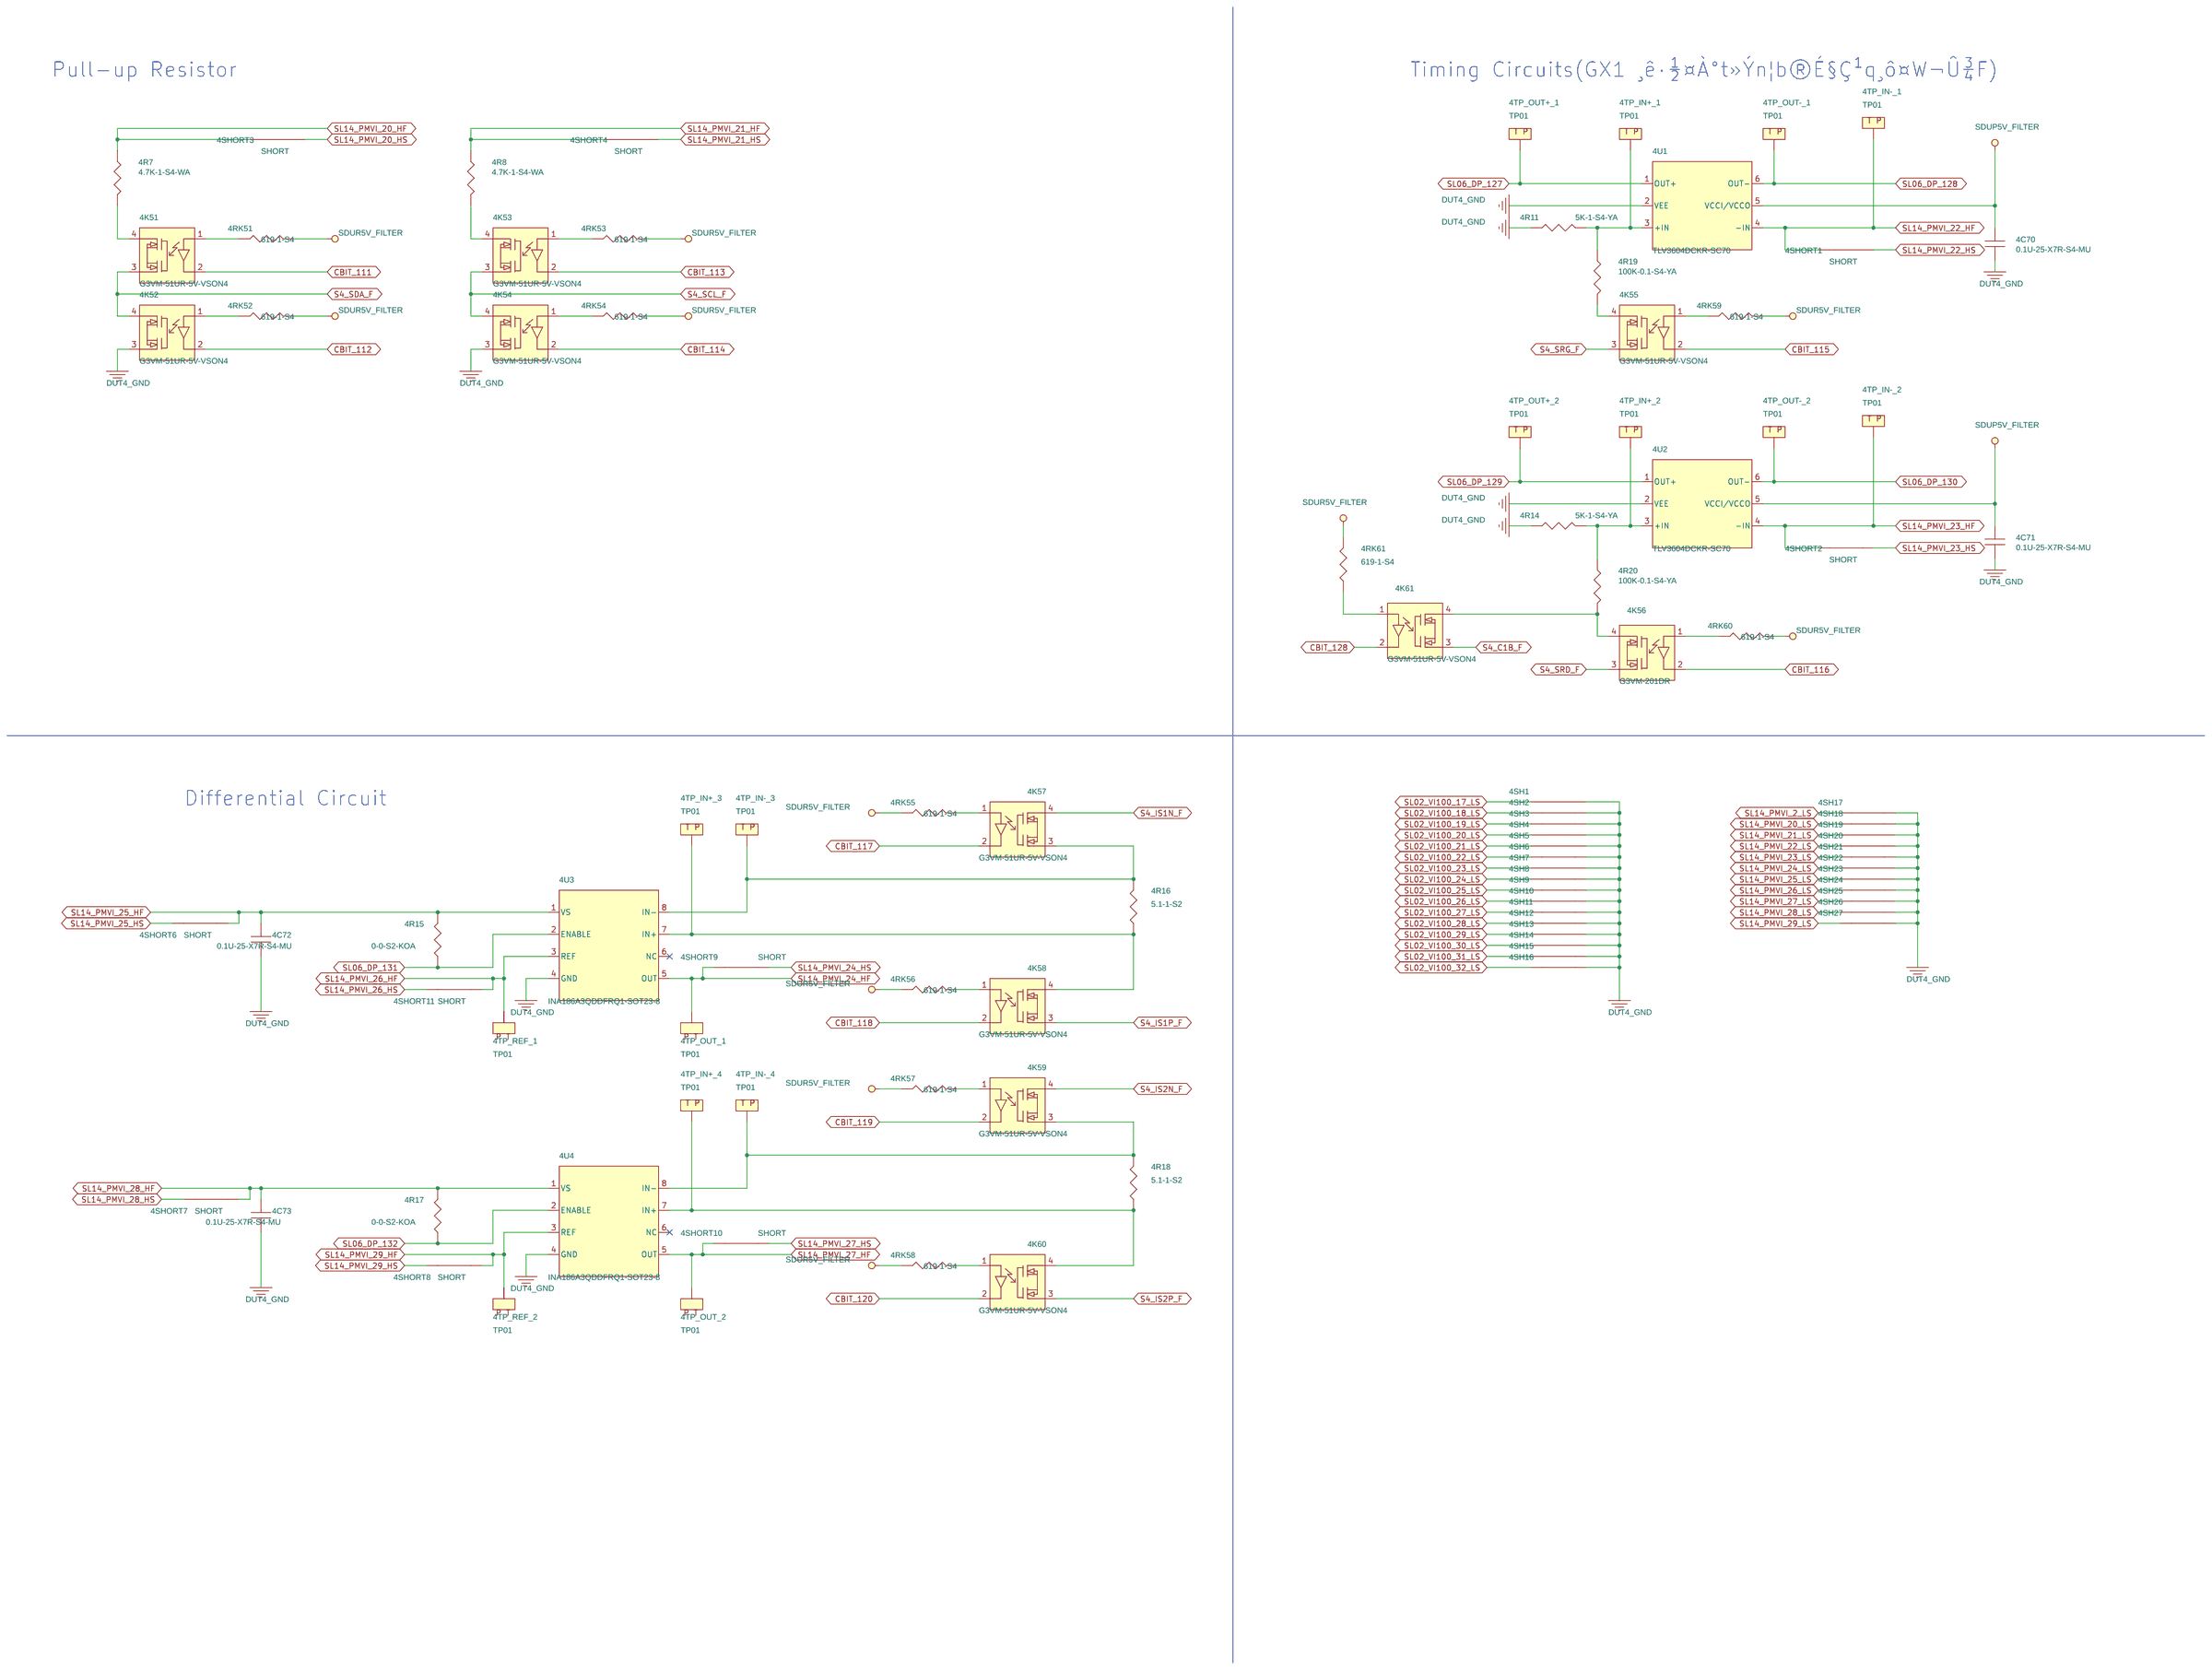
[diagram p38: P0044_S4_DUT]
40 P0043_S4_DUT: size C
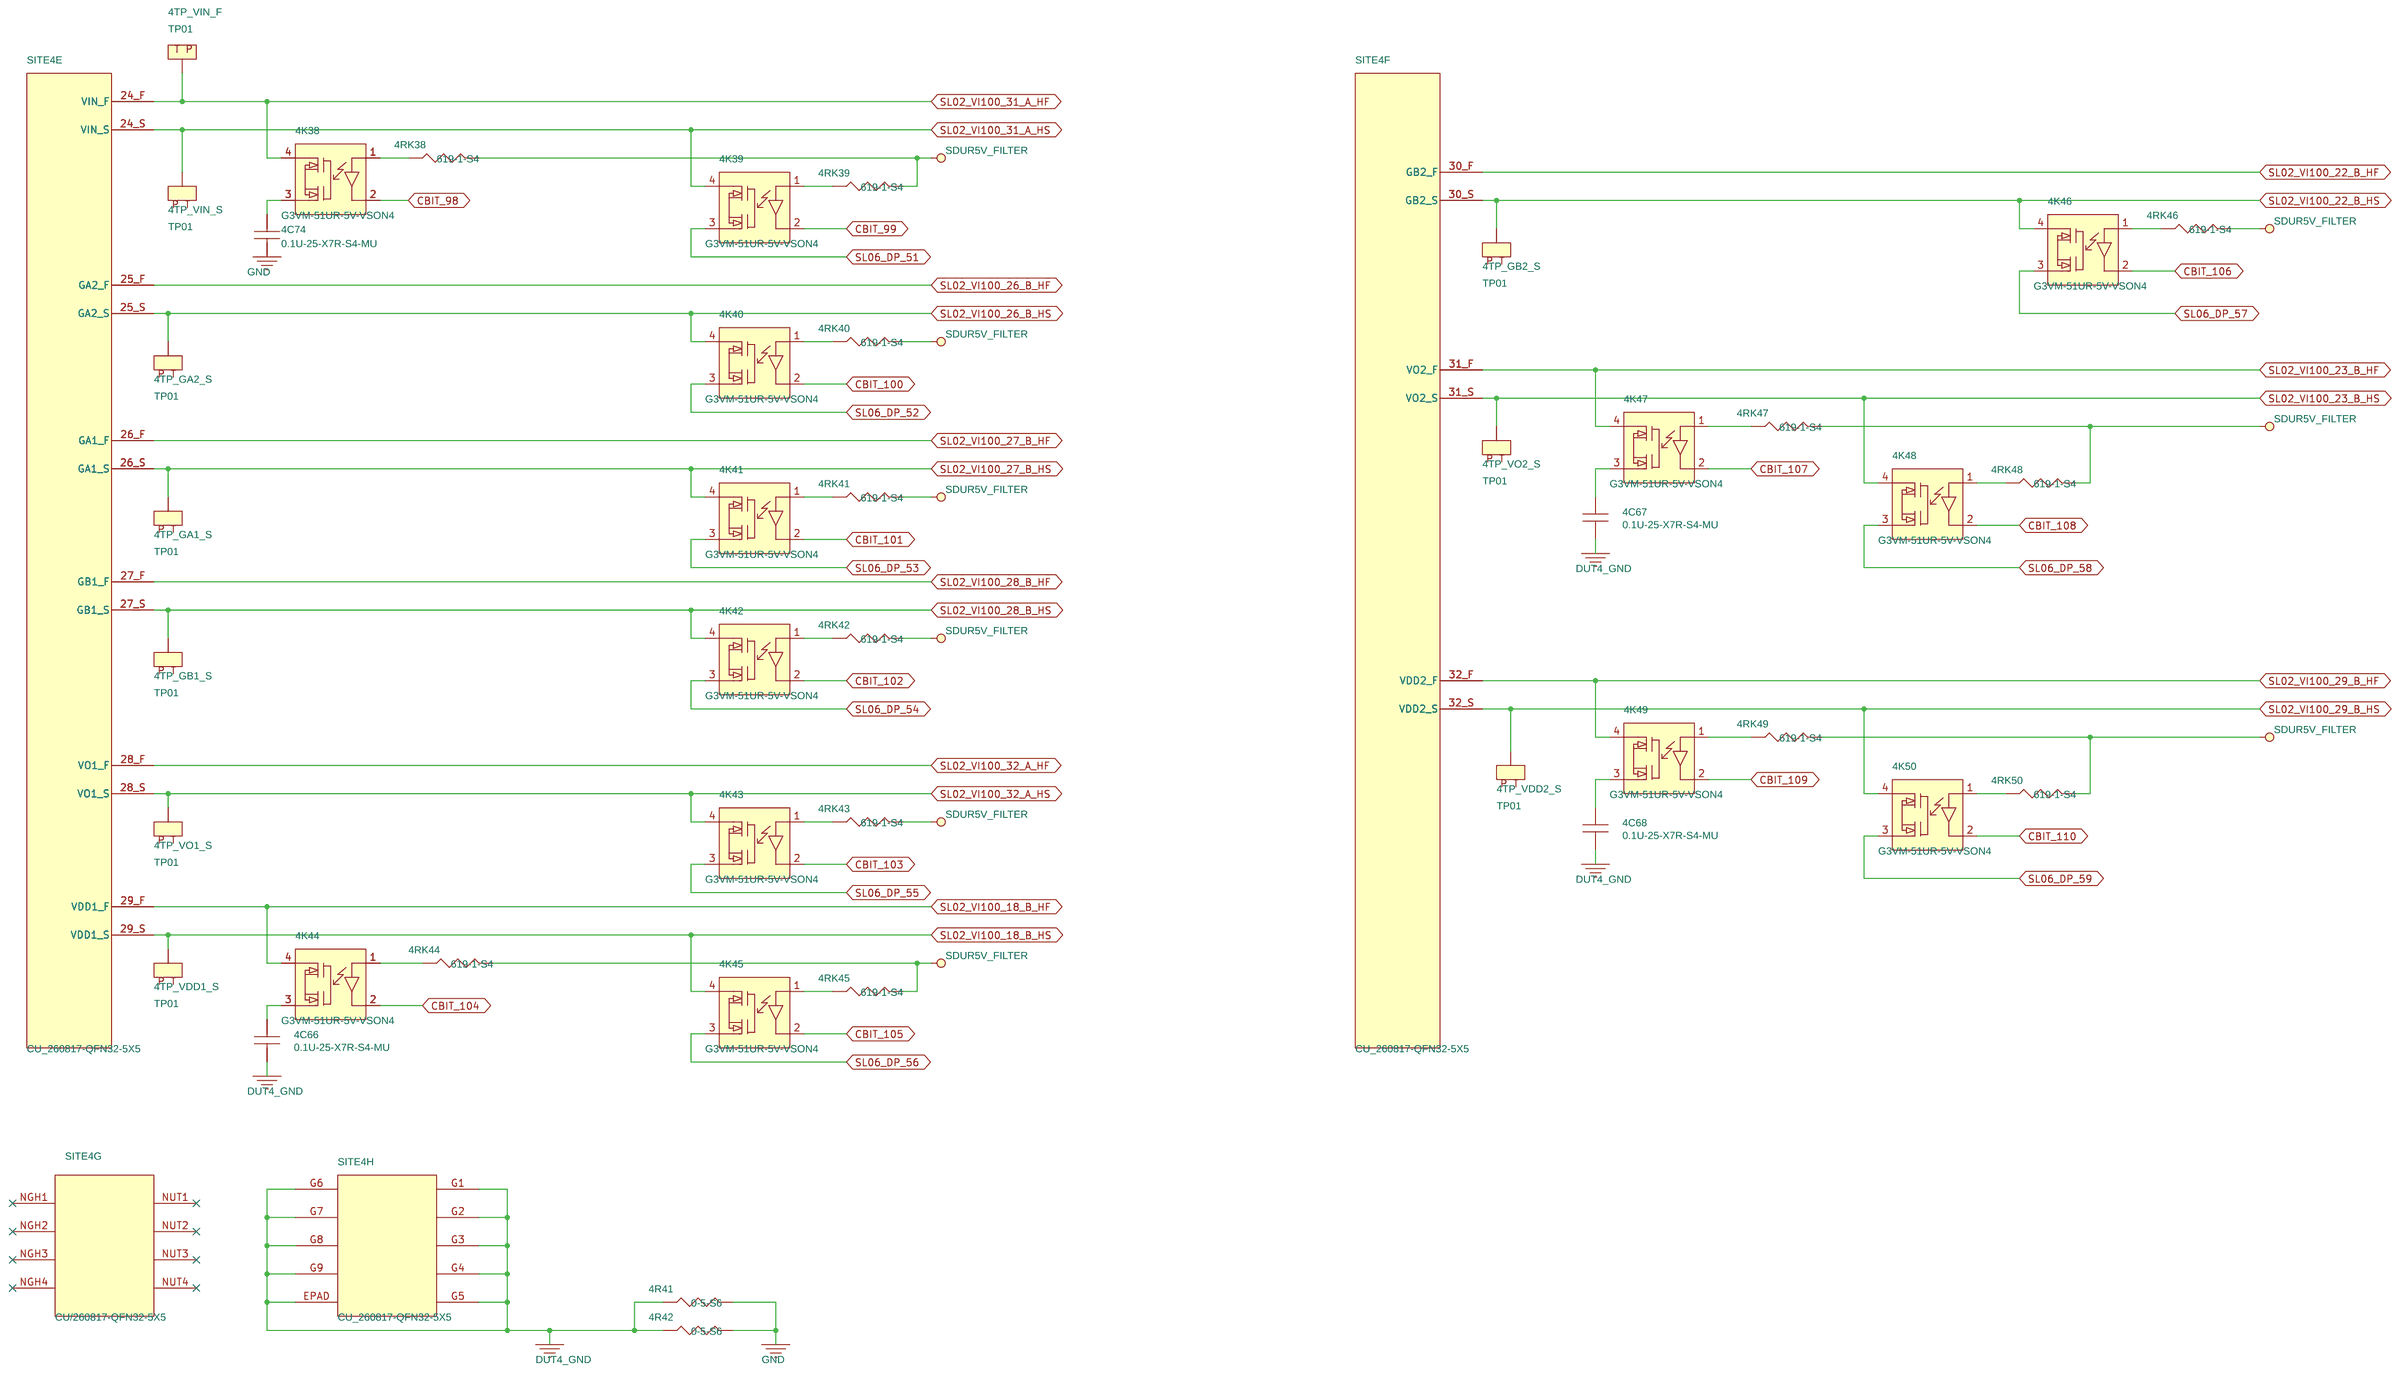
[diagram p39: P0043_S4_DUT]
41 P0042_S4_DUT: size C
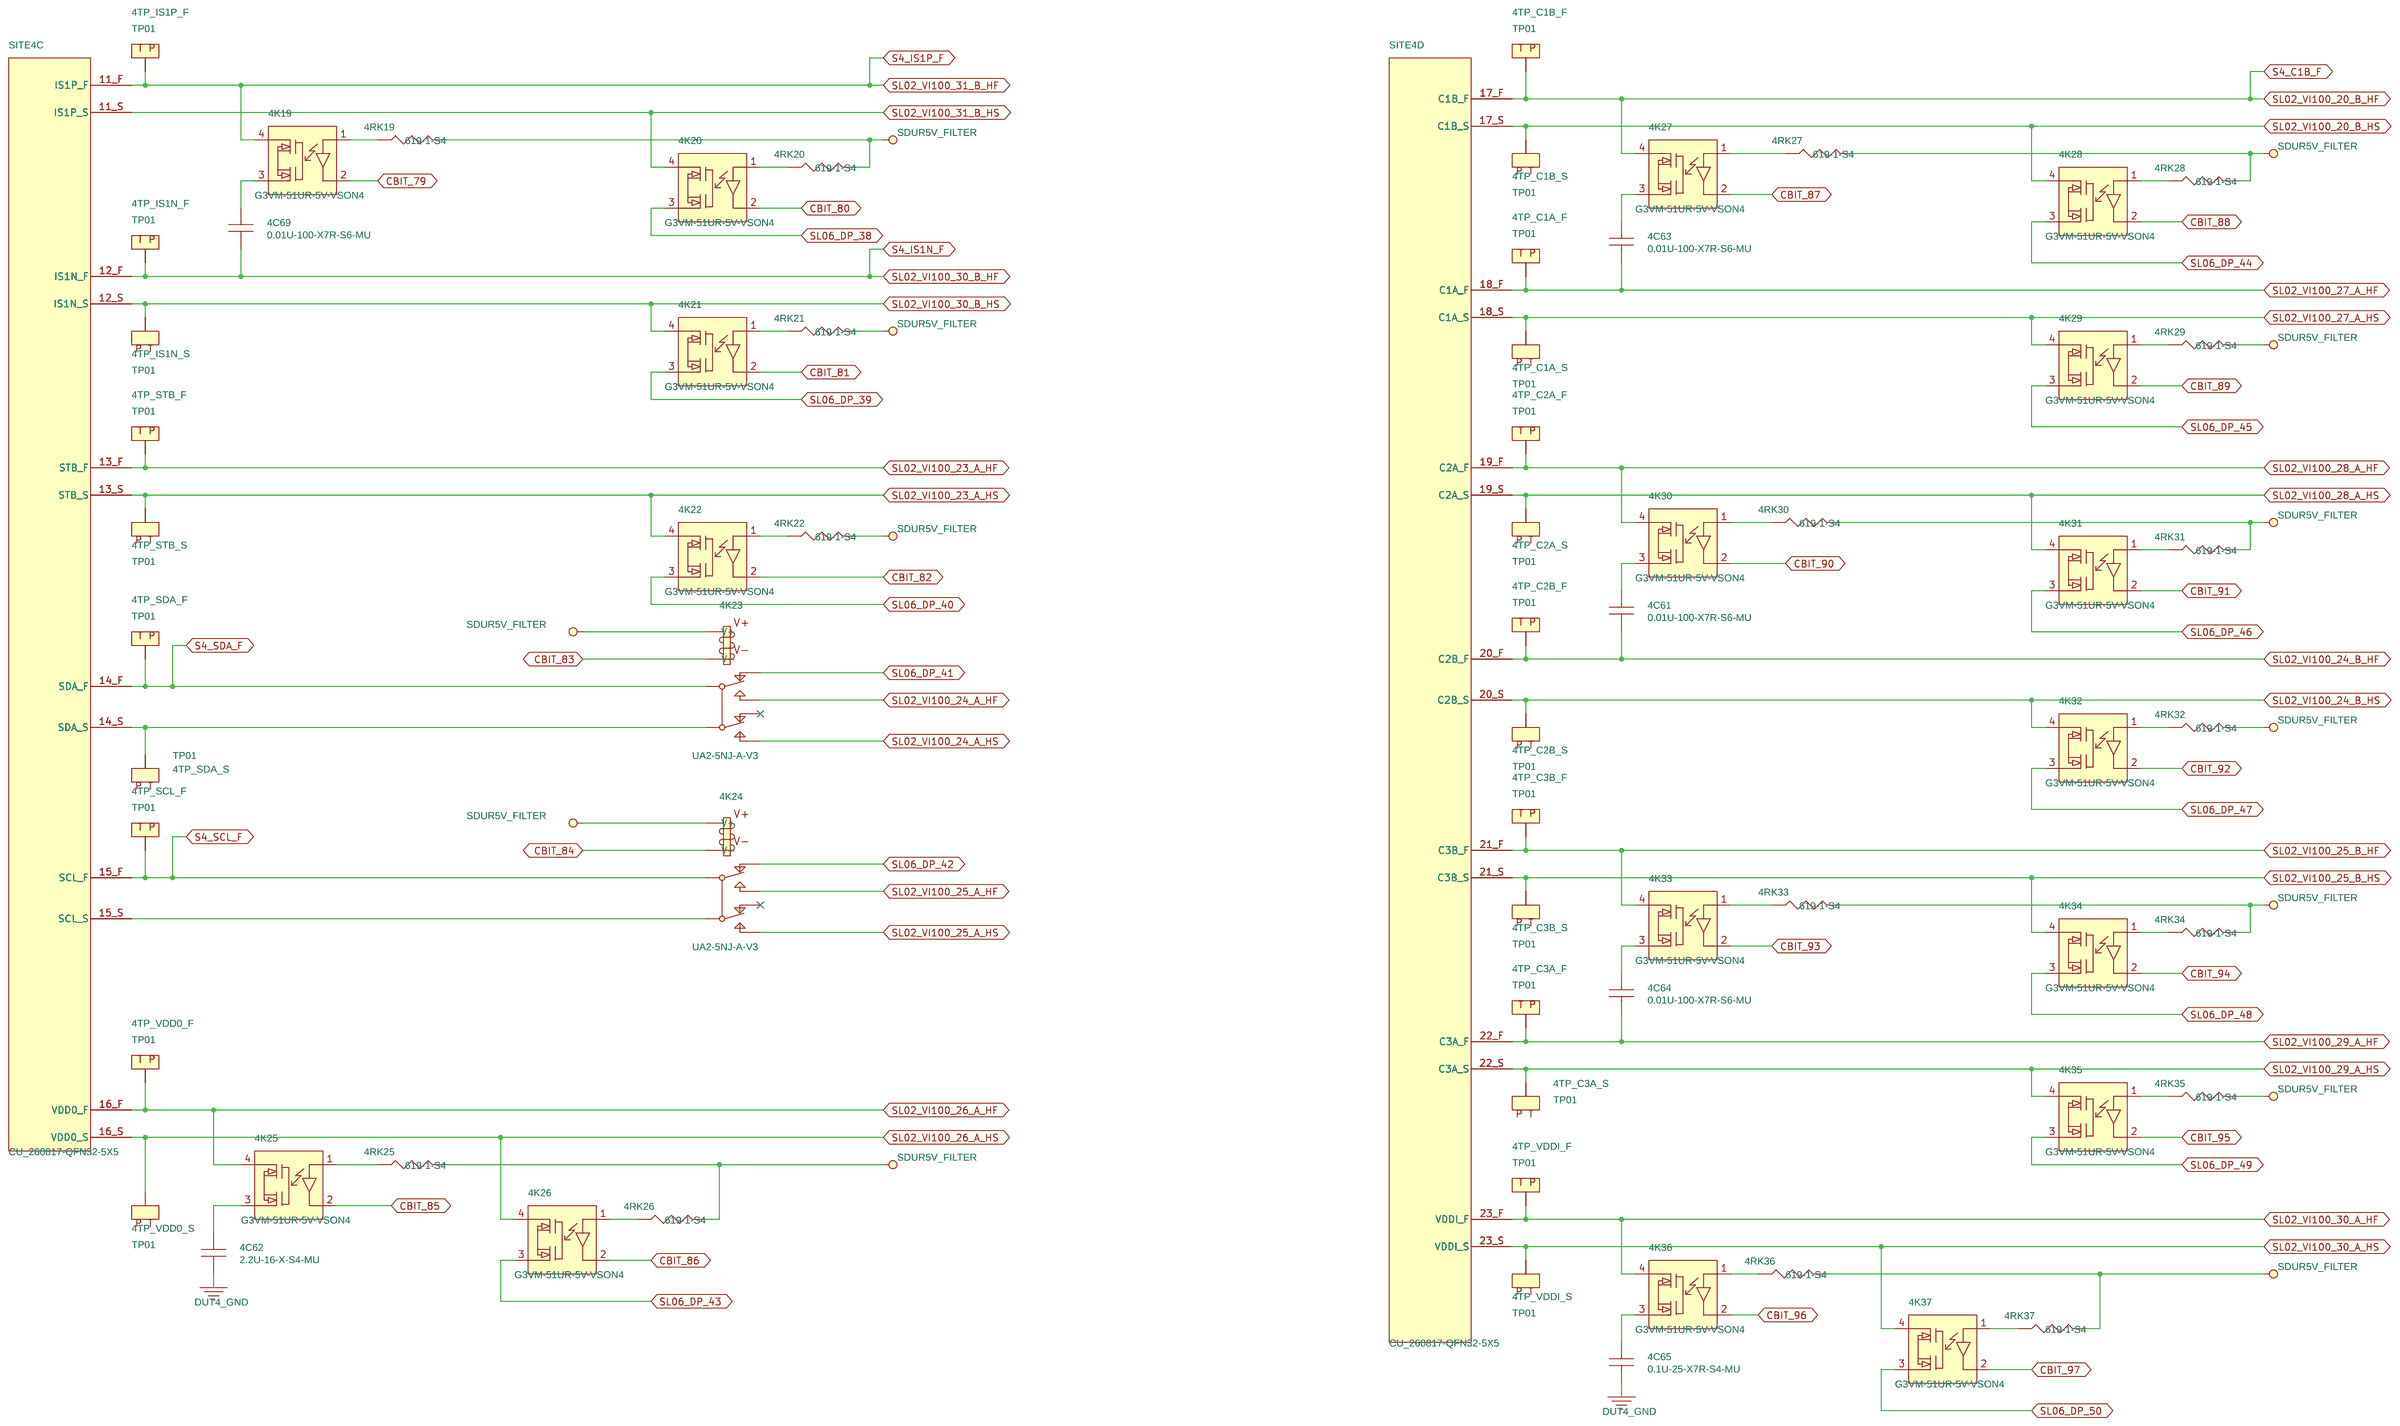
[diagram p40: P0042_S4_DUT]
42 P0041_S4_DUT: size C

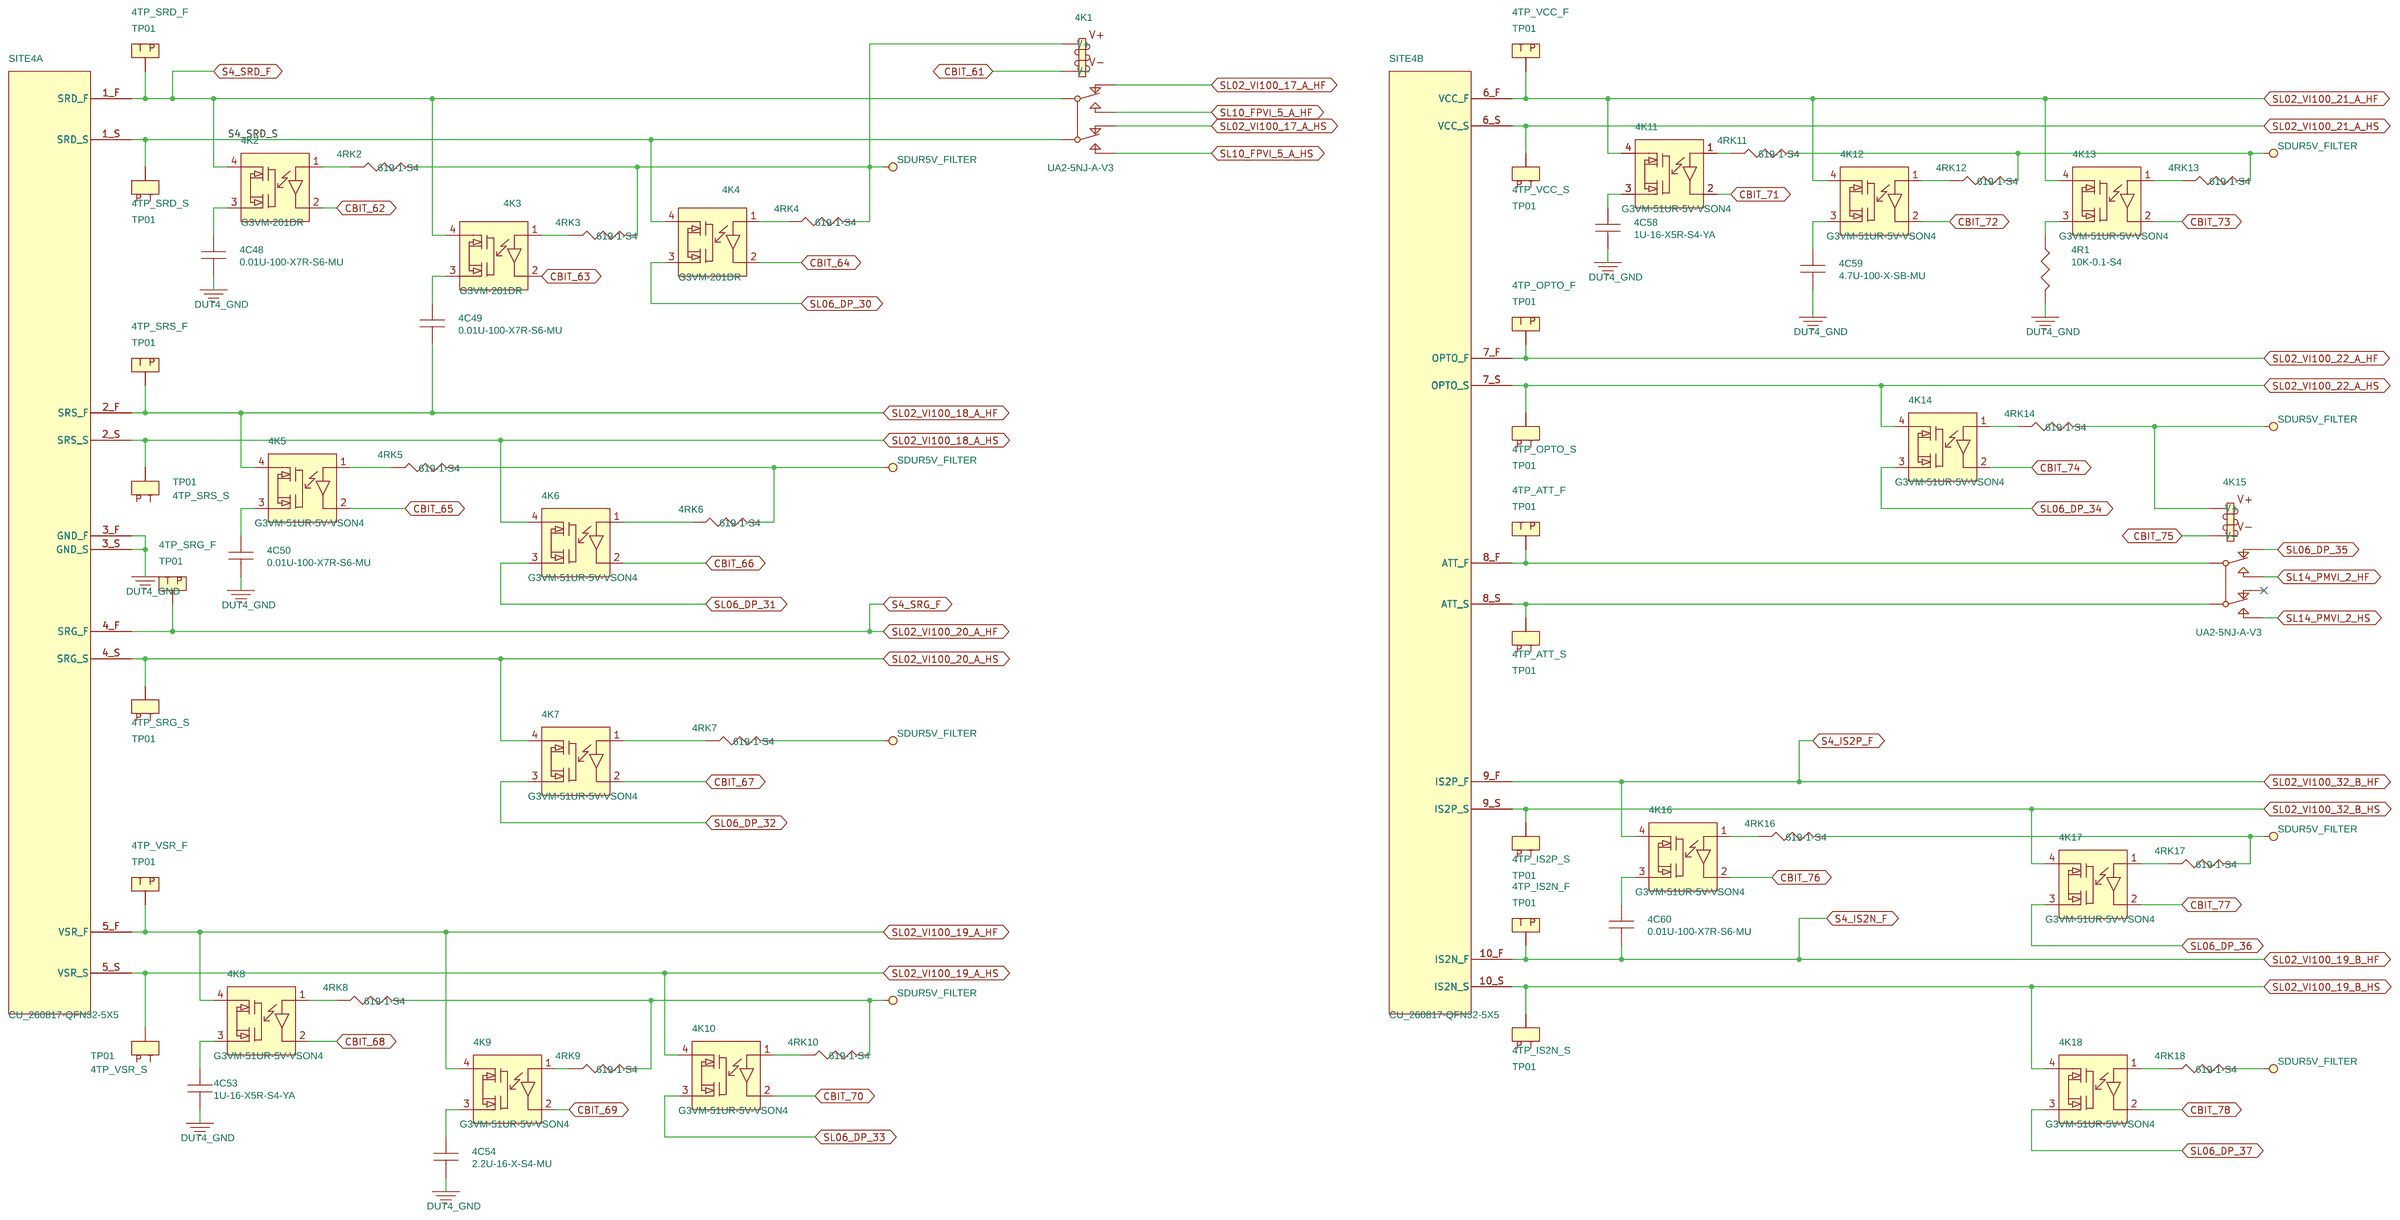
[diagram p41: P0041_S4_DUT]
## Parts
sheet P0041_S4_DUT
4C48  0.01U-100-X7R-S6-MU  [C0603]
4C49  0.01U-100-X7R-S6-MU  [C0603]
4C50  0.01U-100-X7R-S6-MU  [C0603]
4C53  1U-16-X5R-S4-YA  [C0402]
4C54  2.2U-16-X-S4-MU  [C0402]
4C58  1U-16-X5R-S4-YA  [C0402]
4C59  4.7U-100-X-SB-MU  [C1210]
4C60  0.01U-100-X7R-S6-MU  [C0603]
4K1  UA2-5NJ-A-V3  [RL_NECUA2_5V_V3]
4K2  G3VM-201DR  [RL_G3VM201DR_200V]
4K3  G3VM-201DR  [RL_G3VM201DR_200V]
4K4  G3VM-201DR  [RL_G3VM201DR_200V]
4K5  G3VM-51UR-5V-VSON4  [RL_G3VM_4P_VSON4]
4K6  G3VM-51UR-5V-VSON4  [RL_G3VM_4P_VSON4]
4K7  G3VM-51UR-5V-VSON4  [RL_G3VM_4P_VSON4]
4K8  G3VM-51UR-5V-VSON4  [RL_G3VM_4P_VSON4]
4K9  G3VM-51UR-5V-VSON4  [RL_G3VM_4P_VSON4]
4K10  G3VM-51UR-5V-VSON4  [RL_G3VM_4P_VSON4]
4K11  G3VM-51UR-5V-VSON4  [RL_G3VM_4P_VSON4]
4K12  G3VM-51UR-5V-VSON4  [RL_G3VM_4P_VSON4]
4K13  G3VM-51UR-5V-VSON4  [RL_G3VM_4P_VSON4]
4K14  G3VM-51UR-5V-VSON4  [RL_G3VM_4P_VSON4]
4K15  UA2-5NJ-A-V3  [RL_NECUA2_5V_V3]
4K16  G3VM-51UR-5V-VSON4  [RL_G3VM_4P_VSON4]
4K17  G3VM-51UR-5V-VSON4  [RL_G3VM_4P_VSON4]
4K18  G3VM-51UR-5V-VSON4  [RL_G3VM_4P_VSON4]
4R1  10K-0.1-S4  [R0402]
4RK2  619-1-S4  [R0402]
4RK3  619-1-S4  [R0402]
4RK4  619-1-S4  [R0402]
4RK5  619-1-S4  [R0402]
4RK6  619-1-S4  [R0402]
4RK7  619-1-S4  [R0402]
4RK8  619-1-S4  [R0402]
4RK9  619-1-S4  [R0402]
4RK10  619-1-S4  [R0402]
4RK11  619-1-S4  [R0402]
4RK12  619-1-S4  [R0402]
4RK13  619-1-S4  [R0402]
4RK14  619-1-S4  [R0402]
4RK16  619-1-S4  [R0402]
4RK17  619-1-S4  [R0402]
4RK18  619-1-S4  [R0402]
4TP_ATT_F  TP01  [TP_040_T]
4TP_ATT_S  TP01  [TP_040_T]
4TP_IS2N_F  TP01  [TP_040_T]
4TP_IS2N_S  TP01  [TP_040_T]
4TP_IS2P_S  TP01  [TP_040_T]
4TP_OPTO_F  TP01  [TP_040_T]
4TP_OPTO_S  TP01  [TP_040_T]
4TP_SRD_F  TP01  [TP_040_T]
4TP_SRD_S  TP01  [TP_040_T]
4TP_SRG_F  TP01  [TP_040_T]
4TP_SRG_S  TP01  [TP_040_T]
4TP_SRS_F  TP01  [TP_040_T]
4TP_SRS_S  TP01  [TP_040_T]
4TP_VCC_F  TP01  [TP_040_T]
4TP_VCC_S  TP01  [TP_040_T]
4TP_VSR_F  TP01  [TP_040_T]
4TP_VSR_S  TP01  [TP_040_T]
sheet P0042_S4_DUT
4C61  0.01U-100-X7R-S6-MU  [C0603]
4C62  2.2U-16-X-S4-MU  [C0402]
4C63  0.01U-100-X7R-S6-MU  [C0603]
4C64  0.01U-100-X7R-S6-MU  [C0603]
4C65  0.1U-25-X7R-S4-MU  [C0402]
4C69  0.01U-100-X7R-S6-MU  [C0603]
4K19  G3VM-51UR-5V-VSON4  [RL_G3VM_4P_VSON4]
4K20  G3VM-51UR-5V-VSON4  [RL_G3VM_4P_VSON4]
4K21  G3VM-51UR-5V-VSON4  [RL_G3VM_4P_VSON4]
4K22  G3VM-51UR-5V-VSON4  [RL_G3VM_4P_VSON4]
4K23  UA2-5NJ-A-V3  [RL_NECUA2_5V_V3]
4K24  UA2-5NJ-A-V3  [RL_NECUA2_5V_V3]
4K25  G3VM-51UR-5V-VSON4  [RL_G3VM_4P_VSON4]
4K26  G3VM-51UR-5V-VSON4  [RL_G3VM_4P_VSON4]
4K27  G3VM-51UR-5V-VSON4  [RL_G3VM_4P_VSON4]
4K28  G3VM-51UR-5V-VSON4  [RL_G3VM_4P_VSON4]
4K29  G3VM-51UR-5V-VSON4  [RL_G3VM_4P_VSON4]
4K30  G3VM-51UR-5V-VSON4  [RL_G3VM_4P_VSON4]
4K31  G3VM-51UR-5V-VSON4  [RL_G3VM_4P_VSON4]
4K32  G3VM-51UR-5V-VSON4  [RL_G3VM_4P_VSON4]
4K33  G3VM-51UR-5V-VSON4  [RL_G3VM_4P_VSON4]
4K34  G3VM-51UR-5V-VSON4  [RL_G3VM_4P_VSON4]
4K35  G3VM-51UR-5V-VSON4  [RL_G3VM_4P_VSON4]
4K36  G3VM-51UR-5V-VSON4  [RL_G3VM_4P_VSON4]
4K37  G3VM-51UR-5V-VSON4  [RL_G3VM_4P_VSON4]
4RK19  619-1-S4  [R0402]
4RK20  619-1-S4  [R0402]
4RK21  619-1-S4  [R0402]
4RK22  619-1-S4  [R0402]
4RK25  619-1-S4  [R0402]
4RK26  619-1-S4  [R0402]
4RK27  619-1-S4  [R0402]
4RK28  619-1-S4  [R0402]
4RK29  619-1-S4  [R0402]
4RK30  619-1-S4  [R0402]
4RK31  619-1-S4  [R0402]
4RK32  619-1-S4  [R0402]
4RK33  619-1-S4  [R0402]
4RK34  619-1-S4  [R0402]
4RK35  619-1-S4  [R0402]
4RK36  619-1-S4  [R0402]
4RK37  619-1-S4  [R0402]
4TP_C1A_F  TP01  [TP_040_T]
4TP_C1A_S  TP01  [TP_040_T]
4TP_C1B_F  TP01  [TP_040_T]
4TP_C1B_S  TP01  [TP_040_T]
4TP_C2A_F  TP01  [TP_040_T]
4TP_C2A_S  TP01  [TP_040_T]
4TP_C2B_F  TP01  [TP_040_T]
4TP_C2B_S  TP01  [TP_040_T]
4TP_C3A_F  TP01  [TP_040_T]
4TP_C3A_S  TP01  [TP_040_T]
4TP_C3B_F  TP01  [TP_040_T]
4TP_C3B_S  TP01  [TP_040_T]
4TP_IS1N_F  TP01  [TP_040_T]
4TP_IS1N_S  TP01  [TP_040_T]
4TP_IS1P_F  TP01  [TP_040_T]
4TP_SCL_F  TP01  [TP_040_T]
4TP_SDA_F  TP01  [TP_040_T]
4TP_SDA_S  TP01  [TP_040_T]
4TP_STB_F  TP01  [TP_040_T]
4TP_STB_S  TP01  [TP_040_T]
4TP_VDD0_F  TP01  [TP_040_T]
4TP_VDD0_S  TP01  [TP_040_T]
4TP_VDDI_F  TP01  [TP_040_T]
4TP_VDDI_S  TP01  [TP_040_T]
SITE4  CU_260817-QFN32-5X5  [SK_QFN5x5_64P_0P5MM_JG_260817]  (sections A,B,C,D,E,F,G,H)
sheet P0043_S4_DUT
4C66  0.1U-25-X7R-S4-MU  [C0402]
4C67  0.1U-25-X7R-S4-MU  [C0402]
4C68  0.1U-25-X7R-S4-MU  [C0402]
4C74  0.1U-25-X7R-S4-MU  [C0402]
4K38  G3VM-51UR-5V-VSON4  [RL_G3VM_4P_VSON4]
4K39  G3VM-51UR-5V-VSON4  [RL_G3VM_4P_VSON4]
4K40  G3VM-51UR-5V-VSON4  [RL_G3VM_4P_VSON4]
4K41  G3VM-51UR-5V-VSON4  [RL_G3VM_4P_VSON4]
4K42  G3VM-51UR-5V-VSON4  [RL_G3VM_4P_VSON4]
4K43  G3VM-51UR-5V-VSON4  [RL_G3VM_4P_VSON4]
4K44  G3VM-51UR-5V-VSON4  [RL_G3VM_4P_VSON4]
4K45  G3VM-51UR-5V-VSON4  [RL_G3VM_4P_VSON4]
4K46  G3VM-51UR-5V-VSON4  [RL_G3VM_4P_VSON4]
4K47  G3VM-51UR-5V-VSON4  [RL_G3VM_4P_VSON4]
4K48  G3VM-51UR-5V-VSON4  [RL_G3VM_4P_VSON4]
4K49  G3VM-51UR-5V-VSON4  [RL_G3VM_4P_VSON4]
4K50  G3VM-51UR-5V-VSON4  [RL_G3VM_4P_VSON4]
4R41  0-5-S6  [R0603]
4R42  0-5-S6  [R0603]
4RK38  619-1-S4  [R0402]
4RK39  619-1-S4  [R0402]
4RK40  619-1-S4  [R0402]
4RK41  619-1-S4  [R0402]
4RK42  619-1-S4  [R0402]
4RK43  619-1-S4  [R0402]
4RK44  619-1-S4  [R0402]
4RK45  619-1-S4  [R0402]
4RK46  619-1-S4  [R0402]
4RK47  619-1-S4  [R0402]
4RK48  619-1-S4  [R0402]
4RK49  619-1-S4  [R0402]
4RK50  619-1-S4  [R0402]
4TP_GA1_S  TP01  [TP_040_T]
4TP_GA2_S  TP01  [TP_040_T]
4TP_GB1_S  TP01  [TP_040_T]
4TP_GB2_S  TP01  [TP_040_T]
4TP_VDD1_S  TP01  [TP_040_T]
4TP_VDD2_S  TP01  [TP_040_T]
4TP_VIN_F  TP01  [TP_040_T]
4TP_VIN_S  TP01  [TP_040_T]
4TP_VO1_S  TP01  [TP_040_T]
4TP_VO2_S  TP01  [TP_040_T]
sheet P0044_S4_DUT
4C70  0.1U-25-X7R-S4-MU  [C0402]
4C71  0.1U-25-X7R-S4-MU  [C0402]
4C72  0.1U-25-X7R-S4-MU  [C0402]
4C73  0.1U-25-X7R-S4-MU  [C0402]
4K51  G3VM-51UR-5V-VSON4  [RL_G3VM_4P_VSON4]
4K52  G3VM-51UR-5V-VSON4  [RL_G3VM_4P_VSON4]
4K53  G3VM-51UR-5V-VSON4  [RL_G3VM_4P_VSON4]
4K54  G3VM-51UR-5V-VSON4  [RL_G3VM_4P_VSON4]
4K55  G3VM-51UR-5V-VSON4  [RL_G3VM_4P_VSON4]
4K56  G3VM-201DR  [RL_G3VM201DR_200V]
4K57  G3VM-51UR-5V-VSON4  [RL_G3VM_4P_VSON4]
4K58  G3VM-51UR-5V-VSON4  [RL_G3VM_4P_VSON4]
4K59  G3VM-51UR-5V-VSON4  [RL_G3VM_4P_VSON4]
4K60  G3VM-51UR-5V-VSON4  [RL_G3VM_4P_VSON4]
4K61  G3VM-51UR-5V-VSON4  [RL_G3VM_4P_VSON4]
4R7  4.7K-1-S4-WA  [R0402]
4R8  4.7K-1-S4-WA  [R0402]
4R11  5K-1-S4-YA  [R0402]
4R14  5K-1-S4-YA  [R0402]
4R15  0-0-S2-KOA  [R0201]
4R16  5.1-1-S2  [R0201]
4R17  0-0-S2-KOA  [R0201]
4R18  5.1-1-S2  [R0201]
4R19  100K-0.1-S4-YA  [R0402]
4R20  100K-0.1-S4-YA  [R0402]
4RK51  619-1-S4  [R0402]
4RK52  619-1-S4  [R0402]
4RK53  619-1-S4  [R0402]
4RK54  619-1-S4  [R0402]
4RK55  619-1-S4  [R0402]
4RK56  619-1-S4  [R0402]
4RK57  619-1-S4  [R0402]
4RK58  619-1-S4  [R0402]
4RK59  619-1-S4  [R0402]
4RK60  619-1-S4  [R0402]
4RK61  619-1-S4  [R0402]
4SH1  SHORT  [DEFAULT_SHORT_SMALL]
4SH2  SHORT  [DEFAULT_SHORT_SMALL]
4SH3  SHORT  [DEFAULT_SHORT_SMALL]
4SH4  SHORT  [DEFAULT_SHORT_SMALL]
4SH5  SHORT  [DEFAULT_SHORT_SMALL]
4SH6  SHORT  [DEFAULT_SHORT_SMALL]
4SH7  SHORT  [DEFAULT_SHORT_SMALL]
4SH8  SHORT  [DEFAULT_SHORT_SMALL]
4SH9  SHORT  [DEFAULT_SHORT_SMALL]
4SH10  SHORT  [DEFAULT_SHORT_SMALL]
4SH11  SHORT  [DEFAULT_SHORT_SMALL]
4SH12  SHORT  [DEFAULT_SHORT_SMALL]
4SH13  SHORT  [DEFAULT_SHORT_SMALL]
4SH14  SHORT  [DEFAULT_SHORT_SMALL]
4SH15  SHORT  [DEFAULT_SHORT_SMALL]
4SH16  SHORT  [DEFAULT_SHORT_SMALL]
4SH17  SHORT  [DEFAULT_SHORT_SMALL]
4SH18  SHORT  [DEFAULT_SHORT_SMALL]
4SH19  SHORT  [DEFAULT_SHORT_SMALL]
4SH20  SHORT  [DEFAULT_SHORT_SMALL]
4SH21  SHORT  [DEFAULT_SHORT_SMALL]
4SH22  SHORT  [DEFAULT_SHORT_SMALL]
4SH23  SHORT  [DEFAULT_SHORT_SMALL]
4SH24  SHORT  [DEFAULT_SHORT_SMALL]
4SH25  SHORT  [DEFAULT_SHORT_SMALL]
4SH26  SHORT  [DEFAULT_SHORT_SMALL]
4SH27  SHORT  [DEFAULT_SHORT_SMALL]
4SHORT1  SHORT  [DEFAULT_SHORT_SMALL]
4SHORT2  SHORT  [DEFAULT_SHORT_SMALL]
4SHORT3  SHORT  [DEFAULT_SHORT_SMALL]
4SHORT4  SHORT  [DEFAULT_SHORT_SMALL]
4SHORT6  SHORT  [DEFAULT_SHORT_SMALL]
4SHORT7  SHORT  [DEFAULT_SHORT_SMALL]
4SHORT8  SHORT  [DEFAULT_SHORT_SMALL]
4SHORT9  SHORT  [DEFAULT_SHORT_SMALL]
4SHORT10  SHORT  [DEFAULT_SHORT_SMALL]
4SHORT11  SHORT  [DEFAULT_SHORT_SMALL]
4TP_IN+_1  TP01  [TP_040_T]
4TP_IN+_2  TP01  [TP_040_T]
4TP_IN+_3  TP01  [TP_040_T]
4TP_IN+_4  TP01  [TP_040_T]
4TP_IN-_1  TP01  [TP_040_T]
4TP_IN-_2  TP01  [TP_040_T]
4TP_IN-_3  TP01  [TP_040_T]
4TP_IN-_4  TP01  [TP_040_T]
4TP_OUT+_1  TP01  [TP_040_T]
4TP_OUT+_2  TP01  [TP_040_T]
4TP_OUT-_1  TP01  [TP_040_T]
4TP_OUT-_2  TP01  [TP_040_T]
4TP_OUT_1  TP01  [TP_040_T]
4TP_OUT_2  TP01  [TP_040_T]
4TP_REF_1  TP01  [TP_040_T]
4TP_REF_2  TP01  [TP_040_T]
4U1  TLV3604DCKR-SC70  [SC70]
4U2  TLV3604DCKR-SC70  [SC70]
4U3  INA186A3QDDFRQ1-SOT23-8  [SOT23_8P_0P65MM_H1P3MM]
4U4  INA186A3QDDFRQ1-SOT23-8  [SOT23_8P_0P65MM_H1P3MM]
sheet P0051_S5_DUT
5C48  0.01U-100-X7R-S6-MU  [C0603]
5C49  0.01U-100-X7R-S6-MU  [C0603]
5C50  0.01U-100-X7R-S6-MU  [C0603]
5C53  1U-16-X5R-S4-YA  [C0402]
5C54  2.2U-16-X-S4-MU  [C0402]
5C58  1U-16-X5R-S4-YA  [C0402]
5C59  4.7U-100-X-SB-MU  [C1210]
5C60  0.01U-100-X7R-S6-MU  [C0603]
5K1  UA2-5NJ-A-V3  [RL_NECUA2_5V_V3]
5K2  G3VM-201DR  [RL_G3VM201DR_200V]
5K3  G3VM-201DR  [RL_G3VM201DR_200V]
5K4  G3VM-201DR  [RL_G3VM201DR_200V]
5K5  G3VM-51UR-5V-VSON4  [RL_G3VM_4P_VSON4]
5K6  G3VM-51UR-5V-VSON4  [RL_G3VM_4P_VSON4]
5K7  G3VM-51UR-5V-VSON4  [RL_G3VM_4P_VSON4]
5K8  G3VM-51UR-5V-VSON4  [RL_G3VM_4P_VSON4]
5K9  G3VM-51UR-5V-VSON4  [RL_G3VM_4P_VSON4]
5K10  G3VM-51UR-5V-VSON4  [RL_G3VM_4P_VSON4]
5K11  G3VM-51UR-5V-VSON4  [RL_G3VM_4P_VSON4]
5K12  G3VM-51UR-5V-VSON4  [RL_G3VM_4P_VSON4]
5K13  G3VM-51UR-5V-VSON4  [RL_G3VM_4P_VSON4]
5K14  G3VM-51UR-5V-VSON4  [RL_G3VM_4P_VSON4]
5K15  UA2-5NJ-A-V3  [RL_NECUA2_5V_V3]
5K16  G3VM-51UR-5V-VSON4  [RL_G3VM_4P_VSON4]
5K17  G3VM-51UR-5V-VSON4  [RL_G3VM_4P_VSON4]
5K18  G3VM-51UR-5V-VSON4  [RL_G3VM_4P_VSON4]
5R1  10K-0.1-S4  [R0402]
5RK2  619-1-S4  [R0402]
5RK3  619-1-S4  [R0402]
5RK4  619-1-S4  [R0402]
5RK5  619-1-S4  [R0402]
5RK6  619-1-S4  [R0402]
5RK7  619-1-S4  [R0402]
5RK8  619-1-S4  [R0402]
5RK9  619-1-S4  [R0402]
5RK10  619-1-S4  [R0402]
5RK11  619-1-S4  [R0402]
5RK12  619-1-S4  [R0402]
5RK13  619-1-S4  [R0402]
5RK14  619-1-S4  [R0402]
5RK16  619-1-S4  [R0402]
5RK17  619-1-S4  [R0402]
5RK18  619-1-S4  [R0402]
5TP_ATT_F  TP01  [TP_040_T]
5TP_ATT_S  TP01  [TP_040_T]
5TP_IS2N_F  TP01  [TP_040_T]
5TP_IS2N_S  TP01  [TP_040_T]
5TP_IS2P_S  TP01  [TP_040_T]
5TP_OPTO_F  TP01  [TP_040_T]
5TP_OPTO_S  TP01  [TP_040_T]
5TP_SRD_F  TP01  [TP_040_T]
5TP_SRD_S  TP01  [TP_040_T]
5TP_SRG_F  TP01  [TP_040_T]
5TP_SRG_S  TP01  [TP_040_T]
5TP_SRS_F  TP01  [TP_040_T]
5TP_SRS_S  TP01  [TP_040_T]
5TP_VCC_F  TP01  [TP_040_T]
5TP_VCC_S  TP01  [TP_040_T]
5TP_VSR_F  TP01  [TP_040_T]
5TP_VSR_S  TP01  [TP_040_T]
SITE5  CU_260817-QFN32-5X5  [SK_QFN5x5_64P_0P5MM_JG_260817]  (sections A,B,C,D,E,F,G,H)
sheet P0052_S5_DUT
5C61  0.01U-100-X7R-S6-MU  [C0603]
5C62  2.2U-16-X-S4-MU  [C0402]
5C63  0.01U-100-X7R-S6-MU  [C0603]
5C64  0.01U-100-X7R-S6-MU  [C0603]
5C65  0.1U-25-X7R-S4-MU  [C0402]
5C69  0.01U-100-X7R-S6-MU  [C0603]
5K19  G3VM-51UR-5V-VSON4  [RL_G3VM_4P_VSON4]
5K20  G3VM-51UR-5V-VSON4  [RL_G3VM_4P_VSON4]
5K21  G3VM-51UR-5V-VSON4  [RL_G3VM_4P_VSON4]
5K22  G3VM-51UR-5V-VSON4  [RL_G3VM_4P_VSON4]
5K23  UA2-5NJ-A-V3  [RL_NECUA2_5V_V3]
5K24  UA2-5NJ-A-V3  [RL_NECUA2_5V_V3]
5K25  G3VM-51UR-5V-VSON4  [RL_G3VM_4P_VSON4]
5K26  G3VM-51UR-5V-VSON4  [RL_G3VM_4P_VSON4]
5K27  G3VM-51UR-5V-VSON4  [RL_G3VM_4P_VSON4]
5K28  G3VM-51UR-5V-VSON4  [RL_G3VM_4P_VSON4]
5K29  G3VM-51UR-5V-VSON4  [RL_G3VM_4P_VSON4]
5K30  G3VM-51UR-5V-VSON4  [RL_G3VM_4P_VSON4]
5K31  G3VM-51UR-5V-VSON4  [RL_G3VM_4P_VSON4]
5K32  G3VM-51UR-5V-VSON4  [RL_G3VM_4P_VSON4]
5K33  G3VM-51UR-5V-VSON4  [RL_G3VM_4P_VSON4]
5K34  G3VM-51UR-5V-VSON4  [RL_G3VM_4P_VSON4]
5K35  G3VM-51UR-5V-VSON4  [RL_G3VM_4P_VSON4]
5K36  G3VM-51UR-5V-VSON4  [RL_G3VM_4P_VSON4]
5K37  G3VM-51UR-5V-VSON4  [RL_G3VM_4P_VSON4]
5RK19  619-1-S4  [R0402]
5RK20  619-1-S4  [R0402]
5RK21  619-1-S4  [R0402]
5RK22  619-1-S4  [R0402]
5RK25  619-1-S4  [R0402]
5RK26  619-1-S4  [R0402]
5RK27  619-1-S4  [R0402]
5RK28  619-1-S4  [R0402]
5RK29  619-1-S4  [R0402]
5RK30  619-1-S4  [R0402]
5RK31  619-1-S4  [R0402]
5RK32  619-1-S4  [R0402]
5RK33  619-1-S4  [R0402]
5RK34  619-1-S4  [R0402]
5RK35  619-1-S4  [R0402]
5RK36  619-1-S4  [R0402]
5RK37  619-1-S4  [R0402]
5TP_C1A_F  TP01  [TP_040_T]
5TP_C1A_S  TP01  [TP_040_T]
5TP_C1B_F  TP01  [TP_040_T]
5TP_C1B_S  TP01  [TP_040_T]
5TP_C2A_F  TP01  [TP_040_T]
5TP_C2A_S  TP01  [TP_040_T]
5TP_C2B_F  TP01  [TP_040_T]
5TP_C2B_S  TP01  [TP_040_T]
5TP_C3A_F  TP01  [TP_040_T]
5TP_C3A_S  TP01  [TP_040_T]
5TP_C3B_F  TP01  [TP_040_T]
5TP_C3B_S  TP01  [TP_040_T]
5TP_IS1N_F  TP01  [TP_040_T]
5TP_IS1N_S  TP01  [TP_040_T]
5TP_IS1P_F  TP01  [TP_040_T]
5TP_SCL_F  TP01  [TP_040_T]
5TP_SDA_F  TP01  [TP_040_T]
5TP_SDA_S  TP01  [TP_040_T]
5TP_STB_F  TP01  [TP_040_T]
5TP_STB_S  TP01  [TP_040_T]
5TP_VDD0_F  TP01  [TP_040_T]
5TP_VDD0_S  TP01  [TP_040_T]
5TP_VDDI_F  TP01  [TP_040_T]
5TP_VDDI_S  TP01  [TP_040_T]

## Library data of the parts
4C48-4C50 4C60 4C61 4C63 4C64 4C69 5C48-5C50 5C60 5C61 5C63 5C64 5C69 = 0.01U-100-X7R-S6-MU
4C53 4C58 5C53 5C58 = 1U-16-X5R-S4-YA
4C54 4C62 5C54 5C62 = 2.2U-16-X-S4-MU
4C59 5C59 = 4.7U-100-X-SB-MU
4K1 4K15 4K23 4K24 5K1 5K15 5K23 5K24 = UA2-5NJ-A-V3
4K2-4K4 4K56 5K2-5K4 = G3VM-201DR
4K5-4K14 4K16-4K22 4K25-4K55 4K57-4K61 5K5-5K14 5K16-5K22 5K25-5K37 = G3VM-51UR-5V-VSON4
4R1 5R1 = 10K-0.1-S4
4RK2-4RK14 4RK16-4RK22 4RK25-4RK61 5RK2-5RK14 5RK16-5RK22 5RK25-5RK37 = 619-1-S4
4TP_ATT_F 4TP_ATT_S 4TP_C1A_F 4TP_C1A_S 4TP_C1B_F 4TP_C1B_S 4TP_C2A_F 4TP_C2A_S 4TP_C2B_F 4TP_C2B_S 4TP_C3A_F 4TP_C3A_S 4TP_C3B_F 4TP_C3B_S 4TP_GA1_S 4TP_GA2_S 4TP_GB1_S 4TP_GB2_S 4TP_IN+_1-4TP_IN+_4 4TP_IN-_1-4TP_IN-_4 4TP_IS1N_F 4TP_IS1N_S 4TP_IS1P_F 4TP_IS2N_F 4TP_IS2N_S 4TP_IS2P_S 4TP_OPTO_F 4TP_OPTO_S 4TP_OUT+_1 4TP_OUT+_2 4TP_OUT-_1 4TP_OUT-_2 4TP_OUT_1 4TP_OUT_2 4TP_REF_1 4TP_REF_2 4TP_SCL_F 4TP_SDA_F 4TP_SDA_S 4TP_SRD_F 4TP_SRD_S 4TP_SRG_F 4TP_SRG_S 4TP_SRS_F 4TP_SRS_S 4TP_STB_F 4TP_STB_S 4TP_VCC_F 4TP_VCC_S 4TP_VDD0_F 4TP_VDD0_S 4TP_VDD1_S 4TP_VDD2_S 4TP_VDDI_F 4TP_VDDI_S 4TP_VIN_F 4TP_VIN_S 4TP_VO1_S 4TP_VO2_S 4TP_VSR_F 4TP_VSR_S 5TP_ATT_F 5TP_ATT_S 5TP_C1A_F 5TP_C1A_S 5TP_C1B_F 5TP_C1B_S 5TP_C2A_F 5TP_C2A_S 5TP_C2B_F 5TP_C2B_S 5TP_C3A_F 5TP_C3A_S 5TP_C3B_F 5TP_C3B_S 5TP_IS1N_F 5TP_IS1N_S 5TP_IS1P_F 5TP_IS2N_F 5TP_IS2N_S 5TP_IS2P_S 5TP_OPTO_F 5TP_OPTO_S 5TP_SCL_F 5TP_SDA_F 5TP_SDA_S 5TP_SRD_F 5TP_SRD_S 5TP_SRG_F 5TP_SRG_S 5TP_SRS_F 5TP_SRS_S 5TP_STB_F 5TP_STB_S 5TP_VCC_F 5TP_VCC_S 5TP_VDD0_F 5TP_VDD0_S 5TP_VDDI_F 5TP_VDDI_S 5TP_VSR_F 5TP_VSR_S = TP01_v2
4C65-4C68 4C70-4C74 5C65 = 0.1U-25-X7R-S4-MU
SITE4 SITE5 = CU_260817-QFN32-5X5
4R41 4R42 = 0-5-S6
4R7 4R8 = 4.7K-1-S4-WA
4R11 4R14 = 5K-1-S4-YA
4R15 4R17 = 0-0-S2-KOA
4R16 4R18 = 5.1-1-S2
4R19 4R20 = 100K-0.1-S4-YA
4SH1-4SH27 = SHORT: KAIROSNAME: SH1
4SHORT1-4SHORT4 4SHORT6-4SHORT11 = SHORT
4U1 4U2 = TLV3604DCKR-SC70
4U3 4U4 = INA186A3QDDFRQ1-SOT23-8

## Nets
GND: 4R41.2 4R42.2 ; also on sheet 3 4 7 8 11 12 15 16 19 20 21 22 24 28 32 36 44 48 52
CBIT_2: 5K2.2 ; also on sheet 21 30 46 54
CBIT_3: 5K3.2 ; also on sheet 21 30 46 54
CBIT_4: 5K4.2 ; also on sheet 21 30 46 54
CBIT_5: 5K5.2 ; also on sheet 21 30 46 54
CBIT_6: 5K6.2 ; also on sheet 21 30 46 54
CBIT_7: 5K7.2 ; also on sheet 21 30 46 54
CBIT_8: 5K8.2 ; also on sheet 21 30 46 54
CBIT_9: 5K9.2 ; also on sheet 21 30 46 54
CBIT_10: 5K10.2 ; also on sheet 21 30 46 54
CBIT_11: 5K11.2 ; also on sheet 21 30 46 54
CBIT_12: 5K12.2 ; also on sheet 21 30 46 54
CBIT_13: 5K13.2 ; also on sheet 21 30 46 54
CBIT_14: 5K14.2 ; also on sheet 21 30 46 54
CBIT_16: 5K16.2 ; also on sheet 21 30 46 54
CBIT_17: 5K17.2 ; also on sheet 21 30 46 54
CBIT_18: 5K18.2 ; also on sheet 21 30 46 54
CBIT_19: 5K19.2 ; also on sheet 21 29 45 53
CBIT_20: 5K20.2 ; also on sheet 21 29 45 53
CBIT_21: 5K21.2 ; also on sheet 21 29 45 53
CBIT_22: 5K22.2 ; also on sheet 21 29 45 53
CBIT_25: 5K25.2 ; also on sheet 21 29 45 53
CBIT_26: 5K26.2 ; also on sheet 21 29 45 53
CBIT_27: 5K27.2 ; also on sheet 21 29 45 53
CBIT_28: 5K28.2 ; also on sheet 21 29 45 53
CBIT_29: 5K29.2 ; also on sheet 21 29 45 53
CBIT_30: 5K30.2 ; also on sheet 21 29 45 53
CBIT_31: 5K31.2 ; also on sheet 21 29 45 53
CBIT_32: 5K32.2 ; also on sheet 21 29 45 53
CBIT_33: 5K33.2 ; also on sheet 21 29 45 53
CBIT_34: 5K34.2 ; also on sheet 21 29 45 53
CBIT_35: 5K35.2 ; also on sheet 21 29 45 53
CBIT_36: 5K36.2 ; also on sheet 21 29 45 53
CBIT_37: 5K37.2 ; also on sheet 21 29 45 53
CBIT_61: 4K1.8(V-) ; also on sheet 21 50
CBIT_62: 4K2.2 ; also on sheet 21 26 34 50
CBIT_63: 4K3.2 ; also on sheet 21 26 34 50
CBIT_64: 4K4.2 ; also on sheet 21 26 34 50
CBIT_65: 4K5.2 ; also on sheet 21 26 34 50
CBIT_66: 4K6.2 ; also on sheet 21 26 34 50
CBIT_67: 4K7.2 ; also on sheet 21 26 34 50
CBIT_68: 4K8.2 ; also on sheet 21 26 34 50
CBIT_69: 4K9.2 ; also on sheet 21 26 34 50
CBIT_70: 4K10.2 ; also on sheet 21 26 34 50
CBIT_71: 4K11.2 ; also on sheet 21 26 34 50
CBIT_72: 4K12.2 ; also on sheet 21 26 34 50
CBIT_73: 4K13.2 ; also on sheet 21 26 34 50
CBIT_74: 4K14.2 ; also on sheet 21 26 34 50
CBIT_75: 4K15.8(V-) ; also on sheet 21 50
CBIT_76: 4K16.2 ; also on sheet 21 26 34 50
CBIT_77: 4K17.2 ; also on sheet 21 26 34 50
CBIT_78: 4K18.2 ; also on sheet 21 26 34 50
CBIT_79: 4K19.2 ; also on sheet 21 25 33 49
CBIT_80: 4K20.2 ; also on sheet 21 25 33 49
CBIT_81: 4K21.2 ; also on sheet 21 25 33 49
CBIT_82: 4K22.2 ; also on sheet 21 25 33 49
CBIT_83: 4K23.8(V-) ; also on sheet 21 49
CBIT_84: 4K24.8(V-) ; also on sheet 21 49
CBIT_85: 4K25.2 ; also on sheet 21 25 33 49
CBIT_86: 4K26.2 ; also on sheet 21 25 33 49
CBIT_87: 4K27.2 ; also on sheet 21 25 33 49
CBIT_88: 4K28.2 ; also on sheet 21 25 33 49
CBIT_89: 4K29.2 ; also on sheet 21 25 33 49
CBIT_90: 4K30.2 ; also on sheet 21 25 33 49
CBIT_91: 4K31.2 ; also on sheet 21 25 33 49
CBIT_92: 4K32.2 ; also on sheet 21 25 33 49
CBIT_93: 4K33.2 ; also on sheet 21 25 33 49
CBIT_94: 4K34.2 ; also on sheet 21 25 33 49
CBIT_95: 4K35.2 ; also on sheet 21 25 33 49
CBIT_96: 4K36.2 ; also on sheet 21 25 33 49
CBIT_97: 4K37.2 ; also on sheet 21 25 33 49
CBIT_98: 4K38.2 ; also on sheet 21 24 32 48
CBIT_99: 4K39.2 ; also on sheet 21 24 32 48
CBIT_100: 4K40.2 ; also on sheet 21 24 32 48
CBIT_101: 4K41.2 ; also on sheet 21 24 32 48
CBIT_102: 4K42.2 ; also on sheet 21 24 32 48
CBIT_103: 4K43.2 ; also on sheet 21 24 32 48
CBIT_104: 4K44.2 ; also on sheet 21 24 32 48
CBIT_105: 4K45.2 ; also on sheet 21 24 32 48
CBIT_106: 4K46.2 ; also on sheet 21 24 32 48
CBIT_107: 4K47.2 ; also on sheet 21 24 32 48
CBIT_108: 4K48.2 ; also on sheet 21 24 32 48
CBIT_109: 4K49.2 ; also on sheet 21 24 32 48
CBIT_110: 4K50.2 ; also on sheet 21 24 32 48
CBIT_111: 4K51.2 ; also on sheet 21 23 31 47
CBIT_112: 4K52.2 ; also on sheet 21 23 31 47
CBIT_113: 4K53.2 ; also on sheet 21 23 31 47
CBIT_114: 4K54.2 ; also on sheet 21 23 31 47
CBIT_115: 4K55.2 ; also on sheet 21 23 31 47
CBIT_116: 4K56.2 ; also on sheet 21 23 31 47
CBIT_117: 4K57.2 ; also on sheet 21 23 31 47
CBIT_118: 4K58.2 ; also on sheet 21 23 31 47
CBIT_119: 4K59.2 ; also on sheet 21 23 31 47
CBIT_120: 4K60.2 ; also on sheet 21 23 31 47
CBIT_121: 5K1.8(V-) ; also on sheet 21 30
CBIT_123: 5K23.8(V-) ; also on sheet 21 29
CBIT_125: 5K24.8(V-) ; also on sheet 21 25 29 33
CBIT_126: 5K15.8(V-) ; also on sheet 21 26 30 34
CBIT_128: 4K61.2 ; also on sheet 21 23 31 47
DUT4_GND: 4C48.2 4C50.2 4C53.2 4C54.2 4C58.2 4C59.2 4C62.2 4C65.2 4C66.2 4C67.2 4C68.2 4C70.2 4C71.2 4C72.2 4C73.2 4C74.2 4K52.3 4K54.3 4R1.2 4R11.1 4R14.1 4R41.1 4R42.1 4SH1.2 4SH2.2 4SH3.2 4SH4.2 4SH5.2 4SH6.2 4SH7.2 4SH8.2 4SH9.2 4SH10.2 4SH11.2 4SH12.2 4SH13.2 4SH14.2 4SH15.2 4SH16.2 4SH17.2 4SH18.2 4SH19.2 4SH20.2 4SH21.2 4SH22.2 4SH23.2 4SH24.2 4SH25.2 4SH26.2 4SH27.2 4U1.2(VEE) 4U2.2(VEE) 4U3.4(GND) 4U4.4(GND) SITE4.3_F(GND_F) SITE4.3_S(GND_S) SITE4.EPAD SITE4.G1 SITE4.G2 SITE4.G3 SITE4.G4 SITE4.G5 SITE4.G6 SITE4.G7 SITE4.G8 SITE4.G9
DUT5_GND: 5C48.2 5C50.2 5C53.2 5C54.2 5C58.2 5C59.2 5C62.2 5C65.2 5R1.2 SITE5.3_F(GND_F) SITE5.3_S(GND_S) ; also on sheet 35 36
S4_C1B_F: 4K27.4 4K61.3 4TP_C1B_F.1(TP) SITE4.17_F(C1B_F) ; also on sheet 19
S4_IS1N_F: 4C69.2 4K57.4 4TP_IS1N_F.1(TP) SITE4.12_F(IS1N_F) ; also on sheet 19
S4_IS1P_F: 4K19.4 4K58.3 4TP_IS1P_F.1(TP) SITE4.11_F(IS1P_F) ; also on sheet 19
S4_IS2N_F: 4C60.2 4K59.4 4TP_IS2N_F.1(TP) SITE4.10_F(IS2N_F) ; also on sheet 19
S4_IS2P_F: 4K16.4 4K60.3 SITE4.9_F(IS2P_F) ; also on sheet 19
S4_SCL_F: 4K24.3 4K53.3 4K54.4 4TP_SCL_F.1(TP) SITE4.15_F(SCL_F)
S4_SDA_F: 4K23.3 4K51.3 4K52.4 4TP_SDA_F.1(TP) SITE4.14_F(SDA_F)
S4_SRD_F: 4K1.3 4K2.4 4K3.4 4K56.3 4TP_SRD_F.1(TP) SITE4.1_F(SRD_F)
S4_SRD_S: 4K1.6 4K4.4 4TP_SRD_S.1(TP) SITE4.1_S(SRD_S)
S4_SRG_F: 4K55.3 4TP_SRG_F.1(TP) SITE4.4_F(SRG_F) ; also on sheet 19
S5_C1B_F: 5K27.4 5TP_C1B_F.1(TP) SITE5.17_F(C1B_F) ; also on sheet 4 35
S5_IS1N_F: 5C69.2 5TP_IS1N_F.1(TP) SITE5.12_F(IS1N_F) ; also on sheet 4 35
S5_IS1P_F: 5K19.4 5TP_IS1P_F.1(TP) SITE5.11_F(IS1P_F) ; also on sheet 4 35
S5_IS2N_F: 5C60.2 5TP_IS2N_F.1(TP) SITE5.10_F(IS2N_F) ; also on sheet 4 35
S5_IS2P_F: 5K16.4 SITE5.9_F(IS2P_F) ; also on sheet 4 35
S5_SCL_F: 5K24.3 5TP_SCL_F.1(TP) SITE5.15_F(SCL_F) ; also on sheet 35
S5_SDA_F: 5K23.3 5TP_SDA_F.1(TP) SITE5.14_F(SDA_F) ; also on sheet 35
S5_SRD_F: 5K1.3 5K2.4 5K3.4 5TP_SRD_F.1(TP) SITE5.1_F(SRD_F) ; also on sheet 35
S5_SRD_S: 5K1.6 5K4.4 5TP_SRD_S.1(TP) SITE5.1_S(SRD_S)
S5_SRG_F: 5TP_SRG_F.1(TP) SITE5.4_F(SRG_F) ; also on sheet 4 35
SDUP5V_FILTER: 4C70.1 4C71.1 4U1.5(VCCI/VCCO) 4U2.5(VCCI/VCCO) ; also on sheet 22 23 27 31 35 43 47 51
SDUR5V_FILTER: 4K1.1(V+) 4K15.1(V+) 4K23.1(V+) 4K24.1(V+) 4RK2.2 4RK3.2 4RK4.2 4RK5.2 4RK6.2 4RK7.2 4RK8.2 4RK9.2 4RK10.2 4RK11.2 4RK12.2 4RK13.2 4RK14.2 4RK16.2 4RK17.2 4RK18.2 4RK19.2 4RK20.2 4RK21.2 4RK22.2 4RK25.2 4RK26.2 4RK27.2 4RK28.2 4RK29.2 4RK30.2 4RK31.2 4RK32.2 4RK33.2 4RK34.2 4RK35.2 4RK36.2 4RK37.2 4RK38.2 4RK39.2 4RK40.2 4RK41.2 4RK42.2 4RK43.2 4RK44.2 4RK45.2 4RK46.2 4RK47.2 4RK48.2 4RK49.2 4RK50.2 4RK51.2 4RK52.2 4RK53.2 4RK54.2 4RK55.1 4RK56.1 4RK57.1 4RK58.1 4RK59.2 4RK60.2 4RK61.2 5K1.1(V+) 5K15.1(V+) 5K23.1(V+) 5K24.1(V+) 5RK2.2 5RK3.2 5RK4.2 5RK5.2 5RK6.2 5RK7.2 5RK8.2 5RK9.2 5RK10.2 5RK11.2 5RK12.2 5RK13.2 5RK14.2 5RK16.2 5RK17.2 5RK18.2 5RK19.2 5RK20.2 5RK21.2 5RK22.2 5RK25.2 5RK26.2 5RK27.2 5RK28.2 5RK29.2 5RK30.2 5RK31.2 5RK32.2 5RK33.2 5RK34.2 5RK35.2 5RK36.2 5RK37.2 ; also on sheet 22 23 24 25 26 27 28 29 30 31 32 33 34 35 36 43 44 45 46 47 48 49 50 51 52 53 54
SL02_VI100_17_A_HF: 4K1.2 ; also on sheet 19
SL02_VI100_17_A_HS: 4K1.7 ; also on sheet 19
SL02_VI100_17_LS: 4SH1.1 ; also on sheet 19
SL02_VI100_18_A_HF: 4C49.2 4K5.4 4TP_SRS_F.1(TP) SITE4.2_F(SRS_F) ; also on sheet 19
SL02_VI100_18_A_HS: 4K6.4 4TP_SRS_S.1(TP) SITE4.2_S(SRS_S) ; also on sheet 19
SL02_VI100_18_B_HF: 4K44.4 SITE4.29_F(VDD1_F) ; also on sheet 19
SL02_VI100_18_B_HS: 4K45.4 4TP_VDD1_S.1(TP) SITE4.29_S(VDD1_S) ; also on sheet 19
SL02_VI100_18_LS: 4SH2.1 ; also on sheet 19
SL02_VI100_19_A_HF: 4K8.4 4K9.4 4TP_VSR_F.1(TP) SITE4.5_F(VSR_F) ; also on sheet 19
SL02_VI100_19_A_HS: 4K10.4 4TP_VSR_S.1(TP) SITE4.5_S(VSR_S) ; also on sheet 19
SL02_VI100_19_B_HS: 4K18.4 4TP_IS2N_S.1(TP) SITE4.10_S(IS2N_S) ; also on sheet 19
SL02_VI100_19_LS: 4SH3.1 ; also on sheet 19
SL02_VI100_20_A_HS: 4K7.4 4TP_SRG_S.1(TP) SITE4.4_S(SRG_S) ; also on sheet 19
SL02_VI100_20_B_HS: 4K28.4 4TP_C1B_S.1(TP) SITE4.17_S(C1B_S) ; also on sheet 19
SL02_VI100_20_LS: 4SH4.1 ; also on sheet 19
SL02_VI100_21_A_HF: 4K11.4 4K12.4 4K13.4 4TP_VCC_F.1(TP) SITE4.6_F(VCC_F) ; also on sheet 19
SL02_VI100_21_A_HS: 4TP_VCC_S.1(TP) SITE4.6_S(VCC_S) ; also on sheet 19
SL02_VI100_21_LS: 4SH5.1 ; also on sheet 19
SL02_VI100_22_A_HF: 4TP_OPTO_F.1(TP) SITE4.7_F(OPTO_F) ; also on sheet 19
SL02_VI100_22_A_HS: 4K14.4 4TP_OPTO_S.1(TP) SITE4.7_S(OPTO_S) ; also on sheet 19
SL02_VI100_22_B_HF: SITE4.30_F(GB2_F) ; also on sheet 19
SL02_VI100_22_B_HS: 4K46.4 4TP_GB2_S.1(TP) SITE4.30_S(GB2_S) ; also on sheet 19
SL02_VI100_22_LS: 4SH6.1 ; also on sheet 19
SL02_VI100_23_A_HF: 4TP_STB_F.1(TP) SITE4.13_F(STB_F) ; also on sheet 19
SL02_VI100_23_A_HS: 4K22.4 4TP_STB_S.1(TP) SITE4.13_S(STB_S) ; also on sheet 19
SL02_VI100_23_B_HF: 4K47.4 SITE4.31_F(VO2_F) ; also on sheet 19
SL02_VI100_23_B_HS: 4K48.4 4TP_VO2_S.1(TP) SITE4.31_S(VO2_S) ; also on sheet 19
SL02_VI100_23_LS: 4SH7.1 ; also on sheet 19
SL02_VI100_24_A_HF: 4K23.4 ; also on sheet 19
SL02_VI100_24_A_HS: 4K23.5 ; also on sheet 19
SL02_VI100_24_B_HF: 4C61.2 4TP_C2B_F.1(TP) SITE4.20_F(C2B_F) ; also on sheet 19
SL02_VI100_24_B_HS: 4K32.4 4TP_C2B_S.1(TP) SITE4.20_S(C2B_S) ; also on sheet 19
SL02_VI100_24_LS: 4SH8.1 ; also on sheet 19
SL02_VI100_25_A_HF: 4K24.4 ; also on sheet 19
SL02_VI100_25_A_HS: 4K24.5 ; also on sheet 19
SL02_VI100_25_B_HF: 4K33.4 4TP_C3B_F.1(TP) SITE4.21_F(C3B_F) ; also on sheet 19
SL02_VI100_25_B_HS: 4K34.4 4TP_C3B_S.1(TP) SITE4.21_S(C3B_S) ; also on sheet 19
SL02_VI100_25_LS: 4SH9.1 ; also on sheet 19
SL02_VI100_26_A_HF: 4K25.4 4TP_VDD0_F.1(TP) SITE4.16_F(VDD0_F) ; also on sheet 19
SL02_VI100_26_A_HS: 4K26.4 4TP_VDD0_S.1(TP) SITE4.16_S(VDD0_S) ; also on sheet 19
SL02_VI100_26_B_HF: SITE4.25_F(GA2_F) ; also on sheet 19
SL02_VI100_26_B_HS: 4K40.4 4TP_GA2_S.1(TP) SITE4.25_S(GA2_S) ; also on sheet 19
SL02_VI100_26_LS: 4SH10.1 ; also on sheet 19
SL02_VI100_27_A_HF: 4C63.2 4TP_C1A_F.1(TP) SITE4.18_F(C1A_F) ; also on sheet 19
SL02_VI100_27_A_HS: 4K29.4 4TP_C1A_S.1(TP) SITE4.18_S(C1A_S) ; also on sheet 19
SL02_VI100_27_B_HF: SITE4.26_F(GA1_F) ; also on sheet 19
SL02_VI100_27_B_HS: 4K41.4 4TP_GA1_S.1(TP) SITE4.26_S(GA1_S) ; also on sheet 19
SL02_VI100_27_LS: 4SH11.1 ; also on sheet 19
SL02_VI100_28_A_HF: 4K30.4 4TP_C2A_F.1(TP) SITE4.19_F(C2A_F) ; also on sheet 19
SL02_VI100_28_A_HS: 4K31.4 4TP_C2A_S.1(TP) SITE4.19_S(C2A_S) ; also on sheet 19
SL02_VI100_28_B_HF: SITE4.27_F(GB1_F) ; also on sheet 19
SL02_VI100_28_B_HS: 4K42.4 4TP_GB1_S.1(TP) SITE4.27_S(GB1_S) ; also on sheet 19
SL02_VI100_28_LS: 4SH12.1 ; also on sheet 19
SL02_VI100_29_A_HF: 4C64.2 4TP_C3A_F.1(TP) SITE4.22_F(C3A_F) ; also on sheet 19
SL02_VI100_29_A_HS: 4K35.4 4TP_C3A_S.1(TP) SITE4.22_S(C3A_S) ; also on sheet 19
SL02_VI100_29_B_HF: 4K49.4 SITE4.32_F(VDD2_F) ; also on sheet 19
SL02_VI100_29_B_HS: 4K50.4 4TP_VDD2_S.1(TP) SITE4.32_S(VDD2_S) ; also on sheet 19
SL02_VI100_29_LS: 4SH13.1 ; also on sheet 19
SL02_VI100_30_A_HF: 4K36.4 4TP_VDDI_F.1(TP) SITE4.23_F(VDDI_F) ; also on sheet 19
SL02_VI100_30_A_HS: 4K37.4 4TP_VDDI_S.1(TP) SITE4.23_S(VDDI_S) ; also on sheet 19
SL02_VI100_30_B_HS: 4K21.4 4TP_IS1N_S.1(TP) SITE4.12_S(IS1N_S) ; also on sheet 19
SL02_VI100_30_LS: 4SH14.1 ; also on sheet 19
SL02_VI100_31_A_HF: 4K38.4 4TP_VIN_F.1(TP) SITE4.24_F(VIN_F) ; also on sheet 19
SL02_VI100_31_A_HS: 4K39.4 4TP_VIN_S.1(TP) SITE4.24_S(VIN_S) ; also on sheet 19
SL02_VI100_31_B_HS: 4K20.4 SITE4.11_S(IS1P_S) ; also on sheet 19
SL02_VI100_31_LS: 4SH15.1 ; also on sheet 19
SL02_VI100_32_A_HF: SITE4.28_F(VO1_F) ; also on sheet 19
SL02_VI100_32_A_HS: 4K43.4 4TP_VO1_S.1(TP) SITE4.28_S(VO1_S) ; also on sheet 19
SL02_VI100_32_B_HS: 4K17.4 4TP_IS2P_S.1(TP) SITE4.9_S(IS2P_S) ; also on sheet 19
SL02_VI100_32_LS: 4SH16.1 ; also on sheet 19
SL05_PMVI_3_HF: 5K15.4 ; also on sheet 16
SL05_PMVI_3_HS: 5K15.5 ; also on sheet 16
SL06_DP_30: 4K4.3 ; also on sheet 15
SL06_DP_31: 4K6.3 ; also on sheet 15
SL06_DP_32: 4K7.3 ; also on sheet 15
SL06_DP_33: 4K10.3 ; also on sheet 15
SL06_DP_34: 4K14.3 ; also on sheet 15
SL06_DP_35: 4K15.2 ; also on sheet 15
SL06_DP_36: 4K17.3 ; also on sheet 15
SL06_DP_37: 4K18.3 ; also on sheet 15
SL06_DP_38: 4K20.3 ; also on sheet 15
SL06_DP_39: 4K21.3 ; also on sheet 15
SL06_DP_40: 4K22.3 ; also on sheet 15
SL06_DP_41: 4K23.2 ; also on sheet 15
SL06_DP_42: 4K24.2 ; also on sheet 15
SL06_DP_43: 4K26.3 ; also on sheet 15
SL06_DP_44: 4K28.3 ; also on sheet 15
SL06_DP_45: 4K29.3 ; also on sheet 15
SL06_DP_46: 4K31.3 ; also on sheet 15
SL06_DP_47: 4K32.3 ; also on sheet 15
SL06_DP_48: 4K34.3 ; also on sheet 15
SL06_DP_49: 4K35.3 ; also on sheet 15
SL06_DP_50: 4K37.3 ; also on sheet 15
SL06_DP_51: 4K39.3 ; also on sheet 15
SL06_DP_52: 4K40.3 ; also on sheet 15
SL06_DP_53: 4K41.3 ; also on sheet 15
SL06_DP_54: 4K42.3 ; also on sheet 15
SL06_DP_55: 4K43.3 ; also on sheet 15
SL06_DP_56: 4K45.3 ; also on sheet 15
SL06_DP_57: 4K46.3 ; also on sheet 15
SL06_DP_58: 4K48.3 ; also on sheet 15
SL06_DP_59: 4K50.3 ; also on sheet 15
SL06_DP_127: 4TP_OUT+_1.1(TP) 4U1.1(OUT+) ; also on sheet 15
SL06_DP_128: 4TP_OUT-_1.1(TP) 4U1.6(OUT-) ; also on sheet 15
SL06_DP_129: 4TP_OUT+_2.1(TP) 4U2.1(OUT+) ; also on sheet 15
SL06_DP_130: 4TP_OUT-_2.1(TP) 4U2.6(OUT-) ; also on sheet 15
SL06_DP_131: 4R15.1 4U3.2(ENABLE) ; also on sheet 15
SL06_DP_132: 4R17.1 4U4.2(ENABLE) ; also on sheet 15
SL09_FPVI_2_A_HF: 5K1.4 ; also on sheet 12
SL09_FPVI_2_A_HS: 5K1.5 ; also on sheet 12
SL10_FPVI_5_A_HF: 4K1.4 ; also on sheet 11
SL10_FPVI_5_A_HS: 4K1.5 ; also on sheet 11
SL13_DP_60: 5K4.3 ; also on sheet 8
SL13_DP_61: 5K6.3 ; also on sheet 8
SL13_DP_62: 5K7.3 ; also on sheet 8
SL13_DP_63: 5K10.3 ; also on sheet 8
SL13_DP_64: 5K14.3 ; also on sheet 8
SL13_DP_65: 5K15.2 ; also on sheet 8
SL13_DP_66: 5K17.3 ; also on sheet 8
SL13_DP_67: 5K18.3 ; also on sheet 8
SL13_DP_68: 5K20.3 ; also on sheet 8
SL13_DP_69: 5K21.3 ; also on sheet 8
SL13_DP_70: 5K22.3 ; also on sheet 8
SL13_DP_71: 5K23.2 ; also on sheet 8
SL13_DP_72: 5K24.2 ; also on sheet 8
SL13_DP_73: 5K26.3 ; also on sheet 8
SL13_DP_74: 5K28.3 ; also on sheet 8
SL13_DP_75: 5K29.3 ; also on sheet 8
SL13_DP_76: 5K31.3 ; also on sheet 8
SL13_DP_77: 5K32.3 ; also on sheet 8
SL13_DP_78: 5K34.3 ; also on sheet 8
SL13_DP_79: 5K35.3 ; also on sheet 8
SL13_DP_80: 5K37.3 ; also on sheet 8
SL14_PMVI_2_HF: 4K15.4 ; also on sheet 7
SL14_PMVI_2_HS: 4K15.5 ; also on sheet 7
SL14_PMVI_2_LS: 4SH17.1 ; also on sheet 7
SL14_PMVI_20_HF: 4R7.1 4SHORT3.1 ; also on sheet 7
SL14_PMVI_20_HS: 4SHORT3.2 ; also on sheet 7
SL14_PMVI_20_LS: 4SH18.1 ; also on sheet 7
SL14_PMVI_21_HF: 4R8.1 4SHORT4.1 ; also on sheet 7
SL14_PMVI_21_HS: 4SHORT4.2 ; also on sheet 7
SL14_PMVI_21_LS: 4SH19.1 ; also on sheet 7
SL14_PMVI_22_HF: 4SHORT1.1 4TP_IN-_1.1(TP) 4U1.4(-IN) ; also on sheet 7
SL14_PMVI_22_HS: 4SHORT1.2 ; also on sheet 7
SL14_PMVI_22_LS: 4SH20.1 ; also on sheet 7
SL14_PMVI_23_HF: 4SHORT2.1 4TP_IN-_2.1(TP) 4U2.4(-IN) ; also on sheet 7
SL14_PMVI_23_HS: 4SHORT2.2 ; also on sheet 7
SL14_PMVI_23_LS: 4SH21.1 ; also on sheet 7
SL14_PMVI_24_HF: 4SHORT9.1 4TP_OUT_1.1(TP) 4U3.5(OUT) ; also on sheet 7
SL14_PMVI_24_HS: 4SHORT9.2 ; also on sheet 7
SL14_PMVI_24_LS: 4SH22.1 ; also on sheet 7
SL14_PMVI_25_HF: 4C72.1 4R15.2 4SHORT6.2 4U3.1(VS) ; also on sheet 7
SL14_PMVI_25_HS: 4SHORT6.1 ; also on sheet 7
SL14_PMVI_25_LS: 4SH23.1 ; also on sheet 7
SL14_PMVI_26_HF: 4SHORT11.2 4TP_REF_1.1(TP) 4U3.3(REF) ; also on sheet 7
SL14_PMVI_26_HS: 4SHORT11.1 ; also on sheet 7
SL14_PMVI_26_LS: 4SH24.1 ; also on sheet 7
SL14_PMVI_27_HF: 4SHORT10.1 4TP_OUT_2.1(TP) 4U4.5(OUT) ; also on sheet 7
SL14_PMVI_27_HS: 4SHORT10.2 ; also on sheet 7
SL14_PMVI_27_LS: 4SH25.1 ; also on sheet 7
SL14_PMVI_28_HF: 4C73.1 4R17.2 4SHORT7.2 4U4.1(VS) ; also on sheet 7
SL14_PMVI_28_HS: 4SHORT7.1 ; also on sheet 7
SL14_PMVI_28_LS: 4SH26.1 ; also on sheet 7
SL14_PMVI_29_HF: 4SHORT8.2 4TP_REF_2.1(TP) 4U4.3(REF) ; also on sheet 7
SL14_PMVI_29_HS: 4SHORT8.1 ; also on sheet 7
SL14_PMVI_29_LS: 4SH27.1 ; also on sheet 7
SL17_VI100_1_A_HF: 5K1.2 ; also on sheet 4
SL17_VI100_1_A_HS: 5K1.7 ; also on sheet 4
SL17_VI100_2_A_HF: 5C49.2 5K5.4 5TP_SRS_F.1(TP) SITE5.2_F(SRS_F) ; also on sheet 4
SL17_VI100_2_A_HS: 5K6.4 5TP_SRS_S.1(TP) SITE5.2_S(SRS_S) ; also on sheet 4
SL17_VI100_3_A_HF: 5K8.4 5K9.4 5TP_VSR_F.1(TP) SITE5.5_F(VSR_F) ; also on sheet 4
SL17_VI100_3_A_HS: 5K10.4 5TP_VSR_S.1(TP) SITE5.5_S(VSR_S) ; also on sheet 4
SL17_VI100_3_B_HS: 5K18.4 5TP_IS2N_S.1(TP) SITE5.10_S(IS2N_S) ; also on sheet 4
SL17_VI100_4_A_HS: 5K7.4 5TP_SRG_S.1(TP) SITE5.4_S(SRG_S) ; also on sheet 4
SL17_VI100_4_B_HS: 5K28.4 5TP_C1B_S.1(TP) SITE5.17_S(C1B_S) ; also on sheet 4
SL17_VI100_5_A_HF: 5K11.4 5K12.4 5K13.4 5TP_VCC_F.1(TP) SITE5.6_F(VCC_F) ; also on sheet 4
SL17_VI100_5_A_HS: 5TP_VCC_S.1(TP) SITE5.6_S(VCC_S) ; also on sheet 4
SL17_VI100_6_A_HF: 5TP_OPTO_F.1(TP) SITE5.7_F(OPTO_F) ; also on sheet 4
SL17_VI100_6_A_HS: 5K14.4 5TP_OPTO_S.1(TP) SITE5.7_S(OPTO_S) ; also on sheet 4
SL17_VI100_7_A_HF: 5TP_STB_F.1(TP) SITE5.13_F(STB_F) ; also on sheet 4
SL17_VI100_7_A_HS: 5K22.4 5TP_STB_S.1(TP) SITE5.13_S(STB_S) ; also on sheet 4
SL17_VI100_8_A_HF: 5K23.4 ; also on sheet 4
SL17_VI100_8_A_HS: 5K23.5 ; also on sheet 4
SL17_VI100_8_B_HF: 5C61.2 5TP_C2B_F.1(TP) SITE5.20_F(C2B_F) ; also on sheet 4
SL17_VI100_8_B_HS: 5K32.4 5TP_C2B_S.1(TP) SITE5.20_S(C2B_S) ; also on sheet 4
SL17_VI100_9_A_HF: 5K24.4 ; also on sheet 4
SL17_VI100_9_A_HS: 5K24.5 ; also on sheet 4
SL17_VI100_9_B_HF: 5K33.4 5TP_C3B_F.1(TP) SITE5.21_F(C3B_F) ; also on sheet 4
SL17_VI100_9_B_HS: 5K34.4 5TP_C3B_S.1(TP) SITE5.21_S(C3B_S) ; also on sheet 4
SL17_VI100_10_A_HF: 5K25.4 5TP_VDD0_F.1(TP) SITE5.16_F(VDD0_F) ; also on sheet 4
SL17_VI100_10_A_HS: 5K26.4 5TP_VDD0_S.1(TP) SITE5.16_S(VDD0_S) ; also on sheet 4
SL17_VI100_11_A_HF: 5C63.2 5TP_C1A_F.1(TP) SITE5.18_F(C1A_F) ; also on sheet 4
SL17_VI100_11_A_HS: 5K29.4 5TP_C1A_S.1(TP) SITE5.18_S(C1A_S) ; also on sheet 4
SL17_VI100_12_A_HF: 5K30.4 5TP_C2A_F.1(TP) SITE5.19_F(C2A_F) ; also on sheet 4
SL17_VI100_12_A_HS: 5K31.4 5TP_C2A_S.1(TP) SITE5.19_S(C2A_S) ; also on sheet 4
SL17_VI100_13_A_HF: 5C64.2 5TP_C3A_F.1(TP) SITE5.22_F(C3A_F) ; also on sheet 4
SL17_VI100_13_A_HS: 5K35.4 5TP_C3A_S.1(TP) SITE5.22_S(C3A_S) ; also on sheet 4
SL17_VI100_14_A_HF: 5K36.4 5TP_VDDI_F.1(TP) SITE5.23_F(VDDI_F) ; also on sheet 4
SL17_VI100_14_A_HS: 5K37.4 5TP_VDDI_S.1(TP) SITE5.23_S(VDDI_S) ; also on sheet 4
SL17_VI100_14_B_HS: 5K21.4 5TP_IS1N_S.1(TP) SITE5.12_S(IS1N_S) ; also on sheet 4
SL17_VI100_15_B_HS: 5K20.4 SITE5.11_S(IS1P_S) ; also on sheet 4
SL17_VI100_16_B_HS: 5K17.4 5TP_IS2P_S.1(TP) SITE5.9_S(IS2P_S) ; also on sheet 4
N18716734: 4C48.1 4K2.3
N18716743: 4C49.1 4K3.3
N18716752: 4C50.1 4K5.3
N18716785: 4K7.1 4RK7.1
N18716792: 4C53.1 4K8.3
N18716801: 4C54.1 4K9.3
N18716831: 4C59.1 4K12.3
N18716838: 4K13.3 4R1.1
N18716856: 4K15.6 4TP_ATT_S.1(TP) SITE4.8_S(ATT_S)
N18716874: 4K5.1 4RK5.1
N18716876: 4K6.1 4RK6.1
N18716878: 4K8.1 4RK8.1
N18716879: 4K9.1 4RK9.1
N18716880: 4K10.1 4RK10.1
N18716881: 4K11.1 4RK11.1
N18716884: 4C58.1 4K11.3
N18716887: 4K12.1 4RK12.1
N18716889: 4K13.1 4RK13.1
N18716892: 4K14.1 4RK14.1
N18716894: 4K2.1 4RK2.1
N18716895: 4K3.1 4RK3.1
N18716896: 4K4.1 4RK4.1
N18716916: 4K15.3 4TP_ATT_F.1(TP) SITE4.8_F(ATT_F)
N18716928: 4C60.1 4K16.3
N18716941: 4K17.1 4RK17.1
N18716955: 4K16.1 4RK16.1
N18716959: 4K18.1 4RK18.1
N18718109: 4C69.1 4K19.3
N18718136: 4K19.1 4RK19.1
N18718138: 4K20.1 4RK20.1
N18718139: 4K21.1 4RK21.1
N18718164: 4K22.1 4RK22.1
N18718170: 4K23.6 4TP_SDA_S.1(TP) SITE4.14_S(SDA_S)
N18718184: 4K24.6 SITE4.15_S(SCL_S)
N18718194: 4C62.1 4K25.3
N18718212: 4K25.1 4RK25.1
N18718216: 4K26.1 4RK26.1
N18718221: 4C63.1 4K27.3
N18718237: 4K28.1 4RK28.1
N18718258: 4K27.1 4RK27.1
N18718260: 4K29.1 4RK29.1
N18718265: 4C61.1 4K30.3
N18718279: 4K31.1 4RK31.1
N18718299: 4K30.1 4RK30.1
N18718302: 4K32.1 4RK32.1
N18718304: 4K35.1 4RK35.1
N18718306: 4K34.1 4RK34.1
N18718308: 4K33.1 4RK33.1
N18718311: 4C64.1 4K33.3
N18718346: 4K37.1 4RK37.1
N18718347: 4K36.1 4RK36.1
N18718353: 4C65.1 4K36.3
N18719639: 4K39.1 4RK39.1
N18719640: 4K38.1 4RK38.1
N18719646: 4C74.1 4K38.3
N18719665: 4K40.1 4RK40.1
N18719678: 4K41.1 4RK41.1
N18719691: 4K42.1 4RK42.1
N18719703: 4K43.1 4RK43.1
N18719716: 4K45.1 4RK45.1
N18719717: 4K44.1 4RK44.1
N18719727: 4C66.1 4K44.3
N18719745: 4K46.1 4RK46.1
N18719761: 4C67.1 4K47.3
N18719774: 4K48.1 4RK48.1
N18719775: 4K47.1 4RK47.1
N18719785: 4C68.1 4K49.3
N18719798: 4K50.1 4RK50.1
N18719799: 4K49.1 4RK49.1
N18720613: 4K51.4 4R7.2
N18720625: 4K53.4 4R8.2
N18720627: 4K53.1 4RK53.1
N18720649: 4R11.2 4R19.1 4TP_IN+_1.1(TP) 4U1.3(+IN)
N18720661: 4R14.2 4R20.1 4TP_IN+_2.1(TP) 4U2.3(+IN)
N18720671: 4K55.1 4RK59.1
N18720674: 4K55.4 4R19.2
N18720676: 4K56.1 4RK60.1
N18720693: 4K57.3 4R16.1 4TP_IN-_3.1(TP) 4U3.8(IN-)
N18720694: 4K58.4 4R16.2 4TP_IN+_3.1(TP) 4U3.7(IN+)
N18720722: 4K60.4 4R18.2 4TP_IN+_4.1(TP) 4U4.7(IN+)
N18720726: 4K59.3 4R18.1 4TP_IN-_4.1(TP) 4U4.8(IN-)
N18720737: 4K56.4 4K61.4 4R20.2
N18720738: 4K54.1 4RK54.1
N18720742: 4K51.1 4RK51.1
N18720744: 4K52.1 4RK52.1
N18720808: 4K57.1 4RK55.2
N18720809: 4K58.1 4RK56.2
N18720810: 4K59.1 4RK57.2
N18720811: 4K60.1 4RK58.2
N18720814: 4K61.1 4RK61.1
N18721945: 5C48.1 5K2.3
N18721954: 5C49.1 5K3.3
N18721963: 5C50.1 5K5.3
N18721996: 5K7.1 5RK7.1
N18722003: 5C53.1 5K8.3
N18722012: 5C54.1 5K9.3
N18722042: 5C59.1 5K12.3
N18722049: 5K13.3 5R1.1
N18722067: 5K15.6 5TP_ATT_S.1(TP) SITE5.8_S(ATT_S)
N18722085: 5K5.1 5RK5.1
N18722087: 5K6.1 5RK6.1
N18722089: 5K8.1 5RK8.1
N18722090: 5K9.1 5RK9.1
N18722091: 5K10.1 5RK10.1
N18722092: 5K11.1 5RK11.1
N18722095: 5C58.1 5K11.3
N18722098: 5K12.1 5RK12.1
N18722100: 5K13.1 5RK13.1
N18722103: 5K14.1 5RK14.1
N18722105: 5K2.1 5RK2.1
N18722106: 5K3.1 5RK3.1
N18722107: 5K4.1 5RK4.1
N18722127: 5K15.3 5TP_ATT_F.1(TP) SITE5.8_F(ATT_F)
N18722139: 5C60.1 5K16.3
N18722152: 5K17.1 5RK17.1
N18722166: 5K16.1 5RK16.1
N18722170: 5K18.1 5RK18.1
N18723320: 5C69.1 5K19.3
N18723347: 5K19.1 5RK19.1
N18723349: 5K20.1 5RK20.1
N18723350: 5K21.1 5RK21.1
N18723375: 5K22.1 5RK22.1
N18723381: 5K23.6 5TP_SDA_S.1(TP) SITE5.14_S(SDA_S)
N18723395: 5K24.6 SITE5.15_S(SCL_S)
N18723405: 5C62.1 5K25.3
N18723423: 5K25.1 5RK25.1
N18723427: 5K26.1 5RK26.1
N18723432: 5C63.1 5K27.3
N18723448: 5K28.1 5RK28.1
N18723469: 5K27.1 5RK27.1
N18723471: 5K29.1 5RK29.1
N18723476: 5C61.1 5K30.3
N18723490: 5K31.1 5RK31.1
N18723510: 5K30.1 5RK30.1
N18723513: 5K32.1 5RK32.1
N18723515: 5K35.1 5RK35.1
N18723517: 5K34.1 5RK34.1
N18723519: 5K33.1 5RK33.1
N18723522: 5C64.1 5K33.3
N18723557: 5K37.1 5RK37.1
N18723558: 5K36.1 5RK36.1
N18723564: 5C65.1 5K36.3

Not connected (* = marked no-connect by the designer): 4K15 7*; 4K23 7*; 4K24 7*; 4U3 6(NC)*; 4U4 6(NC)*; 5K15 7*; 5K23 7*; 5K24 7*; SITE4 NGH1* NGH2* NGH3* NGH4* NUT1* NUT2* NUT3* NUT4*

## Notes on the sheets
sheet 39
- Pull-up Resistor
- Timing Circuits(GX1 ¸ê·½¤À°t»Ý­n¦b®É§Ç¹q¸ô¤W¬Û¾F)
- Differential Circuit
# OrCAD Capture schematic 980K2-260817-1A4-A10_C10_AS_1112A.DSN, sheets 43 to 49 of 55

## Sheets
43 P0034_S3_DUT: size C
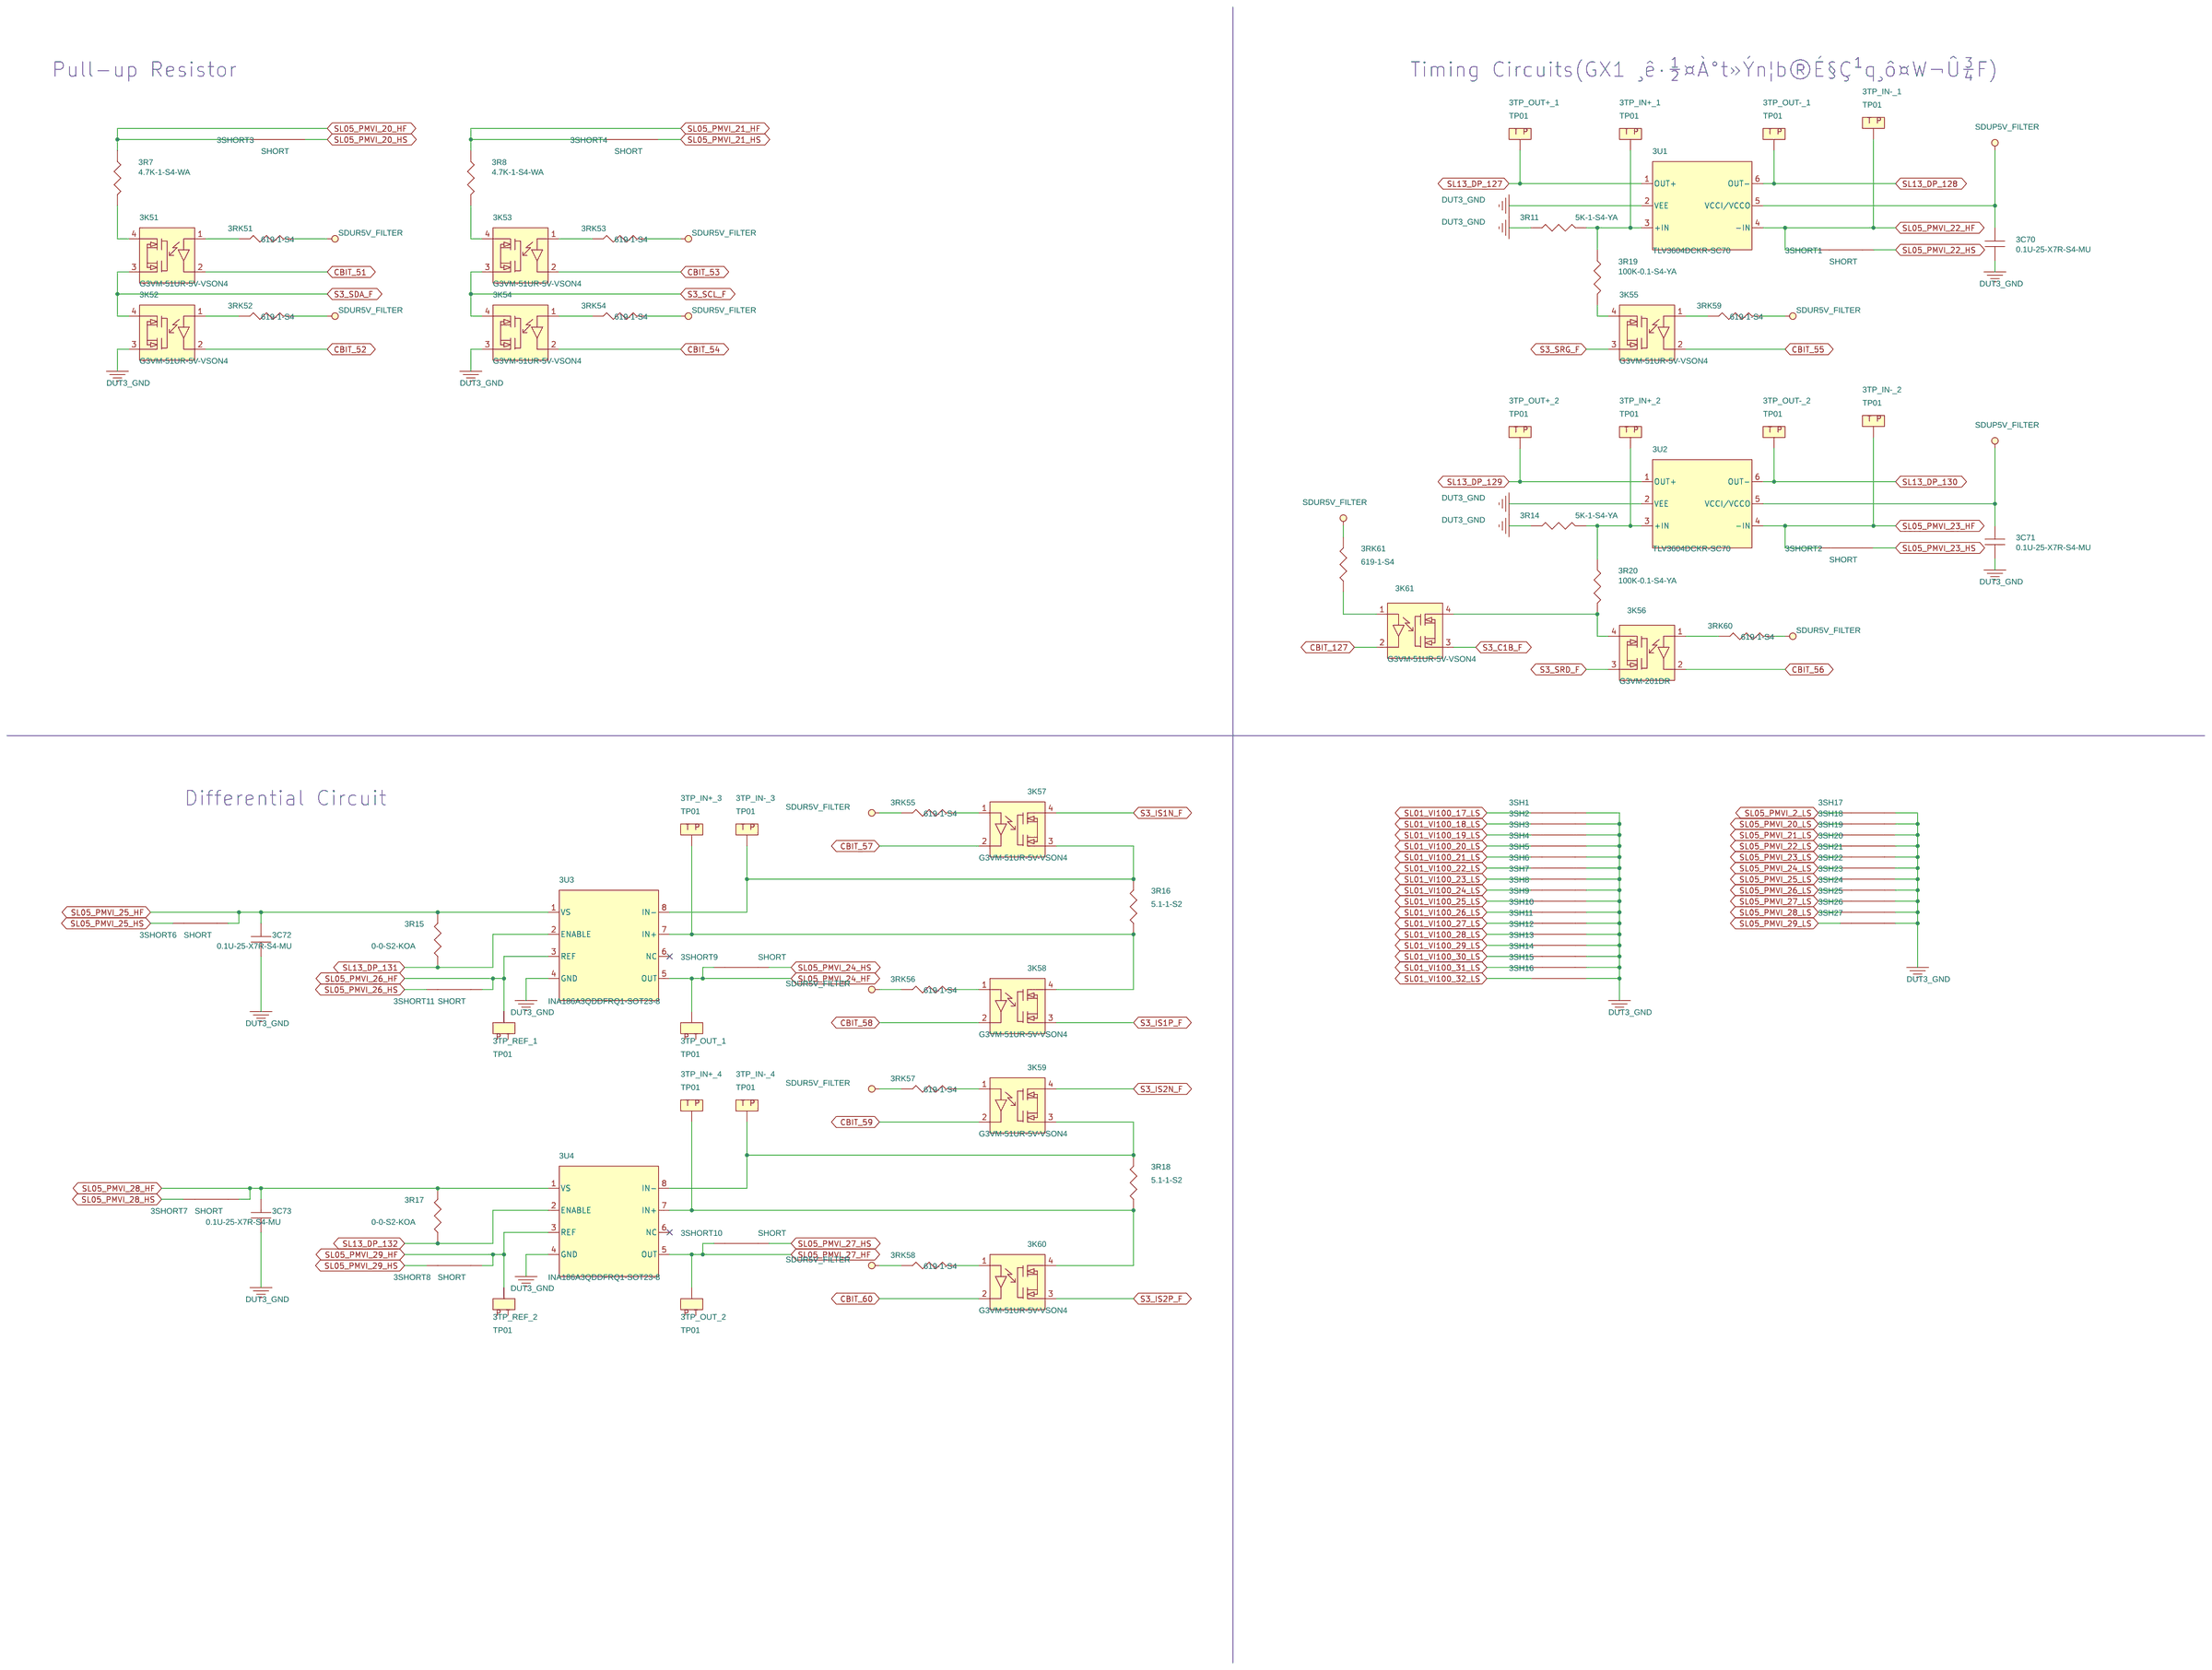
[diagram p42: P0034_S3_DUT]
44 P0033_S3_DUT: size C
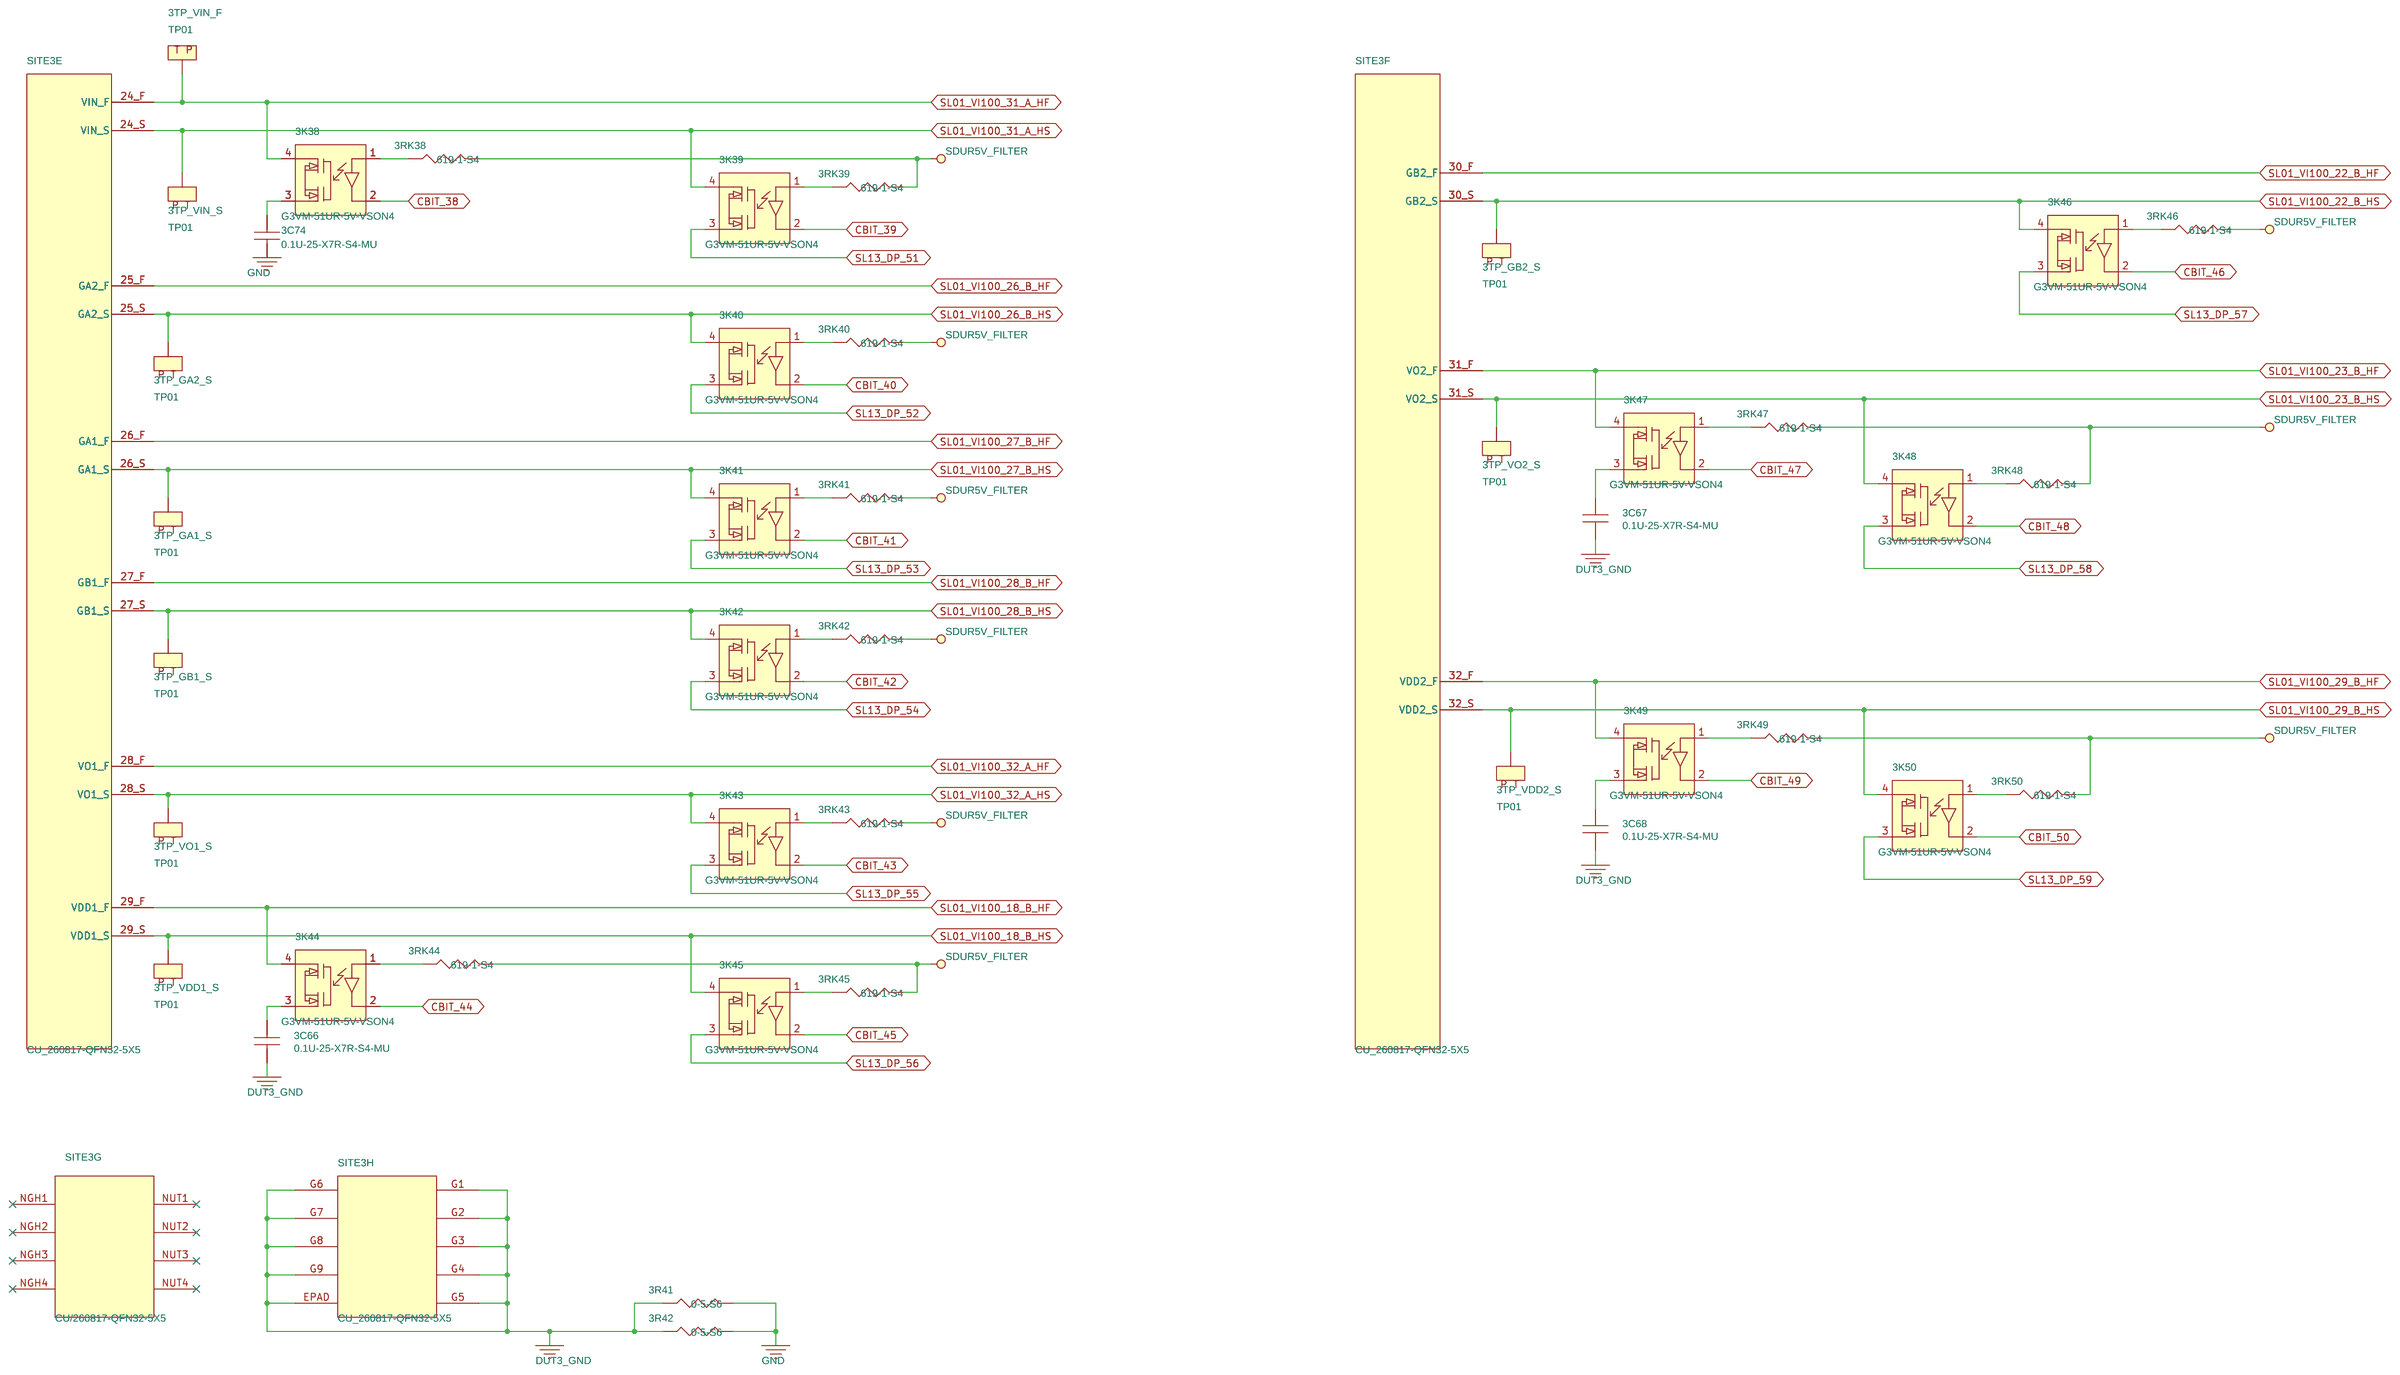
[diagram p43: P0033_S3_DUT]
45 P0032_S3_DUT: size C
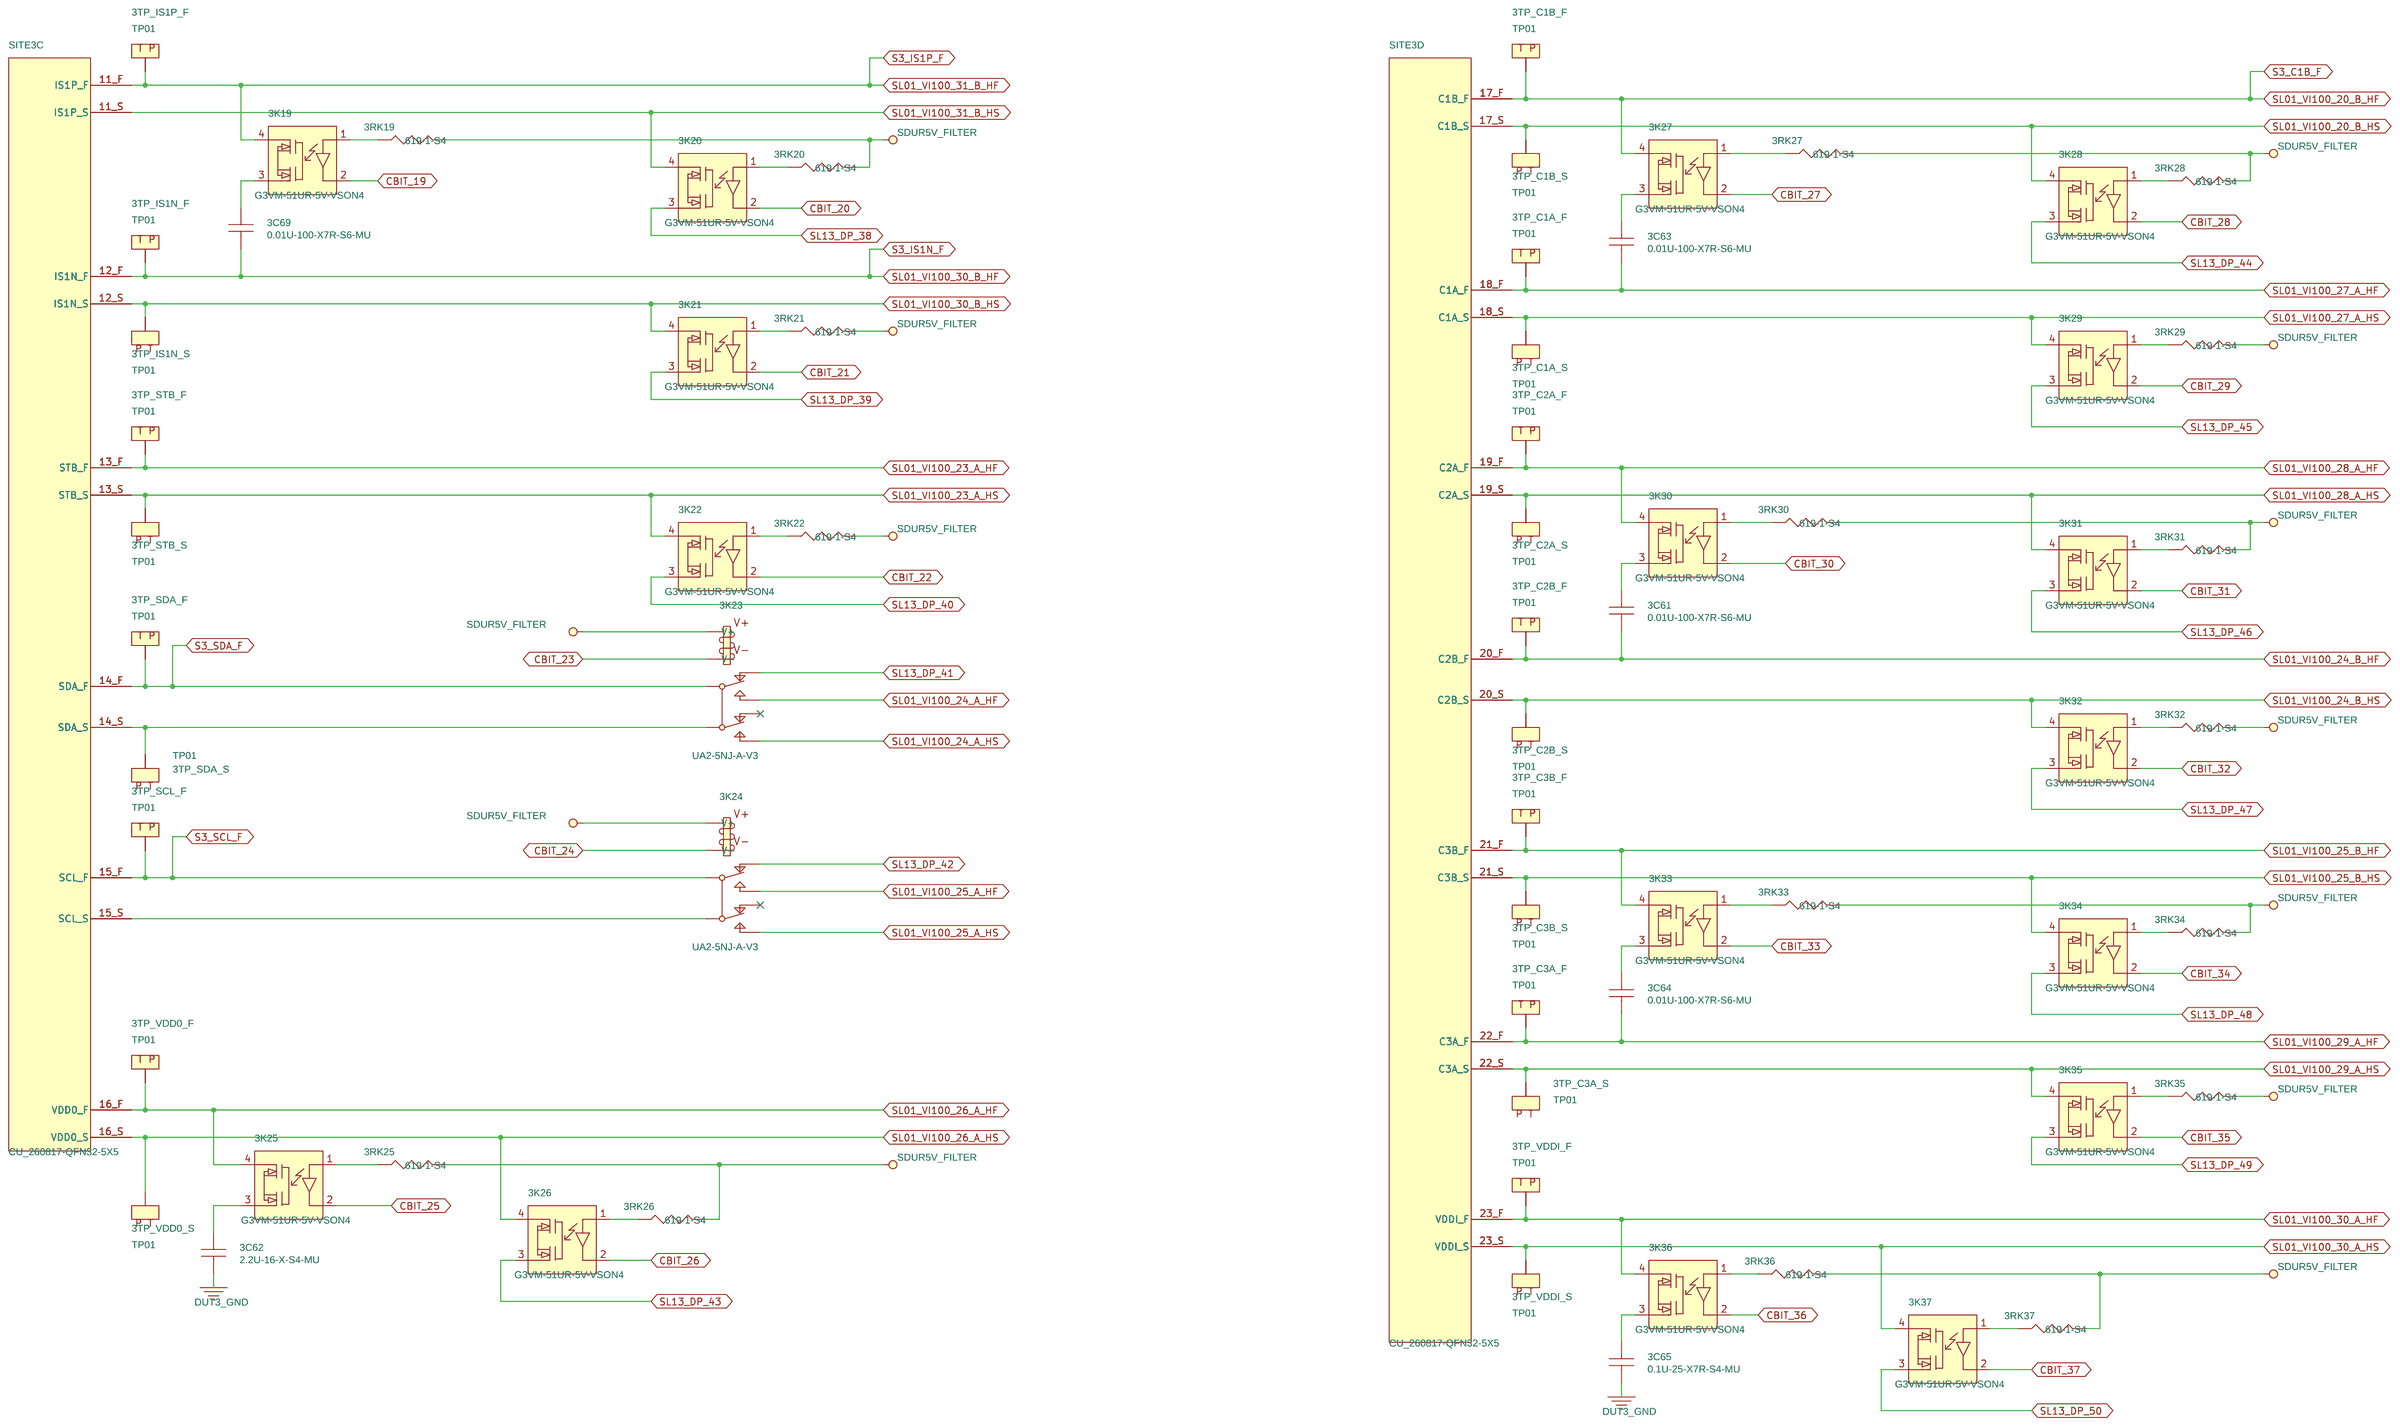
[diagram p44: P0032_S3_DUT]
46 P0031_S3_DUT: size C
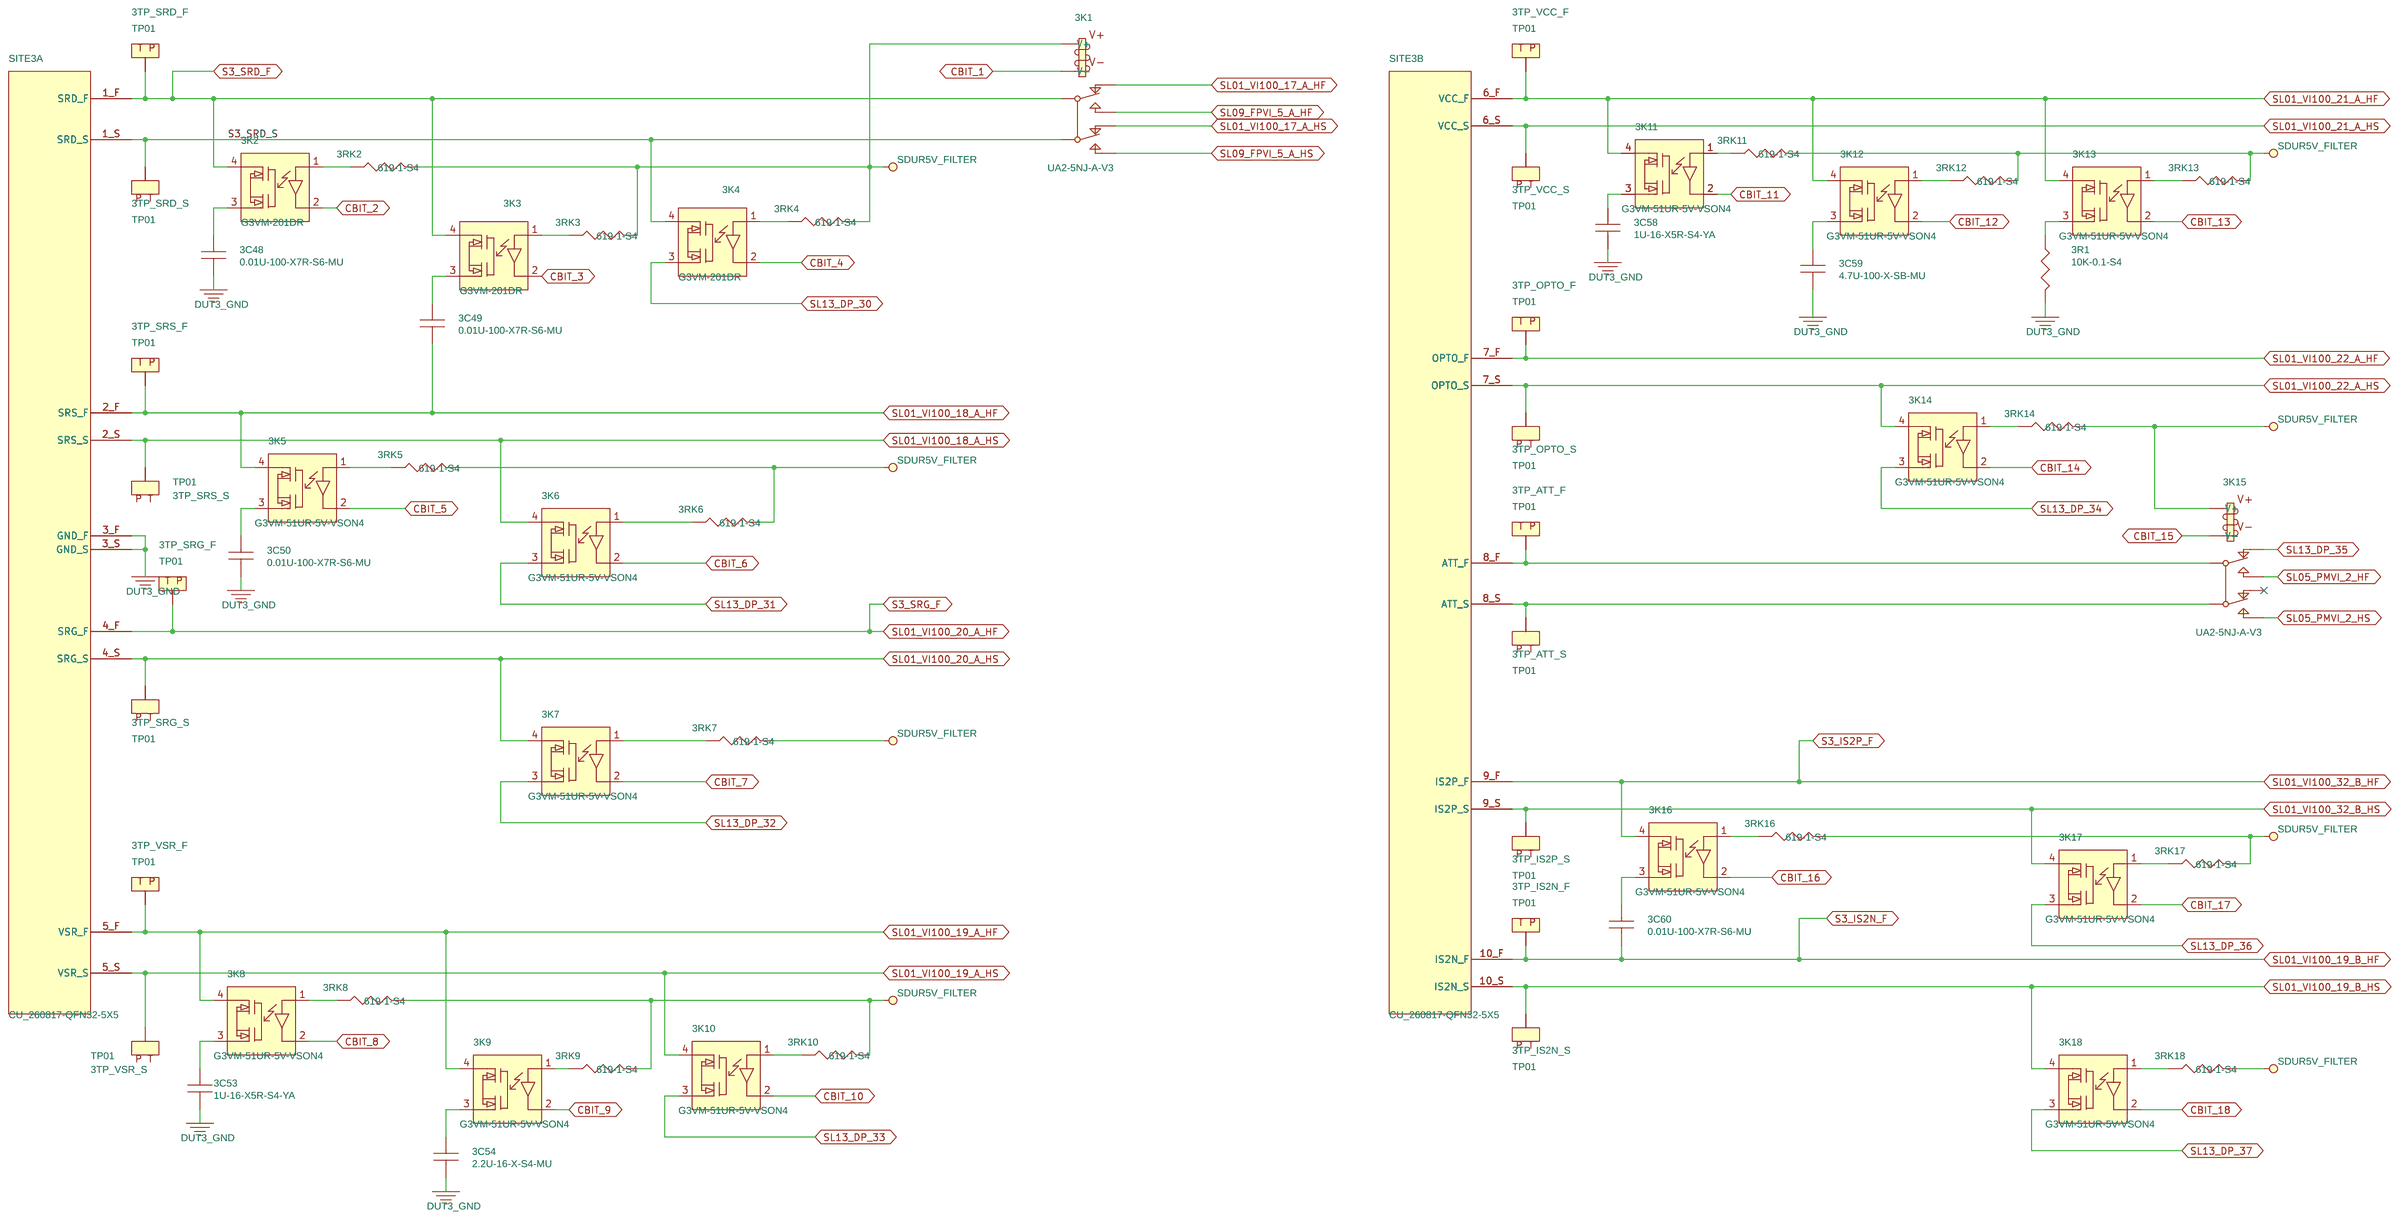
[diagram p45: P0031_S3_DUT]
47 P0024_S2_DUT: size C
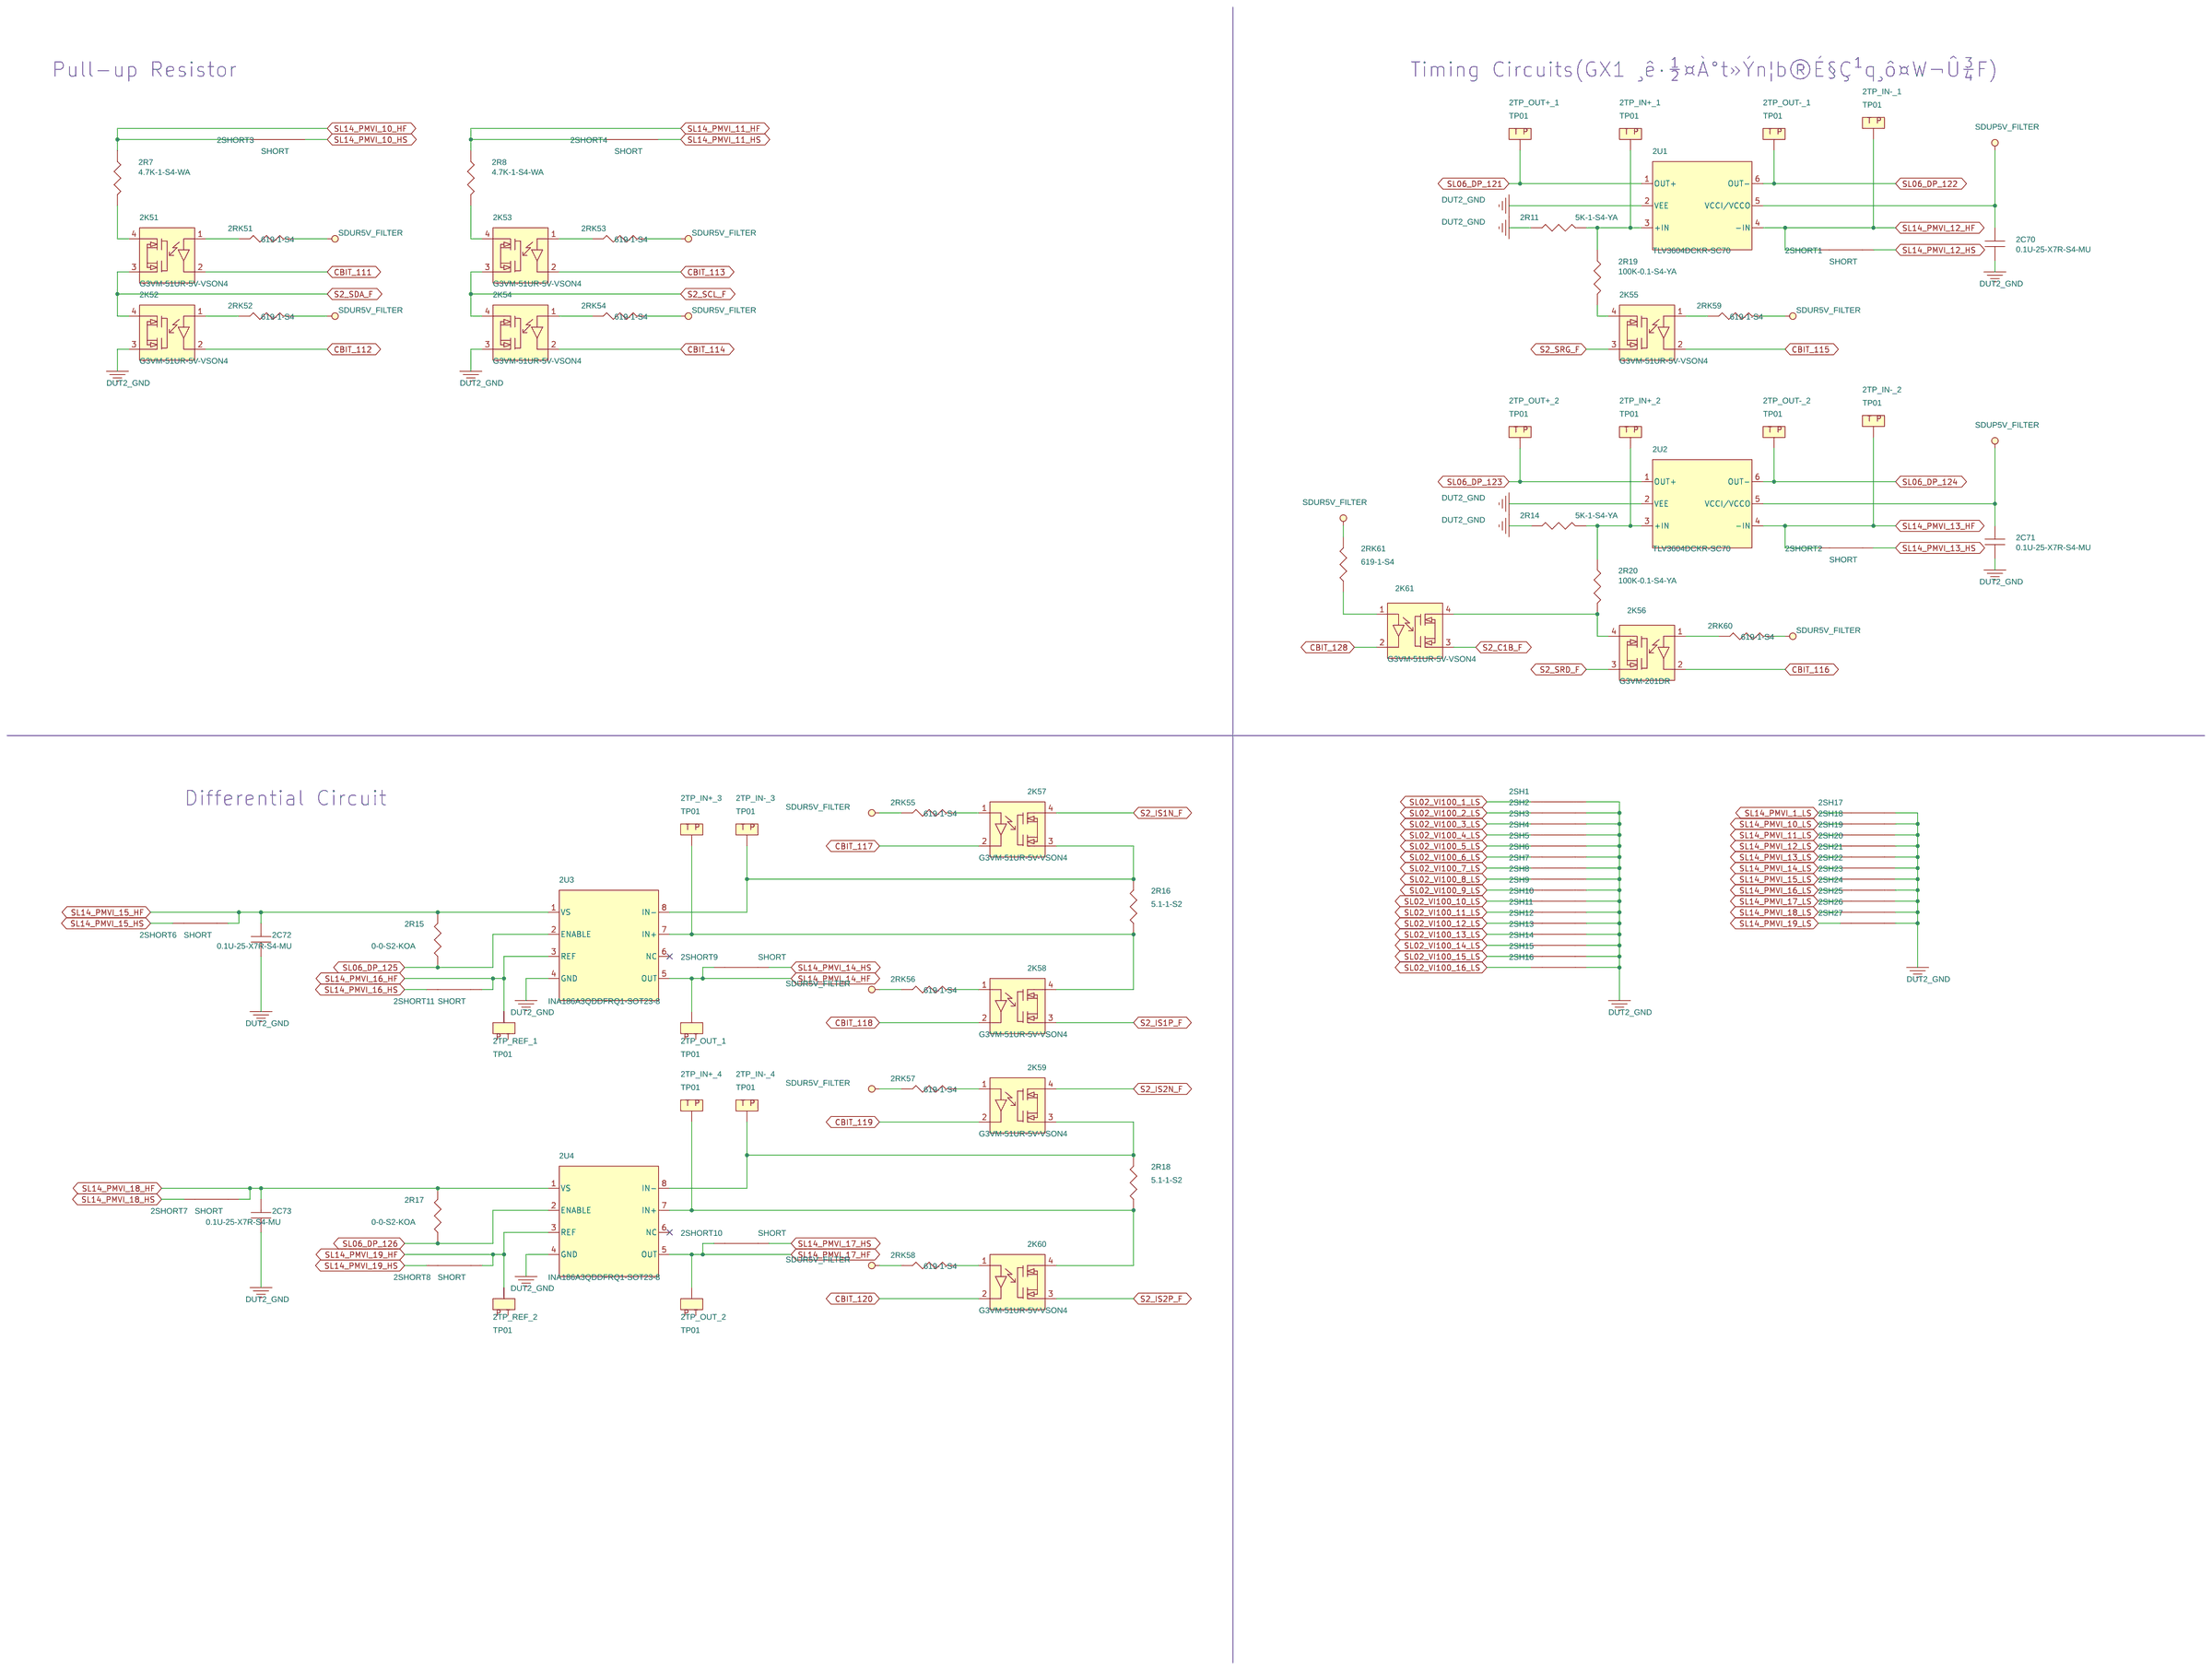
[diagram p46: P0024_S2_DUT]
48 P0023_S2_DUT: size C
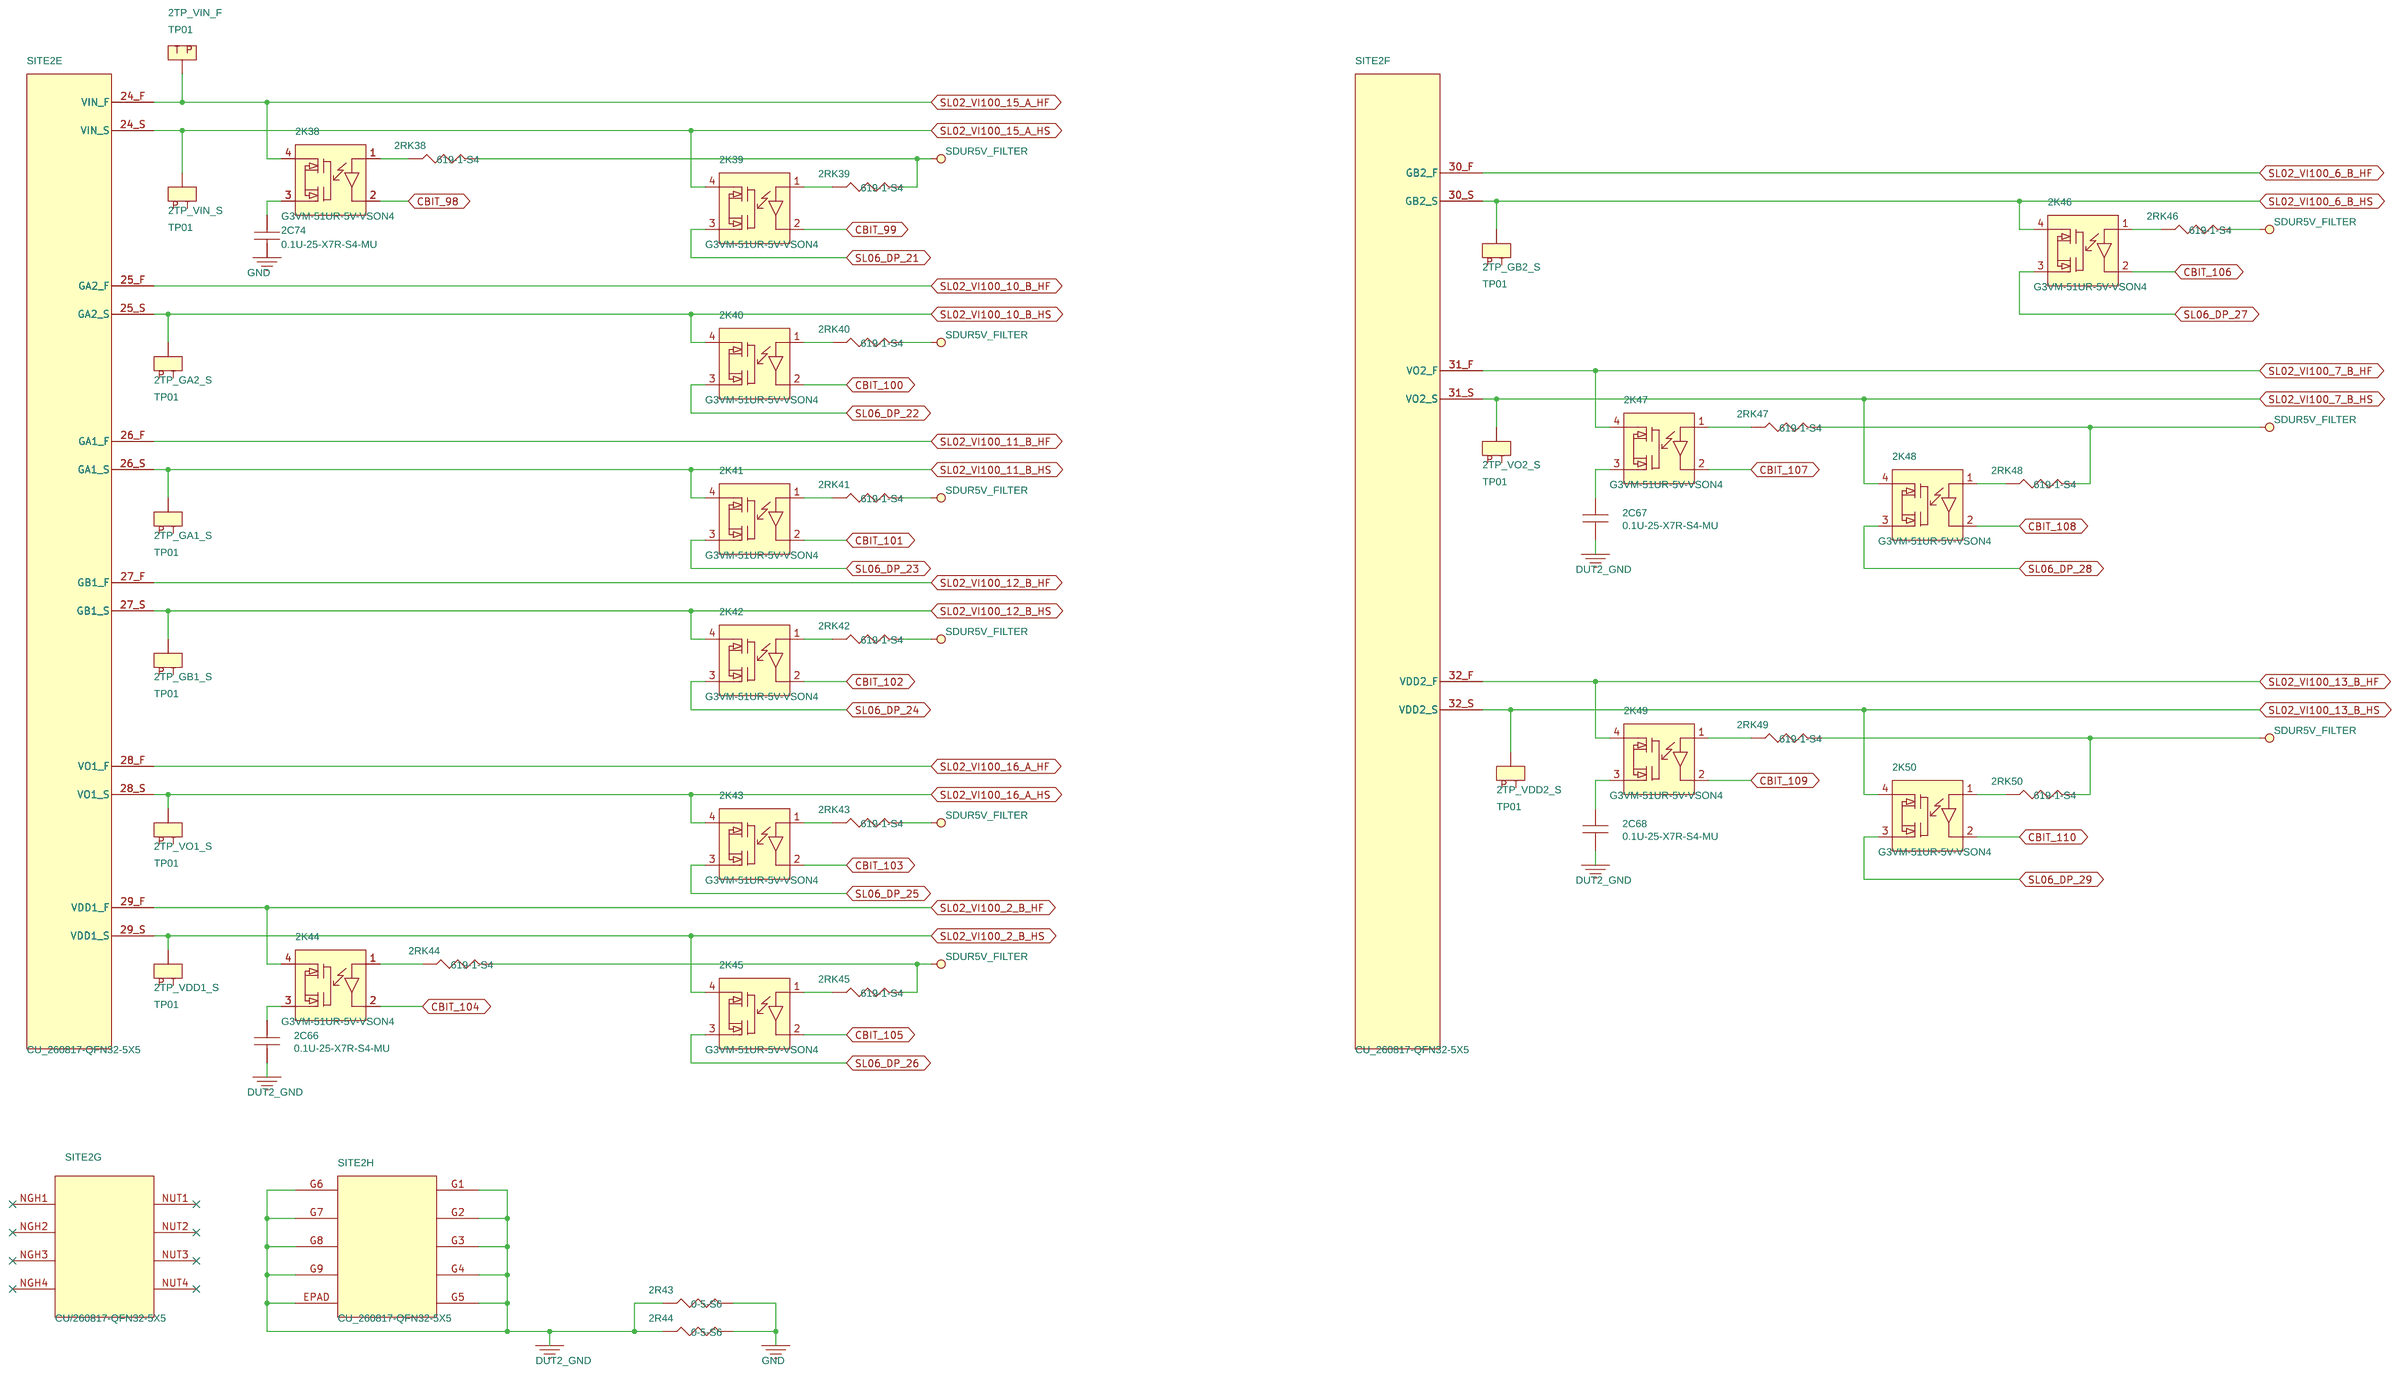
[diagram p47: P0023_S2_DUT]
49 P0022_S2_DUT: size C

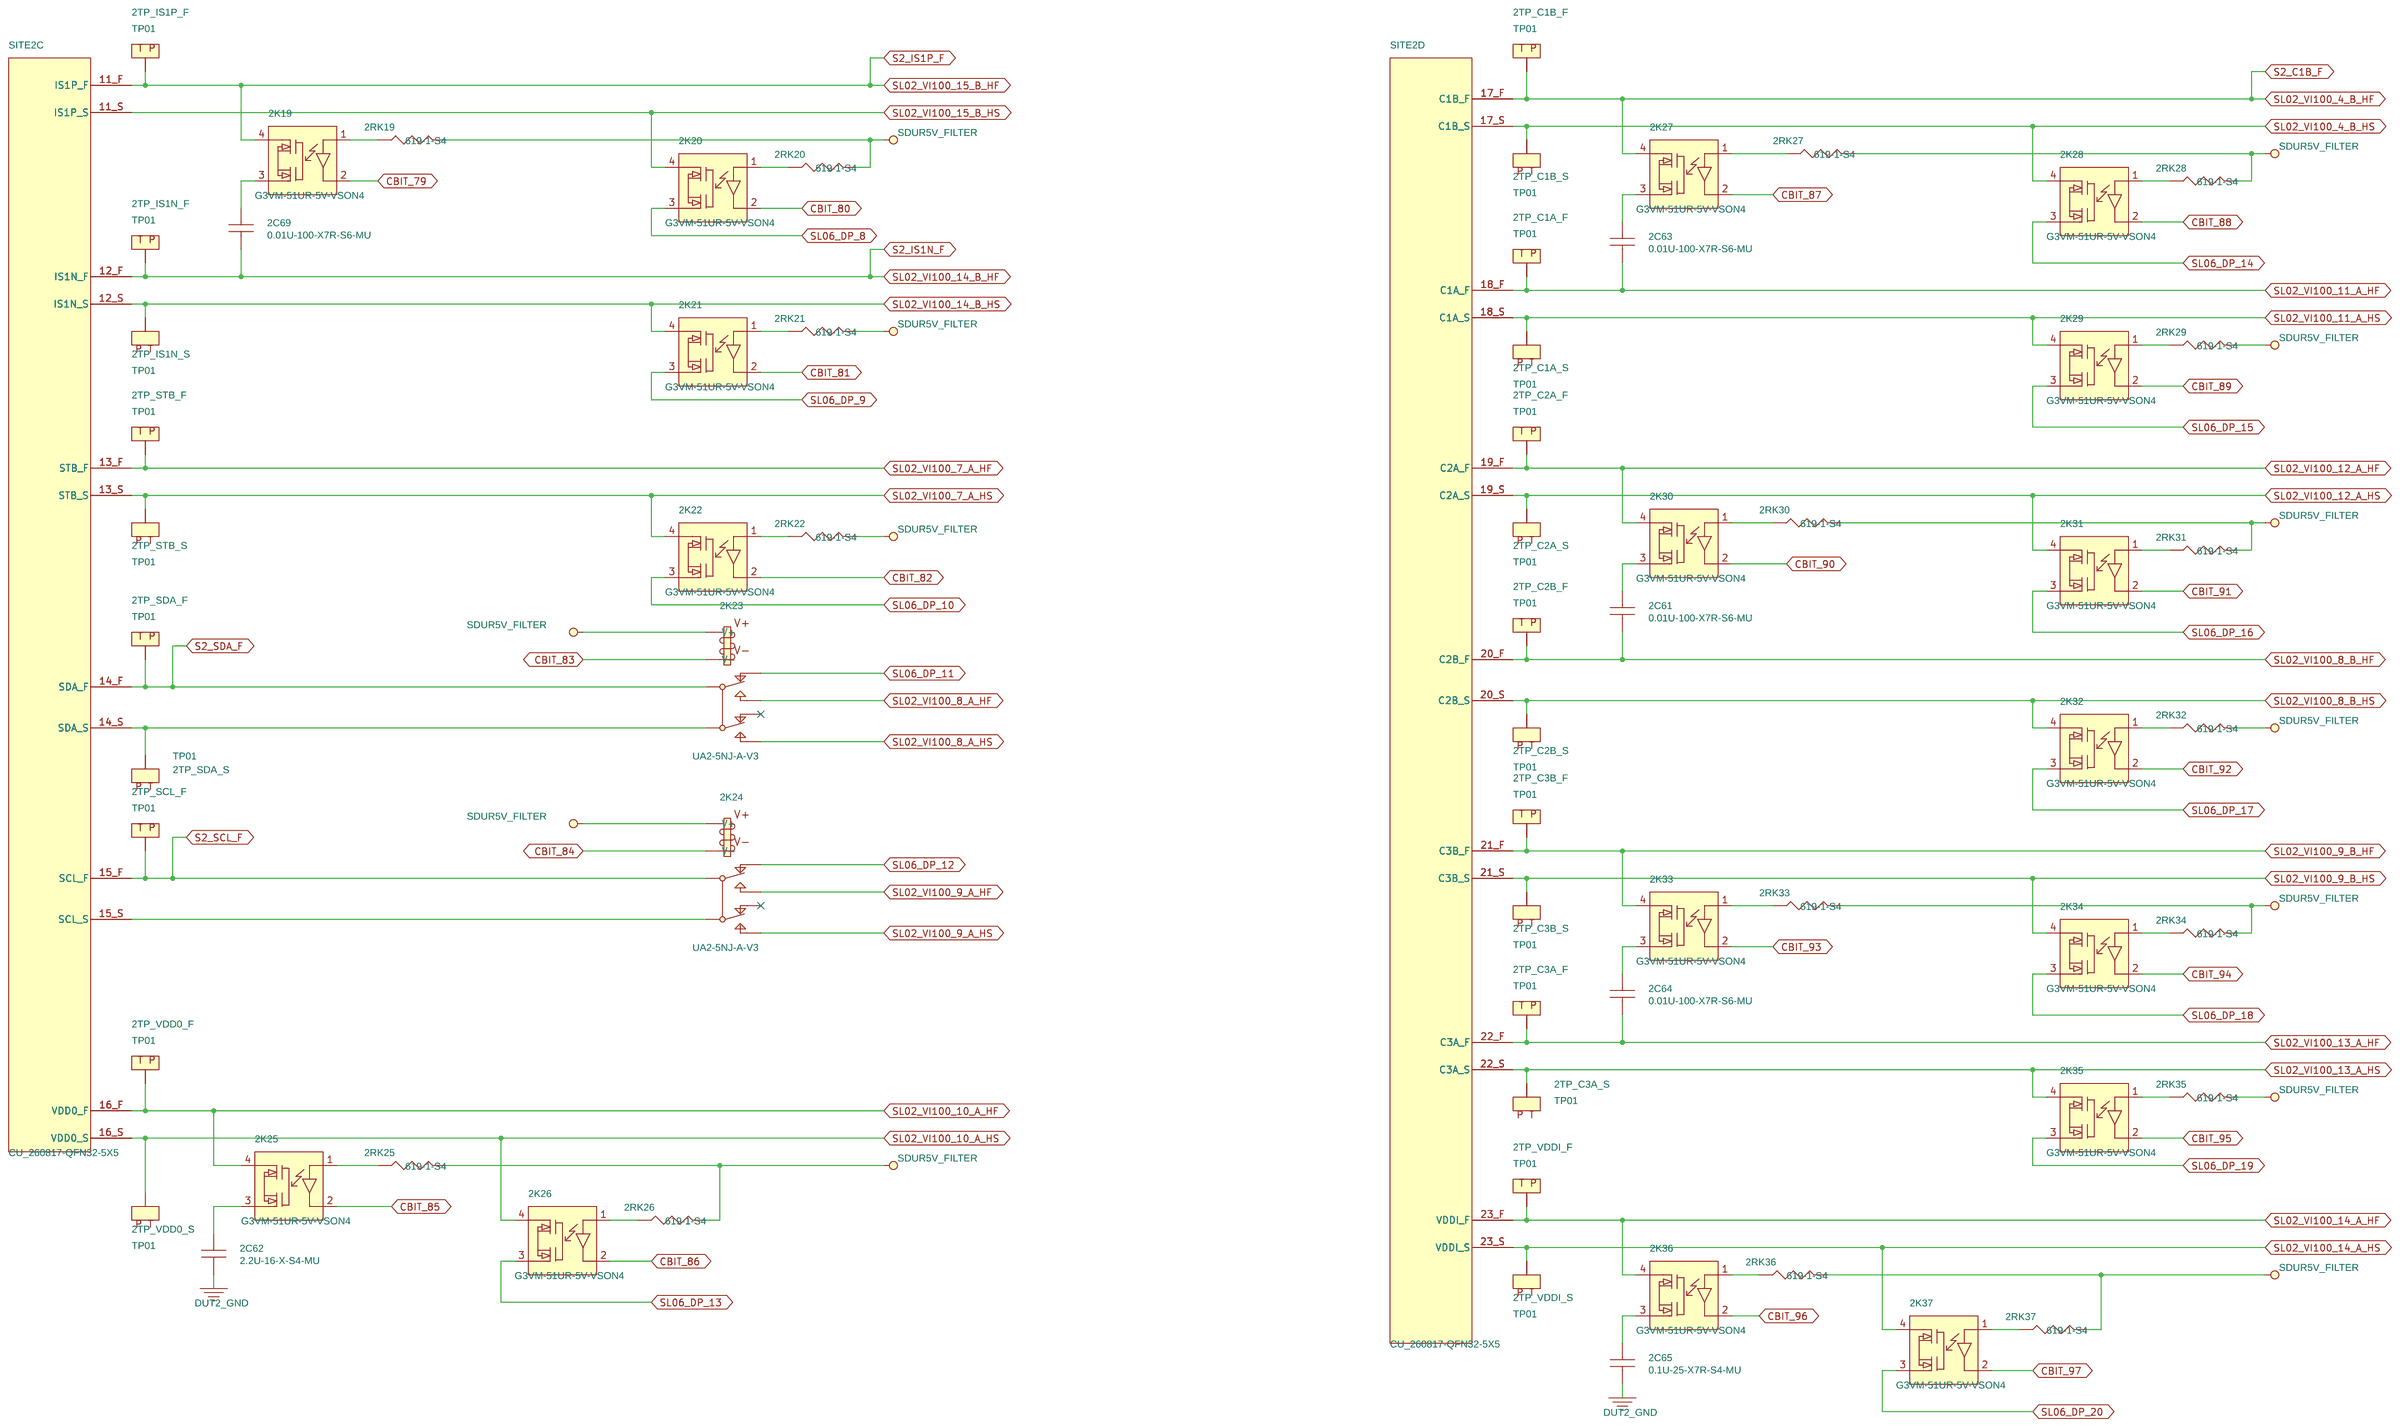
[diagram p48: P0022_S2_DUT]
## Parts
sheet P0022_S2_DUT
2C61  0.01U-100-X7R-S6-MU  [C0603]
2C62  2.2U-16-X-S4-MU  [C0402]
2C63  0.01U-100-X7R-S6-MU  [C0603]
2C64  0.01U-100-X7R-S6-MU  [C0603]
2C65  0.1U-25-X7R-S4-MU  [C0402]
2C69  0.01U-100-X7R-S6-MU  [C0603]
2K19  G3VM-51UR-5V-VSON4  [RL_G3VM_4P_VSON4]
2K20  G3VM-51UR-5V-VSON4  [RL_G3VM_4P_VSON4]
2K21  G3VM-51UR-5V-VSON4  [RL_G3VM_4P_VSON4]
2K22  G3VM-51UR-5V-VSON4  [RL_G3VM_4P_VSON4]
2K23  UA2-5NJ-A-V3  [RL_NECUA2_5V_V3]
2K24  UA2-5NJ-A-V3  [RL_NECUA2_5V_V3]
2K25  G3VM-51UR-5V-VSON4  [RL_G3VM_4P_VSON4]
2K26  G3VM-51UR-5V-VSON4  [RL_G3VM_4P_VSON4]
2K27  G3VM-51UR-5V-VSON4  [RL_G3VM_4P_VSON4]
2K28  G3VM-51UR-5V-VSON4  [RL_G3VM_4P_VSON4]
2K29  G3VM-51UR-5V-VSON4  [RL_G3VM_4P_VSON4]
2K30  G3VM-51UR-5V-VSON4  [RL_G3VM_4P_VSON4]
2K31  G3VM-51UR-5V-VSON4  [RL_G3VM_4P_VSON4]
2K32  G3VM-51UR-5V-VSON4  [RL_G3VM_4P_VSON4]
2K33  G3VM-51UR-5V-VSON4  [RL_G3VM_4P_VSON4]
2K34  G3VM-51UR-5V-VSON4  [RL_G3VM_4P_VSON4]
2K35  G3VM-51UR-5V-VSON4  [RL_G3VM_4P_VSON4]
2K36  G3VM-51UR-5V-VSON4  [RL_G3VM_4P_VSON4]
2K37  G3VM-51UR-5V-VSON4  [RL_G3VM_4P_VSON4]
2RK19  619-1-S4  [R0402]
2RK20  619-1-S4  [R0402]
2RK21  619-1-S4  [R0402]
2RK22  619-1-S4  [R0402]
2RK25  619-1-S4  [R0402]
2RK26  619-1-S4  [R0402]
2RK27  619-1-S4  [R0402]
2RK28  619-1-S4  [R0402]
2RK29  619-1-S4  [R0402]
2RK30  619-1-S4  [R0402]
2RK31  619-1-S4  [R0402]
2RK32  619-1-S4  [R0402]
2RK33  619-1-S4  [R0402]
2RK34  619-1-S4  [R0402]
2RK35  619-1-S4  [R0402]
2RK36  619-1-S4  [R0402]
2RK37  619-1-S4  [R0402]
2TP_C1A_F  TP01  [TP_040_T]
2TP_C1A_S  TP01  [TP_040_T]
2TP_C1B_F  TP01  [TP_040_T]
2TP_C1B_S  TP01  [TP_040_T]
2TP_C2A_F  TP01  [TP_040_T]
2TP_C2A_S  TP01  [TP_040_T]
2TP_C2B_F  TP01  [TP_040_T]
2TP_C2B_S  TP01  [TP_040_T]
2TP_C3A_F  TP01  [TP_040_T]
2TP_C3A_S  TP01  [TP_040_T]
2TP_C3B_F  TP01  [TP_040_T]
2TP_C3B_S  TP01  [TP_040_T]
2TP_IS1N_F  TP01  [TP_040_T]
2TP_IS1N_S  TP01  [TP_040_T]
2TP_IS1P_F  TP01  [TP_040_T]
2TP_SCL_F  TP01  [TP_040_T]
2TP_SDA_F  TP01  [TP_040_T]
2TP_SDA_S  TP01  [TP_040_T]
2TP_STB_F  TP01  [TP_040_T]
2TP_STB_S  TP01  [TP_040_T]
2TP_VDD0_F  TP01  [TP_040_T]
2TP_VDD0_S  TP01  [TP_040_T]
2TP_VDDI_F  TP01  [TP_040_T]
2TP_VDDI_S  TP01  [TP_040_T]
SITE2  CU_260817-QFN32-5X5  [SK_QFN5x5_64P_0P5MM_JG_260817]  (sections A,B,C,D,E,F,G,H)
sheet P0023_S2_DUT
2C66  0.1U-25-X7R-S4-MU  [C0402]
2C67  0.1U-25-X7R-S4-MU  [C0402]
2C68  0.1U-25-X7R-S4-MU  [C0402]
2C74  0.1U-25-X7R-S4-MU  [C0402]
2K38  G3VM-51UR-5V-VSON4  [RL_G3VM_4P_VSON4]
2K39  G3VM-51UR-5V-VSON4  [RL_G3VM_4P_VSON4]
2K40  G3VM-51UR-5V-VSON4  [RL_G3VM_4P_VSON4]
2K41  G3VM-51UR-5V-VSON4  [RL_G3VM_4P_VSON4]
2K42  G3VM-51UR-5V-VSON4  [RL_G3VM_4P_VSON4]
2K43  G3VM-51UR-5V-VSON4  [RL_G3VM_4P_VSON4]
2K44  G3VM-51UR-5V-VSON4  [RL_G3VM_4P_VSON4]
2K45  G3VM-51UR-5V-VSON4  [RL_G3VM_4P_VSON4]
2K46  G3VM-51UR-5V-VSON4  [RL_G3VM_4P_VSON4]
2K47  G3VM-51UR-5V-VSON4  [RL_G3VM_4P_VSON4]
2K48  G3VM-51UR-5V-VSON4  [RL_G3VM_4P_VSON4]
2K49  G3VM-51UR-5V-VSON4  [RL_G3VM_4P_VSON4]
2K50  G3VM-51UR-5V-VSON4  [RL_G3VM_4P_VSON4]
2R43  0-5-S6  [R0603]
2R44  0-5-S6  [R0603]
2RK38  619-1-S4  [R0402]
2RK39  619-1-S4  [R0402]
2RK40  619-1-S4  [R0402]
2RK41  619-1-S4  [R0402]
2RK42  619-1-S4  [R0402]
2RK43  619-1-S4  [R0402]
2RK44  619-1-S4  [R0402]
2RK45  619-1-S4  [R0402]
2RK46  619-1-S4  [R0402]
2RK47  619-1-S4  [R0402]
2RK48  619-1-S4  [R0402]
2RK49  619-1-S4  [R0402]
2RK50  619-1-S4  [R0402]
2TP_GA1_S  TP01  [TP_040_T]
2TP_GA2_S  TP01  [TP_040_T]
2TP_GB1_S  TP01  [TP_040_T]
2TP_GB2_S  TP01  [TP_040_T]
2TP_VDD1_S  TP01  [TP_040_T]
2TP_VDD2_S  TP01  [TP_040_T]
2TP_VIN_F  TP01  [TP_040_T]
2TP_VIN_S  TP01  [TP_040_T]
2TP_VO1_S  TP01  [TP_040_T]
2TP_VO2_S  TP01  [TP_040_T]
sheet P0024_S2_DUT
2C70  0.1U-25-X7R-S4-MU  [C0402]
2C71  0.1U-25-X7R-S4-MU  [C0402]
2C72  0.1U-25-X7R-S4-MU  [C0402]
2C73  0.1U-25-X7R-S4-MU  [C0402]
2K51  G3VM-51UR-5V-VSON4  [RL_G3VM_4P_VSON4]
2K52  G3VM-51UR-5V-VSON4  [RL_G3VM_4P_VSON4]
2K53  G3VM-51UR-5V-VSON4  [RL_G3VM_4P_VSON4]
2K54  G3VM-51UR-5V-VSON4  [RL_G3VM_4P_VSON4]
2K55  G3VM-51UR-5V-VSON4  [RL_G3VM_4P_VSON4]
2K56  G3VM-201DR  [RL_G3VM201DR_200V]
2K57  G3VM-51UR-5V-VSON4  [RL_G3VM_4P_VSON4]
2K58  G3VM-51UR-5V-VSON4  [RL_G3VM_4P_VSON4]
2K59  G3VM-51UR-5V-VSON4  [RL_G3VM_4P_VSON4]
2K60  G3VM-51UR-5V-VSON4  [RL_G3VM_4P_VSON4]
2K61  G3VM-51UR-5V-VSON4  [RL_G3VM_4P_VSON4]
2R7  4.7K-1-S4-WA  [R0402]
2R8  4.7K-1-S4-WA  [R0402]
2R11  5K-1-S4-YA  [R0402]
2R14  5K-1-S4-YA  [R0402]
2R15  0-0-S2-KOA  [R0201]
2R16  5.1-1-S2  [R0201]
2R17  0-0-S2-KOA  [R0201]
2R18  5.1-1-S2  [R0201]
2R19  100K-0.1-S4-YA  [R0402]
2R20  100K-0.1-S4-YA  [R0402]
2RK51  619-1-S4  [R0402]
2RK52  619-1-S4  [R0402]
2RK53  619-1-S4  [R0402]
2RK54  619-1-S4  [R0402]
2RK55  619-1-S4  [R0402]
2RK56  619-1-S4  [R0402]
2RK57  619-1-S4  [R0402]
2RK58  619-1-S4  [R0402]
2RK59  619-1-S4  [R0402]
2RK60  619-1-S4  [R0402]
2RK61  619-1-S4  [R0402]
2SH1  SHORT  [DEFAULT_SHORT_SMALL]
2SH2  SHORT  [DEFAULT_SHORT_SMALL]
2SH3  SHORT  [DEFAULT_SHORT_SMALL]
2SH4  SHORT  [DEFAULT_SHORT_SMALL]
2SH5  SHORT  [DEFAULT_SHORT_SMALL]
2SH6  SHORT  [DEFAULT_SHORT_SMALL]
2SH7  SHORT  [DEFAULT_SHORT_SMALL]
2SH8  SHORT  [DEFAULT_SHORT_SMALL]
2SH9  SHORT  [DEFAULT_SHORT_SMALL]
2SH10  SHORT  [DEFAULT_SHORT_SMALL]
2SH11  SHORT  [DEFAULT_SHORT_SMALL]
2SH12  SHORT  [DEFAULT_SHORT_SMALL]
2SH13  SHORT  [DEFAULT_SHORT_SMALL]
2SH14  SHORT  [DEFAULT_SHORT_SMALL]
2SH15  SHORT  [DEFAULT_SHORT_SMALL]
2SH16  SHORT  [DEFAULT_SHORT_SMALL]
2SH17  SHORT  [DEFAULT_SHORT_SMALL]
2SH18  SHORT  [DEFAULT_SHORT_SMALL]
2SH19  SHORT  [DEFAULT_SHORT_SMALL]
2SH20  SHORT  [DEFAULT_SHORT_SMALL]
2SH21  SHORT  [DEFAULT_SHORT_SMALL]
2SH22  SHORT  [DEFAULT_SHORT_SMALL]
2SH23  SHORT  [DEFAULT_SHORT_SMALL]
2SH24  SHORT  [DEFAULT_SHORT_SMALL]
2SH25  SHORT  [DEFAULT_SHORT_SMALL]
2SH26  SHORT  [DEFAULT_SHORT_SMALL]
2SH27  SHORT  [DEFAULT_SHORT_SMALL]
2SHORT1  SHORT  [DEFAULT_SHORT_SMALL]
2SHORT2  SHORT  [DEFAULT_SHORT_SMALL]
2SHORT3  SHORT  [DEFAULT_SHORT_SMALL]
2SHORT4  SHORT  [DEFAULT_SHORT_SMALL]
2SHORT6  SHORT  [DEFAULT_SHORT_SMALL]
2SHORT7  SHORT  [DEFAULT_SHORT_SMALL]
2SHORT8  SHORT  [DEFAULT_SHORT_SMALL]
2SHORT9  SHORT  [DEFAULT_SHORT_SMALL]
2SHORT10  SHORT  [DEFAULT_SHORT_SMALL]
2SHORT11  SHORT  [DEFAULT_SHORT_SMALL]
2TP_IN+_1  TP01  [TP_040_T]
2TP_IN+_2  TP01  [TP_040_T]
2TP_IN+_3  TP01  [TP_040_T]
2TP_IN+_4  TP01  [TP_040_T]
2TP_IN-_1  TP01  [TP_040_T]
2TP_IN-_2  TP01  [TP_040_T]
2TP_IN-_3  TP01  [TP_040_T]
2TP_IN-_4  TP01  [TP_040_T]
2TP_OUT+_1  TP01  [TP_040_T]
2TP_OUT+_2  TP01  [TP_040_T]
2TP_OUT-_1  TP01  [TP_040_T]
2TP_OUT-_2  TP01  [TP_040_T]
2TP_OUT_1  TP01  [TP_040_T]
2TP_OUT_2  TP01  [TP_040_T]
2TP_REF_1  TP01  [TP_040_T]
2TP_REF_2  TP01  [TP_040_T]
2U1  TLV3604DCKR-SC70  [SC70]
2U2  TLV3604DCKR-SC70  [SC70]
2U3  INA186A3QDDFRQ1-SOT23-8  [SOT23_8P_0P65MM_H1P3MM]
2U4  INA186A3QDDFRQ1-SOT23-8  [SOT23_8P_0P65MM_H1P3MM]
sheet P0031_S3_DUT
3C48  0.01U-100-X7R-S6-MU  [C0603]
3C49  0.01U-100-X7R-S6-MU  [C0603]
3C50  0.01U-100-X7R-S6-MU  [C0603]
3C53  1U-16-X5R-S4-YA  [C0402]
3C54  2.2U-16-X-S4-MU  [C0402]
3C58  1U-16-X5R-S4-YA  [C0402]
3C59  4.7U-100-X-SB-MU  [C1210]
3C60  0.01U-100-X7R-S6-MU  [C0603]
3K1  UA2-5NJ-A-V3  [RL_NECUA2_5V_V3]
3K2  G3VM-201DR  [RL_G3VM201DR_200V]
3K3  G3VM-201DR  [RL_G3VM201DR_200V]
3K4  G3VM-201DR  [RL_G3VM201DR_200V]
3K5  G3VM-51UR-5V-VSON4  [RL_G3VM_4P_VSON4]
3K6  G3VM-51UR-5V-VSON4  [RL_G3VM_4P_VSON4]
3K7  G3VM-51UR-5V-VSON4  [RL_G3VM_4P_VSON4]
3K8  G3VM-51UR-5V-VSON4  [RL_G3VM_4P_VSON4]
3K9  G3VM-51UR-5V-VSON4  [RL_G3VM_4P_VSON4]
3K10  G3VM-51UR-5V-VSON4  [RL_G3VM_4P_VSON4]
3K11  G3VM-51UR-5V-VSON4  [RL_G3VM_4P_VSON4]
3K12  G3VM-51UR-5V-VSON4  [RL_G3VM_4P_VSON4]
3K13  G3VM-51UR-5V-VSON4  [RL_G3VM_4P_VSON4]
3K14  G3VM-51UR-5V-VSON4  [RL_G3VM_4P_VSON4]
3K15  UA2-5NJ-A-V3  [RL_NECUA2_5V_V3]
3K16  G3VM-51UR-5V-VSON4  [RL_G3VM_4P_VSON4]
3K17  G3VM-51UR-5V-VSON4  [RL_G3VM_4P_VSON4]
3K18  G3VM-51UR-5V-VSON4  [RL_G3VM_4P_VSON4]
3R1  10K-0.1-S4  [R0402]
3RK2  619-1-S4  [R0402]
3RK3  619-1-S4  [R0402]
3RK4  619-1-S4  [R0402]
3RK5  619-1-S4  [R0402]
3RK6  619-1-S4  [R0402]
3RK7  619-1-S4  [R0402]
3RK8  619-1-S4  [R0402]
3RK9  619-1-S4  [R0402]
3RK10  619-1-S4  [R0402]
3RK11  619-1-S4  [R0402]
3RK12  619-1-S4  [R0402]
3RK13  619-1-S4  [R0402]
3RK14  619-1-S4  [R0402]
3RK16  619-1-S4  [R0402]
3RK17  619-1-S4  [R0402]
3RK18  619-1-S4  [R0402]
3TP_ATT_F  TP01  [TP_040_T]
3TP_ATT_S  TP01  [TP_040_T]
3TP_IS2N_F  TP01  [TP_040_T]
3TP_IS2N_S  TP01  [TP_040_T]
3TP_IS2P_S  TP01  [TP_040_T]
3TP_OPTO_F  TP01  [TP_040_T]
3TP_OPTO_S  TP01  [TP_040_T]
3TP_SRD_F  TP01  [TP_040_T]
3TP_SRD_S  TP01  [TP_040_T]
3TP_SRG_F  TP01  [TP_040_T]
3TP_SRG_S  TP01  [TP_040_T]
3TP_SRS_F  TP01  [TP_040_T]
3TP_SRS_S  TP01  [TP_040_T]
3TP_VCC_F  TP01  [TP_040_T]
3TP_VCC_S  TP01  [TP_040_T]
3TP_VSR_F  TP01  [TP_040_T]
3TP_VSR_S  TP01  [TP_040_T]
sheet P0032_S3_DUT
3C61  0.01U-100-X7R-S6-MU  [C0603]
3C62  2.2U-16-X-S4-MU  [C0402]
3C63  0.01U-100-X7R-S6-MU  [C0603]
3C64  0.01U-100-X7R-S6-MU  [C0603]
3C65  0.1U-25-X7R-S4-MU  [C0402]
3C69  0.01U-100-X7R-S6-MU  [C0603]
3K19  G3VM-51UR-5V-VSON4  [RL_G3VM_4P_VSON4]
3K20  G3VM-51UR-5V-VSON4  [RL_G3VM_4P_VSON4]
3K21  G3VM-51UR-5V-VSON4  [RL_G3VM_4P_VSON4]
3K22  G3VM-51UR-5V-VSON4  [RL_G3VM_4P_VSON4]
3K23  UA2-5NJ-A-V3  [RL_NECUA2_5V_V3]
3K24  UA2-5NJ-A-V3  [RL_NECUA2_5V_V3]
3K25  G3VM-51UR-5V-VSON4  [RL_G3VM_4P_VSON4]
3K26  G3VM-51UR-5V-VSON4  [RL_G3VM_4P_VSON4]
3K27  G3VM-51UR-5V-VSON4  [RL_G3VM_4P_VSON4]
3K28  G3VM-51UR-5V-VSON4  [RL_G3VM_4P_VSON4]
3K29  G3VM-51UR-5V-VSON4  [RL_G3VM_4P_VSON4]
3K30  G3VM-51UR-5V-VSON4  [RL_G3VM_4P_VSON4]
3K31  G3VM-51UR-5V-VSON4  [RL_G3VM_4P_VSON4]
3K32  G3VM-51UR-5V-VSON4  [RL_G3VM_4P_VSON4]
3K33  G3VM-51UR-5V-VSON4  [RL_G3VM_4P_VSON4]
3K34  G3VM-51UR-5V-VSON4  [RL_G3VM_4P_VSON4]
3K35  G3VM-51UR-5V-VSON4  [RL_G3VM_4P_VSON4]
3K36  G3VM-51UR-5V-VSON4  [RL_G3VM_4P_VSON4]
3K37  G3VM-51UR-5V-VSON4  [RL_G3VM_4P_VSON4]
3RK19  619-1-S4  [R0402]
3RK20  619-1-S4  [R0402]
3RK21  619-1-S4  [R0402]
3RK22  619-1-S4  [R0402]
3RK25  619-1-S4  [R0402]
3RK26  619-1-S4  [R0402]
3RK27  619-1-S4  [R0402]
3RK28  619-1-S4  [R0402]
3RK29  619-1-S4  [R0402]
3RK30  619-1-S4  [R0402]
3RK31  619-1-S4  [R0402]
3RK32  619-1-S4  [R0402]
3RK33  619-1-S4  [R0402]
3RK34  619-1-S4  [R0402]
3RK35  619-1-S4  [R0402]
3RK36  619-1-S4  [R0402]
3RK37  619-1-S4  [R0402]
3TP_C1A_F  TP01  [TP_040_T]
3TP_C1A_S  TP01  [TP_040_T]
3TP_C1B_F  TP01  [TP_040_T]
3TP_C1B_S  TP01  [TP_040_T]
3TP_C2A_F  TP01  [TP_040_T]
3TP_C2A_S  TP01  [TP_040_T]
3TP_C2B_F  TP01  [TP_040_T]
3TP_C2B_S  TP01  [TP_040_T]
3TP_C3A_F  TP01  [TP_040_T]
3TP_C3A_S  TP01  [TP_040_T]
3TP_C3B_F  TP01  [TP_040_T]
3TP_C3B_S  TP01  [TP_040_T]
3TP_IS1N_F  TP01  [TP_040_T]
3TP_IS1N_S  TP01  [TP_040_T]
3TP_IS1P_F  TP01  [TP_040_T]
3TP_SCL_F  TP01  [TP_040_T]
3TP_SDA_F  TP01  [TP_040_T]
3TP_SDA_S  TP01  [TP_040_T]
3TP_STB_F  TP01  [TP_040_T]
3TP_STB_S  TP01  [TP_040_T]
3TP_VDD0_F  TP01  [TP_040_T]
3TP_VDD0_S  TP01  [TP_040_T]
3TP_VDDI_F  TP01  [TP_040_T]
3TP_VDDI_S  TP01  [TP_040_T]
SITE3  CU_260817-QFN32-5X5  [SK_QFN5x5_64P_0P5MM_JG_260817]  (sections A,B,C,D,E,F,G,H)
sheet P0033_S3_DUT
3C66  0.1U-25-X7R-S4-MU  [C0402]
3C67  0.1U-25-X7R-S4-MU  [C0402]
3C68  0.1U-25-X7R-S4-MU  [C0402]
3C74  0.1U-25-X7R-S4-MU  [C0402]
3K38  G3VM-51UR-5V-VSON4  [RL_G3VM_4P_VSON4]
3K39  G3VM-51UR-5V-VSON4  [RL_G3VM_4P_VSON4]
3K40  G3VM-51UR-5V-VSON4  [RL_G3VM_4P_VSON4]
3K41  G3VM-51UR-5V-VSON4  [RL_G3VM_4P_VSON4]
3K42  G3VM-51UR-5V-VSON4  [RL_G3VM_4P_VSON4]
3K43  G3VM-51UR-5V-VSON4  [RL_G3VM_4P_VSON4]
3K44  G3VM-51UR-5V-VSON4  [RL_G3VM_4P_VSON4]
3K45  G3VM-51UR-5V-VSON4  [RL_G3VM_4P_VSON4]
3K46  G3VM-51UR-5V-VSON4  [RL_G3VM_4P_VSON4]
3K47  G3VM-51UR-5V-VSON4  [RL_G3VM_4P_VSON4]
3K48  G3VM-51UR-5V-VSON4  [RL_G3VM_4P_VSON4]
3K49  G3VM-51UR-5V-VSON4  [RL_G3VM_4P_VSON4]
3K50  G3VM-51UR-5V-VSON4  [RL_G3VM_4P_VSON4]
3R41  0-5-S6  [R0603]
3R42  0-5-S6  [R0603]
3RK38  619-1-S4  [R0402]
3RK39  619-1-S4  [R0402]
3RK40  619-1-S4  [R0402]
3RK41  619-1-S4  [R0402]
3RK42  619-1-S4  [R0402]
3RK43  619-1-S4  [R0402]
3RK44  619-1-S4  [R0402]
3RK45  619-1-S4  [R0402]
3RK46  619-1-S4  [R0402]
3RK47  619-1-S4  [R0402]
3RK48  619-1-S4  [R0402]
3RK49  619-1-S4  [R0402]
3RK50  619-1-S4  [R0402]
3TP_GA1_S  TP01  [TP_040_T]
3TP_GA2_S  TP01  [TP_040_T]
3TP_GB1_S  TP01  [TP_040_T]
3TP_GB2_S  TP01  [TP_040_T]
3TP_VDD1_S  TP01  [TP_040_T]
3TP_VDD2_S  TP01  [TP_040_T]
3TP_VIN_F  TP01  [TP_040_T]
3TP_VIN_S  TP01  [TP_040_T]
3TP_VO1_S  TP01  [TP_040_T]
3TP_VO2_S  TP01  [TP_040_T]
sheet P0034_S3_DUT
3C70  0.1U-25-X7R-S4-MU  [C0402]
3C71  0.1U-25-X7R-S4-MU  [C0402]
3C72  0.1U-25-X7R-S4-MU  [C0402]
3C73  0.1U-25-X7R-S4-MU  [C0402]
3K51  G3VM-51UR-5V-VSON4  [RL_G3VM_4P_VSON4]
3K52  G3VM-51UR-5V-VSON4  [RL_G3VM_4P_VSON4]
3K53  G3VM-51UR-5V-VSON4  [RL_G3VM_4P_VSON4]
3K54  G3VM-51UR-5V-VSON4  [RL_G3VM_4P_VSON4]
3K55  G3VM-51UR-5V-VSON4  [RL_G3VM_4P_VSON4]
3K56  G3VM-201DR  [RL_G3VM201DR_200V]
3K57  G3VM-51UR-5V-VSON4  [RL_G3VM_4P_VSON4]
3K58  G3VM-51UR-5V-VSON4  [RL_G3VM_4P_VSON4]
3K59  G3VM-51UR-5V-VSON4  [RL_G3VM_4P_VSON4]
3K60  G3VM-51UR-5V-VSON4  [RL_G3VM_4P_VSON4]
3K61  G3VM-51UR-5V-VSON4  [RL_G3VM_4P_VSON4]
3R7  4.7K-1-S4-WA  [R0402]
3R8  4.7K-1-S4-WA  [R0402]
3R11  5K-1-S4-YA  [R0402]
3R14  5K-1-S4-YA  [R0402]
3R15  0-0-S2-KOA  [R0201]
3R16  5.1-1-S2  [R0201]
3R17  0-0-S2-KOA  [R0201]
3R18  5.1-1-S2  [R0201]
3R19  100K-0.1-S4-YA  [R0402]
3R20  100K-0.1-S4-YA  [R0402]
3RK51  619-1-S4  [R0402]
3RK52  619-1-S4  [R0402]
3RK53  619-1-S4  [R0402]
3RK54  619-1-S4  [R0402]
3RK55  619-1-S4  [R0402]
3RK56  619-1-S4  [R0402]
3RK57  619-1-S4  [R0402]
3RK58  619-1-S4  [R0402]
3RK59  619-1-S4  [R0402]
3RK60  619-1-S4  [R0402]
3RK61  619-1-S4  [R0402]
3SH1  SHORT  [DEFAULT_SHORT_SMALL]
3SH2  SHORT  [DEFAULT_SHORT_SMALL]
3SH3  SHORT  [DEFAULT_SHORT_SMALL]
3SH4  SHORT  [DEFAULT_SHORT_SMALL]
3SH5  SHORT  [DEFAULT_SHORT_SMALL]
3SH6  SHORT  [DEFAULT_SHORT_SMALL]
3SH7  SHORT  [DEFAULT_SHORT_SMALL]
3SH8  SHORT  [DEFAULT_SHORT_SMALL]
3SH9  SHORT  [DEFAULT_SHORT_SMALL]
3SH10  SHORT  [DEFAULT_SHORT_SMALL]
3SH11  SHORT  [DEFAULT_SHORT_SMALL]
3SH12  SHORT  [DEFAULT_SHORT_SMALL]
3SH13  SHORT  [DEFAULT_SHORT_SMALL]
3SH14  SHORT  [DEFAULT_SHORT_SMALL]
3SH15  SHORT  [DEFAULT_SHORT_SMALL]
3SH16  SHORT  [DEFAULT_SHORT_SMALL]
3SH17  SHORT  [DEFAULT_SHORT_SMALL]
3SH18  SHORT  [DEFAULT_SHORT_SMALL]
3SH19  SHORT  [DEFAULT_SHORT_SMALL]
3SH20  SHORT  [DEFAULT_SHORT_SMALL]
3SH21  SHORT  [DEFAULT_SHORT_SMALL]
3SH22  SHORT  [DEFAULT_SHORT_SMALL]
3SH23  SHORT  [DEFAULT_SHORT_SMALL]
3SH24  SHORT  [DEFAULT_SHORT_SMALL]
3SH25  SHORT  [DEFAULT_SHORT_SMALL]
3SH26  SHORT  [DEFAULT_SHORT_SMALL]
3SH27  SHORT  [DEFAULT_SHORT_SMALL]
3SHORT1  SHORT  [DEFAULT_SHORT_SMALL]
3SHORT2  SHORT  [DEFAULT_SHORT_SMALL]
3SHORT3  SHORT  [DEFAULT_SHORT_SMALL]
3SHORT4  SHORT  [DEFAULT_SHORT_SMALL]
3SHORT6  SHORT  [DEFAULT_SHORT_SMALL]
3SHORT7  SHORT  [DEFAULT_SHORT_SMALL]
3SHORT8  SHORT  [DEFAULT_SHORT_SMALL]
3SHORT9  SHORT  [DEFAULT_SHORT_SMALL]
3SHORT10  SHORT  [DEFAULT_SHORT_SMALL]
3SHORT11  SHORT  [DEFAULT_SHORT_SMALL]
3TP_IN+_1  TP01  [TP_040_T]
3TP_IN+_2  TP01  [TP_040_T]
3TP_IN+_3  TP01  [TP_040_T]
3TP_IN+_4  TP01  [TP_040_T]
3TP_IN-_1  TP01  [TP_040_T]
3TP_IN-_2  TP01  [TP_040_T]
3TP_IN-_3  TP01  [TP_040_T]
3TP_IN-_4  TP01  [TP_040_T]
3TP_OUT+_1  TP01  [TP_040_T]
3TP_OUT+_2  TP01  [TP_040_T]
3TP_OUT-_1  TP01  [TP_040_T]
3TP_OUT-_2  TP01  [TP_040_T]
3TP_OUT_1  TP01  [TP_040_T]
3TP_OUT_2  TP01  [TP_040_T]
3TP_REF_1  TP01  [TP_040_T]
3TP_REF_2  TP01  [TP_040_T]
3U1  TLV3604DCKR-SC70  [SC70]
3U2  TLV3604DCKR-SC70  [SC70]
3U3  INA186A3QDDFRQ1-SOT23-8  [SOT23_8P_0P65MM_H1P3MM]
3U4  INA186A3QDDFRQ1-SOT23-8  [SOT23_8P_0P65MM_H1P3MM]

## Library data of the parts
2C61 2C63 2C64 2C69 3C48-3C50 3C60 3C61 3C63 3C64 3C69 = 0.01U-100-X7R-S6-MU
2C62 3C54 3C62 = 2.2U-16-X-S4-MU
2C65-2C68 2C70-2C74 3C65-3C68 3C70-3C74 = 0.1U-25-X7R-S4-MU
2K19-2K22 2K25-2K55 2K57-2K61 3K5-3K14 3K16-3K22 3K25-3K55 3K57-3K61 = G3VM-51UR-5V-VSON4
2K23 2K24 3K1 3K15 3K23 3K24 = UA2-5NJ-A-V3
2RK19-2RK22 2RK25-2RK61 3RK2-3RK14 3RK16-3RK22 3RK25-3RK61 = 619-1-S4
2TP_C1A_F 2TP_C1A_S 2TP_C1B_F 2TP_C1B_S 2TP_C2A_F 2TP_C2A_S 2TP_C2B_F 2TP_C2B_S 2TP_C3A_F 2TP_C3A_S 2TP_C3B_F 2TP_C3B_S 2TP_GA1_S 2TP_GA2_S 2TP_GB1_S 2TP_GB2_S 2TP_IN+_1-2TP_IN+_4 2TP_IN-_1-2TP_IN-_4 2TP_IS1N_F 2TP_IS1N_S 2TP_IS1P_F 2TP_OUT+_1 2TP_OUT+_2 2TP_OUT-_1 2TP_OUT-_2 2TP_OUT_1 2TP_OUT_2 2TP_REF_1 2TP_REF_2 2TP_SCL_F 2TP_SDA_F 2TP_SDA_S 2TP_STB_F 2TP_STB_S 2TP_VDD0_F 2TP_VDD0_S 2TP_VDD1_S 2TP_VDD2_S 2TP_VDDI_F 2TP_VDDI_S 2TP_VIN_F 2TP_VIN_S 2TP_VO1_S 2TP_VO2_S 3TP_ATT_F 3TP_ATT_S 3TP_C1A_F 3TP_C1A_S 3TP_C1B_F 3TP_C1B_S 3TP_C2A_F 3TP_C2A_S 3TP_C2B_F 3TP_C2B_S 3TP_C3A_F 3TP_C3A_S 3TP_C3B_F 3TP_C3B_S 3TP_GA1_S 3TP_GA2_S 3TP_GB1_S 3TP_GB2_S 3TP_IN+_1-3TP_IN+_4 3TP_IN-_1-3TP_IN-_4 3TP_IS1N_F 3TP_IS1N_S 3TP_IS1P_F 3TP_IS2N_F 3TP_IS2N_S 3TP_IS2P_S 3TP_OPTO_F 3TP_OPTO_S 3TP_OUT+_1 3TP_OUT+_2 3TP_OUT-_1 3TP_OUT-_2 3TP_OUT_1 3TP_OUT_2 3TP_REF_1 3TP_REF_2 3TP_SCL_F 3TP_SDA_F 3TP_SDA_S 3TP_SRD_F 3TP_SRD_S 3TP_SRG_F 3TP_SRG_S 3TP_SRS_F 3TP_SRS_S 3TP_STB_F 3TP_STB_S 3TP_VCC_F 3TP_VCC_S 3TP_VDD0_F 3TP_VDD0_S 3TP_VDD1_S 3TP_VDD2_S 3TP_VDDI_F 3TP_VDDI_S 3TP_VIN_F 3TP_VIN_S 3TP_VO1_S 3TP_VO2_S 3TP_VSR_F 3TP_VSR_S = TP01_v2
SITE2 SITE3 = CU_260817-QFN32-5X5
2R43 2R44 3R41 3R42 = 0-5-S6
2K56 3K2-3K4 3K56 = G3VM-201DR
2R7 2R8 3R7 3R8 = 4.7K-1-S4-WA
2R11 2R14 3R11 3R14 = 5K-1-S4-YA
2R15 2R17 3R15 3R17 = 0-0-S2-KOA
2R16 2R18 3R16 3R18 = 5.1-1-S2
2R19 2R20 3R19 3R20 = 100K-0.1-S4-YA
2SH1-2SH27 3SH1-3SH27 = SHORT: KAIROSNAME: SH1
2SHORT1-2SHORT4 2SHORT6-2SHORT11 3SHORT1-3SHORT4 3SHORT6-3SHORT11 = SHORT
2U1 2U2 3U1 3U2 = TLV3604DCKR-SC70
2U3 2U4 3U3 3U4 = INA186A3QDDFRQ1-SOT23-8
3C53 3C58 = 1U-16-X5R-S4-YA
3C59 = 4.7U-100-X-SB-MU
3R1 = 10K-0.1-S4

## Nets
GND: 2R43.2 2R44.2 3R41.2 3R42.2 ; also on sheet 3 4 7 8 11 12 15 16 19 20 21 22 24 28 32 36 40 52
CBIT_1: 3K1.8(V-) ; also on sheet 21 54
CBIT_2: 3K2.2 ; also on sheet 21 30 38 54
CBIT_3: 3K3.2 ; also on sheet 21 30 38 54
CBIT_4: 3K4.2 ; also on sheet 21 30 38 54
CBIT_5: 3K5.2 ; also on sheet 21 30 38 54
CBIT_6: 3K6.2 ; also on sheet 21 30 38 54
CBIT_7: 3K7.2 ; also on sheet 21 30 38 54
CBIT_8: 3K8.2 ; also on sheet 21 30 38 54
CBIT_9: 3K9.2 ; also on sheet 21 30 38 54
CBIT_10: 3K10.2 ; also on sheet 21 30 38 54
CBIT_11: 3K11.2 ; also on sheet 21 30 38 54
CBIT_12: 3K12.2 ; also on sheet 21 30 38 54
CBIT_13: 3K13.2 ; also on sheet 21 30 38 54
CBIT_14: 3K14.2 ; also on sheet 21 30 38 54
CBIT_15: 3K15.8(V-) ; also on sheet 21 54
CBIT_16: 3K16.2 ; also on sheet 21 30 38 54
CBIT_17: 3K17.2 ; also on sheet 21 30 38 54
CBIT_18: 3K18.2 ; also on sheet 21 30 38 54
CBIT_19: 3K19.2 ; also on sheet 21 29 37 53
CBIT_20: 3K20.2 ; also on sheet 21 29 37 53
CBIT_21: 3K21.2 ; also on sheet 21 29 37 53
CBIT_22: 3K22.2 ; also on sheet 21 29 37 53
CBIT_23: 3K23.8(V-) ; also on sheet 21 53
CBIT_24: 3K24.8(V-) ; also on sheet 21 53
CBIT_25: 3K25.2 ; also on sheet 21 29 37 53
CBIT_26: 3K26.2 ; also on sheet 21 29 37 53
CBIT_27: 3K27.2 ; also on sheet 21 29 37 53
CBIT_28: 3K28.2 ; also on sheet 21 29 37 53
CBIT_29: 3K29.2 ; also on sheet 21 29 37 53
CBIT_30: 3K30.2 ; also on sheet 21 29 37 53
CBIT_31: 3K31.2 ; also on sheet 21 29 37 53
CBIT_32: 3K32.2 ; also on sheet 21 29 37 53
CBIT_33: 3K33.2 ; also on sheet 21 29 37 53
CBIT_34: 3K34.2 ; also on sheet 21 29 37 53
CBIT_35: 3K35.2 ; also on sheet 21 29 37 53
CBIT_36: 3K36.2 ; also on sheet 21 29 37 53
CBIT_37: 3K37.2 ; also on sheet 21 29 37 53
CBIT_38: 3K38.2 ; also on sheet 21 28 36 52
CBIT_39: 3K39.2 ; also on sheet 21 28 36 52
CBIT_40: 3K40.2 ; also on sheet 21 28 36 52
CBIT_41: 3K41.2 ; also on sheet 21 28 36 52
CBIT_42: 3K42.2 ; also on sheet 21 28 36 52
CBIT_43: 3K43.2 ; also on sheet 21 28 36 52
CBIT_44: 3K44.2 ; also on sheet 21 28 36 52
CBIT_45: 3K45.2 ; also on sheet 21 28 36 52
CBIT_46: 3K46.2 ; also on sheet 21 28 36 52
CBIT_47: 3K47.2 ; also on sheet 21 28 36 52
CBIT_48: 3K48.2 ; also on sheet 21 28 36 52
CBIT_49: 3K49.2 ; also on sheet 21 28 36 52
CBIT_50: 3K50.2 ; also on sheet 21 28 36 52
CBIT_51: 3K51.2 ; also on sheet 21 27 35 51
CBIT_52: 3K52.2 ; also on sheet 21 27 35 51
CBIT_53: 3K53.2 ; also on sheet 21 27 35 51
CBIT_54: 3K54.2 ; also on sheet 21 27 35 51
CBIT_55: 3K55.2 ; also on sheet 21 27 35 51
CBIT_56: 3K56.2 ; also on sheet 21 27 35 51
CBIT_57: 3K57.2 ; also on sheet 21 27 35 51
CBIT_58: 3K58.2 ; also on sheet 21 27 35 51
CBIT_59: 3K59.2 ; also on sheet 21 27 35 51
CBIT_60: 3K60.2 ; also on sheet 21 27 35 51
CBIT_79: 2K19.2 ; also on sheet 21 25 33 41
CBIT_80: 2K20.2 ; also on sheet 21 25 33 41
CBIT_81: 2K21.2 ; also on sheet 21 25 33 41
CBIT_82: 2K22.2 ; also on sheet 21 25 33 41
CBIT_83: 2K23.8(V-) ; also on sheet 21 41
CBIT_84: 2K24.8(V-) ; also on sheet 21 41
CBIT_85: 2K25.2 ; also on sheet 21 25 33 41
CBIT_86: 2K26.2 ; also on sheet 21 25 33 41
CBIT_87: 2K27.2 ; also on sheet 21 25 33 41
CBIT_88: 2K28.2 ; also on sheet 21 25 33 41
CBIT_89: 2K29.2 ; also on sheet 21 25 33 41
CBIT_90: 2K30.2 ; also on sheet 21 25 33 41
CBIT_91: 2K31.2 ; also on sheet 21 25 33 41
CBIT_92: 2K32.2 ; also on sheet 21 25 33 41
CBIT_93: 2K33.2 ; also on sheet 21 25 33 41
CBIT_94: 2K34.2 ; also on sheet 21 25 33 41
CBIT_95: 2K35.2 ; also on sheet 21 25 33 41
CBIT_96: 2K36.2 ; also on sheet 21 25 33 41
CBIT_97: 2K37.2 ; also on sheet 21 25 33 41
CBIT_98: 2K38.2 ; also on sheet 21 24 32 40
CBIT_99: 2K39.2 ; also on sheet 21 24 32 40
CBIT_100: 2K40.2 ; also on sheet 21 24 32 40
CBIT_101: 2K41.2 ; also on sheet 21 24 32 40
CBIT_102: 2K42.2 ; also on sheet 21 24 32 40
CBIT_103: 2K43.2 ; also on sheet 21 24 32 40
CBIT_104: 2K44.2 ; also on sheet 21 24 32 40
CBIT_105: 2K45.2 ; also on sheet 21 24 32 40
CBIT_106: 2K46.2 ; also on sheet 21 24 32 40
CBIT_107: 2K47.2 ; also on sheet 21 24 32 40
CBIT_108: 2K48.2 ; also on sheet 21 24 32 40
CBIT_109: 2K49.2 ; also on sheet 21 24 32 40
CBIT_110: 2K50.2 ; also on sheet 21 24 32 40
CBIT_111: 2K51.2 ; also on sheet 21 23 31 39
CBIT_112: 2K52.2 ; also on sheet 21 23 31 39
CBIT_113: 2K53.2 ; also on sheet 21 23 31 39
CBIT_114: 2K54.2 ; also on sheet 21 23 31 39
CBIT_115: 2K55.2 ; also on sheet 21 23 31 39
CBIT_116: 2K56.2 ; also on sheet 21 23 31 39
CBIT_117: 2K57.2 ; also on sheet 21 23 31 39
CBIT_118: 2K58.2 ; also on sheet 21 23 31 39
CBIT_119: 2K59.2 ; also on sheet 21 23 31 39
CBIT_120: 2K60.2 ; also on sheet 21 23 31 39
CBIT_127: 3K61.2 ; also on sheet 21 27 35 51
CBIT_128: 2K61.2 ; also on sheet 21 23 31 39
DUT2_GND: 2C62.2 2C65.2 2C66.2 2C67.2 2C68.2 2C70.2 2C71.2 2C72.2 2C73.2 2C74.2 2K52.3 2K54.3 2R11.1 2R14.1 2R43.1 2R44.1 2SH1.2 2SH2.2 2SH3.2 2SH4.2 2SH5.2 2SH6.2 2SH7.2 2SH8.2 2SH9.2 2SH10.2 2SH11.2 2SH12.2 2SH13.2 2SH14.2 2SH15.2 2SH16.2 2SH17.2 2SH18.2 2SH19.2 2SH20.2 2SH21.2 2SH22.2 2SH23.2 2SH24.2 2SH25.2 2SH26.2 2SH27.2 2U1.2(VEE) 2U2.2(VEE) 2U3.4(GND) 2U4.4(GND) SITE2.EPAD SITE2.G1 SITE2.G2 SITE2.G3 SITE2.G4 SITE2.G5 SITE2.G6 SITE2.G7 SITE2.G8 SITE2.G9 ; also on sheet 50
DUT3_GND: 3C48.2 3C50.2 3C53.2 3C54.2 3C58.2 3C59.2 3C62.2 3C65.2 3C66.2 3C67.2 3C68.2 3C70.2 3C71.2 3C72.2 3C73.2 3C74.2 3K52.3 3K54.3 3R1.2 3R11.1 3R14.1 3R41.1 3R42.1 3SH1.2 3SH2.2 3SH3.2 3SH4.2 3SH5.2 3SH6.2 3SH7.2 3SH8.2 3SH9.2 3SH10.2 3SH11.2 3SH12.2 3SH13.2 3SH14.2 3SH15.2 3SH16.2 3SH17.2 3SH18.2 3SH19.2 3SH20.2 3SH21.2 3SH22.2 3SH23.2 3SH24.2 3SH25.2 3SH26.2 3SH27.2 3U1.2(VEE) 3U2.2(VEE) 3U3.4(GND) 3U4.4(GND) SITE3.3_F(GND_F) SITE3.3_S(GND_S) SITE3.EPAD SITE3.G1 SITE3.G2 SITE3.G3 SITE3.G4 SITE3.G5 SITE3.G6 SITE3.G7 SITE3.G8 SITE3.G9
S2_C1B_F: 2K27.4 2K61.3 2TP_C1B_F.1(TP) SITE2.17_F(C1B_F) ; also on sheet 19
S2_IS1N_F: 2C69.2 2K57.4 2TP_IS1N_F.1(TP) SITE2.12_F(IS1N_F) ; also on sheet 19
S2_IS1P_F: 2K19.4 2K58.3 2TP_IS1P_F.1(TP) SITE2.11_F(IS1P_F) ; also on sheet 19
S2_IS2N_F: 2K59.4 ; also on sheet 19 50
S2_IS2P_F: 2K60.3 ; also on sheet 19 50
S2_SCL_F: 2K24.3 2K53.3 2K54.4 2TP_SCL_F.1(TP) SITE2.15_F(SCL_F)
S2_SDA_F: 2K23.3 2K51.3 2K52.4 2TP_SDA_F.1(TP) SITE2.14_F(SDA_F)
S2_SRD_F: 2K56.3 ; also on sheet 50
S2_SRG_F: 2K55.3 ; also on sheet 19 50
S3_C1B_F: 3K27.4 3K61.3 3TP_C1B_F.1(TP) SITE3.17_F(C1B_F) ; also on sheet 20
S3_IS1N_F: 3C69.2 3K57.4 3TP_IS1N_F.1(TP) SITE3.12_F(IS1N_F) ; also on sheet 20
S3_IS1P_F: 3K19.4 3K58.3 3TP_IS1P_F.1(TP) SITE3.11_F(IS1P_F) ; also on sheet 20
S3_IS2N_F: 3C60.2 3K59.4 3TP_IS2N_F.1(TP) SITE3.10_F(IS2N_F) ; also on sheet 20
S3_IS2P_F: 3K16.4 3K60.3 SITE3.9_F(IS2P_F) ; also on sheet 20
S3_SCL_F: 3K24.3 3K53.3 3K54.4 3TP_SCL_F.1(TP) SITE3.15_F(SCL_F)
S3_SDA_F: 3K23.3 3K51.3 3K52.4 3TP_SDA_F.1(TP) SITE3.14_F(SDA_F)
S3_SRD_F: 3K1.3 3K2.4 3K3.4 3K56.3 3TP_SRD_F.1(TP) SITE3.1_F(SRD_F)
S3_SRD_S: 3K1.6 3K4.4 3TP_SRD_S.1(TP) SITE3.1_S(SRD_S)
S3_SRG_F: 3K55.3 3TP_SRG_F.1(TP) SITE3.4_F(SRG_F) ; also on sheet 20
SDUP5V_FILTER: 2C70.1 2C71.1 2U1.5(VCCI/VCCO) 2U2.5(VCCI/VCCO) 3C70.1 3C71.1 3U1.5(VCCI/VCCO) 3U2.5(VCCI/VCCO) ; also on sheet 22 23 27 31 35 39 51
SDUR5V_FILTER: 2K23.1(V+) 2K24.1(V+) 2RK19.2 2RK20.2 2RK21.2 2RK22.2 2RK25.2 2RK26.2 2RK27.2 2RK28.2 2RK29.2 2RK30.2 2RK31.2 2RK32.2 2RK33.2 2RK34.2 2RK35.2 2RK36.2 2RK37.2 2RK38.2 2RK39.2 2RK40.2 2RK41.2 2RK42.2 2RK43.2 2RK44.2 2RK45.2 2RK46.2 2RK47.2 2RK48.2 2RK49.2 2RK50.2 2RK51.2 2RK52.2 2RK53.2 2RK54.2 2RK55.1 2RK56.1 2RK57.1 2RK58.1 2RK59.2 2RK60.2 2RK61.2 3K1.1(V+) 3K15.1(V+) 3K23.1(V+) 3K24.1(V+) 3RK2.2 3RK3.2 3RK4.2 3RK5.2 3RK6.2 3RK7.2 3RK8.2 3RK9.2 3RK10.2 3RK11.2 3RK12.2 3RK13.2 3RK14.2 3RK16.2 3RK17.2 3RK18.2 3RK19.2 3RK20.2 3RK21.2 3RK22.2 3RK25.2 3RK26.2 3RK27.2 3RK28.2 3RK29.2 3RK30.2 3RK31.2 3RK32.2 3RK33.2 3RK34.2 3RK35.2 3RK36.2 3RK37.2 3RK38.2 3RK39.2 3RK40.2 3RK41.2 3RK42.2 3RK43.2 3RK44.2 3RK45.2 3RK46.2 3RK47.2 3RK48.2 3RK49.2 3RK50.2 3RK51.2 3RK52.2 3RK53.2 3RK54.2 3RK55.1 3RK56.1 3RK57.1 3RK58.1 3RK59.2 3RK60.2 3RK61.2 ; also on sheet 22 23 24 25 26 27 28 29 30 31 32 33 34 35 36 37 38 39 40 41 42 50 51 52 53 54
SL01_VI100_17_A_HF: 3K1.2 ; also on sheet 20
SL01_VI100_17_A_HS: 3K1.7 ; also on sheet 20
SL01_VI100_17_LS: 3SH1.1 ; also on sheet 20
SL01_VI100_18_A_HF: 3C49.2 3K5.4 3TP_SRS_F.1(TP) SITE3.2_F(SRS_F) ; also on sheet 20
SL01_VI100_18_A_HS: 3K6.4 3TP_SRS_S.1(TP) SITE3.2_S(SRS_S) ; also on sheet 20
SL01_VI100_18_B_HF: 3K44.4 SITE3.29_F(VDD1_F) ; also on sheet 20
SL01_VI100_18_B_HS: 3K45.4 3TP_VDD1_S.1(TP) SITE3.29_S(VDD1_S) ; also on sheet 20
SL01_VI100_18_LS: 3SH2.1 ; also on sheet 20
SL01_VI100_19_A_HF: 3K8.4 3K9.4 3TP_VSR_F.1(TP) SITE3.5_F(VSR_F) ; also on sheet 20
SL01_VI100_19_A_HS: 3K10.4 3TP_VSR_S.1(TP) SITE3.5_S(VSR_S) ; also on sheet 20
SL01_VI100_19_B_HS: 3K18.4 3TP_IS2N_S.1(TP) SITE3.10_S(IS2N_S) ; also on sheet 20
SL01_VI100_19_LS: 3SH3.1 ; also on sheet 20
SL01_VI100_20_A_HS: 3K7.4 3TP_SRG_S.1(TP) SITE3.4_S(SRG_S) ; also on sheet 20
SL01_VI100_20_B_HS: 3K28.4 3TP_C1B_S.1(TP) SITE3.17_S(C1B_S) ; also on sheet 20
SL01_VI100_20_LS: 3SH4.1 ; also on sheet 20
SL01_VI100_21_A_HF: 3K11.4 3K12.4 3K13.4 3TP_VCC_F.1(TP) SITE3.6_F(VCC_F) ; also on sheet 20
SL01_VI100_21_A_HS: 3TP_VCC_S.1(TP) SITE3.6_S(VCC_S) ; also on sheet 20
SL01_VI100_21_LS: 3SH5.1 ; also on sheet 20
SL01_VI100_22_A_HF: 3TP_OPTO_F.1(TP) SITE3.7_F(OPTO_F) ; also on sheet 20
SL01_VI100_22_A_HS: 3K14.4 3TP_OPTO_S.1(TP) SITE3.7_S(OPTO_S) ; also on sheet 20
SL01_VI100_22_B_HF: SITE3.30_F(GB2_F) ; also on sheet 20
SL01_VI100_22_B_HS: 3K46.4 3TP_GB2_S.1(TP) SITE3.30_S(GB2_S) ; also on sheet 20
SL01_VI100_22_LS: 3SH6.1 ; also on sheet 20
SL01_VI100_23_A_HF: 3TP_STB_F.1(TP) SITE3.13_F(STB_F) ; also on sheet 20
SL01_VI100_23_A_HS: 3K22.4 3TP_STB_S.1(TP) SITE3.13_S(STB_S) ; also on sheet 20
SL01_VI100_23_B_HF: 3K47.4 SITE3.31_F(VO2_F) ; also on sheet 20
SL01_VI100_23_B_HS: 3K48.4 3TP_VO2_S.1(TP) SITE3.31_S(VO2_S) ; also on sheet 20
SL01_VI100_23_LS: 3SH7.1 ; also on sheet 20
SL01_VI100_24_A_HF: 3K23.4 ; also on sheet 20
SL01_VI100_24_A_HS: 3K23.5 ; also on sheet 20
SL01_VI100_24_B_HF: 3C61.2 3TP_C2B_F.1(TP) SITE3.20_F(C2B_F) ; also on sheet 20
SL01_VI100_24_B_HS: 3K32.4 3TP_C2B_S.1(TP) SITE3.20_S(C2B_S) ; also on sheet 20
SL01_VI100_24_LS: 3SH8.1 ; also on sheet 20
SL01_VI100_25_A_HF: 3K24.4 ; also on sheet 20
SL01_VI100_25_A_HS: 3K24.5 ; also on sheet 20
SL01_VI100_25_B_HF: 3K33.4 3TP_C3B_F.1(TP) SITE3.21_F(C3B_F) ; also on sheet 20
SL01_VI100_25_B_HS: 3K34.4 3TP_C3B_S.1(TP) SITE3.21_S(C3B_S) ; also on sheet 20
SL01_VI100_25_LS: 3SH9.1 ; also on sheet 20
SL01_VI100_26_A_HF: 3K25.4 3TP_VDD0_F.1(TP) SITE3.16_F(VDD0_F) ; also on sheet 20
SL01_VI100_26_A_HS: 3K26.4 3TP_VDD0_S.1(TP) SITE3.16_S(VDD0_S) ; also on sheet 20
SL01_VI100_26_B_HF: SITE3.25_F(GA2_F) ; also on sheet 20
SL01_VI100_26_B_HS: 3K40.4 3TP_GA2_S.1(TP) SITE3.25_S(GA2_S) ; also on sheet 20
SL01_VI100_26_LS: 3SH10.1 ; also on sheet 20
SL01_VI100_27_A_HF: 3C63.2 3TP_C1A_F.1(TP) SITE3.18_F(C1A_F) ; also on sheet 20
SL01_VI100_27_A_HS: 3K29.4 3TP_C1A_S.1(TP) SITE3.18_S(C1A_S) ; also on sheet 20
SL01_VI100_27_B_HF: SITE3.26_F(GA1_F) ; also on sheet 20
SL01_VI100_27_B_HS: 3K41.4 3TP_GA1_S.1(TP) SITE3.26_S(GA1_S) ; also on sheet 20
SL01_VI100_27_LS: 3SH11.1 ; also on sheet 20
SL01_VI100_28_A_HF: 3K30.4 3TP_C2A_F.1(TP) SITE3.19_F(C2A_F) ; also on sheet 20
SL01_VI100_28_A_HS: 3K31.4 3TP_C2A_S.1(TP) SITE3.19_S(C2A_S) ; also on sheet 20
SL01_VI100_28_B_HF: SITE3.27_F(GB1_F) ; also on sheet 20
SL01_VI100_28_B_HS: 3K42.4 3TP_GB1_S.1(TP) SITE3.27_S(GB1_S) ; also on sheet 20
SL01_VI100_28_LS: 3SH12.1 ; also on sheet 20
SL01_VI100_29_A_HF: 3C64.2 3TP_C3A_F.1(TP) SITE3.22_F(C3A_F) ; also on sheet 20
SL01_VI100_29_A_HS: 3K35.4 3TP_C3A_S.1(TP) SITE3.22_S(C3A_S) ; also on sheet 20
SL01_VI100_29_B_HF: 3K49.4 SITE3.32_F(VDD2_F) ; also on sheet 20
SL01_VI100_29_B_HS: 3K50.4 3TP_VDD2_S.1(TP) SITE3.32_S(VDD2_S) ; also on sheet 20
SL01_VI100_29_LS: 3SH13.1 ; also on sheet 20
SL01_VI100_30_A_HF: 3K36.4 3TP_VDDI_F.1(TP) SITE3.23_F(VDDI_F) ; also on sheet 20
SL01_VI100_30_A_HS: 3K37.4 3TP_VDDI_S.1(TP) SITE3.23_S(VDDI_S) ; also on sheet 20
SL01_VI100_30_B_HS: 3K21.4 3TP_IS1N_S.1(TP) SITE3.12_S(IS1N_S) ; also on sheet 20
SL01_VI100_30_LS: 3SH14.1 ; also on sheet 20
SL01_VI100_31_A_HF: 3K38.4 3TP_VIN_F.1(TP) SITE3.24_F(VIN_F) ; also on sheet 20
SL01_VI100_31_A_HS: 3K39.4 3TP_VIN_S.1(TP) SITE3.24_S(VIN_S) ; also on sheet 20
SL01_VI100_31_B_HS: 3K20.4 SITE3.11_S(IS1P_S) ; also on sheet 20
SL01_VI100_31_LS: 3SH15.1 ; also on sheet 20
SL01_VI100_32_A_HF: SITE3.28_F(VO1_F) ; also on sheet 20
SL01_VI100_32_A_HS: 3K43.4 3TP_VO1_S.1(TP) SITE3.28_S(VO1_S) ; also on sheet 20
SL01_VI100_32_B_HS: 3K17.4 3TP_IS2P_S.1(TP) SITE3.9_S(IS2P_S) ; also on sheet 20
SL01_VI100_32_LS: 3SH16.1 ; also on sheet 20
SL02_VI100_1_LS: 2SH1.1 ; also on sheet 19
SL02_VI100_2_B_HF: 2K44.4 SITE2.29_F(VDD1_F) ; also on sheet 19
SL02_VI100_2_B_HS: 2K45.4 2TP_VDD1_S.1(TP) SITE2.29_S(VDD1_S) ; also on sheet 19
SL02_VI100_2_LS: 2SH2.1 ; also on sheet 19
SL02_VI100_3_LS: 2SH3.1 ; also on sheet 19
SL02_VI100_4_B_HS: 2K28.4 2TP_C1B_S.1(TP) SITE2.17_S(C1B_S) ; also on sheet 19
SL02_VI100_4_LS: 2SH4.1 ; also on sheet 19
SL02_VI100_5_LS: 2SH5.1 ; also on sheet 19
SL02_VI100_6_B_HF: SITE2.30_F(GB2_F) ; also on sheet 19
SL02_VI100_6_B_HS: 2K46.4 2TP_GB2_S.1(TP) SITE2.30_S(GB2_S) ; also on sheet 19
SL02_VI100_6_LS: 2SH6.1 ; also on sheet 19
SL02_VI100_7_A_HF: 2TP_STB_F.1(TP) SITE2.13_F(STB_F) ; also on sheet 19
SL02_VI100_7_A_HS: 2K22.4 2TP_STB_S.1(TP) SITE2.13_S(STB_S) ; also on sheet 19
SL02_VI100_7_B_HF: 2K47.4 SITE2.31_F(VO2_F) ; also on sheet 19
SL02_VI100_7_B_HS: 2K48.4 2TP_VO2_S.1(TP) SITE2.31_S(VO2_S) ; also on sheet 19
SL02_VI100_7_LS: 2SH7.1 ; also on sheet 19
SL02_VI100_8_A_HF: 2K23.4 ; also on sheet 19
SL02_VI100_8_A_HS: 2K23.5 ; also on sheet 19
SL02_VI100_8_B_HF: 2C61.2 2TP_C2B_F.1(TP) SITE2.20_F(C2B_F) ; also on sheet 19
SL02_VI100_8_B_HS: 2K32.4 2TP_C2B_S.1(TP) SITE2.20_S(C2B_S) ; also on sheet 19
SL02_VI100_8_LS: 2SH8.1 ; also on sheet 19
SL02_VI100_9_A_HF: 2K24.4 ; also on sheet 19
SL02_VI100_9_A_HS: 2K24.5 ; also on sheet 19
SL02_VI100_9_B_HF: 2K33.4 2TP_C3B_F.1(TP) SITE2.21_F(C3B_F) ; also on sheet 19
SL02_VI100_9_B_HS: 2K34.4 2TP_C3B_S.1(TP) SITE2.21_S(C3B_S) ; also on sheet 19
SL02_VI100_9_LS: 2SH9.1 ; also on sheet 19
SL02_VI100_10_A_HF: 2K25.4 2TP_VDD0_F.1(TP) SITE2.16_F(VDD0_F) ; also on sheet 19
SL02_VI100_10_A_HS: 2K26.4 2TP_VDD0_S.1(TP) SITE2.16_S(VDD0_S) ; also on sheet 19
SL02_VI100_10_B_HF: SITE2.25_F(GA2_F) ; also on sheet 19
SL02_VI100_10_B_HS: 2K40.4 2TP_GA2_S.1(TP) SITE2.25_S(GA2_S) ; also on sheet 19
SL02_VI100_10_LS: 2SH10.1 ; also on sheet 19
SL02_VI100_11_A_HF: 2C63.2 2TP_C1A_F.1(TP) SITE2.18_F(C1A_F) ; also on sheet 19
SL02_VI100_11_A_HS: 2K29.4 2TP_C1A_S.1(TP) SITE2.18_S(C1A_S) ; also on sheet 19
SL02_VI100_11_B_HF: SITE2.26_F(GA1_F) ; also on sheet 19
SL02_VI100_11_B_HS: 2K41.4 2TP_GA1_S.1(TP) SITE2.26_S(GA1_S) ; also on sheet 19
SL02_VI100_11_LS: 2SH11.1 ; also on sheet 19
SL02_VI100_12_A_HF: 2K30.4 2TP_C2A_F.1(TP) SITE2.19_F(C2A_F) ; also on sheet 19
SL02_VI100_12_A_HS: 2K31.4 2TP_C2A_S.1(TP) SITE2.19_S(C2A_S) ; also on sheet 19
SL02_VI100_12_B_HF: SITE2.27_F(GB1_F) ; also on sheet 19
SL02_VI100_12_B_HS: 2K42.4 2TP_GB1_S.1(TP) SITE2.27_S(GB1_S) ; also on sheet 19
SL02_VI100_12_LS: 2SH12.1 ; also on sheet 19
SL02_VI100_13_A_HF: 2C64.2 2TP_C3A_F.1(TP) SITE2.22_F(C3A_F) ; also on sheet 19
SL02_VI100_13_A_HS: 2K35.4 2TP_C3A_S.1(TP) SITE2.22_S(C3A_S) ; also on sheet 19
SL02_VI100_13_B_HF: 2K49.4 SITE2.32_F(VDD2_F) ; also on sheet 19
SL02_VI100_13_B_HS: 2K50.4 2TP_VDD2_S.1(TP) SITE2.32_S(VDD2_S) ; also on sheet 19
SL02_VI100_13_LS: 2SH13.1 ; also on sheet 19
SL02_VI100_14_A_HF: 2K36.4 2TP_VDDI_F.1(TP) SITE2.23_F(VDDI_F) ; also on sheet 19
SL02_VI100_14_A_HS: 2K37.4 2TP_VDDI_S.1(TP) SITE2.23_S(VDDI_S) ; also on sheet 19
SL02_VI100_14_B_HS: 2K21.4 2TP_IS1N_S.1(TP) SITE2.12_S(IS1N_S) ; also on sheet 19
SL02_VI100_14_LS: 2SH14.1 ; also on sheet 19
SL02_VI100_15_A_HF: 2K38.4 2TP_VIN_F.1(TP) SITE2.24_F(VIN_F) ; also on sheet 19
SL02_VI100_15_A_HS: 2K39.4 2TP_VIN_S.1(TP) SITE2.24_S(VIN_S) ; also on sheet 19
SL02_VI100_15_B_HS: 2K20.4 SITE2.11_S(IS1P_S) ; also on sheet 19
SL02_VI100_15_LS: 2SH15.1 ; also on sheet 19
SL02_VI100_16_A_HF: SITE2.28_F(VO1_F) ; also on sheet 19
SL02_VI100_16_A_HS: 2K43.4 2TP_VO1_S.1(TP) SITE2.28_S(VO1_S) ; also on sheet 19
SL02_VI100_16_LS: 2SH16.1 ; also on sheet 19
SL05_PMVI_2_HF: 3K15.4 ; also on sheet 16
SL05_PMVI_2_HS: 3K15.5 ; also on sheet 16
SL05_PMVI_2_LS: 3SH17.1 ; also on sheet 16
SL05_PMVI_20_HF: 3R7.1 3SHORT3.1 ; also on sheet 16
SL05_PMVI_20_HS: 3SHORT3.2 ; also on sheet 16
SL05_PMVI_20_LS: 3SH18.1 ; also on sheet 16
SL05_PMVI_21_HF: 3R8.1 3SHORT4.1 ; also on sheet 16
SL05_PMVI_21_HS: 3SHORT4.2 ; also on sheet 16
SL05_PMVI_21_LS: 3SH19.1 ; also on sheet 16
SL05_PMVI_22_HF: 3SHORT1.1 3TP_IN-_1.1(TP) 3U1.4(-IN) ; also on sheet 16
SL05_PMVI_22_HS: 3SHORT1.2 ; also on sheet 16
SL05_PMVI_22_LS: 3SH20.1 ; also on sheet 16
SL05_PMVI_23_HF: 3SHORT2.1 3TP_IN-_2.1(TP) 3U2.4(-IN) ; also on sheet 16
SL05_PMVI_23_HS: 3SHORT2.2 ; also on sheet 16
SL05_PMVI_23_LS: 3SH21.1 ; also on sheet 16
SL05_PMVI_24_HF: 3SHORT9.1 3TP_OUT_1.1(TP) 3U3.5(OUT) ; also on sheet 16
SL05_PMVI_24_HS: 3SHORT9.2 ; also on sheet 16
SL05_PMVI_24_LS: 3SH22.1 ; also on sheet 16
SL05_PMVI_25_HF: 3C72.1 3R15.2 3SHORT6.2 3U3.1(VS) ; also on sheet 16
SL05_PMVI_25_HS: 3SHORT6.1 ; also on sheet 16
SL05_PMVI_25_LS: 3SH23.1 ; also on sheet 16
SL05_PMVI_26_HF: 3SHORT11.2 3TP_REF_1.1(TP) 3U3.3(REF) ; also on sheet 16
SL05_PMVI_26_HS: 3SHORT11.1 ; also on sheet 16
SL05_PMVI_26_LS: 3SH24.1 ; also on sheet 16
SL05_PMVI_27_HF: 3SHORT10.1 3TP_OUT_2.1(TP) 3U4.5(OUT) ; also on sheet 16
SL05_PMVI_27_HS: 3SHORT10.2 ; also on sheet 16
SL05_PMVI_27_LS: 3SH25.1 ; also on sheet 16
SL05_PMVI_28_HF: 3C73.1 3R17.2 3SHORT7.2 3U4.1(VS) ; also on sheet 16
SL05_PMVI_28_HS: 3SHORT7.1 ; also on sheet 16
SL05_PMVI_28_LS: 3SH26.1 ; also on sheet 16
SL05_PMVI_29_HF: 3SHORT8.2 3TP_REF_2.1(TP) 3U4.3(REF) ; also on sheet 16
SL05_PMVI_29_HS: 3SHORT8.1 ; also on sheet 16
SL05_PMVI_29_LS: 3SH27.1 ; also on sheet 16
SL06_DP_8: 2K20.3 ; also on sheet 15
SL06_DP_9: 2K21.3 ; also on sheet 15
SL06_DP_10: 2K22.3 ; also on sheet 15
SL06_DP_11: 2K23.2 ; also on sheet 15
SL06_DP_12: 2K24.2 ; also on sheet 15
SL06_DP_13: 2K26.3 ; also on sheet 15
SL06_DP_14: 2K28.3 ; also on sheet 15
SL06_DP_15: 2K29.3 ; also on sheet 15
SL06_DP_16: 2K31.3 ; also on sheet 15
SL06_DP_17: 2K32.3 ; also on sheet 15
SL06_DP_18: 2K34.3 ; also on sheet 15
SL06_DP_19: 2K35.3 ; also on sheet 15
SL06_DP_20: 2K37.3 ; also on sheet 15
SL06_DP_21: 2K39.3 ; also on sheet 15
SL06_DP_22: 2K40.3 ; also on sheet 15
SL06_DP_23: 2K41.3 ; also on sheet 15
SL06_DP_24: 2K42.3 ; also on sheet 15
SL06_DP_25: 2K43.3 ; also on sheet 15
SL06_DP_26: 2K45.3 ; also on sheet 15
SL06_DP_27: 2K46.3 ; also on sheet 15
SL06_DP_28: 2K48.3 ; also on sheet 15
SL06_DP_29: 2K50.3 ; also on sheet 15
SL06_DP_121: 2TP_OUT+_1.1(TP) 2U1.1(OUT+) ; also on sheet 15
SL06_DP_122: 2TP_OUT-_1.1(TP) 2U1.6(OUT-) ; also on sheet 15
SL06_DP_123: 2TP_OUT+_2.1(TP) 2U2.1(OUT+) ; also on sheet 15
SL06_DP_124: 2TP_OUT-_2.1(TP) 2U2.6(OUT-) ; also on sheet 15
SL06_DP_125: 2R15.1 2U3.2(ENABLE) ; also on sheet 15
SL06_DP_126: 2R17.1 2U4.2(ENABLE) ; also on sheet 15
SL09_FPVI_5_A_HF: 3K1.4 ; also on sheet 12
SL09_FPVI_5_A_HS: 3K1.5 ; also on sheet 12
SL13_DP_30: 3K4.3 ; also on sheet 8
SL13_DP_31: 3K6.3 ; also on sheet 8
SL13_DP_32: 3K7.3 ; also on sheet 8
SL13_DP_33: 3K10.3 ; also on sheet 8
SL13_DP_34: 3K14.3 ; also on sheet 8
SL13_DP_35: 3K15.2 ; also on sheet 8
SL13_DP_36: 3K17.3 ; also on sheet 8
SL13_DP_37: 3K18.3 ; also on sheet 8
SL13_DP_38: 3K20.3 ; also on sheet 8
SL13_DP_39: 3K21.3 ; also on sheet 8
SL13_DP_40: 3K22.3 ; also on sheet 8
SL13_DP_41: 3K23.2 ; also on sheet 8
SL13_DP_42: 3K24.2 ; also on sheet 8
SL13_DP_43: 3K26.3 ; also on sheet 8
SL13_DP_44: 3K28.3 ; also on sheet 8
SL13_DP_45: 3K29.3 ; also on sheet 8
SL13_DP_46: 3K31.3 ; also on sheet 8
SL13_DP_47: 3K32.3 ; also on sheet 8
SL13_DP_48: 3K34.3 ; also on sheet 8
SL13_DP_49: 3K35.3 ; also on sheet 8
SL13_DP_50: 3K37.3 ; also on sheet 8
SL13_DP_51: 3K39.3 ; also on sheet 8
SL13_DP_52: 3K40.3 ; also on sheet 8
SL13_DP_53: 3K41.3 ; also on sheet 8
SL13_DP_54: 3K42.3 ; also on sheet 8
SL13_DP_55: 3K43.3 ; also on sheet 8
SL13_DP_56: 3K45.3 ; also on sheet 8
SL13_DP_57: 3K46.3 ; also on sheet 8
SL13_DP_58: 3K48.3 ; also on sheet 8
SL13_DP_59: 3K50.3 ; also on sheet 8
SL13_DP_127: 3TP_OUT+_1.1(TP) 3U1.1(OUT+) ; also on sheet 8
SL13_DP_128: 3TP_OUT-_1.1(TP) 3U1.6(OUT-) ; also on sheet 8
SL13_DP_129: 3TP_OUT+_2.1(TP) 3U2.1(OUT+) ; also on sheet 8
SL13_DP_130: 3TP_OUT-_2.1(TP) 3U2.6(OUT-) ; also on sheet 8
SL13_DP_131: 3R15.1 3U3.2(ENABLE) ; also on sheet 8
SL13_DP_132: 3R17.1 3U4.2(ENABLE) ; also on sheet 8
SL14_PMVI_1_LS: 2SH17.1 ; also on sheet 7
SL14_PMVI_10_HF: 2R7.1 2SHORT3.1 ; also on sheet 7
SL14_PMVI_10_HS: 2SHORT3.2 ; also on sheet 7
SL14_PMVI_10_LS: 2SH18.1 ; also on sheet 7
SL14_PMVI_11_HF: 2R8.1 2SHORT4.1 ; also on sheet 7
SL14_PMVI_11_HS: 2SHORT4.2 ; also on sheet 7
SL14_PMVI_11_LS: 2SH19.1 ; also on sheet 7
SL14_PMVI_12_HF: 2SHORT1.1 2TP_IN-_1.1(TP) 2U1.4(-IN) ; also on sheet 7
SL14_PMVI_12_HS: 2SHORT1.2 ; also on sheet 7
SL14_PMVI_12_LS: 2SH20.1 ; also on sheet 7
SL14_PMVI_13_HF: 2SHORT2.1 2TP_IN-_2.1(TP) 2U2.4(-IN) ; also on sheet 7
SL14_PMVI_13_HS: 2SHORT2.2 ; also on sheet 7
SL14_PMVI_13_LS: 2SH21.1 ; also on sheet 7
SL14_PMVI_14_HF: 2SHORT9.1 2TP_OUT_1.1(TP) 2U3.5(OUT) ; also on sheet 7
SL14_PMVI_14_HS: 2SHORT9.2 ; also on sheet 7
SL14_PMVI_14_LS: 2SH22.1 ; also on sheet 7
SL14_PMVI_15_HF: 2C72.1 2R15.2 2SHORT6.2 2U3.1(VS) ; also on sheet 7
SL14_PMVI_15_HS: 2SHORT6.1 ; also on sheet 7
SL14_PMVI_15_LS: 2SH23.1 ; also on sheet 7
SL14_PMVI_16_HF: 2SHORT11.2 2TP_REF_1.1(TP) 2U3.3(REF) ; also on sheet 7
SL14_PMVI_16_HS: 2SHORT11.1 ; also on sheet 7
SL14_PMVI_16_LS: 2SH24.1 ; also on sheet 7
SL14_PMVI_17_HF: 2SHORT10.1 2TP_OUT_2.1(TP) 2U4.5(OUT) ; also on sheet 7
SL14_PMVI_17_HS: 2SHORT10.2 ; also on sheet 7
SL14_PMVI_17_LS: 2SH25.1 ; also on sheet 7
SL14_PMVI_18_HF: 2C73.1 2R17.2 2SHORT7.2 2U4.1(VS) ; also on sheet 7
SL14_PMVI_18_HS: 2SHORT7.1 ; also on sheet 7
SL14_PMVI_18_LS: 2SH26.1 ; also on sheet 7
SL14_PMVI_19_HF: 2SHORT8.2 2TP_REF_2.1(TP) 2U4.3(REF) ; also on sheet 7
SL14_PMVI_19_HS: 2SHORT8.1 ; also on sheet 7
SL14_PMVI_19_LS: 2SH27.1 ; also on sheet 7
N18707687: 2C69.1 2K19.3
N18707714: 2K19.1 2RK19.1
N18707716: 2K20.1 2RK20.1
N18707717: 2K21.1 2RK21.1
N18707742: 2K22.1 2RK22.1
N18707748: 2K23.6 2TP_SDA_S.1(TP) SITE2.14_S(SDA_S)
N18707762: 2K24.6 SITE2.15_S(SCL_S)
N18707772: 2C62.1 2K25.3
N18707790: 2K25.1 2RK25.1
N18707794: 2K26.1 2RK26.1
N18707799: 2C63.1 2K27.3
N18707815: 2K28.1 2RK28.1
N18707836: 2K27.1 2RK27.1
N18707838: 2K29.1 2RK29.1
N18707843: 2C61.1 2K30.3
N18707857: 2K31.1 2RK31.1
N18707877: 2K30.1 2RK30.1
N18707880: 2K32.1 2RK32.1
N18707882: 2K35.1 2RK35.1
N18707884: 2K34.1 2RK34.1
N18707886: 2K33.1 2RK33.1
N18707889: 2C64.1 2K33.3
N18707924: 2K37.1 2RK37.1
N18707925: 2K36.1 2RK36.1
N18707931: 2C65.1 2K36.3
N18709217: 2K39.1 2RK39.1
N18709218: 2K38.1 2RK38.1
N18709224: 2C74.1 2K38.3
N18709243: 2K40.1 2RK40.1
N18709256: 2K41.1 2RK41.1
N18709269: 2K42.1 2RK42.1
N18709281: 2K43.1 2RK43.1
N18709294: 2K45.1 2RK45.1
N18709295: 2K44.1 2RK44.1
N18709305: 2C66.1 2K44.3
N18709323: 2K46.1 2RK46.1
N18709339: 2C67.1 2K47.3
N18709352: 2K48.1 2RK48.1
N18709353: 2K47.1 2RK47.1
N18709363: 2C68.1 2K49.3
N18709376: 2K50.1 2RK50.1
N18709377: 2K49.1 2RK49.1
N18710191: 2K51.4 2R7.2
N18710203: 2K53.4 2R8.2
N18710205: 2K53.1 2RK53.1
N18710227: 2R11.2 2R19.1 2TP_IN+_1.1(TP) 2U1.3(+IN)
N18710239: 2R14.2 2R20.1 2TP_IN+_2.1(TP) 2U2.3(+IN)
N18710249: 2K55.1 2RK59.1
N18710252: 2K55.4 2R19.2
N18710254: 2K56.1 2RK60.1
N18710271: 2K57.3 2R16.1 2TP_IN-_3.1(TP) 2U3.8(IN-)
N18710272: 2K58.4 2R16.2 2TP_IN+_3.1(TP) 2U3.7(IN+)
N18710300: 2K60.4 2R18.2 2TP_IN+_4.1(TP) 2U4.7(IN+)
N18710304: 2K59.3 2R18.1 2TP_IN-_4.1(TP) 2U4.8(IN-)
N18710315: 2K56.4 2K61.4 2R20.2
N18710316: 2K54.1 2RK54.1
N18710320: 2K51.1 2RK51.1
N18710322: 2K52.1 2RK52.1
N18710386: 2K57.1 2RK55.2
N18710387: 2K58.1 2RK56.2
N18710388: 2K59.1 2RK57.2
N18710389: 2K60.1 2RK58.2
N18710392: 2K61.1 2RK61.1
N18711523: 3C48.1 3K2.3
N18711532: 3C49.1 3K3.3
N18711541: 3C50.1 3K5.3
N18711574: 3K7.1 3RK7.1
N18711581: 3C53.1 3K8.3
N18711590: 3C54.1 3K9.3
N18711620: 3C59.1 3K12.3
N18711627: 3K13.3 3R1.1
N18711645: 3K15.6 3TP_ATT_S.1(TP) SITE3.8_S(ATT_S)
N18711663: 3K5.1 3RK5.1
N18711665: 3K6.1 3RK6.1
N18711667: 3K8.1 3RK8.1
N18711668: 3K9.1 3RK9.1
N18711669: 3K10.1 3RK10.1
N18711670: 3K11.1 3RK11.1
N18711673: 3C58.1 3K11.3
N18711676: 3K12.1 3RK12.1
N18711678: 3K13.1 3RK13.1
N18711681: 3K14.1 3RK14.1
N18711683: 3K2.1 3RK2.1
N18711684: 3K3.1 3RK3.1
N18711685: 3K4.1 3RK4.1
N18711705: 3K15.3 3TP_ATT_F.1(TP) SITE3.8_F(ATT_F)
N18711717: 3C60.1 3K16.3
N18711730: 3K17.1 3RK17.1
N18711744: 3K16.1 3RK16.1
N18711748: 3K18.1 3RK18.1
N18712898: 3C69.1 3K19.3
N18712925: 3K19.1 3RK19.1
N18712927: 3K20.1 3RK20.1
N18712928: 3K21.1 3RK21.1
N18712953: 3K22.1 3RK22.1
N18712959: 3K23.6 3TP_SDA_S.1(TP) SITE3.14_S(SDA_S)
N18712973: 3K24.6 SITE3.15_S(SCL_S)
N18712983: 3C62.1 3K25.3
N18713001: 3K25.1 3RK25.1
N18713005: 3K26.1 3RK26.1
N18713010: 3C63.1 3K27.3
N18713026: 3K28.1 3RK28.1
N18713047: 3K27.1 3RK27.1
N18713049: 3K29.1 3RK29.1
N18713054: 3C61.1 3K30.3
N18713068: 3K31.1 3RK31.1
N18713088: 3K30.1 3RK30.1
N18713091: 3K32.1 3RK32.1
N18713093: 3K35.1 3RK35.1
N18713095: 3K34.1 3RK34.1
N18713097: 3K33.1 3RK33.1
N18713100: 3C64.1 3K33.3
N18713135: 3K37.1 3RK37.1
N18713136: 3K36.1 3RK36.1
N18713142: 3C65.1 3K36.3
N18714428: 3K39.1 3RK39.1
N18714429: 3K38.1 3RK38.1
N18714435: 3C74.1 3K38.3
N18714454: 3K40.1 3RK40.1
N18714467: 3K41.1 3RK41.1
N18714480: 3K42.1 3RK42.1
N18714492: 3K43.1 3RK43.1
N18714505: 3K45.1 3RK45.1
N18714506: 3K44.1 3RK44.1
N18714516: 3C66.1 3K44.3
N18714534: 3K46.1 3RK46.1
N18714550: 3C67.1 3K47.3
N18714563: 3K48.1 3RK48.1
N18714564: 3K47.1 3RK47.1
N18714574: 3C68.1 3K49.3
N18714587: 3K50.1 3RK50.1
N18714588: 3K49.1 3RK49.1
N18715402: 3K51.4 3R7.2
N18715414: 3K53.4 3R8.2
N18715416: 3K53.1 3RK53.1
N18715438: 3R11.2 3R19.1 3TP_IN+_1.1(TP) 3U1.3(+IN)
N18715450: 3R14.2 3R20.1 3TP_IN+_2.1(TP) 3U2.3(+IN)
N18715460: 3K55.1 3RK59.1
N18715463: 3K55.4 3R19.2
N18715465: 3K56.1 3RK60.1
N18715482: 3K57.3 3R16.1 3TP_IN-_3.1(TP) 3U3.8(IN-)
N18715483: 3K58.4 3R16.2 3TP_IN+_3.1(TP) 3U3.7(IN+)
N18715511: 3K60.4 3R18.2 3TP_IN+_4.1(TP) 3U4.7(IN+)
N18715515: 3K59.3 3R18.1 3TP_IN-_4.1(TP) 3U4.8(IN-)
N18715526: 3K56.4 3K61.4 3R20.2
N18715527: 3K54.1 3RK54.1
N18715531: 3K51.1 3RK51.1
N18715533: 3K52.1 3RK52.1
N18715597: 3K57.1 3RK55.2
N18715598: 3K58.1 3RK56.2
N18715599: 3K59.1 3RK57.2
N18715600: 3K60.1 3RK58.2
N18715603: 3K61.1 3RK61.1

Not connected (* = marked no-connect by the designer): 2K23 7*; 2K24 7*; 2U3 6(NC)*; 2U4 6(NC)*; 3K15 7*; 3K23 7*; 3K24 7*; 3U3 6(NC)*; 3U4 6(NC)*; SITE2 NGH1* NGH2* NGH3* NGH4* NUT1* NUT2* NUT3* NUT4*; SITE3 NGH1* NGH2* NGH3* NGH4* NUT1* NUT2* NUT3* NUT4*

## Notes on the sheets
sheet 43
- Pull-up Resistor
- Timing Circuits(GX1 ¸ê·½¤À°t»Ý­n¦b®É§Ç¹q¸ô¤W¬Û¾F)
- Differential Circuit
sheet 47
- Pull-up Resistor
- Timing Circuits(GX1 ¸ê·½¤À°t»Ý­n¦b®É§Ç¹q¸ô¤W¬Û¾F)
- Differential Circuit
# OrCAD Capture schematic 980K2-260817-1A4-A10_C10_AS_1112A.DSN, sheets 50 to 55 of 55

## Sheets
50 P0021_S2_DUT: size C
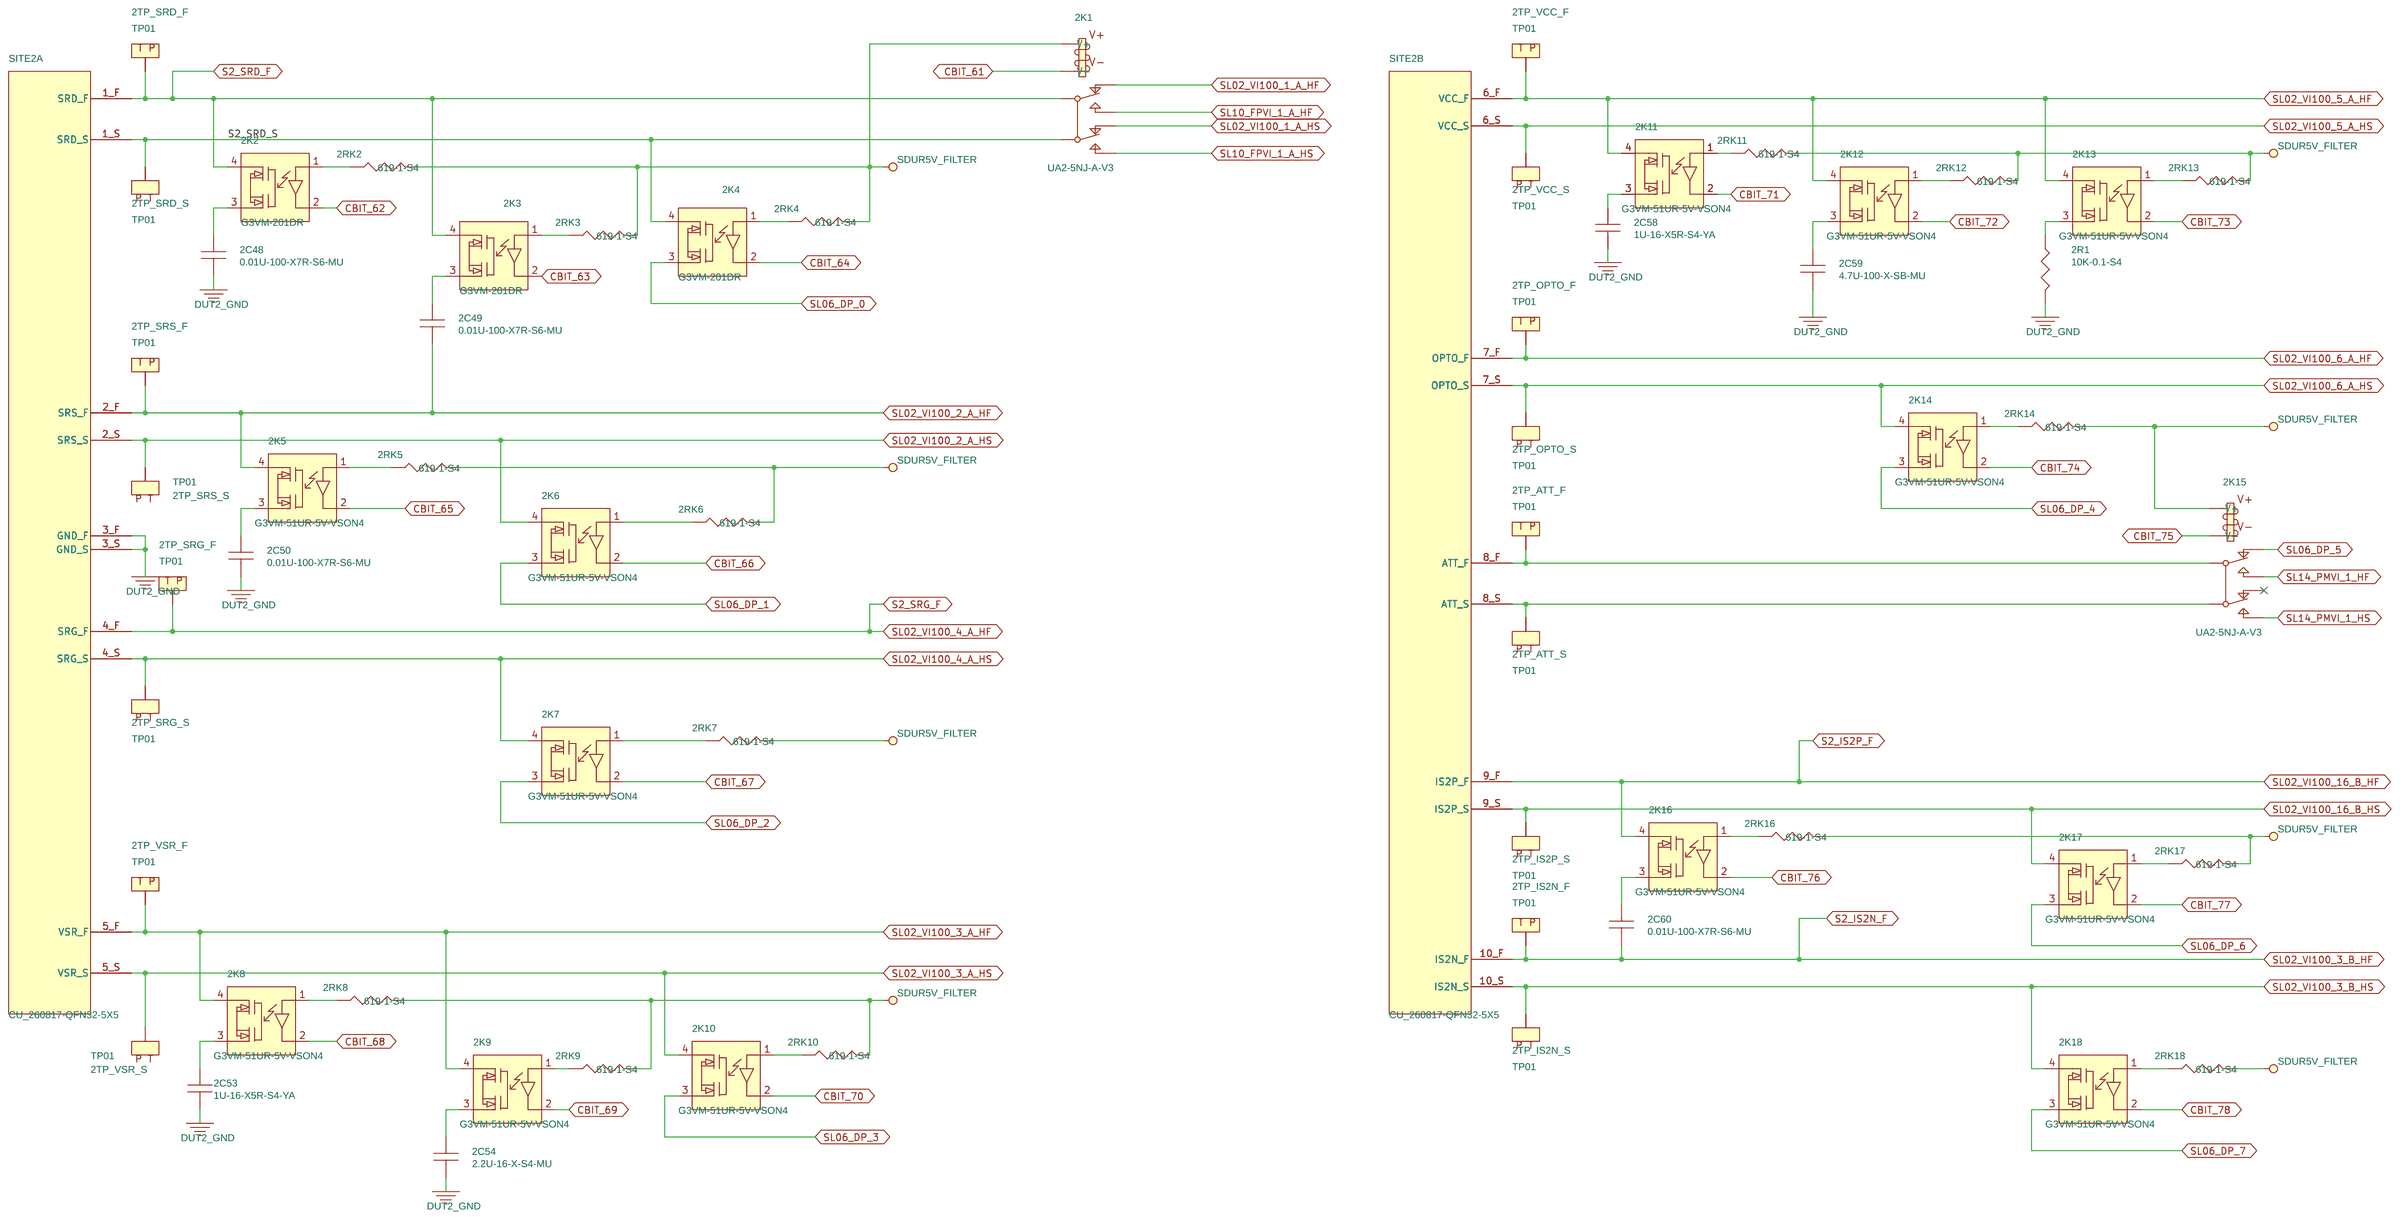
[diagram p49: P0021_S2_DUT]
51 P0014_S1_DUT: size C
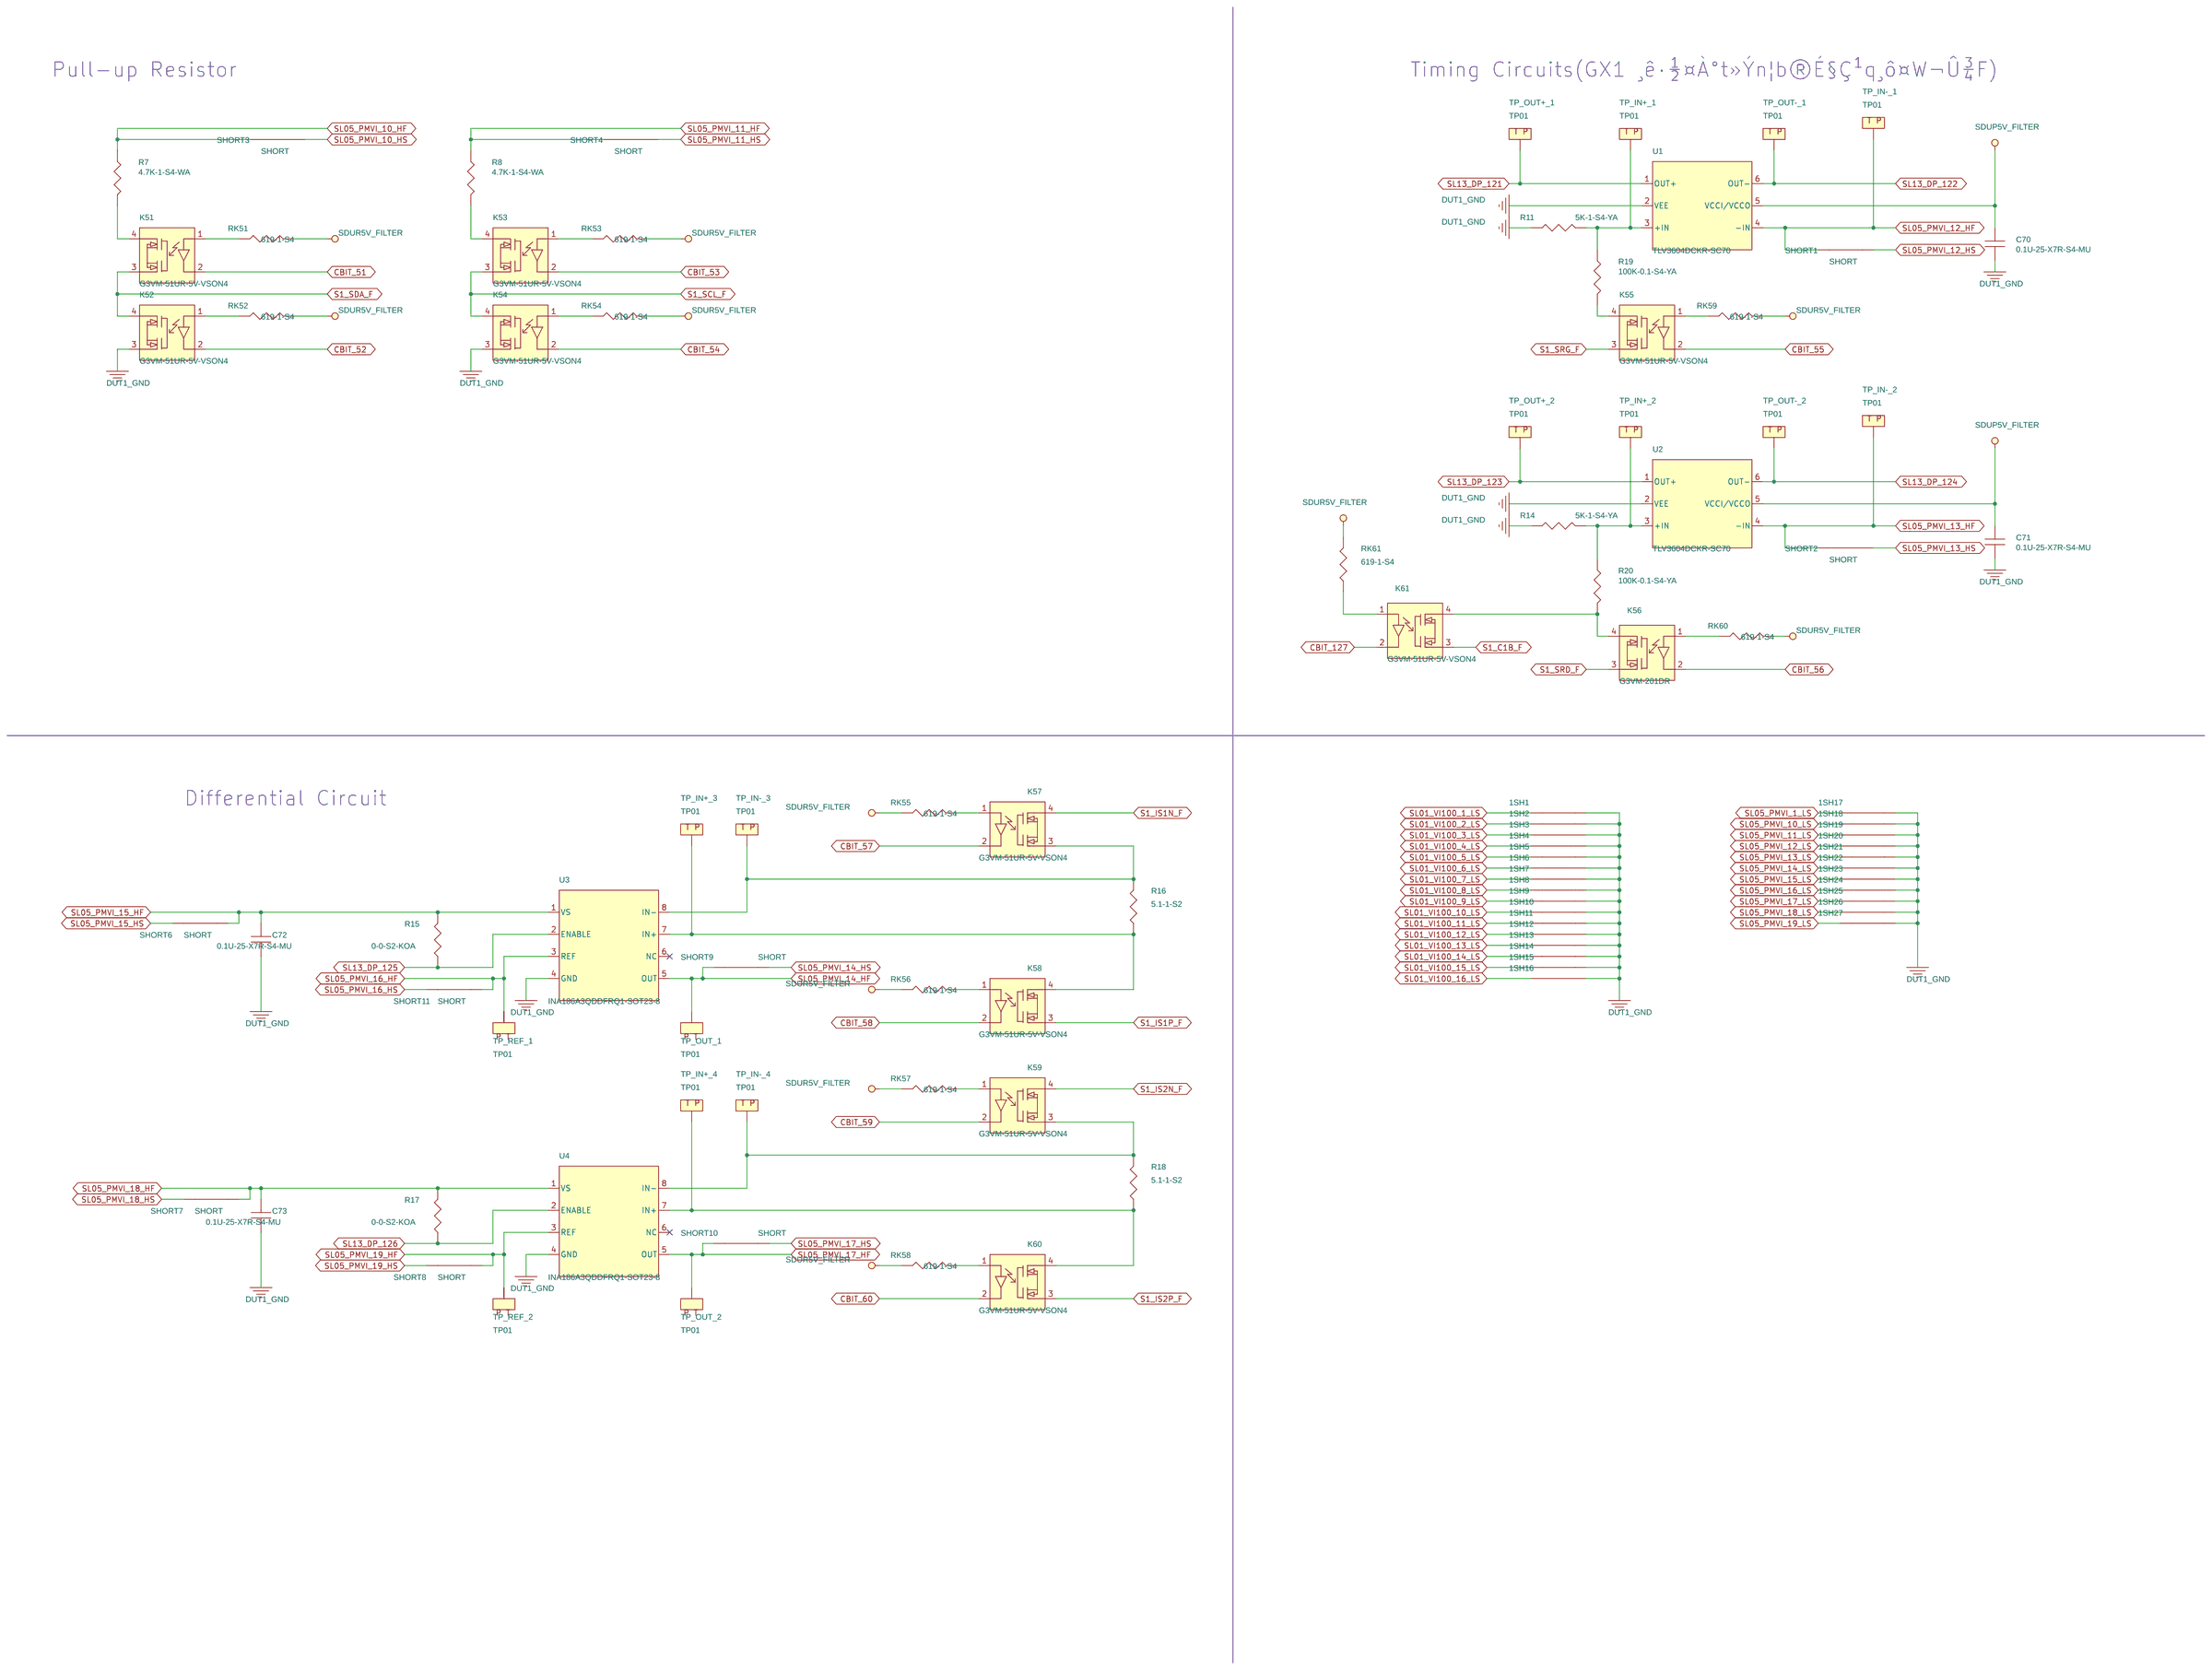
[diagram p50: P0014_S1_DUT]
52 P0013_S1_DUT: size C
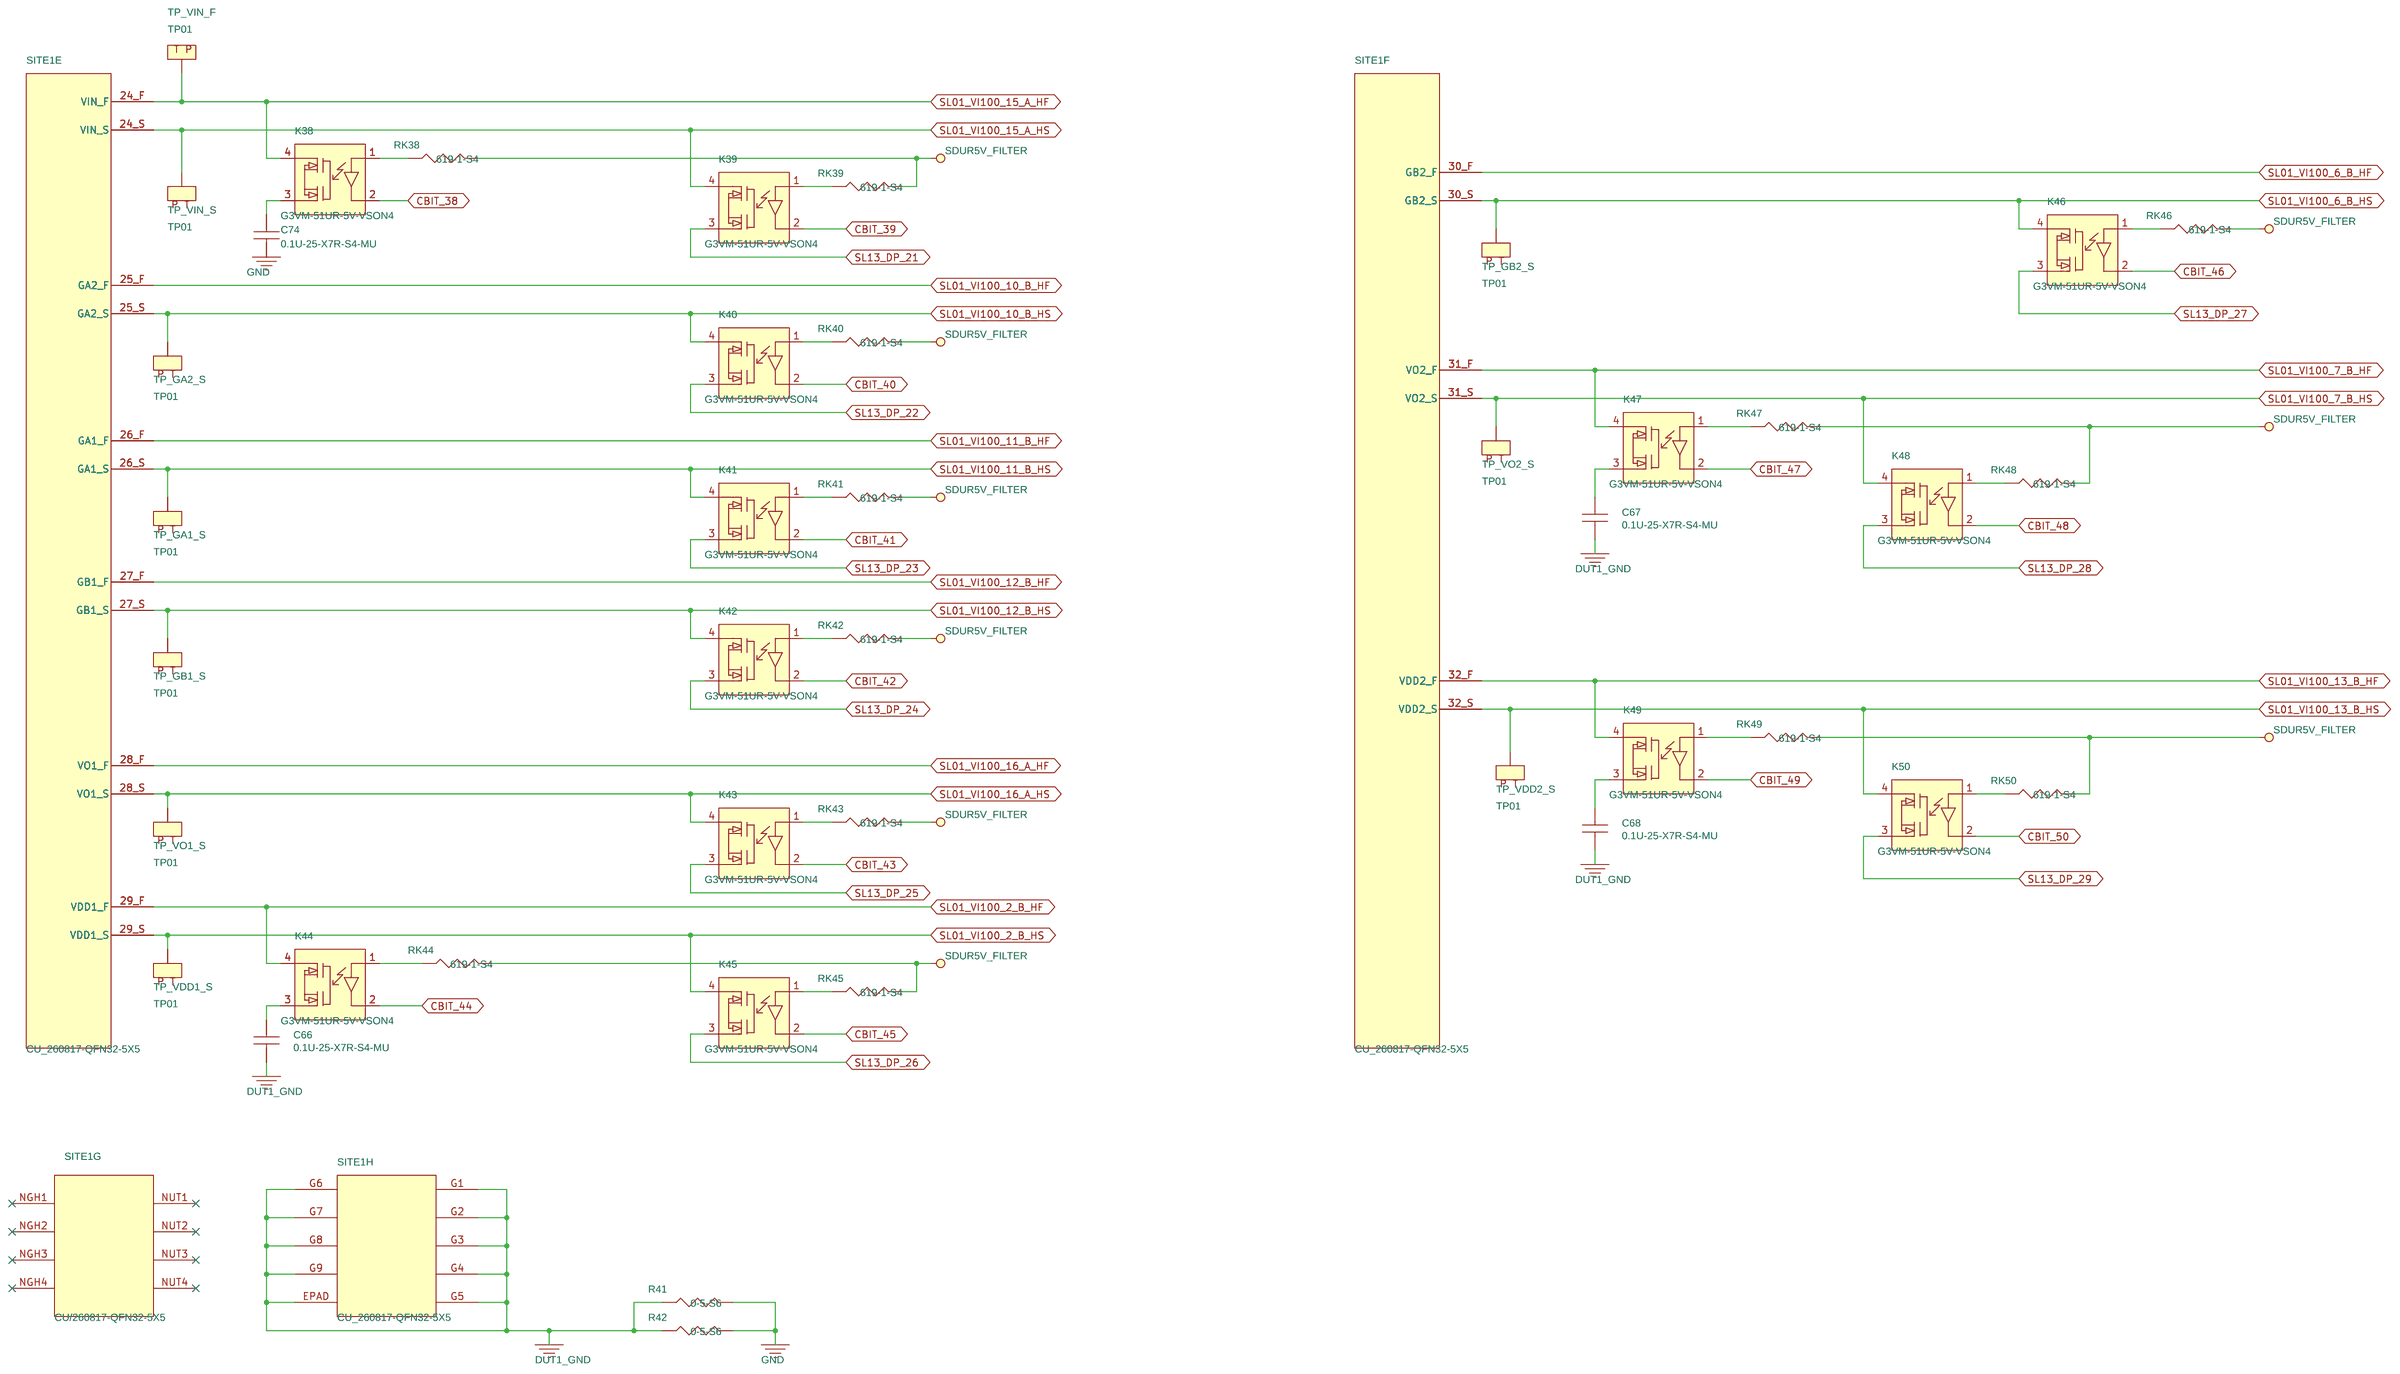
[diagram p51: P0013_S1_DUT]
53 P0012_S1_DUT: size C
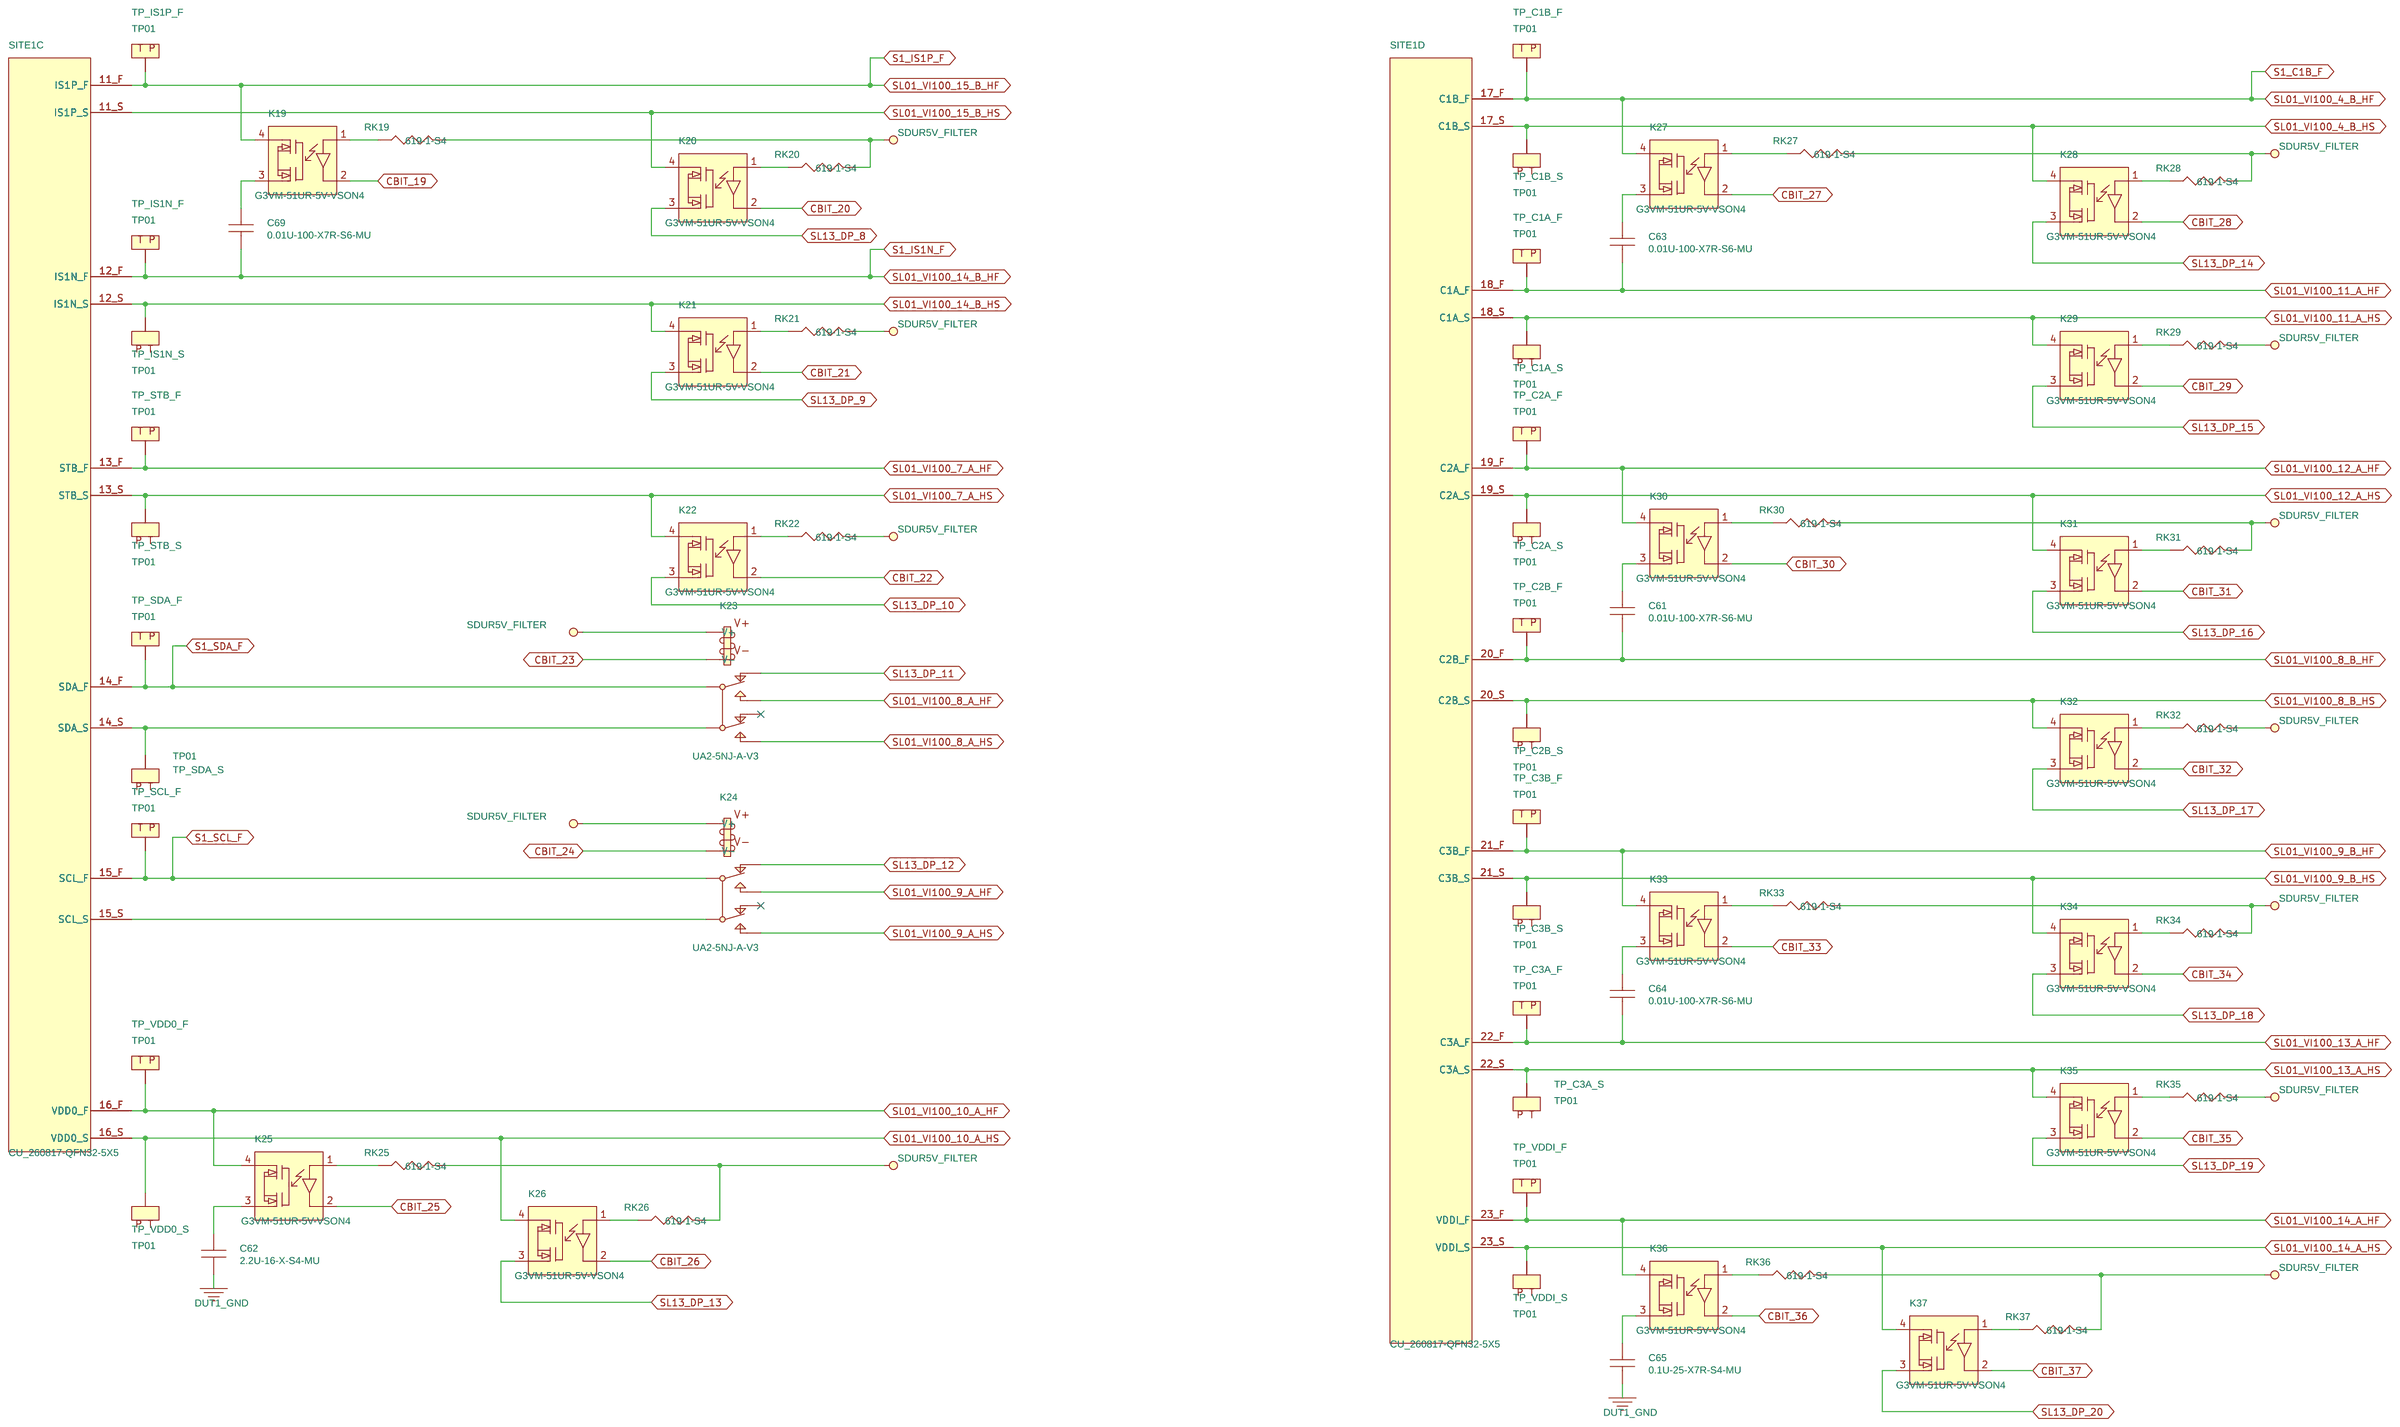
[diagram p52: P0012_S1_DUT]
54 P0011_S1_DUT: size C
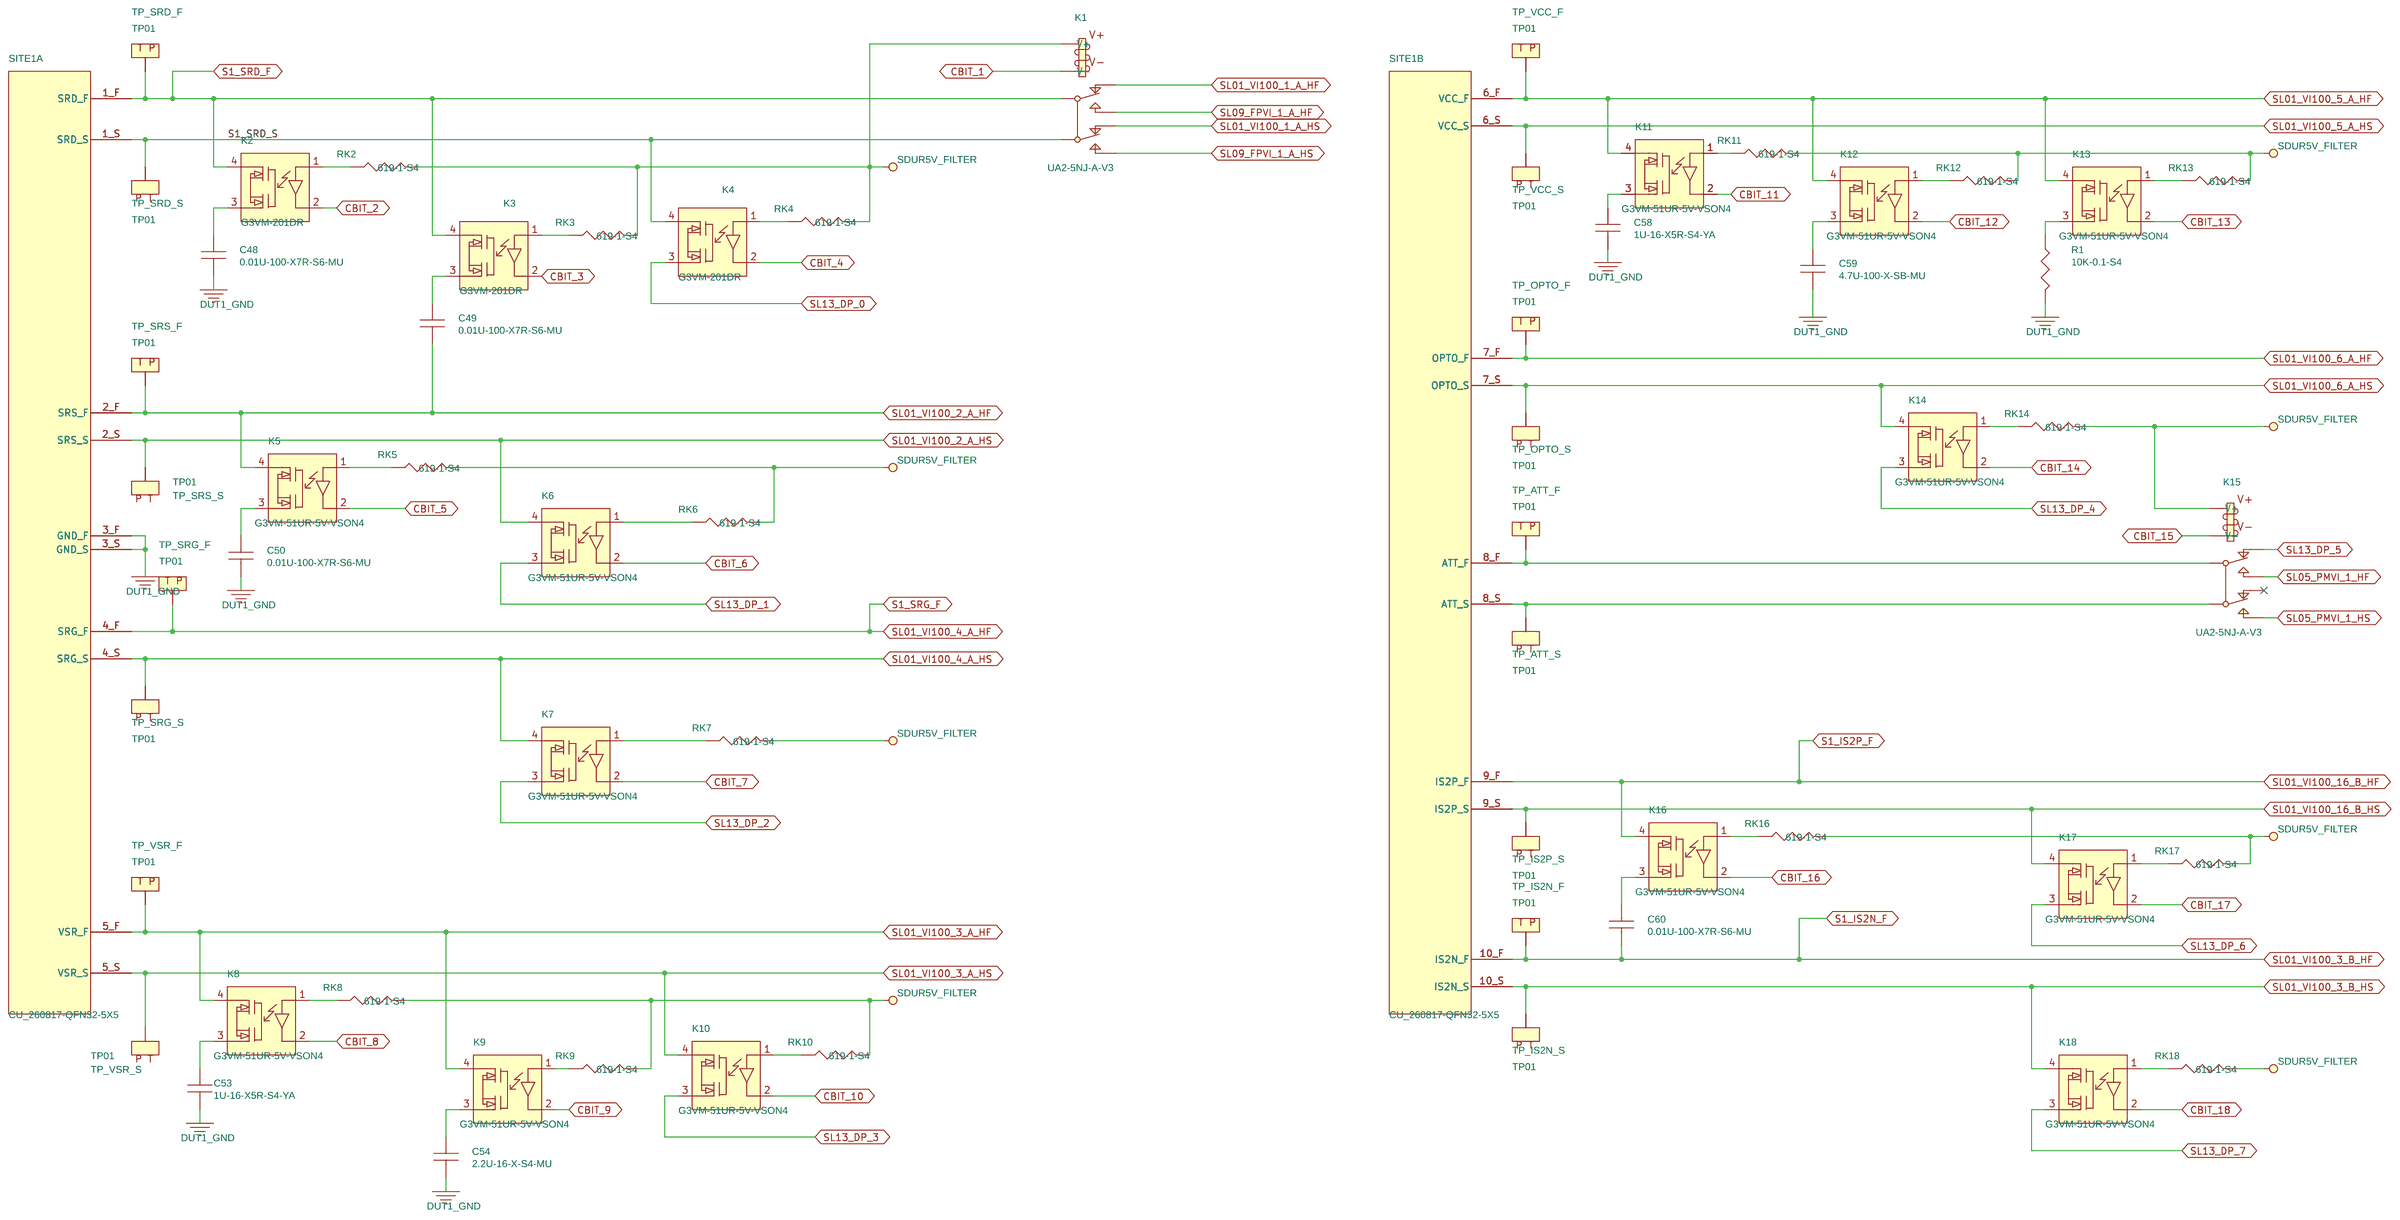
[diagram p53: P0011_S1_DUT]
55 A00.CONFIG: size A3

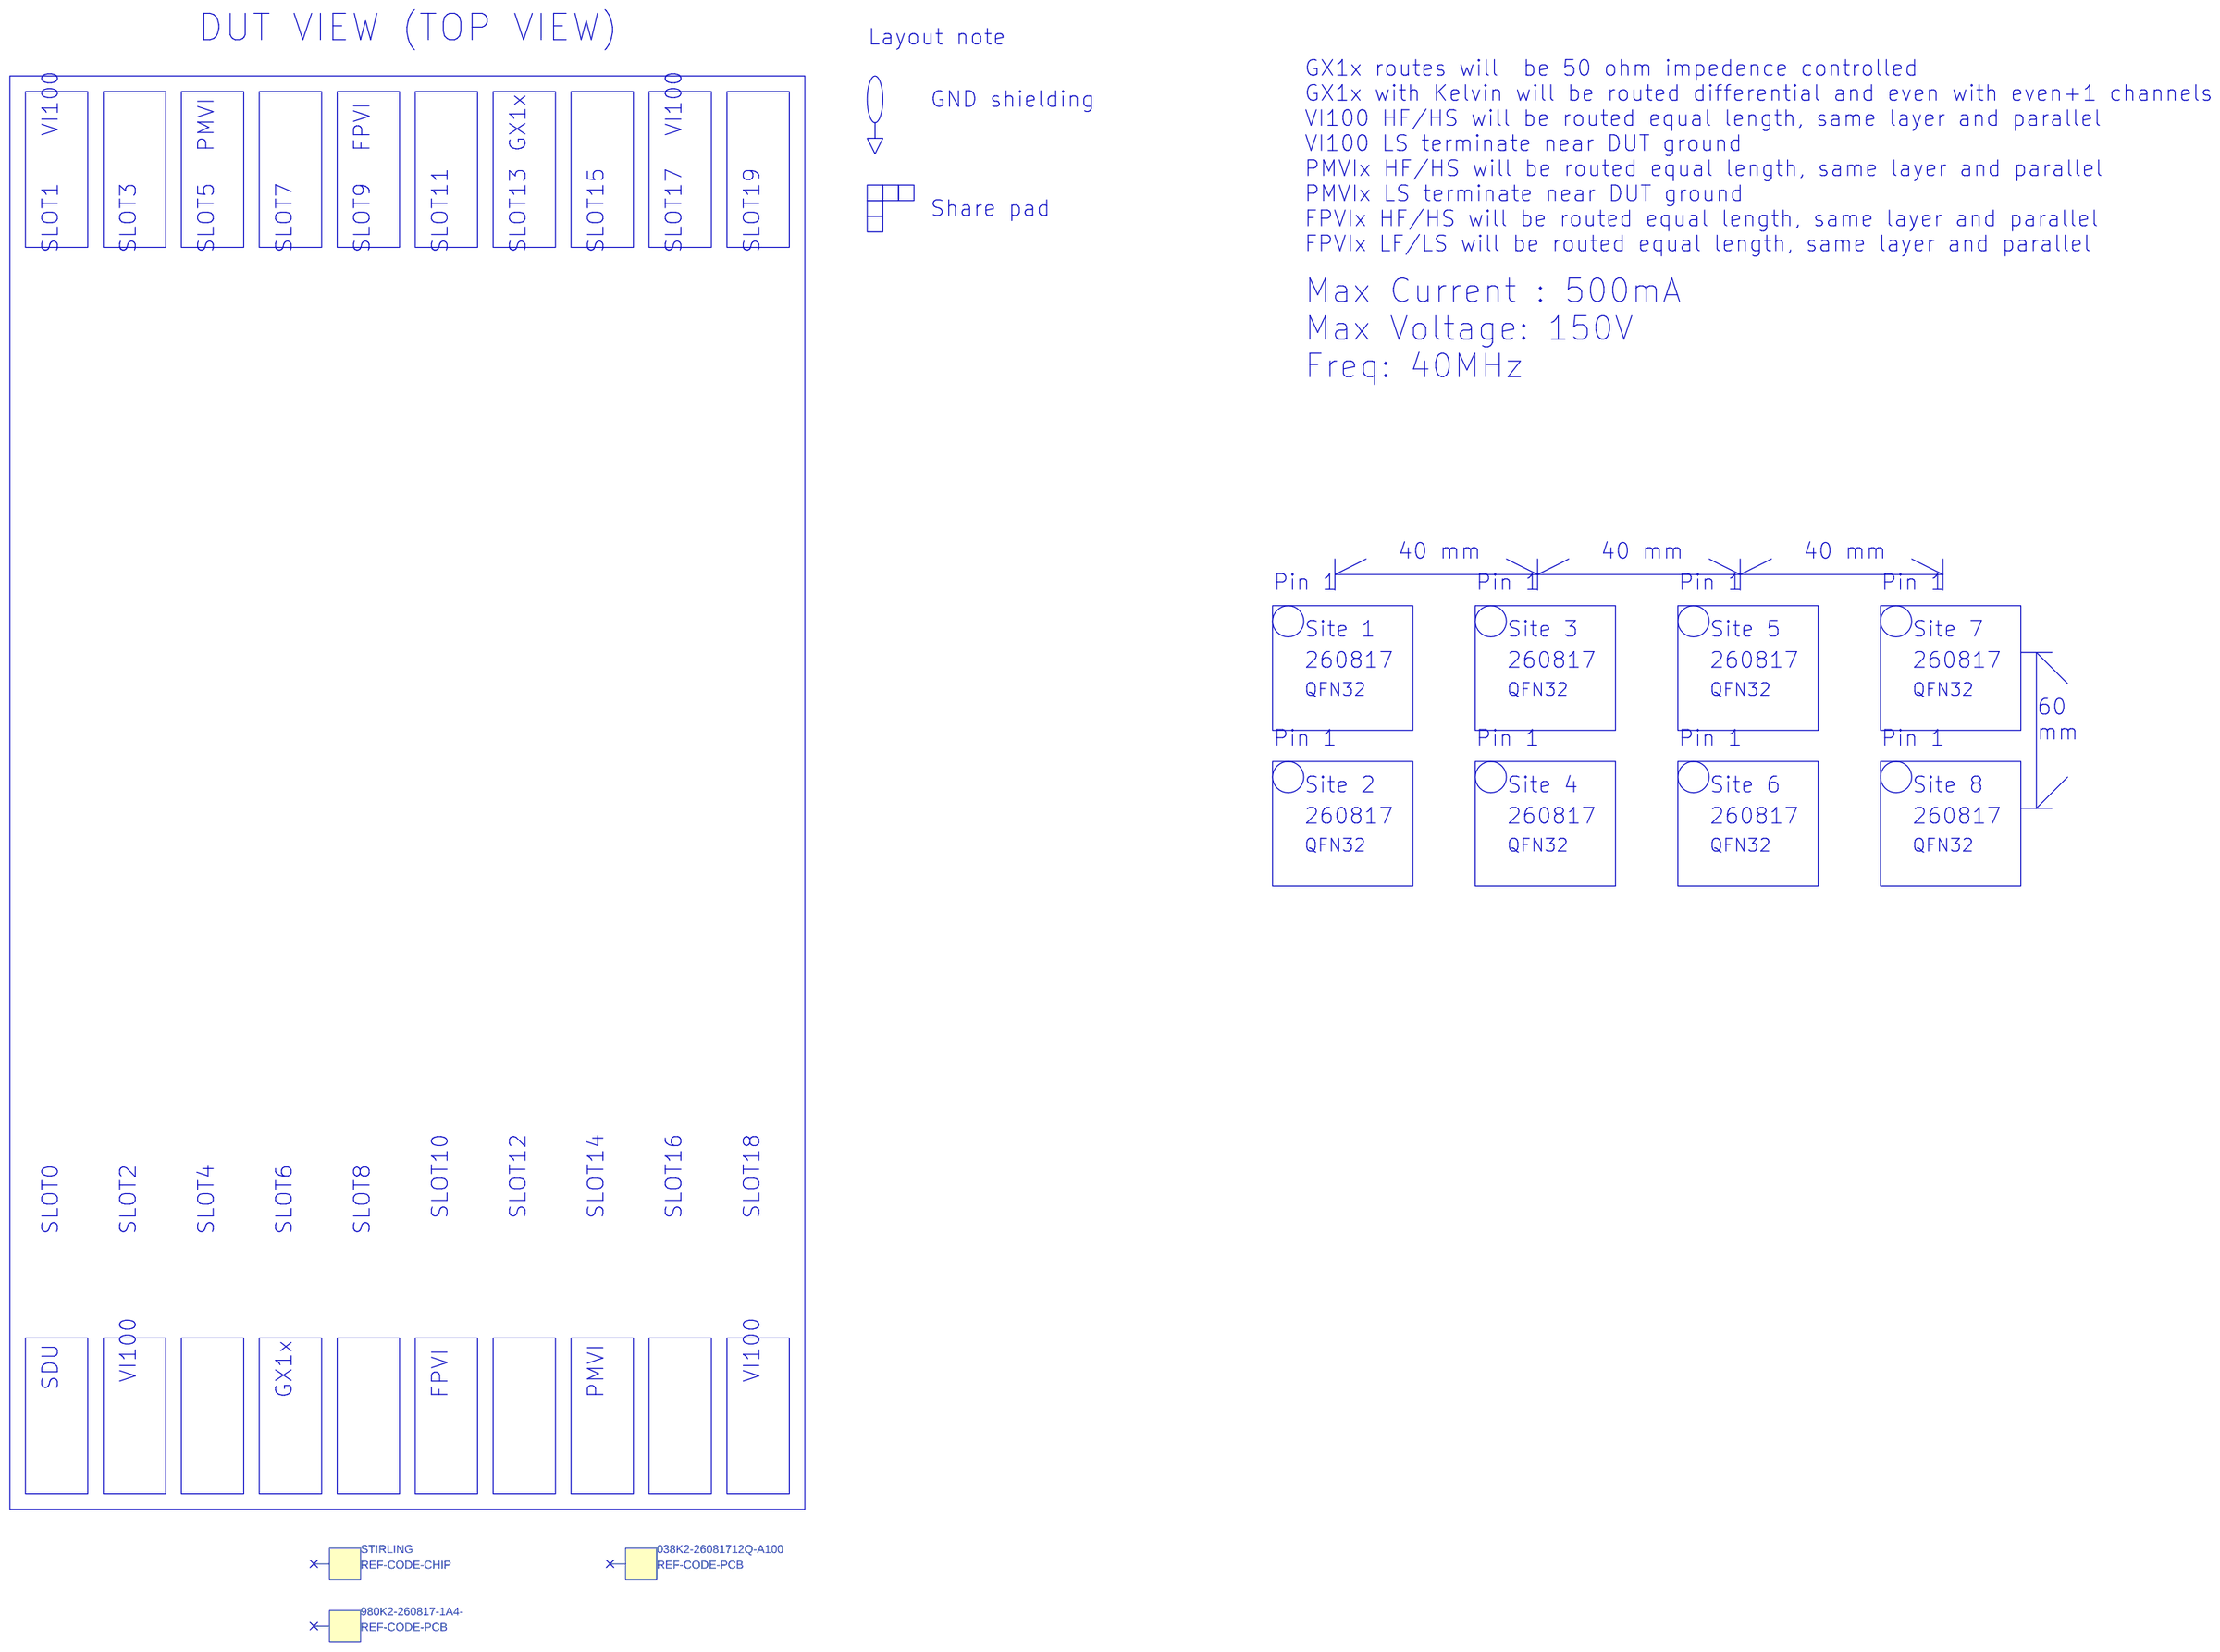
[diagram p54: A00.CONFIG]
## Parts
sheet A00.CONFIG
038K2-26081712Q-A100  REF-CODE-PCB  [PCB_CODE]
980K2-260817-1A4-  REF-CODE-PCB  [PCB_CODE]
STIRLING  REF-CODE-CHIP  [CHIP_CODE]
sheet P0011_S1_DUT
C48  0.01U-100-X7R-S6-MU  [C0603]
C49  0.01U-100-X7R-S6-MU  [C0603]
C50  0.01U-100-X7R-S6-MU  [C0603]
C53  1U-16-X5R-S4-YA  [C0402]
C54  2.2U-16-X-S4-MU  [C0402]
C58  1U-16-X5R-S4-YA  [C0402]
C59  4.7U-100-X-SB-MU  [C1210]
C60  0.01U-100-X7R-S6-MU  [C0603]
K1  UA2-5NJ-A-V3  [RL_NECUA2_5V_V3]
K2  G3VM-201DR  [RL_G3VM201DR_200V]
K3  G3VM-201DR  [RL_G3VM201DR_200V]
K4  G3VM-201DR  [RL_G3VM201DR_200V]
K5  G3VM-51UR-5V-VSON4  [RL_G3VM_4P_VSON4]
K6  G3VM-51UR-5V-VSON4  [RL_G3VM_4P_VSON4]
K7  G3VM-51UR-5V-VSON4  [RL_G3VM_4P_VSON4]
K8  G3VM-51UR-5V-VSON4  [RL_G3VM_4P_VSON4]
K9  G3VM-51UR-5V-VSON4  [RL_G3VM_4P_VSON4]
K10  G3VM-51UR-5V-VSON4  [RL_G3VM_4P_VSON4]
K11  G3VM-51UR-5V-VSON4  [RL_G3VM_4P_VSON4]
K12  G3VM-51UR-5V-VSON4  [RL_G3VM_4P_VSON4]
K13  G3VM-51UR-5V-VSON4  [RL_G3VM_4P_VSON4]
K14  G3VM-51UR-5V-VSON4  [RL_G3VM_4P_VSON4]
K15  UA2-5NJ-A-V3  [RL_NECUA2_5V_V3]
K16  G3VM-51UR-5V-VSON4  [RL_G3VM_4P_VSON4]
K17  G3VM-51UR-5V-VSON4  [RL_G3VM_4P_VSON4]
K18  G3VM-51UR-5V-VSON4  [RL_G3VM_4P_VSON4]
R1  10K-0.1-S4  [R0402]
RK2  619-1-S4  [R0402]
RK3  619-1-S4  [R0402]
RK4  619-1-S4  [R0402]
RK5  619-1-S4  [R0402]
RK6  619-1-S4  [R0402]
RK7  619-1-S4  [R0402]
RK8  619-1-S4  [R0402]
RK9  619-1-S4  [R0402]
RK10  619-1-S4  [R0402]
RK11  619-1-S4  [R0402]
RK12  619-1-S4  [R0402]
RK13  619-1-S4  [R0402]
RK14  619-1-S4  [R0402]
RK16  619-1-S4  [R0402]
RK17  619-1-S4  [R0402]
RK18  619-1-S4  [R0402]
SITE1  CU_260817-QFN32-5X5  [SK_QFN5x5_64P_0P5MM_JG_260817]  (sections A,B,C,D,E,F,G,H)
TP_ATT_F  TP01  [TP_040_T]
TP_ATT_S  TP01  [TP_040_T]
TP_IS2N_F  TP01  [TP_040_T]
TP_IS2N_S  TP01  [TP_040_T]
TP_IS2P_S  TP01  [TP_040_T]
TP_OPTO_F  TP01  [TP_040_T]
TP_OPTO_S  TP01  [TP_040_T]
TP_SRD_F  TP01  [TP_040_T]
TP_SRD_S  TP01  [TP_040_T]
TP_SRG_F  TP01  [TP_040_T]
TP_SRG_S  TP01  [TP_040_T]
TP_SRS_F  TP01  [TP_040_T]
TP_SRS_S  TP01  [TP_040_T]
TP_VCC_F  TP01  [TP_040_T]
TP_VCC_S  TP01  [TP_040_T]
TP_VSR_F  TP01  [TP_040_T]
TP_VSR_S  TP01  [TP_040_T]
sheet P0012_S1_DUT
C61  0.01U-100-X7R-S6-MU  [C0603]
C62  2.2U-16-X-S4-MU  [C0402]
C63  0.01U-100-X7R-S6-MU  [C0603]
C64  0.01U-100-X7R-S6-MU  [C0603]
C65  0.1U-25-X7R-S4-MU  [C0402]
C69  0.01U-100-X7R-S6-MU  [C0603]
K19  G3VM-51UR-5V-VSON4  [RL_G3VM_4P_VSON4]
K20  G3VM-51UR-5V-VSON4  [RL_G3VM_4P_VSON4]
K21  G3VM-51UR-5V-VSON4  [RL_G3VM_4P_VSON4]
K22  G3VM-51UR-5V-VSON4  [RL_G3VM_4P_VSON4]
K23  UA2-5NJ-A-V3  [RL_NECUA2_5V_V3]
K24  UA2-5NJ-A-V3  [RL_NECUA2_5V_V3]
K25  G3VM-51UR-5V-VSON4  [RL_G3VM_4P_VSON4]
K26  G3VM-51UR-5V-VSON4  [RL_G3VM_4P_VSON4]
K27  G3VM-51UR-5V-VSON4  [RL_G3VM_4P_VSON4]
K28  G3VM-51UR-5V-VSON4  [RL_G3VM_4P_VSON4]
K29  G3VM-51UR-5V-VSON4  [RL_G3VM_4P_VSON4]
K30  G3VM-51UR-5V-VSON4  [RL_G3VM_4P_VSON4]
K31  G3VM-51UR-5V-VSON4  [RL_G3VM_4P_VSON4]
K32  G3VM-51UR-5V-VSON4  [RL_G3VM_4P_VSON4]
K33  G3VM-51UR-5V-VSON4  [RL_G3VM_4P_VSON4]
K34  G3VM-51UR-5V-VSON4  [RL_G3VM_4P_VSON4]
K35  G3VM-51UR-5V-VSON4  [RL_G3VM_4P_VSON4]
K36  G3VM-51UR-5V-VSON4  [RL_G3VM_4P_VSON4]
K37  G3VM-51UR-5V-VSON4  [RL_G3VM_4P_VSON4]
RK19  619-1-S4  [R0402]
RK20  619-1-S4  [R0402]
RK21  619-1-S4  [R0402]
RK22  619-1-S4  [R0402]
RK25  619-1-S4  [R0402]
RK26  619-1-S4  [R0402]
RK27  619-1-S4  [R0402]
RK28  619-1-S4  [R0402]
RK29  619-1-S4  [R0402]
RK30  619-1-S4  [R0402]
RK31  619-1-S4  [R0402]
RK32  619-1-S4  [R0402]
RK33  619-1-S4  [R0402]
RK34  619-1-S4  [R0402]
RK35  619-1-S4  [R0402]
RK36  619-1-S4  [R0402]
RK37  619-1-S4  [R0402]
TP_C1A_F  TP01  [TP_040_T]
TP_C1A_S  TP01  [TP_040_T]
TP_C1B_F  TP01  [TP_040_T]
TP_C1B_S  TP01  [TP_040_T]
TP_C2A_F  TP01  [TP_040_T]
TP_C2A_S  TP01  [TP_040_T]
TP_C2B_F  TP01  [TP_040_T]
TP_C2B_S  TP01  [TP_040_T]
TP_C3A_F  TP01  [TP_040_T]
TP_C3A_S  TP01  [TP_040_T]
TP_C3B_F  TP01  [TP_040_T]
TP_C3B_S  TP01  [TP_040_T]
TP_IS1N_F  TP01  [TP_040_T]
TP_IS1N_S  TP01  [TP_040_T]
TP_IS1P_F  TP01  [TP_040_T]
TP_SCL_F  TP01  [TP_040_T]
TP_SDA_F  TP01  [TP_040_T]
TP_SDA_S  TP01  [TP_040_T]
TP_STB_F  TP01  [TP_040_T]
TP_STB_S  TP01  [TP_040_T]
TP_VDD0_F  TP01  [TP_040_T]
TP_VDD0_S  TP01  [TP_040_T]
TP_VDDI_F  TP01  [TP_040_T]
TP_VDDI_S  TP01  [TP_040_T]
sheet P0013_S1_DUT
C66  0.1U-25-X7R-S4-MU  [C0402]
C67  0.1U-25-X7R-S4-MU  [C0402]
C68  0.1U-25-X7R-S4-MU  [C0402]
C74  0.1U-25-X7R-S4-MU  [C0402]
K38  G3VM-51UR-5V-VSON4  [RL_G3VM_4P_VSON4]
K39  G3VM-51UR-5V-VSON4  [RL_G3VM_4P_VSON4]
K40  G3VM-51UR-5V-VSON4  [RL_G3VM_4P_VSON4]
K41  G3VM-51UR-5V-VSON4  [RL_G3VM_4P_VSON4]
K42  G3VM-51UR-5V-VSON4  [RL_G3VM_4P_VSON4]
K43  G3VM-51UR-5V-VSON4  [RL_G3VM_4P_VSON4]
K44  G3VM-51UR-5V-VSON4  [RL_G3VM_4P_VSON4]
K45  G3VM-51UR-5V-VSON4  [RL_G3VM_4P_VSON4]
K46  G3VM-51UR-5V-VSON4  [RL_G3VM_4P_VSON4]
K47  G3VM-51UR-5V-VSON4  [RL_G3VM_4P_VSON4]
K48  G3VM-51UR-5V-VSON4  [RL_G3VM_4P_VSON4]
K49  G3VM-51UR-5V-VSON4  [RL_G3VM_4P_VSON4]
K50  G3VM-51UR-5V-VSON4  [RL_G3VM_4P_VSON4]
R41  0-5-S6  [R0603]
R42  0-5-S6  [R0603]
RK38  619-1-S4  [R0402]
RK39  619-1-S4  [R0402]
RK40  619-1-S4  [R0402]
RK41  619-1-S4  [R0402]
RK42  619-1-S4  [R0402]
RK43  619-1-S4  [R0402]
RK44  619-1-S4  [R0402]
RK45  619-1-S4  [R0402]
RK46  619-1-S4  [R0402]
RK47  619-1-S4  [R0402]
RK48  619-1-S4  [R0402]
RK49  619-1-S4  [R0402]
RK50  619-1-S4  [R0402]
TP_GA1_S  TP01  [TP_040_T]
TP_GA2_S  TP01  [TP_040_T]
TP_GB1_S  TP01  [TP_040_T]
TP_GB2_S  TP01  [TP_040_T]
TP_VDD1_S  TP01  [TP_040_T]
TP_VDD2_S  TP01  [TP_040_T]
TP_VIN_F  TP01  [TP_040_T]
TP_VIN_S  TP01  [TP_040_T]
TP_VO1_S  TP01  [TP_040_T]
TP_VO2_S  TP01  [TP_040_T]
sheet P0014_S1_DUT
1SH1  SHORT  [DEFAULT_SHORT_SMALL]
1SH2  SHORT  [DEFAULT_SHORT_SMALL]
1SH3  SHORT  [DEFAULT_SHORT_SMALL]
1SH4  SHORT  [DEFAULT_SHORT_SMALL]
1SH5  SHORT  [DEFAULT_SHORT_SMALL]
1SH6  SHORT  [DEFAULT_SHORT_SMALL]
1SH7  SHORT  [DEFAULT_SHORT_SMALL]
1SH8  SHORT  [DEFAULT_SHORT_SMALL]
1SH9  SHORT  [DEFAULT_SHORT_SMALL]
1SH10  SHORT  [DEFAULT_SHORT_SMALL]
1SH11  SHORT  [DEFAULT_SHORT_SMALL]
1SH12  SHORT  [DEFAULT_SHORT_SMALL]
1SH13  SHORT  [DEFAULT_SHORT_SMALL]
1SH14  SHORT  [DEFAULT_SHORT_SMALL]
1SH15  SHORT  [DEFAULT_SHORT_SMALL]
1SH16  SHORT  [DEFAULT_SHORT_SMALL]
1SH17  SHORT  [DEFAULT_SHORT_SMALL]
1SH18  SHORT  [DEFAULT_SHORT_SMALL]
1SH19  SHORT  [DEFAULT_SHORT_SMALL]
1SH20  SHORT  [DEFAULT_SHORT_SMALL]
1SH21  SHORT  [DEFAULT_SHORT_SMALL]
1SH22  SHORT  [DEFAULT_SHORT_SMALL]
1SH23  SHORT  [DEFAULT_SHORT_SMALL]
1SH24  SHORT  [DEFAULT_SHORT_SMALL]
1SH25  SHORT  [DEFAULT_SHORT_SMALL]
1SH26  SHORT  [DEFAULT_SHORT_SMALL]
1SH27  SHORT  [DEFAULT_SHORT_SMALL]
C70  0.1U-25-X7R-S4-MU  [C0402]
C71  0.1U-25-X7R-S4-MU  [C0402]
C72  0.1U-25-X7R-S4-MU  [C0402]
C73  0.1U-25-X7R-S4-MU  [C0402]
K51  G3VM-51UR-5V-VSON4  [RL_G3VM_4P_VSON4]
K52  G3VM-51UR-5V-VSON4  [RL_G3VM_4P_VSON4]
K53  G3VM-51UR-5V-VSON4  [RL_G3VM_4P_VSON4]
K54  G3VM-51UR-5V-VSON4  [RL_G3VM_4P_VSON4]
K55  G3VM-51UR-5V-VSON4  [RL_G3VM_4P_VSON4]
K56  G3VM-201DR  [RL_G3VM201DR_200V]
K57  G3VM-51UR-5V-VSON4  [RL_G3VM_4P_VSON4]
K58  G3VM-51UR-5V-VSON4  [RL_G3VM_4P_VSON4]
K59  G3VM-51UR-5V-VSON4  [RL_G3VM_4P_VSON4]
K60  G3VM-51UR-5V-VSON4  [RL_G3VM_4P_VSON4]
K61  G3VM-51UR-5V-VSON4  [RL_G3VM_4P_VSON4]
R7  4.7K-1-S4-WA  [R0402]
R8  4.7K-1-S4-WA  [R0402]
R11  5K-1-S4-YA  [R0402]
R14  5K-1-S4-YA  [R0402]
R15  0-0-S2-KOA  [R0201]
R16  5.1-1-S2  [R0201]
R17  0-0-S2-KOA  [R0201]
R18  5.1-1-S2  [R0201]
R19  100K-0.1-S4-YA  [R0402]
R20  100K-0.1-S4-YA  [R0402]
RK51  619-1-S4  [R0402]
RK52  619-1-S4  [R0402]
RK53  619-1-S4  [R0402]
RK54  619-1-S4  [R0402]
RK55  619-1-S4  [R0402]
RK56  619-1-S4  [R0402]
RK57  619-1-S4  [R0402]
RK58  619-1-S4  [R0402]
RK59  619-1-S4  [R0402]
RK60  619-1-S4  [R0402]
RK61  619-1-S4  [R0402]
SHORT1  SHORT  [DEFAULT_SHORT_SMALL]
SHORT2  SHORT  [DEFAULT_SHORT_SMALL]
SHORT3  SHORT  [DEFAULT_SHORT_SMALL]
SHORT4  SHORT  [DEFAULT_SHORT_SMALL]
SHORT6  SHORT  [DEFAULT_SHORT_SMALL]
SHORT7  SHORT  [DEFAULT_SHORT_SMALL]
SHORT8  SHORT  [DEFAULT_SHORT_SMALL]
SHORT9  SHORT  [DEFAULT_SHORT_SMALL]
SHORT10  SHORT  [DEFAULT_SHORT_SMALL]
SHORT11  SHORT  [DEFAULT_SHORT_SMALL]
TP_IN+_1  TP01  [TP_040_T]
TP_IN+_2  TP01  [TP_040_T]
TP_IN+_3  TP01  [TP_040_T]
TP_IN+_4  TP01  [TP_040_T]
TP_IN-_1  TP01  [TP_040_T]
TP_IN-_2  TP01  [TP_040_T]
TP_IN-_3  TP01  [TP_040_T]
TP_IN-_4  TP01  [TP_040_T]
TP_OUT+_1  TP01  [TP_040_T]
TP_OUT+_2  TP01  [TP_040_T]
TP_OUT-_1  TP01  [TP_040_T]
TP_OUT-_2  TP01  [TP_040_T]
TP_OUT_1  TP01  [TP_040_T]
TP_OUT_2  TP01  [TP_040_T]
TP_REF_1  TP01  [TP_040_T]
TP_REF_2  TP01  [TP_040_T]
U1  TLV3604DCKR-SC70  [SC70]
U2  TLV3604DCKR-SC70  [SC70]
U3  INA186A3QDDFRQ1-SOT23-8  [SOT23_8P_0P65MM_H1P3MM]
U4  INA186A3QDDFRQ1-SOT23-8  [SOT23_8P_0P65MM_H1P3MM]
sheet P0021_S2_DUT
2C48  0.01U-100-X7R-S6-MU  [C0603]
2C49  0.01U-100-X7R-S6-MU  [C0603]
2C50  0.01U-100-X7R-S6-MU  [C0603]
2C53  1U-16-X5R-S4-YA  [C0402]
2C54  2.2U-16-X-S4-MU  [C0402]
2C58  1U-16-X5R-S4-YA  [C0402]
2C59  4.7U-100-X-SB-MU  [C1210]
2C60  0.01U-100-X7R-S6-MU  [C0603]
2K1  UA2-5NJ-A-V3  [RL_NECUA2_5V_V3]
2K2  G3VM-201DR  [RL_G3VM201DR_200V]
2K3  G3VM-201DR  [RL_G3VM201DR_200V]
2K4  G3VM-201DR  [RL_G3VM201DR_200V]
2K5  G3VM-51UR-5V-VSON4  [RL_G3VM_4P_VSON4]
2K6  G3VM-51UR-5V-VSON4  [RL_G3VM_4P_VSON4]
2K7  G3VM-51UR-5V-VSON4  [RL_G3VM_4P_VSON4]
2K8  G3VM-51UR-5V-VSON4  [RL_G3VM_4P_VSON4]
2K9  G3VM-51UR-5V-VSON4  [RL_G3VM_4P_VSON4]
2K10  G3VM-51UR-5V-VSON4  [RL_G3VM_4P_VSON4]
2K11  G3VM-51UR-5V-VSON4  [RL_G3VM_4P_VSON4]
2K12  G3VM-51UR-5V-VSON4  [RL_G3VM_4P_VSON4]
2K13  G3VM-51UR-5V-VSON4  [RL_G3VM_4P_VSON4]
2K14  G3VM-51UR-5V-VSON4  [RL_G3VM_4P_VSON4]
2K15  UA2-5NJ-A-V3  [RL_NECUA2_5V_V3]
2K16  G3VM-51UR-5V-VSON4  [RL_G3VM_4P_VSON4]
2K17  G3VM-51UR-5V-VSON4  [RL_G3VM_4P_VSON4]
2K18  G3VM-51UR-5V-VSON4  [RL_G3VM_4P_VSON4]
2R1  10K-0.1-S4  [R0402]
2RK2  619-1-S4  [R0402]
2RK3  619-1-S4  [R0402]
2RK4  619-1-S4  [R0402]
2RK5  619-1-S4  [R0402]
2RK6  619-1-S4  [R0402]
2RK7  619-1-S4  [R0402]
2RK8  619-1-S4  [R0402]
2RK9  619-1-S4  [R0402]
2RK10  619-1-S4  [R0402]
2RK11  619-1-S4  [R0402]
2RK12  619-1-S4  [R0402]
2RK13  619-1-S4  [R0402]
2RK14  619-1-S4  [R0402]
2RK16  619-1-S4  [R0402]
2RK17  619-1-S4  [R0402]
2RK18  619-1-S4  [R0402]
2TP_ATT_F  TP01  [TP_040_T]
2TP_ATT_S  TP01  [TP_040_T]
2TP_IS2N_F  TP01  [TP_040_T]
2TP_IS2N_S  TP01  [TP_040_T]
2TP_IS2P_S  TP01  [TP_040_T]
2TP_OPTO_F  TP01  [TP_040_T]
2TP_OPTO_S  TP01  [TP_040_T]
2TP_SRD_F  TP01  [TP_040_T]
2TP_SRD_S  TP01  [TP_040_T]
2TP_SRG_F  TP01  [TP_040_T]
2TP_SRG_S  TP01  [TP_040_T]
2TP_SRS_F  TP01  [TP_040_T]
2TP_SRS_S  TP01  [TP_040_T]
2TP_VCC_F  TP01  [TP_040_T]
2TP_VCC_S  TP01  [TP_040_T]
2TP_VSR_F  TP01  [TP_040_T]
2TP_VSR_S  TP01  [TP_040_T]
sheet P0022_S2_DUT
SITE2  CU_260817-QFN32-5X5  [SK_QFN5x5_64P_0P5MM_JG_260817]  (sections A,B,C,D,E,F,G,H)

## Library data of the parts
038K2-26081712Q-A100 980K2-260817-1A4- = REF-CODE-PCB
STIRLING = REF-CODE-CHIP
2C48-2C50 2C60 C48-C50 C60 C61 C63 C64 C69 = 0.01U-100-X7R-S6-MU
2C53 2C58 C53 C58 = 1U-16-X5R-S4-YA
2C54 C54 C62 = 2.2U-16-X-S4-MU
2C59 C59 = 4.7U-100-X-SB-MU
2K1 2K15 K1 K15 K23 K24 = UA2-5NJ-A-V3
2K2-2K4 K2-K4 K56 = G3VM-201DR
2K5-2K14 2K16-2K18 K5-K14 K16-K22 K25-K55 K57-K61 = G3VM-51UR-5V-VSON4
2R1 R1 = 10K-0.1-S4
2RK2-2RK14 2RK16-2RK18 RK2-RK14 RK16-RK22 RK25-RK61 = 619-1-S4
SITE1 SITE2 = CU_260817-QFN32-5X5
2TP_ATT_F 2TP_ATT_S 2TP_IS2N_F 2TP_IS2N_S 2TP_IS2P_S 2TP_OPTO_F 2TP_OPTO_S 2TP_SRD_F 2TP_SRD_S 2TP_SRG_F 2TP_SRG_S 2TP_SRS_F 2TP_SRS_S 2TP_VCC_F 2TP_VCC_S 2TP_VSR_F 2TP_VSR_S TP_ATT_F TP_ATT_S TP_C1A_F TP_C1A_S TP_C1B_F TP_C1B_S TP_C2A_F TP_C2A_S TP_C2B_F TP_C2B_S TP_C3A_F TP_C3A_S TP_C3B_F TP_C3B_S TP_GA1_S TP_GA2_S TP_GB1_S TP_GB2_S TP_IN+_1-TP_IN+_4 TP_IN-_1-TP_IN-_4 TP_IS1N_F TP_IS1N_S TP_IS1P_F TP_IS2N_F TP_IS2N_S TP_IS2P_S TP_OPTO_F TP_OPTO_S TP_OUT+_1 TP_OUT+_2 TP_OUT-_1 TP_OUT-_2 TP_OUT_1 TP_OUT_2 TP_REF_1 TP_REF_2 TP_SCL_F TP_SDA_F TP_SDA_S TP_SRD_F TP_SRD_S TP_SRG_F TP_SRG_S TP_SRS_F TP_SRS_S TP_STB_F TP_STB_S TP_VCC_F TP_VCC_S TP_VDD0_F TP_VDD0_S TP_VDD1_S TP_VDD2_S TP_VDDI_F TP_VDDI_S TP_VIN_F TP_VIN_S TP_VO1_S TP_VO2_S TP_VSR_F TP_VSR_S = TP01_v2
C65-C68 C70-C74 = 0.1U-25-X7R-S4-MU
R41 R42 = 0-5-S6
1SH1-1SH27 = SHORT: KAIROSNAME: SH1
R7 R8 = 4.7K-1-S4-WA
R11 R14 = 5K-1-S4-YA
R15 R17 = 0-0-S2-KOA
R16 R18 = 5.1-1-S2
R19 R20 = 100K-0.1-S4-YA
SHORT1-SHORT4 SHORT6-SHORT11 = SHORT
U1 U2 = TLV3604DCKR-SC70
U3 U4 = INA186A3QDDFRQ1-SOT23-8

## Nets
GND: R41.2 R42.2 ; also on sheet 3 4 7 8 11 12 15 16 19 20 21 22 24 28 32 36 40 44 48
CBIT_1: K1.8(V-) ; also on sheet 21 46
CBIT_2: K2.2 ; also on sheet 21 30 38 46
CBIT_3: K3.2 ; also on sheet 21 30 38 46
CBIT_4: K4.2 ; also on sheet 21 30 38 46
CBIT_5: K5.2 ; also on sheet 21 30 38 46
CBIT_6: K6.2 ; also on sheet 21 30 38 46
CBIT_7: K7.2 ; also on sheet 21 30 38 46
CBIT_8: K8.2 ; also on sheet 21 30 38 46
CBIT_9: K9.2 ; also on sheet 21 30 38 46
CBIT_10: K10.2 ; also on sheet 21 30 38 46
CBIT_11: K11.2 ; also on sheet 21 30 38 46
CBIT_12: K12.2 ; also on sheet 21 30 38 46
CBIT_13: K13.2 ; also on sheet 21 30 38 46
CBIT_14: K14.2 ; also on sheet 21 30 38 46
CBIT_15: K15.8(V-) ; also on sheet 21 46
CBIT_16: K16.2 ; also on sheet 21 30 38 46
CBIT_17: K17.2 ; also on sheet 21 30 38 46
CBIT_18: K18.2 ; also on sheet 21 30 38 46
CBIT_19: K19.2 ; also on sheet 21 29 37 45
CBIT_20: K20.2 ; also on sheet 21 29 37 45
CBIT_21: K21.2 ; also on sheet 21 29 37 45
CBIT_22: K22.2 ; also on sheet 21 29 37 45
CBIT_23: K23.8(V-) ; also on sheet 21 45
CBIT_24: K24.8(V-) ; also on sheet 21 45
CBIT_25: K25.2 ; also on sheet 21 29 37 45
CBIT_26: K26.2 ; also on sheet 21 29 37 45
CBIT_27: K27.2 ; also on sheet 21 29 37 45
CBIT_28: K28.2 ; also on sheet 21 29 37 45
CBIT_29: K29.2 ; also on sheet 21 29 37 45
CBIT_30: K30.2 ; also on sheet 21 29 37 45
CBIT_31: K31.2 ; also on sheet 21 29 37 45
CBIT_32: K32.2 ; also on sheet 21 29 37 45
CBIT_33: K33.2 ; also on sheet 21 29 37 45
CBIT_34: K34.2 ; also on sheet 21 29 37 45
CBIT_35: K35.2 ; also on sheet 21 29 37 45
CBIT_36: K36.2 ; also on sheet 21 29 37 45
CBIT_37: K37.2 ; also on sheet 21 29 37 45
CBIT_38: K38.2 ; also on sheet 21 28 36 44
CBIT_39: K39.2 ; also on sheet 21 28 36 44
CBIT_40: K40.2 ; also on sheet 21 28 36 44
CBIT_41: K41.2 ; also on sheet 21 28 36 44
CBIT_42: K42.2 ; also on sheet 21 28 36 44
CBIT_43: K43.2 ; also on sheet 21 28 36 44
CBIT_44: K44.2 ; also on sheet 21 28 36 44
CBIT_45: K45.2 ; also on sheet 21 28 36 44
CBIT_46: K46.2 ; also on sheet 21 28 36 44
CBIT_47: K47.2 ; also on sheet 21 28 36 44
CBIT_48: K48.2 ; also on sheet 21 28 36 44
CBIT_49: K49.2 ; also on sheet 21 28 36 44
CBIT_50: K50.2 ; also on sheet 21 28 36 44
CBIT_51: K51.2 ; also on sheet 21 27 35 43
CBIT_52: K52.2 ; also on sheet 21 27 35 43
CBIT_53: K53.2 ; also on sheet 21 27 35 43
CBIT_54: K54.2 ; also on sheet 21 27 35 43
CBIT_55: K55.2 ; also on sheet 21 27 35 43
CBIT_56: K56.2 ; also on sheet 21 27 35 43
CBIT_57: K57.2 ; also on sheet 21 27 35 43
CBIT_58: K58.2 ; also on sheet 21 27 35 43
CBIT_59: K59.2 ; also on sheet 21 27 35 43
CBIT_60: K60.2 ; also on sheet 21 27 35 43
CBIT_61: 2K1.8(V-) ; also on sheet 21 42
CBIT_62: 2K2.2 ; also on sheet 21 26 34 42
CBIT_63: 2K3.2 ; also on sheet 21 26 34 42
CBIT_64: 2K4.2 ; also on sheet 21 26 34 42
CBIT_65: 2K5.2 ; also on sheet 21 26 34 42
CBIT_66: 2K6.2 ; also on sheet 21 26 34 42
CBIT_67: 2K7.2 ; also on sheet 21 26 34 42
CBIT_68: 2K8.2 ; also on sheet 21 26 34 42
CBIT_69: 2K9.2 ; also on sheet 21 26 34 42
CBIT_70: 2K10.2 ; also on sheet 21 26 34 42
CBIT_71: 2K11.2 ; also on sheet 21 26 34 42
CBIT_72: 2K12.2 ; also on sheet 21 26 34 42
CBIT_73: 2K13.2 ; also on sheet 21 26 34 42
CBIT_74: 2K14.2 ; also on sheet 21 26 34 42
CBIT_75: 2K15.8(V-) ; also on sheet 21 42
CBIT_76: 2K16.2 ; also on sheet 21 26 34 42
CBIT_77: 2K17.2 ; also on sheet 21 26 34 42
CBIT_78: 2K18.2 ; also on sheet 21 26 34 42
CBIT_127: K61.2 ; also on sheet 21 27 35 43
DUT1_GND: 1SH1.2 1SH2.2 1SH3.2 1SH4.2 1SH5.2 1SH6.2 1SH7.2 1SH8.2 1SH9.2 1SH10.2 1SH11.2 1SH12.2 1SH13.2 1SH14.2 1SH15.2 1SH16.2 1SH17.2 1SH18.2 1SH19.2 1SH20.2 1SH21.2 1SH22.2 1SH23.2 1SH24.2 1SH25.2 1SH26.2 1SH27.2 C48.2 C50.2 C53.2 C54.2 C58.2 C59.2 C62.2 C65.2 C66.2 C67.2 C68.2 C70.2 C71.2 C72.2 C73.2 C74.2 K52.3 K54.3 R1.2 R11.1 R14.1 R41.1 R42.1 SITE1.3_F(GND_F) SITE1.3_S(GND_S) SITE1.EPAD SITE1.G1 SITE1.G2 SITE1.G3 SITE1.G4 SITE1.G5 SITE1.G6 SITE1.G7 SITE1.G8 SITE1.G9 U1.2(VEE) U2.2(VEE) U3.4(GND) U4.4(GND)
DUT2_GND: 2C48.2 2C50.2 2C53.2 2C54.2 2C58.2 2C59.2 2R1.2 SITE2.3_F(GND_F) SITE2.3_S(GND_S) ; also on sheet 47 48 49
S1_C1B_F: K27.4 K61.3 SITE1.17_F(C1B_F) TP_C1B_F.1(TP) ; also on sheet 20
S1_IS1N_F: C69.2 K57.4 SITE1.12_F(IS1N_F) TP_IS1N_F.1(TP) ; also on sheet 20
S1_IS1P_F: K19.4 K58.3 SITE1.11_F(IS1P_F) TP_IS1P_F.1(TP) ; also on sheet 20
S1_IS2N_F: C60.2 K59.4 SITE1.10_F(IS2N_F) TP_IS2N_F.1(TP) ; also on sheet 20
S1_IS2P_F: K16.4 K60.3 SITE1.9_F(IS2P_F) ; also on sheet 20
S1_SCL_F: K24.3 K53.3 K54.4 SITE1.15_F(SCL_F) TP_SCL_F.1(TP)
S1_SDA_F: K23.3 K51.3 K52.4 SITE1.14_F(SDA_F) TP_SDA_F.1(TP)
S1_SRD_F: K1.3 K2.4 K3.4 K56.3 SITE1.1_F(SRD_F) TP_SRD_F.1(TP)
S1_SRD_S: K1.6 K4.4 SITE1.1_S(SRD_S) TP_SRD_S.1(TP)
S1_SRG_F: K55.3 SITE1.4_F(SRG_F) TP_SRG_F.1(TP) ; also on sheet 20
S2_IS2N_F: 2C60.2 2TP_IS2N_F.1(TP) SITE2.10_F(IS2N_F) ; also on sheet 19 47
S2_IS2P_F: 2K16.4 SITE2.9_F(IS2P_F) ; also on sheet 19 47
S2_SRD_F: 2K1.3 2K2.4 2K3.4 2TP_SRD_F.1(TP) SITE2.1_F(SRD_F) ; also on sheet 47
S2_SRD_S: 2K1.6 2K4.4 2TP_SRD_S.1(TP) SITE2.1_S(SRD_S)
S2_SRG_F: 2TP_SRG_F.1(TP) SITE2.4_F(SRG_F) ; also on sheet 19 47
SDUP5V_FILTER: C70.1 C71.1 U1.5(VCCI/VCCO) U2.5(VCCI/VCCO) ; also on sheet 22 23 27 31 35 39 43 47
SDUR5V_FILTER: 2K1.1(V+) 2K15.1(V+) 2RK2.2 2RK3.2 2RK4.2 2RK5.2 2RK6.2 2RK7.2 2RK8.2 2RK9.2 2RK10.2 2RK11.2 2RK12.2 2RK13.2 2RK14.2 2RK16.2 2RK17.2 2RK18.2 K1.1(V+) K15.1(V+) K23.1(V+) K24.1(V+) RK2.2 RK3.2 RK4.2 RK5.2 RK6.2 RK7.2 RK8.2 RK9.2 RK10.2 RK11.2 RK12.2 RK13.2 RK14.2 RK16.2 RK17.2 RK18.2 RK19.2 RK20.2 RK21.2 RK22.2 RK25.2 RK26.2 RK27.2 RK28.2 RK29.2 RK30.2 RK31.2 RK32.2 RK33.2 RK34.2 RK35.2 RK36.2 RK37.2 RK38.2 RK39.2 RK40.2 RK41.2 RK42.2 RK43.2 RK44.2 RK45.2 RK46.2 RK47.2 RK48.2 RK49.2 RK50.2 RK51.2 RK52.2 RK53.2 RK54.2 RK55.1 RK56.1 RK57.1 RK58.1 RK59.2 RK60.2 RK61.2 ; also on sheet 22 23 24 25 26 27 28 29 30 31 32 33 34 35 36 37 38 39 40 41 42 43 44 45 46 47 48 49
SL01_VI100_1_A_HF: K1.2 ; also on sheet 20
SL01_VI100_1_A_HS: K1.7 ; also on sheet 20
SL01_VI100_1_LS: 1SH1.1 ; also on sheet 20
SL01_VI100_2_A_HF: C49.2 K5.4 SITE1.2_F(SRS_F) TP_SRS_F.1(TP) ; also on sheet 20
SL01_VI100_2_A_HS: K6.4 SITE1.2_S(SRS_S) TP_SRS_S.1(TP) ; also on sheet 20
SL01_VI100_2_B_HF: K44.4 SITE1.29_F(VDD1_F) ; also on sheet 20
SL01_VI100_2_B_HS: K45.4 SITE1.29_S(VDD1_S) TP_VDD1_S.1(TP) ; also on sheet 20
SL01_VI100_2_LS: 1SH2.1 ; also on sheet 20
SL01_VI100_3_A_HF: K8.4 K9.4 SITE1.5_F(VSR_F) TP_VSR_F.1(TP) ; also on sheet 20
SL01_VI100_3_A_HS: K10.4 SITE1.5_S(VSR_S) TP_VSR_S.1(TP) ; also on sheet 20
SL01_VI100_3_B_HS: K18.4 SITE1.10_S(IS2N_S) TP_IS2N_S.1(TP) ; also on sheet 20
SL01_VI100_3_LS: 1SH3.1 ; also on sheet 20
SL01_VI100_4_A_HS: K7.4 SITE1.4_S(SRG_S) TP_SRG_S.1(TP) ; also on sheet 20
SL01_VI100_4_B_HS: K28.4 SITE1.17_S(C1B_S) TP_C1B_S.1(TP) ; also on sheet 20
SL01_VI100_4_LS: 1SH4.1 ; also on sheet 20
SL01_VI100_5_A_HF: K11.4 K12.4 K13.4 SITE1.6_F(VCC_F) TP_VCC_F.1(TP) ; also on sheet 20
SL01_VI100_5_A_HS: SITE1.6_S(VCC_S) TP_VCC_S.1(TP) ; also on sheet 20
SL01_VI100_5_LS: 1SH5.1 ; also on sheet 20
SL01_VI100_6_A_HF: SITE1.7_F(OPTO_F) TP_OPTO_F.1(TP) ; also on sheet 20
SL01_VI100_6_A_HS: K14.4 SITE1.7_S(OPTO_S) TP_OPTO_S.1(TP) ; also on sheet 20
SL01_VI100_6_B_HF: SITE1.30_F(GB2_F) ; also on sheet 20
SL01_VI100_6_B_HS: K46.4 SITE1.30_S(GB2_S) TP_GB2_S.1(TP) ; also on sheet 20
SL01_VI100_6_LS: 1SH6.1 ; also on sheet 20
SL01_VI100_7_A_HF: SITE1.13_F(STB_F) TP_STB_F.1(TP) ; also on sheet 20
SL01_VI100_7_A_HS: K22.4 SITE1.13_S(STB_S) TP_STB_S.1(TP) ; also on sheet 20
SL01_VI100_7_B_HF: K47.4 SITE1.31_F(VO2_F) ; also on sheet 20
SL01_VI100_7_B_HS: K48.4 SITE1.31_S(VO2_S) TP_VO2_S.1(TP) ; also on sheet 20
SL01_VI100_7_LS: 1SH7.1 ; also on sheet 20
SL01_VI100_8_A_HF: K23.4 ; also on sheet 20
SL01_VI100_8_A_HS: K23.5 ; also on sheet 20
SL01_VI100_8_B_HF: C61.2 SITE1.20_F(C2B_F) TP_C2B_F.1(TP) ; also on sheet 20
SL01_VI100_8_B_HS: K32.4 SITE1.20_S(C2B_S) TP_C2B_S.1(TP) ; also on sheet 20
SL01_VI100_8_LS: 1SH8.1 ; also on sheet 20
SL01_VI100_9_A_HF: K24.4 ; also on sheet 20
SL01_VI100_9_A_HS: K24.5 ; also on sheet 20
SL01_VI100_9_B_HF: K33.4 SITE1.21_F(C3B_F) TP_C3B_F.1(TP) ; also on sheet 20
SL01_VI100_9_B_HS: K34.4 SITE1.21_S(C3B_S) TP_C3B_S.1(TP) ; also on sheet 20
SL01_VI100_9_LS: 1SH9.1 ; also on sheet 20
SL01_VI100_10_A_HF: K25.4 SITE1.16_F(VDD0_F) TP_VDD0_F.1(TP) ; also on sheet 20
SL01_VI100_10_A_HS: K26.4 SITE1.16_S(VDD0_S) TP_VDD0_S.1(TP) ; also on sheet 20
SL01_VI100_10_B_HF: SITE1.25_F(GA2_F) ; also on sheet 20
SL01_VI100_10_B_HS: K40.4 SITE1.25_S(GA2_S) TP_GA2_S.1(TP) ; also on sheet 20
SL01_VI100_10_LS: 1SH10.1 ; also on sheet 20
SL01_VI100_11_A_HF: C63.2 SITE1.18_F(C1A_F) TP_C1A_F.1(TP) ; also on sheet 20
SL01_VI100_11_A_HS: K29.4 SITE1.18_S(C1A_S) TP_C1A_S.1(TP) ; also on sheet 20
SL01_VI100_11_B_HF: SITE1.26_F(GA1_F) ; also on sheet 20
SL01_VI100_11_B_HS: K41.4 SITE1.26_S(GA1_S) TP_GA1_S.1(TP) ; also on sheet 20
SL01_VI100_11_LS: 1SH11.1 ; also on sheet 20
SL01_VI100_12_A_HF: K30.4 SITE1.19_F(C2A_F) TP_C2A_F.1(TP) ; also on sheet 20
SL01_VI100_12_A_HS: K31.4 SITE1.19_S(C2A_S) TP_C2A_S.1(TP) ; also on sheet 20
SL01_VI100_12_B_HF: SITE1.27_F(GB1_F) ; also on sheet 20
SL01_VI100_12_B_HS: K42.4 SITE1.27_S(GB1_S) TP_GB1_S.1(TP) ; also on sheet 20
SL01_VI100_12_LS: 1SH12.1 ; also on sheet 20
SL01_VI100_13_A_HF: C64.2 SITE1.22_F(C3A_F) TP_C3A_F.1(TP) ; also on sheet 20
SL01_VI100_13_A_HS: K35.4 SITE1.22_S(C3A_S) TP_C3A_S.1(TP) ; also on sheet 20
SL01_VI100_13_B_HF: K49.4 SITE1.32_F(VDD2_F) ; also on sheet 20
SL01_VI100_13_B_HS: K50.4 SITE1.32_S(VDD2_S) TP_VDD2_S.1(TP) ; also on sheet 20
SL01_VI100_13_LS: 1SH13.1 ; also on sheet 20
SL01_VI100_14_A_HF: K36.4 SITE1.23_F(VDDI_F) TP_VDDI_F.1(TP) ; also on sheet 20
SL01_VI100_14_A_HS: K37.4 SITE1.23_S(VDDI_S) TP_VDDI_S.1(TP) ; also on sheet 20
SL01_VI100_14_B_HS: K21.4 SITE1.12_S(IS1N_S) TP_IS1N_S.1(TP) ; also on sheet 20
SL01_VI100_14_LS: 1SH14.1 ; also on sheet 20
SL01_VI100_15_A_HF: K38.4 SITE1.24_F(VIN_F) TP_VIN_F.1(TP) ; also on sheet 20
SL01_VI100_15_A_HS: K39.4 SITE1.24_S(VIN_S) TP_VIN_S.1(TP) ; also on sheet 20
SL01_VI100_15_B_HS: K20.4 SITE1.11_S(IS1P_S) ; also on sheet 20
SL01_VI100_15_LS: 1SH15.1 ; also on sheet 20
SL01_VI100_16_A_HF: SITE1.28_F(VO1_F) ; also on sheet 20
SL01_VI100_16_A_HS: K43.4 SITE1.28_S(VO1_S) TP_VO1_S.1(TP) ; also on sheet 20
SL01_VI100_16_B_HS: K17.4 SITE1.9_S(IS2P_S) TP_IS2P_S.1(TP) ; also on sheet 20
SL01_VI100_16_LS: 1SH16.1 ; also on sheet 20
SL02_VI100_1_A_HF: 2K1.2 ; also on sheet 19
SL02_VI100_1_A_HS: 2K1.7 ; also on sheet 19
SL02_VI100_2_A_HF: 2C49.2 2K5.4 2TP_SRS_F.1(TP) SITE2.2_F(SRS_F) ; also on sheet 19
SL02_VI100_2_A_HS: 2K6.4 2TP_SRS_S.1(TP) SITE2.2_S(SRS_S) ; also on sheet 19
SL02_VI100_3_A_HF: 2K8.4 2K9.4 2TP_VSR_F.1(TP) SITE2.5_F(VSR_F) ; also on sheet 19
SL02_VI100_3_A_HS: 2K10.4 2TP_VSR_S.1(TP) SITE2.5_S(VSR_S) ; also on sheet 19
SL02_VI100_3_B_HS: 2K18.4 2TP_IS2N_S.1(TP) SITE2.10_S(IS2N_S) ; also on sheet 19
SL02_VI100_4_A_HS: 2K7.4 2TP_SRG_S.1(TP) SITE2.4_S(SRG_S) ; also on sheet 19
SL02_VI100_5_A_HF: 2K11.4 2K12.4 2K13.4 2TP_VCC_F.1(TP) SITE2.6_F(VCC_F) ; also on sheet 19
SL02_VI100_5_A_HS: 2TP_VCC_S.1(TP) SITE2.6_S(VCC_S) ; also on sheet 19
SL02_VI100_6_A_HF: 2TP_OPTO_F.1(TP) SITE2.7_F(OPTO_F) ; also on sheet 19
SL02_VI100_6_A_HS: 2K14.4 2TP_OPTO_S.1(TP) SITE2.7_S(OPTO_S) ; also on sheet 19
SL02_VI100_16_B_HS: 2K17.4 2TP_IS2P_S.1(TP) SITE2.9_S(IS2P_S) ; also on sheet 19
SL05_PMVI_1_HF: K15.4 ; also on sheet 16
SL05_PMVI_1_HS: K15.5 ; also on sheet 16
SL05_PMVI_1_LS: 1SH17.1 ; also on sheet 16
SL05_PMVI_10_HF: R7.1 SHORT3.1 ; also on sheet 16
SL05_PMVI_10_HS: SHORT3.2 ; also on sheet 16
SL05_PMVI_10_LS: 1SH18.1 ; also on sheet 16
SL05_PMVI_11_HF: R8.1 SHORT4.1 ; also on sheet 16
SL05_PMVI_11_HS: SHORT4.2 ; also on sheet 16
SL05_PMVI_11_LS: 1SH19.1 ; also on sheet 16
SL05_PMVI_12_HF: SHORT1.1 TP_IN-_1.1(TP) U1.4(-IN) ; also on sheet 16
SL05_PMVI_12_HS: SHORT1.2 ; also on sheet 16
SL05_PMVI_12_LS: 1SH20.1 ; also on sheet 16
SL05_PMVI_13_HF: SHORT2.1 TP_IN-_2.1(TP) U2.4(-IN) ; also on sheet 16
SL05_PMVI_13_HS: SHORT2.2 ; also on sheet 16
SL05_PMVI_13_LS: 1SH21.1 ; also on sheet 16
SL05_PMVI_14_HF: SHORT9.1 TP_OUT_1.1(TP) U3.5(OUT) ; also on sheet 16
SL05_PMVI_14_HS: SHORT9.2 ; also on sheet 16
SL05_PMVI_14_LS: 1SH22.1 ; also on sheet 16
SL05_PMVI_15_HF: C72.1 R15.2 SHORT6.2 U3.1(VS) ; also on sheet 16
SL05_PMVI_15_HS: SHORT6.1 ; also on sheet 16
SL05_PMVI_15_LS: 1SH23.1 ; also on sheet 16
SL05_PMVI_16_HF: SHORT11.2 TP_REF_1.1(TP) U3.3(REF) ; also on sheet 16
SL05_PMVI_16_HS: SHORT11.1 ; also on sheet 16
SL05_PMVI_16_LS: 1SH24.1 ; also on sheet 16
SL05_PMVI_17_HF: SHORT10.1 TP_OUT_2.1(TP) U4.5(OUT) ; also on sheet 16
SL05_PMVI_17_HS: SHORT10.2 ; also on sheet 16
SL05_PMVI_17_LS: 1SH25.1 ; also on sheet 16
SL05_PMVI_18_HF: C73.1 R17.2 SHORT7.2 U4.1(VS) ; also on sheet 16
SL05_PMVI_18_HS: SHORT7.1 ; also on sheet 16
SL05_PMVI_18_LS: 1SH26.1 ; also on sheet 16
SL05_PMVI_19_HF: SHORT8.2 TP_REF_2.1(TP) U4.3(REF) ; also on sheet 16
SL05_PMVI_19_HS: SHORT8.1 ; also on sheet 16
SL05_PMVI_19_LS: 1SH27.1 ; also on sheet 16
SL06_DP_0: 2K4.3 ; also on sheet 15
SL06_DP_1: 2K6.3 ; also on sheet 15
SL06_DP_2: 2K7.3 ; also on sheet 15
SL06_DP_3: 2K10.3 ; also on sheet 15
SL06_DP_4: 2K14.3 ; also on sheet 15
SL06_DP_5: 2K15.2 ; also on sheet 15
SL06_DP_6: 2K17.3 ; also on sheet 15
SL06_DP_7: 2K18.3 ; also on sheet 15
SL09_FPVI_1_A_HF: K1.4 ; also on sheet 12
SL09_FPVI_1_A_HS: K1.5 ; also on sheet 12
SL10_FPVI_1_A_HF: 2K1.4 ; also on sheet 11
SL10_FPVI_1_A_HS: 2K1.5 ; also on sheet 11
SL13_DP_0: K4.3 ; also on sheet 8
SL13_DP_1: K6.3 ; also on sheet 8
SL13_DP_2: K7.3 ; also on sheet 8
SL13_DP_3: K10.3 ; also on sheet 8
SL13_DP_4: K14.3 ; also on sheet 8
SL13_DP_5: K15.2 ; also on sheet 8
SL13_DP_6: K17.3 ; also on sheet 8
SL13_DP_7: K18.3 ; also on sheet 8
SL13_DP_8: K20.3 ; also on sheet 8
SL13_DP_9: K21.3 ; also on sheet 8
SL13_DP_10: K22.3 ; also on sheet 8
SL13_DP_11: K23.2 ; also on sheet 8
SL13_DP_12: K24.2 ; also on sheet 8
SL13_DP_13: K26.3 ; also on sheet 8
SL13_DP_14: K28.3 ; also on sheet 8
SL13_DP_15: K29.3 ; also on sheet 8
SL13_DP_16: K31.3 ; also on sheet 8
SL13_DP_17: K32.3 ; also on sheet 8
SL13_DP_18: K34.3 ; also on sheet 8
SL13_DP_19: K35.3 ; also on sheet 8
SL13_DP_20: K37.3 ; also on sheet 8
SL13_DP_21: K39.3 ; also on sheet 8
SL13_DP_22: K40.3 ; also on sheet 8
SL13_DP_23: K41.3 ; also on sheet 8
SL13_DP_24: K42.3 ; also on sheet 8
SL13_DP_25: K43.3 ; also on sheet 8
SL13_DP_26: K45.3 ; also on sheet 8
SL13_DP_27: K46.3 ; also on sheet 8
SL13_DP_28: K48.3 ; also on sheet 8
SL13_DP_29: K50.3 ; also on sheet 8
SL13_DP_121: TP_OUT+_1.1(TP) U1.1(OUT+) ; also on sheet 8
SL13_DP_122: TP_OUT-_1.1(TP) U1.6(OUT-) ; also on sheet 8
SL13_DP_123: TP_OUT+_2.1(TP) U2.1(OUT+) ; also on sheet 8
SL13_DP_124: TP_OUT-_2.1(TP) U2.6(OUT-) ; also on sheet 8
SL13_DP_125: R15.1 U3.2(ENABLE) ; also on sheet 8
SL13_DP_126: R17.1 U4.2(ENABLE) ; also on sheet 8
SL14_PMVI_1_HF: 2K15.4 ; also on sheet 7
SL14_PMVI_1_HS: 2K15.5 ; also on sheet 7
N17260776: C48.1 K2.3
N17261204: C49.1 K3.3
N17261720: C50.1 K5.3
N17263068: K7.1 RK7.1
N17264482: C53.1 K8.3
N17264547: C54.1 K9.3
N17266096: C59.1 K12.3
N17266582: K13.3 R1.1
N17267238: K15.6 SITE1.8_S(ATT_S) TP_ATT_S.1(TP)
N17270245: C69.1 K19.3
N17493363: K5.1 RK5.1
N17493593: K6.1 RK6.1
N17493900: K8.1 RK8.1
N17494047: K9.1 RK9.1
N17494316: K10.1 RK10.1
N17494507: K11.1 RK11.1
N17494587: C58.1 K11.3
N17494912: K12.1 RK12.1
N17495143: K13.1 RK13.1
N17495451: K14.1 RK14.1
N17495920: K19.1 RK19.1
N17496065: K20.1 RK20.1
N17496168: K21.1 RK21.1
N17508143: K2.1 RK2.1
N17508406: K3.1 RK3.1
N17508530: K4.1 RK4.1
N17654577: K51.4 R7.2
N17654648: K53.4 R8.2
N17654652: K53.1 RK53.1
N17654805: R11.2 R19.1 TP_IN+_1.1(TP) U1.3(+IN)
N17654898: R14.2 R20.1 TP_IN+_2.1(TP) U2.3(+IN)
N17655019: K55.1 RK59.1
N17655025: K55.4 R19.2
N17655029: K56.1 RK60.1
N17655138: K57.3 R16.1 TP_IN-_3.1(TP) U3.8(IN-)
N17655140: K58.4 R16.2 TP_IN+_3.1(TP) U3.7(IN+)
N17655324: K60.4 R18.2 TP_IN+_4.1(TP) U4.7(IN+)
N17655339: K59.3 R18.1 TP_IN-_4.1(TP) U4.8(IN-)
N17655440: K56.4 K61.4 R20.2
N17655462: K54.1 RK54.1
N17655480: K51.1 RK51.1
N17655494: K52.1 RK52.1
N17702527: K15.3 SITE1.8_F(ATT_F) TP_ATT_F.1(TP)
N18407736: C60.1 K16.3
N18407764: K17.1 RK17.1
N18407893: K16.1 RK16.1
N18407930: K18.1 RK18.1
N18409262: K22.1 RK22.1
N18420672: K23.6 SITE1.14_S(SDA_S) TP_SDA_S.1(TP)
N18420953: K24.6 SITE1.15_S(SCL_S)
N18432405: C62.1 K25.3
N18432504: K25.1 RK25.1
N18432522: K26.1 RK26.1
N18432973: C63.1 K27.3
N18433005: K28.1 RK28.1
N18433172: K27.1 RK27.1
N18433200: K29.1 RK29.1
N18433570: C61.1 K30.3
N18433598: K31.1 RK31.1
N18433748: K30.1 RK30.1
N18433778: K32.1 RK32.1
N18434722: K39.1 RK39.1
N18434762: K38.1 RK38.1
N18434888: C74.1 K38.3
N18465960: K35.1 RK35.1
N18465976: K34.1 RK34.1
N18465984: K33.1 RK33.1
N18466028: C64.1 K33.3
N18511830: K37.1 RK37.1
N18511832: K36.1 RK36.1
N18511862: C65.1 K36.3
N18556624: K40.1 RK40.1
N18556932: K41.1 RK41.1
N18557107: K42.1 RK42.1
N18557324: K43.1 RK43.1
N18568668: K45.1 RK45.1
N18568680: K44.1 RK44.1
N18568712: C66.1 K44.3
N18580009: K46.1 RK46.1
N18580265: C67.1 K47.3
N18580347: K48.1 RK48.1
N18580359: K47.1 RK47.1
N18580906: C68.1 K49.3
N18580988: K50.1 RK50.1
N18581000: K49.1 RK49.1
N18705535: K57.1 RK55.2
N18705626: K58.1 RK56.2
N18705736: K59.1 RK57.2
N18705861: K60.1 RK58.2
N18706153: K61.1 RK61.1
N18706312: 2C48.1 2K2.3
N18706321: 2C49.1 2K3.3
N18706330: 2C50.1 2K5.3
N18706363: 2K7.1 2RK7.1
N18706370: 2C53.1 2K8.3
N18706379: 2C54.1 2K9.3
N18706409: 2C59.1 2K12.3
N18706416: 2K13.3 2R1.1
N18706434: 2K15.6 2TP_ATT_S.1(TP) SITE2.8_S(ATT_S)
N18706452: 2K5.1 2RK5.1
N18706454: 2K6.1 2RK6.1
N18706456: 2K8.1 2RK8.1
N18706457: 2K9.1 2RK9.1
N18706458: 2K10.1 2RK10.1
N18706459: 2K11.1 2RK11.1
N18706462: 2C58.1 2K11.3
N18706465: 2K12.1 2RK12.1
N18706467: 2K13.1 2RK13.1
N18706470: 2K14.1 2RK14.1
N18706472: 2K2.1 2RK2.1
N18706473: 2K3.1 2RK3.1
N18706474: 2K4.1 2RK4.1
N18706494: 2K15.3 2TP_ATT_F.1(TP) SITE2.8_F(ATT_F)
N18706506: 2C60.1 2K16.3
N18706519: 2K17.1 2RK17.1
N18706533: 2K16.1 2RK16.1
N18706537: 2K18.1 2RK18.1

Not connected (* = marked no-connect by the designer): 2K15 7*; 038K2-26081712Q-A100 1*; 980K2-260817-1A4- 1*; K15 7*; K23 7*; K24 7*; SITE1 NGH1* NGH2* NGH3* NGH4* NUT1* NUT2* NUT3* NUT4*; STIRLING 1*; U3 6(NC)*; U4 6(NC)*

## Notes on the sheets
sheet 51
- Pull-up Resistor
- Timing Circuits(GX1 ¸ê·½¤À°t»Ý­n¦b®É§Ç¹q¸ô¤W¬Û¾F)
- Differential Circuit
sheet 55
- DUT VIEW (TOP VIEW)
- Layout note
- GX1x routes will  be 50 ohm impedence controlled
  GX1x with Kelvin will be routed differential and even with even+1 channels
  VI100 HF/HS will be routed equal length, same layer and parallel
  VI100 LS terminate near DUT ground
  PMVIx HF/HS will be routed equal length, same layer and parallel
  PMVIx LS terminate near DUT ground
  FPVIx HF/HS will be routed equal length, same layer and parallel
  FPVIx LF/LS will be routed equal length, same layer and parallel
- GND shielding
- VI100
- VI100
- PMVI
- FPVI
- GX1x
- Share pad
- SLOT1
- SLOT3
- SLOT5
- SLOT7
- SLOT9
- SLOT11
- SLOT13
- SLOT15
- SLOT17
- SLOT19
- Max Current : 500mA
  Max Voltage: 150V
  Freq: 40MHz
- 40 mm
- 40 mm
- 40 mm
- Pin 1
- Pin 1
- Pin 1
- Pin 1
- Site 1
- Site 3
- Site 5
- Site 7
- 260817
- 260817
- 260817
- 260817
- QFN32
- QFN32
- QFN32
- QFN32
- 60
  mm
- Pin 1
- Pin 1
- Pin 1
- Pin 1
- Site 2
- Site 4
- Site 6
- Site 8
- 260817
- 260817
- 260817
- 260817
- QFN32
- QFN32
- QFN32
- QFN32
- SLOT10
- SLOT12
- SLOT14
- SLOT16
- SLOT18
- SLOT0
- SLOT2
- SLOT4
- SLOT6
- SLOT8
- SDU
- VI100
- GX1x
- FPVI
- PMVI
- VI100
